<?xml version="1.0" encoding="utf-8" standalone="no"?>
<device schemaVersion="1.1">
  <name>STM32F765ZIT7</name>
  <version>1.0</version>
  <description>STM32F765BGT6,STM32F765BIT6,STM32F765IGK6,STM32F765IGT6,STM32F765IIK6,STM32F765IIK7,STM32F765IIT6,STM32F765IIT7,STM32F765NGH6,STM32F765NGH7,STM32F765NIH6,STM32F765NIH7,STM32F765VGH6,STM32F765VGH7,STM32F765VGT6,STM32F765VGT7,STM32F765VIH6,STM32F765VIT6,STM32F765ZGT6,STM32F765ZGT7,STM32F765ZIT6,STM32F765ZIT7</description>
  <addressUnitBits>8</addressUnitBits>
  <width>32</width>
  <size>0x20</size>
  <resetValue>0</resetValue>
  <resetMask>0xFFFFFFFF</resetMask>
  <peripherals>
    <peripheral>
      <name>TIM2</name>
      <baseAddress>0x40000000</baseAddress>
      <registers>
        <register>
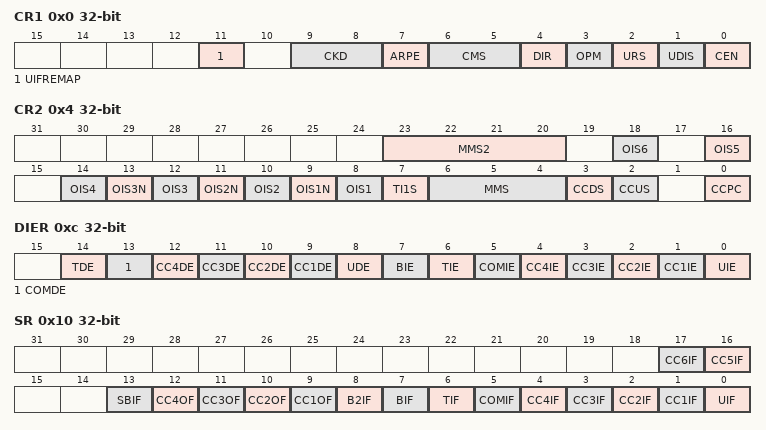
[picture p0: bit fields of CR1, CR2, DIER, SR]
          <name>CR1</name>
          <addressOffset>0x0</addressOffset>
          <size>0x20</size>
          <fields>
            <field>
              <name>CEN</name>
              <bitOffset>0</bitOffset>
              <bitWidth>1</bitWidth>
            </field>
            <field>
              <name>UDIS</name>
              <bitOffset>1</bitOffset>
              <bitWidth>1</bitWidth>
            </field>
            <field>
              <name>URS</name>
              <bitOffset>2</bitOffset>
              <bitWidth>1</bitWidth>
            </field>
            <field>
              <name>OPM</name>
              <bitOffset>3</bitOffset>
              <bitWidth>1</bitWidth>
            </field>
            <field>
              <name>DIR</name>
              <bitOffset>4</bitOffset>
              <bitWidth>1</bitWidth>
            </field>
            <field>
              <name>CMS</name>
              <bitOffset>5</bitOffset>
              <bitWidth>2</bitWidth>
            </field>
            <field>
              <name>ARPE</name>
              <bitOffset>7</bitOffset>
              <bitWidth>1</bitWidth>
            </field>
            <field>
              <name>CKD</name>
              <bitOffset>8</bitOffset>
              <bitWidth>2</bitWidth>
            </field>
            <field>
              <name>UIFREMAP</name>
              <bitOffset>11</bitOffset>
              <bitWidth>1</bitWidth>
            </field>
          </fields>
        </register>
        <register>
          <name>CR2</name>
          <addressOffset>0x4</addressOffset>
          <size>0x20</size>
          <fields>
            <field>
              <name>CCPC</name>
              <bitOffset>0</bitOffset>
              <bitWidth>1</bitWidth>
            </field>
            <field>
              <name>CCUS</name>
              <bitOffset>2</bitOffset>
              <bitWidth>1</bitWidth>
            </field>
            <field>
              <name>CCDS</name>
              <bitOffset>3</bitOffset>
              <bitWidth>1</bitWidth>
            </field>
            <field>
              <name>MMS</name>
              <bitOffset>4</bitOffset>
              <bitWidth>3</bitWidth>
            </field>
            <field>
              <name>TI1S</name>
              <bitOffset>7</bitOffset>
              <bitWidth>1</bitWidth>
            </field>
            <field>
              <name>OIS1</name>
              <bitOffset>8</bitOffset>
              <bitWidth>1</bitWidth>
            </field>
            <field>
              <name>OIS1N</name>
              <bitOffset>9</bitOffset>
              <bitWidth>1</bitWidth>
            </field>
            <field>
              <name>OIS2</name>
              <bitOffset>10</bitOffset>
              <bitWidth>1</bitWidth>
            </field>
            <field>
              <name>OIS2N</name>
              <bitOffset>11</bitOffset>
              <bitWidth>1</bitWidth>
            </field>
            <field>
              <name>OIS3</name>
              <bitOffset>12</bitOffset>
              <bitWidth>1</bitWidth>
            </field>
            <field>
              <name>OIS3N</name>
              <bitOffset>13</bitOffset>
              <bitWidth>1</bitWidth>
            </field>
            <field>
              <name>OIS4</name>
              <bitOffset>14</bitOffset>
              <bitWidth>1</bitWidth>
            </field>
            <field>
              <name>OIS5</name>
              <bitOffset>16</bitOffset>
              <bitWidth>1</bitWidth>
            </field>
            <field>
              <name>OIS6</name>
              <bitOffset>18</bitOffset>
              <bitWidth>1</bitWidth>
            </field>
            <field>
              <name>MMS2</name>
              <bitOffset>20</bitOffset>
              <bitWidth>4</bitWidth>
            </field>
          </fields>
        </register>
        <register>
          <name>SMCR</name>
          <addressOffset>0x8</addressOffset>
          <size>0x20</size>
          <fields>
            <field>
              <name>SMS</name>
              <bitOffset>0</bitOffset>
              <bitWidth>17</bitWidth>
            </field>
            <field>
              <name>TS</name>
              <bitOffset>4</bitOffset>
              <bitWidth>3</bitWidth>
            </field>
            <field>
              <name>MSM</name>
              <bitOffset>7</bitOffset>
              <bitWidth>1</bitWidth>
            </field>
            <field>
              <name>ETF</name>
              <bitOffset>8</bitOffset>
              <bitWidth>4</bitWidth>
            </field>
            <field>
              <name>ETPS</name>
              <bitOffset>12</bitOffset>
              <bitWidth>2</bitWidth>
            </field>
            <field>
              <name>ECE</name>
              <bitOffset>14</bitOffset>
              <bitWidth>1</bitWidth>
            </field>
            <field>
              <name>ETP</name>
              <bitOffset>15</bitOffset>
              <bitWidth>1</bitWidth>
            </field>
          </fields>
        </register>
        <register>
          <name>DIER</name>
          <addressOffset>0xc</addressOffset>
          <size>0x20</size>
          <fields>
            <field>
              <name>UIE</name>
              <bitOffset>0</bitOffset>
              <bitWidth>1</bitWidth>
            </field>
            <field>
              <name>CC1IE</name>
              <bitOffset>1</bitOffset>
              <bitWidth>1</bitWidth>
            </field>
            <field>
              <name>CC2IE</name>
              <bitOffset>2</bitOffset>
              <bitWidth>1</bitWidth>
            </field>
            <field>
              <name>CC3IE</name>
              <bitOffset>3</bitOffset>
              <bitWidth>1</bitWidth>
            </field>
            <field>
              <name>CC4IE</name>
              <bitOffset>4</bitOffset>
              <bitWidth>1</bitWidth>
            </field>
            <field>
              <name>COMIE</name>
              <bitOffset>5</bitOffset>
              <bitWidth>1</bitWidth>
            </field>
            <field>
              <name>TIE</name>
              <bitOffset>6</bitOffset>
              <bitWidth>1</bitWidth>
            </field>
            <field>
              <name>BIE</name>
              <bitOffset>7</bitOffset>
              <bitWidth>1</bitWidth>
            </field>
            <field>
              <name>UDE</name>
              <bitOffset>8</bitOffset>
              <bitWidth>1</bitWidth>
            </field>
            <field>
              <name>CC1DE</name>
              <bitOffset>9</bitOffset>
              <bitWidth>1</bitWidth>
            </field>
            <field>
              <name>CC2DE</name>
              <bitOffset>10</bitOffset>
              <bitWidth>1</bitWidth>
            </field>
            <field>
              <name>CC3DE</name>
              <bitOffset>11</bitOffset>
              <bitWidth>1</bitWidth>
            </field>
            <field>
              <name>CC4DE</name>
              <bitOffset>12</bitOffset>
              <bitWidth>1</bitWidth>
            </field>
            <field>
              <name>COMDE</name>
              <bitOffset>13</bitOffset>
              <bitWidth>1</bitWidth>
            </field>
            <field>
              <name>TDE</name>
              <bitOffset>14</bitOffset>
              <bitWidth>1</bitWidth>
            </field>
          </fields>
        </register>
        <register>
          <name>SR</name>
          <addressOffset>0x10</addressOffset>
          <size>0x20</size>
          <fields>
            <field>
              <name>UIF</name>
              <bitOffset>0</bitOffset>
              <bitWidth>1</bitWidth>
            </field>
            <field>
              <name>CC1IF</name>
              <bitOffset>1</bitOffset>
              <bitWidth>1</bitWidth>
            </field>
            <field>
              <name>CC2IF</name>
              <bitOffset>2</bitOffset>
              <bitWidth>1</bitWidth>
            </field>
            <field>
              <name>CC3IF</name>
              <bitOffset>3</bitOffset>
              <bitWidth>1</bitWidth>
            </field>
            <field>
              <name>CC4IF</name>
              <bitOffset>4</bitOffset>
              <bitWidth>1</bitWidth>
            </field>
            <field>
              <name>COMIF</name>
              <bitOffset>5</bitOffset>
              <bitWidth>1</bitWidth>
            </field>
            <field>
              <name>TIF</name>
              <bitOffset>6</bitOffset>
              <bitWidth>1</bitWidth>
            </field>
            <field>
              <name>BIF</name>
              <bitOffset>7</bitOffset>
              <bitWidth>1</bitWidth>
            </field>
            <field>
              <name>B2IF</name>
              <bitOffset>8</bitOffset>
              <bitWidth>1</bitWidth>
            </field>
            <field>
              <name>CC1OF</name>
              <bitOffset>9</bitOffset>
              <bitWidth>1</bitWidth>
            </field>
            <field>
              <name>CC2OF</name>
              <bitOffset>10</bitOffset>
              <bitWidth>1</bitWidth>
            </field>
            <field>
              <name>CC3OF</name>
              <bitOffset>11</bitOffset>
              <bitWidth>1</bitWidth>
            </field>
            <field>
              <name>CC4OF</name>
              <bitOffset>12</bitOffset>
              <bitWidth>1</bitWidth>
            </field>
            <field>
              <name>SBIF</name>
              <bitOffset>13</bitOffset>
              <bitWidth>1</bitWidth>
            </field>
            <field>
              <name>CC5IF</name>
              <bitOffset>16</bitOffset>
              <bitWidth>1</bitWidth>
            </field>
            <field>
              <name>CC6IF</name>
              <bitOffset>17</bitOffset>
              <bitWidth>1</bitWidth>
            </field>
          </fields>
        </register>
        <register>
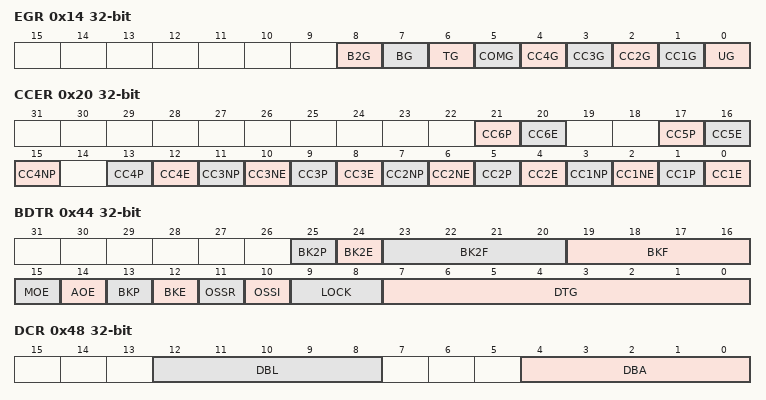
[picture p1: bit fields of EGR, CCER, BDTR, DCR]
          <name>EGR</name>
          <addressOffset>0x14</addressOffset>
          <size>0x20</size>
          <fields>
            <field>
              <name>UG</name>
              <bitOffset>0</bitOffset>
              <bitWidth>1</bitWidth>
            </field>
            <field>
              <name>CC1G</name>
              <bitOffset>1</bitOffset>
              <bitWidth>1</bitWidth>
            </field>
            <field>
              <name>CC2G</name>
              <bitOffset>2</bitOffset>
              <bitWidth>1</bitWidth>
            </field>
            <field>
              <name>CC3G</name>
              <bitOffset>3</bitOffset>
              <bitWidth>1</bitWidth>
            </field>
            <field>
              <name>CC4G</name>
              <bitOffset>4</bitOffset>
              <bitWidth>1</bitWidth>
            </field>
            <field>
              <name>COMG</name>
              <bitOffset>5</bitOffset>
              <bitWidth>1</bitWidth>
            </field>
            <field>
              <name>TG</name>
              <bitOffset>6</bitOffset>
              <bitWidth>1</bitWidth>
            </field>
            <field>
              <name>BG</name>
              <bitOffset>7</bitOffset>
              <bitWidth>1</bitWidth>
            </field>
            <field>
              <name>B2G</name>
              <bitOffset>8</bitOffset>
              <bitWidth>1</bitWidth>
            </field>
          </fields>
        </register>
        <register>
          <name>CCMR1</name>
          <addressOffset>0x18</addressOffset>
          <size>0x20</size>
          <fields>
            <field>
              <name>CC1S</name>
              <bitOffset>0</bitOffset>
              <bitWidth>2</bitWidth>
            </field>
            <field>
              <name>OC1FE</name>
              <bitOffset>2</bitOffset>
              <bitWidth>1</bitWidth>
            </field>
            <field>
              <name>OC1PE</name>
              <bitOffset>3</bitOffset>
              <bitWidth>1</bitWidth>
            </field>
            <field>
              <name>OC1M</name>
              <bitOffset>4</bitOffset>
              <bitWidth>13</bitWidth>
            </field>
            <field>
              <name>OC1CE</name>
              <bitOffset>7</bitOffset>
              <bitWidth>1</bitWidth>
            </field>
            <field>
              <name>CC2S</name>
              <bitOffset>8</bitOffset>
              <bitWidth>2</bitWidth>
            </field>
            <field>
              <name>OC2FE</name>
              <bitOffset>10</bitOffset>
              <bitWidth>1</bitWidth>
            </field>
            <field>
              <name>OC2PE</name>
              <bitOffset>11</bitOffset>
              <bitWidth>1</bitWidth>
            </field>
            <field>
              <name>OC2M</name>
              <bitOffset>12</bitOffset>
              <bitWidth>13</bitWidth>
            </field>
            <field>
              <name>OC2CE</name>
              <bitOffset>15</bitOffset>
              <bitWidth>1</bitWidth>
            </field>
          </fields>
        </register>
        <register>
          <name>CCMR2</name>
          <addressOffset>0x1c</addressOffset>
          <size>0x20</size>
          <fields>
            <field>
              <name>CC3S</name>
              <bitOffset>0</bitOffset>
              <bitWidth>2</bitWidth>
            </field>
            <field>
              <name>OC3FE</name>
              <bitOffset>2</bitOffset>
              <bitWidth>1</bitWidth>
            </field>
            <field>
              <name>OC3PE</name>
              <bitOffset>3</bitOffset>
              <bitWidth>1</bitWidth>
            </field>
            <field>
              <name>OC3M</name>
              <bitOffset>4</bitOffset>
              <bitWidth>13</bitWidth>
            </field>
            <field>
              <name>OC3CE</name>
              <bitOffset>7</bitOffset>
              <bitWidth>1</bitWidth>
            </field>
            <field>
              <name>CC4S</name>
              <bitOffset>8</bitOffset>
              <bitWidth>2</bitWidth>
            </field>
            <field>
              <name>OC4FE</name>
              <bitOffset>10</bitOffset>
              <bitWidth>1</bitWidth>
            </field>
            <field>
              <name>OC4PE</name>
              <bitOffset>11</bitOffset>
              <bitWidth>1</bitWidth>
            </field>
            <field>
              <name>OC4M</name>
              <bitOffset>12</bitOffset>
              <bitWidth>13</bitWidth>
            </field>
            <field>
              <name>OC4CE</name>
              <bitOffset>15</bitOffset>
              <bitWidth>1</bitWidth>
            </field>
          </fields>
        </register>
        <register>
          <name>CCER</name>
          <addressOffset>0x20</addressOffset>
          <size>0x20</size>
          <fields>
            <field>
              <name>CC1E</name>
              <bitOffset>0</bitOffset>
              <bitWidth>1</bitWidth>
            </field>
            <field>
              <name>CC1P</name>
              <bitOffset>1</bitOffset>
              <bitWidth>1</bitWidth>
            </field>
            <field>
              <name>CC1NE</name>
              <bitOffset>2</bitOffset>
              <bitWidth>1</bitWidth>
            </field>
            <field>
              <name>CC1NP</name>
              <bitOffset>3</bitOffset>
              <bitWidth>1</bitWidth>
            </field>
            <field>
              <name>CC2E</name>
              <bitOffset>4</bitOffset>
              <bitWidth>1</bitWidth>
            </field>
            <field>
              <name>CC2P</name>
              <bitOffset>5</bitOffset>
              <bitWidth>1</bitWidth>
            </field>
            <field>
              <name>CC2NE</name>
              <bitOffset>6</bitOffset>
              <bitWidth>1</bitWidth>
            </field>
            <field>
              <name>CC2NP</name>
              <bitOffset>7</bitOffset>
              <bitWidth>1</bitWidth>
            </field>
            <field>
              <name>CC3E</name>
              <bitOffset>8</bitOffset>
              <bitWidth>1</bitWidth>
            </field>
            <field>
              <name>CC3P</name>
              <bitOffset>9</bitOffset>
              <bitWidth>1</bitWidth>
            </field>
            <field>
              <name>CC3NE</name>
              <bitOffset>10</bitOffset>
              <bitWidth>1</bitWidth>
            </field>
            <field>
              <name>CC3NP</name>
              <bitOffset>11</bitOffset>
              <bitWidth>1</bitWidth>
            </field>
            <field>
              <name>CC4E</name>
              <bitOffset>12</bitOffset>
              <bitWidth>1</bitWidth>
            </field>
            <field>
              <name>CC4P</name>
              <bitOffset>13</bitOffset>
              <bitWidth>1</bitWidth>
            </field>
            <field>
              <name>CC4NP</name>
              <bitOffset>15</bitOffset>
              <bitWidth>1</bitWidth>
            </field>
            <field>
              <name>CC5E</name>
              <bitOffset>16</bitOffset>
              <bitWidth>1</bitWidth>
            </field>
            <field>
              <name>CC5P</name>
              <bitOffset>17</bitOffset>
              <bitWidth>1</bitWidth>
            </field>
            <field>
              <name>CC6E</name>
              <bitOffset>20</bitOffset>
              <bitWidth>1</bitWidth>
            </field>
            <field>
              <name>CC6P</name>
              <bitOffset>21</bitOffset>
              <bitWidth>1</bitWidth>
            </field>
          </fields>
        </register>
        <register>
          <name>CNT</name>
          <addressOffset>0x24</addressOffset>
          <size>0x20</size>
          <fields>
            <field>
              <name>CNT</name>
              <bitOffset>0</bitOffset>
              <bitWidth>32</bitWidth>
            </field>
            <field>
              <name>UIFCPY</name>
              <bitOffset>31</bitOffset>
              <bitWidth>1</bitWidth>
            </field>
          </fields>
        </register>
        <register>
          <name>PSC</name>
          <addressOffset>0x28</addressOffset>
          <size>0x20</size>
          <fields>
            <field>
              <name>PSC</name>
              <bitOffset>0</bitOffset>
              <bitWidth>16</bitWidth>
            </field>
          </fields>
        </register>
        <register>
          <name>ARR</name>
          <addressOffset>0x2c</addressOffset>
          <size>0x20</size>
          <fields>
            <field>
              <name>ARR</name>
              <bitOffset>0</bitOffset>
              <bitWidth>32</bitWidth>
            </field>
          </fields>
        </register>
        <register>
          <name>RCR</name>
          <addressOffset>0x30</addressOffset>
          <size>0x20</size>
          <fields>
            <field>
              <name>REP</name>
              <bitOffset>0</bitOffset>
              <bitWidth>16</bitWidth>
            </field>
          </fields>
        </register>
        <register>
          <name>CCR1</name>
          <addressOffset>0x34</addressOffset>
          <size>0x20</size>
          <fields>
            <field>
              <name>CCR1</name>
              <bitOffset>0</bitOffset>
              <bitWidth>16</bitWidth>
            </field>
          </fields>
        </register>
        <register>
          <name>CCR2</name>
          <addressOffset>0x38</addressOffset>
          <size>0x20</size>
          <fields>
            <field>
              <name>CCR2</name>
              <bitOffset>0</bitOffset>
              <bitWidth>16</bitWidth>
            </field>
          </fields>
        </register>
        <register>
          <name>CCR3</name>
          <addressOffset>0x3c</addressOffset>
          <size>0x20</size>
          <fields>
            <field>
              <name>CCR3</name>
              <bitOffset>0</bitOffset>
              <bitWidth>16</bitWidth>
            </field>
          </fields>
        </register>
        <register>
          <name>CCR4</name>
          <addressOffset>0x40</addressOffset>
          <size>0x20</size>
          <fields>
            <field>
              <name>CCR4</name>
              <bitOffset>0</bitOffset>
              <bitWidth>16</bitWidth>
            </field>
          </fields>
        </register>
        <register>
          <name>BDTR</name>
          <addressOffset>0x44</addressOffset>
          <size>0x20</size>
          <fields>
            <field>
              <name>DTG</name>
              <bitOffset>0</bitOffset>
              <bitWidth>8</bitWidth>
            </field>
            <field>
              <name>LOCK</name>
              <bitOffset>8</bitOffset>
              <bitWidth>2</bitWidth>
            </field>
            <field>
              <name>OSSI</name>
              <bitOffset>10</bitOffset>
              <bitWidth>1</bitWidth>
            </field>
            <field>
              <name>OSSR</name>
              <bitOffset>11</bitOffset>
              <bitWidth>1</bitWidth>
            </field>
            <field>
              <name>BKE</name>
              <bitOffset>12</bitOffset>
              <bitWidth>1</bitWidth>
            </field>
            <field>
              <name>BKP</name>
              <bitOffset>13</bitOffset>
              <bitWidth>1</bitWidth>
            </field>
            <field>
              <name>AOE</name>
              <bitOffset>14</bitOffset>
              <bitWidth>1</bitWidth>
            </field>
            <field>
              <name>MOE</name>
              <bitOffset>15</bitOffset>
              <bitWidth>1</bitWidth>
            </field>
            <field>
              <name>BKF</name>
              <bitOffset>16</bitOffset>
              <bitWidth>4</bitWidth>
            </field>
            <field>
              <name>BK2F</name>
              <bitOffset>20</bitOffset>
              <bitWidth>4</bitWidth>
            </field>
            <field>
              <name>BK2E</name>
              <bitOffset>24</bitOffset>
              <bitWidth>1</bitWidth>
            </field>
            <field>
              <name>BK2P</name>
              <bitOffset>25</bitOffset>
              <bitWidth>1</bitWidth>
            </field>
          </fields>
        </register>
        <register>
          <name>DCR</name>
          <addressOffset>0x48</addressOffset>
          <size>0x20</size>
          <fields>
            <field>
              <name>DBA</name>
              <bitOffset>0</bitOffset>
              <bitWidth>5</bitWidth>
            </field>
            <field>
              <name>DBL</name>
              <bitOffset>8</bitOffset>
              <bitWidth>5</bitWidth>
            </field>
          </fields>
        </register>
        <register>
          <name>DMAR</name>
          <addressOffset>0x4c</addressOffset>
          <size>0x20</size>
          <fields>
            <field>
              <name>DMAB</name>
              <bitOffset>0</bitOffset>
              <bitWidth>16</bitWidth>
            </field>
          </fields>
        </register>
        <register>
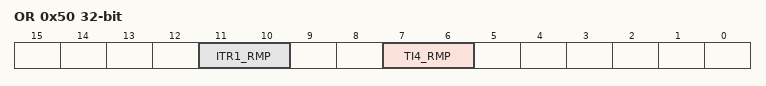
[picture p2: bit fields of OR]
          <name>OR</name>
          <addressOffset>0x50</addressOffset>
          <size>0x20</size>
          <fields>
            <field>
              <name>TI4_RMP</name>
              <bitOffset>6</bitOffset>
              <bitWidth>2</bitWidth>
            </field>
            <field>
              <name>ITR1_RMP</name>
              <bitOffset>10</bitOffset>
              <bitWidth>2</bitWidth>
            </field>
          </fields>
        </register>
        <register>
          <name>CCMR3</name>
          <addressOffset>0x54</addressOffset>
          <size>0x20</size>
          <fields>
            <field>
              <name>OC5FE</name>
              <bitOffset>2</bitOffset>
              <bitWidth>1</bitWidth>
            </field>
            <field>
              <name>OC5PE</name>
              <bitOffset>3</bitOffset>
              <bitWidth>1</bitWidth>
            </field>
            <field>
              <name>OC5M</name>
              <bitOffset>4</bitOffset>
              <bitWidth>13</bitWidth>
            </field>
            <field>
              <name>OC5CE</name>
              <bitOffset>7</bitOffset>
              <bitWidth>1</bitWidth>
            </field>
            <field>
              <name>OC6FE</name>
              <bitOffset>10</bitOffset>
              <bitWidth>1</bitWidth>
            </field>
            <field>
              <name>OC6PE</name>
              <bitOffset>11</bitOffset>
              <bitWidth>1</bitWidth>
            </field>
            <field>
              <name>OC6M</name>
              <bitOffset>12</bitOffset>
              <bitWidth>13</bitWidth>
            </field>
            <field>
              <name>OC6CE</name>
              <bitOffset>15</bitOffset>
              <bitWidth>1</bitWidth>
            </field>
          </fields>
        </register>
        <register>
          <name>CCR5</name>
          <addressOffset>0x58</addressOffset>
          <size>0x20</size>
          <fields>
            <field>
              <name>CCR5</name>
              <bitOffset>0</bitOffset>
              <bitWidth>32</bitWidth>
            </field>
            <field>
              <name>GC5C1</name>
              <bitOffset>29</bitOffset>
              <bitWidth>1</bitWidth>
            </field>
            <field>
              <name>GC5C2</name>
              <bitOffset>30</bitOffset>
              <bitWidth>1</bitWidth>
            </field>
            <field>
              <name>GC5C3</name>
              <bitOffset>31</bitOffset>
              <bitWidth>1</bitWidth>
            </field>
          </fields>
        </register>
        <register>
          <name>CCR6</name>
          <addressOffset>0x5c</addressOffset>
          <size>0x20</size>
        </register>
        <register>
          <name>AF1</name>
          <addressOffset>0x60</addressOffset>
          <size>0x20</size>
        </register>
        <register>
          <name>AF2</name>
          <addressOffset>0x64</addressOffset>
          <size>0x20</size>
        </register>
      </registers>
    </peripheral>
    <peripheral>
      <name>TIM3</name>
      <baseAddress>0x40000400</baseAddress>
      <registers>
        <register>
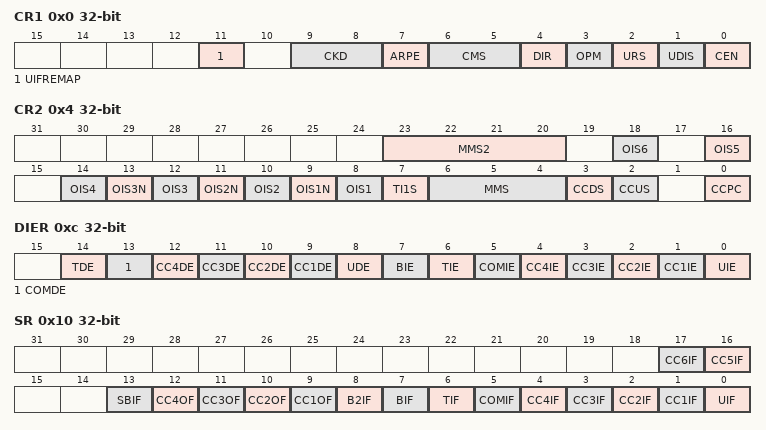
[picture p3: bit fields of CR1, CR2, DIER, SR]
          <name>CR1</name>
          <addressOffset>0x0</addressOffset>
          <size>0x20</size>
          <fields>
            <field>
              <name>CEN</name>
              <bitOffset>0</bitOffset>
              <bitWidth>1</bitWidth>
            </field>
            <field>
              <name>UDIS</name>
              <bitOffset>1</bitOffset>
              <bitWidth>1</bitWidth>
            </field>
            <field>
              <name>URS</name>
              <bitOffset>2</bitOffset>
              <bitWidth>1</bitWidth>
            </field>
            <field>
              <name>OPM</name>
              <bitOffset>3</bitOffset>
              <bitWidth>1</bitWidth>
            </field>
            <field>
              <name>DIR</name>
              <bitOffset>4</bitOffset>
              <bitWidth>1</bitWidth>
            </field>
            <field>
              <name>CMS</name>
              <bitOffset>5</bitOffset>
              <bitWidth>2</bitWidth>
            </field>
            <field>
              <name>ARPE</name>
              <bitOffset>7</bitOffset>
              <bitWidth>1</bitWidth>
            </field>
            <field>
              <name>CKD</name>
              <bitOffset>8</bitOffset>
              <bitWidth>2</bitWidth>
            </field>
            <field>
              <name>UIFREMAP</name>
              <bitOffset>11</bitOffset>
              <bitWidth>1</bitWidth>
            </field>
          </fields>
        </register>
        <register>
          <name>CR2</name>
          <addressOffset>0x4</addressOffset>
          <size>0x20</size>
          <fields>
            <field>
              <name>CCPC</name>
              <bitOffset>0</bitOffset>
              <bitWidth>1</bitWidth>
            </field>
            <field>
              <name>CCUS</name>
              <bitOffset>2</bitOffset>
              <bitWidth>1</bitWidth>
            </field>
            <field>
              <name>CCDS</name>
              <bitOffset>3</bitOffset>
              <bitWidth>1</bitWidth>
            </field>
            <field>
              <name>MMS</name>
              <bitOffset>4</bitOffset>
              <bitWidth>3</bitWidth>
            </field>
            <field>
              <name>TI1S</name>
              <bitOffset>7</bitOffset>
              <bitWidth>1</bitWidth>
            </field>
            <field>
              <name>OIS1</name>
              <bitOffset>8</bitOffset>
              <bitWidth>1</bitWidth>
            </field>
            <field>
              <name>OIS1N</name>
              <bitOffset>9</bitOffset>
              <bitWidth>1</bitWidth>
            </field>
            <field>
              <name>OIS2</name>
              <bitOffset>10</bitOffset>
              <bitWidth>1</bitWidth>
            </field>
            <field>
              <name>OIS2N</name>
              <bitOffset>11</bitOffset>
              <bitWidth>1</bitWidth>
            </field>
            <field>
              <name>OIS3</name>
              <bitOffset>12</bitOffset>
              <bitWidth>1</bitWidth>
            </field>
            <field>
              <name>OIS3N</name>
              <bitOffset>13</bitOffset>
              <bitWidth>1</bitWidth>
            </field>
            <field>
              <name>OIS4</name>
              <bitOffset>14</bitOffset>
              <bitWidth>1</bitWidth>
            </field>
            <field>
              <name>OIS5</name>
              <bitOffset>16</bitOffset>
              <bitWidth>1</bitWidth>
            </field>
            <field>
              <name>OIS6</name>
              <bitOffset>18</bitOffset>
              <bitWidth>1</bitWidth>
            </field>
            <field>
              <name>MMS2</name>
              <bitOffset>20</bitOffset>
              <bitWidth>4</bitWidth>
            </field>
          </fields>
        </register>
        <register>
          <name>SMCR</name>
          <addressOffset>0x8</addressOffset>
          <size>0x20</size>
          <fields>
            <field>
              <name>SMS</name>
              <bitOffset>0</bitOffset>
              <bitWidth>17</bitWidth>
            </field>
            <field>
              <name>TS</name>
              <bitOffset>4</bitOffset>
              <bitWidth>3</bitWidth>
            </field>
            <field>
              <name>MSM</name>
              <bitOffset>7</bitOffset>
              <bitWidth>1</bitWidth>
            </field>
            <field>
              <name>ETF</name>
              <bitOffset>8</bitOffset>
              <bitWidth>4</bitWidth>
            </field>
            <field>
              <name>ETPS</name>
              <bitOffset>12</bitOffset>
              <bitWidth>2</bitWidth>
            </field>
            <field>
              <name>ECE</name>
              <bitOffset>14</bitOffset>
              <bitWidth>1</bitWidth>
            </field>
            <field>
              <name>ETP</name>
              <bitOffset>15</bitOffset>
              <bitWidth>1</bitWidth>
            </field>
          </fields>
        </register>
        <register>
          <name>DIER</name>
          <addressOffset>0xc</addressOffset>
          <size>0x20</size>
          <fields>
            <field>
              <name>UIE</name>
              <bitOffset>0</bitOffset>
              <bitWidth>1</bitWidth>
            </field>
            <field>
              <name>CC1IE</name>
              <bitOffset>1</bitOffset>
              <bitWidth>1</bitWidth>
            </field>
            <field>
              <name>CC2IE</name>
              <bitOffset>2</bitOffset>
              <bitWidth>1</bitWidth>
            </field>
            <field>
              <name>CC3IE</name>
              <bitOffset>3</bitOffset>
              <bitWidth>1</bitWidth>
            </field>
            <field>
              <name>CC4IE</name>
              <bitOffset>4</bitOffset>
              <bitWidth>1</bitWidth>
            </field>
            <field>
              <name>COMIE</name>
              <bitOffset>5</bitOffset>
              <bitWidth>1</bitWidth>
            </field>
            <field>
              <name>TIE</name>
              <bitOffset>6</bitOffset>
              <bitWidth>1</bitWidth>
            </field>
            <field>
              <name>BIE</name>
              <bitOffset>7</bitOffset>
              <bitWidth>1</bitWidth>
            </field>
            <field>
              <name>UDE</name>
              <bitOffset>8</bitOffset>
              <bitWidth>1</bitWidth>
            </field>
            <field>
              <name>CC1DE</name>
              <bitOffset>9</bitOffset>
              <bitWidth>1</bitWidth>
            </field>
            <field>
              <name>CC2DE</name>
              <bitOffset>10</bitOffset>
              <bitWidth>1</bitWidth>
            </field>
            <field>
              <name>CC3DE</name>
              <bitOffset>11</bitOffset>
              <bitWidth>1</bitWidth>
            </field>
            <field>
              <name>CC4DE</name>
              <bitOffset>12</bitOffset>
              <bitWidth>1</bitWidth>
            </field>
            <field>
              <name>COMDE</name>
              <bitOffset>13</bitOffset>
              <bitWidth>1</bitWidth>
            </field>
            <field>
              <name>TDE</name>
              <bitOffset>14</bitOffset>
              <bitWidth>1</bitWidth>
            </field>
          </fields>
        </register>
        <register>
          <name>SR</name>
          <addressOffset>0x10</addressOffset>
          <size>0x20</size>
          <fields>
            <field>
              <name>UIF</name>
              <bitOffset>0</bitOffset>
              <bitWidth>1</bitWidth>
            </field>
            <field>
              <name>CC1IF</name>
              <bitOffset>1</bitOffset>
              <bitWidth>1</bitWidth>
            </field>
            <field>
              <name>CC2IF</name>
              <bitOffset>2</bitOffset>
              <bitWidth>1</bitWidth>
            </field>
            <field>
              <name>CC3IF</name>
              <bitOffset>3</bitOffset>
              <bitWidth>1</bitWidth>
            </field>
            <field>
              <name>CC4IF</name>
              <bitOffset>4</bitOffset>
              <bitWidth>1</bitWidth>
            </field>
            <field>
              <name>COMIF</name>
              <bitOffset>5</bitOffset>
              <bitWidth>1</bitWidth>
            </field>
            <field>
              <name>TIF</name>
              <bitOffset>6</bitOffset>
              <bitWidth>1</bitWidth>
            </field>
            <field>
              <name>BIF</name>
              <bitOffset>7</bitOffset>
              <bitWidth>1</bitWidth>
            </field>
            <field>
              <name>B2IF</name>
              <bitOffset>8</bitOffset>
              <bitWidth>1</bitWidth>
            </field>
            <field>
              <name>CC1OF</name>
              <bitOffset>9</bitOffset>
              <bitWidth>1</bitWidth>
            </field>
            <field>
              <name>CC2OF</name>
              <bitOffset>10</bitOffset>
              <bitWidth>1</bitWidth>
            </field>
            <field>
              <name>CC3OF</name>
              <bitOffset>11</bitOffset>
              <bitWidth>1</bitWidth>
            </field>
            <field>
              <name>CC4OF</name>
              <bitOffset>12</bitOffset>
              <bitWidth>1</bitWidth>
            </field>
            <field>
              <name>SBIF</name>
              <bitOffset>13</bitOffset>
              <bitWidth>1</bitWidth>
            </field>
            <field>
              <name>CC5IF</name>
              <bitOffset>16</bitOffset>
              <bitWidth>1</bitWidth>
            </field>
            <field>
              <name>CC6IF</name>
              <bitOffset>17</bitOffset>
              <bitWidth>1</bitWidth>
            </field>
          </fields>
        </register>
        <register>
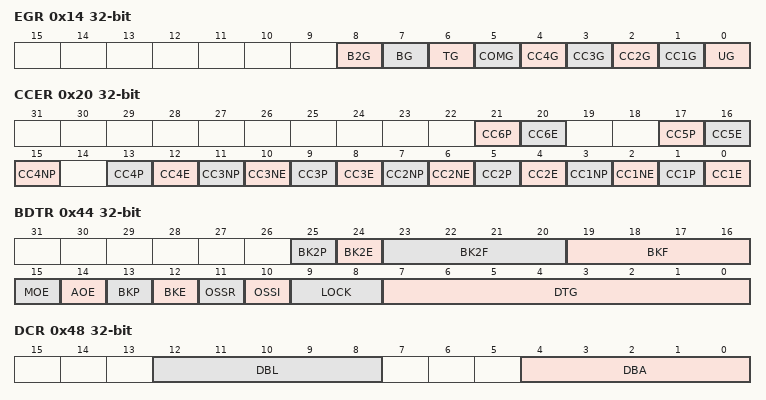
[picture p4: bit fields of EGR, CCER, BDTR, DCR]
          <name>EGR</name>
          <addressOffset>0x14</addressOffset>
          <size>0x20</size>
          <fields>
            <field>
              <name>UG</name>
              <bitOffset>0</bitOffset>
              <bitWidth>1</bitWidth>
            </field>
            <field>
              <name>CC1G</name>
              <bitOffset>1</bitOffset>
              <bitWidth>1</bitWidth>
            </field>
            <field>
              <name>CC2G</name>
              <bitOffset>2</bitOffset>
              <bitWidth>1</bitWidth>
            </field>
            <field>
              <name>CC3G</name>
              <bitOffset>3</bitOffset>
              <bitWidth>1</bitWidth>
            </field>
            <field>
              <name>CC4G</name>
              <bitOffset>4</bitOffset>
              <bitWidth>1</bitWidth>
            </field>
            <field>
              <name>COMG</name>
              <bitOffset>5</bitOffset>
              <bitWidth>1</bitWidth>
            </field>
            <field>
              <name>TG</name>
              <bitOffset>6</bitOffset>
              <bitWidth>1</bitWidth>
            </field>
            <field>
              <name>BG</name>
              <bitOffset>7</bitOffset>
              <bitWidth>1</bitWidth>
            </field>
            <field>
              <name>B2G</name>
              <bitOffset>8</bitOffset>
              <bitWidth>1</bitWidth>
            </field>
          </fields>
        </register>
        <register>
          <name>CCMR1</name>
          <addressOffset>0x18</addressOffset>
          <size>0x20</size>
          <fields>
            <field>
              <name>CC1S</name>
              <bitOffset>0</bitOffset>
              <bitWidth>2</bitWidth>
            </field>
            <field>
              <name>OC1FE</name>
              <bitOffset>2</bitOffset>
              <bitWidth>1</bitWidth>
            </field>
            <field>
              <name>OC1PE</name>
              <bitOffset>3</bitOffset>
              <bitWidth>1</bitWidth>
            </field>
            <field>
              <name>OC1M</name>
              <bitOffset>4</bitOffset>
              <bitWidth>13</bitWidth>
            </field>
            <field>
              <name>OC1CE</name>
              <bitOffset>7</bitOffset>
              <bitWidth>1</bitWidth>
            </field>
            <field>
              <name>CC2S</name>
              <bitOffset>8</bitOffset>
              <bitWidth>2</bitWidth>
            </field>
            <field>
              <name>OC2FE</name>
              <bitOffset>10</bitOffset>
              <bitWidth>1</bitWidth>
            </field>
            <field>
              <name>OC2PE</name>
              <bitOffset>11</bitOffset>
              <bitWidth>1</bitWidth>
            </field>
            <field>
              <name>OC2M</name>
              <bitOffset>12</bitOffset>
              <bitWidth>13</bitWidth>
            </field>
            <field>
              <name>OC2CE</name>
              <bitOffset>15</bitOffset>
              <bitWidth>1</bitWidth>
            </field>
          </fields>
        </register>
        <register>
          <name>CCMR2</name>
          <addressOffset>0x1c</addressOffset>
          <size>0x20</size>
          <fields>
            <field>
              <name>CC3S</name>
              <bitOffset>0</bitOffset>
              <bitWidth>2</bitWidth>
            </field>
            <field>
              <name>OC3FE</name>
              <bitOffset>2</bitOffset>
              <bitWidth>1</bitWidth>
            </field>
            <field>
              <name>OC3PE</name>
              <bitOffset>3</bitOffset>
              <bitWidth>1</bitWidth>
            </field>
            <field>
              <name>OC3M</name>
              <bitOffset>4</bitOffset>
              <bitWidth>13</bitWidth>
            </field>
            <field>
              <name>OC3CE</name>
              <bitOffset>7</bitOffset>
              <bitWidth>1</bitWidth>
            </field>
            <field>
              <name>CC4S</name>
              <bitOffset>8</bitOffset>
              <bitWidth>2</bitWidth>
            </field>
            <field>
              <name>OC4FE</name>
              <bitOffset>10</bitOffset>
              <bitWidth>1</bitWidth>
            </field>
            <field>
              <name>OC4PE</name>
              <bitOffset>11</bitOffset>
              <bitWidth>1</bitWidth>
            </field>
            <field>
              <name>OC4M</name>
              <bitOffset>12</bitOffset>
              <bitWidth>13</bitWidth>
            </field>
            <field>
              <name>OC4CE</name>
              <bitOffset>15</bitOffset>
              <bitWidth>1</bitWidth>
            </field>
          </fields>
        </register>
        <register>
          <name>CCER</name>
          <addressOffset>0x20</addressOffset>
          <size>0x20</size>
          <fields>
            <field>
              <name>CC1E</name>
              <bitOffset>0</bitOffset>
              <bitWidth>1</bitWidth>
            </field>
            <field>
              <name>CC1P</name>
              <bitOffset>1</bitOffset>
              <bitWidth>1</bitWidth>
            </field>
            <field>
              <name>CC1NE</name>
              <bitOffset>2</bitOffset>
              <bitWidth>1</bitWidth>
            </field>
            <field>
              <name>CC1NP</name>
              <bitOffset>3</bitOffset>
              <bitWidth>1</bitWidth>
            </field>
            <field>
              <name>CC2E</name>
              <bitOffset>4</bitOffset>
              <bitWidth>1</bitWidth>
            </field>
            <field>
              <name>CC2P</name>
              <bitOffset>5</bitOffset>
              <bitWidth>1</bitWidth>
            </field>
            <field>
              <name>CC2NE</name>
              <bitOffset>6</bitOffset>
              <bitWidth>1</bitWidth>
            </field>
            <field>
              <name>CC2NP</name>
              <bitOffset>7</bitOffset>
              <bitWidth>1</bitWidth>
            </field>
            <field>
              <name>CC3E</name>
              <bitOffset>8</bitOffset>
              <bitWidth>1</bitWidth>
            </field>
            <field>
              <name>CC3P</name>
              <bitOffset>9</bitOffset>
              <bitWidth>1</bitWidth>
            </field>
            <field>
              <name>CC3NE</name>
              <bitOffset>10</bitOffset>
              <bitWidth>1</bitWidth>
            </field>
            <field>
              <name>CC3NP</name>
              <bitOffset>11</bitOffset>
              <bitWidth>1</bitWidth>
            </field>
            <field>
              <name>CC4E</name>
              <bitOffset>12</bitOffset>
              <bitWidth>1</bitWidth>
            </field>
            <field>
              <name>CC4P</name>
              <bitOffset>13</bitOffset>
              <bitWidth>1</bitWidth>
            </field>
            <field>
              <name>CC4NP</name>
              <bitOffset>15</bitOffset>
              <bitWidth>1</bitWidth>
            </field>
            <field>
              <name>CC5E</name>
              <bitOffset>16</bitOffset>
              <bitWidth>1</bitWidth>
            </field>
            <field>
              <name>CC5P</name>
              <bitOffset>17</bitOffset>
              <bitWidth>1</bitWidth>
            </field>
            <field>
              <name>CC6E</name>
              <bitOffset>20</bitOffset>
              <bitWidth>1</bitWidth>
            </field>
            <field>
              <name>CC6P</name>
              <bitOffset>21</bitOffset>
              <bitWidth>1</bitWidth>
            </field>
          </fields>
        </register>
        <register>
          <name>CNT</name>
          <addressOffset>0x24</addressOffset>
          <size>0x20</size>
          <fields>
            <field>
              <name>CNT</name>
              <bitOffset>0</bitOffset>
              <bitWidth>32</bitWidth>
            </field>
            <field>
              <name>UIFCPY</name>
              <bitOffset>31</bitOffset>
              <bitWidth>1</bitWidth>
            </field>
          </fields>
        </register>
        <register>
          <name>PSC</name>
          <addressOffset>0x28</addressOffset>
          <size>0x20</size>
          <fields>
            <field>
              <name>PSC</name>
              <bitOffset>0</bitOffset>
              <bitWidth>16</bitWidth>
            </field>
          </fields>
        </register>
        <register>
          <name>ARR</name>
          <addressOffset>0x2c</addressOffset>
          <size>0x20</size>
          <fields>
            <field>
              <name>ARR</name>
              <bitOffset>0</bitOffset>
              <bitWidth>32</bitWidth>
            </field>
          </fields>
        </register>
        <register>
          <name>RCR</name>
          <addressOffset>0x30</addressOffset>
          <size>0x20</size>
          <fields>
            <field>
              <name>REP</name>
              <bitOffset>0</bitOffset>
              <bitWidth>16</bitWidth>
            </field>
          </fields>
        </register>
        <register>
          <name>CCR1</name>
          <addressOffset>0x34</addressOffset>
          <size>0x20</size>
          <fields>
            <field>
              <name>CCR1</name>
              <bitOffset>0</bitOffset>
              <bitWidth>16</bitWidth>
            </field>
          </fields>
        </register>
        <register>
          <name>CCR2</name>
          <addressOffset>0x38</addressOffset>
          <size>0x20</size>
          <fields>
            <field>
              <name>CCR2</name>
              <bitOffset>0</bitOffset>
              <bitWidth>16</bitWidth>
            </field>
          </fields>
        </register>
        <register>
          <name>CCR3</name>
          <addressOffset>0x3c</addressOffset>
          <size>0x20</size>
          <fields>
            <field>
              <name>CCR3</name>
              <bitOffset>0</bitOffset>
              <bitWidth>16</bitWidth>
            </field>
          </fields>
        </register>
        <register>
          <name>CCR4</name>
          <addressOffset>0x40</addressOffset>
          <size>0x20</size>
          <fields>
            <field>
              <name>CCR4</name>
              <bitOffset>0</bitOffset>
              <bitWidth>16</bitWidth>
            </field>
          </fields>
        </register>
        <register>
          <name>BDTR</name>
          <addressOffset>0x44</addressOffset>
          <size>0x20</size>
          <fields>
            <field>
              <name>DTG</name>
              <bitOffset>0</bitOffset>
              <bitWidth>8</bitWidth>
            </field>
            <field>
              <name>LOCK</name>
              <bitOffset>8</bitOffset>
              <bitWidth>2</bitWidth>
            </field>
            <field>
              <name>OSSI</name>
              <bitOffset>10</bitOffset>
              <bitWidth>1</bitWidth>
            </field>
            <field>
              <name>OSSR</name>
              <bitOffset>11</bitOffset>
              <bitWidth>1</bitWidth>
            </field>
            <field>
              <name>BKE</name>
              <bitOffset>12</bitOffset>
              <bitWidth>1</bitWidth>
            </field>
            <field>
              <name>BKP</name>
              <bitOffset>13</bitOffset>
              <bitWidth>1</bitWidth>
            </field>
            <field>
              <name>AOE</name>
              <bitOffset>14</bitOffset>
              <bitWidth>1</bitWidth>
            </field>
            <field>
              <name>MOE</name>
              <bitOffset>15</bitOffset>
              <bitWidth>1</bitWidth>
            </field>
            <field>
              <name>BKF</name>
              <bitOffset>16</bitOffset>
              <bitWidth>4</bitWidth>
            </field>
            <field>
              <name>BK2F</name>
              <bitOffset>20</bitOffset>
              <bitWidth>4</bitWidth>
            </field>
            <field>
              <name>BK2E</name>
              <bitOffset>24</bitOffset>
              <bitWidth>1</bitWidth>
            </field>
            <field>
              <name>BK2P</name>
              <bitOffset>25</bitOffset>
              <bitWidth>1</bitWidth>
            </field>
          </fields>
        </register>
        <register>
          <name>DCR</name>
          <addressOffset>0x48</addressOffset>
          <size>0x20</size>
          <fields>
            <field>
              <name>DBA</name>
              <bitOffset>0</bitOffset>
              <bitWidth>5</bitWidth>
            </field>
            <field>
              <name>DBL</name>
              <bitOffset>8</bitOffset>
              <bitWidth>5</bitWidth>
            </field>
          </fields>
        </register>
        <register>
          <name>DMAR</name>
          <addressOffset>0x4c</addressOffset>
          <size>0x20</size>
          <fields>
            <field>
              <name>DMAB</name>
              <bitOffset>0</bitOffset>
              <bitWidth>16</bitWidth>
            </field>
          </fields>
        </register>
        <register>
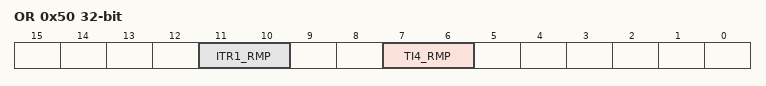
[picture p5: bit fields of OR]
          <name>OR</name>
          <addressOffset>0x50</addressOffset>
          <size>0x20</size>
          <fields>
            <field>
              <name>TI4_RMP</name>
              <bitOffset>6</bitOffset>
              <bitWidth>2</bitWidth>
            </field>
            <field>
              <name>ITR1_RMP</name>
              <bitOffset>10</bitOffset>
              <bitWidth>2</bitWidth>
            </field>
          </fields>
        </register>
        <register>
          <name>CCMR3</name>
          <addressOffset>0x54</addressOffset>
          <size>0x20</size>
          <fields>
            <field>
              <name>OC5FE</name>
              <bitOffset>2</bitOffset>
              <bitWidth>1</bitWidth>
            </field>
            <field>
              <name>OC5PE</name>
              <bitOffset>3</bitOffset>
              <bitWidth>1</bitWidth>
            </field>
            <field>
              <name>OC5M</name>
              <bitOffset>4</bitOffset>
              <bitWidth>13</bitWidth>
            </field>
            <field>
              <name>OC5CE</name>
              <bitOffset>7</bitOffset>
              <bitWidth>1</bitWidth>
            </field>
            <field>
              <name>OC6FE</name>
              <bitOffset>10</bitOffset>
              <bitWidth>1</bitWidth>
            </field>
            <field>
              <name>OC6PE</name>
              <bitOffset>11</bitOffset>
              <bitWidth>1</bitWidth>
            </field>
            <field>
              <name>OC6M</name>
              <bitOffset>12</bitOffset>
              <bitWidth>13</bitWidth>
            </field>
            <field>
              <name>OC6CE</name>
              <bitOffset>15</bitOffset>
              <bitWidth>1</bitWidth>
            </field>
          </fields>
        </register>
        <register>
          <name>CCR5</name>
          <addressOffset>0x58</addressOffset>
          <size>0x20</size>
          <fields>
            <field>
              <name>CCR5</name>
              <bitOffset>0</bitOffset>
              <bitWidth>32</bitWidth>
            </field>
            <field>
              <name>GC5C1</name>
              <bitOffset>29</bitOffset>
              <bitWidth>1</bitWidth>
            </field>
            <field>
              <name>GC5C2</name>
              <bitOffset>30</bitOffset>
              <bitWidth>1</bitWidth>
            </field>
            <field>
              <name>GC5C3</name>
              <bitOffset>31</bitOffset>
              <bitWidth>1</bitWidth>
            </field>
          </fields>
        </register>
        <register>
          <name>CCR6</name>
          <addressOffset>0x5c</addressOffset>
          <size>0x20</size>
        </register>
        <register>
          <name>AF1</name>
          <addressOffset>0x60</addressOffset>
          <size>0x20</size>
        </register>
        <register>
          <name>AF2</name>
          <addressOffset>0x64</addressOffset>
          <size>0x20</size>
        </register>
      </registers>
    </peripheral>
    <peripheral>
      <name>TIM4</name>
      <baseAddress>0x40000800</baseAddress>
      <registers>
        <register>
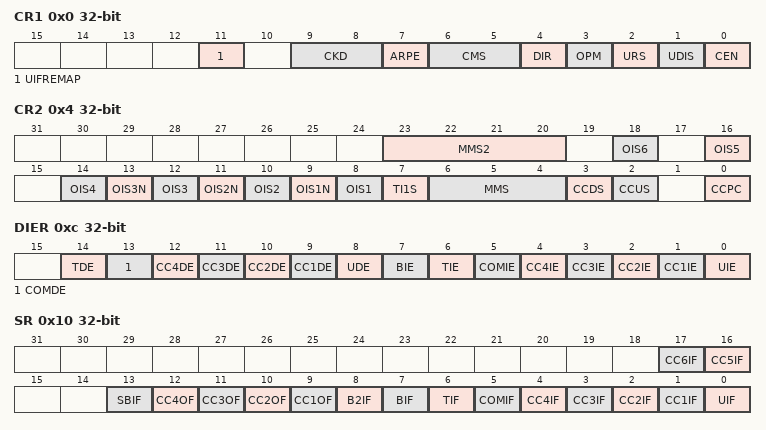
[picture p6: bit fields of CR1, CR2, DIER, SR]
          <name>CR1</name>
          <addressOffset>0x0</addressOffset>
          <size>0x20</size>
          <fields>
            <field>
              <name>CEN</name>
              <bitOffset>0</bitOffset>
              <bitWidth>1</bitWidth>
            </field>
            <field>
              <name>UDIS</name>
              <bitOffset>1</bitOffset>
              <bitWidth>1</bitWidth>
            </field>
            <field>
              <name>URS</name>
              <bitOffset>2</bitOffset>
              <bitWidth>1</bitWidth>
            </field>
            <field>
              <name>OPM</name>
              <bitOffset>3</bitOffset>
              <bitWidth>1</bitWidth>
            </field>
            <field>
              <name>DIR</name>
              <bitOffset>4</bitOffset>
              <bitWidth>1</bitWidth>
            </field>
            <field>
              <name>CMS</name>
              <bitOffset>5</bitOffset>
              <bitWidth>2</bitWidth>
            </field>
            <field>
              <name>ARPE</name>
              <bitOffset>7</bitOffset>
              <bitWidth>1</bitWidth>
            </field>
            <field>
              <name>CKD</name>
              <bitOffset>8</bitOffset>
              <bitWidth>2</bitWidth>
            </field>
            <field>
              <name>UIFREMAP</name>
              <bitOffset>11</bitOffset>
              <bitWidth>1</bitWidth>
            </field>
          </fields>
        </register>
        <register>
          <name>CR2</name>
          <addressOffset>0x4</addressOffset>
          <size>0x20</size>
          <fields>
            <field>
              <name>CCPC</name>
              <bitOffset>0</bitOffset>
              <bitWidth>1</bitWidth>
            </field>
            <field>
              <name>CCUS</name>
              <bitOffset>2</bitOffset>
              <bitWidth>1</bitWidth>
            </field>
            <field>
              <name>CCDS</name>
              <bitOffset>3</bitOffset>
              <bitWidth>1</bitWidth>
            </field>
            <field>
              <name>MMS</name>
              <bitOffset>4</bitOffset>
              <bitWidth>3</bitWidth>
            </field>
            <field>
              <name>TI1S</name>
              <bitOffset>7</bitOffset>
              <bitWidth>1</bitWidth>
            </field>
            <field>
              <name>OIS1</name>
              <bitOffset>8</bitOffset>
              <bitWidth>1</bitWidth>
            </field>
            <field>
              <name>OIS1N</name>
              <bitOffset>9</bitOffset>
              <bitWidth>1</bitWidth>
            </field>
            <field>
              <name>OIS2</name>
              <bitOffset>10</bitOffset>
              <bitWidth>1</bitWidth>
            </field>
            <field>
              <name>OIS2N</name>
              <bitOffset>11</bitOffset>
              <bitWidth>1</bitWidth>
            </field>
            <field>
              <name>OIS3</name>
              <bitOffset>12</bitOffset>
              <bitWidth>1</bitWidth>
            </field>
            <field>
              <name>OIS3N</name>
              <bitOffset>13</bitOffset>
              <bitWidth>1</bitWidth>
            </field>
            <field>
              <name>OIS4</name>
              <bitOffset>14</bitOffset>
              <bitWidth>1</bitWidth>
            </field>
            <field>
              <name>OIS5</name>
              <bitOffset>16</bitOffset>
              <bitWidth>1</bitWidth>
            </field>
            <field>
              <name>OIS6</name>
              <bitOffset>18</bitOffset>
              <bitWidth>1</bitWidth>
            </field>
            <field>
              <name>MMS2</name>
              <bitOffset>20</bitOffset>
              <bitWidth>4</bitWidth>
            </field>
          </fields>
        </register>
        <register>
          <name>SMCR</name>
          <addressOffset>0x8</addressOffset>
          <size>0x20</size>
          <fields>
            <field>
              <name>SMS</name>
              <bitOffset>0</bitOffset>
              <bitWidth>17</bitWidth>
            </field>
            <field>
              <name>TS</name>
              <bitOffset>4</bitOffset>
              <bitWidth>3</bitWidth>
            </field>
            <field>
              <name>MSM</name>
              <bitOffset>7</bitOffset>
              <bitWidth>1</bitWidth>
            </field>
            <field>
              <name>ETF</name>
              <bitOffset>8</bitOffset>
              <bitWidth>4</bitWidth>
            </field>
            <field>
              <name>ETPS</name>
              <bitOffset>12</bitOffset>
              <bitWidth>2</bitWidth>
            </field>
            <field>
              <name>ECE</name>
              <bitOffset>14</bitOffset>
              <bitWidth>1</bitWidth>
            </field>
            <field>
              <name>ETP</name>
              <bitOffset>15</bitOffset>
              <bitWidth>1</bitWidth>
            </field>
          </fields>
        </register>
        <register>
          <name>DIER</name>
          <addressOffset>0xc</addressOffset>
          <size>0x20</size>
          <fields>
            <field>
              <name>UIE</name>
              <bitOffset>0</bitOffset>
              <bitWidth>1</bitWidth>
            </field>
            <field>
              <name>CC1IE</name>
              <bitOffset>1</bitOffset>
              <bitWidth>1</bitWidth>
            </field>
            <field>
              <name>CC2IE</name>
              <bitOffset>2</bitOffset>
              <bitWidth>1</bitWidth>
            </field>
            <field>
              <name>CC3IE</name>
              <bitOffset>3</bitOffset>
              <bitWidth>1</bitWidth>
            </field>
            <field>
              <name>CC4IE</name>
              <bitOffset>4</bitOffset>
              <bitWidth>1</bitWidth>
            </field>
            <field>
              <name>COMIE</name>
              <bitOffset>5</bitOffset>
              <bitWidth>1</bitWidth>
            </field>
            <field>
              <name>TIE</name>
              <bitOffset>6</bitOffset>
              <bitWidth>1</bitWidth>
            </field>
            <field>
              <name>BIE</name>
              <bitOffset>7</bitOffset>
              <bitWidth>1</bitWidth>
            </field>
            <field>
              <name>UDE</name>
              <bitOffset>8</bitOffset>
              <bitWidth>1</bitWidth>
            </field>
            <field>
              <name>CC1DE</name>
              <bitOffset>9</bitOffset>
              <bitWidth>1</bitWidth>
            </field>
            <field>
              <name>CC2DE</name>
              <bitOffset>10</bitOffset>
              <bitWidth>1</bitWidth>
            </field>
            <field>
              <name>CC3DE</name>
              <bitOffset>11</bitOffset>
              <bitWidth>1</bitWidth>
            </field>
            <field>
              <name>CC4DE</name>
              <bitOffset>12</bitOffset>
              <bitWidth>1</bitWidth>
            </field>
            <field>
              <name>COMDE</name>
              <bitOffset>13</bitOffset>
              <bitWidth>1</bitWidth>
            </field>
            <field>
              <name>TDE</name>
              <bitOffset>14</bitOffset>
              <bitWidth>1</bitWidth>
            </field>
          </fields>
        </register>
        <register>
          <name>SR</name>
          <addressOffset>0x10</addressOffset>
          <size>0x20</size>
          <fields>
            <field>
              <name>UIF</name>
              <bitOffset>0</bitOffset>
              <bitWidth>1</bitWidth>
            </field>
            <field>
              <name>CC1IF</name>
              <bitOffset>1</bitOffset>
              <bitWidth>1</bitWidth>
            </field>
            <field>
              <name>CC2IF</name>
              <bitOffset>2</bitOffset>
              <bitWidth>1</bitWidth>
            </field>
            <field>
              <name>CC3IF</name>
              <bitOffset>3</bitOffset>
              <bitWidth>1</bitWidth>
            </field>
            <field>
              <name>CC4IF</name>
              <bitOffset>4</bitOffset>
              <bitWidth>1</bitWidth>
            </field>
            <field>
              <name>COMIF</name>
              <bitOffset>5</bitOffset>
              <bitWidth>1</bitWidth>
            </field>
            <field>
              <name>TIF</name>
              <bitOffset>6</bitOffset>
              <bitWidth>1</bitWidth>
            </field>
            <field>
              <name>BIF</name>
              <bitOffset>7</bitOffset>
              <bitWidth>1</bitWidth>
            </field>
            <field>
              <name>B2IF</name>
              <bitOffset>8</bitOffset>
              <bitWidth>1</bitWidth>
            </field>
            <field>
              <name>CC1OF</name>
              <bitOffset>9</bitOffset>
              <bitWidth>1</bitWidth>
            </field>
            <field>
              <name>CC2OF</name>
              <bitOffset>10</bitOffset>
              <bitWidth>1</bitWidth>
            </field>
            <field>
              <name>CC3OF</name>
              <bitOffset>11</bitOffset>
              <bitWidth>1</bitWidth>
            </field>
            <field>
              <name>CC4OF</name>
              <bitOffset>12</bitOffset>
              <bitWidth>1</bitWidth>
            </field>
            <field>
              <name>SBIF</name>
              <bitOffset>13</bitOffset>
              <bitWidth>1</bitWidth>
            </field>
            <field>
              <name>CC5IF</name>
              <bitOffset>16</bitOffset>
              <bitWidth>1</bitWidth>
            </field>
            <field>
              <name>CC6IF</name>
              <bitOffset>17</bitOffset>
              <bitWidth>1</bitWidth>
            </field>
          </fields>
        </register>
        <register>
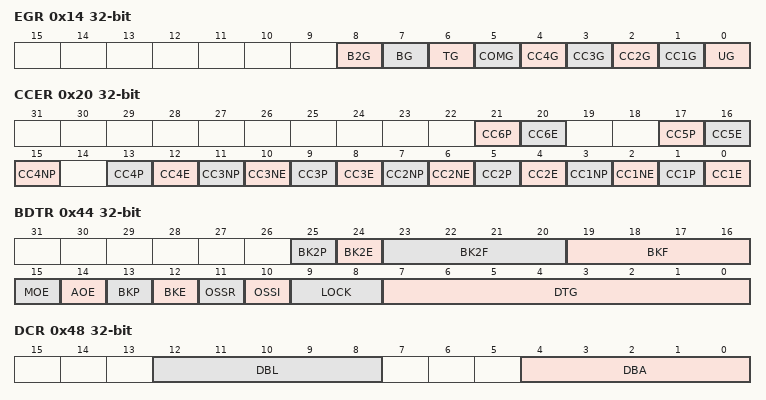
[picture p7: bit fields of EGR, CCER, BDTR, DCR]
          <name>EGR</name>
          <addressOffset>0x14</addressOffset>
          <size>0x20</size>
          <fields>
            <field>
              <name>UG</name>
              <bitOffset>0</bitOffset>
              <bitWidth>1</bitWidth>
            </field>
            <field>
              <name>CC1G</name>
              <bitOffset>1</bitOffset>
              <bitWidth>1</bitWidth>
            </field>
            <field>
              <name>CC2G</name>
              <bitOffset>2</bitOffset>
              <bitWidth>1</bitWidth>
            </field>
            <field>
              <name>CC3G</name>
              <bitOffset>3</bitOffset>
              <bitWidth>1</bitWidth>
            </field>
            <field>
              <name>CC4G</name>
              <bitOffset>4</bitOffset>
              <bitWidth>1</bitWidth>
            </field>
            <field>
              <name>COMG</name>
              <bitOffset>5</bitOffset>
              <bitWidth>1</bitWidth>
            </field>
            <field>
              <name>TG</name>
              <bitOffset>6</bitOffset>
              <bitWidth>1</bitWidth>
            </field>
            <field>
              <name>BG</name>
              <bitOffset>7</bitOffset>
              <bitWidth>1</bitWidth>
            </field>
            <field>
              <name>B2G</name>
              <bitOffset>8</bitOffset>
              <bitWidth>1</bitWidth>
            </field>
          </fields>
        </register>
        <register>
          <name>CCMR1</name>
          <addressOffset>0x18</addressOffset>
          <size>0x20</size>
          <fields>
            <field>
              <name>CC1S</name>
              <bitOffset>0</bitOffset>
              <bitWidth>2</bitWidth>
            </field>
            <field>
              <name>OC1FE</name>
              <bitOffset>2</bitOffset>
              <bitWidth>1</bitWidth>
            </field>
            <field>
              <name>OC1PE</name>
              <bitOffset>3</bitOffset>
              <bitWidth>1</bitWidth>
            </field>
            <field>
              <name>OC1M</name>
              <bitOffset>4</bitOffset>
              <bitWidth>13</bitWidth>
            </field>
            <field>
              <name>OC1CE</name>
              <bitOffset>7</bitOffset>
              <bitWidth>1</bitWidth>
            </field>
            <field>
              <name>CC2S</name>
              <bitOffset>8</bitOffset>
              <bitWidth>2</bitWidth>
            </field>
            <field>
              <name>OC2FE</name>
              <bitOffset>10</bitOffset>
              <bitWidth>1</bitWidth>
            </field>
            <field>
              <name>OC2PE</name>
              <bitOffset>11</bitOffset>
              <bitWidth>1</bitWidth>
            </field>
            <field>
              <name>OC2M</name>
              <bitOffset>12</bitOffset>
              <bitWidth>13</bitWidth>
            </field>
            <field>
              <name>OC2CE</name>
              <bitOffset>15</bitOffset>
              <bitWidth>1</bitWidth>
            </field>
          </fields>
        </register>
        <register>
          <name>CCMR2</name>
          <addressOffset>0x1c</addressOffset>
          <size>0x20</size>
          <fields>
            <field>
              <name>CC3S</name>
              <bitOffset>0</bitOffset>
              <bitWidth>2</bitWidth>
            </field>
            <field>
              <name>OC3FE</name>
              <bitOffset>2</bitOffset>
              <bitWidth>1</bitWidth>
            </field>
            <field>
              <name>OC3PE</name>
              <bitOffset>3</bitOffset>
              <bitWidth>1</bitWidth>
            </field>
            <field>
              <name>OC3M</name>
              <bitOffset>4</bitOffset>
              <bitWidth>13</bitWidth>
            </field>
            <field>
              <name>OC3CE</name>
              <bitOffset>7</bitOffset>
              <bitWidth>1</bitWidth>
            </field>
            <field>
              <name>CC4S</name>
              <bitOffset>8</bitOffset>
              <bitWidth>2</bitWidth>
            </field>
            <field>
              <name>OC4FE</name>
              <bitOffset>10</bitOffset>
              <bitWidth>1</bitWidth>
            </field>
            <field>
              <name>OC4PE</name>
              <bitOffset>11</bitOffset>
              <bitWidth>1</bitWidth>
            </field>
            <field>
              <name>OC4M</name>
              <bitOffset>12</bitOffset>
              <bitWidth>13</bitWidth>
            </field>
            <field>
              <name>OC4CE</name>
              <bitOffset>15</bitOffset>
              <bitWidth>1</bitWidth>
            </field>
          </fields>
        </register>
        <register>
          <name>CCER</name>
          <addressOffset>0x20</addressOffset>
          <size>0x20</size>
          <fields>
            <field>
              <name>CC1E</name>
              <bitOffset>0</bitOffset>
              <bitWidth>1</bitWidth>
            </field>
            <field>
              <name>CC1P</name>
              <bitOffset>1</bitOffset>
              <bitWidth>1</bitWidth>
            </field>
            <field>
              <name>CC1NE</name>
              <bitOffset>2</bitOffset>
              <bitWidth>1</bitWidth>
            </field>
            <field>
              <name>CC1NP</name>
              <bitOffset>3</bitOffset>
              <bitWidth>1</bitWidth>
            </field>
            <field>
              <name>CC2E</name>
              <bitOffset>4</bitOffset>
              <bitWidth>1</bitWidth>
            </field>
            <field>
              <name>CC2P</name>
              <bitOffset>5</bitOffset>
              <bitWidth>1</bitWidth>
            </field>
            <field>
              <name>CC2NE</name>
              <bitOffset>6</bitOffset>
              <bitWidth>1</bitWidth>
            </field>
            <field>
              <name>CC2NP</name>
              <bitOffset>7</bitOffset>
              <bitWidth>1</bitWidth>
            </field>
            <field>
              <name>CC3E</name>
              <bitOffset>8</bitOffset>
              <bitWidth>1</bitWidth>
            </field>
            <field>
              <name>CC3P</name>
              <bitOffset>9</bitOffset>
              <bitWidth>1</bitWidth>
            </field>
            <field>
              <name>CC3NE</name>
              <bitOffset>10</bitOffset>
              <bitWidth>1</bitWidth>
            </field>
            <field>
              <name>CC3NP</name>
              <bitOffset>11</bitOffset>
              <bitWidth>1</bitWidth>
            </field>
            <field>
              <name>CC4E</name>
              <bitOffset>12</bitOffset>
              <bitWidth>1</bitWidth>
            </field>
            <field>
              <name>CC4P</name>
              <bitOffset>13</bitOffset>
              <bitWidth>1</bitWidth>
            </field>
            <field>
              <name>CC4NP</name>
              <bitOffset>15</bitOffset>
              <bitWidth>1</bitWidth>
            </field>
            <field>
              <name>CC5E</name>
              <bitOffset>16</bitOffset>
              <bitWidth>1</bitWidth>
            </field>
            <field>
              <name>CC5P</name>
              <bitOffset>17</bitOffset>
              <bitWidth>1</bitWidth>
            </field>
            <field>
              <name>CC6E</name>
              <bitOffset>20</bitOffset>
              <bitWidth>1</bitWidth>
            </field>
            <field>
              <name>CC6P</name>
              <bitOffset>21</bitOffset>
              <bitWidth>1</bitWidth>
            </field>
          </fields>
        </register>
        <register>
          <name>CNT</name>
          <addressOffset>0x24</addressOffset>
          <size>0x20</size>
          <fields>
            <field>
              <name>CNT</name>
              <bitOffset>0</bitOffset>
              <bitWidth>32</bitWidth>
            </field>
            <field>
              <name>UIFCPY</name>
              <bitOffset>31</bitOffset>
              <bitWidth>1</bitWidth>
            </field>
          </fields>
        </register>
        <register>
          <name>PSC</name>
          <addressOffset>0x28</addressOffset>
          <size>0x20</size>
          <fields>
            <field>
              <name>PSC</name>
              <bitOffset>0</bitOffset>
              <bitWidth>16</bitWidth>
            </field>
          </fields>
        </register>
        <register>
          <name>ARR</name>
          <addressOffset>0x2c</addressOffset>
          <size>0x20</size>
          <fields>
            <field>
              <name>ARR</name>
              <bitOffset>0</bitOffset>
              <bitWidth>32</bitWidth>
            </field>
          </fields>
        </register>
        <register>
          <name>RCR</name>
          <addressOffset>0x30</addressOffset>
          <size>0x20</size>
          <fields>
            <field>
              <name>REP</name>
              <bitOffset>0</bitOffset>
              <bitWidth>16</bitWidth>
            </field>
          </fields>
        </register>
        <register>
          <name>CCR1</name>
          <addressOffset>0x34</addressOffset>
          <size>0x20</size>
          <fields>
            <field>
              <name>CCR1</name>
              <bitOffset>0</bitOffset>
              <bitWidth>16</bitWidth>
            </field>
          </fields>
        </register>
        <register>
          <name>CCR2</name>
          <addressOffset>0x38</addressOffset>
          <size>0x20</size>
          <fields>
            <field>
              <name>CCR2</name>
              <bitOffset>0</bitOffset>
              <bitWidth>16</bitWidth>
            </field>
          </fields>
        </register>
        <register>
          <name>CCR3</name>
          <addressOffset>0x3c</addressOffset>
          <size>0x20</size>
          <fields>
            <field>
              <name>CCR3</name>
              <bitOffset>0</bitOffset>
              <bitWidth>16</bitWidth>
            </field>
          </fields>
        </register>
        <register>
          <name>CCR4</name>
          <addressOffset>0x40</addressOffset>
          <size>0x20</size>
          <fields>
            <field>
              <name>CCR4</name>
              <bitOffset>0</bitOffset>
              <bitWidth>16</bitWidth>
            </field>
          </fields>
        </register>
        <register>
          <name>BDTR</name>
          <addressOffset>0x44</addressOffset>
          <size>0x20</size>
          <fields>
            <field>
              <name>DTG</name>
              <bitOffset>0</bitOffset>
              <bitWidth>8</bitWidth>
            </field>
            <field>
              <name>LOCK</name>
              <bitOffset>8</bitOffset>
              <bitWidth>2</bitWidth>
            </field>
            <field>
              <name>OSSI</name>
              <bitOffset>10</bitOffset>
              <bitWidth>1</bitWidth>
            </field>
            <field>
              <name>OSSR</name>
              <bitOffset>11</bitOffset>
              <bitWidth>1</bitWidth>
            </field>
            <field>
              <name>BKE</name>
              <bitOffset>12</bitOffset>
              <bitWidth>1</bitWidth>
            </field>
            <field>
              <name>BKP</name>
              <bitOffset>13</bitOffset>
              <bitWidth>1</bitWidth>
            </field>
            <field>
              <name>AOE</name>
              <bitOffset>14</bitOffset>
              <bitWidth>1</bitWidth>
            </field>
            <field>
              <name>MOE</name>
              <bitOffset>15</bitOffset>
              <bitWidth>1</bitWidth>
            </field>
            <field>
              <name>BKF</name>
              <bitOffset>16</bitOffset>
              <bitWidth>4</bitWidth>
            </field>
            <field>
              <name>BK2F</name>
              <bitOffset>20</bitOffset>
              <bitWidth>4</bitWidth>
            </field>
            <field>
              <name>BK2E</name>
              <bitOffset>24</bitOffset>
              <bitWidth>1</bitWidth>
            </field>
            <field>
              <name>BK2P</name>
              <bitOffset>25</bitOffset>
              <bitWidth>1</bitWidth>
            </field>
          </fields>
        </register>
        <register>
          <name>DCR</name>
          <addressOffset>0x48</addressOffset>
          <size>0x20</size>
          <fields>
            <field>
              <name>DBA</name>
              <bitOffset>0</bitOffset>
              <bitWidth>5</bitWidth>
            </field>
            <field>
              <name>DBL</name>
              <bitOffset>8</bitOffset>
              <bitWidth>5</bitWidth>
            </field>
          </fields>
        </register>
        <register>
          <name>DMAR</name>
          <addressOffset>0x4c</addressOffset>
          <size>0x20</size>
          <fields>
            <field>
              <name>DMAB</name>
              <bitOffset>0</bitOffset>
              <bitWidth>16</bitWidth>
            </field>
          </fields>
        </register>
        <register>
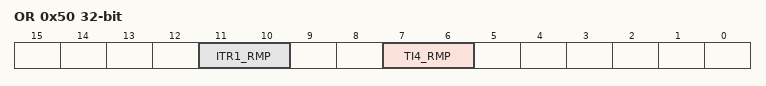
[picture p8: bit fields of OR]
          <name>OR</name>
          <addressOffset>0x50</addressOffset>
          <size>0x20</size>
          <fields>
            <field>
              <name>TI4_RMP</name>
              <bitOffset>6</bitOffset>
              <bitWidth>2</bitWidth>
            </field>
            <field>
              <name>ITR1_RMP</name>
              <bitOffset>10</bitOffset>
              <bitWidth>2</bitWidth>
            </field>
          </fields>
        </register>
        <register>
          <name>CCMR3</name>
          <addressOffset>0x54</addressOffset>
          <size>0x20</size>
          <fields>
            <field>
              <name>OC5FE</name>
              <bitOffset>2</bitOffset>
              <bitWidth>1</bitWidth>
            </field>
            <field>
              <name>OC5PE</name>
              <bitOffset>3</bitOffset>
              <bitWidth>1</bitWidth>
            </field>
            <field>
              <name>OC5M</name>
              <bitOffset>4</bitOffset>
              <bitWidth>13</bitWidth>
            </field>
            <field>
              <name>OC5CE</name>
              <bitOffset>7</bitOffset>
              <bitWidth>1</bitWidth>
            </field>
            <field>
              <name>OC6FE</name>
              <bitOffset>10</bitOffset>
              <bitWidth>1</bitWidth>
            </field>
            <field>
              <name>OC6PE</name>
              <bitOffset>11</bitOffset>
              <bitWidth>1</bitWidth>
            </field>
            <field>
              <name>OC6M</name>
              <bitOffset>12</bitOffset>
              <bitWidth>13</bitWidth>
            </field>
            <field>
              <name>OC6CE</name>
              <bitOffset>15</bitOffset>
              <bitWidth>1</bitWidth>
            </field>
          </fields>
        </register>
        <register>
          <name>CCR5</name>
          <addressOffset>0x58</addressOffset>
          <size>0x20</size>
          <fields>
            <field>
              <name>CCR5</name>
              <bitOffset>0</bitOffset>
              <bitWidth>32</bitWidth>
            </field>
            <field>
              <name>GC5C1</name>
              <bitOffset>29</bitOffset>
              <bitWidth>1</bitWidth>
            </field>
            <field>
              <name>GC5C2</name>
              <bitOffset>30</bitOffset>
              <bitWidth>1</bitWidth>
            </field>
            <field>
              <name>GC5C3</name>
              <bitOffset>31</bitOffset>
              <bitWidth>1</bitWidth>
            </field>
          </fields>
        </register>
        <register>
          <name>CCR6</name>
          <addressOffset>0x5c</addressOffset>
          <size>0x20</size>
        </register>
        <register>
          <name>AF1</name>
          <addressOffset>0x60</addressOffset>
          <size>0x20</size>
        </register>
        <register>
          <name>AF2</name>
          <addressOffset>0x64</addressOffset>
          <size>0x20</size>
        </register>
      </registers>
    </peripheral>
    <peripheral>
      <name>TIM5</name>
      <baseAddress>0x40000c00</baseAddress>
      <registers>
        <register>
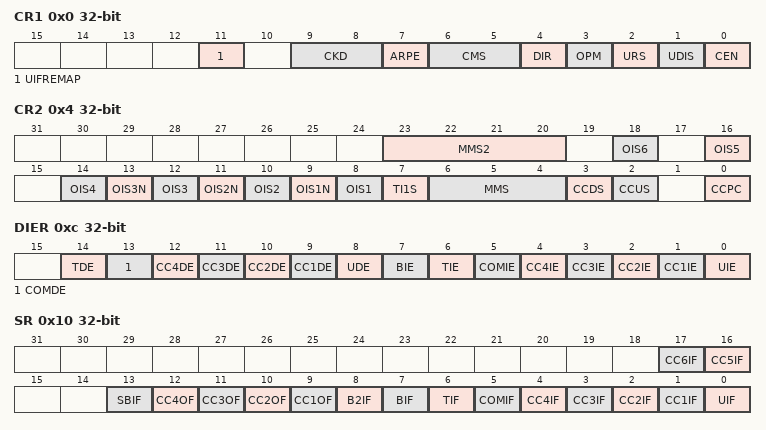
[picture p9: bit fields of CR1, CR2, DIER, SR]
          <name>CR1</name>
          <addressOffset>0x0</addressOffset>
          <size>0x20</size>
          <fields>
            <field>
              <name>CEN</name>
              <bitOffset>0</bitOffset>
              <bitWidth>1</bitWidth>
            </field>
            <field>
              <name>UDIS</name>
              <bitOffset>1</bitOffset>
              <bitWidth>1</bitWidth>
            </field>
            <field>
              <name>URS</name>
              <bitOffset>2</bitOffset>
              <bitWidth>1</bitWidth>
            </field>
            <field>
              <name>OPM</name>
              <bitOffset>3</bitOffset>
              <bitWidth>1</bitWidth>
            </field>
            <field>
              <name>DIR</name>
              <bitOffset>4</bitOffset>
              <bitWidth>1</bitWidth>
            </field>
            <field>
              <name>CMS</name>
              <bitOffset>5</bitOffset>
              <bitWidth>2</bitWidth>
            </field>
            <field>
              <name>ARPE</name>
              <bitOffset>7</bitOffset>
              <bitWidth>1</bitWidth>
            </field>
            <field>
              <name>CKD</name>
              <bitOffset>8</bitOffset>
              <bitWidth>2</bitWidth>
            </field>
            <field>
              <name>UIFREMAP</name>
              <bitOffset>11</bitOffset>
              <bitWidth>1</bitWidth>
            </field>
          </fields>
        </register>
        <register>
          <name>CR2</name>
          <addressOffset>0x4</addressOffset>
          <size>0x20</size>
          <fields>
            <field>
              <name>CCPC</name>
              <bitOffset>0</bitOffset>
              <bitWidth>1</bitWidth>
            </field>
            <field>
              <name>CCUS</name>
              <bitOffset>2</bitOffset>
              <bitWidth>1</bitWidth>
            </field>
            <field>
              <name>CCDS</name>
              <bitOffset>3</bitOffset>
              <bitWidth>1</bitWidth>
            </field>
            <field>
              <name>MMS</name>
              <bitOffset>4</bitOffset>
              <bitWidth>3</bitWidth>
            </field>
            <field>
              <name>TI1S</name>
              <bitOffset>7</bitOffset>
              <bitWidth>1</bitWidth>
            </field>
            <field>
              <name>OIS1</name>
              <bitOffset>8</bitOffset>
              <bitWidth>1</bitWidth>
            </field>
            <field>
              <name>OIS1N</name>
              <bitOffset>9</bitOffset>
              <bitWidth>1</bitWidth>
            </field>
            <field>
              <name>OIS2</name>
              <bitOffset>10</bitOffset>
              <bitWidth>1</bitWidth>
            </field>
            <field>
              <name>OIS2N</name>
              <bitOffset>11</bitOffset>
              <bitWidth>1</bitWidth>
            </field>
            <field>
              <name>OIS3</name>
              <bitOffset>12</bitOffset>
              <bitWidth>1</bitWidth>
            </field>
            <field>
              <name>OIS3N</name>
              <bitOffset>13</bitOffset>
              <bitWidth>1</bitWidth>
            </field>
            <field>
              <name>OIS4</name>
              <bitOffset>14</bitOffset>
              <bitWidth>1</bitWidth>
            </field>
            <field>
              <name>OIS5</name>
              <bitOffset>16</bitOffset>
              <bitWidth>1</bitWidth>
            </field>
            <field>
              <name>OIS6</name>
              <bitOffset>18</bitOffset>
              <bitWidth>1</bitWidth>
            </field>
            <field>
              <name>MMS2</name>
              <bitOffset>20</bitOffset>
              <bitWidth>4</bitWidth>
            </field>
          </fields>
        </register>
        <register>
          <name>SMCR</name>
          <addressOffset>0x8</addressOffset>
          <size>0x20</size>
          <fields>
            <field>
              <name>SMS</name>
              <bitOffset>0</bitOffset>
              <bitWidth>17</bitWidth>
            </field>
            <field>
              <name>TS</name>
              <bitOffset>4</bitOffset>
              <bitWidth>3</bitWidth>
            </field>
            <field>
              <name>MSM</name>
              <bitOffset>7</bitOffset>
              <bitWidth>1</bitWidth>
            </field>
            <field>
              <name>ETF</name>
              <bitOffset>8</bitOffset>
              <bitWidth>4</bitWidth>
            </field>
            <field>
              <name>ETPS</name>
              <bitOffset>12</bitOffset>
              <bitWidth>2</bitWidth>
            </field>
            <field>
              <name>ECE</name>
              <bitOffset>14</bitOffset>
              <bitWidth>1</bitWidth>
            </field>
            <field>
              <name>ETP</name>
              <bitOffset>15</bitOffset>
              <bitWidth>1</bitWidth>
            </field>
          </fields>
        </register>
        <register>
          <name>DIER</name>
          <addressOffset>0xc</addressOffset>
          <size>0x20</size>
          <fields>
            <field>
              <name>UIE</name>
              <bitOffset>0</bitOffset>
              <bitWidth>1</bitWidth>
            </field>
            <field>
              <name>CC1IE</name>
              <bitOffset>1</bitOffset>
              <bitWidth>1</bitWidth>
            </field>
            <field>
              <name>CC2IE</name>
              <bitOffset>2</bitOffset>
              <bitWidth>1</bitWidth>
            </field>
            <field>
              <name>CC3IE</name>
              <bitOffset>3</bitOffset>
              <bitWidth>1</bitWidth>
            </field>
            <field>
              <name>CC4IE</name>
              <bitOffset>4</bitOffset>
              <bitWidth>1</bitWidth>
            </field>
            <field>
              <name>COMIE</name>
              <bitOffset>5</bitOffset>
              <bitWidth>1</bitWidth>
            </field>
            <field>
              <name>TIE</name>
              <bitOffset>6</bitOffset>
              <bitWidth>1</bitWidth>
            </field>
            <field>
              <name>BIE</name>
              <bitOffset>7</bitOffset>
              <bitWidth>1</bitWidth>
            </field>
            <field>
              <name>UDE</name>
              <bitOffset>8</bitOffset>
              <bitWidth>1</bitWidth>
            </field>
            <field>
              <name>CC1DE</name>
              <bitOffset>9</bitOffset>
              <bitWidth>1</bitWidth>
            </field>
            <field>
              <name>CC2DE</name>
              <bitOffset>10</bitOffset>
              <bitWidth>1</bitWidth>
            </field>
            <field>
              <name>CC3DE</name>
              <bitOffset>11</bitOffset>
              <bitWidth>1</bitWidth>
            </field>
            <field>
              <name>CC4DE</name>
              <bitOffset>12</bitOffset>
              <bitWidth>1</bitWidth>
            </field>
            <field>
              <name>COMDE</name>
              <bitOffset>13</bitOffset>
              <bitWidth>1</bitWidth>
            </field>
            <field>
              <name>TDE</name>
              <bitOffset>14</bitOffset>
              <bitWidth>1</bitWidth>
            </field>
          </fields>
        </register>
        <register>
          <name>SR</name>
          <addressOffset>0x10</addressOffset>
          <size>0x20</size>
          <fields>
            <field>
              <name>UIF</name>
              <bitOffset>0</bitOffset>
              <bitWidth>1</bitWidth>
            </field>
            <field>
              <name>CC1IF</name>
              <bitOffset>1</bitOffset>
              <bitWidth>1</bitWidth>
            </field>
            <field>
              <name>CC2IF</name>
              <bitOffset>2</bitOffset>
              <bitWidth>1</bitWidth>
            </field>
            <field>
              <name>CC3IF</name>
              <bitOffset>3</bitOffset>
              <bitWidth>1</bitWidth>
            </field>
            <field>
              <name>CC4IF</name>
              <bitOffset>4</bitOffset>
              <bitWidth>1</bitWidth>
            </field>
            <field>
              <name>COMIF</name>
              <bitOffset>5</bitOffset>
              <bitWidth>1</bitWidth>
            </field>
            <field>
              <name>TIF</name>
              <bitOffset>6</bitOffset>
              <bitWidth>1</bitWidth>
            </field>
            <field>
              <name>BIF</name>
              <bitOffset>7</bitOffset>
              <bitWidth>1</bitWidth>
            </field>
            <field>
              <name>B2IF</name>
              <bitOffset>8</bitOffset>
              <bitWidth>1</bitWidth>
            </field>
            <field>
              <name>CC1OF</name>
              <bitOffset>9</bitOffset>
              <bitWidth>1</bitWidth>
            </field>
            <field>
              <name>CC2OF</name>
              <bitOffset>10</bitOffset>
              <bitWidth>1</bitWidth>
            </field>
            <field>
              <name>CC3OF</name>
              <bitOffset>11</bitOffset>
              <bitWidth>1</bitWidth>
            </field>
            <field>
              <name>CC4OF</name>
              <bitOffset>12</bitOffset>
              <bitWidth>1</bitWidth>
            </field>
            <field>
              <name>SBIF</name>
              <bitOffset>13</bitOffset>
              <bitWidth>1</bitWidth>
            </field>
            <field>
              <name>CC5IF</name>
              <bitOffset>16</bitOffset>
              <bitWidth>1</bitWidth>
            </field>
            <field>
              <name>CC6IF</name>
              <bitOffset>17</bitOffset>
              <bitWidth>1</bitWidth>
            </field>
          </fields>
        </register>
        <register>
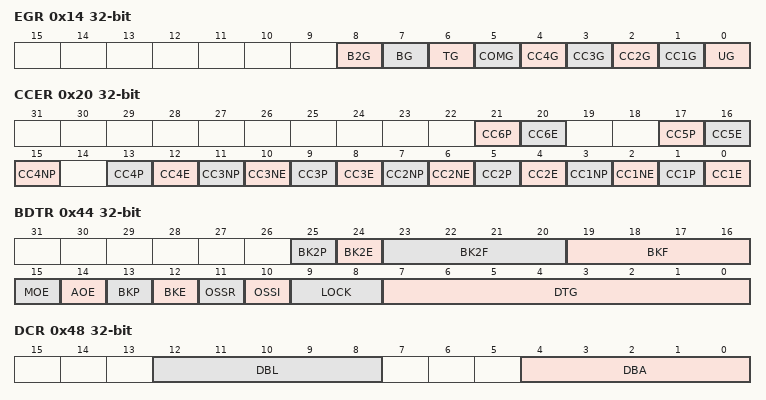
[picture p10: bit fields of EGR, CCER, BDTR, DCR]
          <name>EGR</name>
          <addressOffset>0x14</addressOffset>
          <size>0x20</size>
          <fields>
            <field>
              <name>UG</name>
              <bitOffset>0</bitOffset>
              <bitWidth>1</bitWidth>
            </field>
            <field>
              <name>CC1G</name>
              <bitOffset>1</bitOffset>
              <bitWidth>1</bitWidth>
            </field>
            <field>
              <name>CC2G</name>
              <bitOffset>2</bitOffset>
              <bitWidth>1</bitWidth>
            </field>
            <field>
              <name>CC3G</name>
              <bitOffset>3</bitOffset>
              <bitWidth>1</bitWidth>
            </field>
            <field>
              <name>CC4G</name>
              <bitOffset>4</bitOffset>
              <bitWidth>1</bitWidth>
            </field>
            <field>
              <name>COMG</name>
              <bitOffset>5</bitOffset>
              <bitWidth>1</bitWidth>
            </field>
            <field>
              <name>TG</name>
              <bitOffset>6</bitOffset>
              <bitWidth>1</bitWidth>
            </field>
            <field>
              <name>BG</name>
              <bitOffset>7</bitOffset>
              <bitWidth>1</bitWidth>
            </field>
            <field>
              <name>B2G</name>
              <bitOffset>8</bitOffset>
              <bitWidth>1</bitWidth>
            </field>
          </fields>
        </register>
        <register>
          <name>CCMR1</name>
          <addressOffset>0x18</addressOffset>
          <size>0x20</size>
          <fields>
            <field>
              <name>CC1S</name>
              <bitOffset>0</bitOffset>
              <bitWidth>2</bitWidth>
            </field>
            <field>
              <name>OC1FE</name>
              <bitOffset>2</bitOffset>
              <bitWidth>1</bitWidth>
            </field>
            <field>
              <name>OC1PE</name>
              <bitOffset>3</bitOffset>
              <bitWidth>1</bitWidth>
            </field>
            <field>
              <name>OC1M</name>
              <bitOffset>4</bitOffset>
              <bitWidth>13</bitWidth>
            </field>
            <field>
              <name>OC1CE</name>
              <bitOffset>7</bitOffset>
              <bitWidth>1</bitWidth>
            </field>
            <field>
              <name>CC2S</name>
              <bitOffset>8</bitOffset>
              <bitWidth>2</bitWidth>
            </field>
            <field>
              <name>OC2FE</name>
              <bitOffset>10</bitOffset>
              <bitWidth>1</bitWidth>
            </field>
            <field>
              <name>OC2PE</name>
              <bitOffset>11</bitOffset>
              <bitWidth>1</bitWidth>
            </field>
            <field>
              <name>OC2M</name>
              <bitOffset>12</bitOffset>
              <bitWidth>13</bitWidth>
            </field>
            <field>
              <name>OC2CE</name>
              <bitOffset>15</bitOffset>
              <bitWidth>1</bitWidth>
            </field>
          </fields>
        </register>
        <register>
          <name>CCMR2</name>
          <addressOffset>0x1c</addressOffset>
          <size>0x20</size>
          <fields>
            <field>
              <name>CC3S</name>
              <bitOffset>0</bitOffset>
              <bitWidth>2</bitWidth>
            </field>
            <field>
              <name>OC3FE</name>
              <bitOffset>2</bitOffset>
              <bitWidth>1</bitWidth>
            </field>
            <field>
              <name>OC3PE</name>
              <bitOffset>3</bitOffset>
              <bitWidth>1</bitWidth>
            </field>
            <field>
              <name>OC3M</name>
              <bitOffset>4</bitOffset>
              <bitWidth>13</bitWidth>
            </field>
            <field>
              <name>OC3CE</name>
              <bitOffset>7</bitOffset>
              <bitWidth>1</bitWidth>
            </field>
            <field>
              <name>CC4S</name>
              <bitOffset>8</bitOffset>
              <bitWidth>2</bitWidth>
            </field>
            <field>
              <name>OC4FE</name>
              <bitOffset>10</bitOffset>
              <bitWidth>1</bitWidth>
            </field>
            <field>
              <name>OC4PE</name>
              <bitOffset>11</bitOffset>
              <bitWidth>1</bitWidth>
            </field>
            <field>
              <name>OC4M</name>
              <bitOffset>12</bitOffset>
              <bitWidth>13</bitWidth>
            </field>
            <field>
              <name>OC4CE</name>
              <bitOffset>15</bitOffset>
              <bitWidth>1</bitWidth>
            </field>
          </fields>
        </register>
        <register>
          <name>CCER</name>
          <addressOffset>0x20</addressOffset>
          <size>0x20</size>
          <fields>
            <field>
              <name>CC1E</name>
              <bitOffset>0</bitOffset>
              <bitWidth>1</bitWidth>
            </field>
            <field>
              <name>CC1P</name>
              <bitOffset>1</bitOffset>
              <bitWidth>1</bitWidth>
            </field>
            <field>
              <name>CC1NE</name>
              <bitOffset>2</bitOffset>
              <bitWidth>1</bitWidth>
            </field>
            <field>
              <name>CC1NP</name>
              <bitOffset>3</bitOffset>
              <bitWidth>1</bitWidth>
            </field>
            <field>
              <name>CC2E</name>
              <bitOffset>4</bitOffset>
              <bitWidth>1</bitWidth>
            </field>
            <field>
              <name>CC2P</name>
              <bitOffset>5</bitOffset>
              <bitWidth>1</bitWidth>
            </field>
            <field>
              <name>CC2NE</name>
              <bitOffset>6</bitOffset>
              <bitWidth>1</bitWidth>
            </field>
            <field>
              <name>CC2NP</name>
              <bitOffset>7</bitOffset>
              <bitWidth>1</bitWidth>
            </field>
            <field>
              <name>CC3E</name>
              <bitOffset>8</bitOffset>
              <bitWidth>1</bitWidth>
            </field>
            <field>
              <name>CC3P</name>
              <bitOffset>9</bitOffset>
              <bitWidth>1</bitWidth>
            </field>
            <field>
              <name>CC3NE</name>
              <bitOffset>10</bitOffset>
              <bitWidth>1</bitWidth>
            </field>
            <field>
              <name>CC3NP</name>
              <bitOffset>11</bitOffset>
              <bitWidth>1</bitWidth>
            </field>
            <field>
              <name>CC4E</name>
              <bitOffset>12</bitOffset>
              <bitWidth>1</bitWidth>
            </field>
            <field>
              <name>CC4P</name>
              <bitOffset>13</bitOffset>
              <bitWidth>1</bitWidth>
            </field>
            <field>
              <name>CC4NP</name>
              <bitOffset>15</bitOffset>
              <bitWidth>1</bitWidth>
            </field>
            <field>
              <name>CC5E</name>
              <bitOffset>16</bitOffset>
              <bitWidth>1</bitWidth>
            </field>
            <field>
              <name>CC5P</name>
              <bitOffset>17</bitOffset>
              <bitWidth>1</bitWidth>
            </field>
            <field>
              <name>CC6E</name>
              <bitOffset>20</bitOffset>
              <bitWidth>1</bitWidth>
            </field>
            <field>
              <name>CC6P</name>
              <bitOffset>21</bitOffset>
              <bitWidth>1</bitWidth>
            </field>
          </fields>
        </register>
        <register>
          <name>CNT</name>
          <addressOffset>0x24</addressOffset>
          <size>0x20</size>
          <fields>
            <field>
              <name>CNT</name>
              <bitOffset>0</bitOffset>
              <bitWidth>32</bitWidth>
            </field>
            <field>
              <name>UIFCPY</name>
              <bitOffset>31</bitOffset>
              <bitWidth>1</bitWidth>
            </field>
          </fields>
        </register>
        <register>
          <name>PSC</name>
          <addressOffset>0x28</addressOffset>
          <size>0x20</size>
          <fields>
            <field>
              <name>PSC</name>
              <bitOffset>0</bitOffset>
              <bitWidth>16</bitWidth>
            </field>
          </fields>
        </register>
        <register>
          <name>ARR</name>
          <addressOffset>0x2c</addressOffset>
          <size>0x20</size>
          <fields>
            <field>
              <name>ARR</name>
              <bitOffset>0</bitOffset>
              <bitWidth>32</bitWidth>
            </field>
          </fields>
        </register>
        <register>
          <name>RCR</name>
          <addressOffset>0x30</addressOffset>
          <size>0x20</size>
          <fields>
            <field>
              <name>REP</name>
              <bitOffset>0</bitOffset>
              <bitWidth>16</bitWidth>
            </field>
          </fields>
        </register>
        <register>
          <name>CCR1</name>
          <addressOffset>0x34</addressOffset>
          <size>0x20</size>
          <fields>
            <field>
              <name>CCR1</name>
              <bitOffset>0</bitOffset>
              <bitWidth>16</bitWidth>
            </field>
          </fields>
        </register>
        <register>
          <name>CCR2</name>
          <addressOffset>0x38</addressOffset>
          <size>0x20</size>
          <fields>
            <field>
              <name>CCR2</name>
              <bitOffset>0</bitOffset>
              <bitWidth>16</bitWidth>
            </field>
          </fields>
        </register>
        <register>
          <name>CCR3</name>
          <addressOffset>0x3c</addressOffset>
          <size>0x20</size>
          <fields>
            <field>
              <name>CCR3</name>
              <bitOffset>0</bitOffset>
              <bitWidth>16</bitWidth>
            </field>
          </fields>
        </register>
        <register>
          <name>CCR4</name>
          <addressOffset>0x40</addressOffset>
          <size>0x20</size>
          <fields>
            <field>
              <name>CCR4</name>
              <bitOffset>0</bitOffset>
              <bitWidth>16</bitWidth>
            </field>
          </fields>
        </register>
        <register>
          <name>BDTR</name>
          <addressOffset>0x44</addressOffset>
          <size>0x20</size>
          <fields>
            <field>
              <name>DTG</name>
              <bitOffset>0</bitOffset>
              <bitWidth>8</bitWidth>
            </field>
            <field>
              <name>LOCK</name>
              <bitOffset>8</bitOffset>
              <bitWidth>2</bitWidth>
            </field>
            <field>
              <name>OSSI</name>
              <bitOffset>10</bitOffset>
              <bitWidth>1</bitWidth>
            </field>
            <field>
              <name>OSSR</name>
              <bitOffset>11</bitOffset>
              <bitWidth>1</bitWidth>
            </field>
            <field>
              <name>BKE</name>
              <bitOffset>12</bitOffset>
              <bitWidth>1</bitWidth>
            </field>
            <field>
              <name>BKP</name>
              <bitOffset>13</bitOffset>
              <bitWidth>1</bitWidth>
            </field>
            <field>
              <name>AOE</name>
              <bitOffset>14</bitOffset>
              <bitWidth>1</bitWidth>
            </field>
            <field>
              <name>MOE</name>
              <bitOffset>15</bitOffset>
              <bitWidth>1</bitWidth>
            </field>
            <field>
              <name>BKF</name>
              <bitOffset>16</bitOffset>
              <bitWidth>4</bitWidth>
            </field>
            <field>
              <name>BK2F</name>
              <bitOffset>20</bitOffset>
              <bitWidth>4</bitWidth>
            </field>
            <field>
              <name>BK2E</name>
              <bitOffset>24</bitOffset>
              <bitWidth>1</bitWidth>
            </field>
            <field>
              <name>BK2P</name>
              <bitOffset>25</bitOffset>
              <bitWidth>1</bitWidth>
            </field>
          </fields>
        </register>
        <register>
          <name>DCR</name>
          <addressOffset>0x48</addressOffset>
          <size>0x20</size>
          <fields>
            <field>
              <name>DBA</name>
              <bitOffset>0</bitOffset>
              <bitWidth>5</bitWidth>
            </field>
            <field>
              <name>DBL</name>
              <bitOffset>8</bitOffset>
              <bitWidth>5</bitWidth>
            </field>
          </fields>
        </register>
        <register>
          <name>DMAR</name>
          <addressOffset>0x4c</addressOffset>
          <size>0x20</size>
          <fields>
            <field>
              <name>DMAB</name>
              <bitOffset>0</bitOffset>
              <bitWidth>16</bitWidth>
            </field>
          </fields>
        </register>
        <register>
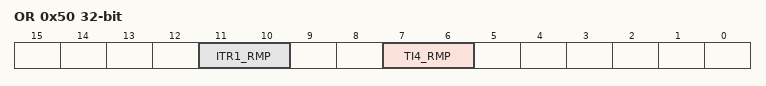
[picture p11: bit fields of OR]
          <name>OR</name>
          <addressOffset>0x50</addressOffset>
          <size>0x20</size>
          <fields>
            <field>
              <name>TI4_RMP</name>
              <bitOffset>6</bitOffset>
              <bitWidth>2</bitWidth>
            </field>
            <field>
              <name>ITR1_RMP</name>
              <bitOffset>10</bitOffset>
              <bitWidth>2</bitWidth>
            </field>
          </fields>
        </register>
        <register>
          <name>CCMR3</name>
          <addressOffset>0x54</addressOffset>
          <size>0x20</size>
          <fields>
            <field>
              <name>OC5FE</name>
              <bitOffset>2</bitOffset>
              <bitWidth>1</bitWidth>
            </field>
            <field>
              <name>OC5PE</name>
              <bitOffset>3</bitOffset>
              <bitWidth>1</bitWidth>
            </field>
            <field>
              <name>OC5M</name>
              <bitOffset>4</bitOffset>
              <bitWidth>13</bitWidth>
            </field>
            <field>
              <name>OC5CE</name>
              <bitOffset>7</bitOffset>
              <bitWidth>1</bitWidth>
            </field>
            <field>
              <name>OC6FE</name>
              <bitOffset>10</bitOffset>
              <bitWidth>1</bitWidth>
            </field>
            <field>
              <name>OC6PE</name>
              <bitOffset>11</bitOffset>
              <bitWidth>1</bitWidth>
            </field>
            <field>
              <name>OC6M</name>
              <bitOffset>12</bitOffset>
              <bitWidth>13</bitWidth>
            </field>
            <field>
              <name>OC6CE</name>
              <bitOffset>15</bitOffset>
              <bitWidth>1</bitWidth>
            </field>
          </fields>
        </register>
        <register>
          <name>CCR5</name>
          <addressOffset>0x58</addressOffset>
          <size>0x20</size>
          <fields>
            <field>
              <name>CCR5</name>
              <bitOffset>0</bitOffset>
              <bitWidth>32</bitWidth>
            </field>
            <field>
              <name>GC5C1</name>
              <bitOffset>29</bitOffset>
              <bitWidth>1</bitWidth>
            </field>
            <field>
              <name>GC5C2</name>
              <bitOffset>30</bitOffset>
              <bitWidth>1</bitWidth>
            </field>
            <field>
              <name>GC5C3</name>
              <bitOffset>31</bitOffset>
              <bitWidth>1</bitWidth>
            </field>
          </fields>
        </register>
        <register>
          <name>CCR6</name>
          <addressOffset>0x5c</addressOffset>
          <size>0x20</size>
        </register>
        <register>
          <name>AF1</name>
          <addressOffset>0x60</addressOffset>
          <size>0x20</size>
        </register>
        <register>
          <name>AF2</name>
          <addressOffset>0x64</addressOffset>
          <size>0x20</size>
        </register>
      </registers>
    </peripheral>
    <peripheral>
      <name>TIM6</name>
      <baseAddress>0x40001000</baseAddress>
      <registers>
        <register>
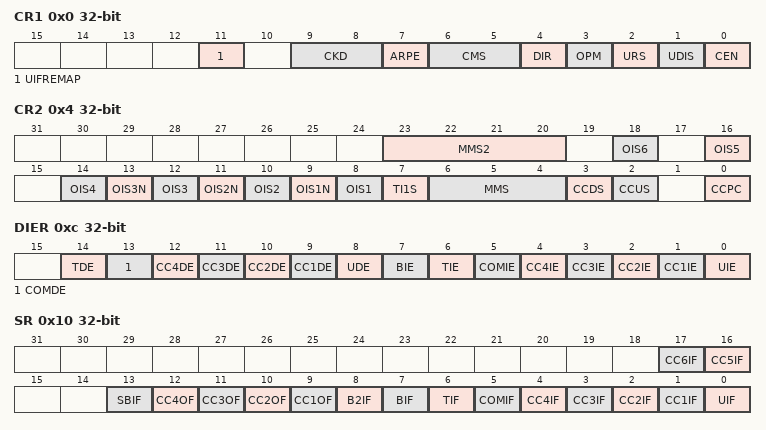
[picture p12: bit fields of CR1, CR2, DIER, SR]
          <name>CR1</name>
          <addressOffset>0x0</addressOffset>
          <size>0x20</size>
          <fields>
            <field>
              <name>CEN</name>
              <bitOffset>0</bitOffset>
              <bitWidth>1</bitWidth>
            </field>
            <field>
              <name>UDIS</name>
              <bitOffset>1</bitOffset>
              <bitWidth>1</bitWidth>
            </field>
            <field>
              <name>URS</name>
              <bitOffset>2</bitOffset>
              <bitWidth>1</bitWidth>
            </field>
            <field>
              <name>OPM</name>
              <bitOffset>3</bitOffset>
              <bitWidth>1</bitWidth>
            </field>
            <field>
              <name>DIR</name>
              <bitOffset>4</bitOffset>
              <bitWidth>1</bitWidth>
            </field>
            <field>
              <name>CMS</name>
              <bitOffset>5</bitOffset>
              <bitWidth>2</bitWidth>
            </field>
            <field>
              <name>ARPE</name>
              <bitOffset>7</bitOffset>
              <bitWidth>1</bitWidth>
            </field>
            <field>
              <name>CKD</name>
              <bitOffset>8</bitOffset>
              <bitWidth>2</bitWidth>
            </field>
            <field>
              <name>UIFREMAP</name>
              <bitOffset>11</bitOffset>
              <bitWidth>1</bitWidth>
            </field>
          </fields>
        </register>
        <register>
          <name>CR2</name>
          <addressOffset>0x4</addressOffset>
          <size>0x20</size>
          <fields>
            <field>
              <name>CCPC</name>
              <bitOffset>0</bitOffset>
              <bitWidth>1</bitWidth>
            </field>
            <field>
              <name>CCUS</name>
              <bitOffset>2</bitOffset>
              <bitWidth>1</bitWidth>
            </field>
            <field>
              <name>CCDS</name>
              <bitOffset>3</bitOffset>
              <bitWidth>1</bitWidth>
            </field>
            <field>
              <name>MMS</name>
              <bitOffset>4</bitOffset>
              <bitWidth>3</bitWidth>
            </field>
            <field>
              <name>TI1S</name>
              <bitOffset>7</bitOffset>
              <bitWidth>1</bitWidth>
            </field>
            <field>
              <name>OIS1</name>
              <bitOffset>8</bitOffset>
              <bitWidth>1</bitWidth>
            </field>
            <field>
              <name>OIS1N</name>
              <bitOffset>9</bitOffset>
              <bitWidth>1</bitWidth>
            </field>
            <field>
              <name>OIS2</name>
              <bitOffset>10</bitOffset>
              <bitWidth>1</bitWidth>
            </field>
            <field>
              <name>OIS2N</name>
              <bitOffset>11</bitOffset>
              <bitWidth>1</bitWidth>
            </field>
            <field>
              <name>OIS3</name>
              <bitOffset>12</bitOffset>
              <bitWidth>1</bitWidth>
            </field>
            <field>
              <name>OIS3N</name>
              <bitOffset>13</bitOffset>
              <bitWidth>1</bitWidth>
            </field>
            <field>
              <name>OIS4</name>
              <bitOffset>14</bitOffset>
              <bitWidth>1</bitWidth>
            </field>
            <field>
              <name>OIS5</name>
              <bitOffset>16</bitOffset>
              <bitWidth>1</bitWidth>
            </field>
            <field>
              <name>OIS6</name>
              <bitOffset>18</bitOffset>
              <bitWidth>1</bitWidth>
            </field>
            <field>
              <name>MMS2</name>
              <bitOffset>20</bitOffset>
              <bitWidth>4</bitWidth>
            </field>
          </fields>
        </register>
        <register>
          <name>SMCR</name>
          <addressOffset>0x8</addressOffset>
          <size>0x20</size>
          <fields>
            <field>
              <name>SMS</name>
              <bitOffset>0</bitOffset>
              <bitWidth>17</bitWidth>
            </field>
            <field>
              <name>TS</name>
              <bitOffset>4</bitOffset>
              <bitWidth>3</bitWidth>
            </field>
            <field>
              <name>MSM</name>
              <bitOffset>7</bitOffset>
              <bitWidth>1</bitWidth>
            </field>
            <field>
              <name>ETF</name>
              <bitOffset>8</bitOffset>
              <bitWidth>4</bitWidth>
            </field>
            <field>
              <name>ETPS</name>
              <bitOffset>12</bitOffset>
              <bitWidth>2</bitWidth>
            </field>
            <field>
              <name>ECE</name>
              <bitOffset>14</bitOffset>
              <bitWidth>1</bitWidth>
            </field>
            <field>
              <name>ETP</name>
              <bitOffset>15</bitOffset>
              <bitWidth>1</bitWidth>
            </field>
          </fields>
        </register>
        <register>
          <name>DIER</name>
          <addressOffset>0xc</addressOffset>
          <size>0x20</size>
          <fields>
            <field>
              <name>UIE</name>
              <bitOffset>0</bitOffset>
              <bitWidth>1</bitWidth>
            </field>
            <field>
              <name>CC1IE</name>
              <bitOffset>1</bitOffset>
              <bitWidth>1</bitWidth>
            </field>
            <field>
              <name>CC2IE</name>
              <bitOffset>2</bitOffset>
              <bitWidth>1</bitWidth>
            </field>
            <field>
              <name>CC3IE</name>
              <bitOffset>3</bitOffset>
              <bitWidth>1</bitWidth>
            </field>
            <field>
              <name>CC4IE</name>
              <bitOffset>4</bitOffset>
              <bitWidth>1</bitWidth>
            </field>
            <field>
              <name>COMIE</name>
              <bitOffset>5</bitOffset>
              <bitWidth>1</bitWidth>
            </field>
            <field>
              <name>TIE</name>
              <bitOffset>6</bitOffset>
              <bitWidth>1</bitWidth>
            </field>
            <field>
              <name>BIE</name>
              <bitOffset>7</bitOffset>
              <bitWidth>1</bitWidth>
            </field>
            <field>
              <name>UDE</name>
              <bitOffset>8</bitOffset>
              <bitWidth>1</bitWidth>
            </field>
            <field>
              <name>CC1DE</name>
              <bitOffset>9</bitOffset>
              <bitWidth>1</bitWidth>
            </field>
            <field>
              <name>CC2DE</name>
              <bitOffset>10</bitOffset>
              <bitWidth>1</bitWidth>
            </field>
            <field>
              <name>CC3DE</name>
              <bitOffset>11</bitOffset>
              <bitWidth>1</bitWidth>
            </field>
            <field>
              <name>CC4DE</name>
              <bitOffset>12</bitOffset>
              <bitWidth>1</bitWidth>
            </field>
            <field>
              <name>COMDE</name>
              <bitOffset>13</bitOffset>
              <bitWidth>1</bitWidth>
            </field>
            <field>
              <name>TDE</name>
              <bitOffset>14</bitOffset>
              <bitWidth>1</bitWidth>
            </field>
          </fields>
        </register>
        <register>
          <name>SR</name>
          <addressOffset>0x10</addressOffset>
          <size>0x20</size>
          <fields>
            <field>
              <name>UIF</name>
              <bitOffset>0</bitOffset>
              <bitWidth>1</bitWidth>
            </field>
            <field>
              <name>CC1IF</name>
              <bitOffset>1</bitOffset>
              <bitWidth>1</bitWidth>
            </field>
            <field>
              <name>CC2IF</name>
              <bitOffset>2</bitOffset>
              <bitWidth>1</bitWidth>
            </field>
            <field>
              <name>CC3IF</name>
              <bitOffset>3</bitOffset>
              <bitWidth>1</bitWidth>
            </field>
            <field>
              <name>CC4IF</name>
              <bitOffset>4</bitOffset>
              <bitWidth>1</bitWidth>
            </field>
            <field>
              <name>COMIF</name>
              <bitOffset>5</bitOffset>
              <bitWidth>1</bitWidth>
            </field>
            <field>
              <name>TIF</name>
              <bitOffset>6</bitOffset>
              <bitWidth>1</bitWidth>
            </field>
            <field>
              <name>BIF</name>
              <bitOffset>7</bitOffset>
              <bitWidth>1</bitWidth>
            </field>
            <field>
              <name>B2IF</name>
              <bitOffset>8</bitOffset>
              <bitWidth>1</bitWidth>
            </field>
            <field>
              <name>CC1OF</name>
              <bitOffset>9</bitOffset>
              <bitWidth>1</bitWidth>
            </field>
            <field>
              <name>CC2OF</name>
              <bitOffset>10</bitOffset>
              <bitWidth>1</bitWidth>
            </field>
            <field>
              <name>CC3OF</name>
              <bitOffset>11</bitOffset>
              <bitWidth>1</bitWidth>
            </field>
            <field>
              <name>CC4OF</name>
              <bitOffset>12</bitOffset>
              <bitWidth>1</bitWidth>
            </field>
            <field>
              <name>SBIF</name>
              <bitOffset>13</bitOffset>
              <bitWidth>1</bitWidth>
            </field>
            <field>
              <name>CC5IF</name>
              <bitOffset>16</bitOffset>
              <bitWidth>1</bitWidth>
            </field>
            <field>
              <name>CC6IF</name>
              <bitOffset>17</bitOffset>
              <bitWidth>1</bitWidth>
            </field>
          </fields>
        </register>
        <register>
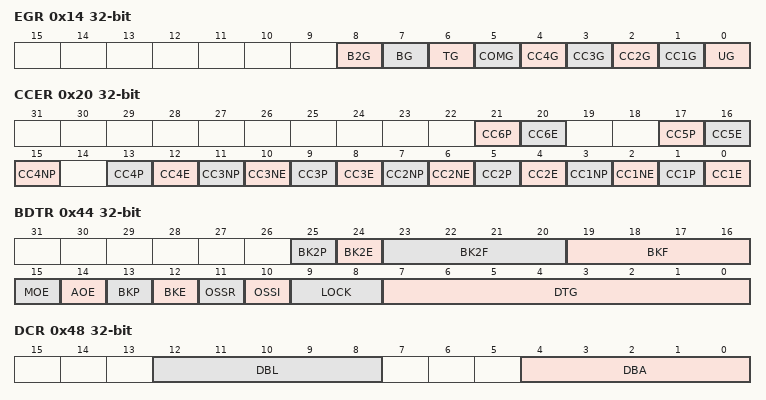
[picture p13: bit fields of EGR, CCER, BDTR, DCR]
          <name>EGR</name>
          <addressOffset>0x14</addressOffset>
          <size>0x20</size>
          <fields>
            <field>
              <name>UG</name>
              <bitOffset>0</bitOffset>
              <bitWidth>1</bitWidth>
            </field>
            <field>
              <name>CC1G</name>
              <bitOffset>1</bitOffset>
              <bitWidth>1</bitWidth>
            </field>
            <field>
              <name>CC2G</name>
              <bitOffset>2</bitOffset>
              <bitWidth>1</bitWidth>
            </field>
            <field>
              <name>CC3G</name>
              <bitOffset>3</bitOffset>
              <bitWidth>1</bitWidth>
            </field>
            <field>
              <name>CC4G</name>
              <bitOffset>4</bitOffset>
              <bitWidth>1</bitWidth>
            </field>
            <field>
              <name>COMG</name>
              <bitOffset>5</bitOffset>
              <bitWidth>1</bitWidth>
            </field>
            <field>
              <name>TG</name>
              <bitOffset>6</bitOffset>
              <bitWidth>1</bitWidth>
            </field>
            <field>
              <name>BG</name>
              <bitOffset>7</bitOffset>
              <bitWidth>1</bitWidth>
            </field>
            <field>
              <name>B2G</name>
              <bitOffset>8</bitOffset>
              <bitWidth>1</bitWidth>
            </field>
          </fields>
        </register>
        <register>
          <name>CCMR1</name>
          <addressOffset>0x18</addressOffset>
          <size>0x20</size>
          <fields>
            <field>
              <name>CC1S</name>
              <bitOffset>0</bitOffset>
              <bitWidth>2</bitWidth>
            </field>
            <field>
              <name>OC1FE</name>
              <bitOffset>2</bitOffset>
              <bitWidth>1</bitWidth>
            </field>
            <field>
              <name>OC1PE</name>
              <bitOffset>3</bitOffset>
              <bitWidth>1</bitWidth>
            </field>
            <field>
              <name>OC1M</name>
              <bitOffset>4</bitOffset>
              <bitWidth>13</bitWidth>
            </field>
            <field>
              <name>OC1CE</name>
              <bitOffset>7</bitOffset>
              <bitWidth>1</bitWidth>
            </field>
            <field>
              <name>CC2S</name>
              <bitOffset>8</bitOffset>
              <bitWidth>2</bitWidth>
            </field>
            <field>
              <name>OC2FE</name>
              <bitOffset>10</bitOffset>
              <bitWidth>1</bitWidth>
            </field>
            <field>
              <name>OC2PE</name>
              <bitOffset>11</bitOffset>
              <bitWidth>1</bitWidth>
            </field>
            <field>
              <name>OC2M</name>
              <bitOffset>12</bitOffset>
              <bitWidth>13</bitWidth>
            </field>
            <field>
              <name>OC2CE</name>
              <bitOffset>15</bitOffset>
              <bitWidth>1</bitWidth>
            </field>
          </fields>
        </register>
        <register>
          <name>CCMR2</name>
          <addressOffset>0x1c</addressOffset>
          <size>0x20</size>
          <fields>
            <field>
              <name>CC3S</name>
              <bitOffset>0</bitOffset>
              <bitWidth>2</bitWidth>
            </field>
            <field>
              <name>OC3FE</name>
              <bitOffset>2</bitOffset>
              <bitWidth>1</bitWidth>
            </field>
            <field>
              <name>OC3PE</name>
              <bitOffset>3</bitOffset>
              <bitWidth>1</bitWidth>
            </field>
            <field>
              <name>OC3M</name>
              <bitOffset>4</bitOffset>
              <bitWidth>13</bitWidth>
            </field>
            <field>
              <name>OC3CE</name>
              <bitOffset>7</bitOffset>
              <bitWidth>1</bitWidth>
            </field>
            <field>
              <name>CC4S</name>
              <bitOffset>8</bitOffset>
              <bitWidth>2</bitWidth>
            </field>
            <field>
              <name>OC4FE</name>
              <bitOffset>10</bitOffset>
              <bitWidth>1</bitWidth>
            </field>
            <field>
              <name>OC4PE</name>
              <bitOffset>11</bitOffset>
              <bitWidth>1</bitWidth>
            </field>
            <field>
              <name>OC4M</name>
              <bitOffset>12</bitOffset>
              <bitWidth>13</bitWidth>
            </field>
            <field>
              <name>OC4CE</name>
              <bitOffset>15</bitOffset>
              <bitWidth>1</bitWidth>
            </field>
          </fields>
        </register>
        <register>
          <name>CCER</name>
          <addressOffset>0x20</addressOffset>
          <size>0x20</size>
          <fields>
            <field>
              <name>CC1E</name>
              <bitOffset>0</bitOffset>
              <bitWidth>1</bitWidth>
            </field>
            <field>
              <name>CC1P</name>
              <bitOffset>1</bitOffset>
              <bitWidth>1</bitWidth>
            </field>
            <field>
              <name>CC1NE</name>
              <bitOffset>2</bitOffset>
              <bitWidth>1</bitWidth>
            </field>
            <field>
              <name>CC1NP</name>
              <bitOffset>3</bitOffset>
              <bitWidth>1</bitWidth>
            </field>
            <field>
              <name>CC2E</name>
              <bitOffset>4</bitOffset>
              <bitWidth>1</bitWidth>
            </field>
            <field>
              <name>CC2P</name>
              <bitOffset>5</bitOffset>
              <bitWidth>1</bitWidth>
            </field>
            <field>
              <name>CC2NE</name>
              <bitOffset>6</bitOffset>
              <bitWidth>1</bitWidth>
            </field>
            <field>
              <name>CC2NP</name>
              <bitOffset>7</bitOffset>
              <bitWidth>1</bitWidth>
            </field>
            <field>
              <name>CC3E</name>
              <bitOffset>8</bitOffset>
              <bitWidth>1</bitWidth>
            </field>
            <field>
              <name>CC3P</name>
              <bitOffset>9</bitOffset>
              <bitWidth>1</bitWidth>
            </field>
            <field>
              <name>CC3NE</name>
              <bitOffset>10</bitOffset>
              <bitWidth>1</bitWidth>
            </field>
            <field>
              <name>CC3NP</name>
              <bitOffset>11</bitOffset>
              <bitWidth>1</bitWidth>
            </field>
            <field>
              <name>CC4E</name>
              <bitOffset>12</bitOffset>
              <bitWidth>1</bitWidth>
            </field>
            <field>
              <name>CC4P</name>
              <bitOffset>13</bitOffset>
              <bitWidth>1</bitWidth>
            </field>
            <field>
              <name>CC4NP</name>
              <bitOffset>15</bitOffset>
              <bitWidth>1</bitWidth>
            </field>
            <field>
              <name>CC5E</name>
              <bitOffset>16</bitOffset>
              <bitWidth>1</bitWidth>
            </field>
            <field>
              <name>CC5P</name>
              <bitOffset>17</bitOffset>
              <bitWidth>1</bitWidth>
            </field>
            <field>
              <name>CC6E</name>
              <bitOffset>20</bitOffset>
              <bitWidth>1</bitWidth>
            </field>
            <field>
              <name>CC6P</name>
              <bitOffset>21</bitOffset>
              <bitWidth>1</bitWidth>
            </field>
          </fields>
        </register>
        <register>
          <name>CNT</name>
          <addressOffset>0x24</addressOffset>
          <size>0x20</size>
          <fields>
            <field>
              <name>CNT</name>
              <bitOffset>0</bitOffset>
              <bitWidth>32</bitWidth>
            </field>
            <field>
              <name>UIFCPY</name>
              <bitOffset>31</bitOffset>
              <bitWidth>1</bitWidth>
            </field>
          </fields>
        </register>
        <register>
          <name>PSC</name>
          <addressOffset>0x28</addressOffset>
          <size>0x20</size>
          <fields>
            <field>
              <name>PSC</name>
              <bitOffset>0</bitOffset>
              <bitWidth>16</bitWidth>
            </field>
          </fields>
        </register>
        <register>
          <name>ARR</name>
          <addressOffset>0x2c</addressOffset>
          <size>0x20</size>
          <fields>
            <field>
              <name>ARR</name>
              <bitOffset>0</bitOffset>
              <bitWidth>32</bitWidth>
            </field>
          </fields>
        </register>
        <register>
          <name>RCR</name>
          <addressOffset>0x30</addressOffset>
          <size>0x20</size>
          <fields>
            <field>
              <name>REP</name>
              <bitOffset>0</bitOffset>
              <bitWidth>16</bitWidth>
            </field>
          </fields>
        </register>
        <register>
          <name>CCR1</name>
          <addressOffset>0x34</addressOffset>
          <size>0x20</size>
          <fields>
            <field>
              <name>CCR1</name>
              <bitOffset>0</bitOffset>
              <bitWidth>16</bitWidth>
            </field>
          </fields>
        </register>
        <register>
          <name>CCR2</name>
          <addressOffset>0x38</addressOffset>
          <size>0x20</size>
          <fields>
            <field>
              <name>CCR2</name>
              <bitOffset>0</bitOffset>
              <bitWidth>16</bitWidth>
            </field>
          </fields>
        </register>
        <register>
          <name>CCR3</name>
          <addressOffset>0x3c</addressOffset>
          <size>0x20</size>
          <fields>
            <field>
              <name>CCR3</name>
              <bitOffset>0</bitOffset>
              <bitWidth>16</bitWidth>
            </field>
          </fields>
        </register>
        <register>
          <name>CCR4</name>
          <addressOffset>0x40</addressOffset>
          <size>0x20</size>
          <fields>
            <field>
              <name>CCR4</name>
              <bitOffset>0</bitOffset>
              <bitWidth>16</bitWidth>
            </field>
          </fields>
        </register>
        <register>
          <name>BDTR</name>
          <addressOffset>0x44</addressOffset>
          <size>0x20</size>
          <fields>
            <field>
              <name>DTG</name>
              <bitOffset>0</bitOffset>
              <bitWidth>8</bitWidth>
            </field>
            <field>
              <name>LOCK</name>
              <bitOffset>8</bitOffset>
              <bitWidth>2</bitWidth>
            </field>
            <field>
              <name>OSSI</name>
              <bitOffset>10</bitOffset>
              <bitWidth>1</bitWidth>
            </field>
            <field>
              <name>OSSR</name>
              <bitOffset>11</bitOffset>
              <bitWidth>1</bitWidth>
            </field>
            <field>
              <name>BKE</name>
              <bitOffset>12</bitOffset>
              <bitWidth>1</bitWidth>
            </field>
            <field>
              <name>BKP</name>
              <bitOffset>13</bitOffset>
              <bitWidth>1</bitWidth>
            </field>
            <field>
              <name>AOE</name>
              <bitOffset>14</bitOffset>
              <bitWidth>1</bitWidth>
            </field>
            <field>
              <name>MOE</name>
              <bitOffset>15</bitOffset>
              <bitWidth>1</bitWidth>
            </field>
            <field>
              <name>BKF</name>
              <bitOffset>16</bitOffset>
              <bitWidth>4</bitWidth>
            </field>
            <field>
              <name>BK2F</name>
              <bitOffset>20</bitOffset>
              <bitWidth>4</bitWidth>
            </field>
            <field>
              <name>BK2E</name>
              <bitOffset>24</bitOffset>
              <bitWidth>1</bitWidth>
            </field>
            <field>
              <name>BK2P</name>
              <bitOffset>25</bitOffset>
              <bitWidth>1</bitWidth>
            </field>
          </fields>
        </register>
        <register>
          <name>DCR</name>
          <addressOffset>0x48</addressOffset>
          <size>0x20</size>
          <fields>
            <field>
              <name>DBA</name>
              <bitOffset>0</bitOffset>
              <bitWidth>5</bitWidth>
            </field>
            <field>
              <name>DBL</name>
              <bitOffset>8</bitOffset>
              <bitWidth>5</bitWidth>
            </field>
          </fields>
        </register>
        <register>
          <name>DMAR</name>
          <addressOffset>0x4c</addressOffset>
          <size>0x20</size>
          <fields>
            <field>
              <name>DMAB</name>
              <bitOffset>0</bitOffset>
              <bitWidth>16</bitWidth>
            </field>
          </fields>
        </register>
        <register>
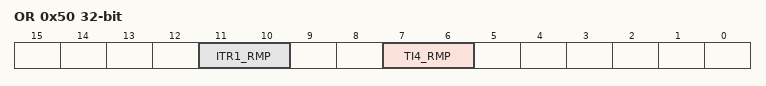
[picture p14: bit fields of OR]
          <name>OR</name>
          <addressOffset>0x50</addressOffset>
          <size>0x20</size>
          <fields>
            <field>
              <name>TI4_RMP</name>
              <bitOffset>6</bitOffset>
              <bitWidth>2</bitWidth>
            </field>
            <field>
              <name>ITR1_RMP</name>
              <bitOffset>10</bitOffset>
              <bitWidth>2</bitWidth>
            </field>
          </fields>
        </register>
        <register>
          <name>CCMR3</name>
          <addressOffset>0x54</addressOffset>
          <size>0x20</size>
          <fields>
            <field>
              <name>OC5FE</name>
              <bitOffset>2</bitOffset>
              <bitWidth>1</bitWidth>
            </field>
            <field>
              <name>OC5PE</name>
              <bitOffset>3</bitOffset>
              <bitWidth>1</bitWidth>
            </field>
            <field>
              <name>OC5M</name>
              <bitOffset>4</bitOffset>
              <bitWidth>13</bitWidth>
            </field>
            <field>
              <name>OC5CE</name>
              <bitOffset>7</bitOffset>
              <bitWidth>1</bitWidth>
            </field>
            <field>
              <name>OC6FE</name>
              <bitOffset>10</bitOffset>
              <bitWidth>1</bitWidth>
            </field>
            <field>
              <name>OC6PE</name>
              <bitOffset>11</bitOffset>
              <bitWidth>1</bitWidth>
            </field>
            <field>
              <name>OC6M</name>
              <bitOffset>12</bitOffset>
              <bitWidth>13</bitWidth>
            </field>
            <field>
              <name>OC6CE</name>
              <bitOffset>15</bitOffset>
              <bitWidth>1</bitWidth>
            </field>
          </fields>
        </register>
        <register>
          <name>CCR5</name>
          <addressOffset>0x58</addressOffset>
          <size>0x20</size>
          <fields>
            <field>
              <name>CCR5</name>
              <bitOffset>0</bitOffset>
              <bitWidth>32</bitWidth>
            </field>
            <field>
              <name>GC5C1</name>
              <bitOffset>29</bitOffset>
              <bitWidth>1</bitWidth>
            </field>
            <field>
              <name>GC5C2</name>
              <bitOffset>30</bitOffset>
              <bitWidth>1</bitWidth>
            </field>
            <field>
              <name>GC5C3</name>
              <bitOffset>31</bitOffset>
              <bitWidth>1</bitWidth>
            </field>
          </fields>
        </register>
        <register>
          <name>CCR6</name>
          <addressOffset>0x5c</addressOffset>
          <size>0x20</size>
        </register>
        <register>
          <name>AF1</name>
          <addressOffset>0x60</addressOffset>
          <size>0x20</size>
        </register>
        <register>
          <name>AF2</name>
          <addressOffset>0x64</addressOffset>
          <size>0x20</size>
        </register>
      </registers>
    </peripheral>
    <peripheral>
      <name>TIM7</name>
      <baseAddress>0x40001400</baseAddress>
      <registers>
        <register>
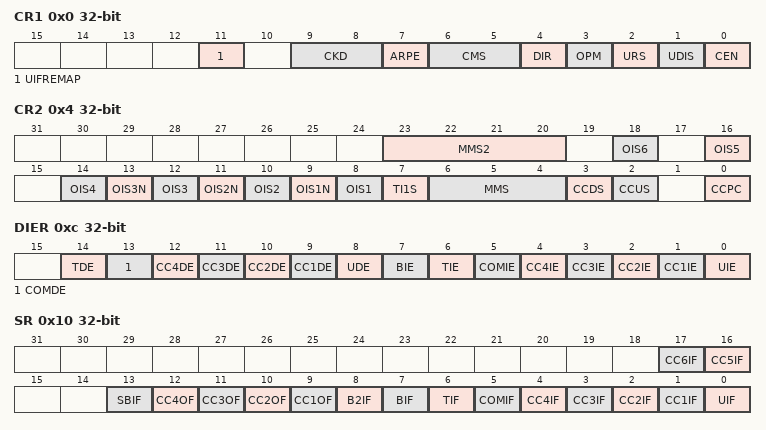
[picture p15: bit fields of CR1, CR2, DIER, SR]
          <name>CR1</name>
          <addressOffset>0x0</addressOffset>
          <size>0x20</size>
          <fields>
            <field>
              <name>CEN</name>
              <bitOffset>0</bitOffset>
              <bitWidth>1</bitWidth>
            </field>
            <field>
              <name>UDIS</name>
              <bitOffset>1</bitOffset>
              <bitWidth>1</bitWidth>
            </field>
            <field>
              <name>URS</name>
              <bitOffset>2</bitOffset>
              <bitWidth>1</bitWidth>
            </field>
            <field>
              <name>OPM</name>
              <bitOffset>3</bitOffset>
              <bitWidth>1</bitWidth>
            </field>
            <field>
              <name>DIR</name>
              <bitOffset>4</bitOffset>
              <bitWidth>1</bitWidth>
            </field>
            <field>
              <name>CMS</name>
              <bitOffset>5</bitOffset>
              <bitWidth>2</bitWidth>
            </field>
            <field>
              <name>ARPE</name>
              <bitOffset>7</bitOffset>
              <bitWidth>1</bitWidth>
            </field>
            <field>
              <name>CKD</name>
              <bitOffset>8</bitOffset>
              <bitWidth>2</bitWidth>
            </field>
            <field>
              <name>UIFREMAP</name>
              <bitOffset>11</bitOffset>
              <bitWidth>1</bitWidth>
            </field>
          </fields>
        </register>
        <register>
          <name>CR2</name>
          <addressOffset>0x4</addressOffset>
          <size>0x20</size>
          <fields>
            <field>
              <name>CCPC</name>
              <bitOffset>0</bitOffset>
              <bitWidth>1</bitWidth>
            </field>
            <field>
              <name>CCUS</name>
              <bitOffset>2</bitOffset>
              <bitWidth>1</bitWidth>
            </field>
            <field>
              <name>CCDS</name>
              <bitOffset>3</bitOffset>
              <bitWidth>1</bitWidth>
            </field>
            <field>
              <name>MMS</name>
              <bitOffset>4</bitOffset>
              <bitWidth>3</bitWidth>
            </field>
            <field>
              <name>TI1S</name>
              <bitOffset>7</bitOffset>
              <bitWidth>1</bitWidth>
            </field>
            <field>
              <name>OIS1</name>
              <bitOffset>8</bitOffset>
              <bitWidth>1</bitWidth>
            </field>
            <field>
              <name>OIS1N</name>
              <bitOffset>9</bitOffset>
              <bitWidth>1</bitWidth>
            </field>
            <field>
              <name>OIS2</name>
              <bitOffset>10</bitOffset>
              <bitWidth>1</bitWidth>
            </field>
            <field>
              <name>OIS2N</name>
              <bitOffset>11</bitOffset>
              <bitWidth>1</bitWidth>
            </field>
            <field>
              <name>OIS3</name>
              <bitOffset>12</bitOffset>
              <bitWidth>1</bitWidth>
            </field>
            <field>
              <name>OIS3N</name>
              <bitOffset>13</bitOffset>
              <bitWidth>1</bitWidth>
            </field>
            <field>
              <name>OIS4</name>
              <bitOffset>14</bitOffset>
              <bitWidth>1</bitWidth>
            </field>
            <field>
              <name>OIS5</name>
              <bitOffset>16</bitOffset>
              <bitWidth>1</bitWidth>
            </field>
            <field>
              <name>OIS6</name>
              <bitOffset>18</bitOffset>
              <bitWidth>1</bitWidth>
            </field>
            <field>
              <name>MMS2</name>
              <bitOffset>20</bitOffset>
              <bitWidth>4</bitWidth>
            </field>
          </fields>
        </register>
        <register>
          <name>SMCR</name>
          <addressOffset>0x8</addressOffset>
          <size>0x20</size>
          <fields>
            <field>
              <name>SMS</name>
              <bitOffset>0</bitOffset>
              <bitWidth>17</bitWidth>
            </field>
            <field>
              <name>TS</name>
              <bitOffset>4</bitOffset>
              <bitWidth>3</bitWidth>
            </field>
            <field>
              <name>MSM</name>
              <bitOffset>7</bitOffset>
              <bitWidth>1</bitWidth>
            </field>
            <field>
              <name>ETF</name>
              <bitOffset>8</bitOffset>
              <bitWidth>4</bitWidth>
            </field>
            <field>
              <name>ETPS</name>
              <bitOffset>12</bitOffset>
              <bitWidth>2</bitWidth>
            </field>
            <field>
              <name>ECE</name>
              <bitOffset>14</bitOffset>
              <bitWidth>1</bitWidth>
            </field>
            <field>
              <name>ETP</name>
              <bitOffset>15</bitOffset>
              <bitWidth>1</bitWidth>
            </field>
          </fields>
        </register>
        <register>
          <name>DIER</name>
          <addressOffset>0xc</addressOffset>
          <size>0x20</size>
          <fields>
            <field>
              <name>UIE</name>
              <bitOffset>0</bitOffset>
              <bitWidth>1</bitWidth>
            </field>
            <field>
              <name>CC1IE</name>
              <bitOffset>1</bitOffset>
              <bitWidth>1</bitWidth>
            </field>
            <field>
              <name>CC2IE</name>
              <bitOffset>2</bitOffset>
              <bitWidth>1</bitWidth>
            </field>
            <field>
              <name>CC3IE</name>
              <bitOffset>3</bitOffset>
              <bitWidth>1</bitWidth>
            </field>
            <field>
              <name>CC4IE</name>
              <bitOffset>4</bitOffset>
              <bitWidth>1</bitWidth>
            </field>
            <field>
              <name>COMIE</name>
              <bitOffset>5</bitOffset>
              <bitWidth>1</bitWidth>
            </field>
            <field>
              <name>TIE</name>
              <bitOffset>6</bitOffset>
              <bitWidth>1</bitWidth>
            </field>
            <field>
              <name>BIE</name>
              <bitOffset>7</bitOffset>
              <bitWidth>1</bitWidth>
            </field>
            <field>
              <name>UDE</name>
              <bitOffset>8</bitOffset>
              <bitWidth>1</bitWidth>
            </field>
            <field>
              <name>CC1DE</name>
              <bitOffset>9</bitOffset>
              <bitWidth>1</bitWidth>
            </field>
            <field>
              <name>CC2DE</name>
              <bitOffset>10</bitOffset>
              <bitWidth>1</bitWidth>
            </field>
            <field>
              <name>CC3DE</name>
              <bitOffset>11</bitOffset>
              <bitWidth>1</bitWidth>
            </field>
            <field>
              <name>CC4DE</name>
              <bitOffset>12</bitOffset>
              <bitWidth>1</bitWidth>
            </field>
            <field>
              <name>COMDE</name>
              <bitOffset>13</bitOffset>
              <bitWidth>1</bitWidth>
            </field>
            <field>
              <name>TDE</name>
              <bitOffset>14</bitOffset>
              <bitWidth>1</bitWidth>
            </field>
          </fields>
        </register>
        <register>
          <name>SR</name>
          <addressOffset>0x10</addressOffset>
          <size>0x20</size>
          <fields>
            <field>
              <name>UIF</name>
              <bitOffset>0</bitOffset>
              <bitWidth>1</bitWidth>
            </field>
            <field>
              <name>CC1IF</name>
              <bitOffset>1</bitOffset>
              <bitWidth>1</bitWidth>
            </field>
            <field>
              <name>CC2IF</name>
              <bitOffset>2</bitOffset>
              <bitWidth>1</bitWidth>
            </field>
            <field>
              <name>CC3IF</name>
              <bitOffset>3</bitOffset>
              <bitWidth>1</bitWidth>
            </field>
            <field>
              <name>CC4IF</name>
              <bitOffset>4</bitOffset>
              <bitWidth>1</bitWidth>
            </field>
            <field>
              <name>COMIF</name>
              <bitOffset>5</bitOffset>
              <bitWidth>1</bitWidth>
            </field>
            <field>
              <name>TIF</name>
              <bitOffset>6</bitOffset>
              <bitWidth>1</bitWidth>
            </field>
            <field>
              <name>BIF</name>
              <bitOffset>7</bitOffset>
              <bitWidth>1</bitWidth>
            </field>
            <field>
              <name>B2IF</name>
              <bitOffset>8</bitOffset>
              <bitWidth>1</bitWidth>
            </field>
            <field>
              <name>CC1OF</name>
              <bitOffset>9</bitOffset>
              <bitWidth>1</bitWidth>
            </field>
            <field>
              <name>CC2OF</name>
              <bitOffset>10</bitOffset>
              <bitWidth>1</bitWidth>
            </field>
            <field>
              <name>CC3OF</name>
              <bitOffset>11</bitOffset>
              <bitWidth>1</bitWidth>
            </field>
            <field>
              <name>CC4OF</name>
              <bitOffset>12</bitOffset>
              <bitWidth>1</bitWidth>
            </field>
            <field>
              <name>SBIF</name>
              <bitOffset>13</bitOffset>
              <bitWidth>1</bitWidth>
            </field>
            <field>
              <name>CC5IF</name>
              <bitOffset>16</bitOffset>
              <bitWidth>1</bitWidth>
            </field>
            <field>
              <name>CC6IF</name>
              <bitOffset>17</bitOffset>
              <bitWidth>1</bitWidth>
            </field>
          </fields>
        </register>
        <register>
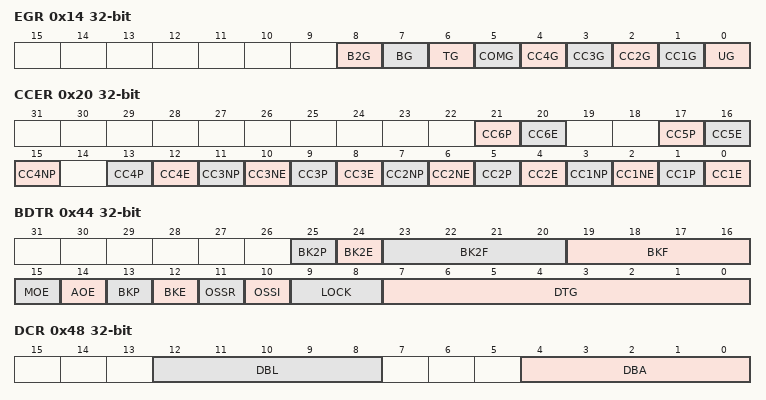
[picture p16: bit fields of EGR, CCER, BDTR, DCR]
          <name>EGR</name>
          <addressOffset>0x14</addressOffset>
          <size>0x20</size>
          <fields>
            <field>
              <name>UG</name>
              <bitOffset>0</bitOffset>
              <bitWidth>1</bitWidth>
            </field>
            <field>
              <name>CC1G</name>
              <bitOffset>1</bitOffset>
              <bitWidth>1</bitWidth>
            </field>
            <field>
              <name>CC2G</name>
              <bitOffset>2</bitOffset>
              <bitWidth>1</bitWidth>
            </field>
            <field>
              <name>CC3G</name>
              <bitOffset>3</bitOffset>
              <bitWidth>1</bitWidth>
            </field>
            <field>
              <name>CC4G</name>
              <bitOffset>4</bitOffset>
              <bitWidth>1</bitWidth>
            </field>
            <field>
              <name>COMG</name>
              <bitOffset>5</bitOffset>
              <bitWidth>1</bitWidth>
            </field>
            <field>
              <name>TG</name>
              <bitOffset>6</bitOffset>
              <bitWidth>1</bitWidth>
            </field>
            <field>
              <name>BG</name>
              <bitOffset>7</bitOffset>
              <bitWidth>1</bitWidth>
            </field>
            <field>
              <name>B2G</name>
              <bitOffset>8</bitOffset>
              <bitWidth>1</bitWidth>
            </field>
          </fields>
        </register>
        <register>
          <name>CCMR1</name>
          <addressOffset>0x18</addressOffset>
          <size>0x20</size>
          <fields>
            <field>
              <name>CC1S</name>
              <bitOffset>0</bitOffset>
              <bitWidth>2</bitWidth>
            </field>
            <field>
              <name>OC1FE</name>
              <bitOffset>2</bitOffset>
              <bitWidth>1</bitWidth>
            </field>
            <field>
              <name>OC1PE</name>
              <bitOffset>3</bitOffset>
              <bitWidth>1</bitWidth>
            </field>
            <field>
              <name>OC1M</name>
              <bitOffset>4</bitOffset>
              <bitWidth>13</bitWidth>
            </field>
            <field>
              <name>OC1CE</name>
              <bitOffset>7</bitOffset>
              <bitWidth>1</bitWidth>
            </field>
            <field>
              <name>CC2S</name>
              <bitOffset>8</bitOffset>
              <bitWidth>2</bitWidth>
            </field>
            <field>
              <name>OC2FE</name>
              <bitOffset>10</bitOffset>
              <bitWidth>1</bitWidth>
            </field>
            <field>
              <name>OC2PE</name>
              <bitOffset>11</bitOffset>
              <bitWidth>1</bitWidth>
            </field>
            <field>
              <name>OC2M</name>
              <bitOffset>12</bitOffset>
              <bitWidth>13</bitWidth>
            </field>
            <field>
              <name>OC2CE</name>
              <bitOffset>15</bitOffset>
              <bitWidth>1</bitWidth>
            </field>
          </fields>
        </register>
        <register>
          <name>CCMR2</name>
          <addressOffset>0x1c</addressOffset>
          <size>0x20</size>
          <fields>
            <field>
              <name>CC3S</name>
              <bitOffset>0</bitOffset>
              <bitWidth>2</bitWidth>
            </field>
            <field>
              <name>OC3FE</name>
              <bitOffset>2</bitOffset>
              <bitWidth>1</bitWidth>
            </field>
            <field>
              <name>OC3PE</name>
              <bitOffset>3</bitOffset>
              <bitWidth>1</bitWidth>
            </field>
            <field>
              <name>OC3M</name>
              <bitOffset>4</bitOffset>
              <bitWidth>13</bitWidth>
            </field>
            <field>
              <name>OC3CE</name>
              <bitOffset>7</bitOffset>
              <bitWidth>1</bitWidth>
            </field>
            <field>
              <name>CC4S</name>
              <bitOffset>8</bitOffset>
              <bitWidth>2</bitWidth>
            </field>
            <field>
              <name>OC4FE</name>
              <bitOffset>10</bitOffset>
              <bitWidth>1</bitWidth>
            </field>
            <field>
              <name>OC4PE</name>
              <bitOffset>11</bitOffset>
              <bitWidth>1</bitWidth>
            </field>
            <field>
              <name>OC4M</name>
              <bitOffset>12</bitOffset>
              <bitWidth>13</bitWidth>
            </field>
            <field>
              <name>OC4CE</name>
              <bitOffset>15</bitOffset>
              <bitWidth>1</bitWidth>
            </field>
          </fields>
        </register>
        <register>
          <name>CCER</name>
          <addressOffset>0x20</addressOffset>
          <size>0x20</size>
          <fields>
            <field>
              <name>CC1E</name>
              <bitOffset>0</bitOffset>
              <bitWidth>1</bitWidth>
            </field>
            <field>
              <name>CC1P</name>
              <bitOffset>1</bitOffset>
              <bitWidth>1</bitWidth>
            </field>
            <field>
              <name>CC1NE</name>
              <bitOffset>2</bitOffset>
              <bitWidth>1</bitWidth>
            </field>
            <field>
              <name>CC1NP</name>
              <bitOffset>3</bitOffset>
              <bitWidth>1</bitWidth>
            </field>
            <field>
              <name>CC2E</name>
              <bitOffset>4</bitOffset>
              <bitWidth>1</bitWidth>
            </field>
            <field>
              <name>CC2P</name>
              <bitOffset>5</bitOffset>
              <bitWidth>1</bitWidth>
            </field>
            <field>
              <name>CC2NE</name>
              <bitOffset>6</bitOffset>
              <bitWidth>1</bitWidth>
            </field>
            <field>
              <name>CC2NP</name>
              <bitOffset>7</bitOffset>
              <bitWidth>1</bitWidth>
            </field>
            <field>
              <name>CC3E</name>
              <bitOffset>8</bitOffset>
              <bitWidth>1</bitWidth>
            </field>
            <field>
              <name>CC3P</name>
              <bitOffset>9</bitOffset>
              <bitWidth>1</bitWidth>
            </field>
            <field>
              <name>CC3NE</name>
              <bitOffset>10</bitOffset>
              <bitWidth>1</bitWidth>
            </field>
            <field>
              <name>CC3NP</name>
              <bitOffset>11</bitOffset>
              <bitWidth>1</bitWidth>
            </field>
            <field>
              <name>CC4E</name>
              <bitOffset>12</bitOffset>
              <bitWidth>1</bitWidth>
            </field>
            <field>
              <name>CC4P</name>
              <bitOffset>13</bitOffset>
              <bitWidth>1</bitWidth>
            </field>
            <field>
              <name>CC4NP</name>
              <bitOffset>15</bitOffset>
              <bitWidth>1</bitWidth>
            </field>
            <field>
              <name>CC5E</name>
              <bitOffset>16</bitOffset>
              <bitWidth>1</bitWidth>
            </field>
            <field>
              <name>CC5P</name>
              <bitOffset>17</bitOffset>
              <bitWidth>1</bitWidth>
            </field>
            <field>
              <name>CC6E</name>
              <bitOffset>20</bitOffset>
              <bitWidth>1</bitWidth>
            </field>
            <field>
              <name>CC6P</name>
              <bitOffset>21</bitOffset>
              <bitWidth>1</bitWidth>
            </field>
          </fields>
        </register>
        <register>
          <name>CNT</name>
          <addressOffset>0x24</addressOffset>
          <size>0x20</size>
          <fields>
            <field>
              <name>CNT</name>
              <bitOffset>0</bitOffset>
              <bitWidth>32</bitWidth>
            </field>
            <field>
              <name>UIFCPY</name>
              <bitOffset>31</bitOffset>
              <bitWidth>1</bitWidth>
            </field>
          </fields>
        </register>
        <register>
          <name>PSC</name>
          <addressOffset>0x28</addressOffset>
          <size>0x20</size>
          <fields>
            <field>
              <name>PSC</name>
              <bitOffset>0</bitOffset>
              <bitWidth>16</bitWidth>
            </field>
          </fields>
        </register>
        <register>
          <name>ARR</name>
          <addressOffset>0x2c</addressOffset>
          <size>0x20</size>
          <fields>
            <field>
              <name>ARR</name>
              <bitOffset>0</bitOffset>
              <bitWidth>32</bitWidth>
            </field>
          </fields>
        </register>
        <register>
          <name>RCR</name>
          <addressOffset>0x30</addressOffset>
          <size>0x20</size>
          <fields>
            <field>
              <name>REP</name>
              <bitOffset>0</bitOffset>
              <bitWidth>16</bitWidth>
            </field>
          </fields>
        </register>
        <register>
          <name>CCR1</name>
          <addressOffset>0x34</addressOffset>
          <size>0x20</size>
          <fields>
            <field>
              <name>CCR1</name>
              <bitOffset>0</bitOffset>
              <bitWidth>16</bitWidth>
            </field>
          </fields>
        </register>
        <register>
          <name>CCR2</name>
          <addressOffset>0x38</addressOffset>
          <size>0x20</size>
          <fields>
            <field>
              <name>CCR2</name>
              <bitOffset>0</bitOffset>
              <bitWidth>16</bitWidth>
            </field>
          </fields>
        </register>
        <register>
          <name>CCR3</name>
          <addressOffset>0x3c</addressOffset>
          <size>0x20</size>
          <fields>
            <field>
              <name>CCR3</name>
              <bitOffset>0</bitOffset>
              <bitWidth>16</bitWidth>
            </field>
          </fields>
        </register>
        <register>
          <name>CCR4</name>
          <addressOffset>0x40</addressOffset>
          <size>0x20</size>
          <fields>
            <field>
              <name>CCR4</name>
              <bitOffset>0</bitOffset>
              <bitWidth>16</bitWidth>
            </field>
          </fields>
        </register>
        <register>
          <name>BDTR</name>
          <addressOffset>0x44</addressOffset>
          <size>0x20</size>
          <fields>
            <field>
              <name>DTG</name>
              <bitOffset>0</bitOffset>
              <bitWidth>8</bitWidth>
            </field>
            <field>
              <name>LOCK</name>
              <bitOffset>8</bitOffset>
              <bitWidth>2</bitWidth>
            </field>
            <field>
              <name>OSSI</name>
              <bitOffset>10</bitOffset>
              <bitWidth>1</bitWidth>
            </field>
            <field>
              <name>OSSR</name>
              <bitOffset>11</bitOffset>
              <bitWidth>1</bitWidth>
            </field>
            <field>
              <name>BKE</name>
              <bitOffset>12</bitOffset>
              <bitWidth>1</bitWidth>
            </field>
            <field>
              <name>BKP</name>
              <bitOffset>13</bitOffset>
              <bitWidth>1</bitWidth>
            </field>
            <field>
              <name>AOE</name>
              <bitOffset>14</bitOffset>
              <bitWidth>1</bitWidth>
            </field>
            <field>
              <name>MOE</name>
              <bitOffset>15</bitOffset>
              <bitWidth>1</bitWidth>
            </field>
            <field>
              <name>BKF</name>
              <bitOffset>16</bitOffset>
              <bitWidth>4</bitWidth>
            </field>
            <field>
              <name>BK2F</name>
              <bitOffset>20</bitOffset>
              <bitWidth>4</bitWidth>
            </field>
            <field>
              <name>BK2E</name>
              <bitOffset>24</bitOffset>
              <bitWidth>1</bitWidth>
            </field>
            <field>
              <name>BK2P</name>
              <bitOffset>25</bitOffset>
              <bitWidth>1</bitWidth>
            </field>
          </fields>
        </register>
        <register>
          <name>DCR</name>
          <addressOffset>0x48</addressOffset>
          <size>0x20</size>
          <fields>
            <field>
              <name>DBA</name>
              <bitOffset>0</bitOffset>
              <bitWidth>5</bitWidth>
            </field>
            <field>
              <name>DBL</name>
              <bitOffset>8</bitOffset>
              <bitWidth>5</bitWidth>
            </field>
          </fields>
        </register>
        <register>
          <name>DMAR</name>
          <addressOffset>0x4c</addressOffset>
          <size>0x20</size>
          <fields>
            <field>
              <name>DMAB</name>
              <bitOffset>0</bitOffset>
              <bitWidth>16</bitWidth>
            </field>
          </fields>
        </register>
        <register>
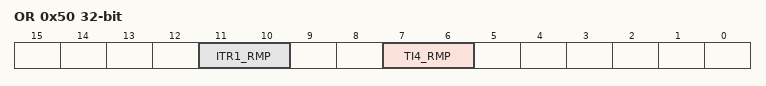
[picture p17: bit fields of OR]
          <name>OR</name>
          <addressOffset>0x50</addressOffset>
          <size>0x20</size>
          <fields>
            <field>
              <name>TI4_RMP</name>
              <bitOffset>6</bitOffset>
              <bitWidth>2</bitWidth>
            </field>
            <field>
              <name>ITR1_RMP</name>
              <bitOffset>10</bitOffset>
              <bitWidth>2</bitWidth>
            </field>
          </fields>
        </register>
        <register>
          <name>CCMR3</name>
          <addressOffset>0x54</addressOffset>
          <size>0x20</size>
          <fields>
            <field>
              <name>OC5FE</name>
              <bitOffset>2</bitOffset>
              <bitWidth>1</bitWidth>
            </field>
            <field>
              <name>OC5PE</name>
              <bitOffset>3</bitOffset>
              <bitWidth>1</bitWidth>
            </field>
            <field>
              <name>OC5M</name>
              <bitOffset>4</bitOffset>
              <bitWidth>13</bitWidth>
            </field>
            <field>
              <name>OC5CE</name>
              <bitOffset>7</bitOffset>
              <bitWidth>1</bitWidth>
            </field>
            <field>
              <name>OC6FE</name>
              <bitOffset>10</bitOffset>
              <bitWidth>1</bitWidth>
            </field>
            <field>
              <name>OC6PE</name>
              <bitOffset>11</bitOffset>
              <bitWidth>1</bitWidth>
            </field>
            <field>
              <name>OC6M</name>
              <bitOffset>12</bitOffset>
              <bitWidth>13</bitWidth>
            </field>
            <field>
              <name>OC6CE</name>
              <bitOffset>15</bitOffset>
              <bitWidth>1</bitWidth>
            </field>
          </fields>
        </register>
        <register>
          <name>CCR5</name>
          <addressOffset>0x58</addressOffset>
          <size>0x20</size>
          <fields>
            <field>
              <name>CCR5</name>
              <bitOffset>0</bitOffset>
              <bitWidth>32</bitWidth>
            </field>
            <field>
              <name>GC5C1</name>
              <bitOffset>29</bitOffset>
              <bitWidth>1</bitWidth>
            </field>
            <field>
              <name>GC5C2</name>
              <bitOffset>30</bitOffset>
              <bitWidth>1</bitWidth>
            </field>
            <field>
              <name>GC5C3</name>
              <bitOffset>31</bitOffset>
              <bitWidth>1</bitWidth>
            </field>
          </fields>
        </register>
        <register>
          <name>CCR6</name>
          <addressOffset>0x5c</addressOffset>
          <size>0x20</size>
        </register>
        <register>
          <name>AF1</name>
          <addressOffset>0x60</addressOffset>
          <size>0x20</size>
        </register>
        <register>
          <name>AF2</name>
          <addressOffset>0x64</addressOffset>
          <size>0x20</size>
        </register>
      </registers>
    </peripheral>
    <peripheral>
      <name>TIM12</name>
      <baseAddress>0x40001800</baseAddress>
      <registers>
        <register>
          <name>CR1</name>
          <addressOffset>0x0</addressOffset>
          <size>0x20</size>
          <fields>
            <field>
              <name>CEN</name>
              <bitOffset>0</bitOffset>
              <bitWidth>1</bitWidth>
            </field>
            <field>
              <name>UDIS</name>
              <bitOffset>1</bitOffset>
              <bitWidth>1</bitWidth>
            </field>
            <field>
              <name>URS</name>
              <bitOffset>2</bitOffset>
              <bitWidth>1</bitWidth>
            </field>
            <field>
              <name>OPM</name>
              <bitOffset>3</bitOffset>
              <bitWidth>1</bitWidth>
            </field>
            <field>
              <name>DIR</name>
              <bitOffset>4</bitOffset>
              <bitWidth>1</bitWidth>
            </field>
            <field>
              <name>CMS</name>
              <bitOffset>5</bitOffset>
              <bitWidth>2</bitWidth>
            </field>
            <field>
              <name>ARPE</name>
              <bitOffset>7</bitOffset>
              <bitWidth>1</bitWidth>
            </field>
            <field>
              <name>CKD</name>
              <bitOffset>8</bitOffset>
              <bitWidth>2</bitWidth>
            </field>
            <field>
              <name>UIFREMAP</name>
              <bitOffset>11</bitOffset>
              <bitWidth>1</bitWidth>
            </field>
          </fields>
        </register>
        <register>
          <name>CR2</name>
          <addressOffset>0x4</addressOffset>
          <size>0x20</size>
          <fields>
            <field>
              <name>CCPC</name>
              <bitOffset>0</bitOffset>
              <bitWidth>1</bitWidth>
            </field>
            <field>
              <name>CCUS</name>
              <bitOffset>2</bitOffset>
              <bitWidth>1</bitWidth>
            </field>
            <field>
              <name>CCDS</name>
              <bitOffset>3</bitOffset>
              <bitWidth>1</bitWidth>
            </field>
            <field>
              <name>MMS</name>
              <bitOffset>4</bitOffset>
              <bitWidth>3</bitWidth>
            </field>
            <field>
              <name>TI1S</name>
              <bitOffset>7</bitOffset>
              <bitWidth>1</bitWidth>
            </field>
            <field>
              <name>OIS1</name>
              <bitOffset>8</bitOffset>
              <bitWidth>1</bitWidth>
            </field>
            <field>
              <name>OIS1N</name>
              <bitOffset>9</bitOffset>
              <bitWidth>1</bitWidth>
            </field>
            <field>
              <name>OIS2</name>
              <bitOffset>10</bitOffset>
              <bitWidth>1</bitWidth>
            </field>
            <field>
              <name>OIS2N</name>
              <bitOffset>11</bitOffset>
              <bitWidth>1</bitWidth>
            </field>
            <field>
              <name>OIS3</name>
              <bitOffset>12</bitOffset>
              <bitWidth>1</bitWidth>
            </field>
            <field>
              <name>OIS3N</name>
              <bitOffset>13</bitOffset>
              <bitWidth>1</bitWidth>
            </field>
            <field>
              <name>OIS4</name>
              <bitOffset>14</bitOffset>
              <bitWidth>1</bitWidth>
            </field>
            <field>
              <name>OIS5</name>
              <bitOffset>16</bitOffset>
              <bitWidth>1</bitWidth>
            </field>
            <field>
              <name>OIS6</name>
              <bitOffset>18</bitOffset>
              <bitWidth>1</bitWidth>
            </field>
            <field>
              <name>MMS2</name>
              <bitOffset>20</bitOffset>
              <bitWidth>4</bitWidth>
            </field>
          </fields>
        </register>
        <register>
          <name>SMCR</name>
          <addressOffset>0x8</addressOffset>
          <size>0x20</size>
          <fields>
            <field>
              <name>SMS</name>
              <bitOffset>0</bitOffset>
              <bitWidth>17</bitWidth>
            </field>
            <field>
              <name>TS</name>
              <bitOffset>4</bitOffset>
              <bitWidth>3</bitWidth>
            </field>
            <field>
              <name>MSM</name>
              <bitOffset>7</bitOffset>
              <bitWidth>1</bitWidth>
            </field>
            <field>
              <name>ETF</name>
              <bitOffset>8</bitOffset>
              <bitWidth>4</bitWidth>
            </field>
            <field>
              <name>ETPS</name>
              <bitOffset>12</bitOffset>
              <bitWidth>2</bitWidth>
            </field>
            <field>
              <name>ECE</name>
              <bitOffset>14</bitOffset>
              <bitWidth>1</bitWidth>
            </field>
            <field>
              <name>ETP</name>
              <bitOffset>15</bitOffset>
              <bitWidth>1</bitWidth>
            </field>
          </fields>
        </register>
        <register>
          <name>DIER</name>
          <addressOffset>0xc</addressOffset>
          <size>0x20</size>
          <fields>
            <field>
              <name>UIE</name>
              <bitOffset>0</bitOffset>
              <bitWidth>1</bitWidth>
            </field>
            <field>
              <name>CC1IE</name>
              <bitOffset>1</bitOffset>
              <bitWidth>1</bitWidth>
            </field>
            <field>
              <name>CC2IE</name>
              <bitOffset>2</bitOffset>
              <bitWidth>1</bitWidth>
            </field>
            <field>
              <name>CC3IE</name>
              <bitOffset>3</bitOffset>
              <bitWidth>1</bitWidth>
            </field>
            <field>
              <name>CC4IE</name>
              <bitOffset>4</bitOffset>
              <bitWidth>1</bitWidth>
            </field>
            <field>
              <name>COMIE</name>
              <bitOffset>5</bitOffset>
              <bitWidth>1</bitWidth>
            </field>
            <field>
              <name>TIE</name>
              <bitOffset>6</bitOffset>
              <bitWidth>1</bitWidth>
            </field>
            <field>
              <name>BIE</name>
              <bitOffset>7</bitOffset>
              <bitWidth>1</bitWidth>
            </field>
            <field>
              <name>UDE</name>
              <bitOffset>8</bitOffset>
              <bitWidth>1</bitWidth>
            </field>
            <field>
              <name>CC1DE</name>
              <bitOffset>9</bitOffset>
              <bitWidth>1</bitWidth>
            </field>
            <field>
              <name>CC2DE</name>
              <bitOffset>10</bitOffset>
              <bitWidth>1</bitWidth>
            </field>
            <field>
              <name>CC3DE</name>
              <bitOffset>11</bitOffset>
              <bitWidth>1</bitWidth>
            </field>
            <field>
              <name>CC4DE</name>
              <bitOffset>12</bitOffset>
              <bitWidth>1</bitWidth>
            </field>
            <field>
              <name>COMDE</name>
              <bitOffset>13</bitOffset>
              <bitWidth>1</bitWidth>
            </field>
            <field>
              <name>TDE</name>
              <bitOffset>14</bitOffset>
              <bitWidth>1</bitWidth>
            </field>
          </fields>
        </register>
        <register>
          <name>SR</name>
          <addressOffset>0x10</addressOffset>
          <size>0x20</size>
          <fields>
            <field>
              <name>UIF</name>
              <bitOffset>0</bitOffset>
              <bitWidth>1</bitWidth>
            </field>
            <field>
              <name>CC1IF</name>
              <bitOffset>1</bitOffset>
              <bitWidth>1</bitWidth>
            </field>
            <field>
              <name>CC2IF</name>
              <bitOffset>2</bitOffset>
              <bitWidth>1</bitWidth>
            </field>
            <field>
              <name>CC3IF</name>
              <bitOffset>3</bitOffset>
              <bitWidth>1</bitWidth>
            </field>
            <field>
              <name>CC4IF</name>
              <bitOffset>4</bitOffset>
              <bitWidth>1</bitWidth>
            </field>
            <field>
              <name>COMIF</name>
              <bitOffset>5</bitOffset>
              <bitWidth>1</bitWidth>
            </field>
            <field>
              <name>TIF</name>
              <bitOffset>6</bitOffset>
              <bitWidth>1</bitWidth>
            </field>
            <field>
              <name>BIF</name>
              <bitOffset>7</bitOffset>
              <bitWidth>1</bitWidth>
            </field>
            <field>
              <name>B2IF</name>
              <bitOffset>8</bitOffset>
              <bitWidth>1</bitWidth>
            </field>
            <field>
              <name>CC1OF</name>
              <bitOffset>9</bitOffset>
              <bitWidth>1</bitWidth>
            </field>
            <field>
              <name>CC2OF</name>
              <bitOffset>10</bitOffset>
              <bitWidth>1</bitWidth>
            </field>
            <field>
              <name>CC3OF</name>
              <bitOffset>11</bitOffset>
              <bitWidth>1</bitWidth>
            </field>
            <field>
              <name>CC4OF</name>
              <bitOffset>12</bitOffset>
              <bitWidth>1</bitWidth>
            </field>
            <field>
              <name>SBIF</name>
              <bitOffset>13</bitOffset>
              <bitWidth>1</bitWidth>
            </field>
            <field>
              <name>CC5IF</name>
              <bitOffset>16</bitOffset>
              <bitWidth>1</bitWidth>
            </field>
            <field>
              <name>CC6IF</name>
              <bitOffset>17</bitOffset>
              <bitWidth>1</bitWidth>
            </field>
          </fields>
        </register>
        <register>
          <name>EGR</name>
          <addressOffset>0x14</addressOffset>
          <size>0x20</size>
          <fields>
            <field>
              <name>UG</name>
              <bitOffset>0</bitOffset>
              <bitWidth>1</bitWidth>
            </field>
            <field>
              <name>CC1G</name>
              <bitOffset>1</bitOffset>
              <bitWidth>1</bitWidth>
            </field>
            <field>
              <name>CC2G</name>
              <bitOffset>2</bitOffset>
              <bitWidth>1</bitWidth>
            </field>
            <field>
              <name>CC3G</name>
              <bitOffset>3</bitOffset>
              <bitWidth>1</bitWidth>
            </field>
            <field>
              <name>CC4G</name>
              <bitOffset>4</bitOffset>
              <bitWidth>1</bitWidth>
            </field>
            <field>
              <name>COMG</name>
              <bitOffset>5</bitOffset>
              <bitWidth>1</bitWidth>
            </field>
            <field>
              <name>TG</name>
              <bitOffset>6</bitOffset>
              <bitWidth>1</bitWidth>
            </field>
            <field>
              <name>BG</name>
              <bitOffset>7</bitOffset>
              <bitWidth>1</bitWidth>
            </field>
            <field>
              <name>B2G</name>
              <bitOffset>8</bitOffset>
              <bitWidth>1</bitWidth>
            </field>
          </fields>
        </register>
        <register>
          <name>CCMR1</name>
          <addressOffset>0x18</addressOffset>
          <size>0x20</size>
          <fields>
            <field>
              <name>CC1S</name>
              <bitOffset>0</bitOffset>
              <bitWidth>2</bitWidth>
            </field>
            <field>
              <name>OC1FE</name>
              <bitOffset>2</bitOffset>
              <bitWidth>1</bitWidth>
            </field>
            <field>
              <name>OC1PE</name>
              <bitOffset>3</bitOffset>
              <bitWidth>1</bitWidth>
            </field>
            <field>
              <name>OC1M</name>
              <bitOffset>4</bitOffset>
              <bitWidth>13</bitWidth>
            </field>
            <field>
              <name>OC1CE</name>
              <bitOffset>7</bitOffset>
              <bitWidth>1</bitWidth>
            </field>
            <field>
              <name>CC2S</name>
              <bitOffset>8</bitOffset>
              <bitWidth>2</bitWidth>
            </field>
            <field>
              <name>OC2FE</name>
              <bitOffset>10</bitOffset>
              <bitWidth>1</bitWidth>
            </field>
            <field>
              <name>OC2PE</name>
              <bitOffset>11</bitOffset>
              <bitWidth>1</bitWidth>
            </field>
            <field>
              <name>OC2M</name>
              <bitOffset>12</bitOffset>
              <bitWidth>13</bitWidth>
            </field>
            <field>
              <name>OC2CE</name>
              <bitOffset>15</bitOffset>
              <bitWidth>1</bitWidth>
            </field>
          </fields>
        </register>
        <register>
          <name>CCMR2</name>
          <addressOffset>0x1c</addressOffset>
          <size>0x20</size>
          <fields>
            <field>
              <name>CC3S</name>
              <bitOffset>0</bitOffset>
              <bitWidth>2</bitWidth>
            </field>
            <field>
              <name>OC3FE</name>
              <bitOffset>2</bitOffset>
              <bitWidth>1</bitWidth>
            </field>
            <field>
              <name>OC3PE</name>
              <bitOffset>3</bitOffset>
              <bitWidth>1</bitWidth>
            </field>
            <field>
              <name>OC3M</name>
              <bitOffset>4</bitOffset>
              <bitWidth>13</bitWidth>
            </field>
            <field>
              <name>OC3CE</name>
              <bitOffset>7</bitOffset>
              <bitWidth>1</bitWidth>
            </field>
            <field>
              <name>CC4S</name>
              <bitOffset>8</bitOffset>
              <bitWidth>2</bitWidth>
            </field>
            <field>
              <name>OC4FE</name>
              <bitOffset>10</bitOffset>
              <bitWidth>1</bitWidth>
            </field>
            <field>
              <name>OC4PE</name>
              <bitOffset>11</bitOffset>
              <bitWidth>1</bitWidth>
            </field>
            <field>
              <name>OC4M</name>
              <bitOffset>12</bitOffset>
              <bitWidth>13</bitWidth>
            </field>
            <field>
              <name>OC4CE</name>
              <bitOffset>15</bitOffset>
              <bitWidth>1</bitWidth>
            </field>
          </fields>
        </register>
        <register>
          <name>CCER</name>
          <addressOffset>0x20</addressOffset>
          <size>0x20</size>
          <fields>
            <field>
              <name>CC1E</name>
              <bitOffset>0</bitOffset>
              <bitWidth>1</bitWidth>
            </field>
            <field>
              <name>CC1P</name>
              <bitOffset>1</bitOffset>
              <bitWidth>1</bitWidth>
            </field>
            <field>
              <name>CC1NE</name>
              <bitOffset>2</bitOffset>
              <bitWidth>1</bitWidth>
            </field>
            <field>
              <name>CC1NP</name>
              <bitOffset>3</bitOffset>
              <bitWidth>1</bitWidth>
            </field>
            <field>
              <name>CC2E</name>
              <bitOffset>4</bitOffset>
              <bitWidth>1</bitWidth>
            </field>
            <field>
              <name>CC2P</name>
              <bitOffset>5</bitOffset>
              <bitWidth>1</bitWidth>
            </field>
            <field>
              <name>CC2NE</name>
              <bitOffset>6</bitOffset>
              <bitWidth>1</bitWidth>
            </field>
            <field>
              <name>CC2NP</name>
              <bitOffset>7</bitOffset>
              <bitWidth>1</bitWidth>
            </field>
            <field>
              <name>CC3E</name>
              <bitOffset>8</bitOffset>
              <bitWidth>1</bitWidth>
            </field>
            <field>
              <name>CC3P</name>
              <bitOffset>9</bitOffset>
              <bitWidth>1</bitWidth>
            </field>
            <field>
              <name>CC3NE</name>
              <bitOffset>10</bitOffset>
              <bitWidth>1</bitWidth>
            </field>
            <field>
              <name>CC3NP</name>
              <bitOffset>11</bitOffset>
              <bitWidth>1</bitWidth>
            </field>
            <field>
              <name>CC4E</name>
              <bitOffset>12</bitOffset>
              <bitWidth>1</bitWidth>
            </field>
            <field>
              <name>CC4P</name>
              <bitOffset>13</bitOffset>
              <bitWidth>1</bitWidth>
            </field>
            <field>
              <name>CC4NP</name>
              <bitOffset>15</bitOffset>
              <bitWidth>1</bitWidth>
            </field>
            <field>
              <name>CC5E</name>
              <bitOffset>16</bitOffset>
              <bitWidth>1</bitWidth>
            </field>
            <field>
              <name>CC5P</name>
              <bitOffset>17</bitOffset>
              <bitWidth>1</bitWidth>
            </field>
            <field>
              <name>CC6E</name>
              <bitOffset>20</bitOffset>
              <bitWidth>1</bitWidth>
            </field>
            <field>
              <name>CC6P</name>
              <bitOffset>21</bitOffset>
              <bitWidth>1</bitWidth>
            </field>
          </fields>
        </register>
        <register>
          <name>CNT</name>
          <addressOffset>0x24</addressOffset>
          <size>0x20</size>
          <fields>
            <field>
              <name>CNT</name>
              <bitOffset>0</bitOffset>
              <bitWidth>32</bitWidth>
            </field>
            <field>
              <name>UIFCPY</name>
              <bitOffset>31</bitOffset>
              <bitWidth>1</bitWidth>
            </field>
          </fields>
        </register>
        <register>
          <name>PSC</name>
          <addressOffset>0x28</addressOffset>
          <size>0x20</size>
          <fields>
            <field>
              <name>PSC</name>
              <bitOffset>0</bitOffset>
              <bitWidth>16</bitWidth>
            </field>
          </fields>
        </register>
        <register>
          <name>ARR</name>
          <addressOffset>0x2c</addressOffset>
          <size>0x20</size>
          <fields>
            <field>
              <name>ARR</name>
              <bitOffset>0</bitOffset>
              <bitWidth>32</bitWidth>
            </field>
          </fields>
        </register>
        <register>
          <name>RCR</name>
          <addressOffset>0x30</addressOffset>
          <size>0x20</size>
          <fields>
            <field>
              <name>REP</name>
              <bitOffset>0</bitOffset>
              <bitWidth>16</bitWidth>
            </field>
          </fields>
        </register>
        <register>
          <name>CCR1</name>
          <addressOffset>0x34</addressOffset>
          <size>0x20</size>
          <fields>
            <field>
              <name>CCR1</name>
              <bitOffset>0</bitOffset>
              <bitWidth>16</bitWidth>
            </field>
          </fields>
        </register>
        <register>
          <name>CCR2</name>
          <addressOffset>0x38</addressOffset>
          <size>0x20</size>
          <fields>
            <field>
              <name>CCR2</name>
              <bitOffset>0</bitOffset>
              <bitWidth>16</bitWidth>
            </field>
          </fields>
        </register>
        <register>
          <name>CCR3</name>
          <addressOffset>0x3c</addressOffset>
          <size>0x20</size>
          <fields>
            <field>
              <name>CCR3</name>
              <bitOffset>0</bitOffset>
              <bitWidth>16</bitWidth>
            </field>
          </fields>
        </register>
        <register>
          <name>CCR4</name>
          <addressOffset>0x40</addressOffset>
          <size>0x20</size>
          <fields>
            <field>
              <name>CCR4</name>
              <bitOffset>0</bitOffset>
              <bitWidth>16</bitWidth>
            </field>
          </fields>
        </register>
        <register>
          <name>BDTR</name>
          <addressOffset>0x44</addressOffset>
          <size>0x20</size>
          <fields>
            <field>
              <name>DTG</name>
              <bitOffset>0</bitOffset>
              <bitWidth>8</bitWidth>
            </field>
            <field>
              <name>LOCK</name>
              <bitOffset>8</bitOffset>
              <bitWidth>2</bitWidth>
            </field>
            <field>
              <name>OSSI</name>
              <bitOffset>10</bitOffset>
              <bitWidth>1</bitWidth>
            </field>
            <field>
              <name>OSSR</name>
              <bitOffset>11</bitOffset>
              <bitWidth>1</bitWidth>
            </field>
            <field>
              <name>BKE</name>
              <bitOffset>12</bitOffset>
              <bitWidth>1</bitWidth>
            </field>
            <field>
              <name>BKP</name>
              <bitOffset>13</bitOffset>
              <bitWidth>1</bitWidth>
            </field>
            <field>
              <name>AOE</name>
              <bitOffset>14</bitOffset>
              <bitWidth>1</bitWidth>
            </field>
            <field>
              <name>MOE</name>
              <bitOffset>15</bitOffset>
              <bitWidth>1</bitWidth>
            </field>
            <field>
              <name>BKF</name>
              <bitOffset>16</bitOffset>
              <bitWidth>4</bitWidth>
            </field>
            <field>
              <name>BK2F</name>
              <bitOffset>20</bitOffset>
              <bitWidth>4</bitWidth>
            </field>
            <field>
              <name>BK2E</name>
              <bitOffset>24</bitOffset>
              <bitWidth>1</bitWidth>
            </field>
            <field>
              <name>BK2P</name>
              <bitOffset>25</bitOffset>
              <bitWidth>1</bitWidth>
            </field>
          </fields>
        </register>
        <register>
          <name>DCR</name>
          <addressOffset>0x48</addressOffset>
          <size>0x20</size>
          <fields>
            <field>
              <name>DBA</name>
              <bitOffset>0</bitOffset>
              <bitWidth>5</bitWidth>
            </field>
            <field>
              <name>DBL</name>
              <bitOffset>8</bitOffset>
              <bitWidth>5</bitWidth>
            </field>
          </fields>
        </register>
        <register>
          <name>DMAR</name>
          <addressOffset>0x4c</addressOffset>
          <size>0x20</size>
          <fields>
            <field>
              <name>DMAB</name>
              <bitOffset>0</bitOffset>
              <bitWidth>16</bitWidth>
            </field>
          </fields>
        </register>
        <register>
          <name>OR</name>
          <addressOffset>0x50</addressOffset>
          <size>0x20</size>
          <fields>
            <field>
              <name>TI4_RMP</name>
              <bitOffset>6</bitOffset>
              <bitWidth>2</bitWidth>
            </field>
            <field>
              <name>ITR1_RMP</name>
              <bitOffset>10</bitOffset>
              <bitWidth>2</bitWidth>
            </field>
          </fields>
        </register>
        <register>
          <name>CCMR3</name>
          <addressOffset>0x54</addressOffset>
          <size>0x20</size>
          <fields>
            <field>
              <name>OC5FE</name>
              <bitOffset>2</bitOffset>
              <bitWidth>1</bitWidth>
            </field>
            <field>
              <name>OC5PE</name>
              <bitOffset>3</bitOffset>
              <bitWidth>1</bitWidth>
            </field>
            <field>
              <name>OC5M</name>
              <bitOffset>4</bitOffset>
              <bitWidth>13</bitWidth>
            </field>
            <field>
              <name>OC5CE</name>
              <bitOffset>7</bitOffset>
              <bitWidth>1</bitWidth>
            </field>
            <field>
              <name>OC6FE</name>
              <bitOffset>10</bitOffset>
              <bitWidth>1</bitWidth>
            </field>
            <field>
              <name>OC6PE</name>
              <bitOffset>11</bitOffset>
              <bitWidth>1</bitWidth>
            </field>
            <field>
              <name>OC6M</name>
              <bitOffset>12</bitOffset>
              <bitWidth>13</bitWidth>
            </field>
            <field>
              <name>OC6CE</name>
              <bitOffset>15</bitOffset>
              <bitWidth>1</bitWidth>
            </field>
          </fields>
        </register>
        <register>
          <name>CCR5</name>
          <addressOffset>0x58</addressOffset>
          <size>0x20</size>
          <fields>
            <field>
              <name>CCR5</name>
              <bitOffset>0</bitOffset>
              <bitWidth>32</bitWidth>
            </field>
            <field>
              <name>GC5C1</name>
              <bitOffset>29</bitOffset>
              <bitWidth>1</bitWidth>
            </field>
            <field>
              <name>GC5C2</name>
              <bitOffset>30</bitOffset>
              <bitWidth>1</bitWidth>
            </field>
            <field>
              <name>GC5C3</name>
              <bitOffset>31</bitOffset>
              <bitWidth>1</bitWidth>
            </field>
          </fields>
        </register>
        <register>
          <name>CCR6</name>
          <addressOffset>0x5c</addressOffset>
          <size>0x20</size>
        </register>
        <register>
          <name>AF1</name>
          <addressOffset>0x60</addressOffset>
          <size>0x20</size>
        </register>
        <register>
          <name>AF2</name>
          <addressOffset>0x64</addressOffset>
          <size>0x20</size>
        </register>
      </registers>
    </peripheral>
    <peripheral>
      <name>TIM13</name>
      <baseAddress>0x40001c00</baseAddress>
      <registers>
        <register>
          <name>CR1</name>
          <addressOffset>0x0</addressOffset>
          <size>0x20</size>
          <fields>
            <field>
              <name>CEN</name>
              <bitOffset>0</bitOffset>
              <bitWidth>1</bitWidth>
            </field>
            <field>
              <name>UDIS</name>
              <bitOffset>1</bitOffset>
              <bitWidth>1</bitWidth>
            </field>
            <field>
              <name>URS</name>
              <bitOffset>2</bitOffset>
              <bitWidth>1</bitWidth>
            </field>
            <field>
              <name>OPM</name>
              <bitOffset>3</bitOffset>
              <bitWidth>1</bitWidth>
            </field>
            <field>
              <name>DIR</name>
              <bitOffset>4</bitOffset>
              <bitWidth>1</bitWidth>
            </field>
            <field>
              <name>CMS</name>
              <bitOffset>5</bitOffset>
              <bitWidth>2</bitWidth>
            </field>
            <field>
              <name>ARPE</name>
              <bitOffset>7</bitOffset>
              <bitWidth>1</bitWidth>
            </field>
            <field>
              <name>CKD</name>
              <bitOffset>8</bitOffset>
              <bitWidth>2</bitWidth>
            </field>
            <field>
              <name>UIFREMAP</name>
              <bitOffset>11</bitOffset>
              <bitWidth>1</bitWidth>
            </field>
          </fields>
        </register>
        <register>
          <name>CR2</name>
          <addressOffset>0x4</addressOffset>
          <size>0x20</size>
          <fields>
            <field>
              <name>CCPC</name>
              <bitOffset>0</bitOffset>
              <bitWidth>1</bitWidth>
            </field>
            <field>
              <name>CCUS</name>
              <bitOffset>2</bitOffset>
              <bitWidth>1</bitWidth>
            </field>
            <field>
              <name>CCDS</name>
              <bitOffset>3</bitOffset>
              <bitWidth>1</bitWidth>
            </field>
            <field>
              <name>MMS</name>
              <bitOffset>4</bitOffset>
              <bitWidth>3</bitWidth>
            </field>
            <field>
              <name>TI1S</name>
              <bitOffset>7</bitOffset>
              <bitWidth>1</bitWidth>
            </field>
            <field>
              <name>OIS1</name>
              <bitOffset>8</bitOffset>
              <bitWidth>1</bitWidth>
            </field>
            <field>
              <name>OIS1N</name>
              <bitOffset>9</bitOffset>
              <bitWidth>1</bitWidth>
            </field>
            <field>
              <name>OIS2</name>
              <bitOffset>10</bitOffset>
              <bitWidth>1</bitWidth>
            </field>
            <field>
              <name>OIS2N</name>
              <bitOffset>11</bitOffset>
              <bitWidth>1</bitWidth>
            </field>
            <field>
              <name>OIS3</name>
              <bitOffset>12</bitOffset>
              <bitWidth>1</bitWidth>
            </field>
            <field>
              <name>OIS3N</name>
              <bitOffset>13</bitOffset>
              <bitWidth>1</bitWidth>
            </field>
            <field>
              <name>OIS4</name>
              <bitOffset>14</bitOffset>
              <bitWidth>1</bitWidth>
            </field>
            <field>
              <name>OIS5</name>
              <bitOffset>16</bitOffset>
              <bitWidth>1</bitWidth>
            </field>
            <field>
              <name>OIS6</name>
              <bitOffset>18</bitOffset>
              <bitWidth>1</bitWidth>
            </field>
            <field>
              <name>MMS2</name>
              <bitOffset>20</bitOffset>
              <bitWidth>4</bitWidth>
            </field>
          </fields>
        </register>
        <register>
          <name>SMCR</name>
          <addressOffset>0x8</addressOffset>
          <size>0x20</size>
          <fields>
            <field>
              <name>SMS</name>
              <bitOffset>0</bitOffset>
              <bitWidth>17</bitWidth>
            </field>
            <field>
              <name>TS</name>
              <bitOffset>4</bitOffset>
              <bitWidth>3</bitWidth>
            </field>
            <field>
              <name>MSM</name>
              <bitOffset>7</bitOffset>
              <bitWidth>1</bitWidth>
            </field>
            <field>
              <name>ETF</name>
              <bitOffset>8</bitOffset>
              <bitWidth>4</bitWidth>
            </field>
            <field>
              <name>ETPS</name>
              <bitOffset>12</bitOffset>
              <bitWidth>2</bitWidth>
            </field>
            <field>
              <name>ECE</name>
              <bitOffset>14</bitOffset>
              <bitWidth>1</bitWidth>
            </field>
            <field>
              <name>ETP</name>
              <bitOffset>15</bitOffset>
              <bitWidth>1</bitWidth>
            </field>
          </fields>
        </register>
        <register>
          <name>DIER</name>
          <addressOffset>0xc</addressOffset>
          <size>0x20</size>
          <fields>
            <field>
              <name>UIE</name>
              <bitOffset>0</bitOffset>
              <bitWidth>1</bitWidth>
            </field>
            <field>
              <name>CC1IE</name>
              <bitOffset>1</bitOffset>
              <bitWidth>1</bitWidth>
            </field>
            <field>
              <name>CC2IE</name>
              <bitOffset>2</bitOffset>
              <bitWidth>1</bitWidth>
            </field>
            <field>
              <name>CC3IE</name>
              <bitOffset>3</bitOffset>
              <bitWidth>1</bitWidth>
            </field>
            <field>
              <name>CC4IE</name>
              <bitOffset>4</bitOffset>
              <bitWidth>1</bitWidth>
            </field>
            <field>
              <name>COMIE</name>
              <bitOffset>5</bitOffset>
              <bitWidth>1</bitWidth>
            </field>
            <field>
              <name>TIE</name>
              <bitOffset>6</bitOffset>
              <bitWidth>1</bitWidth>
            </field>
            <field>
              <name>BIE</name>
              <bitOffset>7</bitOffset>
              <bitWidth>1</bitWidth>
            </field>
            <field>
              <name>UDE</name>
              <bitOffset>8</bitOffset>
              <bitWidth>1</bitWidth>
            </field>
            <field>
              <name>CC1DE</name>
              <bitOffset>9</bitOffset>
              <bitWidth>1</bitWidth>
            </field>
            <field>
              <name>CC2DE</name>
              <bitOffset>10</bitOffset>
              <bitWidth>1</bitWidth>
            </field>
            <field>
              <name>CC3DE</name>
              <bitOffset>11</bitOffset>
              <bitWidth>1</bitWidth>
            </field>
            <field>
              <name>CC4DE</name>
              <bitOffset>12</bitOffset>
              <bitWidth>1</bitWidth>
            </field>
            <field>
              <name>COMDE</name>
              <bitOffset>13</bitOffset>
              <bitWidth>1</bitWidth>
            </field>
            <field>
              <name>TDE</name>
              <bitOffset>14</bitOffset>
              <bitWidth>1</bitWidth>
            </field>
          </fields>
        </register>
        <register>
          <name>SR</name>
          <addressOffset>0x10</addressOffset>
          <size>0x20</size>
          <fields>
            <field>
              <name>UIF</name>
              <bitOffset>0</bitOffset>
              <bitWidth>1</bitWidth>
            </field>
            <field>
              <name>CC1IF</name>
              <bitOffset>1</bitOffset>
              <bitWidth>1</bitWidth>
            </field>
            <field>
              <name>CC2IF</name>
              <bitOffset>2</bitOffset>
              <bitWidth>1</bitWidth>
            </field>
            <field>
              <name>CC3IF</name>
              <bitOffset>3</bitOffset>
              <bitWidth>1</bitWidth>
            </field>
            <field>
              <name>CC4IF</name>
              <bitOffset>4</bitOffset>
              <bitWidth>1</bitWidth>
            </field>
            <field>
              <name>COMIF</name>
              <bitOffset>5</bitOffset>
              <bitWidth>1</bitWidth>
            </field>
            <field>
              <name>TIF</name>
              <bitOffset>6</bitOffset>
              <bitWidth>1</bitWidth>
            </field>
            <field>
              <name>BIF</name>
              <bitOffset>7</bitOffset>
              <bitWidth>1</bitWidth>
            </field>
            <field>
              <name>B2IF</name>
              <bitOffset>8</bitOffset>
              <bitWidth>1</bitWidth>
            </field>
            <field>
              <name>CC1OF</name>
              <bitOffset>9</bitOffset>
              <bitWidth>1</bitWidth>
            </field>
            <field>
              <name>CC2OF</name>
              <bitOffset>10</bitOffset>
              <bitWidth>1</bitWidth>
            </field>
            <field>
              <name>CC3OF</name>
              <bitOffset>11</bitOffset>
              <bitWidth>1</bitWidth>
            </field>
            <field>
              <name>CC4OF</name>
              <bitOffset>12</bitOffset>
              <bitWidth>1</bitWidth>
            </field>
            <field>
              <name>SBIF</name>
              <bitOffset>13</bitOffset>
              <bitWidth>1</bitWidth>
            </field>
            <field>
              <name>CC5IF</name>
              <bitOffset>16</bitOffset>
              <bitWidth>1</bitWidth>
            </field>
            <field>
              <name>CC6IF</name>
              <bitOffset>17</bitOffset>
              <bitWidth>1</bitWidth>
            </field>
          </fields>
        </register>
        <register>
          <name>EGR</name>
          <addressOffset>0x14</addressOffset>
          <size>0x20</size>
          <fields>
            <field>
              <name>UG</name>
              <bitOffset>0</bitOffset>
              <bitWidth>1</bitWidth>
            </field>
            <field>
              <name>CC1G</name>
              <bitOffset>1</bitOffset>
              <bitWidth>1</bitWidth>
            </field>
            <field>
              <name>CC2G</name>
              <bitOffset>2</bitOffset>
              <bitWidth>1</bitWidth>
            </field>
            <field>
              <name>CC3G</name>
              <bitOffset>3</bitOffset>
              <bitWidth>1</bitWidth>
            </field>
            <field>
              <name>CC4G</name>
              <bitOffset>4</bitOffset>
              <bitWidth>1</bitWidth>
            </field>
            <field>
              <name>COMG</name>
              <bitOffset>5</bitOffset>
              <bitWidth>1</bitWidth>
            </field>
            <field>
              <name>TG</name>
              <bitOffset>6</bitOffset>
              <bitWidth>1</bitWidth>
            </field>
            <field>
              <name>BG</name>
              <bitOffset>7</bitOffset>
              <bitWidth>1</bitWidth>
            </field>
            <field>
              <name>B2G</name>
              <bitOffset>8</bitOffset>
              <bitWidth>1</bitWidth>
            </field>
          </fields>
        </register>
        <register>
          <name>CCMR1</name>
          <addressOffset>0x18</addressOffset>
          <size>0x20</size>
          <fields>
            <field>
              <name>CC1S</name>
              <bitOffset>0</bitOffset>
              <bitWidth>2</bitWidth>
            </field>
            <field>
              <name>OC1FE</name>
              <bitOffset>2</bitOffset>
              <bitWidth>1</bitWidth>
            </field>
            <field>
              <name>OC1PE</name>
              <bitOffset>3</bitOffset>
              <bitWidth>1</bitWidth>
            </field>
            <field>
              <name>OC1M</name>
              <bitOffset>4</bitOffset>
              <bitWidth>13</bitWidth>
            </field>
            <field>
              <name>OC1CE</name>
              <bitOffset>7</bitOffset>
              <bitWidth>1</bitWidth>
            </field>
            <field>
              <name>CC2S</name>
              <bitOffset>8</bitOffset>
              <bitWidth>2</bitWidth>
            </field>
            <field>
              <name>OC2FE</name>
              <bitOffset>10</bitOffset>
              <bitWidth>1</bitWidth>
            </field>
            <field>
              <name>OC2PE</name>
              <bitOffset>11</bitOffset>
              <bitWidth>1</bitWidth>
            </field>
            <field>
              <name>OC2M</name>
              <bitOffset>12</bitOffset>
              <bitWidth>13</bitWidth>
            </field>
            <field>
              <name>OC2CE</name>
              <bitOffset>15</bitOffset>
              <bitWidth>1</bitWidth>
            </field>
          </fields>
        </register>
        <register>
          <name>CCMR2</name>
          <addressOffset>0x1c</addressOffset>
          <size>0x20</size>
          <fields>
            <field>
              <name>CC3S</name>
              <bitOffset>0</bitOffset>
              <bitWidth>2</bitWidth>
            </field>
            <field>
              <name>OC3FE</name>
              <bitOffset>2</bitOffset>
              <bitWidth>1</bitWidth>
            </field>
            <field>
              <name>OC3PE</name>
              <bitOffset>3</bitOffset>
              <bitWidth>1</bitWidth>
            </field>
            <field>
              <name>OC3M</name>
              <bitOffset>4</bitOffset>
              <bitWidth>13</bitWidth>
            </field>
            <field>
              <name>OC3CE</name>
              <bitOffset>7</bitOffset>
              <bitWidth>1</bitWidth>
            </field>
            <field>
              <name>CC4S</name>
              <bitOffset>8</bitOffset>
              <bitWidth>2</bitWidth>
            </field>
            <field>
              <name>OC4FE</name>
              <bitOffset>10</bitOffset>
              <bitWidth>1</bitWidth>
            </field>
            <field>
              <name>OC4PE</name>
              <bitOffset>11</bitOffset>
              <bitWidth>1</bitWidth>
            </field>
            <field>
              <name>OC4M</name>
              <bitOffset>12</bitOffset>
              <bitWidth>13</bitWidth>
            </field>
            <field>
              <name>OC4CE</name>
              <bitOffset>15</bitOffset>
              <bitWidth>1</bitWidth>
            </field>
          </fields>
        </register>
        <register>
          <name>CCER</name>
          <addressOffset>0x20</addressOffset>
          <size>0x20</size>
          <fields>
            <field>
              <name>CC1E</name>
              <bitOffset>0</bitOffset>
              <bitWidth>1</bitWidth>
            </field>
            <field>
              <name>CC1P</name>
              <bitOffset>1</bitOffset>
              <bitWidth>1</bitWidth>
            </field>
            <field>
              <name>CC1NE</name>
              <bitOffset>2</bitOffset>
              <bitWidth>1</bitWidth>
            </field>
            <field>
              <name>CC1NP</name>
              <bitOffset>3</bitOffset>
              <bitWidth>1</bitWidth>
            </field>
            <field>
              <name>CC2E</name>
              <bitOffset>4</bitOffset>
              <bitWidth>1</bitWidth>
            </field>
            <field>
              <name>CC2P</name>
              <bitOffset>5</bitOffset>
              <bitWidth>1</bitWidth>
            </field>
            <field>
              <name>CC2NE</name>
              <bitOffset>6</bitOffset>
              <bitWidth>1</bitWidth>
            </field>
            <field>
              <name>CC2NP</name>
              <bitOffset>7</bitOffset>
              <bitWidth>1</bitWidth>
            </field>
            <field>
              <name>CC3E</name>
              <bitOffset>8</bitOffset>
              <bitWidth>1</bitWidth>
            </field>
            <field>
              <name>CC3P</name>
              <bitOffset>9</bitOffset>
              <bitWidth>1</bitWidth>
            </field>
            <field>
              <name>CC3NE</name>
              <bitOffset>10</bitOffset>
              <bitWidth>1</bitWidth>
            </field>
            <field>
              <name>CC3NP</name>
              <bitOffset>11</bitOffset>
              <bitWidth>1</bitWidth>
            </field>
            <field>
              <name>CC4E</name>
              <bitOffset>12</bitOffset>
              <bitWidth>1</bitWidth>
            </field>
            <field>
              <name>CC4P</name>
              <bitOffset>13</bitOffset>
              <bitWidth>1</bitWidth>
            </field>
            <field>
              <name>CC4NP</name>
              <bitOffset>15</bitOffset>
              <bitWidth>1</bitWidth>
            </field>
            <field>
              <name>CC5E</name>
              <bitOffset>16</bitOffset>
              <bitWidth>1</bitWidth>
            </field>
            <field>
              <name>CC5P</name>
              <bitOffset>17</bitOffset>
              <bitWidth>1</bitWidth>
            </field>
            <field>
              <name>CC6E</name>
              <bitOffset>20</bitOffset>
              <bitWidth>1</bitWidth>
            </field>
            <field>
              <name>CC6P</name>
              <bitOffset>21</bitOffset>
              <bitWidth>1</bitWidth>
            </field>
          </fields>
        </register>
        <register>
          <name>CNT</name>
          <addressOffset>0x24</addressOffset>
          <size>0x20</size>
          <fields>
            <field>
              <name>CNT</name>
              <bitOffset>0</bitOffset>
              <bitWidth>32</bitWidth>
            </field>
            <field>
              <name>UIFCPY</name>
              <bitOffset>31</bitOffset>
              <bitWidth>1</bitWidth>
            </field>
          </fields>
        </register>
        <register>
          <name>PSC</name>
          <addressOffset>0x28</addressOffset>
          <size>0x20</size>
          <fields>
            <field>
              <name>PSC</name>
              <bitOffset>0</bitOffset>
              <bitWidth>16</bitWidth>
            </field>
          </fields>
        </register>
        <register>
          <name>ARR</name>
          <addressOffset>0x2c</addressOffset>
          <size>0x20</size>
          <fields>
            <field>
              <name>ARR</name>
              <bitOffset>0</bitOffset>
              <bitWidth>32</bitWidth>
            </field>
          </fields>
        </register>
        <register>
          <name>RCR</name>
          <addressOffset>0x30</addressOffset>
          <size>0x20</size>
          <fields>
            <field>
              <name>REP</name>
              <bitOffset>0</bitOffset>
              <bitWidth>16</bitWidth>
            </field>
          </fields>
        </register>
        <register>
          <name>CCR1</name>
          <addressOffset>0x34</addressOffset>
          <size>0x20</size>
          <fields>
            <field>
              <name>CCR1</name>
              <bitOffset>0</bitOffset>
              <bitWidth>16</bitWidth>
            </field>
          </fields>
        </register>
        <register>
          <name>CCR2</name>
          <addressOffset>0x38</addressOffset>
          <size>0x20</size>
          <fields>
            <field>
              <name>CCR2</name>
              <bitOffset>0</bitOffset>
              <bitWidth>16</bitWidth>
            </field>
          </fields>
        </register>
        <register>
          <name>CCR3</name>
          <addressOffset>0x3c</addressOffset>
          <size>0x20</size>
          <fields>
            <field>
              <name>CCR3</name>
              <bitOffset>0</bitOffset>
              <bitWidth>16</bitWidth>
            </field>
          </fields>
        </register>
        <register>
          <name>CCR4</name>
          <addressOffset>0x40</addressOffset>
          <size>0x20</size>
          <fields>
            <field>
              <name>CCR4</name>
              <bitOffset>0</bitOffset>
              <bitWidth>16</bitWidth>
            </field>
          </fields>
        </register>
        <register>
          <name>BDTR</name>
          <addressOffset>0x44</addressOffset>
          <size>0x20</size>
          <fields>
            <field>
              <name>DTG</name>
              <bitOffset>0</bitOffset>
              <bitWidth>8</bitWidth>
            </field>
            <field>
              <name>LOCK</name>
              <bitOffset>8</bitOffset>
              <bitWidth>2</bitWidth>
            </field>
            <field>
              <name>OSSI</name>
              <bitOffset>10</bitOffset>
              <bitWidth>1</bitWidth>
            </field>
            <field>
              <name>OSSR</name>
              <bitOffset>11</bitOffset>
              <bitWidth>1</bitWidth>
            </field>
            <field>
              <name>BKE</name>
              <bitOffset>12</bitOffset>
              <bitWidth>1</bitWidth>
            </field>
            <field>
              <name>BKP</name>
              <bitOffset>13</bitOffset>
              <bitWidth>1</bitWidth>
            </field>
            <field>
              <name>AOE</name>
              <bitOffset>14</bitOffset>
              <bitWidth>1</bitWidth>
            </field>
            <field>
              <name>MOE</name>
              <bitOffset>15</bitOffset>
              <bitWidth>1</bitWidth>
            </field>
            <field>
              <name>BKF</name>
              <bitOffset>16</bitOffset>
              <bitWidth>4</bitWidth>
            </field>
            <field>
              <name>BK2F</name>
              <bitOffset>20</bitOffset>
              <bitWidth>4</bitWidth>
            </field>
            <field>
              <name>BK2E</name>
              <bitOffset>24</bitOffset>
              <bitWidth>1</bitWidth>
            </field>
            <field>
              <name>BK2P</name>
              <bitOffset>25</bitOffset>
              <bitWidth>1</bitWidth>
            </field>
          </fields>
        </register>
        <register>
          <name>DCR</name>
          <addressOffset>0x48</addressOffset>
          <size>0x20</size>
          <fields>
            <field>
              <name>DBA</name>
              <bitOffset>0</bitOffset>
              <bitWidth>5</bitWidth>
            </field>
            <field>
              <name>DBL</name>
              <bitOffset>8</bitOffset>
              <bitWidth>5</bitWidth>
            </field>
          </fields>
        </register>
        <register>
          <name>DMAR</name>
          <addressOffset>0x4c</addressOffset>
          <size>0x20</size>
          <fields>
            <field>
              <name>DMAB</name>
              <bitOffset>0</bitOffset>
              <bitWidth>16</bitWidth>
            </field>
          </fields>
        </register>
        <register>
          <name>OR</name>
          <addressOffset>0x50</addressOffset>
          <size>0x20</size>
          <fields>
            <field>
              <name>TI4_RMP</name>
              <bitOffset>6</bitOffset>
              <bitWidth>2</bitWidth>
            </field>
            <field>
              <name>ITR1_RMP</name>
              <bitOffset>10</bitOffset>
              <bitWidth>2</bitWidth>
            </field>
          </fields>
        </register>
        <register>
          <name>CCMR3</name>
          <addressOffset>0x54</addressOffset>
          <size>0x20</size>
          <fields>
            <field>
              <name>OC5FE</name>
              <bitOffset>2</bitOffset>
              <bitWidth>1</bitWidth>
            </field>
            <field>
              <name>OC5PE</name>
              <bitOffset>3</bitOffset>
              <bitWidth>1</bitWidth>
            </field>
            <field>
              <name>OC5M</name>
              <bitOffset>4</bitOffset>
              <bitWidth>13</bitWidth>
            </field>
            <field>
              <name>OC5CE</name>
              <bitOffset>7</bitOffset>
              <bitWidth>1</bitWidth>
            </field>
            <field>
              <name>OC6FE</name>
              <bitOffset>10</bitOffset>
              <bitWidth>1</bitWidth>
            </field>
            <field>
              <name>OC6PE</name>
              <bitOffset>11</bitOffset>
              <bitWidth>1</bitWidth>
            </field>
            <field>
              <name>OC6M</name>
              <bitOffset>12</bitOffset>
              <bitWidth>13</bitWidth>
            </field>
            <field>
              <name>OC6CE</name>
              <bitOffset>15</bitOffset>
              <bitWidth>1</bitWidth>
            </field>
          </fields>
        </register>
        <register>
          <name>CCR5</name>
          <addressOffset>0x58</addressOffset>
          <size>0x20</size>
          <fields>
            <field>
              <name>CCR5</name>
              <bitOffset>0</bitOffset>
              <bitWidth>32</bitWidth>
            </field>
            <field>
              <name>GC5C1</name>
              <bitOffset>29</bitOffset>
              <bitWidth>1</bitWidth>
            </field>
            <field>
              <name>GC5C2</name>
              <bitOffset>30</bitOffset>
              <bitWidth>1</bitWidth>
            </field>
            <field>
              <name>GC5C3</name>
              <bitOffset>31</bitOffset>
              <bitWidth>1</bitWidth>
            </field>
          </fields>
        </register>
        <register>
          <name>CCR6</name>
          <addressOffset>0x5c</addressOffset>
          <size>0x20</size>
        </register>
        <register>
          <name>AF1</name>
          <addressOffset>0x60</addressOffset>
          <size>0x20</size>
        </register>
        <register>
          <name>AF2</name>
          <addressOffset>0x64</addressOffset>
          <size>0x20</size>
        </register>
      </registers>
    </peripheral>
    <peripheral>
      <name>TIM14</name>
      <baseAddress>0x40002000</baseAddress>
      <registers>
        <register>
          <name>CR1</name>
          <addressOffset>0x0</addressOffset>
          <size>0x20</size>
          <fields>
            <field>
              <name>CEN</name>
              <bitOffset>0</bitOffset>
              <bitWidth>1</bitWidth>
            </field>
            <field>
              <name>UDIS</name>
              <bitOffset>1</bitOffset>
              <bitWidth>1</bitWidth>
            </field>
            <field>
              <name>URS</name>
              <bitOffset>2</bitOffset>
              <bitWidth>1</bitWidth>
            </field>
            <field>
              <name>OPM</name>
              <bitOffset>3</bitOffset>
              <bitWidth>1</bitWidth>
            </field>
            <field>
              <name>DIR</name>
              <bitOffset>4</bitOffset>
              <bitWidth>1</bitWidth>
            </field>
            <field>
              <name>CMS</name>
              <bitOffset>5</bitOffset>
              <bitWidth>2</bitWidth>
            </field>
            <field>
              <name>ARPE</name>
              <bitOffset>7</bitOffset>
              <bitWidth>1</bitWidth>
            </field>
            <field>
              <name>CKD</name>
              <bitOffset>8</bitOffset>
              <bitWidth>2</bitWidth>
            </field>
            <field>
              <name>UIFREMAP</name>
              <bitOffset>11</bitOffset>
              <bitWidth>1</bitWidth>
            </field>
          </fields>
        </register>
        <register>
          <name>CR2</name>
          <addressOffset>0x4</addressOffset>
          <size>0x20</size>
          <fields>
            <field>
              <name>CCPC</name>
              <bitOffset>0</bitOffset>
              <bitWidth>1</bitWidth>
            </field>
            <field>
              <name>CCUS</name>
              <bitOffset>2</bitOffset>
              <bitWidth>1</bitWidth>
            </field>
            <field>
              <name>CCDS</name>
              <bitOffset>3</bitOffset>
              <bitWidth>1</bitWidth>
            </field>
            <field>
              <name>MMS</name>
              <bitOffset>4</bitOffset>
              <bitWidth>3</bitWidth>
            </field>
            <field>
              <name>TI1S</name>
              <bitOffset>7</bitOffset>
              <bitWidth>1</bitWidth>
            </field>
            <field>
              <name>OIS1</name>
              <bitOffset>8</bitOffset>
              <bitWidth>1</bitWidth>
            </field>
            <field>
              <name>OIS1N</name>
              <bitOffset>9</bitOffset>
              <bitWidth>1</bitWidth>
            </field>
            <field>
              <name>OIS2</name>
              <bitOffset>10</bitOffset>
              <bitWidth>1</bitWidth>
            </field>
            <field>
              <name>OIS2N</name>
              <bitOffset>11</bitOffset>
              <bitWidth>1</bitWidth>
            </field>
            <field>
              <name>OIS3</name>
              <bitOffset>12</bitOffset>
              <bitWidth>1</bitWidth>
            </field>
            <field>
              <name>OIS3N</name>
              <bitOffset>13</bitOffset>
              <bitWidth>1</bitWidth>
            </field>
            <field>
              <name>OIS4</name>
              <bitOffset>14</bitOffset>
              <bitWidth>1</bitWidth>
            </field>
            <field>
              <name>OIS5</name>
              <bitOffset>16</bitOffset>
              <bitWidth>1</bitWidth>
            </field>
            <field>
              <name>OIS6</name>
              <bitOffset>18</bitOffset>
              <bitWidth>1</bitWidth>
            </field>
            <field>
              <name>MMS2</name>
              <bitOffset>20</bitOffset>
              <bitWidth>4</bitWidth>
            </field>
          </fields>
        </register>
        <register>
          <name>SMCR</name>
          <addressOffset>0x8</addressOffset>
          <size>0x20</size>
          <fields>
            <field>
              <name>SMS</name>
              <bitOffset>0</bitOffset>
              <bitWidth>17</bitWidth>
            </field>
            <field>
              <name>TS</name>
              <bitOffset>4</bitOffset>
              <bitWidth>3</bitWidth>
            </field>
            <field>
              <name>MSM</name>
              <bitOffset>7</bitOffset>
              <bitWidth>1</bitWidth>
            </field>
            <field>
              <name>ETF</name>
              <bitOffset>8</bitOffset>
              <bitWidth>4</bitWidth>
            </field>
            <field>
              <name>ETPS</name>
              <bitOffset>12</bitOffset>
              <bitWidth>2</bitWidth>
            </field>
            <field>
              <name>ECE</name>
              <bitOffset>14</bitOffset>
              <bitWidth>1</bitWidth>
            </field>
            <field>
              <name>ETP</name>
              <bitOffset>15</bitOffset>
              <bitWidth>1</bitWidth>
            </field>
          </fields>
        </register>
        <register>
          <name>DIER</name>
          <addressOffset>0xc</addressOffset>
          <size>0x20</size>
          <fields>
            <field>
              <name>UIE</name>
              <bitOffset>0</bitOffset>
              <bitWidth>1</bitWidth>
            </field>
            <field>
              <name>CC1IE</name>
              <bitOffset>1</bitOffset>
              <bitWidth>1</bitWidth>
            </field>
            <field>
              <name>CC2IE</name>
              <bitOffset>2</bitOffset>
              <bitWidth>1</bitWidth>
            </field>
            <field>
              <name>CC3IE</name>
              <bitOffset>3</bitOffset>
              <bitWidth>1</bitWidth>
            </field>
            <field>
              <name>CC4IE</name>
              <bitOffset>4</bitOffset>
              <bitWidth>1</bitWidth>
            </field>
            <field>
              <name>COMIE</name>
              <bitOffset>5</bitOffset>
              <bitWidth>1</bitWidth>
            </field>
            <field>
              <name>TIE</name>
              <bitOffset>6</bitOffset>
              <bitWidth>1</bitWidth>
            </field>
            <field>
              <name>BIE</name>
              <bitOffset>7</bitOffset>
              <bitWidth>1</bitWidth>
            </field>
            <field>
              <name>UDE</name>
              <bitOffset>8</bitOffset>
              <bitWidth>1</bitWidth>
            </field>
            <field>
              <name>CC1DE</name>
              <bitOffset>9</bitOffset>
              <bitWidth>1</bitWidth>
            </field>
            <field>
              <name>CC2DE</name>
              <bitOffset>10</bitOffset>
              <bitWidth>1</bitWidth>
            </field>
            <field>
              <name>CC3DE</name>
              <bitOffset>11</bitOffset>
              <bitWidth>1</bitWidth>
            </field>
            <field>
              <name>CC4DE</name>
              <bitOffset>12</bitOffset>
              <bitWidth>1</bitWidth>
            </field>
            <field>
              <name>COMDE</name>
              <bitOffset>13</bitOffset>
              <bitWidth>1</bitWidth>
            </field>
            <field>
              <name>TDE</name>
              <bitOffset>14</bitOffset>
              <bitWidth>1</bitWidth>
            </field>
          </fields>
        </register>
        <register>
          <name>SR</name>
          <addressOffset>0x10</addressOffset>
          <size>0x20</size>
          <fields>
            <field>
              <name>UIF</name>
              <bitOffset>0</bitOffset>
              <bitWidth>1</bitWidth>
            </field>
            <field>
              <name>CC1IF</name>
              <bitOffset>1</bitOffset>
              <bitWidth>1</bitWidth>
            </field>
            <field>
              <name>CC2IF</name>
              <bitOffset>2</bitOffset>
              <bitWidth>1</bitWidth>
            </field>
            <field>
              <name>CC3IF</name>
              <bitOffset>3</bitOffset>
              <bitWidth>1</bitWidth>
            </field>
            <field>
              <name>CC4IF</name>
              <bitOffset>4</bitOffset>
              <bitWidth>1</bitWidth>
            </field>
            <field>
              <name>COMIF</name>
              <bitOffset>5</bitOffset>
              <bitWidth>1</bitWidth>
            </field>
            <field>
              <name>TIF</name>
              <bitOffset>6</bitOffset>
              <bitWidth>1</bitWidth>
            </field>
            <field>
              <name>BIF</name>
              <bitOffset>7</bitOffset>
              <bitWidth>1</bitWidth>
            </field>
            <field>
              <name>B2IF</name>
              <bitOffset>8</bitOffset>
              <bitWidth>1</bitWidth>
            </field>
            <field>
              <name>CC1OF</name>
              <bitOffset>9</bitOffset>
              <bitWidth>1</bitWidth>
            </field>
            <field>
              <name>CC2OF</name>
              <bitOffset>10</bitOffset>
              <bitWidth>1</bitWidth>
            </field>
            <field>
              <name>CC3OF</name>
              <bitOffset>11</bitOffset>
              <bitWidth>1</bitWidth>
            </field>
            <field>
              <name>CC4OF</name>
              <bitOffset>12</bitOffset>
              <bitWidth>1</bitWidth>
            </field>
            <field>
              <name>SBIF</name>
              <bitOffset>13</bitOffset>
              <bitWidth>1</bitWidth>
            </field>
            <field>
              <name>CC5IF</name>
              <bitOffset>16</bitOffset>
              <bitWidth>1</bitWidth>
            </field>
            <field>
              <name>CC6IF</name>
              <bitOffset>17</bitOffset>
              <bitWidth>1</bitWidth>
            </field>
          </fields>
        </register>
        <register>
          <name>EGR</name>
          <addressOffset>0x14</addressOffset>
          <size>0x20</size>
          <fields>
            <field>
              <name>UG</name>
              <bitOffset>0</bitOffset>
              <bitWidth>1</bitWidth>
            </field>
            <field>
              <name>CC1G</name>
              <bitOffset>1</bitOffset>
              <bitWidth>1</bitWidth>
            </field>
            <field>
              <name>CC2G</name>
              <bitOffset>2</bitOffset>
              <bitWidth>1</bitWidth>
            </field>
            <field>
              <name>CC3G</name>
              <bitOffset>3</bitOffset>
              <bitWidth>1</bitWidth>
            </field>
            <field>
              <name>CC4G</name>
              <bitOffset>4</bitOffset>
              <bitWidth>1</bitWidth>
            </field>
            <field>
              <name>COMG</name>
              <bitOffset>5</bitOffset>
              <bitWidth>1</bitWidth>
            </field>
            <field>
              <name>TG</name>
              <bitOffset>6</bitOffset>
              <bitWidth>1</bitWidth>
            </field>
            <field>
              <name>BG</name>
              <bitOffset>7</bitOffset>
              <bitWidth>1</bitWidth>
            </field>
            <field>
              <name>B2G</name>
              <bitOffset>8</bitOffset>
              <bitWidth>1</bitWidth>
            </field>
          </fields>
        </register>
        <register>
          <name>CCMR1</name>
          <addressOffset>0x18</addressOffset>
          <size>0x20</size>
          <fields>
            <field>
              <name>CC1S</name>
              <bitOffset>0</bitOffset>
              <bitWidth>2</bitWidth>
            </field>
            <field>
              <name>OC1FE</name>
              <bitOffset>2</bitOffset>
              <bitWidth>1</bitWidth>
            </field>
            <field>
              <name>OC1PE</name>
              <bitOffset>3</bitOffset>
              <bitWidth>1</bitWidth>
            </field>
            <field>
              <name>OC1M</name>
              <bitOffset>4</bitOffset>
              <bitWidth>13</bitWidth>
            </field>
            <field>
              <name>OC1CE</name>
              <bitOffset>7</bitOffset>
              <bitWidth>1</bitWidth>
            </field>
            <field>
              <name>CC2S</name>
              <bitOffset>8</bitOffset>
              <bitWidth>2</bitWidth>
            </field>
            <field>
              <name>OC2FE</name>
              <bitOffset>10</bitOffset>
              <bitWidth>1</bitWidth>
            </field>
            <field>
              <name>OC2PE</name>
              <bitOffset>11</bitOffset>
              <bitWidth>1</bitWidth>
            </field>
            <field>
              <name>OC2M</name>
              <bitOffset>12</bitOffset>
              <bitWidth>13</bitWidth>
            </field>
            <field>
              <name>OC2CE</name>
              <bitOffset>15</bitOffset>
              <bitWidth>1</bitWidth>
            </field>
          </fields>
        </register>
        <register>
          <name>CCMR2</name>
          <addressOffset>0x1c</addressOffset>
          <size>0x20</size>
          <fields>
            <field>
              <name>CC3S</name>
              <bitOffset>0</bitOffset>
              <bitWidth>2</bitWidth>
            </field>
            <field>
              <name>OC3FE</name>
              <bitOffset>2</bitOffset>
              <bitWidth>1</bitWidth>
            </field>
            <field>
              <name>OC3PE</name>
              <bitOffset>3</bitOffset>
              <bitWidth>1</bitWidth>
            </field>
            <field>
              <name>OC3M</name>
              <bitOffset>4</bitOffset>
              <bitWidth>13</bitWidth>
            </field>
            <field>
              <name>OC3CE</name>
              <bitOffset>7</bitOffset>
              <bitWidth>1</bitWidth>
            </field>
            <field>
              <name>CC4S</name>
              <bitOffset>8</bitOffset>
              <bitWidth>2</bitWidth>
            </field>
            <field>
              <name>OC4FE</name>
              <bitOffset>10</bitOffset>
              <bitWidth>1</bitWidth>
            </field>
            <field>
              <name>OC4PE</name>
              <bitOffset>11</bitOffset>
              <bitWidth>1</bitWidth>
            </field>
            <field>
              <name>OC4M</name>
              <bitOffset>12</bitOffset>
              <bitWidth>13</bitWidth>
            </field>
            <field>
              <name>OC4CE</name>
              <bitOffset>15</bitOffset>
              <bitWidth>1</bitWidth>
            </field>
          </fields>
        </register>
        <register>
          <name>CCER</name>
          <addressOffset>0x20</addressOffset>
          <size>0x20</size>
          <fields>
            <field>
              <name>CC1E</name>
              <bitOffset>0</bitOffset>
              <bitWidth>1</bitWidth>
            </field>
            <field>
              <name>CC1P</name>
              <bitOffset>1</bitOffset>
              <bitWidth>1</bitWidth>
            </field>
            <field>
              <name>CC1NE</name>
              <bitOffset>2</bitOffset>
              <bitWidth>1</bitWidth>
            </field>
            <field>
              <name>CC1NP</name>
              <bitOffset>3</bitOffset>
              <bitWidth>1</bitWidth>
            </field>
            <field>
              <name>CC2E</name>
              <bitOffset>4</bitOffset>
              <bitWidth>1</bitWidth>
            </field>
            <field>
              <name>CC2P</name>
              <bitOffset>5</bitOffset>
              <bitWidth>1</bitWidth>
            </field>
            <field>
              <name>CC2NE</name>
              <bitOffset>6</bitOffset>
              <bitWidth>1</bitWidth>
            </field>
            <field>
              <name>CC2NP</name>
              <bitOffset>7</bitOffset>
              <bitWidth>1</bitWidth>
            </field>
            <field>
              <name>CC3E</name>
              <bitOffset>8</bitOffset>
              <bitWidth>1</bitWidth>
            </field>
            <field>
              <name>CC3P</name>
              <bitOffset>9</bitOffset>
              <bitWidth>1</bitWidth>
            </field>
            <field>
              <name>CC3NE</name>
              <bitOffset>10</bitOffset>
              <bitWidth>1</bitWidth>
            </field>
            <field>
              <name>CC3NP</name>
              <bitOffset>11</bitOffset>
              <bitWidth>1</bitWidth>
            </field>
            <field>
              <name>CC4E</name>
              <bitOffset>12</bitOffset>
              <bitWidth>1</bitWidth>
            </field>
            <field>
              <name>CC4P</name>
              <bitOffset>13</bitOffset>
              <bitWidth>1</bitWidth>
            </field>
            <field>
              <name>CC4NP</name>
              <bitOffset>15</bitOffset>
              <bitWidth>1</bitWidth>
            </field>
            <field>
              <name>CC5E</name>
              <bitOffset>16</bitOffset>
              <bitWidth>1</bitWidth>
            </field>
            <field>
              <name>CC5P</name>
              <bitOffset>17</bitOffset>
              <bitWidth>1</bitWidth>
            </field>
            <field>
              <name>CC6E</name>
              <bitOffset>20</bitOffset>
              <bitWidth>1</bitWidth>
            </field>
            <field>
              <name>CC6P</name>
              <bitOffset>21</bitOffset>
              <bitWidth>1</bitWidth>
            </field>
          </fields>
        </register>
        <register>
          <name>CNT</name>
          <addressOffset>0x24</addressOffset>
          <size>0x20</size>
          <fields>
            <field>
              <name>CNT</name>
              <bitOffset>0</bitOffset>
              <bitWidth>32</bitWidth>
            </field>
            <field>
              <name>UIFCPY</name>
              <bitOffset>31</bitOffset>
              <bitWidth>1</bitWidth>
            </field>
          </fields>
        </register>
        <register>
          <name>PSC</name>
          <addressOffset>0x28</addressOffset>
          <size>0x20</size>
          <fields>
            <field>
              <name>PSC</name>
              <bitOffset>0</bitOffset>
              <bitWidth>16</bitWidth>
            </field>
          </fields>
        </register>
        <register>
          <name>ARR</name>
          <addressOffset>0x2c</addressOffset>
          <size>0x20</size>
          <fields>
            <field>
              <name>ARR</name>
              <bitOffset>0</bitOffset>
              <bitWidth>32</bitWidth>
            </field>
          </fields>
        </register>
        <register>
          <name>RCR</name>
          <addressOffset>0x30</addressOffset>
          <size>0x20</size>
          <fields>
            <field>
              <name>REP</name>
              <bitOffset>0</bitOffset>
              <bitWidth>16</bitWidth>
            </field>
          </fields>
        </register>
        <register>
          <name>CCR1</name>
          <addressOffset>0x34</addressOffset>
          <size>0x20</size>
          <fields>
            <field>
              <name>CCR1</name>
              <bitOffset>0</bitOffset>
              <bitWidth>16</bitWidth>
            </field>
          </fields>
        </register>
        <register>
          <name>CCR2</name>
          <addressOffset>0x38</addressOffset>
          <size>0x20</size>
          <fields>
            <field>
              <name>CCR2</name>
              <bitOffset>0</bitOffset>
              <bitWidth>16</bitWidth>
            </field>
          </fields>
        </register>
        <register>
          <name>CCR3</name>
          <addressOffset>0x3c</addressOffset>
          <size>0x20</size>
          <fields>
            <field>
              <name>CCR3</name>
              <bitOffset>0</bitOffset>
              <bitWidth>16</bitWidth>
            </field>
          </fields>
        </register>
        <register>
          <name>CCR4</name>
          <addressOffset>0x40</addressOffset>
          <size>0x20</size>
          <fields>
            <field>
              <name>CCR4</name>
              <bitOffset>0</bitOffset>
              <bitWidth>16</bitWidth>
            </field>
          </fields>
        </register>
        <register>
          <name>BDTR</name>
          <addressOffset>0x44</addressOffset>
          <size>0x20</size>
          <fields>
            <field>
              <name>DTG</name>
              <bitOffset>0</bitOffset>
              <bitWidth>8</bitWidth>
            </field>
            <field>
              <name>LOCK</name>
              <bitOffset>8</bitOffset>
              <bitWidth>2</bitWidth>
            </field>
            <field>
              <name>OSSI</name>
              <bitOffset>10</bitOffset>
              <bitWidth>1</bitWidth>
            </field>
            <field>
              <name>OSSR</name>
              <bitOffset>11</bitOffset>
              <bitWidth>1</bitWidth>
            </field>
            <field>
              <name>BKE</name>
              <bitOffset>12</bitOffset>
              <bitWidth>1</bitWidth>
            </field>
            <field>
              <name>BKP</name>
              <bitOffset>13</bitOffset>
              <bitWidth>1</bitWidth>
            </field>
            <field>
              <name>AOE</name>
              <bitOffset>14</bitOffset>
              <bitWidth>1</bitWidth>
            </field>
            <field>
              <name>MOE</name>
              <bitOffset>15</bitOffset>
              <bitWidth>1</bitWidth>
            </field>
            <field>
              <name>BKF</name>
              <bitOffset>16</bitOffset>
              <bitWidth>4</bitWidth>
            </field>
            <field>
              <name>BK2F</name>
              <bitOffset>20</bitOffset>
              <bitWidth>4</bitWidth>
            </field>
            <field>
              <name>BK2E</name>
              <bitOffset>24</bitOffset>
              <bitWidth>1</bitWidth>
            </field>
            <field>
              <name>BK2P</name>
              <bitOffset>25</bitOffset>
              <bitWidth>1</bitWidth>
            </field>
          </fields>
        </register>
        <register>
          <name>DCR</name>
          <addressOffset>0x48</addressOffset>
          <size>0x20</size>
          <fields>
            <field>
              <name>DBA</name>
              <bitOffset>0</bitOffset>
              <bitWidth>5</bitWidth>
            </field>
            <field>
              <name>DBL</name>
              <bitOffset>8</bitOffset>
              <bitWidth>5</bitWidth>
            </field>
          </fields>
        </register>
        <register>
          <name>DMAR</name>
          <addressOffset>0x4c</addressOffset>
          <size>0x20</size>
          <fields>
            <field>
              <name>DMAB</name>
              <bitOffset>0</bitOffset>
              <bitWidth>16</bitWidth>
            </field>
          </fields>
        </register>
        <register>
          <name>OR</name>
          <addressOffset>0x50</addressOffset>
          <size>0x20</size>
          <fields>
            <field>
              <name>TI4_RMP</name>
              <bitOffset>6</bitOffset>
              <bitWidth>2</bitWidth>
            </field>
            <field>
              <name>ITR1_RMP</name>
              <bitOffset>10</bitOffset>
              <bitWidth>2</bitWidth>
            </field>
          </fields>
        </register>
        <register>
          <name>CCMR3</name>
          <addressOffset>0x54</addressOffset>
          <size>0x20</size>
          <fields>
            <field>
              <name>OC5FE</name>
              <bitOffset>2</bitOffset>
              <bitWidth>1</bitWidth>
            </field>
            <field>
              <name>OC5PE</name>
              <bitOffset>3</bitOffset>
              <bitWidth>1</bitWidth>
            </field>
            <field>
              <name>OC5M</name>
              <bitOffset>4</bitOffset>
              <bitWidth>13</bitWidth>
            </field>
            <field>
              <name>OC5CE</name>
              <bitOffset>7</bitOffset>
              <bitWidth>1</bitWidth>
            </field>
            <field>
              <name>OC6FE</name>
              <bitOffset>10</bitOffset>
              <bitWidth>1</bitWidth>
            </field>
            <field>
              <name>OC6PE</name>
              <bitOffset>11</bitOffset>
              <bitWidth>1</bitWidth>
            </field>
            <field>
              <name>OC6M</name>
              <bitOffset>12</bitOffset>
              <bitWidth>13</bitWidth>
            </field>
            <field>
              <name>OC6CE</name>
              <bitOffset>15</bitOffset>
              <bitWidth>1</bitWidth>
            </field>
          </fields>
        </register>
        <register>
          <name>CCR5</name>
          <addressOffset>0x58</addressOffset>
          <size>0x20</size>
          <fields>
            <field>
              <name>CCR5</name>
              <bitOffset>0</bitOffset>
              <bitWidth>32</bitWidth>
            </field>
            <field>
              <name>GC5C1</name>
              <bitOffset>29</bitOffset>
              <bitWidth>1</bitWidth>
            </field>
            <field>
              <name>GC5C2</name>
              <bitOffset>30</bitOffset>
              <bitWidth>1</bitWidth>
            </field>
            <field>
              <name>GC5C3</name>
              <bitOffset>31</bitOffset>
              <bitWidth>1</bitWidth>
            </field>
          </fields>
        </register>
        <register>
          <name>CCR6</name>
          <addressOffset>0x5c</addressOffset>
          <size>0x20</size>
        </register>
        <register>
          <name>AF1</name>
          <addressOffset>0x60</addressOffset>
          <size>0x20</size>
        </register>
        <register>
          <name>AF2</name>
          <addressOffset>0x64</addressOffset>
          <size>0x20</size>
        </register>
      </registers>
    </peripheral>
    <peripheral>
      <name>LPTIM1</name>
      <baseAddress>0x40002400</baseAddress>
      <registers>
        <register>
          <name>ISR</name>
          <addressOffset>0x0</addressOffset>
          <size>0x20</size>
          <fields>
            <field>
              <name>CMPM</name>
              <bitOffset>0</bitOffset>
              <bitWidth>1</bitWidth>
            </field>
            <field>
              <name>ARRM</name>
              <bitOffset>1</bitOffset>
              <bitWidth>1</bitWidth>
            </field>
            <field>
              <name>EXTTRIG</name>
              <bitOffset>2</bitOffset>
              <bitWidth>1</bitWidth>
            </field>
            <field>
              <name>CMPOK</name>
              <bitOffset>3</bitOffset>
              <bitWidth>1</bitWidth>
            </field>
            <field>
              <name>ARROK</name>
              <bitOffset>4</bitOffset>
              <bitWidth>1</bitWidth>
            </field>
            <field>
              <name>UP</name>
              <bitOffset>5</bitOffset>
              <bitWidth>1</bitWidth>
            </field>
            <field>
              <name>DOWN</name>
              <bitOffset>6</bitOffset>
              <bitWidth>1</bitWidth>
            </field>
          </fields>
        </register>
        <register>
          <name>ICR</name>
          <addressOffset>0x4</addressOffset>
          <size>0x20</size>
          <fields>
            <field>
              <name>CMPMCF</name>
              <bitOffset>0</bitOffset>
              <bitWidth>1</bitWidth>
            </field>
            <field>
              <name>ARRMCF</name>
              <bitOffset>1</bitOffset>
              <bitWidth>1</bitWidth>
            </field>
            <field>
              <name>EXTTRIGCF</name>
              <bitOffset>2</bitOffset>
              <bitWidth>1</bitWidth>
            </field>
            <field>
              <name>CMPOKCF</name>
              <bitOffset>3</bitOffset>
              <bitWidth>1</bitWidth>
            </field>
            <field>
              <name>ARROKCF</name>
              <bitOffset>4</bitOffset>
              <bitWidth>1</bitWidth>
            </field>
            <field>
              <name>UPCF</name>
              <bitOffset>5</bitOffset>
              <bitWidth>1</bitWidth>
            </field>
            <field>
              <name>DOWNCF</name>
              <bitOffset>6</bitOffset>
              <bitWidth>1</bitWidth>
            </field>
          </fields>
        </register>
        <register>
          <name>IER</name>
          <addressOffset>0x8</addressOffset>
          <size>0x20</size>
          <fields>
            <field>
              <name>CMPMIE</name>
              <bitOffset>0</bitOffset>
              <bitWidth>1</bitWidth>
            </field>
            <field>
              <name>ARRMIE</name>
              <bitOffset>1</bitOffset>
              <bitWidth>1</bitWidth>
            </field>
            <field>
              <name>EXTTRIGIE</name>
              <bitOffset>2</bitOffset>
              <bitWidth>1</bitWidth>
            </field>
            <field>
              <name>CMPOKIE</name>
              <bitOffset>3</bitOffset>
              <bitWidth>1</bitWidth>
            </field>
            <field>
              <name>ARROKIE</name>
              <bitOffset>4</bitOffset>
              <bitWidth>1</bitWidth>
            </field>
            <field>
              <name>UPIE</name>
              <bitOffset>5</bitOffset>
              <bitWidth>1</bitWidth>
            </field>
            <field>
              <name>DOWNIE</name>
              <bitOffset>6</bitOffset>
              <bitWidth>1</bitWidth>
            </field>
          </fields>
        </register>
        <register>
          <name>CFGR</name>
          <addressOffset>0xc</addressOffset>
          <size>0x20</size>
          <fields>
            <field>
              <name>CKSEL</name>
              <bitOffset>0</bitOffset>
              <bitWidth>1</bitWidth>
            </field>
            <field>
              <name>CKPOL</name>
              <bitOffset>1</bitOffset>
              <bitWidth>2</bitWidth>
            </field>
            <field>
              <name>CKFLT</name>
              <bitOffset>3</bitOffset>
              <bitWidth>2</bitWidth>
            </field>
            <field>
              <name>TRGFLT</name>
              <bitOffset>6</bitOffset>
              <bitWidth>2</bitWidth>
            </field>
            <field>
              <name>PRESC</name>
              <bitOffset>9</bitOffset>
              <bitWidth>3</bitWidth>
            </field>
            <field>
              <name>TRIGSEL</name>
              <bitOffset>13</bitOffset>
              <bitWidth>3</bitWidth>
            </field>
            <field>
              <name>TRIGEN</name>
              <bitOffset>17</bitOffset>
              <bitWidth>2</bitWidth>
            </field>
            <field>
              <name>TIMOUT</name>
              <bitOffset>19</bitOffset>
              <bitWidth>1</bitWidth>
            </field>
            <field>
              <name>WAVE</name>
              <bitOffset>20</bitOffset>
              <bitWidth>1</bitWidth>
            </field>
            <field>
              <name>WAVPOL</name>
              <bitOffset>21</bitOffset>
              <bitWidth>1</bitWidth>
            </field>
            <field>
              <name>PRELOAD</name>
              <bitOffset>22</bitOffset>
              <bitWidth>1</bitWidth>
            </field>
            <field>
              <name>COUNTMODE</name>
              <bitOffset>23</bitOffset>
              <bitWidth>1</bitWidth>
            </field>
            <field>
              <name>ENC</name>
              <bitOffset>24</bitOffset>
              <bitWidth>1</bitWidth>
            </field>
          </fields>
        </register>
        <register>
          <name>CR</name>
          <addressOffset>0x10</addressOffset>
          <size>0x20</size>
          <fields>
            <field>
              <name>ENABLE</name>
              <bitOffset>0</bitOffset>
              <bitWidth>1</bitWidth>
            </field>
            <field>
              <name>SNGSTRT</name>
              <bitOffset>1</bitOffset>
              <bitWidth>1</bitWidth>
            </field>
            <field>
              <name>CNTSTRT</name>
              <bitOffset>2</bitOffset>
              <bitWidth>1</bitWidth>
            </field>
          </fields>
        </register>
        <register>
          <name>CMP</name>
          <addressOffset>0x14</addressOffset>
          <size>0x20</size>
          <fields>
            <field>
              <name>CMP</name>
              <bitOffset>0</bitOffset>
              <bitWidth>16</bitWidth>
            </field>
          </fields>
        </register>
        <register>
          <name>ARR</name>
          <addressOffset>0x18</addressOffset>
          <size>0x20</size>
          <fields>
            <field>
              <name>ARR</name>
              <bitOffset>0</bitOffset>
              <bitWidth>16</bitWidth>
            </field>
          </fields>
        </register>
        <register>
          <name>CNT</name>
          <addressOffset>0x1c</addressOffset>
          <size>0x20</size>
          <fields>
            <field>
              <name>CNT</name>
              <bitOffset>0</bitOffset>
              <bitWidth>16</bitWidth>
            </field>
          </fields>
        </register>
      </registers>
    </peripheral>
    <peripheral>
      <name>RTC</name>
      <baseAddress>0x40002800</baseAddress>
      <registers>
        <register>
          <name>TR</name>
          <addressOffset>0x0</addressOffset>
          <size>0x20</size>
          <fields>
            <field>
              <name>SU</name>
              <bitOffset>0</bitOffset>
              <bitWidth>4</bitWidth>
            </field>
            <field>
              <name>ST</name>
              <bitOffset>4</bitOffset>
              <bitWidth>3</bitWidth>
            </field>
            <field>
              <name>MNU</name>
              <bitOffset>8</bitOffset>
              <bitWidth>4</bitWidth>
            </field>
            <field>
              <name>MNT</name>
              <bitOffset>12</bitOffset>
              <bitWidth>3</bitWidth>
            </field>
            <field>
              <name>HU</name>
              <bitOffset>16</bitOffset>
              <bitWidth>4</bitWidth>
            </field>
            <field>
              <name>HT</name>
              <bitOffset>20</bitOffset>
              <bitWidth>2</bitWidth>
            </field>
            <field>
              <name>PM</name>
              <bitOffset>22</bitOffset>
              <bitWidth>1</bitWidth>
            </field>
          </fields>
        </register>
        <register>
          <name>DR</name>
          <addressOffset>0x4</addressOffset>
          <size>0x20</size>
          <fields>
            <field>
              <name>DU</name>
              <bitOffset>0</bitOffset>
              <bitWidth>4</bitWidth>
            </field>
            <field>
              <name>DT</name>
              <bitOffset>4</bitOffset>
              <bitWidth>2</bitWidth>
            </field>
            <field>
              <name>MU</name>
              <bitOffset>8</bitOffset>
              <bitWidth>4</bitWidth>
            </field>
            <field>
              <name>MT</name>
              <bitOffset>12</bitOffset>
              <bitWidth>1</bitWidth>
            </field>
            <field>
              <name>WDU</name>
              <bitOffset>13</bitOffset>
              <bitWidth>3</bitWidth>
            </field>
            <field>
              <name>YU</name>
              <bitOffset>16</bitOffset>
              <bitWidth>4</bitWidth>
            </field>
            <field>
              <name>YT</name>
              <bitOffset>20</bitOffset>
              <bitWidth>4</bitWidth>
            </field>
          </fields>
        </register>
        <register>
          <name>CR</name>
          <addressOffset>0x8</addressOffset>
          <size>0x20</size>
          <fields>
            <field>
              <name>WUCKSEL</name>
              <bitOffset>0</bitOffset>
              <bitWidth>3</bitWidth>
            </field>
            <field>
              <name>TSEDGE</name>
              <bitOffset>3</bitOffset>
              <bitWidth>1</bitWidth>
            </field>
            <field>
              <name>REFCKON</name>
              <bitOffset>4</bitOffset>
              <bitWidth>1</bitWidth>
            </field>
            <field>
              <name>BYPSHAD</name>
              <bitOffset>5</bitOffset>
              <bitWidth>1</bitWidth>
            </field>
            <field>
              <name>FMT</name>
              <bitOffset>6</bitOffset>
              <bitWidth>1</bitWidth>
            </field>
            <field>
              <name>ALRAE</name>
              <bitOffset>8</bitOffset>
              <bitWidth>1</bitWidth>
            </field>
            <field>
              <name>ALRBE</name>
              <bitOffset>9</bitOffset>
              <bitWidth>1</bitWidth>
            </field>
            <field>
              <name>WUTE</name>
              <bitOffset>10</bitOffset>
              <bitWidth>1</bitWidth>
            </field>
            <field>
              <name>TSE</name>
              <bitOffset>11</bitOffset>
              <bitWidth>1</bitWidth>
            </field>
            <field>
              <name>ALRAIE</name>
              <bitOffset>12</bitOffset>
              <bitWidth>1</bitWidth>
            </field>
            <field>
              <name>ALRBIE</name>
              <bitOffset>13</bitOffset>
              <bitWidth>1</bitWidth>
            </field>
            <field>
              <name>WUTIE</name>
              <bitOffset>14</bitOffset>
              <bitWidth>1</bitWidth>
            </field>
            <field>
              <name>TSIE</name>
              <bitOffset>15</bitOffset>
              <bitWidth>1</bitWidth>
            </field>
            <field>
              <name>ADD1H</name>
              <bitOffset>16</bitOffset>
              <bitWidth>1</bitWidth>
            </field>
            <field>
              <name>SUB1H</name>
              <bitOffset>17</bitOffset>
              <bitWidth>1</bitWidth>
            </field>
            <field>
              <name>BKP</name>
              <bitOffset>18</bitOffset>
              <bitWidth>1</bitWidth>
            </field>
            <field>
              <name>COSEL</name>
              <bitOffset>19</bitOffset>
              <bitWidth>1</bitWidth>
            </field>
            <field>
              <name>POL</name>
              <bitOffset>20</bitOffset>
              <bitWidth>1</bitWidth>
            </field>
            <field>
              <name>OSEL</name>
              <bitOffset>21</bitOffset>
              <bitWidth>2</bitWidth>
            </field>
            <field>
              <name>COE</name>
              <bitOffset>23</bitOffset>
              <bitWidth>1</bitWidth>
            </field>
            <field>
              <name>ITSE</name>
              <bitOffset>24</bitOffset>
              <bitWidth>1</bitWidth>
            </field>
          </fields>
        </register>
        <register>
          <name>ISR</name>
          <addressOffset>0xc</addressOffset>
          <size>0x20</size>
          <fields>
            <field>
              <name>ALRAWF</name>
              <bitOffset>0</bitOffset>
              <bitWidth>1</bitWidth>
            </field>
            <field>
              <name>ALRBWF</name>
              <bitOffset>1</bitOffset>
              <bitWidth>1</bitWidth>
            </field>
            <field>
              <name>WUTWF</name>
              <bitOffset>2</bitOffset>
              <bitWidth>1</bitWidth>
            </field>
            <field>
              <name>SHPF</name>
              <bitOffset>3</bitOffset>
              <bitWidth>1</bitWidth>
            </field>
            <field>
              <name>INITS</name>
              <bitOffset>4</bitOffset>
              <bitWidth>1</bitWidth>
            </field>
            <field>
              <name>RSF</name>
              <bitOffset>5</bitOffset>
              <bitWidth>1</bitWidth>
            </field>
            <field>
              <name>INITF</name>
              <bitOffset>6</bitOffset>
              <bitWidth>1</bitWidth>
            </field>
            <field>
              <name>INIT</name>
              <bitOffset>7</bitOffset>
              <bitWidth>1</bitWidth>
            </field>
            <field>
              <name>ALRAF</name>
              <bitOffset>8</bitOffset>
              <bitWidth>1</bitWidth>
            </field>
            <field>
              <name>ALRBF</name>
              <bitOffset>9</bitOffset>
              <bitWidth>1</bitWidth>
            </field>
            <field>
              <name>WUTF</name>
              <bitOffset>10</bitOffset>
              <bitWidth>1</bitWidth>
            </field>
            <field>
              <name>TSF</name>
              <bitOffset>11</bitOffset>
              <bitWidth>1</bitWidth>
            </field>
            <field>
              <name>TSOVF</name>
              <bitOffset>12</bitOffset>
              <bitWidth>1</bitWidth>
            </field>
            <field>
              <name>TAMP1F</name>
              <bitOffset>13</bitOffset>
              <bitWidth>1</bitWidth>
            </field>
            <field>
              <name>TAMP2F</name>
              <bitOffset>14</bitOffset>
              <bitWidth>1</bitWidth>
            </field>
            <field>
              <name>TAMP3F</name>
              <bitOffset>15</bitOffset>
              <bitWidth>1</bitWidth>
            </field>
            <field>
              <name>RECALPF</name>
              <bitOffset>16</bitOffset>
              <bitWidth>1</bitWidth>
            </field>
            <field>
              <name>ITSF</name>
              <bitOffset>17</bitOffset>
              <bitWidth>1</bitWidth>
            </field>
          </fields>
        </register>
        <register>
          <name>PRER</name>
          <addressOffset>0x10</addressOffset>
          <size>0x20</size>
          <fields>
            <field>
              <name>PREDIV_S</name>
              <bitOffset>0</bitOffset>
              <bitWidth>15</bitWidth>
            </field>
            <field>
              <name>PREDIV_A</name>
              <bitOffset>16</bitOffset>
              <bitWidth>7</bitWidth>
            </field>
          </fields>
        </register>
        <register>
          <name>WUTR</name>
          <addressOffset>0x14</addressOffset>
          <size>0x20</size>
          <fields>
            <field>
              <name>WUT</name>
              <bitOffset>0</bitOffset>
              <bitWidth>16</bitWidth>
            </field>
          </fields>
        </register>
        <register>
          <name>ALRMAR</name>
          <addressOffset>0x1c</addressOffset>
          <size>0x20</size>
          <fields>
            <field>
              <name>SU</name>
              <bitOffset>0</bitOffset>
              <bitWidth>4</bitWidth>
            </field>
            <field>
              <name>ST</name>
              <bitOffset>4</bitOffset>
              <bitWidth>3</bitWidth>
            </field>
            <field>
              <name>MSK1</name>
              <bitOffset>7</bitOffset>
              <bitWidth>1</bitWidth>
            </field>
            <field>
              <name>MNU</name>
              <bitOffset>8</bitOffset>
              <bitWidth>4</bitWidth>
            </field>
            <field>
              <name>MNT</name>
              <bitOffset>12</bitOffset>
              <bitWidth>3</bitWidth>
            </field>
            <field>
              <name>MSK2</name>
              <bitOffset>15</bitOffset>
              <bitWidth>1</bitWidth>
            </field>
            <field>
              <name>HU</name>
              <bitOffset>16</bitOffset>
              <bitWidth>4</bitWidth>
            </field>
            <field>
              <name>HT</name>
              <bitOffset>20</bitOffset>
              <bitWidth>2</bitWidth>
            </field>
            <field>
              <name>PM</name>
              <bitOffset>22</bitOffset>
              <bitWidth>1</bitWidth>
            </field>
            <field>
              <name>MSK3</name>
              <bitOffset>23</bitOffset>
              <bitWidth>1</bitWidth>
            </field>
            <field>
              <name>DU</name>
              <bitOffset>24</bitOffset>
              <bitWidth>4</bitWidth>
            </field>
            <field>
              <name>DT</name>
              <bitOffset>28</bitOffset>
              <bitWidth>2</bitWidth>
            </field>
            <field>
              <name>WDSEL</name>
              <bitOffset>30</bitOffset>
              <bitWidth>1</bitWidth>
            </field>
            <field>
              <name>MSK4</name>
              <bitOffset>31</bitOffset>
              <bitWidth>1</bitWidth>
            </field>
          </fields>
        </register>
        <register>
          <name>ALRMBR</name>
          <addressOffset>0x20</addressOffset>
          <size>0x20</size>
          <fields>
            <field>
              <name>SU</name>
              <bitOffset>0</bitOffset>
              <bitWidth>4</bitWidth>
            </field>
            <field>
              <name>ST</name>
              <bitOffset>4</bitOffset>
              <bitWidth>3</bitWidth>
            </field>
            <field>
              <name>MSK1</name>
              <bitOffset>7</bitOffset>
              <bitWidth>1</bitWidth>
            </field>
            <field>
              <name>MNU</name>
              <bitOffset>8</bitOffset>
              <bitWidth>4</bitWidth>
            </field>
            <field>
              <name>MNT</name>
              <bitOffset>12</bitOffset>
              <bitWidth>3</bitWidth>
            </field>
            <field>
              <name>MSK2</name>
              <bitOffset>15</bitOffset>
              <bitWidth>1</bitWidth>
            </field>
            <field>
              <name>HU</name>
              <bitOffset>16</bitOffset>
              <bitWidth>4</bitWidth>
            </field>
            <field>
              <name>HT</name>
              <bitOffset>20</bitOffset>
              <bitWidth>2</bitWidth>
            </field>
            <field>
              <name>PM</name>
              <bitOffset>22</bitOffset>
              <bitWidth>1</bitWidth>
            </field>
            <field>
              <name>MSK3</name>
              <bitOffset>23</bitOffset>
              <bitWidth>1</bitWidth>
            </field>
            <field>
              <name>DU</name>
              <bitOffset>24</bitOffset>
              <bitWidth>4</bitWidth>
            </field>
            <field>
              <name>DT</name>
              <bitOffset>28</bitOffset>
              <bitWidth>2</bitWidth>
            </field>
            <field>
              <name>WDSEL</name>
              <bitOffset>30</bitOffset>
              <bitWidth>1</bitWidth>
            </field>
            <field>
              <name>MSK4</name>
              <bitOffset>31</bitOffset>
              <bitWidth>1</bitWidth>
            </field>
          </fields>
        </register>
        <register>
          <name>WPR</name>
          <addressOffset>0x24</addressOffset>
          <size>0x20</size>
          <fields>
            <field>
              <name>KEY</name>
              <bitOffset>0</bitOffset>
              <bitWidth>8</bitWidth>
            </field>
          </fields>
        </register>
        <register>
          <name>SSR</name>
          <addressOffset>0x28</addressOffset>
          <size>0x20</size>
          <fields>
            <field>
              <name>SS</name>
              <bitOffset>0</bitOffset>
              <bitWidth>16</bitWidth>
            </field>
          </fields>
        </register>
        <register>
          <name>SHIFTR</name>
          <addressOffset>0x2c</addressOffset>
          <size>0x20</size>
          <fields>
            <field>
              <name>SUBFS</name>
              <bitOffset>0</bitOffset>
              <bitWidth>15</bitWidth>
            </field>
            <field>
              <name>ADD1S</name>
              <bitOffset>31</bitOffset>
              <bitWidth>1</bitWidth>
            </field>
          </fields>
        </register>
        <register>
          <name>TSTR</name>
          <addressOffset>0x30</addressOffset>
          <size>0x20</size>
          <fields>
            <field>
              <name>SU</name>
              <bitOffset>0</bitOffset>
              <bitWidth>4</bitWidth>
            </field>
            <field>
              <name>ST</name>
              <bitOffset>4</bitOffset>
              <bitWidth>3</bitWidth>
            </field>
            <field>
              <name>MNU</name>
              <bitOffset>8</bitOffset>
              <bitWidth>4</bitWidth>
            </field>
            <field>
              <name>MNT</name>
              <bitOffset>12</bitOffset>
              <bitWidth>3</bitWidth>
            </field>
            <field>
              <name>HU</name>
              <bitOffset>16</bitOffset>
              <bitWidth>4</bitWidth>
            </field>
            <field>
              <name>HT</name>
              <bitOffset>20</bitOffset>
              <bitWidth>2</bitWidth>
            </field>
            <field>
              <name>PM</name>
              <bitOffset>22</bitOffset>
              <bitWidth>1</bitWidth>
            </field>
          </fields>
        </register>
        <register>
          <name>TSDR</name>
          <addressOffset>0x34</addressOffset>
          <size>0x20</size>
          <fields>
            <field>
              <name>DU</name>
              <bitOffset>0</bitOffset>
              <bitWidth>4</bitWidth>
            </field>
            <field>
              <name>DT</name>
              <bitOffset>4</bitOffset>
              <bitWidth>2</bitWidth>
            </field>
            <field>
              <name>MU</name>
              <bitOffset>8</bitOffset>
              <bitWidth>4</bitWidth>
            </field>
            <field>
              <name>MT</name>
              <bitOffset>12</bitOffset>
              <bitWidth>1</bitWidth>
            </field>
            <field>
              <name>WDU</name>
              <bitOffset>13</bitOffset>
              <bitWidth>3</bitWidth>
            </field>
          </fields>
        </register>
        <register>
          <name>TSSSR</name>
          <addressOffset>0x38</addressOffset>
          <size>0x20</size>
          <fields>
            <field>
              <name>SS</name>
              <bitOffset>0</bitOffset>
              <bitWidth>16</bitWidth>
            </field>
          </fields>
        </register>
        <register>
          <name>CALR</name>
          <addressOffset>0x3c</addressOffset>
          <size>0x20</size>
          <fields>
            <field>
              <name>CALM</name>
              <bitOffset>0</bitOffset>
              <bitWidth>9</bitWidth>
            </field>
            <field>
              <name>CALW16</name>
              <bitOffset>13</bitOffset>
              <bitWidth>1</bitWidth>
            </field>
            <field>
              <name>CALW8</name>
              <bitOffset>14</bitOffset>
              <bitWidth>1</bitWidth>
            </field>
            <field>
              <name>CALP</name>
              <bitOffset>15</bitOffset>
              <bitWidth>1</bitWidth>
            </field>
          </fields>
        </register>
        <register>
          <name>TAMPCR</name>
          <addressOffset>0x40</addressOffset>
          <size>0x20</size>
          <fields>
            <field>
              <name>TAMP1E</name>
              <bitOffset>0</bitOffset>
              <bitWidth>1</bitWidth>
            </field>
            <field>
              <name>TAMP1TRG</name>
              <bitOffset>1</bitOffset>
              <bitWidth>1</bitWidth>
            </field>
            <field>
              <name>TAMPIE</name>
              <bitOffset>2</bitOffset>
              <bitWidth>1</bitWidth>
            </field>
            <field>
              <name>TAMP2E</name>
              <bitOffset>3</bitOffset>
              <bitWidth>1</bitWidth>
            </field>
            <field>
              <name>TAMP2TRG</name>
              <bitOffset>4</bitOffset>
              <bitWidth>1</bitWidth>
            </field>
            <field>
              <name>TAMP3E</name>
              <bitOffset>5</bitOffset>
              <bitWidth>1</bitWidth>
            </field>
            <field>
              <name>TAMP3TRG</name>
              <bitOffset>6</bitOffset>
              <bitWidth>1</bitWidth>
            </field>
            <field>
              <name>TAMPTS</name>
              <bitOffset>7</bitOffset>
              <bitWidth>1</bitWidth>
            </field>
            <field>
              <name>TAMPFREQ</name>
              <bitOffset>8</bitOffset>
              <bitWidth>3</bitWidth>
            </field>
            <field>
              <name>TAMPFLT</name>
              <bitOffset>11</bitOffset>
              <bitWidth>2</bitWidth>
            </field>
            <field>
              <name>TAMPPRCH</name>
              <bitOffset>13</bitOffset>
              <bitWidth>2</bitWidth>
            </field>
            <field>
              <name>TAMPPUDIS</name>
              <bitOffset>15</bitOffset>
              <bitWidth>1</bitWidth>
            </field>
            <field>
              <name>TAMP1IE</name>
              <bitOffset>16</bitOffset>
              <bitWidth>1</bitWidth>
            </field>
            <field>
              <name>TAMP1NOERASE</name>
              <bitOffset>17</bitOffset>
              <bitWidth>1</bitWidth>
            </field>
            <field>
              <name>TAMP1MF</name>
              <bitOffset>18</bitOffset>
              <bitWidth>1</bitWidth>
            </field>
            <field>
              <name>TAMP2IE</name>
              <bitOffset>19</bitOffset>
              <bitWidth>1</bitWidth>
            </field>
            <field>
              <name>TAMP2NOERASE</name>
              <bitOffset>20</bitOffset>
              <bitWidth>1</bitWidth>
            </field>
            <field>
              <name>TAMP2MF</name>
              <bitOffset>21</bitOffset>
              <bitWidth>1</bitWidth>
            </field>
            <field>
              <name>TAMP3IE</name>
              <bitOffset>22</bitOffset>
              <bitWidth>1</bitWidth>
            </field>
            <field>
              <name>TAMP3NOERASE</name>
              <bitOffset>23</bitOffset>
              <bitWidth>1</bitWidth>
            </field>
            <field>
              <name>TAMP3MF</name>
              <bitOffset>24</bitOffset>
              <bitWidth>1</bitWidth>
            </field>
          </fields>
        </register>
        <register>
          <name>ALRMASSR</name>
          <addressOffset>0x44</addressOffset>
          <size>0x20</size>
          <fields>
            <field>
              <name>SS</name>
              <bitOffset>0</bitOffset>
              <bitWidth>15</bitWidth>
            </field>
            <field>
              <name>MASKSS</name>
              <bitOffset>24</bitOffset>
              <bitWidth>4</bitWidth>
            </field>
          </fields>
        </register>
        <register>
          <name>ALRMBSSR</name>
          <addressOffset>0x48</addressOffset>
          <size>0x20</size>
          <fields>
            <field>
              <name>SS</name>
              <bitOffset>0</bitOffset>
              <bitWidth>15</bitWidth>
            </field>
            <field>
              <name>MASKSS</name>
              <bitOffset>24</bitOffset>
              <bitWidth>4</bitWidth>
            </field>
          </fields>
        </register>
        <register>
          <name>OR</name>
          <addressOffset>0x4c</addressOffset>
          <size>0x20</size>
          <fields>
            <field>
              <name>TSINSEL</name>
              <bitOffset>1</bitOffset>
              <bitWidth>2</bitWidth>
            </field>
            <field>
              <name>ALARMOUTTYPE</name>
              <bitOffset>3</bitOffset>
              <bitWidth>1</bitWidth>
            </field>
          </fields>
        </register>
        <register>
          <name>BKP0R</name>
          <addressOffset>0x50</addressOffset>
          <size>0x20</size>
        </register>
        <register>
          <name>BKP1R</name>
          <addressOffset>0x54</addressOffset>
          <size>0x20</size>
        </register>
        <register>
          <name>BKP2R</name>
          <addressOffset>0x58</addressOffset>
          <size>0x20</size>
        </register>
        <register>
          <name>BKP3R</name>
          <addressOffset>0x5c</addressOffset>
          <size>0x20</size>
        </register>
        <register>
          <name>BKP4R</name>
          <addressOffset>0x60</addressOffset>
          <size>0x20</size>
        </register>
        <register>
          <name>BKP5R</name>
          <addressOffset>0x64</addressOffset>
          <size>0x20</size>
        </register>
        <register>
          <name>BKP6R</name>
          <addressOffset>0x68</addressOffset>
          <size>0x20</size>
        </register>
        <register>
          <name>BKP7R</name>
          <addressOffset>0x6c</addressOffset>
          <size>0x20</size>
        </register>
        <register>
          <name>BKP8R</name>
          <addressOffset>0x70</addressOffset>
          <size>0x20</size>
        </register>
        <register>
          <name>BKP9R</name>
          <addressOffset>0x74</addressOffset>
          <size>0x20</size>
        </register>
        <register>
          <name>BKP10R</name>
          <addressOffset>0x78</addressOffset>
          <size>0x20</size>
        </register>
        <register>
          <name>BKP11R</name>
          <addressOffset>0x7c</addressOffset>
          <size>0x20</size>
        </register>
        <register>
          <name>BKP12R</name>
          <addressOffset>0x80</addressOffset>
          <size>0x20</size>
        </register>
        <register>
          <name>BKP13R</name>
          <addressOffset>0x84</addressOffset>
          <size>0x20</size>
        </register>
        <register>
          <name>BKP14R</name>
          <addressOffset>0x88</addressOffset>
          <size>0x20</size>
        </register>
        <register>
          <name>BKP15R</name>
          <addressOffset>0x8c</addressOffset>
          <size>0x20</size>
        </register>
        <register>
          <name>BKP16R</name>
          <addressOffset>0x90</addressOffset>
          <size>0x20</size>
        </register>
        <register>
          <name>BKP17R</name>
          <addressOffset>0x94</addressOffset>
          <size>0x20</size>
        </register>
        <register>
          <name>BKP18R</name>
          <addressOffset>0x98</addressOffset>
          <size>0x20</size>
        </register>
        <register>
          <name>BKP19R</name>
          <addressOffset>0x9c</addressOffset>
          <size>0x20</size>
        </register>
        <register>
          <name>BKP20R</name>
          <addressOffset>0xa0</addressOffset>
          <size>0x20</size>
        </register>
        <register>
          <name>BKP21R</name>
          <addressOffset>0xa4</addressOffset>
          <size>0x20</size>
        </register>
        <register>
          <name>BKP22R</name>
          <addressOffset>0xa8</addressOffset>
          <size>0x20</size>
        </register>
        <register>
          <name>BKP23R</name>
          <addressOffset>0xac</addressOffset>
          <size>0x20</size>
        </register>
        <register>
          <name>BKP24R</name>
          <addressOffset>0xb0</addressOffset>
          <size>0x20</size>
        </register>
        <register>
          <name>BKP25R</name>
          <addressOffset>0xb4</addressOffset>
          <size>0x20</size>
        </register>
        <register>
          <name>BKP26R</name>
          <addressOffset>0xb8</addressOffset>
          <size>0x20</size>
        </register>
        <register>
          <name>BKP27R</name>
          <addressOffset>0xbc</addressOffset>
          <size>0x20</size>
        </register>
        <register>
          <name>BKP28R</name>
          <addressOffset>0xc0</addressOffset>
          <size>0x20</size>
        </register>
        <register>
          <name>BKP29R</name>
          <addressOffset>0xc4</addressOffset>
          <size>0x20</size>
        </register>
        <register>
          <name>BKP30R</name>
          <addressOffset>0xc8</addressOffset>
          <size>0x20</size>
        </register>
        <register>
          <name>BKP31R</name>
          <addressOffset>0xcc</addressOffset>
          <size>0x20</size>
        </register>
      </registers>
    </peripheral>
    <peripheral>
      <name>WWDG</name>
      <baseAddress>0x40002c00</baseAddress>
      <registers>
        <register>
          <name>CR</name>
          <addressOffset>0x0</addressOffset>
          <size>0x20</size>
          <fields>
            <field>
              <name>T</name>
              <bitOffset>0</bitOffset>
              <bitWidth>7</bitWidth>
            </field>
            <field>
              <name>WDGA</name>
              <bitOffset>7</bitOffset>
              <bitWidth>1</bitWidth>
            </field>
          </fields>
        </register>
        <register>
          <name>CFR</name>
          <addressOffset>0x4</addressOffset>
          <size>0x20</size>
          <fields>
            <field>
              <name>W</name>
              <bitOffset>0</bitOffset>
              <bitWidth>7</bitWidth>
            </field>
            <field>
              <name>WDGTB</name>
              <bitOffset>7</bitOffset>
              <bitWidth>2</bitWidth>
            </field>
            <field>
              <name>EWI</name>
              <bitOffset>9</bitOffset>
              <bitWidth>1</bitWidth>
            </field>
          </fields>
        </register>
        <register>
          <name>SR</name>
          <addressOffset>0x8</addressOffset>
          <size>0x20</size>
          <fields>
            <field>
              <name>EWIF</name>
              <bitOffset>0</bitOffset>
              <bitWidth>1</bitWidth>
            </field>
          </fields>
        </register>
      </registers>
    </peripheral>
    <peripheral>
      <name>IWDG</name>
      <baseAddress>0x40003000</baseAddress>
      <registers>
        <register>
          <name>KR</name>
          <addressOffset>0x0</addressOffset>
          <size>0x20</size>
          <fields>
            <field>
              <name>KEY</name>
              <bitOffset>0</bitOffset>
              <bitWidth>16</bitWidth>
            </field>
          </fields>
        </register>
        <register>
          <name>PR</name>
          <addressOffset>0x4</addressOffset>
          <size>0x20</size>
          <fields>
            <field>
              <name>PR</name>
              <bitOffset>0</bitOffset>
              <bitWidth>3</bitWidth>
            </field>
          </fields>
        </register>
        <register>
          <name>RLR</name>
          <addressOffset>0x8</addressOffset>
          <size>0x20</size>
          <fields>
            <field>
              <name>RL</name>
              <bitOffset>0</bitOffset>
              <bitWidth>12</bitWidth>
            </field>
          </fields>
        </register>
        <register>
          <name>SR</name>
          <addressOffset>0xc</addressOffset>
          <size>0x20</size>
          <fields>
            <field>
              <name>PVU</name>
              <bitOffset>0</bitOffset>
              <bitWidth>1</bitWidth>
            </field>
            <field>
              <name>RVU</name>
              <bitOffset>1</bitOffset>
              <bitWidth>1</bitWidth>
            </field>
            <field>
              <name>WVU</name>
              <bitOffset>2</bitOffset>
              <bitWidth>1</bitWidth>
            </field>
          </fields>
        </register>
        <register>
          <name>WINR</name>
          <addressOffset>0x10</addressOffset>
          <size>0x20</size>
          <fields>
            <field>
              <name>WIN</name>
              <bitOffset>0</bitOffset>
              <bitWidth>12</bitWidth>
            </field>
          </fields>
        </register>
      </registers>
    </peripheral>
    <peripheral>
      <name>CAN3</name>
      <baseAddress>0x40003400</baseAddress>
      <registers>
        <register>
          <name>MCR</name>
          <addressOffset>0x0</addressOffset>
          <size>0x20</size>
          <fields>
            <field>
              <name>INRQ</name>
              <bitOffset>0</bitOffset>
              <bitWidth>1</bitWidth>
            </field>
            <field>
              <name>SLEEP</name>
              <bitOffset>1</bitOffset>
              <bitWidth>1</bitWidth>
            </field>
            <field>
              <name>TXFP</name>
              <bitOffset>2</bitOffset>
              <bitWidth>1</bitWidth>
            </field>
            <field>
              <name>RFLM</name>
              <bitOffset>3</bitOffset>
              <bitWidth>1</bitWidth>
            </field>
            <field>
              <name>NART</name>
              <bitOffset>4</bitOffset>
              <bitWidth>1</bitWidth>
            </field>
            <field>
              <name>AWUM</name>
              <bitOffset>5</bitOffset>
              <bitWidth>1</bitWidth>
            </field>
            <field>
              <name>ABOM</name>
              <bitOffset>6</bitOffset>
              <bitWidth>1</bitWidth>
            </field>
            <field>
              <name>TTCM</name>
              <bitOffset>7</bitOffset>
              <bitWidth>1</bitWidth>
            </field>
            <field>
              <name>RESET</name>
              <bitOffset>15</bitOffset>
              <bitWidth>1</bitWidth>
            </field>
          </fields>
        </register>
        <register>
          <name>MSR</name>
          <addressOffset>0x4</addressOffset>
          <size>0x20</size>
          <fields>
            <field>
              <name>INAK</name>
              <bitOffset>0</bitOffset>
              <bitWidth>1</bitWidth>
            </field>
            <field>
              <name>SLAK</name>
              <bitOffset>1</bitOffset>
              <bitWidth>1</bitWidth>
            </field>
            <field>
              <name>ERRI</name>
              <bitOffset>2</bitOffset>
              <bitWidth>1</bitWidth>
            </field>
            <field>
              <name>WKUI</name>
              <bitOffset>3</bitOffset>
              <bitWidth>1</bitWidth>
            </field>
            <field>
              <name>SLAKI</name>
              <bitOffset>4</bitOffset>
              <bitWidth>1</bitWidth>
            </field>
            <field>
              <name>TXM</name>
              <bitOffset>8</bitOffset>
              <bitWidth>1</bitWidth>
            </field>
            <field>
              <name>RXM</name>
              <bitOffset>9</bitOffset>
              <bitWidth>1</bitWidth>
            </field>
            <field>
              <name>SAMP</name>
              <bitOffset>10</bitOffset>
              <bitWidth>1</bitWidth>
            </field>
            <field>
              <name>RX</name>
              <bitOffset>11</bitOffset>
              <bitWidth>1</bitWidth>
            </field>
          </fields>
        </register>
        <register>
          <name>TSR</name>
          <addressOffset>0x8</addressOffset>
          <size>0x20</size>
          <fields>
            <field>
              <name>RQCP0</name>
              <bitOffset>0</bitOffset>
              <bitWidth>1</bitWidth>
            </field>
            <field>
              <name>TXOK0</name>
              <bitOffset>1</bitOffset>
              <bitWidth>1</bitWidth>
            </field>
            <field>
              <name>ALST0</name>
              <bitOffset>2</bitOffset>
              <bitWidth>1</bitWidth>
            </field>
            <field>
              <name>TERR0</name>
              <bitOffset>3</bitOffset>
              <bitWidth>1</bitWidth>
            </field>
            <field>
              <name>ABRQ0</name>
              <bitOffset>7</bitOffset>
              <bitWidth>1</bitWidth>
            </field>
            <field>
              <name>RQCP1</name>
              <bitOffset>8</bitOffset>
              <bitWidth>1</bitWidth>
            </field>
            <field>
              <name>TXOK1</name>
              <bitOffset>9</bitOffset>
              <bitWidth>1</bitWidth>
            </field>
            <field>
              <name>ALST1</name>
              <bitOffset>10</bitOffset>
              <bitWidth>1</bitWidth>
            </field>
            <field>
              <name>TERR1</name>
              <bitOffset>11</bitOffset>
              <bitWidth>1</bitWidth>
            </field>
            <field>
              <name>ABRQ1</name>
              <bitOffset>15</bitOffset>
              <bitWidth>1</bitWidth>
            </field>
            <field>
              <name>RQCP2</name>
              <bitOffset>16</bitOffset>
              <bitWidth>1</bitWidth>
            </field>
            <field>
              <name>TXOK2</name>
              <bitOffset>17</bitOffset>
              <bitWidth>1</bitWidth>
            </field>
            <field>
              <name>ALST2</name>
              <bitOffset>18</bitOffset>
              <bitWidth>1</bitWidth>
            </field>
            <field>
              <name>TERR2</name>
              <bitOffset>19</bitOffset>
              <bitWidth>1</bitWidth>
            </field>
            <field>
              <name>ABRQ2</name>
              <bitOffset>23</bitOffset>
              <bitWidth>1</bitWidth>
            </field>
            <field>
              <name>CODE</name>
              <bitOffset>24</bitOffset>
              <bitWidth>2</bitWidth>
            </field>
            <field>
              <name>TME0</name>
              <bitOffset>26</bitOffset>
              <bitWidth>1</bitWidth>
            </field>
            <field>
              <name>TME1</name>
              <bitOffset>27</bitOffset>
              <bitWidth>1</bitWidth>
            </field>
            <field>
              <name>TME2</name>
              <bitOffset>28</bitOffset>
              <bitWidth>1</bitWidth>
            </field>
            <field>
              <name>LOW0</name>
              <bitOffset>29</bitOffset>
              <bitWidth>1</bitWidth>
            </field>
            <field>
              <name>LOW1</name>
              <bitOffset>30</bitOffset>
              <bitWidth>1</bitWidth>
            </field>
            <field>
              <name>LOW2</name>
              <bitOffset>31</bitOffset>
              <bitWidth>1</bitWidth>
            </field>
          </fields>
        </register>
        <register>
          <name>RF0R</name>
          <addressOffset>0xc</addressOffset>
          <size>0x20</size>
          <fields>
            <field>
              <name>FMP0</name>
              <bitOffset>0</bitOffset>
              <bitWidth>2</bitWidth>
            </field>
            <field>
              <name>FULL0</name>
              <bitOffset>3</bitOffset>
              <bitWidth>1</bitWidth>
            </field>
            <field>
              <name>FOVR0</name>
              <bitOffset>4</bitOffset>
              <bitWidth>1</bitWidth>
            </field>
            <field>
              <name>RFOM0</name>
              <bitOffset>5</bitOffset>
              <bitWidth>1</bitWidth>
            </field>
          </fields>
        </register>
        <register>
          <name>RF1R</name>
          <addressOffset>0x10</addressOffset>
          <size>0x20</size>
          <fields>
            <field>
              <name>FMP1</name>
              <bitOffset>0</bitOffset>
              <bitWidth>2</bitWidth>
            </field>
            <field>
              <name>FULL1</name>
              <bitOffset>3</bitOffset>
              <bitWidth>1</bitWidth>
            </field>
            <field>
              <name>FOVR1</name>
              <bitOffset>4</bitOffset>
              <bitWidth>1</bitWidth>
            </field>
            <field>
              <name>RFOM1</name>
              <bitOffset>5</bitOffset>
              <bitWidth>1</bitWidth>
            </field>
          </fields>
        </register>
        <register>
          <name>IER</name>
          <addressOffset>0x14</addressOffset>
          <size>0x20</size>
          <fields>
            <field>
              <name>TMEIE</name>
              <bitOffset>0</bitOffset>
              <bitWidth>1</bitWidth>
            </field>
            <field>
              <name>FMPIE0</name>
              <bitOffset>1</bitOffset>
              <bitWidth>1</bitWidth>
            </field>
            <field>
              <name>FFIE0</name>
              <bitOffset>2</bitOffset>
              <bitWidth>1</bitWidth>
            </field>
            <field>
              <name>FOVIE0</name>
              <bitOffset>3</bitOffset>
              <bitWidth>1</bitWidth>
            </field>
            <field>
              <name>FMPIE1</name>
              <bitOffset>4</bitOffset>
              <bitWidth>1</bitWidth>
            </field>
            <field>
              <name>FFIE1</name>
              <bitOffset>5</bitOffset>
              <bitWidth>1</bitWidth>
            </field>
            <field>
              <name>FOVIE1</name>
              <bitOffset>6</bitOffset>
              <bitWidth>1</bitWidth>
            </field>
            <field>
              <name>EWGIE</name>
              <bitOffset>8</bitOffset>
              <bitWidth>1</bitWidth>
            </field>
            <field>
              <name>EPVIE</name>
              <bitOffset>9</bitOffset>
              <bitWidth>1</bitWidth>
            </field>
            <field>
              <name>BOFIE</name>
              <bitOffset>10</bitOffset>
              <bitWidth>1</bitWidth>
            </field>
            <field>
              <name>LECIE</name>
              <bitOffset>11</bitOffset>
              <bitWidth>1</bitWidth>
            </field>
            <field>
              <name>ERRIE</name>
              <bitOffset>15</bitOffset>
              <bitWidth>1</bitWidth>
            </field>
            <field>
              <name>WKUIE</name>
              <bitOffset>16</bitOffset>
              <bitWidth>1</bitWidth>
            </field>
            <field>
              <name>SLKIE</name>
              <bitOffset>17</bitOffset>
              <bitWidth>1</bitWidth>
            </field>
          </fields>
        </register>
        <register>
          <name>ESR</name>
          <addressOffset>0x18</addressOffset>
          <size>0x20</size>
          <fields>
            <field>
              <name>EWGF</name>
              <bitOffset>0</bitOffset>
              <bitWidth>1</bitWidth>
            </field>
            <field>
              <name>EPVF</name>
              <bitOffset>1</bitOffset>
              <bitWidth>1</bitWidth>
            </field>
            <field>
              <name>BOFF</name>
              <bitOffset>2</bitOffset>
              <bitWidth>1</bitWidth>
            </field>
            <field>
              <name>LEC</name>
              <bitOffset>4</bitOffset>
              <bitWidth>3</bitWidth>
            </field>
            <field>
              <name>TEC</name>
              <bitOffset>16</bitOffset>
              <bitWidth>8</bitWidth>
            </field>
            <field>
              <name>REC</name>
              <bitOffset>24</bitOffset>
              <bitWidth>8</bitWidth>
            </field>
          </fields>
        </register>
        <register>
          <name>BTR</name>
          <addressOffset>0x1c</addressOffset>
          <size>0x20</size>
          <fields>
            <field>
              <name>BRP</name>
              <bitOffset>0</bitOffset>
              <bitWidth>10</bitWidth>
            </field>
            <field>
              <name>TS1</name>
              <bitOffset>16</bitOffset>
              <bitWidth>4</bitWidth>
            </field>
            <field>
              <name>TS2</name>
              <bitOffset>20</bitOffset>
              <bitWidth>3</bitWidth>
            </field>
            <field>
              <name>SJW</name>
              <bitOffset>24</bitOffset>
              <bitWidth>2</bitWidth>
            </field>
            <field>
              <name>LBKM</name>
              <bitOffset>30</bitOffset>
              <bitWidth>1</bitWidth>
            </field>
            <field>
              <name>SILM</name>
              <bitOffset>31</bitOffset>
              <bitWidth>1</bitWidth>
            </field>
          </fields>
        </register>
        <register>
          <name>sTxMailBox.0.TIR</name>
          <addressOffset>0x180</addressOffset>
          <size>0x20</size>
          <fields>
            <field>
              <name>TXRQ</name>
              <bitOffset>0</bitOffset>
              <bitWidth>1</bitWidth>
            </field>
            <field>
              <name>RTR</name>
              <bitOffset>1</bitOffset>
              <bitWidth>1</bitWidth>
            </field>
            <field>
              <name>IDE</name>
              <bitOffset>2</bitOffset>
              <bitWidth>1</bitWidth>
            </field>
            <field>
              <name>EXID</name>
              <bitOffset>3</bitOffset>
              <bitWidth>18</bitWidth>
            </field>
            <field>
              <name>STID</name>
              <bitOffset>21</bitOffset>
              <bitWidth>11</bitWidth>
            </field>
          </fields>
        </register>
        <register>
          <name>sTxMailBox.0.TDTR</name>
          <addressOffset>0x184</addressOffset>
          <size>0x20</size>
          <fields>
            <field>
              <name>DLC</name>
              <bitOffset>0</bitOffset>
              <bitWidth>4</bitWidth>
            </field>
            <field>
              <name>TGT</name>
              <bitOffset>8</bitOffset>
              <bitWidth>1</bitWidth>
            </field>
            <field>
              <name>TIME</name>
              <bitOffset>16</bitOffset>
              <bitWidth>16</bitWidth>
            </field>
          </fields>
        </register>
        <register>
          <name>sTxMailBox.0.TDLR</name>
          <addressOffset>0x188</addressOffset>
          <size>0x20</size>
          <fields>
            <field>
              <name>DATA0</name>
              <bitOffset>0</bitOffset>
              <bitWidth>8</bitWidth>
            </field>
            <field>
              <name>DATA1</name>
              <bitOffset>8</bitOffset>
              <bitWidth>8</bitWidth>
            </field>
            <field>
              <name>DATA2</name>
              <bitOffset>16</bitOffset>
              <bitWidth>8</bitWidth>
            </field>
            <field>
              <name>DATA3</name>
              <bitOffset>24</bitOffset>
              <bitWidth>8</bitWidth>
            </field>
          </fields>
        </register>
        <register>
          <name>sTxMailBox.0.TDHR</name>
          <addressOffset>0x18c</addressOffset>
          <size>0x20</size>
          <fields>
            <field>
              <name>DATA4</name>
              <bitOffset>0</bitOffset>
              <bitWidth>8</bitWidth>
            </field>
            <field>
              <name>DATA5</name>
              <bitOffset>8</bitOffset>
              <bitWidth>8</bitWidth>
            </field>
            <field>
              <name>DATA6</name>
              <bitOffset>16</bitOffset>
              <bitWidth>8</bitWidth>
            </field>
            <field>
              <name>DATA7</name>
              <bitOffset>24</bitOffset>
              <bitWidth>8</bitWidth>
            </field>
          </fields>
        </register>
        <register>
          <name>sTxMailBox.1.TIR</name>
          <addressOffset>0x190</addressOffset>
          <size>0x20</size>
          <fields>
            <field>
              <name>TXRQ</name>
              <bitOffset>0</bitOffset>
              <bitWidth>1</bitWidth>
            </field>
            <field>
              <name>RTR</name>
              <bitOffset>1</bitOffset>
              <bitWidth>1</bitWidth>
            </field>
            <field>
              <name>IDE</name>
              <bitOffset>2</bitOffset>
              <bitWidth>1</bitWidth>
            </field>
            <field>
              <name>EXID</name>
              <bitOffset>3</bitOffset>
              <bitWidth>18</bitWidth>
            </field>
            <field>
              <name>STID</name>
              <bitOffset>21</bitOffset>
              <bitWidth>11</bitWidth>
            </field>
          </fields>
        </register>
        <register>
          <name>sTxMailBox.1.TDTR</name>
          <addressOffset>0x194</addressOffset>
          <size>0x20</size>
          <fields>
            <field>
              <name>DLC</name>
              <bitOffset>0</bitOffset>
              <bitWidth>4</bitWidth>
            </field>
            <field>
              <name>TGT</name>
              <bitOffset>8</bitOffset>
              <bitWidth>1</bitWidth>
            </field>
            <field>
              <name>TIME</name>
              <bitOffset>16</bitOffset>
              <bitWidth>16</bitWidth>
            </field>
          </fields>
        </register>
        <register>
          <name>sTxMailBox.1.TDLR</name>
          <addressOffset>0x198</addressOffset>
          <size>0x20</size>
          <fields>
            <field>
              <name>DATA0</name>
              <bitOffset>0</bitOffset>
              <bitWidth>8</bitWidth>
            </field>
            <field>
              <name>DATA1</name>
              <bitOffset>8</bitOffset>
              <bitWidth>8</bitWidth>
            </field>
            <field>
              <name>DATA2</name>
              <bitOffset>16</bitOffset>
              <bitWidth>8</bitWidth>
            </field>
            <field>
              <name>DATA3</name>
              <bitOffset>24</bitOffset>
              <bitWidth>8</bitWidth>
            </field>
          </fields>
        </register>
        <register>
          <name>sTxMailBox.1.TDHR</name>
          <addressOffset>0x19c</addressOffset>
          <size>0x20</size>
          <fields>
            <field>
              <name>DATA4</name>
              <bitOffset>0</bitOffset>
              <bitWidth>8</bitWidth>
            </field>
            <field>
              <name>DATA5</name>
              <bitOffset>8</bitOffset>
              <bitWidth>8</bitWidth>
            </field>
            <field>
              <name>DATA6</name>
              <bitOffset>16</bitOffset>
              <bitWidth>8</bitWidth>
            </field>
            <field>
              <name>DATA7</name>
              <bitOffset>24</bitOffset>
              <bitWidth>8</bitWidth>
            </field>
          </fields>
        </register>
        <register>
          <name>sTxMailBox.2.TIR</name>
          <addressOffset>0x1a0</addressOffset>
          <size>0x20</size>
          <fields>
            <field>
              <name>TXRQ</name>
              <bitOffset>0</bitOffset>
              <bitWidth>1</bitWidth>
            </field>
            <field>
              <name>RTR</name>
              <bitOffset>1</bitOffset>
              <bitWidth>1</bitWidth>
            </field>
            <field>
              <name>IDE</name>
              <bitOffset>2</bitOffset>
              <bitWidth>1</bitWidth>
            </field>
            <field>
              <name>EXID</name>
              <bitOffset>3</bitOffset>
              <bitWidth>18</bitWidth>
            </field>
            <field>
              <name>STID</name>
              <bitOffset>21</bitOffset>
              <bitWidth>11</bitWidth>
            </field>
          </fields>
        </register>
        <register>
          <name>sTxMailBox.2.TDTR</name>
          <addressOffset>0x1a4</addressOffset>
          <size>0x20</size>
          <fields>
            <field>
              <name>DLC</name>
              <bitOffset>0</bitOffset>
              <bitWidth>4</bitWidth>
            </field>
            <field>
              <name>TGT</name>
              <bitOffset>8</bitOffset>
              <bitWidth>1</bitWidth>
            </field>
            <field>
              <name>TIME</name>
              <bitOffset>16</bitOffset>
              <bitWidth>16</bitWidth>
            </field>
          </fields>
        </register>
        <register>
          <name>sTxMailBox.2.TDLR</name>
          <addressOffset>0x1a8</addressOffset>
          <size>0x20</size>
          <fields>
            <field>
              <name>DATA0</name>
              <bitOffset>0</bitOffset>
              <bitWidth>8</bitWidth>
            </field>
            <field>
              <name>DATA1</name>
              <bitOffset>8</bitOffset>
              <bitWidth>8</bitWidth>
            </field>
            <field>
              <name>DATA2</name>
              <bitOffset>16</bitOffset>
              <bitWidth>8</bitWidth>
            </field>
            <field>
              <name>DATA3</name>
              <bitOffset>24</bitOffset>
              <bitWidth>8</bitWidth>
            </field>
          </fields>
        </register>
        <register>
          <name>sTxMailBox.2.TDHR</name>
          <addressOffset>0x1ac</addressOffset>
          <size>0x20</size>
          <fields>
            <field>
              <name>DATA4</name>
              <bitOffset>0</bitOffset>
              <bitWidth>8</bitWidth>
            </field>
            <field>
              <name>DATA5</name>
              <bitOffset>8</bitOffset>
              <bitWidth>8</bitWidth>
            </field>
            <field>
              <name>DATA6</name>
              <bitOffset>16</bitOffset>
              <bitWidth>8</bitWidth>
            </field>
            <field>
              <name>DATA7</name>
              <bitOffset>24</bitOffset>
              <bitWidth>8</bitWidth>
            </field>
          </fields>
        </register>
        <register>
          <name>sFIFOMailBox.0.RIR</name>
          <addressOffset>0x1b0</addressOffset>
          <size>0x20</size>
          <fields>
            <field>
              <name>RTR</name>
              <bitOffset>1</bitOffset>
              <bitWidth>1</bitWidth>
            </field>
            <field>
              <name>IDE</name>
              <bitOffset>2</bitOffset>
              <bitWidth>1</bitWidth>
            </field>
            <field>
              <name>EXID</name>
              <bitOffset>3</bitOffset>
              <bitWidth>18</bitWidth>
            </field>
            <field>
              <name>STID</name>
              <bitOffset>21</bitOffset>
              <bitWidth>11</bitWidth>
            </field>
          </fields>
        </register>
        <register>
          <name>sFIFOMailBox.0.RDTR</name>
          <addressOffset>0x1b4</addressOffset>
          <size>0x20</size>
          <fields>
            <field>
              <name>DLC</name>
              <bitOffset>0</bitOffset>
              <bitWidth>4</bitWidth>
            </field>
            <field>
              <name>FMI</name>
              <bitOffset>8</bitOffset>
              <bitWidth>8</bitWidth>
            </field>
            <field>
              <name>TIME</name>
              <bitOffset>16</bitOffset>
              <bitWidth>16</bitWidth>
            </field>
          </fields>
        </register>
        <register>
          <name>sFIFOMailBox.0.RDLR</name>
          <addressOffset>0x1b8</addressOffset>
          <size>0x20</size>
          <fields>
            <field>
              <name>DATA0</name>
              <bitOffset>0</bitOffset>
              <bitWidth>8</bitWidth>
            </field>
            <field>
              <name>DATA1</name>
              <bitOffset>8</bitOffset>
              <bitWidth>8</bitWidth>
            </field>
            <field>
              <name>DATA2</name>
              <bitOffset>16</bitOffset>
              <bitWidth>8</bitWidth>
            </field>
            <field>
              <name>DATA3</name>
              <bitOffset>24</bitOffset>
              <bitWidth>8</bitWidth>
            </field>
          </fields>
        </register>
        <register>
          <name>sFIFOMailBox.0.RDHR</name>
          <addressOffset>0x1bc</addressOffset>
          <size>0x20</size>
          <fields>
            <field>
              <name>DATA4</name>
              <bitOffset>0</bitOffset>
              <bitWidth>8</bitWidth>
            </field>
            <field>
              <name>DATA5</name>
              <bitOffset>8</bitOffset>
              <bitWidth>8</bitWidth>
            </field>
            <field>
              <name>DATA6</name>
              <bitOffset>16</bitOffset>
              <bitWidth>8</bitWidth>
            </field>
            <field>
              <name>DATA7</name>
              <bitOffset>24</bitOffset>
              <bitWidth>8</bitWidth>
            </field>
          </fields>
        </register>
        <register>
          <name>sFIFOMailBox.1.RIR</name>
          <addressOffset>0x1c0</addressOffset>
          <size>0x20</size>
          <fields>
            <field>
              <name>RTR</name>
              <bitOffset>1</bitOffset>
              <bitWidth>1</bitWidth>
            </field>
            <field>
              <name>IDE</name>
              <bitOffset>2</bitOffset>
              <bitWidth>1</bitWidth>
            </field>
            <field>
              <name>EXID</name>
              <bitOffset>3</bitOffset>
              <bitWidth>18</bitWidth>
            </field>
            <field>
              <name>STID</name>
              <bitOffset>21</bitOffset>
              <bitWidth>11</bitWidth>
            </field>
          </fields>
        </register>
        <register>
          <name>sFIFOMailBox.1.RDTR</name>
          <addressOffset>0x1c4</addressOffset>
          <size>0x20</size>
          <fields>
            <field>
              <name>DLC</name>
              <bitOffset>0</bitOffset>
              <bitWidth>4</bitWidth>
            </field>
            <field>
              <name>FMI</name>
              <bitOffset>8</bitOffset>
              <bitWidth>8</bitWidth>
            </field>
            <field>
              <name>TIME</name>
              <bitOffset>16</bitOffset>
              <bitWidth>16</bitWidth>
            </field>
          </fields>
        </register>
        <register>
          <name>sFIFOMailBox.1.RDLR</name>
          <addressOffset>0x1c8</addressOffset>
          <size>0x20</size>
          <fields>
            <field>
              <name>DATA0</name>
              <bitOffset>0</bitOffset>
              <bitWidth>8</bitWidth>
            </field>
            <field>
              <name>DATA1</name>
              <bitOffset>8</bitOffset>
              <bitWidth>8</bitWidth>
            </field>
            <field>
              <name>DATA2</name>
              <bitOffset>16</bitOffset>
              <bitWidth>8</bitWidth>
            </field>
            <field>
              <name>DATA3</name>
              <bitOffset>24</bitOffset>
              <bitWidth>8</bitWidth>
            </field>
          </fields>
        </register>
        <register>
          <name>sFIFOMailBox.1.RDHR</name>
          <addressOffset>0x1cc</addressOffset>
          <size>0x20</size>
          <fields>
            <field>
              <name>DATA4</name>
              <bitOffset>0</bitOffset>
              <bitWidth>8</bitWidth>
            </field>
            <field>
              <name>DATA5</name>
              <bitOffset>8</bitOffset>
              <bitWidth>8</bitWidth>
            </field>
            <field>
              <name>DATA6</name>
              <bitOffset>16</bitOffset>
              <bitWidth>8</bitWidth>
            </field>
            <field>
              <name>DATA7</name>
              <bitOffset>24</bitOffset>
              <bitWidth>8</bitWidth>
            </field>
          </fields>
        </register>
        <register>
          <name>FMR</name>
          <addressOffset>0x200</addressOffset>
          <size>0x20</size>
          <fields>
            <field>
              <name>CAN2SB</name>
              <bitOffset>8</bitOffset>
              <bitWidth>6</bitWidth>
            </field>
          </fields>
        </register>
        <register>
          <name>FM1R</name>
          <addressOffset>0x204</addressOffset>
          <size>0x20</size>
          <fields>
            <field>
              <name>FBM0</name>
              <bitOffset>0</bitOffset>
              <bitWidth>1</bitWidth>
            </field>
            <field>
              <name>FBM1</name>
              <bitOffset>1</bitOffset>
              <bitWidth>1</bitWidth>
            </field>
            <field>
              <name>FBM2</name>
              <bitOffset>2</bitOffset>
              <bitWidth>1</bitWidth>
            </field>
            <field>
              <name>FBM3</name>
              <bitOffset>3</bitOffset>
              <bitWidth>1</bitWidth>
            </field>
            <field>
              <name>FBM4</name>
              <bitOffset>4</bitOffset>
              <bitWidth>1</bitWidth>
            </field>
            <field>
              <name>FBM5</name>
              <bitOffset>5</bitOffset>
              <bitWidth>1</bitWidth>
            </field>
            <field>
              <name>FBM6</name>
              <bitOffset>6</bitOffset>
              <bitWidth>1</bitWidth>
            </field>
            <field>
              <name>FBM7</name>
              <bitOffset>7</bitOffset>
              <bitWidth>1</bitWidth>
            </field>
            <field>
              <name>FBM8</name>
              <bitOffset>8</bitOffset>
              <bitWidth>1</bitWidth>
            </field>
            <field>
              <name>FBM9</name>
              <bitOffset>9</bitOffset>
              <bitWidth>1</bitWidth>
            </field>
            <field>
              <name>FBM10</name>
              <bitOffset>10</bitOffset>
              <bitWidth>1</bitWidth>
            </field>
            <field>
              <name>FBM11</name>
              <bitOffset>11</bitOffset>
              <bitWidth>1</bitWidth>
            </field>
            <field>
              <name>FBM12</name>
              <bitOffset>12</bitOffset>
              <bitWidth>1</bitWidth>
            </field>
            <field>
              <name>FBM13</name>
              <bitOffset>13</bitOffset>
              <bitWidth>1</bitWidth>
            </field>
          </fields>
        </register>
        <register>
          <name>FS1R</name>
          <addressOffset>0x20c</addressOffset>
          <size>0x20</size>
          <fields>
            <field>
              <name>FSC0</name>
              <bitOffset>0</bitOffset>
              <bitWidth>1</bitWidth>
            </field>
            <field>
              <name>FSC1</name>
              <bitOffset>1</bitOffset>
              <bitWidth>1</bitWidth>
            </field>
            <field>
              <name>FSC2</name>
              <bitOffset>2</bitOffset>
              <bitWidth>1</bitWidth>
            </field>
            <field>
              <name>FSC3</name>
              <bitOffset>3</bitOffset>
              <bitWidth>1</bitWidth>
            </field>
            <field>
              <name>FSC4</name>
              <bitOffset>4</bitOffset>
              <bitWidth>1</bitWidth>
            </field>
            <field>
              <name>FSC5</name>
              <bitOffset>5</bitOffset>
              <bitWidth>1</bitWidth>
            </field>
            <field>
              <name>FSC6</name>
              <bitOffset>6</bitOffset>
              <bitWidth>1</bitWidth>
            </field>
            <field>
              <name>FSC7</name>
              <bitOffset>7</bitOffset>
              <bitWidth>1</bitWidth>
            </field>
            <field>
              <name>FSC8</name>
              <bitOffset>8</bitOffset>
              <bitWidth>1</bitWidth>
            </field>
            <field>
              <name>FSC9</name>
              <bitOffset>9</bitOffset>
              <bitWidth>1</bitWidth>
            </field>
            <field>
              <name>FSC10</name>
              <bitOffset>10</bitOffset>
              <bitWidth>1</bitWidth>
            </field>
            <field>
              <name>FSC11</name>
              <bitOffset>11</bitOffset>
              <bitWidth>1</bitWidth>
            </field>
            <field>
              <name>FSC12</name>
              <bitOffset>12</bitOffset>
              <bitWidth>1</bitWidth>
            </field>
            <field>
              <name>FSC13</name>
              <bitOffset>13</bitOffset>
              <bitWidth>1</bitWidth>
            </field>
          </fields>
        </register>
        <register>
          <name>FFA1R</name>
          <addressOffset>0x214</addressOffset>
          <size>0x20</size>
          <fields>
            <field>
              <name>FFA0</name>
              <bitOffset>0</bitOffset>
              <bitWidth>1</bitWidth>
            </field>
            <field>
              <name>FFA1</name>
              <bitOffset>1</bitOffset>
              <bitWidth>1</bitWidth>
            </field>
            <field>
              <name>FFA2</name>
              <bitOffset>2</bitOffset>
              <bitWidth>1</bitWidth>
            </field>
            <field>
              <name>FFA3</name>
              <bitOffset>3</bitOffset>
              <bitWidth>1</bitWidth>
            </field>
            <field>
              <name>FFA4</name>
              <bitOffset>4</bitOffset>
              <bitWidth>1</bitWidth>
            </field>
            <field>
              <name>FFA5</name>
              <bitOffset>5</bitOffset>
              <bitWidth>1</bitWidth>
            </field>
            <field>
              <name>FFA6</name>
              <bitOffset>6</bitOffset>
              <bitWidth>1</bitWidth>
            </field>
            <field>
              <name>FFA7</name>
              <bitOffset>7</bitOffset>
              <bitWidth>1</bitWidth>
            </field>
            <field>
              <name>FFA8</name>
              <bitOffset>8</bitOffset>
              <bitWidth>1</bitWidth>
            </field>
            <field>
              <name>FFA9</name>
              <bitOffset>9</bitOffset>
              <bitWidth>1</bitWidth>
            </field>
            <field>
              <name>FFA10</name>
              <bitOffset>10</bitOffset>
              <bitWidth>1</bitWidth>
            </field>
            <field>
              <name>FFA11</name>
              <bitOffset>11</bitOffset>
              <bitWidth>1</bitWidth>
            </field>
            <field>
              <name>FFA12</name>
              <bitOffset>12</bitOffset>
              <bitWidth>1</bitWidth>
            </field>
            <field>
              <name>FFA13</name>
              <bitOffset>13</bitOffset>
              <bitWidth>1</bitWidth>
            </field>
          </fields>
        </register>
        <register>
          <name>FA1R</name>
          <addressOffset>0x21c</addressOffset>
          <size>0x20</size>
          <fields>
            <field>
              <name>FACT0</name>
              <bitOffset>0</bitOffset>
              <bitWidth>1</bitWidth>
            </field>
            <field>
              <name>FACT1</name>
              <bitOffset>1</bitOffset>
              <bitWidth>1</bitWidth>
            </field>
            <field>
              <name>FACT2</name>
              <bitOffset>2</bitOffset>
              <bitWidth>1</bitWidth>
            </field>
            <field>
              <name>FACT3</name>
              <bitOffset>3</bitOffset>
              <bitWidth>1</bitWidth>
            </field>
            <field>
              <name>FACT4</name>
              <bitOffset>4</bitOffset>
              <bitWidth>1</bitWidth>
            </field>
            <field>
              <name>FACT5</name>
              <bitOffset>5</bitOffset>
              <bitWidth>1</bitWidth>
            </field>
            <field>
              <name>FACT6</name>
              <bitOffset>6</bitOffset>
              <bitWidth>1</bitWidth>
            </field>
            <field>
              <name>FACT7</name>
              <bitOffset>7</bitOffset>
              <bitWidth>1</bitWidth>
            </field>
            <field>
              <name>FACT8</name>
              <bitOffset>8</bitOffset>
              <bitWidth>1</bitWidth>
            </field>
            <field>
              <name>FACT9</name>
              <bitOffset>9</bitOffset>
              <bitWidth>1</bitWidth>
            </field>
            <field>
              <name>FACT10</name>
              <bitOffset>10</bitOffset>
              <bitWidth>1</bitWidth>
            </field>
            <field>
              <name>FACT11</name>
              <bitOffset>11</bitOffset>
              <bitWidth>1</bitWidth>
            </field>
            <field>
              <name>FACT12</name>
              <bitOffset>12</bitOffset>
              <bitWidth>1</bitWidth>
            </field>
            <field>
              <name>FACT13</name>
              <bitOffset>13</bitOffset>
              <bitWidth>1</bitWidth>
            </field>
          </fields>
        </register>
        <register>
          <name>sFilterRegister.0.FR1</name>
          <addressOffset>0x240</addressOffset>
          <size>0x20</size>
          <fields>
            <field>
              <name>FB0</name>
              <bitOffset>0</bitOffset>
              <bitWidth>1</bitWidth>
            </field>
            <field>
              <name>FB1</name>
              <bitOffset>1</bitOffset>
              <bitWidth>1</bitWidth>
            </field>
            <field>
              <name>FB2</name>
              <bitOffset>2</bitOffset>
              <bitWidth>1</bitWidth>
            </field>
            <field>
              <name>FB3</name>
              <bitOffset>3</bitOffset>
              <bitWidth>1</bitWidth>
            </field>
            <field>
              <name>FB4</name>
              <bitOffset>4</bitOffset>
              <bitWidth>1</bitWidth>
            </field>
            <field>
              <name>FB5</name>
              <bitOffset>5</bitOffset>
              <bitWidth>1</bitWidth>
            </field>
            <field>
              <name>FB6</name>
              <bitOffset>6</bitOffset>
              <bitWidth>1</bitWidth>
            </field>
            <field>
              <name>FB7</name>
              <bitOffset>7</bitOffset>
              <bitWidth>1</bitWidth>
            </field>
            <field>
              <name>FB8</name>
              <bitOffset>8</bitOffset>
              <bitWidth>1</bitWidth>
            </field>
            <field>
              <name>FB9</name>
              <bitOffset>9</bitOffset>
              <bitWidth>1</bitWidth>
            </field>
            <field>
              <name>FB10</name>
              <bitOffset>10</bitOffset>
              <bitWidth>1</bitWidth>
            </field>
            <field>
              <name>FB11</name>
              <bitOffset>11</bitOffset>
              <bitWidth>1</bitWidth>
            </field>
            <field>
              <name>FB12</name>
              <bitOffset>12</bitOffset>
              <bitWidth>1</bitWidth>
            </field>
            <field>
              <name>FB13</name>
              <bitOffset>13</bitOffset>
              <bitWidth>1</bitWidth>
            </field>
            <field>
              <name>FB14</name>
              <bitOffset>14</bitOffset>
              <bitWidth>1</bitWidth>
            </field>
            <field>
              <name>FB15</name>
              <bitOffset>15</bitOffset>
              <bitWidth>1</bitWidth>
            </field>
            <field>
              <name>FB16</name>
              <bitOffset>16</bitOffset>
              <bitWidth>1</bitWidth>
            </field>
            <field>
              <name>FB17</name>
              <bitOffset>17</bitOffset>
              <bitWidth>1</bitWidth>
            </field>
            <field>
              <name>FB18</name>
              <bitOffset>18</bitOffset>
              <bitWidth>1</bitWidth>
            </field>
            <field>
              <name>FB19</name>
              <bitOffset>19</bitOffset>
              <bitWidth>1</bitWidth>
            </field>
            <field>
              <name>FB20</name>
              <bitOffset>20</bitOffset>
              <bitWidth>1</bitWidth>
            </field>
            <field>
              <name>FB21</name>
              <bitOffset>21</bitOffset>
              <bitWidth>1</bitWidth>
            </field>
            <field>
              <name>FB22</name>
              <bitOffset>22</bitOffset>
              <bitWidth>1</bitWidth>
            </field>
            <field>
              <name>FB23</name>
              <bitOffset>23</bitOffset>
              <bitWidth>1</bitWidth>
            </field>
            <field>
              <name>FB24</name>
              <bitOffset>24</bitOffset>
              <bitWidth>1</bitWidth>
            </field>
            <field>
              <name>FB25</name>
              <bitOffset>25</bitOffset>
              <bitWidth>1</bitWidth>
            </field>
            <field>
              <name>FB26</name>
              <bitOffset>26</bitOffset>
              <bitWidth>1</bitWidth>
            </field>
            <field>
              <name>FB27</name>
              <bitOffset>27</bitOffset>
              <bitWidth>1</bitWidth>
            </field>
            <field>
              <name>FB28</name>
              <bitOffset>28</bitOffset>
              <bitWidth>1</bitWidth>
            </field>
            <field>
              <name>FB29</name>
              <bitOffset>29</bitOffset>
              <bitWidth>1</bitWidth>
            </field>
            <field>
              <name>FB30</name>
              <bitOffset>30</bitOffset>
              <bitWidth>1</bitWidth>
            </field>
            <field>
              <name>FB31</name>
              <bitOffset>31</bitOffset>
              <bitWidth>1</bitWidth>
            </field>
          </fields>
        </register>
        <register>
          <name>sFilterRegister.0.FR2</name>
          <addressOffset>0x244</addressOffset>
          <size>0x20</size>
          <fields>
            <field>
              <name>FB0</name>
              <bitOffset>0</bitOffset>
              <bitWidth>1</bitWidth>
            </field>
            <field>
              <name>FB1</name>
              <bitOffset>1</bitOffset>
              <bitWidth>1</bitWidth>
            </field>
            <field>
              <name>FB2</name>
              <bitOffset>2</bitOffset>
              <bitWidth>1</bitWidth>
            </field>
            <field>
              <name>FB3</name>
              <bitOffset>3</bitOffset>
              <bitWidth>1</bitWidth>
            </field>
            <field>
              <name>FB4</name>
              <bitOffset>4</bitOffset>
              <bitWidth>1</bitWidth>
            </field>
            <field>
              <name>FB5</name>
              <bitOffset>5</bitOffset>
              <bitWidth>1</bitWidth>
            </field>
            <field>
              <name>FB6</name>
              <bitOffset>6</bitOffset>
              <bitWidth>1</bitWidth>
            </field>
            <field>
              <name>FB7</name>
              <bitOffset>7</bitOffset>
              <bitWidth>1</bitWidth>
            </field>
            <field>
              <name>FB8</name>
              <bitOffset>8</bitOffset>
              <bitWidth>1</bitWidth>
            </field>
            <field>
              <name>FB9</name>
              <bitOffset>9</bitOffset>
              <bitWidth>1</bitWidth>
            </field>
            <field>
              <name>FB10</name>
              <bitOffset>10</bitOffset>
              <bitWidth>1</bitWidth>
            </field>
            <field>
              <name>FB11</name>
              <bitOffset>11</bitOffset>
              <bitWidth>1</bitWidth>
            </field>
            <field>
              <name>FB12</name>
              <bitOffset>12</bitOffset>
              <bitWidth>1</bitWidth>
            </field>
            <field>
              <name>FB13</name>
              <bitOffset>13</bitOffset>
              <bitWidth>1</bitWidth>
            </field>
            <field>
              <name>FB14</name>
              <bitOffset>14</bitOffset>
              <bitWidth>1</bitWidth>
            </field>
            <field>
              <name>FB15</name>
              <bitOffset>15</bitOffset>
              <bitWidth>1</bitWidth>
            </field>
            <field>
              <name>FB16</name>
              <bitOffset>16</bitOffset>
              <bitWidth>1</bitWidth>
            </field>
            <field>
              <name>FB17</name>
              <bitOffset>17</bitOffset>
              <bitWidth>1</bitWidth>
            </field>
            <field>
              <name>FB18</name>
              <bitOffset>18</bitOffset>
              <bitWidth>1</bitWidth>
            </field>
            <field>
              <name>FB19</name>
              <bitOffset>19</bitOffset>
              <bitWidth>1</bitWidth>
            </field>
            <field>
              <name>FB20</name>
              <bitOffset>20</bitOffset>
              <bitWidth>1</bitWidth>
            </field>
            <field>
              <name>FB21</name>
              <bitOffset>21</bitOffset>
              <bitWidth>1</bitWidth>
            </field>
            <field>
              <name>FB22</name>
              <bitOffset>22</bitOffset>
              <bitWidth>1</bitWidth>
            </field>
            <field>
              <name>FB23</name>
              <bitOffset>23</bitOffset>
              <bitWidth>1</bitWidth>
            </field>
            <field>
              <name>FB24</name>
              <bitOffset>24</bitOffset>
              <bitWidth>1</bitWidth>
            </field>
            <field>
              <name>FB25</name>
              <bitOffset>25</bitOffset>
              <bitWidth>1</bitWidth>
            </field>
            <field>
              <name>FB26</name>
              <bitOffset>26</bitOffset>
              <bitWidth>1</bitWidth>
            </field>
            <field>
              <name>FB27</name>
              <bitOffset>27</bitOffset>
              <bitWidth>1</bitWidth>
            </field>
            <field>
              <name>FB28</name>
              <bitOffset>28</bitOffset>
              <bitWidth>1</bitWidth>
            </field>
            <field>
              <name>FB29</name>
              <bitOffset>29</bitOffset>
              <bitWidth>1</bitWidth>
            </field>
            <field>
              <name>FB30</name>
              <bitOffset>30</bitOffset>
              <bitWidth>1</bitWidth>
            </field>
            <field>
              <name>FB31</name>
              <bitOffset>31</bitOffset>
              <bitWidth>1</bitWidth>
            </field>
          </fields>
        </register>
        <register>
          <name>sFilterRegister.1.FR1</name>
          <addressOffset>0x248</addressOffset>
          <size>0x20</size>
          <fields>
            <field>
              <name>FB0</name>
              <bitOffset>0</bitOffset>
              <bitWidth>1</bitWidth>
            </field>
            <field>
              <name>FB1</name>
              <bitOffset>1</bitOffset>
              <bitWidth>1</bitWidth>
            </field>
            <field>
              <name>FB2</name>
              <bitOffset>2</bitOffset>
              <bitWidth>1</bitWidth>
            </field>
            <field>
              <name>FB3</name>
              <bitOffset>3</bitOffset>
              <bitWidth>1</bitWidth>
            </field>
            <field>
              <name>FB4</name>
              <bitOffset>4</bitOffset>
              <bitWidth>1</bitWidth>
            </field>
            <field>
              <name>FB5</name>
              <bitOffset>5</bitOffset>
              <bitWidth>1</bitWidth>
            </field>
            <field>
              <name>FB6</name>
              <bitOffset>6</bitOffset>
              <bitWidth>1</bitWidth>
            </field>
            <field>
              <name>FB7</name>
              <bitOffset>7</bitOffset>
              <bitWidth>1</bitWidth>
            </field>
            <field>
              <name>FB8</name>
              <bitOffset>8</bitOffset>
              <bitWidth>1</bitWidth>
            </field>
            <field>
              <name>FB9</name>
              <bitOffset>9</bitOffset>
              <bitWidth>1</bitWidth>
            </field>
            <field>
              <name>FB10</name>
              <bitOffset>10</bitOffset>
              <bitWidth>1</bitWidth>
            </field>
            <field>
              <name>FB11</name>
              <bitOffset>11</bitOffset>
              <bitWidth>1</bitWidth>
            </field>
            <field>
              <name>FB12</name>
              <bitOffset>12</bitOffset>
              <bitWidth>1</bitWidth>
            </field>
            <field>
              <name>FB13</name>
              <bitOffset>13</bitOffset>
              <bitWidth>1</bitWidth>
            </field>
            <field>
              <name>FB14</name>
              <bitOffset>14</bitOffset>
              <bitWidth>1</bitWidth>
            </field>
            <field>
              <name>FB15</name>
              <bitOffset>15</bitOffset>
              <bitWidth>1</bitWidth>
            </field>
            <field>
              <name>FB16</name>
              <bitOffset>16</bitOffset>
              <bitWidth>1</bitWidth>
            </field>
            <field>
              <name>FB17</name>
              <bitOffset>17</bitOffset>
              <bitWidth>1</bitWidth>
            </field>
            <field>
              <name>FB18</name>
              <bitOffset>18</bitOffset>
              <bitWidth>1</bitWidth>
            </field>
            <field>
              <name>FB19</name>
              <bitOffset>19</bitOffset>
              <bitWidth>1</bitWidth>
            </field>
            <field>
              <name>FB20</name>
              <bitOffset>20</bitOffset>
              <bitWidth>1</bitWidth>
            </field>
            <field>
              <name>FB21</name>
              <bitOffset>21</bitOffset>
              <bitWidth>1</bitWidth>
            </field>
            <field>
              <name>FB22</name>
              <bitOffset>22</bitOffset>
              <bitWidth>1</bitWidth>
            </field>
            <field>
              <name>FB23</name>
              <bitOffset>23</bitOffset>
              <bitWidth>1</bitWidth>
            </field>
            <field>
              <name>FB24</name>
              <bitOffset>24</bitOffset>
              <bitWidth>1</bitWidth>
            </field>
            <field>
              <name>FB25</name>
              <bitOffset>25</bitOffset>
              <bitWidth>1</bitWidth>
            </field>
            <field>
              <name>FB26</name>
              <bitOffset>26</bitOffset>
              <bitWidth>1</bitWidth>
            </field>
            <field>
              <name>FB27</name>
              <bitOffset>27</bitOffset>
              <bitWidth>1</bitWidth>
            </field>
            <field>
              <name>FB28</name>
              <bitOffset>28</bitOffset>
              <bitWidth>1</bitWidth>
            </field>
            <field>
              <name>FB29</name>
              <bitOffset>29</bitOffset>
              <bitWidth>1</bitWidth>
            </field>
            <field>
              <name>FB30</name>
              <bitOffset>30</bitOffset>
              <bitWidth>1</bitWidth>
            </field>
            <field>
              <name>FB31</name>
              <bitOffset>31</bitOffset>
              <bitWidth>1</bitWidth>
            </field>
          </fields>
        </register>
        <register>
          <name>sFilterRegister.1.FR2</name>
          <addressOffset>0x24c</addressOffset>
          <size>0x20</size>
          <fields>
            <field>
              <name>FB0</name>
              <bitOffset>0</bitOffset>
              <bitWidth>1</bitWidth>
            </field>
            <field>
              <name>FB1</name>
              <bitOffset>1</bitOffset>
              <bitWidth>1</bitWidth>
            </field>
            <field>
              <name>FB2</name>
              <bitOffset>2</bitOffset>
              <bitWidth>1</bitWidth>
            </field>
            <field>
              <name>FB3</name>
              <bitOffset>3</bitOffset>
              <bitWidth>1</bitWidth>
            </field>
            <field>
              <name>FB4</name>
              <bitOffset>4</bitOffset>
              <bitWidth>1</bitWidth>
            </field>
            <field>
              <name>FB5</name>
              <bitOffset>5</bitOffset>
              <bitWidth>1</bitWidth>
            </field>
            <field>
              <name>FB6</name>
              <bitOffset>6</bitOffset>
              <bitWidth>1</bitWidth>
            </field>
            <field>
              <name>FB7</name>
              <bitOffset>7</bitOffset>
              <bitWidth>1</bitWidth>
            </field>
            <field>
              <name>FB8</name>
              <bitOffset>8</bitOffset>
              <bitWidth>1</bitWidth>
            </field>
            <field>
              <name>FB9</name>
              <bitOffset>9</bitOffset>
              <bitWidth>1</bitWidth>
            </field>
            <field>
              <name>FB10</name>
              <bitOffset>10</bitOffset>
              <bitWidth>1</bitWidth>
            </field>
            <field>
              <name>FB11</name>
              <bitOffset>11</bitOffset>
              <bitWidth>1</bitWidth>
            </field>
            <field>
              <name>FB12</name>
              <bitOffset>12</bitOffset>
              <bitWidth>1</bitWidth>
            </field>
            <field>
              <name>FB13</name>
              <bitOffset>13</bitOffset>
              <bitWidth>1</bitWidth>
            </field>
            <field>
              <name>FB14</name>
              <bitOffset>14</bitOffset>
              <bitWidth>1</bitWidth>
            </field>
            <field>
              <name>FB15</name>
              <bitOffset>15</bitOffset>
              <bitWidth>1</bitWidth>
            </field>
            <field>
              <name>FB16</name>
              <bitOffset>16</bitOffset>
              <bitWidth>1</bitWidth>
            </field>
            <field>
              <name>FB17</name>
              <bitOffset>17</bitOffset>
              <bitWidth>1</bitWidth>
            </field>
            <field>
              <name>FB18</name>
              <bitOffset>18</bitOffset>
              <bitWidth>1</bitWidth>
            </field>
            <field>
              <name>FB19</name>
              <bitOffset>19</bitOffset>
              <bitWidth>1</bitWidth>
            </field>
            <field>
              <name>FB20</name>
              <bitOffset>20</bitOffset>
              <bitWidth>1</bitWidth>
            </field>
            <field>
              <name>FB21</name>
              <bitOffset>21</bitOffset>
              <bitWidth>1</bitWidth>
            </field>
            <field>
              <name>FB22</name>
              <bitOffset>22</bitOffset>
              <bitWidth>1</bitWidth>
            </field>
            <field>
              <name>FB23</name>
              <bitOffset>23</bitOffset>
              <bitWidth>1</bitWidth>
            </field>
            <field>
              <name>FB24</name>
              <bitOffset>24</bitOffset>
              <bitWidth>1</bitWidth>
            </field>
            <field>
              <name>FB25</name>
              <bitOffset>25</bitOffset>
              <bitWidth>1</bitWidth>
            </field>
            <field>
              <name>FB26</name>
              <bitOffset>26</bitOffset>
              <bitWidth>1</bitWidth>
            </field>
            <field>
              <name>FB27</name>
              <bitOffset>27</bitOffset>
              <bitWidth>1</bitWidth>
            </field>
            <field>
              <name>FB28</name>
              <bitOffset>28</bitOffset>
              <bitWidth>1</bitWidth>
            </field>
            <field>
              <name>FB29</name>
              <bitOffset>29</bitOffset>
              <bitWidth>1</bitWidth>
            </field>
            <field>
              <name>FB30</name>
              <bitOffset>30</bitOffset>
              <bitWidth>1</bitWidth>
            </field>
            <field>
              <name>FB31</name>
              <bitOffset>31</bitOffset>
              <bitWidth>1</bitWidth>
            </field>
          </fields>
        </register>
        <register>
          <name>sFilterRegister.2.FR1</name>
          <addressOffset>0x250</addressOffset>
          <size>0x20</size>
          <fields>
            <field>
              <name>FB0</name>
              <bitOffset>0</bitOffset>
              <bitWidth>1</bitWidth>
            </field>
            <field>
              <name>FB1</name>
              <bitOffset>1</bitOffset>
              <bitWidth>1</bitWidth>
            </field>
            <field>
              <name>FB2</name>
              <bitOffset>2</bitOffset>
              <bitWidth>1</bitWidth>
            </field>
            <field>
              <name>FB3</name>
              <bitOffset>3</bitOffset>
              <bitWidth>1</bitWidth>
            </field>
            <field>
              <name>FB4</name>
              <bitOffset>4</bitOffset>
              <bitWidth>1</bitWidth>
            </field>
            <field>
              <name>FB5</name>
              <bitOffset>5</bitOffset>
              <bitWidth>1</bitWidth>
            </field>
            <field>
              <name>FB6</name>
              <bitOffset>6</bitOffset>
              <bitWidth>1</bitWidth>
            </field>
            <field>
              <name>FB7</name>
              <bitOffset>7</bitOffset>
              <bitWidth>1</bitWidth>
            </field>
            <field>
              <name>FB8</name>
              <bitOffset>8</bitOffset>
              <bitWidth>1</bitWidth>
            </field>
            <field>
              <name>FB9</name>
              <bitOffset>9</bitOffset>
              <bitWidth>1</bitWidth>
            </field>
            <field>
              <name>FB10</name>
              <bitOffset>10</bitOffset>
              <bitWidth>1</bitWidth>
            </field>
            <field>
              <name>FB11</name>
              <bitOffset>11</bitOffset>
              <bitWidth>1</bitWidth>
            </field>
            <field>
              <name>FB12</name>
              <bitOffset>12</bitOffset>
              <bitWidth>1</bitWidth>
            </field>
            <field>
              <name>FB13</name>
              <bitOffset>13</bitOffset>
              <bitWidth>1</bitWidth>
            </field>
            <field>
              <name>FB14</name>
              <bitOffset>14</bitOffset>
              <bitWidth>1</bitWidth>
            </field>
            <field>
              <name>FB15</name>
              <bitOffset>15</bitOffset>
              <bitWidth>1</bitWidth>
            </field>
            <field>
              <name>FB16</name>
              <bitOffset>16</bitOffset>
              <bitWidth>1</bitWidth>
            </field>
            <field>
              <name>FB17</name>
              <bitOffset>17</bitOffset>
              <bitWidth>1</bitWidth>
            </field>
            <field>
              <name>FB18</name>
              <bitOffset>18</bitOffset>
              <bitWidth>1</bitWidth>
            </field>
            <field>
              <name>FB19</name>
              <bitOffset>19</bitOffset>
              <bitWidth>1</bitWidth>
            </field>
            <field>
              <name>FB20</name>
              <bitOffset>20</bitOffset>
              <bitWidth>1</bitWidth>
            </field>
            <field>
              <name>FB21</name>
              <bitOffset>21</bitOffset>
              <bitWidth>1</bitWidth>
            </field>
            <field>
              <name>FB22</name>
              <bitOffset>22</bitOffset>
              <bitWidth>1</bitWidth>
            </field>
            <field>
              <name>FB23</name>
              <bitOffset>23</bitOffset>
              <bitWidth>1</bitWidth>
            </field>
            <field>
              <name>FB24</name>
              <bitOffset>24</bitOffset>
              <bitWidth>1</bitWidth>
            </field>
            <field>
              <name>FB25</name>
              <bitOffset>25</bitOffset>
              <bitWidth>1</bitWidth>
            </field>
            <field>
              <name>FB26</name>
              <bitOffset>26</bitOffset>
              <bitWidth>1</bitWidth>
            </field>
            <field>
              <name>FB27</name>
              <bitOffset>27</bitOffset>
              <bitWidth>1</bitWidth>
            </field>
            <field>
              <name>FB28</name>
              <bitOffset>28</bitOffset>
              <bitWidth>1</bitWidth>
            </field>
            <field>
              <name>FB29</name>
              <bitOffset>29</bitOffset>
              <bitWidth>1</bitWidth>
            </field>
            <field>
              <name>FB30</name>
              <bitOffset>30</bitOffset>
              <bitWidth>1</bitWidth>
            </field>
            <field>
              <name>FB31</name>
              <bitOffset>31</bitOffset>
              <bitWidth>1</bitWidth>
            </field>
          </fields>
        </register>
        <register>
          <name>sFilterRegister.2.FR2</name>
          <addressOffset>0x254</addressOffset>
          <size>0x20</size>
          <fields>
            <field>
              <name>FB0</name>
              <bitOffset>0</bitOffset>
              <bitWidth>1</bitWidth>
            </field>
            <field>
              <name>FB1</name>
              <bitOffset>1</bitOffset>
              <bitWidth>1</bitWidth>
            </field>
            <field>
              <name>FB2</name>
              <bitOffset>2</bitOffset>
              <bitWidth>1</bitWidth>
            </field>
            <field>
              <name>FB3</name>
              <bitOffset>3</bitOffset>
              <bitWidth>1</bitWidth>
            </field>
            <field>
              <name>FB4</name>
              <bitOffset>4</bitOffset>
              <bitWidth>1</bitWidth>
            </field>
            <field>
              <name>FB5</name>
              <bitOffset>5</bitOffset>
              <bitWidth>1</bitWidth>
            </field>
            <field>
              <name>FB6</name>
              <bitOffset>6</bitOffset>
              <bitWidth>1</bitWidth>
            </field>
            <field>
              <name>FB7</name>
              <bitOffset>7</bitOffset>
              <bitWidth>1</bitWidth>
            </field>
            <field>
              <name>FB8</name>
              <bitOffset>8</bitOffset>
              <bitWidth>1</bitWidth>
            </field>
            <field>
              <name>FB9</name>
              <bitOffset>9</bitOffset>
              <bitWidth>1</bitWidth>
            </field>
            <field>
              <name>FB10</name>
              <bitOffset>10</bitOffset>
              <bitWidth>1</bitWidth>
            </field>
            <field>
              <name>FB11</name>
              <bitOffset>11</bitOffset>
              <bitWidth>1</bitWidth>
            </field>
            <field>
              <name>FB12</name>
              <bitOffset>12</bitOffset>
              <bitWidth>1</bitWidth>
            </field>
            <field>
              <name>FB13</name>
              <bitOffset>13</bitOffset>
              <bitWidth>1</bitWidth>
            </field>
            <field>
              <name>FB14</name>
              <bitOffset>14</bitOffset>
              <bitWidth>1</bitWidth>
            </field>
            <field>
              <name>FB15</name>
              <bitOffset>15</bitOffset>
              <bitWidth>1</bitWidth>
            </field>
            <field>
              <name>FB16</name>
              <bitOffset>16</bitOffset>
              <bitWidth>1</bitWidth>
            </field>
            <field>
              <name>FB17</name>
              <bitOffset>17</bitOffset>
              <bitWidth>1</bitWidth>
            </field>
            <field>
              <name>FB18</name>
              <bitOffset>18</bitOffset>
              <bitWidth>1</bitWidth>
            </field>
            <field>
              <name>FB19</name>
              <bitOffset>19</bitOffset>
              <bitWidth>1</bitWidth>
            </field>
            <field>
              <name>FB20</name>
              <bitOffset>20</bitOffset>
              <bitWidth>1</bitWidth>
            </field>
            <field>
              <name>FB21</name>
              <bitOffset>21</bitOffset>
              <bitWidth>1</bitWidth>
            </field>
            <field>
              <name>FB22</name>
              <bitOffset>22</bitOffset>
              <bitWidth>1</bitWidth>
            </field>
            <field>
              <name>FB23</name>
              <bitOffset>23</bitOffset>
              <bitWidth>1</bitWidth>
            </field>
            <field>
              <name>FB24</name>
              <bitOffset>24</bitOffset>
              <bitWidth>1</bitWidth>
            </field>
            <field>
              <name>FB25</name>
              <bitOffset>25</bitOffset>
              <bitWidth>1</bitWidth>
            </field>
            <field>
              <name>FB26</name>
              <bitOffset>26</bitOffset>
              <bitWidth>1</bitWidth>
            </field>
            <field>
              <name>FB27</name>
              <bitOffset>27</bitOffset>
              <bitWidth>1</bitWidth>
            </field>
            <field>
              <name>FB28</name>
              <bitOffset>28</bitOffset>
              <bitWidth>1</bitWidth>
            </field>
            <field>
              <name>FB29</name>
              <bitOffset>29</bitOffset>
              <bitWidth>1</bitWidth>
            </field>
            <field>
              <name>FB30</name>
              <bitOffset>30</bitOffset>
              <bitWidth>1</bitWidth>
            </field>
            <field>
              <name>FB31</name>
              <bitOffset>31</bitOffset>
              <bitWidth>1</bitWidth>
            </field>
          </fields>
        </register>
        <register>
          <name>sFilterRegister.3.FR1</name>
          <addressOffset>0x258</addressOffset>
          <size>0x20</size>
          <fields>
            <field>
              <name>FB0</name>
              <bitOffset>0</bitOffset>
              <bitWidth>1</bitWidth>
            </field>
            <field>
              <name>FB1</name>
              <bitOffset>1</bitOffset>
              <bitWidth>1</bitWidth>
            </field>
            <field>
              <name>FB2</name>
              <bitOffset>2</bitOffset>
              <bitWidth>1</bitWidth>
            </field>
            <field>
              <name>FB3</name>
              <bitOffset>3</bitOffset>
              <bitWidth>1</bitWidth>
            </field>
            <field>
              <name>FB4</name>
              <bitOffset>4</bitOffset>
              <bitWidth>1</bitWidth>
            </field>
            <field>
              <name>FB5</name>
              <bitOffset>5</bitOffset>
              <bitWidth>1</bitWidth>
            </field>
            <field>
              <name>FB6</name>
              <bitOffset>6</bitOffset>
              <bitWidth>1</bitWidth>
            </field>
            <field>
              <name>FB7</name>
              <bitOffset>7</bitOffset>
              <bitWidth>1</bitWidth>
            </field>
            <field>
              <name>FB8</name>
              <bitOffset>8</bitOffset>
              <bitWidth>1</bitWidth>
            </field>
            <field>
              <name>FB9</name>
              <bitOffset>9</bitOffset>
              <bitWidth>1</bitWidth>
            </field>
            <field>
              <name>FB10</name>
              <bitOffset>10</bitOffset>
              <bitWidth>1</bitWidth>
            </field>
            <field>
              <name>FB11</name>
              <bitOffset>11</bitOffset>
              <bitWidth>1</bitWidth>
            </field>
            <field>
              <name>FB12</name>
              <bitOffset>12</bitOffset>
              <bitWidth>1</bitWidth>
            </field>
            <field>
              <name>FB13</name>
              <bitOffset>13</bitOffset>
              <bitWidth>1</bitWidth>
            </field>
            <field>
              <name>FB14</name>
              <bitOffset>14</bitOffset>
              <bitWidth>1</bitWidth>
            </field>
            <field>
              <name>FB15</name>
              <bitOffset>15</bitOffset>
              <bitWidth>1</bitWidth>
            </field>
            <field>
              <name>FB16</name>
              <bitOffset>16</bitOffset>
              <bitWidth>1</bitWidth>
            </field>
            <field>
              <name>FB17</name>
              <bitOffset>17</bitOffset>
              <bitWidth>1</bitWidth>
            </field>
            <field>
              <name>FB18</name>
              <bitOffset>18</bitOffset>
              <bitWidth>1</bitWidth>
            </field>
            <field>
              <name>FB19</name>
              <bitOffset>19</bitOffset>
              <bitWidth>1</bitWidth>
            </field>
            <field>
              <name>FB20</name>
              <bitOffset>20</bitOffset>
              <bitWidth>1</bitWidth>
            </field>
            <field>
              <name>FB21</name>
              <bitOffset>21</bitOffset>
              <bitWidth>1</bitWidth>
            </field>
            <field>
              <name>FB22</name>
              <bitOffset>22</bitOffset>
              <bitWidth>1</bitWidth>
            </field>
            <field>
              <name>FB23</name>
              <bitOffset>23</bitOffset>
              <bitWidth>1</bitWidth>
            </field>
            <field>
              <name>FB24</name>
              <bitOffset>24</bitOffset>
              <bitWidth>1</bitWidth>
            </field>
            <field>
              <name>FB25</name>
              <bitOffset>25</bitOffset>
              <bitWidth>1</bitWidth>
            </field>
            <field>
              <name>FB26</name>
              <bitOffset>26</bitOffset>
              <bitWidth>1</bitWidth>
            </field>
            <field>
              <name>FB27</name>
              <bitOffset>27</bitOffset>
              <bitWidth>1</bitWidth>
            </field>
            <field>
              <name>FB28</name>
              <bitOffset>28</bitOffset>
              <bitWidth>1</bitWidth>
            </field>
            <field>
              <name>FB29</name>
              <bitOffset>29</bitOffset>
              <bitWidth>1</bitWidth>
            </field>
            <field>
              <name>FB30</name>
              <bitOffset>30</bitOffset>
              <bitWidth>1</bitWidth>
            </field>
            <field>
              <name>FB31</name>
              <bitOffset>31</bitOffset>
              <bitWidth>1</bitWidth>
            </field>
          </fields>
        </register>
        <register>
          <name>sFilterRegister.3.FR2</name>
          <addressOffset>0x25c</addressOffset>
          <size>0x20</size>
          <fields>
            <field>
              <name>FB0</name>
              <bitOffset>0</bitOffset>
              <bitWidth>1</bitWidth>
            </field>
            <field>
              <name>FB1</name>
              <bitOffset>1</bitOffset>
              <bitWidth>1</bitWidth>
            </field>
            <field>
              <name>FB2</name>
              <bitOffset>2</bitOffset>
              <bitWidth>1</bitWidth>
            </field>
            <field>
              <name>FB3</name>
              <bitOffset>3</bitOffset>
              <bitWidth>1</bitWidth>
            </field>
            <field>
              <name>FB4</name>
              <bitOffset>4</bitOffset>
              <bitWidth>1</bitWidth>
            </field>
            <field>
              <name>FB5</name>
              <bitOffset>5</bitOffset>
              <bitWidth>1</bitWidth>
            </field>
            <field>
              <name>FB6</name>
              <bitOffset>6</bitOffset>
              <bitWidth>1</bitWidth>
            </field>
            <field>
              <name>FB7</name>
              <bitOffset>7</bitOffset>
              <bitWidth>1</bitWidth>
            </field>
            <field>
              <name>FB8</name>
              <bitOffset>8</bitOffset>
              <bitWidth>1</bitWidth>
            </field>
            <field>
              <name>FB9</name>
              <bitOffset>9</bitOffset>
              <bitWidth>1</bitWidth>
            </field>
            <field>
              <name>FB10</name>
              <bitOffset>10</bitOffset>
              <bitWidth>1</bitWidth>
            </field>
            <field>
              <name>FB11</name>
              <bitOffset>11</bitOffset>
              <bitWidth>1</bitWidth>
            </field>
            <field>
              <name>FB12</name>
              <bitOffset>12</bitOffset>
              <bitWidth>1</bitWidth>
            </field>
            <field>
              <name>FB13</name>
              <bitOffset>13</bitOffset>
              <bitWidth>1</bitWidth>
            </field>
            <field>
              <name>FB14</name>
              <bitOffset>14</bitOffset>
              <bitWidth>1</bitWidth>
            </field>
            <field>
              <name>FB15</name>
              <bitOffset>15</bitOffset>
              <bitWidth>1</bitWidth>
            </field>
            <field>
              <name>FB16</name>
              <bitOffset>16</bitOffset>
              <bitWidth>1</bitWidth>
            </field>
            <field>
              <name>FB17</name>
              <bitOffset>17</bitOffset>
              <bitWidth>1</bitWidth>
            </field>
            <field>
              <name>FB18</name>
              <bitOffset>18</bitOffset>
              <bitWidth>1</bitWidth>
            </field>
            <field>
              <name>FB19</name>
              <bitOffset>19</bitOffset>
              <bitWidth>1</bitWidth>
            </field>
            <field>
              <name>FB20</name>
              <bitOffset>20</bitOffset>
              <bitWidth>1</bitWidth>
            </field>
            <field>
              <name>FB21</name>
              <bitOffset>21</bitOffset>
              <bitWidth>1</bitWidth>
            </field>
            <field>
              <name>FB22</name>
              <bitOffset>22</bitOffset>
              <bitWidth>1</bitWidth>
            </field>
            <field>
              <name>FB23</name>
              <bitOffset>23</bitOffset>
              <bitWidth>1</bitWidth>
            </field>
            <field>
              <name>FB24</name>
              <bitOffset>24</bitOffset>
              <bitWidth>1</bitWidth>
            </field>
            <field>
              <name>FB25</name>
              <bitOffset>25</bitOffset>
              <bitWidth>1</bitWidth>
            </field>
            <field>
              <name>FB26</name>
              <bitOffset>26</bitOffset>
              <bitWidth>1</bitWidth>
            </field>
            <field>
              <name>FB27</name>
              <bitOffset>27</bitOffset>
              <bitWidth>1</bitWidth>
            </field>
            <field>
              <name>FB28</name>
              <bitOffset>28</bitOffset>
              <bitWidth>1</bitWidth>
            </field>
            <field>
              <name>FB29</name>
              <bitOffset>29</bitOffset>
              <bitWidth>1</bitWidth>
            </field>
            <field>
              <name>FB30</name>
              <bitOffset>30</bitOffset>
              <bitWidth>1</bitWidth>
            </field>
            <field>
              <name>FB31</name>
              <bitOffset>31</bitOffset>
              <bitWidth>1</bitWidth>
            </field>
          </fields>
        </register>
        <register>
          <name>sFilterRegister.4.FR1</name>
          <addressOffset>0x260</addressOffset>
          <size>0x20</size>
          <fields>
            <field>
              <name>FB0</name>
              <bitOffset>0</bitOffset>
              <bitWidth>1</bitWidth>
            </field>
            <field>
              <name>FB1</name>
              <bitOffset>1</bitOffset>
              <bitWidth>1</bitWidth>
            </field>
            <field>
              <name>FB2</name>
              <bitOffset>2</bitOffset>
              <bitWidth>1</bitWidth>
            </field>
            <field>
              <name>FB3</name>
              <bitOffset>3</bitOffset>
              <bitWidth>1</bitWidth>
            </field>
            <field>
              <name>FB4</name>
              <bitOffset>4</bitOffset>
              <bitWidth>1</bitWidth>
            </field>
            <field>
              <name>FB5</name>
              <bitOffset>5</bitOffset>
              <bitWidth>1</bitWidth>
            </field>
            <field>
              <name>FB6</name>
              <bitOffset>6</bitOffset>
              <bitWidth>1</bitWidth>
            </field>
            <field>
              <name>FB7</name>
              <bitOffset>7</bitOffset>
              <bitWidth>1</bitWidth>
            </field>
            <field>
              <name>FB8</name>
              <bitOffset>8</bitOffset>
              <bitWidth>1</bitWidth>
            </field>
            <field>
              <name>FB9</name>
              <bitOffset>9</bitOffset>
              <bitWidth>1</bitWidth>
            </field>
            <field>
              <name>FB10</name>
              <bitOffset>10</bitOffset>
              <bitWidth>1</bitWidth>
            </field>
            <field>
              <name>FB11</name>
              <bitOffset>11</bitOffset>
              <bitWidth>1</bitWidth>
            </field>
            <field>
              <name>FB12</name>
              <bitOffset>12</bitOffset>
              <bitWidth>1</bitWidth>
            </field>
            <field>
              <name>FB13</name>
              <bitOffset>13</bitOffset>
              <bitWidth>1</bitWidth>
            </field>
            <field>
              <name>FB14</name>
              <bitOffset>14</bitOffset>
              <bitWidth>1</bitWidth>
            </field>
            <field>
              <name>FB15</name>
              <bitOffset>15</bitOffset>
              <bitWidth>1</bitWidth>
            </field>
            <field>
              <name>FB16</name>
              <bitOffset>16</bitOffset>
              <bitWidth>1</bitWidth>
            </field>
            <field>
              <name>FB17</name>
              <bitOffset>17</bitOffset>
              <bitWidth>1</bitWidth>
            </field>
            <field>
              <name>FB18</name>
              <bitOffset>18</bitOffset>
              <bitWidth>1</bitWidth>
            </field>
            <field>
              <name>FB19</name>
              <bitOffset>19</bitOffset>
              <bitWidth>1</bitWidth>
            </field>
            <field>
              <name>FB20</name>
              <bitOffset>20</bitOffset>
              <bitWidth>1</bitWidth>
            </field>
            <field>
              <name>FB21</name>
              <bitOffset>21</bitOffset>
              <bitWidth>1</bitWidth>
            </field>
            <field>
              <name>FB22</name>
              <bitOffset>22</bitOffset>
              <bitWidth>1</bitWidth>
            </field>
            <field>
              <name>FB23</name>
              <bitOffset>23</bitOffset>
              <bitWidth>1</bitWidth>
            </field>
            <field>
              <name>FB24</name>
              <bitOffset>24</bitOffset>
              <bitWidth>1</bitWidth>
            </field>
            <field>
              <name>FB25</name>
              <bitOffset>25</bitOffset>
              <bitWidth>1</bitWidth>
            </field>
            <field>
              <name>FB26</name>
              <bitOffset>26</bitOffset>
              <bitWidth>1</bitWidth>
            </field>
            <field>
              <name>FB27</name>
              <bitOffset>27</bitOffset>
              <bitWidth>1</bitWidth>
            </field>
            <field>
              <name>FB28</name>
              <bitOffset>28</bitOffset>
              <bitWidth>1</bitWidth>
            </field>
            <field>
              <name>FB29</name>
              <bitOffset>29</bitOffset>
              <bitWidth>1</bitWidth>
            </field>
            <field>
              <name>FB30</name>
              <bitOffset>30</bitOffset>
              <bitWidth>1</bitWidth>
            </field>
            <field>
              <name>FB31</name>
              <bitOffset>31</bitOffset>
              <bitWidth>1</bitWidth>
            </field>
          </fields>
        </register>
        <register>
          <name>sFilterRegister.4.FR2</name>
          <addressOffset>0x264</addressOffset>
          <size>0x20</size>
          <fields>
            <field>
              <name>FB0</name>
              <bitOffset>0</bitOffset>
              <bitWidth>1</bitWidth>
            </field>
            <field>
              <name>FB1</name>
              <bitOffset>1</bitOffset>
              <bitWidth>1</bitWidth>
            </field>
            <field>
              <name>FB2</name>
              <bitOffset>2</bitOffset>
              <bitWidth>1</bitWidth>
            </field>
            <field>
              <name>FB3</name>
              <bitOffset>3</bitOffset>
              <bitWidth>1</bitWidth>
            </field>
            <field>
              <name>FB4</name>
              <bitOffset>4</bitOffset>
              <bitWidth>1</bitWidth>
            </field>
            <field>
              <name>FB5</name>
              <bitOffset>5</bitOffset>
              <bitWidth>1</bitWidth>
            </field>
            <field>
              <name>FB6</name>
              <bitOffset>6</bitOffset>
              <bitWidth>1</bitWidth>
            </field>
            <field>
              <name>FB7</name>
              <bitOffset>7</bitOffset>
              <bitWidth>1</bitWidth>
            </field>
            <field>
              <name>FB8</name>
              <bitOffset>8</bitOffset>
              <bitWidth>1</bitWidth>
            </field>
            <field>
              <name>FB9</name>
              <bitOffset>9</bitOffset>
              <bitWidth>1</bitWidth>
            </field>
            <field>
              <name>FB10</name>
              <bitOffset>10</bitOffset>
              <bitWidth>1</bitWidth>
            </field>
            <field>
              <name>FB11</name>
              <bitOffset>11</bitOffset>
              <bitWidth>1</bitWidth>
            </field>
            <field>
              <name>FB12</name>
              <bitOffset>12</bitOffset>
              <bitWidth>1</bitWidth>
            </field>
            <field>
              <name>FB13</name>
              <bitOffset>13</bitOffset>
              <bitWidth>1</bitWidth>
            </field>
            <field>
              <name>FB14</name>
              <bitOffset>14</bitOffset>
              <bitWidth>1</bitWidth>
            </field>
            <field>
              <name>FB15</name>
              <bitOffset>15</bitOffset>
              <bitWidth>1</bitWidth>
            </field>
            <field>
              <name>FB16</name>
              <bitOffset>16</bitOffset>
              <bitWidth>1</bitWidth>
            </field>
            <field>
              <name>FB17</name>
              <bitOffset>17</bitOffset>
              <bitWidth>1</bitWidth>
            </field>
            <field>
              <name>FB18</name>
              <bitOffset>18</bitOffset>
              <bitWidth>1</bitWidth>
            </field>
            <field>
              <name>FB19</name>
              <bitOffset>19</bitOffset>
              <bitWidth>1</bitWidth>
            </field>
            <field>
              <name>FB20</name>
              <bitOffset>20</bitOffset>
              <bitWidth>1</bitWidth>
            </field>
            <field>
              <name>FB21</name>
              <bitOffset>21</bitOffset>
              <bitWidth>1</bitWidth>
            </field>
            <field>
              <name>FB22</name>
              <bitOffset>22</bitOffset>
              <bitWidth>1</bitWidth>
            </field>
            <field>
              <name>FB23</name>
              <bitOffset>23</bitOffset>
              <bitWidth>1</bitWidth>
            </field>
            <field>
              <name>FB24</name>
              <bitOffset>24</bitOffset>
              <bitWidth>1</bitWidth>
            </field>
            <field>
              <name>FB25</name>
              <bitOffset>25</bitOffset>
              <bitWidth>1</bitWidth>
            </field>
            <field>
              <name>FB26</name>
              <bitOffset>26</bitOffset>
              <bitWidth>1</bitWidth>
            </field>
            <field>
              <name>FB27</name>
              <bitOffset>27</bitOffset>
              <bitWidth>1</bitWidth>
            </field>
            <field>
              <name>FB28</name>
              <bitOffset>28</bitOffset>
              <bitWidth>1</bitWidth>
            </field>
            <field>
              <name>FB29</name>
              <bitOffset>29</bitOffset>
              <bitWidth>1</bitWidth>
            </field>
            <field>
              <name>FB30</name>
              <bitOffset>30</bitOffset>
              <bitWidth>1</bitWidth>
            </field>
            <field>
              <name>FB31</name>
              <bitOffset>31</bitOffset>
              <bitWidth>1</bitWidth>
            </field>
          </fields>
        </register>
        <register>
          <name>sFilterRegister.5.FR1</name>
          <addressOffset>0x268</addressOffset>
          <size>0x20</size>
          <fields>
            <field>
              <name>FB0</name>
              <bitOffset>0</bitOffset>
              <bitWidth>1</bitWidth>
            </field>
            <field>
              <name>FB1</name>
              <bitOffset>1</bitOffset>
              <bitWidth>1</bitWidth>
            </field>
            <field>
              <name>FB2</name>
              <bitOffset>2</bitOffset>
              <bitWidth>1</bitWidth>
            </field>
            <field>
              <name>FB3</name>
              <bitOffset>3</bitOffset>
              <bitWidth>1</bitWidth>
            </field>
            <field>
              <name>FB4</name>
              <bitOffset>4</bitOffset>
              <bitWidth>1</bitWidth>
            </field>
            <field>
              <name>FB5</name>
              <bitOffset>5</bitOffset>
              <bitWidth>1</bitWidth>
            </field>
            <field>
              <name>FB6</name>
              <bitOffset>6</bitOffset>
              <bitWidth>1</bitWidth>
            </field>
            <field>
              <name>FB7</name>
              <bitOffset>7</bitOffset>
              <bitWidth>1</bitWidth>
            </field>
            <field>
              <name>FB8</name>
              <bitOffset>8</bitOffset>
              <bitWidth>1</bitWidth>
            </field>
            <field>
              <name>FB9</name>
              <bitOffset>9</bitOffset>
              <bitWidth>1</bitWidth>
            </field>
            <field>
              <name>FB10</name>
              <bitOffset>10</bitOffset>
              <bitWidth>1</bitWidth>
            </field>
            <field>
              <name>FB11</name>
              <bitOffset>11</bitOffset>
              <bitWidth>1</bitWidth>
            </field>
            <field>
              <name>FB12</name>
              <bitOffset>12</bitOffset>
              <bitWidth>1</bitWidth>
            </field>
            <field>
              <name>FB13</name>
              <bitOffset>13</bitOffset>
              <bitWidth>1</bitWidth>
            </field>
            <field>
              <name>FB14</name>
              <bitOffset>14</bitOffset>
              <bitWidth>1</bitWidth>
            </field>
            <field>
              <name>FB15</name>
              <bitOffset>15</bitOffset>
              <bitWidth>1</bitWidth>
            </field>
            <field>
              <name>FB16</name>
              <bitOffset>16</bitOffset>
              <bitWidth>1</bitWidth>
            </field>
            <field>
              <name>FB17</name>
              <bitOffset>17</bitOffset>
              <bitWidth>1</bitWidth>
            </field>
            <field>
              <name>FB18</name>
              <bitOffset>18</bitOffset>
              <bitWidth>1</bitWidth>
            </field>
            <field>
              <name>FB19</name>
              <bitOffset>19</bitOffset>
              <bitWidth>1</bitWidth>
            </field>
            <field>
              <name>FB20</name>
              <bitOffset>20</bitOffset>
              <bitWidth>1</bitWidth>
            </field>
            <field>
              <name>FB21</name>
              <bitOffset>21</bitOffset>
              <bitWidth>1</bitWidth>
            </field>
            <field>
              <name>FB22</name>
              <bitOffset>22</bitOffset>
              <bitWidth>1</bitWidth>
            </field>
            <field>
              <name>FB23</name>
              <bitOffset>23</bitOffset>
              <bitWidth>1</bitWidth>
            </field>
            <field>
              <name>FB24</name>
              <bitOffset>24</bitOffset>
              <bitWidth>1</bitWidth>
            </field>
            <field>
              <name>FB25</name>
              <bitOffset>25</bitOffset>
              <bitWidth>1</bitWidth>
            </field>
            <field>
              <name>FB26</name>
              <bitOffset>26</bitOffset>
              <bitWidth>1</bitWidth>
            </field>
            <field>
              <name>FB27</name>
              <bitOffset>27</bitOffset>
              <bitWidth>1</bitWidth>
            </field>
            <field>
              <name>FB28</name>
              <bitOffset>28</bitOffset>
              <bitWidth>1</bitWidth>
            </field>
            <field>
              <name>FB29</name>
              <bitOffset>29</bitOffset>
              <bitWidth>1</bitWidth>
            </field>
            <field>
              <name>FB30</name>
              <bitOffset>30</bitOffset>
              <bitWidth>1</bitWidth>
            </field>
            <field>
              <name>FB31</name>
              <bitOffset>31</bitOffset>
              <bitWidth>1</bitWidth>
            </field>
          </fields>
        </register>
        <register>
          <name>sFilterRegister.5.FR2</name>
          <addressOffset>0x26c</addressOffset>
          <size>0x20</size>
          <fields>
            <field>
              <name>FB0</name>
              <bitOffset>0</bitOffset>
              <bitWidth>1</bitWidth>
            </field>
            <field>
              <name>FB1</name>
              <bitOffset>1</bitOffset>
              <bitWidth>1</bitWidth>
            </field>
            <field>
              <name>FB2</name>
              <bitOffset>2</bitOffset>
              <bitWidth>1</bitWidth>
            </field>
            <field>
              <name>FB3</name>
              <bitOffset>3</bitOffset>
              <bitWidth>1</bitWidth>
            </field>
            <field>
              <name>FB4</name>
              <bitOffset>4</bitOffset>
              <bitWidth>1</bitWidth>
            </field>
            <field>
              <name>FB5</name>
              <bitOffset>5</bitOffset>
              <bitWidth>1</bitWidth>
            </field>
            <field>
              <name>FB6</name>
              <bitOffset>6</bitOffset>
              <bitWidth>1</bitWidth>
            </field>
            <field>
              <name>FB7</name>
              <bitOffset>7</bitOffset>
              <bitWidth>1</bitWidth>
            </field>
            <field>
              <name>FB8</name>
              <bitOffset>8</bitOffset>
              <bitWidth>1</bitWidth>
            </field>
            <field>
              <name>FB9</name>
              <bitOffset>9</bitOffset>
              <bitWidth>1</bitWidth>
            </field>
            <field>
              <name>FB10</name>
              <bitOffset>10</bitOffset>
              <bitWidth>1</bitWidth>
            </field>
            <field>
              <name>FB11</name>
              <bitOffset>11</bitOffset>
              <bitWidth>1</bitWidth>
            </field>
            <field>
              <name>FB12</name>
              <bitOffset>12</bitOffset>
              <bitWidth>1</bitWidth>
            </field>
            <field>
              <name>FB13</name>
              <bitOffset>13</bitOffset>
              <bitWidth>1</bitWidth>
            </field>
            <field>
              <name>FB14</name>
              <bitOffset>14</bitOffset>
              <bitWidth>1</bitWidth>
            </field>
            <field>
              <name>FB15</name>
              <bitOffset>15</bitOffset>
              <bitWidth>1</bitWidth>
            </field>
            <field>
              <name>FB16</name>
              <bitOffset>16</bitOffset>
              <bitWidth>1</bitWidth>
            </field>
            <field>
              <name>FB17</name>
              <bitOffset>17</bitOffset>
              <bitWidth>1</bitWidth>
            </field>
            <field>
              <name>FB18</name>
              <bitOffset>18</bitOffset>
              <bitWidth>1</bitWidth>
            </field>
            <field>
              <name>FB19</name>
              <bitOffset>19</bitOffset>
              <bitWidth>1</bitWidth>
            </field>
            <field>
              <name>FB20</name>
              <bitOffset>20</bitOffset>
              <bitWidth>1</bitWidth>
            </field>
            <field>
              <name>FB21</name>
              <bitOffset>21</bitOffset>
              <bitWidth>1</bitWidth>
            </field>
            <field>
              <name>FB22</name>
              <bitOffset>22</bitOffset>
              <bitWidth>1</bitWidth>
            </field>
            <field>
              <name>FB23</name>
              <bitOffset>23</bitOffset>
              <bitWidth>1</bitWidth>
            </field>
            <field>
              <name>FB24</name>
              <bitOffset>24</bitOffset>
              <bitWidth>1</bitWidth>
            </field>
            <field>
              <name>FB25</name>
              <bitOffset>25</bitOffset>
              <bitWidth>1</bitWidth>
            </field>
            <field>
              <name>FB26</name>
              <bitOffset>26</bitOffset>
              <bitWidth>1</bitWidth>
            </field>
            <field>
              <name>FB27</name>
              <bitOffset>27</bitOffset>
              <bitWidth>1</bitWidth>
            </field>
            <field>
              <name>FB28</name>
              <bitOffset>28</bitOffset>
              <bitWidth>1</bitWidth>
            </field>
            <field>
              <name>FB29</name>
              <bitOffset>29</bitOffset>
              <bitWidth>1</bitWidth>
            </field>
            <field>
              <name>FB30</name>
              <bitOffset>30</bitOffset>
              <bitWidth>1</bitWidth>
            </field>
            <field>
              <name>FB31</name>
              <bitOffset>31</bitOffset>
              <bitWidth>1</bitWidth>
            </field>
          </fields>
        </register>
        <register>
          <name>sFilterRegister.6.FR1</name>
          <addressOffset>0x270</addressOffset>
          <size>0x20</size>
          <fields>
            <field>
              <name>FB0</name>
              <bitOffset>0</bitOffset>
              <bitWidth>1</bitWidth>
            </field>
            <field>
              <name>FB1</name>
              <bitOffset>1</bitOffset>
              <bitWidth>1</bitWidth>
            </field>
            <field>
              <name>FB2</name>
              <bitOffset>2</bitOffset>
              <bitWidth>1</bitWidth>
            </field>
            <field>
              <name>FB3</name>
              <bitOffset>3</bitOffset>
              <bitWidth>1</bitWidth>
            </field>
            <field>
              <name>FB4</name>
              <bitOffset>4</bitOffset>
              <bitWidth>1</bitWidth>
            </field>
            <field>
              <name>FB5</name>
              <bitOffset>5</bitOffset>
              <bitWidth>1</bitWidth>
            </field>
            <field>
              <name>FB6</name>
              <bitOffset>6</bitOffset>
              <bitWidth>1</bitWidth>
            </field>
            <field>
              <name>FB7</name>
              <bitOffset>7</bitOffset>
              <bitWidth>1</bitWidth>
            </field>
            <field>
              <name>FB8</name>
              <bitOffset>8</bitOffset>
              <bitWidth>1</bitWidth>
            </field>
            <field>
              <name>FB9</name>
              <bitOffset>9</bitOffset>
              <bitWidth>1</bitWidth>
            </field>
            <field>
              <name>FB10</name>
              <bitOffset>10</bitOffset>
              <bitWidth>1</bitWidth>
            </field>
            <field>
              <name>FB11</name>
              <bitOffset>11</bitOffset>
              <bitWidth>1</bitWidth>
            </field>
            <field>
              <name>FB12</name>
              <bitOffset>12</bitOffset>
              <bitWidth>1</bitWidth>
            </field>
            <field>
              <name>FB13</name>
              <bitOffset>13</bitOffset>
              <bitWidth>1</bitWidth>
            </field>
            <field>
              <name>FB14</name>
              <bitOffset>14</bitOffset>
              <bitWidth>1</bitWidth>
            </field>
            <field>
              <name>FB15</name>
              <bitOffset>15</bitOffset>
              <bitWidth>1</bitWidth>
            </field>
            <field>
              <name>FB16</name>
              <bitOffset>16</bitOffset>
              <bitWidth>1</bitWidth>
            </field>
            <field>
              <name>FB17</name>
              <bitOffset>17</bitOffset>
              <bitWidth>1</bitWidth>
            </field>
            <field>
              <name>FB18</name>
              <bitOffset>18</bitOffset>
              <bitWidth>1</bitWidth>
            </field>
            <field>
              <name>FB19</name>
              <bitOffset>19</bitOffset>
              <bitWidth>1</bitWidth>
            </field>
            <field>
              <name>FB20</name>
              <bitOffset>20</bitOffset>
              <bitWidth>1</bitWidth>
            </field>
            <field>
              <name>FB21</name>
              <bitOffset>21</bitOffset>
              <bitWidth>1</bitWidth>
            </field>
            <field>
              <name>FB22</name>
              <bitOffset>22</bitOffset>
              <bitWidth>1</bitWidth>
            </field>
            <field>
              <name>FB23</name>
              <bitOffset>23</bitOffset>
              <bitWidth>1</bitWidth>
            </field>
            <field>
              <name>FB24</name>
              <bitOffset>24</bitOffset>
              <bitWidth>1</bitWidth>
            </field>
            <field>
              <name>FB25</name>
              <bitOffset>25</bitOffset>
              <bitWidth>1</bitWidth>
            </field>
            <field>
              <name>FB26</name>
              <bitOffset>26</bitOffset>
              <bitWidth>1</bitWidth>
            </field>
            <field>
              <name>FB27</name>
              <bitOffset>27</bitOffset>
              <bitWidth>1</bitWidth>
            </field>
            <field>
              <name>FB28</name>
              <bitOffset>28</bitOffset>
              <bitWidth>1</bitWidth>
            </field>
            <field>
              <name>FB29</name>
              <bitOffset>29</bitOffset>
              <bitWidth>1</bitWidth>
            </field>
            <field>
              <name>FB30</name>
              <bitOffset>30</bitOffset>
              <bitWidth>1</bitWidth>
            </field>
            <field>
              <name>FB31</name>
              <bitOffset>31</bitOffset>
              <bitWidth>1</bitWidth>
            </field>
          </fields>
        </register>
        <register>
          <name>sFilterRegister.6.FR2</name>
          <addressOffset>0x274</addressOffset>
          <size>0x20</size>
          <fields>
            <field>
              <name>FB0</name>
              <bitOffset>0</bitOffset>
              <bitWidth>1</bitWidth>
            </field>
            <field>
              <name>FB1</name>
              <bitOffset>1</bitOffset>
              <bitWidth>1</bitWidth>
            </field>
            <field>
              <name>FB2</name>
              <bitOffset>2</bitOffset>
              <bitWidth>1</bitWidth>
            </field>
            <field>
              <name>FB3</name>
              <bitOffset>3</bitOffset>
              <bitWidth>1</bitWidth>
            </field>
            <field>
              <name>FB4</name>
              <bitOffset>4</bitOffset>
              <bitWidth>1</bitWidth>
            </field>
            <field>
              <name>FB5</name>
              <bitOffset>5</bitOffset>
              <bitWidth>1</bitWidth>
            </field>
            <field>
              <name>FB6</name>
              <bitOffset>6</bitOffset>
              <bitWidth>1</bitWidth>
            </field>
            <field>
              <name>FB7</name>
              <bitOffset>7</bitOffset>
              <bitWidth>1</bitWidth>
            </field>
            <field>
              <name>FB8</name>
              <bitOffset>8</bitOffset>
              <bitWidth>1</bitWidth>
            </field>
            <field>
              <name>FB9</name>
              <bitOffset>9</bitOffset>
              <bitWidth>1</bitWidth>
            </field>
            <field>
              <name>FB10</name>
              <bitOffset>10</bitOffset>
              <bitWidth>1</bitWidth>
            </field>
            <field>
              <name>FB11</name>
              <bitOffset>11</bitOffset>
              <bitWidth>1</bitWidth>
            </field>
            <field>
              <name>FB12</name>
              <bitOffset>12</bitOffset>
              <bitWidth>1</bitWidth>
            </field>
            <field>
              <name>FB13</name>
              <bitOffset>13</bitOffset>
              <bitWidth>1</bitWidth>
            </field>
            <field>
              <name>FB14</name>
              <bitOffset>14</bitOffset>
              <bitWidth>1</bitWidth>
            </field>
            <field>
              <name>FB15</name>
              <bitOffset>15</bitOffset>
              <bitWidth>1</bitWidth>
            </field>
            <field>
              <name>FB16</name>
              <bitOffset>16</bitOffset>
              <bitWidth>1</bitWidth>
            </field>
            <field>
              <name>FB17</name>
              <bitOffset>17</bitOffset>
              <bitWidth>1</bitWidth>
            </field>
            <field>
              <name>FB18</name>
              <bitOffset>18</bitOffset>
              <bitWidth>1</bitWidth>
            </field>
            <field>
              <name>FB19</name>
              <bitOffset>19</bitOffset>
              <bitWidth>1</bitWidth>
            </field>
            <field>
              <name>FB20</name>
              <bitOffset>20</bitOffset>
              <bitWidth>1</bitWidth>
            </field>
            <field>
              <name>FB21</name>
              <bitOffset>21</bitOffset>
              <bitWidth>1</bitWidth>
            </field>
            <field>
              <name>FB22</name>
              <bitOffset>22</bitOffset>
              <bitWidth>1</bitWidth>
            </field>
            <field>
              <name>FB23</name>
              <bitOffset>23</bitOffset>
              <bitWidth>1</bitWidth>
            </field>
            <field>
              <name>FB24</name>
              <bitOffset>24</bitOffset>
              <bitWidth>1</bitWidth>
            </field>
            <field>
              <name>FB25</name>
              <bitOffset>25</bitOffset>
              <bitWidth>1</bitWidth>
            </field>
            <field>
              <name>FB26</name>
              <bitOffset>26</bitOffset>
              <bitWidth>1</bitWidth>
            </field>
            <field>
              <name>FB27</name>
              <bitOffset>27</bitOffset>
              <bitWidth>1</bitWidth>
            </field>
            <field>
              <name>FB28</name>
              <bitOffset>28</bitOffset>
              <bitWidth>1</bitWidth>
            </field>
            <field>
              <name>FB29</name>
              <bitOffset>29</bitOffset>
              <bitWidth>1</bitWidth>
            </field>
            <field>
              <name>FB30</name>
              <bitOffset>30</bitOffset>
              <bitWidth>1</bitWidth>
            </field>
            <field>
              <name>FB31</name>
              <bitOffset>31</bitOffset>
              <bitWidth>1</bitWidth>
            </field>
          </fields>
        </register>
        <register>
          <name>sFilterRegister.7.FR1</name>
          <addressOffset>0x278</addressOffset>
          <size>0x20</size>
          <fields>
            <field>
              <name>FB0</name>
              <bitOffset>0</bitOffset>
              <bitWidth>1</bitWidth>
            </field>
            <field>
              <name>FB1</name>
              <bitOffset>1</bitOffset>
              <bitWidth>1</bitWidth>
            </field>
            <field>
              <name>FB2</name>
              <bitOffset>2</bitOffset>
              <bitWidth>1</bitWidth>
            </field>
            <field>
              <name>FB3</name>
              <bitOffset>3</bitOffset>
              <bitWidth>1</bitWidth>
            </field>
            <field>
              <name>FB4</name>
              <bitOffset>4</bitOffset>
              <bitWidth>1</bitWidth>
            </field>
            <field>
              <name>FB5</name>
              <bitOffset>5</bitOffset>
              <bitWidth>1</bitWidth>
            </field>
            <field>
              <name>FB6</name>
              <bitOffset>6</bitOffset>
              <bitWidth>1</bitWidth>
            </field>
            <field>
              <name>FB7</name>
              <bitOffset>7</bitOffset>
              <bitWidth>1</bitWidth>
            </field>
            <field>
              <name>FB8</name>
              <bitOffset>8</bitOffset>
              <bitWidth>1</bitWidth>
            </field>
            <field>
              <name>FB9</name>
              <bitOffset>9</bitOffset>
              <bitWidth>1</bitWidth>
            </field>
            <field>
              <name>FB10</name>
              <bitOffset>10</bitOffset>
              <bitWidth>1</bitWidth>
            </field>
            <field>
              <name>FB11</name>
              <bitOffset>11</bitOffset>
              <bitWidth>1</bitWidth>
            </field>
            <field>
              <name>FB12</name>
              <bitOffset>12</bitOffset>
              <bitWidth>1</bitWidth>
            </field>
            <field>
              <name>FB13</name>
              <bitOffset>13</bitOffset>
              <bitWidth>1</bitWidth>
            </field>
            <field>
              <name>FB14</name>
              <bitOffset>14</bitOffset>
              <bitWidth>1</bitWidth>
            </field>
            <field>
              <name>FB15</name>
              <bitOffset>15</bitOffset>
              <bitWidth>1</bitWidth>
            </field>
            <field>
              <name>FB16</name>
              <bitOffset>16</bitOffset>
              <bitWidth>1</bitWidth>
            </field>
            <field>
              <name>FB17</name>
              <bitOffset>17</bitOffset>
              <bitWidth>1</bitWidth>
            </field>
            <field>
              <name>FB18</name>
              <bitOffset>18</bitOffset>
              <bitWidth>1</bitWidth>
            </field>
            <field>
              <name>FB19</name>
              <bitOffset>19</bitOffset>
              <bitWidth>1</bitWidth>
            </field>
            <field>
              <name>FB20</name>
              <bitOffset>20</bitOffset>
              <bitWidth>1</bitWidth>
            </field>
            <field>
              <name>FB21</name>
              <bitOffset>21</bitOffset>
              <bitWidth>1</bitWidth>
            </field>
            <field>
              <name>FB22</name>
              <bitOffset>22</bitOffset>
              <bitWidth>1</bitWidth>
            </field>
            <field>
              <name>FB23</name>
              <bitOffset>23</bitOffset>
              <bitWidth>1</bitWidth>
            </field>
            <field>
              <name>FB24</name>
              <bitOffset>24</bitOffset>
              <bitWidth>1</bitWidth>
            </field>
            <field>
              <name>FB25</name>
              <bitOffset>25</bitOffset>
              <bitWidth>1</bitWidth>
            </field>
            <field>
              <name>FB26</name>
              <bitOffset>26</bitOffset>
              <bitWidth>1</bitWidth>
            </field>
            <field>
              <name>FB27</name>
              <bitOffset>27</bitOffset>
              <bitWidth>1</bitWidth>
            </field>
            <field>
              <name>FB28</name>
              <bitOffset>28</bitOffset>
              <bitWidth>1</bitWidth>
            </field>
            <field>
              <name>FB29</name>
              <bitOffset>29</bitOffset>
              <bitWidth>1</bitWidth>
            </field>
            <field>
              <name>FB30</name>
              <bitOffset>30</bitOffset>
              <bitWidth>1</bitWidth>
            </field>
            <field>
              <name>FB31</name>
              <bitOffset>31</bitOffset>
              <bitWidth>1</bitWidth>
            </field>
          </fields>
        </register>
        <register>
          <name>sFilterRegister.7.FR2</name>
          <addressOffset>0x27c</addressOffset>
          <size>0x20</size>
          <fields>
            <field>
              <name>FB0</name>
              <bitOffset>0</bitOffset>
              <bitWidth>1</bitWidth>
            </field>
            <field>
              <name>FB1</name>
              <bitOffset>1</bitOffset>
              <bitWidth>1</bitWidth>
            </field>
            <field>
              <name>FB2</name>
              <bitOffset>2</bitOffset>
              <bitWidth>1</bitWidth>
            </field>
            <field>
              <name>FB3</name>
              <bitOffset>3</bitOffset>
              <bitWidth>1</bitWidth>
            </field>
            <field>
              <name>FB4</name>
              <bitOffset>4</bitOffset>
              <bitWidth>1</bitWidth>
            </field>
            <field>
              <name>FB5</name>
              <bitOffset>5</bitOffset>
              <bitWidth>1</bitWidth>
            </field>
            <field>
              <name>FB6</name>
              <bitOffset>6</bitOffset>
              <bitWidth>1</bitWidth>
            </field>
            <field>
              <name>FB7</name>
              <bitOffset>7</bitOffset>
              <bitWidth>1</bitWidth>
            </field>
            <field>
              <name>FB8</name>
              <bitOffset>8</bitOffset>
              <bitWidth>1</bitWidth>
            </field>
            <field>
              <name>FB9</name>
              <bitOffset>9</bitOffset>
              <bitWidth>1</bitWidth>
            </field>
            <field>
              <name>FB10</name>
              <bitOffset>10</bitOffset>
              <bitWidth>1</bitWidth>
            </field>
            <field>
              <name>FB11</name>
              <bitOffset>11</bitOffset>
              <bitWidth>1</bitWidth>
            </field>
            <field>
              <name>FB12</name>
              <bitOffset>12</bitOffset>
              <bitWidth>1</bitWidth>
            </field>
            <field>
              <name>FB13</name>
              <bitOffset>13</bitOffset>
              <bitWidth>1</bitWidth>
            </field>
            <field>
              <name>FB14</name>
              <bitOffset>14</bitOffset>
              <bitWidth>1</bitWidth>
            </field>
            <field>
              <name>FB15</name>
              <bitOffset>15</bitOffset>
              <bitWidth>1</bitWidth>
            </field>
            <field>
              <name>FB16</name>
              <bitOffset>16</bitOffset>
              <bitWidth>1</bitWidth>
            </field>
            <field>
              <name>FB17</name>
              <bitOffset>17</bitOffset>
              <bitWidth>1</bitWidth>
            </field>
            <field>
              <name>FB18</name>
              <bitOffset>18</bitOffset>
              <bitWidth>1</bitWidth>
            </field>
            <field>
              <name>FB19</name>
              <bitOffset>19</bitOffset>
              <bitWidth>1</bitWidth>
            </field>
            <field>
              <name>FB20</name>
              <bitOffset>20</bitOffset>
              <bitWidth>1</bitWidth>
            </field>
            <field>
              <name>FB21</name>
              <bitOffset>21</bitOffset>
              <bitWidth>1</bitWidth>
            </field>
            <field>
              <name>FB22</name>
              <bitOffset>22</bitOffset>
              <bitWidth>1</bitWidth>
            </field>
            <field>
              <name>FB23</name>
              <bitOffset>23</bitOffset>
              <bitWidth>1</bitWidth>
            </field>
            <field>
              <name>FB24</name>
              <bitOffset>24</bitOffset>
              <bitWidth>1</bitWidth>
            </field>
            <field>
              <name>FB25</name>
              <bitOffset>25</bitOffset>
              <bitWidth>1</bitWidth>
            </field>
            <field>
              <name>FB26</name>
              <bitOffset>26</bitOffset>
              <bitWidth>1</bitWidth>
            </field>
            <field>
              <name>FB27</name>
              <bitOffset>27</bitOffset>
              <bitWidth>1</bitWidth>
            </field>
            <field>
              <name>FB28</name>
              <bitOffset>28</bitOffset>
              <bitWidth>1</bitWidth>
            </field>
            <field>
              <name>FB29</name>
              <bitOffset>29</bitOffset>
              <bitWidth>1</bitWidth>
            </field>
            <field>
              <name>FB30</name>
              <bitOffset>30</bitOffset>
              <bitWidth>1</bitWidth>
            </field>
            <field>
              <name>FB31</name>
              <bitOffset>31</bitOffset>
              <bitWidth>1</bitWidth>
            </field>
          </fields>
        </register>
        <register>
          <name>sFilterRegister.8.FR1</name>
          <addressOffset>0x280</addressOffset>
          <size>0x20</size>
          <fields>
            <field>
              <name>FB0</name>
              <bitOffset>0</bitOffset>
              <bitWidth>1</bitWidth>
            </field>
            <field>
              <name>FB1</name>
              <bitOffset>1</bitOffset>
              <bitWidth>1</bitWidth>
            </field>
            <field>
              <name>FB2</name>
              <bitOffset>2</bitOffset>
              <bitWidth>1</bitWidth>
            </field>
            <field>
              <name>FB3</name>
              <bitOffset>3</bitOffset>
              <bitWidth>1</bitWidth>
            </field>
            <field>
              <name>FB4</name>
              <bitOffset>4</bitOffset>
              <bitWidth>1</bitWidth>
            </field>
            <field>
              <name>FB5</name>
              <bitOffset>5</bitOffset>
              <bitWidth>1</bitWidth>
            </field>
            <field>
              <name>FB6</name>
              <bitOffset>6</bitOffset>
              <bitWidth>1</bitWidth>
            </field>
            <field>
              <name>FB7</name>
              <bitOffset>7</bitOffset>
              <bitWidth>1</bitWidth>
            </field>
            <field>
              <name>FB8</name>
              <bitOffset>8</bitOffset>
              <bitWidth>1</bitWidth>
            </field>
            <field>
              <name>FB9</name>
              <bitOffset>9</bitOffset>
              <bitWidth>1</bitWidth>
            </field>
            <field>
              <name>FB10</name>
              <bitOffset>10</bitOffset>
              <bitWidth>1</bitWidth>
            </field>
            <field>
              <name>FB11</name>
              <bitOffset>11</bitOffset>
              <bitWidth>1</bitWidth>
            </field>
            <field>
              <name>FB12</name>
              <bitOffset>12</bitOffset>
              <bitWidth>1</bitWidth>
            </field>
            <field>
              <name>FB13</name>
              <bitOffset>13</bitOffset>
              <bitWidth>1</bitWidth>
            </field>
            <field>
              <name>FB14</name>
              <bitOffset>14</bitOffset>
              <bitWidth>1</bitWidth>
            </field>
            <field>
              <name>FB15</name>
              <bitOffset>15</bitOffset>
              <bitWidth>1</bitWidth>
            </field>
            <field>
              <name>FB16</name>
              <bitOffset>16</bitOffset>
              <bitWidth>1</bitWidth>
            </field>
            <field>
              <name>FB17</name>
              <bitOffset>17</bitOffset>
              <bitWidth>1</bitWidth>
            </field>
            <field>
              <name>FB18</name>
              <bitOffset>18</bitOffset>
              <bitWidth>1</bitWidth>
            </field>
            <field>
              <name>FB19</name>
              <bitOffset>19</bitOffset>
              <bitWidth>1</bitWidth>
            </field>
            <field>
              <name>FB20</name>
              <bitOffset>20</bitOffset>
              <bitWidth>1</bitWidth>
            </field>
            <field>
              <name>FB21</name>
              <bitOffset>21</bitOffset>
              <bitWidth>1</bitWidth>
            </field>
            <field>
              <name>FB22</name>
              <bitOffset>22</bitOffset>
              <bitWidth>1</bitWidth>
            </field>
            <field>
              <name>FB23</name>
              <bitOffset>23</bitOffset>
              <bitWidth>1</bitWidth>
            </field>
            <field>
              <name>FB24</name>
              <bitOffset>24</bitOffset>
              <bitWidth>1</bitWidth>
            </field>
            <field>
              <name>FB25</name>
              <bitOffset>25</bitOffset>
              <bitWidth>1</bitWidth>
            </field>
            <field>
              <name>FB26</name>
              <bitOffset>26</bitOffset>
              <bitWidth>1</bitWidth>
            </field>
            <field>
              <name>FB27</name>
              <bitOffset>27</bitOffset>
              <bitWidth>1</bitWidth>
            </field>
            <field>
              <name>FB28</name>
              <bitOffset>28</bitOffset>
              <bitWidth>1</bitWidth>
            </field>
            <field>
              <name>FB29</name>
              <bitOffset>29</bitOffset>
              <bitWidth>1</bitWidth>
            </field>
            <field>
              <name>FB30</name>
              <bitOffset>30</bitOffset>
              <bitWidth>1</bitWidth>
            </field>
            <field>
              <name>FB31</name>
              <bitOffset>31</bitOffset>
              <bitWidth>1</bitWidth>
            </field>
          </fields>
        </register>
        <register>
          <name>sFilterRegister.8.FR2</name>
          <addressOffset>0x284</addressOffset>
          <size>0x20</size>
          <fields>
            <field>
              <name>FB0</name>
              <bitOffset>0</bitOffset>
              <bitWidth>1</bitWidth>
            </field>
            <field>
              <name>FB1</name>
              <bitOffset>1</bitOffset>
              <bitWidth>1</bitWidth>
            </field>
            <field>
              <name>FB2</name>
              <bitOffset>2</bitOffset>
              <bitWidth>1</bitWidth>
            </field>
            <field>
              <name>FB3</name>
              <bitOffset>3</bitOffset>
              <bitWidth>1</bitWidth>
            </field>
            <field>
              <name>FB4</name>
              <bitOffset>4</bitOffset>
              <bitWidth>1</bitWidth>
            </field>
            <field>
              <name>FB5</name>
              <bitOffset>5</bitOffset>
              <bitWidth>1</bitWidth>
            </field>
            <field>
              <name>FB6</name>
              <bitOffset>6</bitOffset>
              <bitWidth>1</bitWidth>
            </field>
            <field>
              <name>FB7</name>
              <bitOffset>7</bitOffset>
              <bitWidth>1</bitWidth>
            </field>
            <field>
              <name>FB8</name>
              <bitOffset>8</bitOffset>
              <bitWidth>1</bitWidth>
            </field>
            <field>
              <name>FB9</name>
              <bitOffset>9</bitOffset>
              <bitWidth>1</bitWidth>
            </field>
            <field>
              <name>FB10</name>
              <bitOffset>10</bitOffset>
              <bitWidth>1</bitWidth>
            </field>
            <field>
              <name>FB11</name>
              <bitOffset>11</bitOffset>
              <bitWidth>1</bitWidth>
            </field>
            <field>
              <name>FB12</name>
              <bitOffset>12</bitOffset>
              <bitWidth>1</bitWidth>
            </field>
            <field>
              <name>FB13</name>
              <bitOffset>13</bitOffset>
              <bitWidth>1</bitWidth>
            </field>
            <field>
              <name>FB14</name>
              <bitOffset>14</bitOffset>
              <bitWidth>1</bitWidth>
            </field>
            <field>
              <name>FB15</name>
              <bitOffset>15</bitOffset>
              <bitWidth>1</bitWidth>
            </field>
            <field>
              <name>FB16</name>
              <bitOffset>16</bitOffset>
              <bitWidth>1</bitWidth>
            </field>
            <field>
              <name>FB17</name>
              <bitOffset>17</bitOffset>
              <bitWidth>1</bitWidth>
            </field>
            <field>
              <name>FB18</name>
              <bitOffset>18</bitOffset>
              <bitWidth>1</bitWidth>
            </field>
            <field>
              <name>FB19</name>
              <bitOffset>19</bitOffset>
              <bitWidth>1</bitWidth>
            </field>
            <field>
              <name>FB20</name>
              <bitOffset>20</bitOffset>
              <bitWidth>1</bitWidth>
            </field>
            <field>
              <name>FB21</name>
              <bitOffset>21</bitOffset>
              <bitWidth>1</bitWidth>
            </field>
            <field>
              <name>FB22</name>
              <bitOffset>22</bitOffset>
              <bitWidth>1</bitWidth>
            </field>
            <field>
              <name>FB23</name>
              <bitOffset>23</bitOffset>
              <bitWidth>1</bitWidth>
            </field>
            <field>
              <name>FB24</name>
              <bitOffset>24</bitOffset>
              <bitWidth>1</bitWidth>
            </field>
            <field>
              <name>FB25</name>
              <bitOffset>25</bitOffset>
              <bitWidth>1</bitWidth>
            </field>
            <field>
              <name>FB26</name>
              <bitOffset>26</bitOffset>
              <bitWidth>1</bitWidth>
            </field>
            <field>
              <name>FB27</name>
              <bitOffset>27</bitOffset>
              <bitWidth>1</bitWidth>
            </field>
            <field>
              <name>FB28</name>
              <bitOffset>28</bitOffset>
              <bitWidth>1</bitWidth>
            </field>
            <field>
              <name>FB29</name>
              <bitOffset>29</bitOffset>
              <bitWidth>1</bitWidth>
            </field>
            <field>
              <name>FB30</name>
              <bitOffset>30</bitOffset>
              <bitWidth>1</bitWidth>
            </field>
            <field>
              <name>FB31</name>
              <bitOffset>31</bitOffset>
              <bitWidth>1</bitWidth>
            </field>
          </fields>
        </register>
        <register>
          <name>sFilterRegister.9.FR1</name>
          <addressOffset>0x288</addressOffset>
          <size>0x20</size>
          <fields>
            <field>
              <name>FB0</name>
              <bitOffset>0</bitOffset>
              <bitWidth>1</bitWidth>
            </field>
            <field>
              <name>FB1</name>
              <bitOffset>1</bitOffset>
              <bitWidth>1</bitWidth>
            </field>
            <field>
              <name>FB2</name>
              <bitOffset>2</bitOffset>
              <bitWidth>1</bitWidth>
            </field>
            <field>
              <name>FB3</name>
              <bitOffset>3</bitOffset>
              <bitWidth>1</bitWidth>
            </field>
            <field>
              <name>FB4</name>
              <bitOffset>4</bitOffset>
              <bitWidth>1</bitWidth>
            </field>
            <field>
              <name>FB5</name>
              <bitOffset>5</bitOffset>
              <bitWidth>1</bitWidth>
            </field>
            <field>
              <name>FB6</name>
              <bitOffset>6</bitOffset>
              <bitWidth>1</bitWidth>
            </field>
            <field>
              <name>FB7</name>
              <bitOffset>7</bitOffset>
              <bitWidth>1</bitWidth>
            </field>
            <field>
              <name>FB8</name>
              <bitOffset>8</bitOffset>
              <bitWidth>1</bitWidth>
            </field>
            <field>
              <name>FB9</name>
              <bitOffset>9</bitOffset>
              <bitWidth>1</bitWidth>
            </field>
            <field>
              <name>FB10</name>
              <bitOffset>10</bitOffset>
              <bitWidth>1</bitWidth>
            </field>
            <field>
              <name>FB11</name>
              <bitOffset>11</bitOffset>
              <bitWidth>1</bitWidth>
            </field>
            <field>
              <name>FB12</name>
              <bitOffset>12</bitOffset>
              <bitWidth>1</bitWidth>
            </field>
            <field>
              <name>FB13</name>
              <bitOffset>13</bitOffset>
              <bitWidth>1</bitWidth>
            </field>
            <field>
              <name>FB14</name>
              <bitOffset>14</bitOffset>
              <bitWidth>1</bitWidth>
            </field>
            <field>
              <name>FB15</name>
              <bitOffset>15</bitOffset>
              <bitWidth>1</bitWidth>
            </field>
            <field>
              <name>FB16</name>
              <bitOffset>16</bitOffset>
              <bitWidth>1</bitWidth>
            </field>
            <field>
              <name>FB17</name>
              <bitOffset>17</bitOffset>
              <bitWidth>1</bitWidth>
            </field>
            <field>
              <name>FB18</name>
              <bitOffset>18</bitOffset>
              <bitWidth>1</bitWidth>
            </field>
            <field>
              <name>FB19</name>
              <bitOffset>19</bitOffset>
              <bitWidth>1</bitWidth>
            </field>
            <field>
              <name>FB20</name>
              <bitOffset>20</bitOffset>
              <bitWidth>1</bitWidth>
            </field>
            <field>
              <name>FB21</name>
              <bitOffset>21</bitOffset>
              <bitWidth>1</bitWidth>
            </field>
            <field>
              <name>FB22</name>
              <bitOffset>22</bitOffset>
              <bitWidth>1</bitWidth>
            </field>
            <field>
              <name>FB23</name>
              <bitOffset>23</bitOffset>
              <bitWidth>1</bitWidth>
            </field>
            <field>
              <name>FB24</name>
              <bitOffset>24</bitOffset>
              <bitWidth>1</bitWidth>
            </field>
            <field>
              <name>FB25</name>
              <bitOffset>25</bitOffset>
              <bitWidth>1</bitWidth>
            </field>
            <field>
              <name>FB26</name>
              <bitOffset>26</bitOffset>
              <bitWidth>1</bitWidth>
            </field>
            <field>
              <name>FB27</name>
              <bitOffset>27</bitOffset>
              <bitWidth>1</bitWidth>
            </field>
            <field>
              <name>FB28</name>
              <bitOffset>28</bitOffset>
              <bitWidth>1</bitWidth>
            </field>
            <field>
              <name>FB29</name>
              <bitOffset>29</bitOffset>
              <bitWidth>1</bitWidth>
            </field>
            <field>
              <name>FB30</name>
              <bitOffset>30</bitOffset>
              <bitWidth>1</bitWidth>
            </field>
            <field>
              <name>FB31</name>
              <bitOffset>31</bitOffset>
              <bitWidth>1</bitWidth>
            </field>
          </fields>
        </register>
        <register>
          <name>sFilterRegister.9.FR2</name>
          <addressOffset>0x28c</addressOffset>
          <size>0x20</size>
          <fields>
            <field>
              <name>FB0</name>
              <bitOffset>0</bitOffset>
              <bitWidth>1</bitWidth>
            </field>
            <field>
              <name>FB1</name>
              <bitOffset>1</bitOffset>
              <bitWidth>1</bitWidth>
            </field>
            <field>
              <name>FB2</name>
              <bitOffset>2</bitOffset>
              <bitWidth>1</bitWidth>
            </field>
            <field>
              <name>FB3</name>
              <bitOffset>3</bitOffset>
              <bitWidth>1</bitWidth>
            </field>
            <field>
              <name>FB4</name>
              <bitOffset>4</bitOffset>
              <bitWidth>1</bitWidth>
            </field>
            <field>
              <name>FB5</name>
              <bitOffset>5</bitOffset>
              <bitWidth>1</bitWidth>
            </field>
            <field>
              <name>FB6</name>
              <bitOffset>6</bitOffset>
              <bitWidth>1</bitWidth>
            </field>
            <field>
              <name>FB7</name>
              <bitOffset>7</bitOffset>
              <bitWidth>1</bitWidth>
            </field>
            <field>
              <name>FB8</name>
              <bitOffset>8</bitOffset>
              <bitWidth>1</bitWidth>
            </field>
            <field>
              <name>FB9</name>
              <bitOffset>9</bitOffset>
              <bitWidth>1</bitWidth>
            </field>
            <field>
              <name>FB10</name>
              <bitOffset>10</bitOffset>
              <bitWidth>1</bitWidth>
            </field>
            <field>
              <name>FB11</name>
              <bitOffset>11</bitOffset>
              <bitWidth>1</bitWidth>
            </field>
            <field>
              <name>FB12</name>
              <bitOffset>12</bitOffset>
              <bitWidth>1</bitWidth>
            </field>
            <field>
              <name>FB13</name>
              <bitOffset>13</bitOffset>
              <bitWidth>1</bitWidth>
            </field>
            <field>
              <name>FB14</name>
              <bitOffset>14</bitOffset>
              <bitWidth>1</bitWidth>
            </field>
            <field>
              <name>FB15</name>
              <bitOffset>15</bitOffset>
              <bitWidth>1</bitWidth>
            </field>
            <field>
              <name>FB16</name>
              <bitOffset>16</bitOffset>
              <bitWidth>1</bitWidth>
            </field>
            <field>
              <name>FB17</name>
              <bitOffset>17</bitOffset>
              <bitWidth>1</bitWidth>
            </field>
            <field>
              <name>FB18</name>
              <bitOffset>18</bitOffset>
              <bitWidth>1</bitWidth>
            </field>
            <field>
              <name>FB19</name>
              <bitOffset>19</bitOffset>
              <bitWidth>1</bitWidth>
            </field>
            <field>
              <name>FB20</name>
              <bitOffset>20</bitOffset>
              <bitWidth>1</bitWidth>
            </field>
            <field>
              <name>FB21</name>
              <bitOffset>21</bitOffset>
              <bitWidth>1</bitWidth>
            </field>
            <field>
              <name>FB22</name>
              <bitOffset>22</bitOffset>
              <bitWidth>1</bitWidth>
            </field>
            <field>
              <name>FB23</name>
              <bitOffset>23</bitOffset>
              <bitWidth>1</bitWidth>
            </field>
            <field>
              <name>FB24</name>
              <bitOffset>24</bitOffset>
              <bitWidth>1</bitWidth>
            </field>
            <field>
              <name>FB25</name>
              <bitOffset>25</bitOffset>
              <bitWidth>1</bitWidth>
            </field>
            <field>
              <name>FB26</name>
              <bitOffset>26</bitOffset>
              <bitWidth>1</bitWidth>
            </field>
            <field>
              <name>FB27</name>
              <bitOffset>27</bitOffset>
              <bitWidth>1</bitWidth>
            </field>
            <field>
              <name>FB28</name>
              <bitOffset>28</bitOffset>
              <bitWidth>1</bitWidth>
            </field>
            <field>
              <name>FB29</name>
              <bitOffset>29</bitOffset>
              <bitWidth>1</bitWidth>
            </field>
            <field>
              <name>FB30</name>
              <bitOffset>30</bitOffset>
              <bitWidth>1</bitWidth>
            </field>
            <field>
              <name>FB31</name>
              <bitOffset>31</bitOffset>
              <bitWidth>1</bitWidth>
            </field>
          </fields>
        </register>
        <register>
          <name>sFilterRegister.10.FR1</name>
          <addressOffset>0x290</addressOffset>
          <size>0x20</size>
          <fields>
            <field>
              <name>FB0</name>
              <bitOffset>0</bitOffset>
              <bitWidth>1</bitWidth>
            </field>
            <field>
              <name>FB1</name>
              <bitOffset>1</bitOffset>
              <bitWidth>1</bitWidth>
            </field>
            <field>
              <name>FB2</name>
              <bitOffset>2</bitOffset>
              <bitWidth>1</bitWidth>
            </field>
            <field>
              <name>FB3</name>
              <bitOffset>3</bitOffset>
              <bitWidth>1</bitWidth>
            </field>
            <field>
              <name>FB4</name>
              <bitOffset>4</bitOffset>
              <bitWidth>1</bitWidth>
            </field>
            <field>
              <name>FB5</name>
              <bitOffset>5</bitOffset>
              <bitWidth>1</bitWidth>
            </field>
            <field>
              <name>FB6</name>
              <bitOffset>6</bitOffset>
              <bitWidth>1</bitWidth>
            </field>
            <field>
              <name>FB7</name>
              <bitOffset>7</bitOffset>
              <bitWidth>1</bitWidth>
            </field>
            <field>
              <name>FB8</name>
              <bitOffset>8</bitOffset>
              <bitWidth>1</bitWidth>
            </field>
            <field>
              <name>FB9</name>
              <bitOffset>9</bitOffset>
              <bitWidth>1</bitWidth>
            </field>
            <field>
              <name>FB10</name>
              <bitOffset>10</bitOffset>
              <bitWidth>1</bitWidth>
            </field>
            <field>
              <name>FB11</name>
              <bitOffset>11</bitOffset>
              <bitWidth>1</bitWidth>
            </field>
            <field>
              <name>FB12</name>
              <bitOffset>12</bitOffset>
              <bitWidth>1</bitWidth>
            </field>
            <field>
              <name>FB13</name>
              <bitOffset>13</bitOffset>
              <bitWidth>1</bitWidth>
            </field>
            <field>
              <name>FB14</name>
              <bitOffset>14</bitOffset>
              <bitWidth>1</bitWidth>
            </field>
            <field>
              <name>FB15</name>
              <bitOffset>15</bitOffset>
              <bitWidth>1</bitWidth>
            </field>
            <field>
              <name>FB16</name>
              <bitOffset>16</bitOffset>
              <bitWidth>1</bitWidth>
            </field>
            <field>
              <name>FB17</name>
              <bitOffset>17</bitOffset>
              <bitWidth>1</bitWidth>
            </field>
            <field>
              <name>FB18</name>
              <bitOffset>18</bitOffset>
              <bitWidth>1</bitWidth>
            </field>
            <field>
              <name>FB19</name>
              <bitOffset>19</bitOffset>
              <bitWidth>1</bitWidth>
            </field>
            <field>
              <name>FB20</name>
              <bitOffset>20</bitOffset>
              <bitWidth>1</bitWidth>
            </field>
            <field>
              <name>FB21</name>
              <bitOffset>21</bitOffset>
              <bitWidth>1</bitWidth>
            </field>
            <field>
              <name>FB22</name>
              <bitOffset>22</bitOffset>
              <bitWidth>1</bitWidth>
            </field>
            <field>
              <name>FB23</name>
              <bitOffset>23</bitOffset>
              <bitWidth>1</bitWidth>
            </field>
            <field>
              <name>FB24</name>
              <bitOffset>24</bitOffset>
              <bitWidth>1</bitWidth>
            </field>
            <field>
              <name>FB25</name>
              <bitOffset>25</bitOffset>
              <bitWidth>1</bitWidth>
            </field>
            <field>
              <name>FB26</name>
              <bitOffset>26</bitOffset>
              <bitWidth>1</bitWidth>
            </field>
            <field>
              <name>FB27</name>
              <bitOffset>27</bitOffset>
              <bitWidth>1</bitWidth>
            </field>
            <field>
              <name>FB28</name>
              <bitOffset>28</bitOffset>
              <bitWidth>1</bitWidth>
            </field>
            <field>
              <name>FB29</name>
              <bitOffset>29</bitOffset>
              <bitWidth>1</bitWidth>
            </field>
            <field>
              <name>FB30</name>
              <bitOffset>30</bitOffset>
              <bitWidth>1</bitWidth>
            </field>
            <field>
              <name>FB31</name>
              <bitOffset>31</bitOffset>
              <bitWidth>1</bitWidth>
            </field>
          </fields>
        </register>
        <register>
          <name>sFilterRegister.10.FR2</name>
          <addressOffset>0x294</addressOffset>
          <size>0x20</size>
          <fields>
            <field>
              <name>FB0</name>
              <bitOffset>0</bitOffset>
              <bitWidth>1</bitWidth>
            </field>
            <field>
              <name>FB1</name>
              <bitOffset>1</bitOffset>
              <bitWidth>1</bitWidth>
            </field>
            <field>
              <name>FB2</name>
              <bitOffset>2</bitOffset>
              <bitWidth>1</bitWidth>
            </field>
            <field>
              <name>FB3</name>
              <bitOffset>3</bitOffset>
              <bitWidth>1</bitWidth>
            </field>
            <field>
              <name>FB4</name>
              <bitOffset>4</bitOffset>
              <bitWidth>1</bitWidth>
            </field>
            <field>
              <name>FB5</name>
              <bitOffset>5</bitOffset>
              <bitWidth>1</bitWidth>
            </field>
            <field>
              <name>FB6</name>
              <bitOffset>6</bitOffset>
              <bitWidth>1</bitWidth>
            </field>
            <field>
              <name>FB7</name>
              <bitOffset>7</bitOffset>
              <bitWidth>1</bitWidth>
            </field>
            <field>
              <name>FB8</name>
              <bitOffset>8</bitOffset>
              <bitWidth>1</bitWidth>
            </field>
            <field>
              <name>FB9</name>
              <bitOffset>9</bitOffset>
              <bitWidth>1</bitWidth>
            </field>
            <field>
              <name>FB10</name>
              <bitOffset>10</bitOffset>
              <bitWidth>1</bitWidth>
            </field>
            <field>
              <name>FB11</name>
              <bitOffset>11</bitOffset>
              <bitWidth>1</bitWidth>
            </field>
            <field>
              <name>FB12</name>
              <bitOffset>12</bitOffset>
              <bitWidth>1</bitWidth>
            </field>
            <field>
              <name>FB13</name>
              <bitOffset>13</bitOffset>
              <bitWidth>1</bitWidth>
            </field>
            <field>
              <name>FB14</name>
              <bitOffset>14</bitOffset>
              <bitWidth>1</bitWidth>
            </field>
            <field>
              <name>FB15</name>
              <bitOffset>15</bitOffset>
              <bitWidth>1</bitWidth>
            </field>
            <field>
              <name>FB16</name>
              <bitOffset>16</bitOffset>
              <bitWidth>1</bitWidth>
            </field>
            <field>
              <name>FB17</name>
              <bitOffset>17</bitOffset>
              <bitWidth>1</bitWidth>
            </field>
            <field>
              <name>FB18</name>
              <bitOffset>18</bitOffset>
              <bitWidth>1</bitWidth>
            </field>
            <field>
              <name>FB19</name>
              <bitOffset>19</bitOffset>
              <bitWidth>1</bitWidth>
            </field>
            <field>
              <name>FB20</name>
              <bitOffset>20</bitOffset>
              <bitWidth>1</bitWidth>
            </field>
            <field>
              <name>FB21</name>
              <bitOffset>21</bitOffset>
              <bitWidth>1</bitWidth>
            </field>
            <field>
              <name>FB22</name>
              <bitOffset>22</bitOffset>
              <bitWidth>1</bitWidth>
            </field>
            <field>
              <name>FB23</name>
              <bitOffset>23</bitOffset>
              <bitWidth>1</bitWidth>
            </field>
            <field>
              <name>FB24</name>
              <bitOffset>24</bitOffset>
              <bitWidth>1</bitWidth>
            </field>
            <field>
              <name>FB25</name>
              <bitOffset>25</bitOffset>
              <bitWidth>1</bitWidth>
            </field>
            <field>
              <name>FB26</name>
              <bitOffset>26</bitOffset>
              <bitWidth>1</bitWidth>
            </field>
            <field>
              <name>FB27</name>
              <bitOffset>27</bitOffset>
              <bitWidth>1</bitWidth>
            </field>
            <field>
              <name>FB28</name>
              <bitOffset>28</bitOffset>
              <bitWidth>1</bitWidth>
            </field>
            <field>
              <name>FB29</name>
              <bitOffset>29</bitOffset>
              <bitWidth>1</bitWidth>
            </field>
            <field>
              <name>FB30</name>
              <bitOffset>30</bitOffset>
              <bitWidth>1</bitWidth>
            </field>
            <field>
              <name>FB31</name>
              <bitOffset>31</bitOffset>
              <bitWidth>1</bitWidth>
            </field>
          </fields>
        </register>
        <register>
          <name>sFilterRegister.11.FR1</name>
          <addressOffset>0x298</addressOffset>
          <size>0x20</size>
          <fields>
            <field>
              <name>FB0</name>
              <bitOffset>0</bitOffset>
              <bitWidth>1</bitWidth>
            </field>
            <field>
              <name>FB1</name>
              <bitOffset>1</bitOffset>
              <bitWidth>1</bitWidth>
            </field>
            <field>
              <name>FB2</name>
              <bitOffset>2</bitOffset>
              <bitWidth>1</bitWidth>
            </field>
            <field>
              <name>FB3</name>
              <bitOffset>3</bitOffset>
              <bitWidth>1</bitWidth>
            </field>
            <field>
              <name>FB4</name>
              <bitOffset>4</bitOffset>
              <bitWidth>1</bitWidth>
            </field>
            <field>
              <name>FB5</name>
              <bitOffset>5</bitOffset>
              <bitWidth>1</bitWidth>
            </field>
            <field>
              <name>FB6</name>
              <bitOffset>6</bitOffset>
              <bitWidth>1</bitWidth>
            </field>
            <field>
              <name>FB7</name>
              <bitOffset>7</bitOffset>
              <bitWidth>1</bitWidth>
            </field>
            <field>
              <name>FB8</name>
              <bitOffset>8</bitOffset>
              <bitWidth>1</bitWidth>
            </field>
            <field>
              <name>FB9</name>
              <bitOffset>9</bitOffset>
              <bitWidth>1</bitWidth>
            </field>
            <field>
              <name>FB10</name>
              <bitOffset>10</bitOffset>
              <bitWidth>1</bitWidth>
            </field>
            <field>
              <name>FB11</name>
              <bitOffset>11</bitOffset>
              <bitWidth>1</bitWidth>
            </field>
            <field>
              <name>FB12</name>
              <bitOffset>12</bitOffset>
              <bitWidth>1</bitWidth>
            </field>
            <field>
              <name>FB13</name>
              <bitOffset>13</bitOffset>
              <bitWidth>1</bitWidth>
            </field>
            <field>
              <name>FB14</name>
              <bitOffset>14</bitOffset>
              <bitWidth>1</bitWidth>
            </field>
            <field>
              <name>FB15</name>
              <bitOffset>15</bitOffset>
              <bitWidth>1</bitWidth>
            </field>
            <field>
              <name>FB16</name>
              <bitOffset>16</bitOffset>
              <bitWidth>1</bitWidth>
            </field>
            <field>
              <name>FB17</name>
              <bitOffset>17</bitOffset>
              <bitWidth>1</bitWidth>
            </field>
            <field>
              <name>FB18</name>
              <bitOffset>18</bitOffset>
              <bitWidth>1</bitWidth>
            </field>
            <field>
              <name>FB19</name>
              <bitOffset>19</bitOffset>
              <bitWidth>1</bitWidth>
            </field>
            <field>
              <name>FB20</name>
              <bitOffset>20</bitOffset>
              <bitWidth>1</bitWidth>
            </field>
            <field>
              <name>FB21</name>
              <bitOffset>21</bitOffset>
              <bitWidth>1</bitWidth>
            </field>
            <field>
              <name>FB22</name>
              <bitOffset>22</bitOffset>
              <bitWidth>1</bitWidth>
            </field>
            <field>
              <name>FB23</name>
              <bitOffset>23</bitOffset>
              <bitWidth>1</bitWidth>
            </field>
            <field>
              <name>FB24</name>
              <bitOffset>24</bitOffset>
              <bitWidth>1</bitWidth>
            </field>
            <field>
              <name>FB25</name>
              <bitOffset>25</bitOffset>
              <bitWidth>1</bitWidth>
            </field>
            <field>
              <name>FB26</name>
              <bitOffset>26</bitOffset>
              <bitWidth>1</bitWidth>
            </field>
            <field>
              <name>FB27</name>
              <bitOffset>27</bitOffset>
              <bitWidth>1</bitWidth>
            </field>
            <field>
              <name>FB28</name>
              <bitOffset>28</bitOffset>
              <bitWidth>1</bitWidth>
            </field>
            <field>
              <name>FB29</name>
              <bitOffset>29</bitOffset>
              <bitWidth>1</bitWidth>
            </field>
            <field>
              <name>FB30</name>
              <bitOffset>30</bitOffset>
              <bitWidth>1</bitWidth>
            </field>
            <field>
              <name>FB31</name>
              <bitOffset>31</bitOffset>
              <bitWidth>1</bitWidth>
            </field>
          </fields>
        </register>
        <register>
          <name>sFilterRegister.11.FR2</name>
          <addressOffset>0x29c</addressOffset>
          <size>0x20</size>
          <fields>
            <field>
              <name>FB0</name>
              <bitOffset>0</bitOffset>
              <bitWidth>1</bitWidth>
            </field>
            <field>
              <name>FB1</name>
              <bitOffset>1</bitOffset>
              <bitWidth>1</bitWidth>
            </field>
            <field>
              <name>FB2</name>
              <bitOffset>2</bitOffset>
              <bitWidth>1</bitWidth>
            </field>
            <field>
              <name>FB3</name>
              <bitOffset>3</bitOffset>
              <bitWidth>1</bitWidth>
            </field>
            <field>
              <name>FB4</name>
              <bitOffset>4</bitOffset>
              <bitWidth>1</bitWidth>
            </field>
            <field>
              <name>FB5</name>
              <bitOffset>5</bitOffset>
              <bitWidth>1</bitWidth>
            </field>
            <field>
              <name>FB6</name>
              <bitOffset>6</bitOffset>
              <bitWidth>1</bitWidth>
            </field>
            <field>
              <name>FB7</name>
              <bitOffset>7</bitOffset>
              <bitWidth>1</bitWidth>
            </field>
            <field>
              <name>FB8</name>
              <bitOffset>8</bitOffset>
              <bitWidth>1</bitWidth>
            </field>
            <field>
              <name>FB9</name>
              <bitOffset>9</bitOffset>
              <bitWidth>1</bitWidth>
            </field>
            <field>
              <name>FB10</name>
              <bitOffset>10</bitOffset>
              <bitWidth>1</bitWidth>
            </field>
            <field>
              <name>FB11</name>
              <bitOffset>11</bitOffset>
              <bitWidth>1</bitWidth>
            </field>
            <field>
              <name>FB12</name>
              <bitOffset>12</bitOffset>
              <bitWidth>1</bitWidth>
            </field>
            <field>
              <name>FB13</name>
              <bitOffset>13</bitOffset>
              <bitWidth>1</bitWidth>
            </field>
            <field>
              <name>FB14</name>
              <bitOffset>14</bitOffset>
              <bitWidth>1</bitWidth>
            </field>
            <field>
              <name>FB15</name>
              <bitOffset>15</bitOffset>
              <bitWidth>1</bitWidth>
            </field>
            <field>
              <name>FB16</name>
              <bitOffset>16</bitOffset>
              <bitWidth>1</bitWidth>
            </field>
            <field>
              <name>FB17</name>
              <bitOffset>17</bitOffset>
              <bitWidth>1</bitWidth>
            </field>
            <field>
              <name>FB18</name>
              <bitOffset>18</bitOffset>
              <bitWidth>1</bitWidth>
            </field>
            <field>
              <name>FB19</name>
              <bitOffset>19</bitOffset>
              <bitWidth>1</bitWidth>
            </field>
            <field>
              <name>FB20</name>
              <bitOffset>20</bitOffset>
              <bitWidth>1</bitWidth>
            </field>
            <field>
              <name>FB21</name>
              <bitOffset>21</bitOffset>
              <bitWidth>1</bitWidth>
            </field>
            <field>
              <name>FB22</name>
              <bitOffset>22</bitOffset>
              <bitWidth>1</bitWidth>
            </field>
            <field>
              <name>FB23</name>
              <bitOffset>23</bitOffset>
              <bitWidth>1</bitWidth>
            </field>
            <field>
              <name>FB24</name>
              <bitOffset>24</bitOffset>
              <bitWidth>1</bitWidth>
            </field>
            <field>
              <name>FB25</name>
              <bitOffset>25</bitOffset>
              <bitWidth>1</bitWidth>
            </field>
            <field>
              <name>FB26</name>
              <bitOffset>26</bitOffset>
              <bitWidth>1</bitWidth>
            </field>
            <field>
              <name>FB27</name>
              <bitOffset>27</bitOffset>
              <bitWidth>1</bitWidth>
            </field>
            <field>
              <name>FB28</name>
              <bitOffset>28</bitOffset>
              <bitWidth>1</bitWidth>
            </field>
            <field>
              <name>FB29</name>
              <bitOffset>29</bitOffset>
              <bitWidth>1</bitWidth>
            </field>
            <field>
              <name>FB30</name>
              <bitOffset>30</bitOffset>
              <bitWidth>1</bitWidth>
            </field>
            <field>
              <name>FB31</name>
              <bitOffset>31</bitOffset>
              <bitWidth>1</bitWidth>
            </field>
          </fields>
        </register>
        <register>
          <name>sFilterRegister.12.FR1</name>
          <addressOffset>0x2a0</addressOffset>
          <size>0x20</size>
          <fields>
            <field>
              <name>FB0</name>
              <bitOffset>0</bitOffset>
              <bitWidth>1</bitWidth>
            </field>
            <field>
              <name>FB1</name>
              <bitOffset>1</bitOffset>
              <bitWidth>1</bitWidth>
            </field>
            <field>
              <name>FB2</name>
              <bitOffset>2</bitOffset>
              <bitWidth>1</bitWidth>
            </field>
            <field>
              <name>FB3</name>
              <bitOffset>3</bitOffset>
              <bitWidth>1</bitWidth>
            </field>
            <field>
              <name>FB4</name>
              <bitOffset>4</bitOffset>
              <bitWidth>1</bitWidth>
            </field>
            <field>
              <name>FB5</name>
              <bitOffset>5</bitOffset>
              <bitWidth>1</bitWidth>
            </field>
            <field>
              <name>FB6</name>
              <bitOffset>6</bitOffset>
              <bitWidth>1</bitWidth>
            </field>
            <field>
              <name>FB7</name>
              <bitOffset>7</bitOffset>
              <bitWidth>1</bitWidth>
            </field>
            <field>
              <name>FB8</name>
              <bitOffset>8</bitOffset>
              <bitWidth>1</bitWidth>
            </field>
            <field>
              <name>FB9</name>
              <bitOffset>9</bitOffset>
              <bitWidth>1</bitWidth>
            </field>
            <field>
              <name>FB10</name>
              <bitOffset>10</bitOffset>
              <bitWidth>1</bitWidth>
            </field>
            <field>
              <name>FB11</name>
              <bitOffset>11</bitOffset>
              <bitWidth>1</bitWidth>
            </field>
            <field>
              <name>FB12</name>
              <bitOffset>12</bitOffset>
              <bitWidth>1</bitWidth>
            </field>
            <field>
              <name>FB13</name>
              <bitOffset>13</bitOffset>
              <bitWidth>1</bitWidth>
            </field>
            <field>
              <name>FB14</name>
              <bitOffset>14</bitOffset>
              <bitWidth>1</bitWidth>
            </field>
            <field>
              <name>FB15</name>
              <bitOffset>15</bitOffset>
              <bitWidth>1</bitWidth>
            </field>
            <field>
              <name>FB16</name>
              <bitOffset>16</bitOffset>
              <bitWidth>1</bitWidth>
            </field>
            <field>
              <name>FB17</name>
              <bitOffset>17</bitOffset>
              <bitWidth>1</bitWidth>
            </field>
            <field>
              <name>FB18</name>
              <bitOffset>18</bitOffset>
              <bitWidth>1</bitWidth>
            </field>
            <field>
              <name>FB19</name>
              <bitOffset>19</bitOffset>
              <bitWidth>1</bitWidth>
            </field>
            <field>
              <name>FB20</name>
              <bitOffset>20</bitOffset>
              <bitWidth>1</bitWidth>
            </field>
            <field>
              <name>FB21</name>
              <bitOffset>21</bitOffset>
              <bitWidth>1</bitWidth>
            </field>
            <field>
              <name>FB22</name>
              <bitOffset>22</bitOffset>
              <bitWidth>1</bitWidth>
            </field>
            <field>
              <name>FB23</name>
              <bitOffset>23</bitOffset>
              <bitWidth>1</bitWidth>
            </field>
            <field>
              <name>FB24</name>
              <bitOffset>24</bitOffset>
              <bitWidth>1</bitWidth>
            </field>
            <field>
              <name>FB25</name>
              <bitOffset>25</bitOffset>
              <bitWidth>1</bitWidth>
            </field>
            <field>
              <name>FB26</name>
              <bitOffset>26</bitOffset>
              <bitWidth>1</bitWidth>
            </field>
            <field>
              <name>FB27</name>
              <bitOffset>27</bitOffset>
              <bitWidth>1</bitWidth>
            </field>
            <field>
              <name>FB28</name>
              <bitOffset>28</bitOffset>
              <bitWidth>1</bitWidth>
            </field>
            <field>
              <name>FB29</name>
              <bitOffset>29</bitOffset>
              <bitWidth>1</bitWidth>
            </field>
            <field>
              <name>FB30</name>
              <bitOffset>30</bitOffset>
              <bitWidth>1</bitWidth>
            </field>
            <field>
              <name>FB31</name>
              <bitOffset>31</bitOffset>
              <bitWidth>1</bitWidth>
            </field>
          </fields>
        </register>
        <register>
          <name>sFilterRegister.12.FR2</name>
          <addressOffset>0x2a4</addressOffset>
          <size>0x20</size>
          <fields>
            <field>
              <name>FB0</name>
              <bitOffset>0</bitOffset>
              <bitWidth>1</bitWidth>
            </field>
            <field>
              <name>FB1</name>
              <bitOffset>1</bitOffset>
              <bitWidth>1</bitWidth>
            </field>
            <field>
              <name>FB2</name>
              <bitOffset>2</bitOffset>
              <bitWidth>1</bitWidth>
            </field>
            <field>
              <name>FB3</name>
              <bitOffset>3</bitOffset>
              <bitWidth>1</bitWidth>
            </field>
            <field>
              <name>FB4</name>
              <bitOffset>4</bitOffset>
              <bitWidth>1</bitWidth>
            </field>
            <field>
              <name>FB5</name>
              <bitOffset>5</bitOffset>
              <bitWidth>1</bitWidth>
            </field>
            <field>
              <name>FB6</name>
              <bitOffset>6</bitOffset>
              <bitWidth>1</bitWidth>
            </field>
            <field>
              <name>FB7</name>
              <bitOffset>7</bitOffset>
              <bitWidth>1</bitWidth>
            </field>
            <field>
              <name>FB8</name>
              <bitOffset>8</bitOffset>
              <bitWidth>1</bitWidth>
            </field>
            <field>
              <name>FB9</name>
              <bitOffset>9</bitOffset>
              <bitWidth>1</bitWidth>
            </field>
            <field>
              <name>FB10</name>
              <bitOffset>10</bitOffset>
              <bitWidth>1</bitWidth>
            </field>
            <field>
              <name>FB11</name>
              <bitOffset>11</bitOffset>
              <bitWidth>1</bitWidth>
            </field>
            <field>
              <name>FB12</name>
              <bitOffset>12</bitOffset>
              <bitWidth>1</bitWidth>
            </field>
            <field>
              <name>FB13</name>
              <bitOffset>13</bitOffset>
              <bitWidth>1</bitWidth>
            </field>
            <field>
              <name>FB14</name>
              <bitOffset>14</bitOffset>
              <bitWidth>1</bitWidth>
            </field>
            <field>
              <name>FB15</name>
              <bitOffset>15</bitOffset>
              <bitWidth>1</bitWidth>
            </field>
            <field>
              <name>FB16</name>
              <bitOffset>16</bitOffset>
              <bitWidth>1</bitWidth>
            </field>
            <field>
              <name>FB17</name>
              <bitOffset>17</bitOffset>
              <bitWidth>1</bitWidth>
            </field>
            <field>
              <name>FB18</name>
              <bitOffset>18</bitOffset>
              <bitWidth>1</bitWidth>
            </field>
            <field>
              <name>FB19</name>
              <bitOffset>19</bitOffset>
              <bitWidth>1</bitWidth>
            </field>
            <field>
              <name>FB20</name>
              <bitOffset>20</bitOffset>
              <bitWidth>1</bitWidth>
            </field>
            <field>
              <name>FB21</name>
              <bitOffset>21</bitOffset>
              <bitWidth>1</bitWidth>
            </field>
            <field>
              <name>FB22</name>
              <bitOffset>22</bitOffset>
              <bitWidth>1</bitWidth>
            </field>
            <field>
              <name>FB23</name>
              <bitOffset>23</bitOffset>
              <bitWidth>1</bitWidth>
            </field>
            <field>
              <name>FB24</name>
              <bitOffset>24</bitOffset>
              <bitWidth>1</bitWidth>
            </field>
            <field>
              <name>FB25</name>
              <bitOffset>25</bitOffset>
              <bitWidth>1</bitWidth>
            </field>
            <field>
              <name>FB26</name>
              <bitOffset>26</bitOffset>
              <bitWidth>1</bitWidth>
            </field>
            <field>
              <name>FB27</name>
              <bitOffset>27</bitOffset>
              <bitWidth>1</bitWidth>
            </field>
            <field>
              <name>FB28</name>
              <bitOffset>28</bitOffset>
              <bitWidth>1</bitWidth>
            </field>
            <field>
              <name>FB29</name>
              <bitOffset>29</bitOffset>
              <bitWidth>1</bitWidth>
            </field>
            <field>
              <name>FB30</name>
              <bitOffset>30</bitOffset>
              <bitWidth>1</bitWidth>
            </field>
            <field>
              <name>FB31</name>
              <bitOffset>31</bitOffset>
              <bitWidth>1</bitWidth>
            </field>
          </fields>
        </register>
        <register>
          <name>sFilterRegister.13.FR1</name>
          <addressOffset>0x2a8</addressOffset>
          <size>0x20</size>
          <fields>
            <field>
              <name>FB0</name>
              <bitOffset>0</bitOffset>
              <bitWidth>1</bitWidth>
            </field>
            <field>
              <name>FB1</name>
              <bitOffset>1</bitOffset>
              <bitWidth>1</bitWidth>
            </field>
            <field>
              <name>FB2</name>
              <bitOffset>2</bitOffset>
              <bitWidth>1</bitWidth>
            </field>
            <field>
              <name>FB3</name>
              <bitOffset>3</bitOffset>
              <bitWidth>1</bitWidth>
            </field>
            <field>
              <name>FB4</name>
              <bitOffset>4</bitOffset>
              <bitWidth>1</bitWidth>
            </field>
            <field>
              <name>FB5</name>
              <bitOffset>5</bitOffset>
              <bitWidth>1</bitWidth>
            </field>
            <field>
              <name>FB6</name>
              <bitOffset>6</bitOffset>
              <bitWidth>1</bitWidth>
            </field>
            <field>
              <name>FB7</name>
              <bitOffset>7</bitOffset>
              <bitWidth>1</bitWidth>
            </field>
            <field>
              <name>FB8</name>
              <bitOffset>8</bitOffset>
              <bitWidth>1</bitWidth>
            </field>
            <field>
              <name>FB9</name>
              <bitOffset>9</bitOffset>
              <bitWidth>1</bitWidth>
            </field>
            <field>
              <name>FB10</name>
              <bitOffset>10</bitOffset>
              <bitWidth>1</bitWidth>
            </field>
            <field>
              <name>FB11</name>
              <bitOffset>11</bitOffset>
              <bitWidth>1</bitWidth>
            </field>
            <field>
              <name>FB12</name>
              <bitOffset>12</bitOffset>
              <bitWidth>1</bitWidth>
            </field>
            <field>
              <name>FB13</name>
              <bitOffset>13</bitOffset>
              <bitWidth>1</bitWidth>
            </field>
            <field>
              <name>FB14</name>
              <bitOffset>14</bitOffset>
              <bitWidth>1</bitWidth>
            </field>
            <field>
              <name>FB15</name>
              <bitOffset>15</bitOffset>
              <bitWidth>1</bitWidth>
            </field>
            <field>
              <name>FB16</name>
              <bitOffset>16</bitOffset>
              <bitWidth>1</bitWidth>
            </field>
            <field>
              <name>FB17</name>
              <bitOffset>17</bitOffset>
              <bitWidth>1</bitWidth>
            </field>
            <field>
              <name>FB18</name>
              <bitOffset>18</bitOffset>
              <bitWidth>1</bitWidth>
            </field>
            <field>
              <name>FB19</name>
              <bitOffset>19</bitOffset>
              <bitWidth>1</bitWidth>
            </field>
            <field>
              <name>FB20</name>
              <bitOffset>20</bitOffset>
              <bitWidth>1</bitWidth>
            </field>
            <field>
              <name>FB21</name>
              <bitOffset>21</bitOffset>
              <bitWidth>1</bitWidth>
            </field>
            <field>
              <name>FB22</name>
              <bitOffset>22</bitOffset>
              <bitWidth>1</bitWidth>
            </field>
            <field>
              <name>FB23</name>
              <bitOffset>23</bitOffset>
              <bitWidth>1</bitWidth>
            </field>
            <field>
              <name>FB24</name>
              <bitOffset>24</bitOffset>
              <bitWidth>1</bitWidth>
            </field>
            <field>
              <name>FB25</name>
              <bitOffset>25</bitOffset>
              <bitWidth>1</bitWidth>
            </field>
            <field>
              <name>FB26</name>
              <bitOffset>26</bitOffset>
              <bitWidth>1</bitWidth>
            </field>
            <field>
              <name>FB27</name>
              <bitOffset>27</bitOffset>
              <bitWidth>1</bitWidth>
            </field>
            <field>
              <name>FB28</name>
              <bitOffset>28</bitOffset>
              <bitWidth>1</bitWidth>
            </field>
            <field>
              <name>FB29</name>
              <bitOffset>29</bitOffset>
              <bitWidth>1</bitWidth>
            </field>
            <field>
              <name>FB30</name>
              <bitOffset>30</bitOffset>
              <bitWidth>1</bitWidth>
            </field>
            <field>
              <name>FB31</name>
              <bitOffset>31</bitOffset>
              <bitWidth>1</bitWidth>
            </field>
          </fields>
        </register>
        <register>
          <name>sFilterRegister.13.FR2</name>
          <addressOffset>0x2ac</addressOffset>
          <size>0x20</size>
          <fields>
            <field>
              <name>FB0</name>
              <bitOffset>0</bitOffset>
              <bitWidth>1</bitWidth>
            </field>
            <field>
              <name>FB1</name>
              <bitOffset>1</bitOffset>
              <bitWidth>1</bitWidth>
            </field>
            <field>
              <name>FB2</name>
              <bitOffset>2</bitOffset>
              <bitWidth>1</bitWidth>
            </field>
            <field>
              <name>FB3</name>
              <bitOffset>3</bitOffset>
              <bitWidth>1</bitWidth>
            </field>
            <field>
              <name>FB4</name>
              <bitOffset>4</bitOffset>
              <bitWidth>1</bitWidth>
            </field>
            <field>
              <name>FB5</name>
              <bitOffset>5</bitOffset>
              <bitWidth>1</bitWidth>
            </field>
            <field>
              <name>FB6</name>
              <bitOffset>6</bitOffset>
              <bitWidth>1</bitWidth>
            </field>
            <field>
              <name>FB7</name>
              <bitOffset>7</bitOffset>
              <bitWidth>1</bitWidth>
            </field>
            <field>
              <name>FB8</name>
              <bitOffset>8</bitOffset>
              <bitWidth>1</bitWidth>
            </field>
            <field>
              <name>FB9</name>
              <bitOffset>9</bitOffset>
              <bitWidth>1</bitWidth>
            </field>
            <field>
              <name>FB10</name>
              <bitOffset>10</bitOffset>
              <bitWidth>1</bitWidth>
            </field>
            <field>
              <name>FB11</name>
              <bitOffset>11</bitOffset>
              <bitWidth>1</bitWidth>
            </field>
            <field>
              <name>FB12</name>
              <bitOffset>12</bitOffset>
              <bitWidth>1</bitWidth>
            </field>
            <field>
              <name>FB13</name>
              <bitOffset>13</bitOffset>
              <bitWidth>1</bitWidth>
            </field>
            <field>
              <name>FB14</name>
              <bitOffset>14</bitOffset>
              <bitWidth>1</bitWidth>
            </field>
            <field>
              <name>FB15</name>
              <bitOffset>15</bitOffset>
              <bitWidth>1</bitWidth>
            </field>
            <field>
              <name>FB16</name>
              <bitOffset>16</bitOffset>
              <bitWidth>1</bitWidth>
            </field>
            <field>
              <name>FB17</name>
              <bitOffset>17</bitOffset>
              <bitWidth>1</bitWidth>
            </field>
            <field>
              <name>FB18</name>
              <bitOffset>18</bitOffset>
              <bitWidth>1</bitWidth>
            </field>
            <field>
              <name>FB19</name>
              <bitOffset>19</bitOffset>
              <bitWidth>1</bitWidth>
            </field>
            <field>
              <name>FB20</name>
              <bitOffset>20</bitOffset>
              <bitWidth>1</bitWidth>
            </field>
            <field>
              <name>FB21</name>
              <bitOffset>21</bitOffset>
              <bitWidth>1</bitWidth>
            </field>
            <field>
              <name>FB22</name>
              <bitOffset>22</bitOffset>
              <bitWidth>1</bitWidth>
            </field>
            <field>
              <name>FB23</name>
              <bitOffset>23</bitOffset>
              <bitWidth>1</bitWidth>
            </field>
            <field>
              <name>FB24</name>
              <bitOffset>24</bitOffset>
              <bitWidth>1</bitWidth>
            </field>
            <field>
              <name>FB25</name>
              <bitOffset>25</bitOffset>
              <bitWidth>1</bitWidth>
            </field>
            <field>
              <name>FB26</name>
              <bitOffset>26</bitOffset>
              <bitWidth>1</bitWidth>
            </field>
            <field>
              <name>FB27</name>
              <bitOffset>27</bitOffset>
              <bitWidth>1</bitWidth>
            </field>
            <field>
              <name>FB28</name>
              <bitOffset>28</bitOffset>
              <bitWidth>1</bitWidth>
            </field>
            <field>
              <name>FB29</name>
              <bitOffset>29</bitOffset>
              <bitWidth>1</bitWidth>
            </field>
            <field>
              <name>FB30</name>
              <bitOffset>30</bitOffset>
              <bitWidth>1</bitWidth>
            </field>
            <field>
              <name>FB31</name>
              <bitOffset>31</bitOffset>
              <bitWidth>1</bitWidth>
            </field>
          </fields>
        </register>
        <register>
          <name>sFilterRegister.14.FR1</name>
          <addressOffset>0x2b0</addressOffset>
          <size>0x20</size>
        </register>
        <register>
          <name>sFilterRegister.14.FR2</name>
          <addressOffset>0x2b4</addressOffset>
          <size>0x20</size>
        </register>
        <register>
          <name>sFilterRegister.15.FR1</name>
          <addressOffset>0x2b8</addressOffset>
          <size>0x20</size>
        </register>
        <register>
          <name>sFilterRegister.15.FR2</name>
          <addressOffset>0x2bc</addressOffset>
          <size>0x20</size>
        </register>
        <register>
          <name>sFilterRegister.16.FR1</name>
          <addressOffset>0x2c0</addressOffset>
          <size>0x20</size>
        </register>
        <register>
          <name>sFilterRegister.16.FR2</name>
          <addressOffset>0x2c4</addressOffset>
          <size>0x20</size>
        </register>
        <register>
          <name>sFilterRegister.17.FR1</name>
          <addressOffset>0x2c8</addressOffset>
          <size>0x20</size>
        </register>
        <register>
          <name>sFilterRegister.17.FR2</name>
          <addressOffset>0x2cc</addressOffset>
          <size>0x20</size>
        </register>
        <register>
          <name>sFilterRegister.18.FR1</name>
          <addressOffset>0x2d0</addressOffset>
          <size>0x20</size>
        </register>
        <register>
          <name>sFilterRegister.18.FR2</name>
          <addressOffset>0x2d4</addressOffset>
          <size>0x20</size>
        </register>
        <register>
          <name>sFilterRegister.19.FR1</name>
          <addressOffset>0x2d8</addressOffset>
          <size>0x20</size>
        </register>
        <register>
          <name>sFilterRegister.19.FR2</name>
          <addressOffset>0x2dc</addressOffset>
          <size>0x20</size>
        </register>
        <register>
          <name>sFilterRegister.20.FR1</name>
          <addressOffset>0x2e0</addressOffset>
          <size>0x20</size>
        </register>
        <register>
          <name>sFilterRegister.20.FR2</name>
          <addressOffset>0x2e4</addressOffset>
          <size>0x20</size>
        </register>
        <register>
          <name>sFilterRegister.21.FR1</name>
          <addressOffset>0x2e8</addressOffset>
          <size>0x20</size>
        </register>
        <register>
          <name>sFilterRegister.21.FR2</name>
          <addressOffset>0x2ec</addressOffset>
          <size>0x20</size>
        </register>
        <register>
          <name>sFilterRegister.22.FR1</name>
          <addressOffset>0x2f0</addressOffset>
          <size>0x20</size>
        </register>
        <register>
          <name>sFilterRegister.22.FR2</name>
          <addressOffset>0x2f4</addressOffset>
          <size>0x20</size>
        </register>
        <register>
          <name>sFilterRegister.23.FR1</name>
          <addressOffset>0x2f8</addressOffset>
          <size>0x20</size>
        </register>
        <register>
          <name>sFilterRegister.23.FR2</name>
          <addressOffset>0x2fc</addressOffset>
          <size>0x20</size>
        </register>
        <register>
          <name>sFilterRegister.24.FR1</name>
          <addressOffset>0x300</addressOffset>
          <size>0x20</size>
        </register>
        <register>
          <name>sFilterRegister.24.FR2</name>
          <addressOffset>0x304</addressOffset>
          <size>0x20</size>
        </register>
        <register>
          <name>sFilterRegister.25.FR1</name>
          <addressOffset>0x308</addressOffset>
          <size>0x20</size>
        </register>
        <register>
          <name>sFilterRegister.25.FR2</name>
          <addressOffset>0x30c</addressOffset>
          <size>0x20</size>
        </register>
        <register>
          <name>sFilterRegister.26.FR1</name>
          <addressOffset>0x310</addressOffset>
          <size>0x20</size>
        </register>
        <register>
          <name>sFilterRegister.26.FR2</name>
          <addressOffset>0x314</addressOffset>
          <size>0x20</size>
        </register>
        <register>
          <name>sFilterRegister.27.FR1</name>
          <addressOffset>0x318</addressOffset>
          <size>0x20</size>
        </register>
        <register>
          <name>sFilterRegister.27.FR2</name>
          <addressOffset>0x31c</addressOffset>
          <size>0x20</size>
        </register>
      </registers>
    </peripheral>
    <peripheral>
      <name>SPI2</name>
      <baseAddress>0x40003800</baseAddress>
      <registers>
        <register>
          <name>CR1</name>
          <addressOffset>0x0</addressOffset>
          <size>0x20</size>
          <fields>
            <field>
              <name>CPHA</name>
              <bitOffset>0</bitOffset>
              <bitWidth>1</bitWidth>
            </field>
            <field>
              <name>CPOL</name>
              <bitOffset>1</bitOffset>
              <bitWidth>1</bitWidth>
            </field>
            <field>
              <name>MSTR</name>
              <bitOffset>2</bitOffset>
              <bitWidth>1</bitWidth>
            </field>
            <field>
              <name>BR</name>
              <bitOffset>3</bitOffset>
              <bitWidth>3</bitWidth>
            </field>
            <field>
              <name>SPE</name>
              <bitOffset>6</bitOffset>
              <bitWidth>1</bitWidth>
            </field>
            <field>
              <name>LSBFIRST</name>
              <bitOffset>7</bitOffset>
              <bitWidth>1</bitWidth>
            </field>
            <field>
              <name>SSI</name>
              <bitOffset>8</bitOffset>
              <bitWidth>1</bitWidth>
            </field>
            <field>
              <name>SSM</name>
              <bitOffset>9</bitOffset>
              <bitWidth>1</bitWidth>
            </field>
            <field>
              <name>RXONLY</name>
              <bitOffset>10</bitOffset>
              <bitWidth>1</bitWidth>
            </field>
            <field>
              <name>CRCL</name>
              <bitOffset>11</bitOffset>
              <bitWidth>1</bitWidth>
            </field>
            <field>
              <name>CRCNEXT</name>
              <bitOffset>12</bitOffset>
              <bitWidth>1</bitWidth>
            </field>
            <field>
              <name>CRCEN</name>
              <bitOffset>13</bitOffset>
              <bitWidth>1</bitWidth>
            </field>
            <field>
              <name>BIDIOE</name>
              <bitOffset>14</bitOffset>
              <bitWidth>1</bitWidth>
            </field>
            <field>
              <name>BIDIMODE</name>
              <bitOffset>15</bitOffset>
              <bitWidth>1</bitWidth>
            </field>
          </fields>
        </register>
        <register>
          <name>CR2</name>
          <addressOffset>0x4</addressOffset>
          <size>0x20</size>
          <fields>
            <field>
              <name>RXDMAEN</name>
              <bitOffset>0</bitOffset>
              <bitWidth>1</bitWidth>
            </field>
            <field>
              <name>TXDMAEN</name>
              <bitOffset>1</bitOffset>
              <bitWidth>1</bitWidth>
            </field>
            <field>
              <name>SSOE</name>
              <bitOffset>2</bitOffset>
              <bitWidth>1</bitWidth>
            </field>
            <field>
              <name>NSSP</name>
              <bitOffset>3</bitOffset>
              <bitWidth>1</bitWidth>
            </field>
            <field>
              <name>FRF</name>
              <bitOffset>4</bitOffset>
              <bitWidth>1</bitWidth>
            </field>
            <field>
              <name>ERRIE</name>
              <bitOffset>5</bitOffset>
              <bitWidth>1</bitWidth>
            </field>
            <field>
              <name>RXNEIE</name>
              <bitOffset>6</bitOffset>
              <bitWidth>1</bitWidth>
            </field>
            <field>
              <name>TXEIE</name>
              <bitOffset>7</bitOffset>
              <bitWidth>1</bitWidth>
            </field>
            <field>
              <name>DS</name>
              <bitOffset>8</bitOffset>
              <bitWidth>4</bitWidth>
            </field>
            <field>
              <name>FRXTH</name>
              <bitOffset>12</bitOffset>
              <bitWidth>1</bitWidth>
            </field>
            <field>
              <name>LDMARX</name>
              <bitOffset>13</bitOffset>
              <bitWidth>1</bitWidth>
            </field>
            <field>
              <name>LDMATX</name>
              <bitOffset>14</bitOffset>
              <bitWidth>1</bitWidth>
            </field>
          </fields>
        </register>
        <register>
          <name>SR</name>
          <addressOffset>0x8</addressOffset>
          <size>0x20</size>
          <fields>
            <field>
              <name>RXNE</name>
              <bitOffset>0</bitOffset>
              <bitWidth>1</bitWidth>
            </field>
            <field>
              <name>TXE</name>
              <bitOffset>1</bitOffset>
              <bitWidth>1</bitWidth>
            </field>
            <field>
              <name>CHSIDE</name>
              <bitOffset>2</bitOffset>
              <bitWidth>1</bitWidth>
            </field>
            <field>
              <name>UDR</name>
              <bitOffset>3</bitOffset>
              <bitWidth>1</bitWidth>
            </field>
            <field>
              <name>CRCERR</name>
              <bitOffset>4</bitOffset>
              <bitWidth>1</bitWidth>
            </field>
            <field>
              <name>MODF</name>
              <bitOffset>5</bitOffset>
              <bitWidth>1</bitWidth>
            </field>
            <field>
              <name>OVR</name>
              <bitOffset>6</bitOffset>
              <bitWidth>1</bitWidth>
            </field>
            <field>
              <name>BSY</name>
              <bitOffset>7</bitOffset>
              <bitWidth>1</bitWidth>
            </field>
            <field>
              <name>FRE</name>
              <bitOffset>8</bitOffset>
              <bitWidth>1</bitWidth>
            </field>
            <field>
              <name>FRLVL</name>
              <bitOffset>9</bitOffset>
              <bitWidth>2</bitWidth>
            </field>
            <field>
              <name>FTLVL</name>
              <bitOffset>11</bitOffset>
              <bitWidth>2</bitWidth>
            </field>
          </fields>
        </register>
        <register>
          <name>DR</name>
          <addressOffset>0xc</addressOffset>
          <size>0x20</size>
          <fields>
            <field>
              <name>DR</name>
              <bitOffset>0</bitOffset>
              <bitWidth>16</bitWidth>
            </field>
          </fields>
        </register>
        <register>
          <name>CRCPR</name>
          <addressOffset>0x10</addressOffset>
          <size>0x20</size>
          <fields>
            <field>
              <name>CRCPOLY</name>
              <bitOffset>0</bitOffset>
              <bitWidth>16</bitWidth>
            </field>
          </fields>
        </register>
        <register>
          <name>RXCRCR</name>
          <addressOffset>0x14</addressOffset>
          <size>0x20</size>
          <fields>
            <field>
              <name>RXCRC</name>
              <bitOffset>0</bitOffset>
              <bitWidth>16</bitWidth>
            </field>
          </fields>
        </register>
        <register>
          <name>TXCRCR</name>
          <addressOffset>0x18</addressOffset>
          <size>0x20</size>
          <fields>
            <field>
              <name>TXCRC</name>
              <bitOffset>0</bitOffset>
              <bitWidth>16</bitWidth>
            </field>
          </fields>
        </register>
        <register>
          <name>I2SCFGR</name>
          <addressOffset>0x1c</addressOffset>
          <size>0x20</size>
          <fields>
            <field>
              <name>CHLEN</name>
              <bitOffset>0</bitOffset>
              <bitWidth>1</bitWidth>
            </field>
            <field>
              <name>DATLEN</name>
              <bitOffset>1</bitOffset>
              <bitWidth>2</bitWidth>
            </field>
            <field>
              <name>CKPOL</name>
              <bitOffset>3</bitOffset>
              <bitWidth>1</bitWidth>
            </field>
            <field>
              <name>I2SSTD</name>
              <bitOffset>4</bitOffset>
              <bitWidth>2</bitWidth>
            </field>
            <field>
              <name>PCMSYNC</name>
              <bitOffset>7</bitOffset>
              <bitWidth>1</bitWidth>
            </field>
            <field>
              <name>I2SCFG</name>
              <bitOffset>8</bitOffset>
              <bitWidth>2</bitWidth>
            </field>
            <field>
              <name>I2SE</name>
              <bitOffset>10</bitOffset>
              <bitWidth>1</bitWidth>
            </field>
            <field>
              <name>I2SMOD</name>
              <bitOffset>11</bitOffset>
              <bitWidth>1</bitWidth>
            </field>
            <field>
              <name>ASTRTEN</name>
              <bitOffset>12</bitOffset>
              <bitWidth>1</bitWidth>
            </field>
          </fields>
        </register>
        <register>
          <name>I2SPR</name>
          <addressOffset>0x20</addressOffset>
          <size>0x20</size>
          <fields>
            <field>
              <name>I2SDIV</name>
              <bitOffset>0</bitOffset>
              <bitWidth>8</bitWidth>
            </field>
            <field>
              <name>ODD</name>
              <bitOffset>8</bitOffset>
              <bitWidth>1</bitWidth>
            </field>
            <field>
              <name>MCKOE</name>
              <bitOffset>9</bitOffset>
              <bitWidth>1</bitWidth>
            </field>
          </fields>
        </register>
      </registers>
    </peripheral>
    <peripheral>
      <name>SPI3</name>
      <baseAddress>0x40003c00</baseAddress>
      <registers>
        <register>
          <name>CR1</name>
          <addressOffset>0x0</addressOffset>
          <size>0x20</size>
          <fields>
            <field>
              <name>CPHA</name>
              <bitOffset>0</bitOffset>
              <bitWidth>1</bitWidth>
            </field>
            <field>
              <name>CPOL</name>
              <bitOffset>1</bitOffset>
              <bitWidth>1</bitWidth>
            </field>
            <field>
              <name>MSTR</name>
              <bitOffset>2</bitOffset>
              <bitWidth>1</bitWidth>
            </field>
            <field>
              <name>BR</name>
              <bitOffset>3</bitOffset>
              <bitWidth>3</bitWidth>
            </field>
            <field>
              <name>SPE</name>
              <bitOffset>6</bitOffset>
              <bitWidth>1</bitWidth>
            </field>
            <field>
              <name>LSBFIRST</name>
              <bitOffset>7</bitOffset>
              <bitWidth>1</bitWidth>
            </field>
            <field>
              <name>SSI</name>
              <bitOffset>8</bitOffset>
              <bitWidth>1</bitWidth>
            </field>
            <field>
              <name>SSM</name>
              <bitOffset>9</bitOffset>
              <bitWidth>1</bitWidth>
            </field>
            <field>
              <name>RXONLY</name>
              <bitOffset>10</bitOffset>
              <bitWidth>1</bitWidth>
            </field>
            <field>
              <name>CRCL</name>
              <bitOffset>11</bitOffset>
              <bitWidth>1</bitWidth>
            </field>
            <field>
              <name>CRCNEXT</name>
              <bitOffset>12</bitOffset>
              <bitWidth>1</bitWidth>
            </field>
            <field>
              <name>CRCEN</name>
              <bitOffset>13</bitOffset>
              <bitWidth>1</bitWidth>
            </field>
            <field>
              <name>BIDIOE</name>
              <bitOffset>14</bitOffset>
              <bitWidth>1</bitWidth>
            </field>
            <field>
              <name>BIDIMODE</name>
              <bitOffset>15</bitOffset>
              <bitWidth>1</bitWidth>
            </field>
          </fields>
        </register>
        <register>
          <name>CR2</name>
          <addressOffset>0x4</addressOffset>
          <size>0x20</size>
          <fields>
            <field>
              <name>RXDMAEN</name>
              <bitOffset>0</bitOffset>
              <bitWidth>1</bitWidth>
            </field>
            <field>
              <name>TXDMAEN</name>
              <bitOffset>1</bitOffset>
              <bitWidth>1</bitWidth>
            </field>
            <field>
              <name>SSOE</name>
              <bitOffset>2</bitOffset>
              <bitWidth>1</bitWidth>
            </field>
            <field>
              <name>NSSP</name>
              <bitOffset>3</bitOffset>
              <bitWidth>1</bitWidth>
            </field>
            <field>
              <name>FRF</name>
              <bitOffset>4</bitOffset>
              <bitWidth>1</bitWidth>
            </field>
            <field>
              <name>ERRIE</name>
              <bitOffset>5</bitOffset>
              <bitWidth>1</bitWidth>
            </field>
            <field>
              <name>RXNEIE</name>
              <bitOffset>6</bitOffset>
              <bitWidth>1</bitWidth>
            </field>
            <field>
              <name>TXEIE</name>
              <bitOffset>7</bitOffset>
              <bitWidth>1</bitWidth>
            </field>
            <field>
              <name>DS</name>
              <bitOffset>8</bitOffset>
              <bitWidth>4</bitWidth>
            </field>
            <field>
              <name>FRXTH</name>
              <bitOffset>12</bitOffset>
              <bitWidth>1</bitWidth>
            </field>
            <field>
              <name>LDMARX</name>
              <bitOffset>13</bitOffset>
              <bitWidth>1</bitWidth>
            </field>
            <field>
              <name>LDMATX</name>
              <bitOffset>14</bitOffset>
              <bitWidth>1</bitWidth>
            </field>
          </fields>
        </register>
        <register>
          <name>SR</name>
          <addressOffset>0x8</addressOffset>
          <size>0x20</size>
          <fields>
            <field>
              <name>RXNE</name>
              <bitOffset>0</bitOffset>
              <bitWidth>1</bitWidth>
            </field>
            <field>
              <name>TXE</name>
              <bitOffset>1</bitOffset>
              <bitWidth>1</bitWidth>
            </field>
            <field>
              <name>CHSIDE</name>
              <bitOffset>2</bitOffset>
              <bitWidth>1</bitWidth>
            </field>
            <field>
              <name>UDR</name>
              <bitOffset>3</bitOffset>
              <bitWidth>1</bitWidth>
            </field>
            <field>
              <name>CRCERR</name>
              <bitOffset>4</bitOffset>
              <bitWidth>1</bitWidth>
            </field>
            <field>
              <name>MODF</name>
              <bitOffset>5</bitOffset>
              <bitWidth>1</bitWidth>
            </field>
            <field>
              <name>OVR</name>
              <bitOffset>6</bitOffset>
              <bitWidth>1</bitWidth>
            </field>
            <field>
              <name>BSY</name>
              <bitOffset>7</bitOffset>
              <bitWidth>1</bitWidth>
            </field>
            <field>
              <name>FRE</name>
              <bitOffset>8</bitOffset>
              <bitWidth>1</bitWidth>
            </field>
            <field>
              <name>FRLVL</name>
              <bitOffset>9</bitOffset>
              <bitWidth>2</bitWidth>
            </field>
            <field>
              <name>FTLVL</name>
              <bitOffset>11</bitOffset>
              <bitWidth>2</bitWidth>
            </field>
          </fields>
        </register>
        <register>
          <name>DR</name>
          <addressOffset>0xc</addressOffset>
          <size>0x20</size>
          <fields>
            <field>
              <name>DR</name>
              <bitOffset>0</bitOffset>
              <bitWidth>16</bitWidth>
            </field>
          </fields>
        </register>
        <register>
          <name>CRCPR</name>
          <addressOffset>0x10</addressOffset>
          <size>0x20</size>
          <fields>
            <field>
              <name>CRCPOLY</name>
              <bitOffset>0</bitOffset>
              <bitWidth>16</bitWidth>
            </field>
          </fields>
        </register>
        <register>
          <name>RXCRCR</name>
          <addressOffset>0x14</addressOffset>
          <size>0x20</size>
          <fields>
            <field>
              <name>RXCRC</name>
              <bitOffset>0</bitOffset>
              <bitWidth>16</bitWidth>
            </field>
          </fields>
        </register>
        <register>
          <name>TXCRCR</name>
          <addressOffset>0x18</addressOffset>
          <size>0x20</size>
          <fields>
            <field>
              <name>TXCRC</name>
              <bitOffset>0</bitOffset>
              <bitWidth>16</bitWidth>
            </field>
          </fields>
        </register>
        <register>
          <name>I2SCFGR</name>
          <addressOffset>0x1c</addressOffset>
          <size>0x20</size>
          <fields>
            <field>
              <name>CHLEN</name>
              <bitOffset>0</bitOffset>
              <bitWidth>1</bitWidth>
            </field>
            <field>
              <name>DATLEN</name>
              <bitOffset>1</bitOffset>
              <bitWidth>2</bitWidth>
            </field>
            <field>
              <name>CKPOL</name>
              <bitOffset>3</bitOffset>
              <bitWidth>1</bitWidth>
            </field>
            <field>
              <name>I2SSTD</name>
              <bitOffset>4</bitOffset>
              <bitWidth>2</bitWidth>
            </field>
            <field>
              <name>PCMSYNC</name>
              <bitOffset>7</bitOffset>
              <bitWidth>1</bitWidth>
            </field>
            <field>
              <name>I2SCFG</name>
              <bitOffset>8</bitOffset>
              <bitWidth>2</bitWidth>
            </field>
            <field>
              <name>I2SE</name>
              <bitOffset>10</bitOffset>
              <bitWidth>1</bitWidth>
            </field>
            <field>
              <name>I2SMOD</name>
              <bitOffset>11</bitOffset>
              <bitWidth>1</bitWidth>
            </field>
            <field>
              <name>ASTRTEN</name>
              <bitOffset>12</bitOffset>
              <bitWidth>1</bitWidth>
            </field>
          </fields>
        </register>
        <register>
          <name>I2SPR</name>
          <addressOffset>0x20</addressOffset>
          <size>0x20</size>
          <fields>
            <field>
              <name>I2SDIV</name>
              <bitOffset>0</bitOffset>
              <bitWidth>8</bitWidth>
            </field>
            <field>
              <name>ODD</name>
              <bitOffset>8</bitOffset>
              <bitWidth>1</bitWidth>
            </field>
            <field>
              <name>MCKOE</name>
              <bitOffset>9</bitOffset>
              <bitWidth>1</bitWidth>
            </field>
          </fields>
        </register>
      </registers>
    </peripheral>
    <peripheral>
      <name>SPDIFRX</name>
      <baseAddress>0x40004000</baseAddress>
      <registers>
        <register>
          <name>CR</name>
          <addressOffset>0x0</addressOffset>
          <size>0x20</size>
          <fields>
            <field>
              <name>SPDIFEN</name>
              <bitOffset>0</bitOffset>
              <bitWidth>2</bitWidth>
            </field>
            <field>
              <name>RXDMAEN</name>
              <bitOffset>2</bitOffset>
              <bitWidth>1</bitWidth>
            </field>
            <field>
              <name>RXSTEO</name>
              <bitOffset>3</bitOffset>
              <bitWidth>1</bitWidth>
            </field>
            <field>
              <name>DRFMT</name>
              <bitOffset>4</bitOffset>
              <bitWidth>2</bitWidth>
            </field>
            <field>
              <name>PMSK</name>
              <bitOffset>6</bitOffset>
              <bitWidth>1</bitWidth>
            </field>
            <field>
              <name>VMSK</name>
              <bitOffset>7</bitOffset>
              <bitWidth>1</bitWidth>
            </field>
            <field>
              <name>CUMSK</name>
              <bitOffset>8</bitOffset>
              <bitWidth>1</bitWidth>
            </field>
            <field>
              <name>PTMSK</name>
              <bitOffset>9</bitOffset>
              <bitWidth>1</bitWidth>
            </field>
            <field>
              <name>CBDMAEN</name>
              <bitOffset>10</bitOffset>
              <bitWidth>1</bitWidth>
            </field>
            <field>
              <name>CHSEL</name>
              <bitOffset>11</bitOffset>
              <bitWidth>1</bitWidth>
            </field>
            <field>
              <name>NBTR</name>
              <bitOffset>12</bitOffset>
              <bitWidth>2</bitWidth>
            </field>
            <field>
              <name>WFA</name>
              <bitOffset>14</bitOffset>
              <bitWidth>1</bitWidth>
            </field>
            <field>
              <name>INSEL</name>
              <bitOffset>16</bitOffset>
              <bitWidth>3</bitWidth>
            </field>
          </fields>
        </register>
        <register>
          <name>IMR</name>
          <addressOffset>0x4</addressOffset>
          <size>0x20</size>
          <fields>
            <field>
              <name>RXNEIE</name>
              <bitOffset>0</bitOffset>
              <bitWidth>1</bitWidth>
            </field>
            <field>
              <name>CSRNEIE</name>
              <bitOffset>1</bitOffset>
              <bitWidth>1</bitWidth>
            </field>
            <field>
              <name>PERRIE</name>
              <bitOffset>2</bitOffset>
              <bitWidth>1</bitWidth>
            </field>
            <field>
              <name>OVRIE</name>
              <bitOffset>3</bitOffset>
              <bitWidth>1</bitWidth>
            </field>
            <field>
              <name>SBLKIE</name>
              <bitOffset>4</bitOffset>
              <bitWidth>1</bitWidth>
            </field>
            <field>
              <name>SYNCDIE</name>
              <bitOffset>5</bitOffset>
              <bitWidth>1</bitWidth>
            </field>
            <field>
              <name>IFEIE</name>
              <bitOffset>6</bitOffset>
              <bitWidth>1</bitWidth>
            </field>
          </fields>
        </register>
        <register>
          <name>SR</name>
          <addressOffset>0x8</addressOffset>
          <size>0x20</size>
          <fields>
            <field>
              <name>RXNE</name>
              <bitOffset>0</bitOffset>
              <bitWidth>1</bitWidth>
            </field>
            <field>
              <name>CSRNE</name>
              <bitOffset>1</bitOffset>
              <bitWidth>1</bitWidth>
            </field>
            <field>
              <name>PERR</name>
              <bitOffset>2</bitOffset>
              <bitWidth>1</bitWidth>
            </field>
            <field>
              <name>OVR</name>
              <bitOffset>3</bitOffset>
              <bitWidth>1</bitWidth>
            </field>
            <field>
              <name>SBD</name>
              <bitOffset>4</bitOffset>
              <bitWidth>1</bitWidth>
            </field>
            <field>
              <name>SYNCD</name>
              <bitOffset>5</bitOffset>
              <bitWidth>1</bitWidth>
            </field>
            <field>
              <name>FERR</name>
              <bitOffset>6</bitOffset>
              <bitWidth>1</bitWidth>
            </field>
            <field>
              <name>SERR</name>
              <bitOffset>7</bitOffset>
              <bitWidth>1</bitWidth>
            </field>
            <field>
              <name>TERR</name>
              <bitOffset>8</bitOffset>
              <bitWidth>1</bitWidth>
            </field>
            <field>
              <name>WIDTH5</name>
              <bitOffset>16</bitOffset>
              <bitWidth>15</bitWidth>
            </field>
          </fields>
        </register>
        <register>
          <name>IFCR</name>
          <addressOffset>0xc</addressOffset>
          <size>0x20</size>
          <fields>
            <field>
              <name>PERRCF</name>
              <bitOffset>2</bitOffset>
              <bitWidth>1</bitWidth>
            </field>
            <field>
              <name>OVRCF</name>
              <bitOffset>3</bitOffset>
              <bitWidth>1</bitWidth>
            </field>
            <field>
              <name>SBDCF</name>
              <bitOffset>4</bitOffset>
              <bitWidth>1</bitWidth>
            </field>
            <field>
              <name>SYNCDCF</name>
              <bitOffset>5</bitOffset>
              <bitWidth>1</bitWidth>
            </field>
          </fields>
        </register>
        <register>
          <name>DR</name>
          <addressOffset>0x10</addressOffset>
          <size>0x20</size>
        </register>
        <register>
          <name>CSR</name>
          <addressOffset>0x14</addressOffset>
          <size>0x20</size>
          <fields>
            <field>
              <name>USR</name>
              <bitOffset>0</bitOffset>
              <bitWidth>16</bitWidth>
            </field>
            <field>
              <name>CS</name>
              <bitOffset>16</bitOffset>
              <bitWidth>8</bitWidth>
            </field>
            <field>
              <name>SOB</name>
              <bitOffset>24</bitOffset>
              <bitWidth>1</bitWidth>
            </field>
          </fields>
        </register>
        <register>
          <name>DIR</name>
          <addressOffset>0x18</addressOffset>
          <size>0x20</size>
          <fields>
            <field>
              <name>THI</name>
              <bitOffset>0</bitOffset>
              <bitWidth>13</bitWidth>
            </field>
            <field>
              <name>TLO</name>
              <bitOffset>16</bitOffset>
              <bitWidth>13</bitWidth>
            </field>
          </fields>
        </register>
      </registers>
    </peripheral>
    <peripheral>
      <name>USART2</name>
      <baseAddress>0x40004400</baseAddress>
      <registers>
        <register>
          <name>CR1</name>
          <addressOffset>0x0</addressOffset>
          <size>0x20</size>
          <fields>
            <field>
              <name>UE</name>
              <bitOffset>0</bitOffset>
              <bitWidth>1</bitWidth>
            </field>
            <field>
              <name>UESM</name>
              <bitOffset>1</bitOffset>
              <bitWidth>1</bitWidth>
            </field>
            <field>
              <name>RE</name>
              <bitOffset>2</bitOffset>
              <bitWidth>1</bitWidth>
            </field>
            <field>
              <name>TE</name>
              <bitOffset>3</bitOffset>
              <bitWidth>1</bitWidth>
            </field>
            <field>
              <name>IDLEIE</name>
              <bitOffset>4</bitOffset>
              <bitWidth>1</bitWidth>
            </field>
            <field>
              <name>RXNEIE</name>
              <bitOffset>5</bitOffset>
              <bitWidth>1</bitWidth>
            </field>
            <field>
              <name>TCIE</name>
              <bitOffset>6</bitOffset>
              <bitWidth>1</bitWidth>
            </field>
            <field>
              <name>TXEIE</name>
              <bitOffset>7</bitOffset>
              <bitWidth>1</bitWidth>
            </field>
            <field>
              <name>PEIE</name>
              <bitOffset>8</bitOffset>
              <bitWidth>1</bitWidth>
            </field>
            <field>
              <name>PS</name>
              <bitOffset>9</bitOffset>
              <bitWidth>1</bitWidth>
            </field>
            <field>
              <name>PCE</name>
              <bitOffset>10</bitOffset>
              <bitWidth>1</bitWidth>
            </field>
            <field>
              <name>WAKE</name>
              <bitOffset>11</bitOffset>
              <bitWidth>1</bitWidth>
            </field>
            <field>
              <name>M</name>
              <bitOffset>12</bitOffset>
              <bitWidth>17</bitWidth>
            </field>
            <field>
              <name>MME</name>
              <bitOffset>13</bitOffset>
              <bitWidth>1</bitWidth>
            </field>
            <field>
              <name>CMIE</name>
              <bitOffset>14</bitOffset>
              <bitWidth>1</bitWidth>
            </field>
            <field>
              <name>OVER8</name>
              <bitOffset>15</bitOffset>
              <bitWidth>1</bitWidth>
            </field>
            <field>
              <name>DEDT</name>
              <bitOffset>16</bitOffset>
              <bitWidth>5</bitWidth>
            </field>
            <field>
              <name>DEAT</name>
              <bitOffset>21</bitOffset>
              <bitWidth>5</bitWidth>
            </field>
            <field>
              <name>RTOIE</name>
              <bitOffset>26</bitOffset>
              <bitWidth>1</bitWidth>
            </field>
            <field>
              <name>EOBIE</name>
              <bitOffset>27</bitOffset>
              <bitWidth>1</bitWidth>
            </field>
          </fields>
        </register>
        <register>
          <name>CR2</name>
          <addressOffset>0x4</addressOffset>
          <size>0x20</size>
          <fields>
            <field>
              <name>ADDM7</name>
              <bitOffset>4</bitOffset>
              <bitWidth>1</bitWidth>
            </field>
            <field>
              <name>LBDL</name>
              <bitOffset>5</bitOffset>
              <bitWidth>1</bitWidth>
            </field>
            <field>
              <name>LBDIE</name>
              <bitOffset>6</bitOffset>
              <bitWidth>1</bitWidth>
            </field>
            <field>
              <name>LBCL</name>
              <bitOffset>8</bitOffset>
              <bitWidth>1</bitWidth>
            </field>
            <field>
              <name>CPHA</name>
              <bitOffset>9</bitOffset>
              <bitWidth>1</bitWidth>
            </field>
            <field>
              <name>CPOL</name>
              <bitOffset>10</bitOffset>
              <bitWidth>1</bitWidth>
            </field>
            <field>
              <name>CLKEN</name>
              <bitOffset>11</bitOffset>
              <bitWidth>1</bitWidth>
            </field>
            <field>
              <name>STOP</name>
              <bitOffset>12</bitOffset>
              <bitWidth>2</bitWidth>
            </field>
            <field>
              <name>LINEN</name>
              <bitOffset>14</bitOffset>
              <bitWidth>1</bitWidth>
            </field>
            <field>
              <name>SWAP</name>
              <bitOffset>15</bitOffset>
              <bitWidth>1</bitWidth>
            </field>
            <field>
              <name>RXINV</name>
              <bitOffset>16</bitOffset>
              <bitWidth>1</bitWidth>
            </field>
            <field>
              <name>TXINV</name>
              <bitOffset>17</bitOffset>
              <bitWidth>1</bitWidth>
            </field>
            <field>
              <name>DATAINV</name>
              <bitOffset>18</bitOffset>
              <bitWidth>1</bitWidth>
            </field>
            <field>
              <name>MSBFIRST</name>
              <bitOffset>19</bitOffset>
              <bitWidth>1</bitWidth>
            </field>
            <field>
              <name>ABREN</name>
              <bitOffset>20</bitOffset>
              <bitWidth>1</bitWidth>
            </field>
            <field>
              <name>ABRMODE</name>
              <bitOffset>21</bitOffset>
              <bitWidth>2</bitWidth>
            </field>
            <field>
              <name>RTOEN</name>
              <bitOffset>23</bitOffset>
              <bitWidth>1</bitWidth>
            </field>
            <field>
              <name>ADD</name>
              <bitOffset>24</bitOffset>
              <bitWidth>8</bitWidth>
            </field>
          </fields>
        </register>
        <register>
          <name>CR3</name>
          <addressOffset>0x8</addressOffset>
          <size>0x20</size>
          <fields>
            <field>
              <name>EIE</name>
              <bitOffset>0</bitOffset>
              <bitWidth>1</bitWidth>
            </field>
            <field>
              <name>IREN</name>
              <bitOffset>1</bitOffset>
              <bitWidth>1</bitWidth>
            </field>
            <field>
              <name>IRLP</name>
              <bitOffset>2</bitOffset>
              <bitWidth>1</bitWidth>
            </field>
            <field>
              <name>HDSEL</name>
              <bitOffset>3</bitOffset>
              <bitWidth>1</bitWidth>
            </field>
            <field>
              <name>NACK</name>
              <bitOffset>4</bitOffset>
              <bitWidth>1</bitWidth>
            </field>
            <field>
              <name>SCEN</name>
              <bitOffset>5</bitOffset>
              <bitWidth>1</bitWidth>
            </field>
            <field>
              <name>DMAR</name>
              <bitOffset>6</bitOffset>
              <bitWidth>1</bitWidth>
            </field>
            <field>
              <name>DMAT</name>
              <bitOffset>7</bitOffset>
              <bitWidth>1</bitWidth>
            </field>
            <field>
              <name>RTSE</name>
              <bitOffset>8</bitOffset>
              <bitWidth>1</bitWidth>
            </field>
            <field>
              <name>CTSE</name>
              <bitOffset>9</bitOffset>
              <bitWidth>1</bitWidth>
            </field>
            <field>
              <name>CTSIE</name>
              <bitOffset>10</bitOffset>
              <bitWidth>1</bitWidth>
            </field>
            <field>
              <name>ONEBIT</name>
              <bitOffset>11</bitOffset>
              <bitWidth>1</bitWidth>
            </field>
            <field>
              <name>OVRDIS</name>
              <bitOffset>12</bitOffset>
              <bitWidth>1</bitWidth>
            </field>
            <field>
              <name>DDRE</name>
              <bitOffset>13</bitOffset>
              <bitWidth>1</bitWidth>
            </field>
            <field>
              <name>DEM</name>
              <bitOffset>14</bitOffset>
              <bitWidth>1</bitWidth>
            </field>
            <field>
              <name>DEP</name>
              <bitOffset>15</bitOffset>
              <bitWidth>1</bitWidth>
            </field>
            <field>
              <name>SCARCNT</name>
              <bitOffset>17</bitOffset>
              <bitWidth>3</bitWidth>
            </field>
            <field>
              <name>WUS</name>
              <bitOffset>20</bitOffset>
              <bitWidth>2</bitWidth>
            </field>
            <field>
              <name>WUFIE</name>
              <bitOffset>22</bitOffset>
              <bitWidth>1</bitWidth>
            </field>
            <field>
              <name>UCESM</name>
              <bitOffset>23</bitOffset>
              <bitWidth>1</bitWidth>
            </field>
          </fields>
        </register>
        <register>
          <name>BRR</name>
          <addressOffset>0xc</addressOffset>
          <size>0x20</size>
          <fields>
            <field>
              <name>DIV_FRACTION</name>
              <bitOffset>0</bitOffset>
              <bitWidth>4</bitWidth>
            </field>
            <field>
              <name>DIV_MANTISSA</name>
              <bitOffset>4</bitOffset>
              <bitWidth>12</bitWidth>
            </field>
          </fields>
        </register>
        <register>
          <name>GTPR</name>
          <addressOffset>0x10</addressOffset>
          <size>0x20</size>
          <fields>
            <field>
              <name>PSC</name>
              <bitOffset>0</bitOffset>
              <bitWidth>8</bitWidth>
            </field>
            <field>
              <name>GT</name>
              <bitOffset>8</bitOffset>
              <bitWidth>8</bitWidth>
            </field>
          </fields>
        </register>
        <register>
          <name>RTOR</name>
          <addressOffset>0x14</addressOffset>
          <size>0x20</size>
          <fields>
            <field>
              <name>RTO</name>
              <bitOffset>0</bitOffset>
              <bitWidth>24</bitWidth>
            </field>
            <field>
              <name>BLEN</name>
              <bitOffset>24</bitOffset>
              <bitWidth>8</bitWidth>
            </field>
          </fields>
        </register>
        <register>
          <name>RQR</name>
          <addressOffset>0x18</addressOffset>
          <size>0x20</size>
          <fields>
            <field>
              <name>ABRRQ</name>
              <bitOffset>0</bitOffset>
              <bitWidth>1</bitWidth>
            </field>
            <field>
              <name>SBKRQ</name>
              <bitOffset>1</bitOffset>
              <bitWidth>1</bitWidth>
            </field>
            <field>
              <name>MMRQ</name>
              <bitOffset>2</bitOffset>
              <bitWidth>1</bitWidth>
            </field>
            <field>
              <name>RXFRQ</name>
              <bitOffset>3</bitOffset>
              <bitWidth>1</bitWidth>
            </field>
            <field>
              <name>TXFRQ</name>
              <bitOffset>4</bitOffset>
              <bitWidth>1</bitWidth>
            </field>
          </fields>
        </register>
        <register>
          <name>ISR</name>
          <addressOffset>0x1c</addressOffset>
          <size>0x20</size>
          <fields>
            <field>
              <name>PE</name>
              <bitOffset>0</bitOffset>
              <bitWidth>1</bitWidth>
            </field>
            <field>
              <name>FE</name>
              <bitOffset>1</bitOffset>
              <bitWidth>1</bitWidth>
            </field>
            <field>
              <name>NE</name>
              <bitOffset>2</bitOffset>
              <bitWidth>1</bitWidth>
            </field>
            <field>
              <name>ORE</name>
              <bitOffset>3</bitOffset>
              <bitWidth>1</bitWidth>
            </field>
            <field>
              <name>IDLE</name>
              <bitOffset>4</bitOffset>
              <bitWidth>1</bitWidth>
            </field>
            <field>
              <name>RXNE</name>
              <bitOffset>5</bitOffset>
              <bitWidth>1</bitWidth>
            </field>
            <field>
              <name>TC</name>
              <bitOffset>6</bitOffset>
              <bitWidth>1</bitWidth>
            </field>
            <field>
              <name>TXE</name>
              <bitOffset>7</bitOffset>
              <bitWidth>1</bitWidth>
            </field>
            <field>
              <name>LBDF</name>
              <bitOffset>8</bitOffset>
              <bitWidth>1</bitWidth>
            </field>
            <field>
              <name>CTSIF</name>
              <bitOffset>9</bitOffset>
              <bitWidth>1</bitWidth>
            </field>
            <field>
              <name>CTS</name>
              <bitOffset>10</bitOffset>
              <bitWidth>1</bitWidth>
            </field>
            <field>
              <name>RTOF</name>
              <bitOffset>11</bitOffset>
              <bitWidth>1</bitWidth>
            </field>
            <field>
              <name>EOBF</name>
              <bitOffset>12</bitOffset>
              <bitWidth>1</bitWidth>
            </field>
            <field>
              <name>ABRE</name>
              <bitOffset>14</bitOffset>
              <bitWidth>1</bitWidth>
            </field>
            <field>
              <name>ABRF</name>
              <bitOffset>15</bitOffset>
              <bitWidth>1</bitWidth>
            </field>
            <field>
              <name>BUSY</name>
              <bitOffset>16</bitOffset>
              <bitWidth>1</bitWidth>
            </field>
            <field>
              <name>CMF</name>
              <bitOffset>17</bitOffset>
              <bitWidth>1</bitWidth>
            </field>
            <field>
              <name>SBKF</name>
              <bitOffset>18</bitOffset>
              <bitWidth>1</bitWidth>
            </field>
            <field>
              <name>RWU</name>
              <bitOffset>19</bitOffset>
              <bitWidth>1</bitWidth>
            </field>
            <field>
              <name>WUF</name>
              <bitOffset>20</bitOffset>
              <bitWidth>1</bitWidth>
            </field>
            <field>
              <name>TEACK</name>
              <bitOffset>21</bitOffset>
              <bitWidth>1</bitWidth>
            </field>
            <field>
              <name>REACK</name>
              <bitOffset>22</bitOffset>
              <bitWidth>1</bitWidth>
            </field>
          </fields>
        </register>
        <register>
          <name>ICR</name>
          <addressOffset>0x20</addressOffset>
          <size>0x20</size>
          <fields>
            <field>
              <name>PECF</name>
              <bitOffset>0</bitOffset>
              <bitWidth>1</bitWidth>
            </field>
            <field>
              <name>FECF</name>
              <bitOffset>1</bitOffset>
              <bitWidth>1</bitWidth>
            </field>
            <field>
              <name>NCF</name>
              <bitOffset>2</bitOffset>
              <bitWidth>1</bitWidth>
            </field>
            <field>
              <name>ORECF</name>
              <bitOffset>3</bitOffset>
              <bitWidth>1</bitWidth>
            </field>
            <field>
              <name>IDLECF</name>
              <bitOffset>4</bitOffset>
              <bitWidth>1</bitWidth>
            </field>
            <field>
              <name>TCCF</name>
              <bitOffset>6</bitOffset>
              <bitWidth>1</bitWidth>
            </field>
            <field>
              <name>LBDCF</name>
              <bitOffset>8</bitOffset>
              <bitWidth>1</bitWidth>
            </field>
            <field>
              <name>CTSCF</name>
              <bitOffset>9</bitOffset>
              <bitWidth>1</bitWidth>
            </field>
            <field>
              <name>RTOCF</name>
              <bitOffset>11</bitOffset>
              <bitWidth>1</bitWidth>
            </field>
            <field>
              <name>EOBCF</name>
              <bitOffset>12</bitOffset>
              <bitWidth>1</bitWidth>
            </field>
            <field>
              <name>CMCF</name>
              <bitOffset>17</bitOffset>
              <bitWidth>1</bitWidth>
            </field>
            <field>
              <name>WUCF</name>
              <bitOffset>20</bitOffset>
              <bitWidth>1</bitWidth>
            </field>
          </fields>
        </register>
        <register>
          <name>RDR</name>
          <addressOffset>0x24</addressOffset>
          <size>0x20</size>
          <fields>
            <field>
              <name>RDR</name>
              <bitOffset>0</bitOffset>
              <bitWidth>9</bitWidth>
            </field>
          </fields>
        </register>
        <register>
          <name>TDR</name>
          <addressOffset>0x28</addressOffset>
          <size>0x20</size>
          <fields>
            <field>
              <name>TDR</name>
              <bitOffset>0</bitOffset>
              <bitWidth>9</bitWidth>
            </field>
          </fields>
        </register>
      </registers>
    </peripheral>
    <peripheral>
      <name>USART3</name>
      <baseAddress>0x40004800</baseAddress>
      <registers>
        <register>
          <name>CR1</name>
          <addressOffset>0x0</addressOffset>
          <size>0x20</size>
          <fields>
            <field>
              <name>UE</name>
              <bitOffset>0</bitOffset>
              <bitWidth>1</bitWidth>
            </field>
            <field>
              <name>UESM</name>
              <bitOffset>1</bitOffset>
              <bitWidth>1</bitWidth>
            </field>
            <field>
              <name>RE</name>
              <bitOffset>2</bitOffset>
              <bitWidth>1</bitWidth>
            </field>
            <field>
              <name>TE</name>
              <bitOffset>3</bitOffset>
              <bitWidth>1</bitWidth>
            </field>
            <field>
              <name>IDLEIE</name>
              <bitOffset>4</bitOffset>
              <bitWidth>1</bitWidth>
            </field>
            <field>
              <name>RXNEIE</name>
              <bitOffset>5</bitOffset>
              <bitWidth>1</bitWidth>
            </field>
            <field>
              <name>TCIE</name>
              <bitOffset>6</bitOffset>
              <bitWidth>1</bitWidth>
            </field>
            <field>
              <name>TXEIE</name>
              <bitOffset>7</bitOffset>
              <bitWidth>1</bitWidth>
            </field>
            <field>
              <name>PEIE</name>
              <bitOffset>8</bitOffset>
              <bitWidth>1</bitWidth>
            </field>
            <field>
              <name>PS</name>
              <bitOffset>9</bitOffset>
              <bitWidth>1</bitWidth>
            </field>
            <field>
              <name>PCE</name>
              <bitOffset>10</bitOffset>
              <bitWidth>1</bitWidth>
            </field>
            <field>
              <name>WAKE</name>
              <bitOffset>11</bitOffset>
              <bitWidth>1</bitWidth>
            </field>
            <field>
              <name>M</name>
              <bitOffset>12</bitOffset>
              <bitWidth>17</bitWidth>
            </field>
            <field>
              <name>MME</name>
              <bitOffset>13</bitOffset>
              <bitWidth>1</bitWidth>
            </field>
            <field>
              <name>CMIE</name>
              <bitOffset>14</bitOffset>
              <bitWidth>1</bitWidth>
            </field>
            <field>
              <name>OVER8</name>
              <bitOffset>15</bitOffset>
              <bitWidth>1</bitWidth>
            </field>
            <field>
              <name>DEDT</name>
              <bitOffset>16</bitOffset>
              <bitWidth>5</bitWidth>
            </field>
            <field>
              <name>DEAT</name>
              <bitOffset>21</bitOffset>
              <bitWidth>5</bitWidth>
            </field>
            <field>
              <name>RTOIE</name>
              <bitOffset>26</bitOffset>
              <bitWidth>1</bitWidth>
            </field>
            <field>
              <name>EOBIE</name>
              <bitOffset>27</bitOffset>
              <bitWidth>1</bitWidth>
            </field>
          </fields>
        </register>
        <register>
          <name>CR2</name>
          <addressOffset>0x4</addressOffset>
          <size>0x20</size>
          <fields>
            <field>
              <name>ADDM7</name>
              <bitOffset>4</bitOffset>
              <bitWidth>1</bitWidth>
            </field>
            <field>
              <name>LBDL</name>
              <bitOffset>5</bitOffset>
              <bitWidth>1</bitWidth>
            </field>
            <field>
              <name>LBDIE</name>
              <bitOffset>6</bitOffset>
              <bitWidth>1</bitWidth>
            </field>
            <field>
              <name>LBCL</name>
              <bitOffset>8</bitOffset>
              <bitWidth>1</bitWidth>
            </field>
            <field>
              <name>CPHA</name>
              <bitOffset>9</bitOffset>
              <bitWidth>1</bitWidth>
            </field>
            <field>
              <name>CPOL</name>
              <bitOffset>10</bitOffset>
              <bitWidth>1</bitWidth>
            </field>
            <field>
              <name>CLKEN</name>
              <bitOffset>11</bitOffset>
              <bitWidth>1</bitWidth>
            </field>
            <field>
              <name>STOP</name>
              <bitOffset>12</bitOffset>
              <bitWidth>2</bitWidth>
            </field>
            <field>
              <name>LINEN</name>
              <bitOffset>14</bitOffset>
              <bitWidth>1</bitWidth>
            </field>
            <field>
              <name>SWAP</name>
              <bitOffset>15</bitOffset>
              <bitWidth>1</bitWidth>
            </field>
            <field>
              <name>RXINV</name>
              <bitOffset>16</bitOffset>
              <bitWidth>1</bitWidth>
            </field>
            <field>
              <name>TXINV</name>
              <bitOffset>17</bitOffset>
              <bitWidth>1</bitWidth>
            </field>
            <field>
              <name>DATAINV</name>
              <bitOffset>18</bitOffset>
              <bitWidth>1</bitWidth>
            </field>
            <field>
              <name>MSBFIRST</name>
              <bitOffset>19</bitOffset>
              <bitWidth>1</bitWidth>
            </field>
            <field>
              <name>ABREN</name>
              <bitOffset>20</bitOffset>
              <bitWidth>1</bitWidth>
            </field>
            <field>
              <name>ABRMODE</name>
              <bitOffset>21</bitOffset>
              <bitWidth>2</bitWidth>
            </field>
            <field>
              <name>RTOEN</name>
              <bitOffset>23</bitOffset>
              <bitWidth>1</bitWidth>
            </field>
            <field>
              <name>ADD</name>
              <bitOffset>24</bitOffset>
              <bitWidth>8</bitWidth>
            </field>
          </fields>
        </register>
        <register>
          <name>CR3</name>
          <addressOffset>0x8</addressOffset>
          <size>0x20</size>
          <fields>
            <field>
              <name>EIE</name>
              <bitOffset>0</bitOffset>
              <bitWidth>1</bitWidth>
            </field>
            <field>
              <name>IREN</name>
              <bitOffset>1</bitOffset>
              <bitWidth>1</bitWidth>
            </field>
            <field>
              <name>IRLP</name>
              <bitOffset>2</bitOffset>
              <bitWidth>1</bitWidth>
            </field>
            <field>
              <name>HDSEL</name>
              <bitOffset>3</bitOffset>
              <bitWidth>1</bitWidth>
            </field>
            <field>
              <name>NACK</name>
              <bitOffset>4</bitOffset>
              <bitWidth>1</bitWidth>
            </field>
            <field>
              <name>SCEN</name>
              <bitOffset>5</bitOffset>
              <bitWidth>1</bitWidth>
            </field>
            <field>
              <name>DMAR</name>
              <bitOffset>6</bitOffset>
              <bitWidth>1</bitWidth>
            </field>
            <field>
              <name>DMAT</name>
              <bitOffset>7</bitOffset>
              <bitWidth>1</bitWidth>
            </field>
            <field>
              <name>RTSE</name>
              <bitOffset>8</bitOffset>
              <bitWidth>1</bitWidth>
            </field>
            <field>
              <name>CTSE</name>
              <bitOffset>9</bitOffset>
              <bitWidth>1</bitWidth>
            </field>
            <field>
              <name>CTSIE</name>
              <bitOffset>10</bitOffset>
              <bitWidth>1</bitWidth>
            </field>
            <field>
              <name>ONEBIT</name>
              <bitOffset>11</bitOffset>
              <bitWidth>1</bitWidth>
            </field>
            <field>
              <name>OVRDIS</name>
              <bitOffset>12</bitOffset>
              <bitWidth>1</bitWidth>
            </field>
            <field>
              <name>DDRE</name>
              <bitOffset>13</bitOffset>
              <bitWidth>1</bitWidth>
            </field>
            <field>
              <name>DEM</name>
              <bitOffset>14</bitOffset>
              <bitWidth>1</bitWidth>
            </field>
            <field>
              <name>DEP</name>
              <bitOffset>15</bitOffset>
              <bitWidth>1</bitWidth>
            </field>
            <field>
              <name>SCARCNT</name>
              <bitOffset>17</bitOffset>
              <bitWidth>3</bitWidth>
            </field>
            <field>
              <name>WUS</name>
              <bitOffset>20</bitOffset>
              <bitWidth>2</bitWidth>
            </field>
            <field>
              <name>WUFIE</name>
              <bitOffset>22</bitOffset>
              <bitWidth>1</bitWidth>
            </field>
            <field>
              <name>UCESM</name>
              <bitOffset>23</bitOffset>
              <bitWidth>1</bitWidth>
            </field>
          </fields>
        </register>
        <register>
          <name>BRR</name>
          <addressOffset>0xc</addressOffset>
          <size>0x20</size>
          <fields>
            <field>
              <name>DIV_FRACTION</name>
              <bitOffset>0</bitOffset>
              <bitWidth>4</bitWidth>
            </field>
            <field>
              <name>DIV_MANTISSA</name>
              <bitOffset>4</bitOffset>
              <bitWidth>12</bitWidth>
            </field>
          </fields>
        </register>
        <register>
          <name>GTPR</name>
          <addressOffset>0x10</addressOffset>
          <size>0x20</size>
          <fields>
            <field>
              <name>PSC</name>
              <bitOffset>0</bitOffset>
              <bitWidth>8</bitWidth>
            </field>
            <field>
              <name>GT</name>
              <bitOffset>8</bitOffset>
              <bitWidth>8</bitWidth>
            </field>
          </fields>
        </register>
        <register>
          <name>RTOR</name>
          <addressOffset>0x14</addressOffset>
          <size>0x20</size>
          <fields>
            <field>
              <name>RTO</name>
              <bitOffset>0</bitOffset>
              <bitWidth>24</bitWidth>
            </field>
            <field>
              <name>BLEN</name>
              <bitOffset>24</bitOffset>
              <bitWidth>8</bitWidth>
            </field>
          </fields>
        </register>
        <register>
          <name>RQR</name>
          <addressOffset>0x18</addressOffset>
          <size>0x20</size>
          <fields>
            <field>
              <name>ABRRQ</name>
              <bitOffset>0</bitOffset>
              <bitWidth>1</bitWidth>
            </field>
            <field>
              <name>SBKRQ</name>
              <bitOffset>1</bitOffset>
              <bitWidth>1</bitWidth>
            </field>
            <field>
              <name>MMRQ</name>
              <bitOffset>2</bitOffset>
              <bitWidth>1</bitWidth>
            </field>
            <field>
              <name>RXFRQ</name>
              <bitOffset>3</bitOffset>
              <bitWidth>1</bitWidth>
            </field>
            <field>
              <name>TXFRQ</name>
              <bitOffset>4</bitOffset>
              <bitWidth>1</bitWidth>
            </field>
          </fields>
        </register>
        <register>
          <name>ISR</name>
          <addressOffset>0x1c</addressOffset>
          <size>0x20</size>
          <fields>
            <field>
              <name>PE</name>
              <bitOffset>0</bitOffset>
              <bitWidth>1</bitWidth>
            </field>
            <field>
              <name>FE</name>
              <bitOffset>1</bitOffset>
              <bitWidth>1</bitWidth>
            </field>
            <field>
              <name>NE</name>
              <bitOffset>2</bitOffset>
              <bitWidth>1</bitWidth>
            </field>
            <field>
              <name>ORE</name>
              <bitOffset>3</bitOffset>
              <bitWidth>1</bitWidth>
            </field>
            <field>
              <name>IDLE</name>
              <bitOffset>4</bitOffset>
              <bitWidth>1</bitWidth>
            </field>
            <field>
              <name>RXNE</name>
              <bitOffset>5</bitOffset>
              <bitWidth>1</bitWidth>
            </field>
            <field>
              <name>TC</name>
              <bitOffset>6</bitOffset>
              <bitWidth>1</bitWidth>
            </field>
            <field>
              <name>TXE</name>
              <bitOffset>7</bitOffset>
              <bitWidth>1</bitWidth>
            </field>
            <field>
              <name>LBDF</name>
              <bitOffset>8</bitOffset>
              <bitWidth>1</bitWidth>
            </field>
            <field>
              <name>CTSIF</name>
              <bitOffset>9</bitOffset>
              <bitWidth>1</bitWidth>
            </field>
            <field>
              <name>CTS</name>
              <bitOffset>10</bitOffset>
              <bitWidth>1</bitWidth>
            </field>
            <field>
              <name>RTOF</name>
              <bitOffset>11</bitOffset>
              <bitWidth>1</bitWidth>
            </field>
            <field>
              <name>EOBF</name>
              <bitOffset>12</bitOffset>
              <bitWidth>1</bitWidth>
            </field>
            <field>
              <name>ABRE</name>
              <bitOffset>14</bitOffset>
              <bitWidth>1</bitWidth>
            </field>
            <field>
              <name>ABRF</name>
              <bitOffset>15</bitOffset>
              <bitWidth>1</bitWidth>
            </field>
            <field>
              <name>BUSY</name>
              <bitOffset>16</bitOffset>
              <bitWidth>1</bitWidth>
            </field>
            <field>
              <name>CMF</name>
              <bitOffset>17</bitOffset>
              <bitWidth>1</bitWidth>
            </field>
            <field>
              <name>SBKF</name>
              <bitOffset>18</bitOffset>
              <bitWidth>1</bitWidth>
            </field>
            <field>
              <name>RWU</name>
              <bitOffset>19</bitOffset>
              <bitWidth>1</bitWidth>
            </field>
            <field>
              <name>WUF</name>
              <bitOffset>20</bitOffset>
              <bitWidth>1</bitWidth>
            </field>
            <field>
              <name>TEACK</name>
              <bitOffset>21</bitOffset>
              <bitWidth>1</bitWidth>
            </field>
            <field>
              <name>REACK</name>
              <bitOffset>22</bitOffset>
              <bitWidth>1</bitWidth>
            </field>
          </fields>
        </register>
        <register>
          <name>ICR</name>
          <addressOffset>0x20</addressOffset>
          <size>0x20</size>
          <fields>
            <field>
              <name>PECF</name>
              <bitOffset>0</bitOffset>
              <bitWidth>1</bitWidth>
            </field>
            <field>
              <name>FECF</name>
              <bitOffset>1</bitOffset>
              <bitWidth>1</bitWidth>
            </field>
            <field>
              <name>NCF</name>
              <bitOffset>2</bitOffset>
              <bitWidth>1</bitWidth>
            </field>
            <field>
              <name>ORECF</name>
              <bitOffset>3</bitOffset>
              <bitWidth>1</bitWidth>
            </field>
            <field>
              <name>IDLECF</name>
              <bitOffset>4</bitOffset>
              <bitWidth>1</bitWidth>
            </field>
            <field>
              <name>TCCF</name>
              <bitOffset>6</bitOffset>
              <bitWidth>1</bitWidth>
            </field>
            <field>
              <name>LBDCF</name>
              <bitOffset>8</bitOffset>
              <bitWidth>1</bitWidth>
            </field>
            <field>
              <name>CTSCF</name>
              <bitOffset>9</bitOffset>
              <bitWidth>1</bitWidth>
            </field>
            <field>
              <name>RTOCF</name>
              <bitOffset>11</bitOffset>
              <bitWidth>1</bitWidth>
            </field>
            <field>
              <name>EOBCF</name>
              <bitOffset>12</bitOffset>
              <bitWidth>1</bitWidth>
            </field>
            <field>
              <name>CMCF</name>
              <bitOffset>17</bitOffset>
              <bitWidth>1</bitWidth>
            </field>
            <field>
              <name>WUCF</name>
              <bitOffset>20</bitOffset>
              <bitWidth>1</bitWidth>
            </field>
          </fields>
        </register>
        <register>
          <name>RDR</name>
          <addressOffset>0x24</addressOffset>
          <size>0x20</size>
          <fields>
            <field>
              <name>RDR</name>
              <bitOffset>0</bitOffset>
              <bitWidth>9</bitWidth>
            </field>
          </fields>
        </register>
        <register>
          <name>TDR</name>
          <addressOffset>0x28</addressOffset>
          <size>0x20</size>
          <fields>
            <field>
              <name>TDR</name>
              <bitOffset>0</bitOffset>
              <bitWidth>9</bitWidth>
            </field>
          </fields>
        </register>
      </registers>
    </peripheral>
    <peripheral>
      <name>UART4</name>
      <baseAddress>0x40004c00</baseAddress>
      <registers>
        <register>
          <name>CR1</name>
          <addressOffset>0x0</addressOffset>
          <size>0x20</size>
          <fields>
            <field>
              <name>UE</name>
              <bitOffset>0</bitOffset>
              <bitWidth>1</bitWidth>
            </field>
            <field>
              <name>UESM</name>
              <bitOffset>1</bitOffset>
              <bitWidth>1</bitWidth>
            </field>
            <field>
              <name>RE</name>
              <bitOffset>2</bitOffset>
              <bitWidth>1</bitWidth>
            </field>
            <field>
              <name>TE</name>
              <bitOffset>3</bitOffset>
              <bitWidth>1</bitWidth>
            </field>
            <field>
              <name>IDLEIE</name>
              <bitOffset>4</bitOffset>
              <bitWidth>1</bitWidth>
            </field>
            <field>
              <name>RXNEIE</name>
              <bitOffset>5</bitOffset>
              <bitWidth>1</bitWidth>
            </field>
            <field>
              <name>TCIE</name>
              <bitOffset>6</bitOffset>
              <bitWidth>1</bitWidth>
            </field>
            <field>
              <name>TXEIE</name>
              <bitOffset>7</bitOffset>
              <bitWidth>1</bitWidth>
            </field>
            <field>
              <name>PEIE</name>
              <bitOffset>8</bitOffset>
              <bitWidth>1</bitWidth>
            </field>
            <field>
              <name>PS</name>
              <bitOffset>9</bitOffset>
              <bitWidth>1</bitWidth>
            </field>
            <field>
              <name>PCE</name>
              <bitOffset>10</bitOffset>
              <bitWidth>1</bitWidth>
            </field>
            <field>
              <name>WAKE</name>
              <bitOffset>11</bitOffset>
              <bitWidth>1</bitWidth>
            </field>
            <field>
              <name>M</name>
              <bitOffset>12</bitOffset>
              <bitWidth>17</bitWidth>
            </field>
            <field>
              <name>MME</name>
              <bitOffset>13</bitOffset>
              <bitWidth>1</bitWidth>
            </field>
            <field>
              <name>CMIE</name>
              <bitOffset>14</bitOffset>
              <bitWidth>1</bitWidth>
            </field>
            <field>
              <name>OVER8</name>
              <bitOffset>15</bitOffset>
              <bitWidth>1</bitWidth>
            </field>
            <field>
              <name>DEDT</name>
              <bitOffset>16</bitOffset>
              <bitWidth>5</bitWidth>
            </field>
            <field>
              <name>DEAT</name>
              <bitOffset>21</bitOffset>
              <bitWidth>5</bitWidth>
            </field>
            <field>
              <name>RTOIE</name>
              <bitOffset>26</bitOffset>
              <bitWidth>1</bitWidth>
            </field>
            <field>
              <name>EOBIE</name>
              <bitOffset>27</bitOffset>
              <bitWidth>1</bitWidth>
            </field>
          </fields>
        </register>
        <register>
          <name>CR2</name>
          <addressOffset>0x4</addressOffset>
          <size>0x20</size>
          <fields>
            <field>
              <name>ADDM7</name>
              <bitOffset>4</bitOffset>
              <bitWidth>1</bitWidth>
            </field>
            <field>
              <name>LBDL</name>
              <bitOffset>5</bitOffset>
              <bitWidth>1</bitWidth>
            </field>
            <field>
              <name>LBDIE</name>
              <bitOffset>6</bitOffset>
              <bitWidth>1</bitWidth>
            </field>
            <field>
              <name>LBCL</name>
              <bitOffset>8</bitOffset>
              <bitWidth>1</bitWidth>
            </field>
            <field>
              <name>CPHA</name>
              <bitOffset>9</bitOffset>
              <bitWidth>1</bitWidth>
            </field>
            <field>
              <name>CPOL</name>
              <bitOffset>10</bitOffset>
              <bitWidth>1</bitWidth>
            </field>
            <field>
              <name>CLKEN</name>
              <bitOffset>11</bitOffset>
              <bitWidth>1</bitWidth>
            </field>
            <field>
              <name>STOP</name>
              <bitOffset>12</bitOffset>
              <bitWidth>2</bitWidth>
            </field>
            <field>
              <name>LINEN</name>
              <bitOffset>14</bitOffset>
              <bitWidth>1</bitWidth>
            </field>
            <field>
              <name>SWAP</name>
              <bitOffset>15</bitOffset>
              <bitWidth>1</bitWidth>
            </field>
            <field>
              <name>RXINV</name>
              <bitOffset>16</bitOffset>
              <bitWidth>1</bitWidth>
            </field>
            <field>
              <name>TXINV</name>
              <bitOffset>17</bitOffset>
              <bitWidth>1</bitWidth>
            </field>
            <field>
              <name>DATAINV</name>
              <bitOffset>18</bitOffset>
              <bitWidth>1</bitWidth>
            </field>
            <field>
              <name>MSBFIRST</name>
              <bitOffset>19</bitOffset>
              <bitWidth>1</bitWidth>
            </field>
            <field>
              <name>ABREN</name>
              <bitOffset>20</bitOffset>
              <bitWidth>1</bitWidth>
            </field>
            <field>
              <name>ABRMODE</name>
              <bitOffset>21</bitOffset>
              <bitWidth>2</bitWidth>
            </field>
            <field>
              <name>RTOEN</name>
              <bitOffset>23</bitOffset>
              <bitWidth>1</bitWidth>
            </field>
            <field>
              <name>ADD</name>
              <bitOffset>24</bitOffset>
              <bitWidth>8</bitWidth>
            </field>
          </fields>
        </register>
        <register>
          <name>CR3</name>
          <addressOffset>0x8</addressOffset>
          <size>0x20</size>
          <fields>
            <field>
              <name>EIE</name>
              <bitOffset>0</bitOffset>
              <bitWidth>1</bitWidth>
            </field>
            <field>
              <name>IREN</name>
              <bitOffset>1</bitOffset>
              <bitWidth>1</bitWidth>
            </field>
            <field>
              <name>IRLP</name>
              <bitOffset>2</bitOffset>
              <bitWidth>1</bitWidth>
            </field>
            <field>
              <name>HDSEL</name>
              <bitOffset>3</bitOffset>
              <bitWidth>1</bitWidth>
            </field>
            <field>
              <name>NACK</name>
              <bitOffset>4</bitOffset>
              <bitWidth>1</bitWidth>
            </field>
            <field>
              <name>SCEN</name>
              <bitOffset>5</bitOffset>
              <bitWidth>1</bitWidth>
            </field>
            <field>
              <name>DMAR</name>
              <bitOffset>6</bitOffset>
              <bitWidth>1</bitWidth>
            </field>
            <field>
              <name>DMAT</name>
              <bitOffset>7</bitOffset>
              <bitWidth>1</bitWidth>
            </field>
            <field>
              <name>RTSE</name>
              <bitOffset>8</bitOffset>
              <bitWidth>1</bitWidth>
            </field>
            <field>
              <name>CTSE</name>
              <bitOffset>9</bitOffset>
              <bitWidth>1</bitWidth>
            </field>
            <field>
              <name>CTSIE</name>
              <bitOffset>10</bitOffset>
              <bitWidth>1</bitWidth>
            </field>
            <field>
              <name>ONEBIT</name>
              <bitOffset>11</bitOffset>
              <bitWidth>1</bitWidth>
            </field>
            <field>
              <name>OVRDIS</name>
              <bitOffset>12</bitOffset>
              <bitWidth>1</bitWidth>
            </field>
            <field>
              <name>DDRE</name>
              <bitOffset>13</bitOffset>
              <bitWidth>1</bitWidth>
            </field>
            <field>
              <name>DEM</name>
              <bitOffset>14</bitOffset>
              <bitWidth>1</bitWidth>
            </field>
            <field>
              <name>DEP</name>
              <bitOffset>15</bitOffset>
              <bitWidth>1</bitWidth>
            </field>
            <field>
              <name>SCARCNT</name>
              <bitOffset>17</bitOffset>
              <bitWidth>3</bitWidth>
            </field>
            <field>
              <name>WUS</name>
              <bitOffset>20</bitOffset>
              <bitWidth>2</bitWidth>
            </field>
            <field>
              <name>WUFIE</name>
              <bitOffset>22</bitOffset>
              <bitWidth>1</bitWidth>
            </field>
            <field>
              <name>UCESM</name>
              <bitOffset>23</bitOffset>
              <bitWidth>1</bitWidth>
            </field>
          </fields>
        </register>
        <register>
          <name>BRR</name>
          <addressOffset>0xc</addressOffset>
          <size>0x20</size>
          <fields>
            <field>
              <name>DIV_FRACTION</name>
              <bitOffset>0</bitOffset>
              <bitWidth>4</bitWidth>
            </field>
            <field>
              <name>DIV_MANTISSA</name>
              <bitOffset>4</bitOffset>
              <bitWidth>12</bitWidth>
            </field>
          </fields>
        </register>
        <register>
          <name>GTPR</name>
          <addressOffset>0x10</addressOffset>
          <size>0x20</size>
          <fields>
            <field>
              <name>PSC</name>
              <bitOffset>0</bitOffset>
              <bitWidth>8</bitWidth>
            </field>
            <field>
              <name>GT</name>
              <bitOffset>8</bitOffset>
              <bitWidth>8</bitWidth>
            </field>
          </fields>
        </register>
        <register>
          <name>RTOR</name>
          <addressOffset>0x14</addressOffset>
          <size>0x20</size>
          <fields>
            <field>
              <name>RTO</name>
              <bitOffset>0</bitOffset>
              <bitWidth>24</bitWidth>
            </field>
            <field>
              <name>BLEN</name>
              <bitOffset>24</bitOffset>
              <bitWidth>8</bitWidth>
            </field>
          </fields>
        </register>
        <register>
          <name>RQR</name>
          <addressOffset>0x18</addressOffset>
          <size>0x20</size>
          <fields>
            <field>
              <name>ABRRQ</name>
              <bitOffset>0</bitOffset>
              <bitWidth>1</bitWidth>
            </field>
            <field>
              <name>SBKRQ</name>
              <bitOffset>1</bitOffset>
              <bitWidth>1</bitWidth>
            </field>
            <field>
              <name>MMRQ</name>
              <bitOffset>2</bitOffset>
              <bitWidth>1</bitWidth>
            </field>
            <field>
              <name>RXFRQ</name>
              <bitOffset>3</bitOffset>
              <bitWidth>1</bitWidth>
            </field>
            <field>
              <name>TXFRQ</name>
              <bitOffset>4</bitOffset>
              <bitWidth>1</bitWidth>
            </field>
          </fields>
        </register>
        <register>
          <name>ISR</name>
          <addressOffset>0x1c</addressOffset>
          <size>0x20</size>
          <fields>
            <field>
              <name>PE</name>
              <bitOffset>0</bitOffset>
              <bitWidth>1</bitWidth>
            </field>
            <field>
              <name>FE</name>
              <bitOffset>1</bitOffset>
              <bitWidth>1</bitWidth>
            </field>
            <field>
              <name>NE</name>
              <bitOffset>2</bitOffset>
              <bitWidth>1</bitWidth>
            </field>
            <field>
              <name>ORE</name>
              <bitOffset>3</bitOffset>
              <bitWidth>1</bitWidth>
            </field>
            <field>
              <name>IDLE</name>
              <bitOffset>4</bitOffset>
              <bitWidth>1</bitWidth>
            </field>
            <field>
              <name>RXNE</name>
              <bitOffset>5</bitOffset>
              <bitWidth>1</bitWidth>
            </field>
            <field>
              <name>TC</name>
              <bitOffset>6</bitOffset>
              <bitWidth>1</bitWidth>
            </field>
            <field>
              <name>TXE</name>
              <bitOffset>7</bitOffset>
              <bitWidth>1</bitWidth>
            </field>
            <field>
              <name>LBDF</name>
              <bitOffset>8</bitOffset>
              <bitWidth>1</bitWidth>
            </field>
            <field>
              <name>CTSIF</name>
              <bitOffset>9</bitOffset>
              <bitWidth>1</bitWidth>
            </field>
            <field>
              <name>CTS</name>
              <bitOffset>10</bitOffset>
              <bitWidth>1</bitWidth>
            </field>
            <field>
              <name>RTOF</name>
              <bitOffset>11</bitOffset>
              <bitWidth>1</bitWidth>
            </field>
            <field>
              <name>EOBF</name>
              <bitOffset>12</bitOffset>
              <bitWidth>1</bitWidth>
            </field>
            <field>
              <name>ABRE</name>
              <bitOffset>14</bitOffset>
              <bitWidth>1</bitWidth>
            </field>
            <field>
              <name>ABRF</name>
              <bitOffset>15</bitOffset>
              <bitWidth>1</bitWidth>
            </field>
            <field>
              <name>BUSY</name>
              <bitOffset>16</bitOffset>
              <bitWidth>1</bitWidth>
            </field>
            <field>
              <name>CMF</name>
              <bitOffset>17</bitOffset>
              <bitWidth>1</bitWidth>
            </field>
            <field>
              <name>SBKF</name>
              <bitOffset>18</bitOffset>
              <bitWidth>1</bitWidth>
            </field>
            <field>
              <name>RWU</name>
              <bitOffset>19</bitOffset>
              <bitWidth>1</bitWidth>
            </field>
            <field>
              <name>WUF</name>
              <bitOffset>20</bitOffset>
              <bitWidth>1</bitWidth>
            </field>
            <field>
              <name>TEACK</name>
              <bitOffset>21</bitOffset>
              <bitWidth>1</bitWidth>
            </field>
            <field>
              <name>REACK</name>
              <bitOffset>22</bitOffset>
              <bitWidth>1</bitWidth>
            </field>
          </fields>
        </register>
        <register>
          <name>ICR</name>
          <addressOffset>0x20</addressOffset>
          <size>0x20</size>
          <fields>
            <field>
              <name>PECF</name>
              <bitOffset>0</bitOffset>
              <bitWidth>1</bitWidth>
            </field>
            <field>
              <name>FECF</name>
              <bitOffset>1</bitOffset>
              <bitWidth>1</bitWidth>
            </field>
            <field>
              <name>NCF</name>
              <bitOffset>2</bitOffset>
              <bitWidth>1</bitWidth>
            </field>
            <field>
              <name>ORECF</name>
              <bitOffset>3</bitOffset>
              <bitWidth>1</bitWidth>
            </field>
            <field>
              <name>IDLECF</name>
              <bitOffset>4</bitOffset>
              <bitWidth>1</bitWidth>
            </field>
            <field>
              <name>TCCF</name>
              <bitOffset>6</bitOffset>
              <bitWidth>1</bitWidth>
            </field>
            <field>
              <name>LBDCF</name>
              <bitOffset>8</bitOffset>
              <bitWidth>1</bitWidth>
            </field>
            <field>
              <name>CTSCF</name>
              <bitOffset>9</bitOffset>
              <bitWidth>1</bitWidth>
            </field>
            <field>
              <name>RTOCF</name>
              <bitOffset>11</bitOffset>
              <bitWidth>1</bitWidth>
            </field>
            <field>
              <name>EOBCF</name>
              <bitOffset>12</bitOffset>
              <bitWidth>1</bitWidth>
            </field>
            <field>
              <name>CMCF</name>
              <bitOffset>17</bitOffset>
              <bitWidth>1</bitWidth>
            </field>
            <field>
              <name>WUCF</name>
              <bitOffset>20</bitOffset>
              <bitWidth>1</bitWidth>
            </field>
          </fields>
        </register>
        <register>
          <name>RDR</name>
          <addressOffset>0x24</addressOffset>
          <size>0x20</size>
          <fields>
            <field>
              <name>RDR</name>
              <bitOffset>0</bitOffset>
              <bitWidth>9</bitWidth>
            </field>
          </fields>
        </register>
        <register>
          <name>TDR</name>
          <addressOffset>0x28</addressOffset>
          <size>0x20</size>
          <fields>
            <field>
              <name>TDR</name>
              <bitOffset>0</bitOffset>
              <bitWidth>9</bitWidth>
            </field>
          </fields>
        </register>
      </registers>
    </peripheral>
    <peripheral>
      <name>UART5</name>
      <baseAddress>0x40005000</baseAddress>
      <registers>
        <register>
          <name>CR1</name>
          <addressOffset>0x0</addressOffset>
          <size>0x20</size>
          <fields>
            <field>
              <name>UE</name>
              <bitOffset>0</bitOffset>
              <bitWidth>1</bitWidth>
            </field>
            <field>
              <name>UESM</name>
              <bitOffset>1</bitOffset>
              <bitWidth>1</bitWidth>
            </field>
            <field>
              <name>RE</name>
              <bitOffset>2</bitOffset>
              <bitWidth>1</bitWidth>
            </field>
            <field>
              <name>TE</name>
              <bitOffset>3</bitOffset>
              <bitWidth>1</bitWidth>
            </field>
            <field>
              <name>IDLEIE</name>
              <bitOffset>4</bitOffset>
              <bitWidth>1</bitWidth>
            </field>
            <field>
              <name>RXNEIE</name>
              <bitOffset>5</bitOffset>
              <bitWidth>1</bitWidth>
            </field>
            <field>
              <name>TCIE</name>
              <bitOffset>6</bitOffset>
              <bitWidth>1</bitWidth>
            </field>
            <field>
              <name>TXEIE</name>
              <bitOffset>7</bitOffset>
              <bitWidth>1</bitWidth>
            </field>
            <field>
              <name>PEIE</name>
              <bitOffset>8</bitOffset>
              <bitWidth>1</bitWidth>
            </field>
            <field>
              <name>PS</name>
              <bitOffset>9</bitOffset>
              <bitWidth>1</bitWidth>
            </field>
            <field>
              <name>PCE</name>
              <bitOffset>10</bitOffset>
              <bitWidth>1</bitWidth>
            </field>
            <field>
              <name>WAKE</name>
              <bitOffset>11</bitOffset>
              <bitWidth>1</bitWidth>
            </field>
            <field>
              <name>M</name>
              <bitOffset>12</bitOffset>
              <bitWidth>17</bitWidth>
            </field>
            <field>
              <name>MME</name>
              <bitOffset>13</bitOffset>
              <bitWidth>1</bitWidth>
            </field>
            <field>
              <name>CMIE</name>
              <bitOffset>14</bitOffset>
              <bitWidth>1</bitWidth>
            </field>
            <field>
              <name>OVER8</name>
              <bitOffset>15</bitOffset>
              <bitWidth>1</bitWidth>
            </field>
            <field>
              <name>DEDT</name>
              <bitOffset>16</bitOffset>
              <bitWidth>5</bitWidth>
            </field>
            <field>
              <name>DEAT</name>
              <bitOffset>21</bitOffset>
              <bitWidth>5</bitWidth>
            </field>
            <field>
              <name>RTOIE</name>
              <bitOffset>26</bitOffset>
              <bitWidth>1</bitWidth>
            </field>
            <field>
              <name>EOBIE</name>
              <bitOffset>27</bitOffset>
              <bitWidth>1</bitWidth>
            </field>
          </fields>
        </register>
        <register>
          <name>CR2</name>
          <addressOffset>0x4</addressOffset>
          <size>0x20</size>
          <fields>
            <field>
              <name>ADDM7</name>
              <bitOffset>4</bitOffset>
              <bitWidth>1</bitWidth>
            </field>
            <field>
              <name>LBDL</name>
              <bitOffset>5</bitOffset>
              <bitWidth>1</bitWidth>
            </field>
            <field>
              <name>LBDIE</name>
              <bitOffset>6</bitOffset>
              <bitWidth>1</bitWidth>
            </field>
            <field>
              <name>LBCL</name>
              <bitOffset>8</bitOffset>
              <bitWidth>1</bitWidth>
            </field>
            <field>
              <name>CPHA</name>
              <bitOffset>9</bitOffset>
              <bitWidth>1</bitWidth>
            </field>
            <field>
              <name>CPOL</name>
              <bitOffset>10</bitOffset>
              <bitWidth>1</bitWidth>
            </field>
            <field>
              <name>CLKEN</name>
              <bitOffset>11</bitOffset>
              <bitWidth>1</bitWidth>
            </field>
            <field>
              <name>STOP</name>
              <bitOffset>12</bitOffset>
              <bitWidth>2</bitWidth>
            </field>
            <field>
              <name>LINEN</name>
              <bitOffset>14</bitOffset>
              <bitWidth>1</bitWidth>
            </field>
            <field>
              <name>SWAP</name>
              <bitOffset>15</bitOffset>
              <bitWidth>1</bitWidth>
            </field>
            <field>
              <name>RXINV</name>
              <bitOffset>16</bitOffset>
              <bitWidth>1</bitWidth>
            </field>
            <field>
              <name>TXINV</name>
              <bitOffset>17</bitOffset>
              <bitWidth>1</bitWidth>
            </field>
            <field>
              <name>DATAINV</name>
              <bitOffset>18</bitOffset>
              <bitWidth>1</bitWidth>
            </field>
            <field>
              <name>MSBFIRST</name>
              <bitOffset>19</bitOffset>
              <bitWidth>1</bitWidth>
            </field>
            <field>
              <name>ABREN</name>
              <bitOffset>20</bitOffset>
              <bitWidth>1</bitWidth>
            </field>
            <field>
              <name>ABRMODE</name>
              <bitOffset>21</bitOffset>
              <bitWidth>2</bitWidth>
            </field>
            <field>
              <name>RTOEN</name>
              <bitOffset>23</bitOffset>
              <bitWidth>1</bitWidth>
            </field>
            <field>
              <name>ADD</name>
              <bitOffset>24</bitOffset>
              <bitWidth>8</bitWidth>
            </field>
          </fields>
        </register>
        <register>
          <name>CR3</name>
          <addressOffset>0x8</addressOffset>
          <size>0x20</size>
          <fields>
            <field>
              <name>EIE</name>
              <bitOffset>0</bitOffset>
              <bitWidth>1</bitWidth>
            </field>
            <field>
              <name>IREN</name>
              <bitOffset>1</bitOffset>
              <bitWidth>1</bitWidth>
            </field>
            <field>
              <name>IRLP</name>
              <bitOffset>2</bitOffset>
              <bitWidth>1</bitWidth>
            </field>
            <field>
              <name>HDSEL</name>
              <bitOffset>3</bitOffset>
              <bitWidth>1</bitWidth>
            </field>
            <field>
              <name>NACK</name>
              <bitOffset>4</bitOffset>
              <bitWidth>1</bitWidth>
            </field>
            <field>
              <name>SCEN</name>
              <bitOffset>5</bitOffset>
              <bitWidth>1</bitWidth>
            </field>
            <field>
              <name>DMAR</name>
              <bitOffset>6</bitOffset>
              <bitWidth>1</bitWidth>
            </field>
            <field>
              <name>DMAT</name>
              <bitOffset>7</bitOffset>
              <bitWidth>1</bitWidth>
            </field>
            <field>
              <name>RTSE</name>
              <bitOffset>8</bitOffset>
              <bitWidth>1</bitWidth>
            </field>
            <field>
              <name>CTSE</name>
              <bitOffset>9</bitOffset>
              <bitWidth>1</bitWidth>
            </field>
            <field>
              <name>CTSIE</name>
              <bitOffset>10</bitOffset>
              <bitWidth>1</bitWidth>
            </field>
            <field>
              <name>ONEBIT</name>
              <bitOffset>11</bitOffset>
              <bitWidth>1</bitWidth>
            </field>
            <field>
              <name>OVRDIS</name>
              <bitOffset>12</bitOffset>
              <bitWidth>1</bitWidth>
            </field>
            <field>
              <name>DDRE</name>
              <bitOffset>13</bitOffset>
              <bitWidth>1</bitWidth>
            </field>
            <field>
              <name>DEM</name>
              <bitOffset>14</bitOffset>
              <bitWidth>1</bitWidth>
            </field>
            <field>
              <name>DEP</name>
              <bitOffset>15</bitOffset>
              <bitWidth>1</bitWidth>
            </field>
            <field>
              <name>SCARCNT</name>
              <bitOffset>17</bitOffset>
              <bitWidth>3</bitWidth>
            </field>
            <field>
              <name>WUS</name>
              <bitOffset>20</bitOffset>
              <bitWidth>2</bitWidth>
            </field>
            <field>
              <name>WUFIE</name>
              <bitOffset>22</bitOffset>
              <bitWidth>1</bitWidth>
            </field>
            <field>
              <name>UCESM</name>
              <bitOffset>23</bitOffset>
              <bitWidth>1</bitWidth>
            </field>
          </fields>
        </register>
        <register>
          <name>BRR</name>
          <addressOffset>0xc</addressOffset>
          <size>0x20</size>
          <fields>
            <field>
              <name>DIV_FRACTION</name>
              <bitOffset>0</bitOffset>
              <bitWidth>4</bitWidth>
            </field>
            <field>
              <name>DIV_MANTISSA</name>
              <bitOffset>4</bitOffset>
              <bitWidth>12</bitWidth>
            </field>
          </fields>
        </register>
        <register>
          <name>GTPR</name>
          <addressOffset>0x10</addressOffset>
          <size>0x20</size>
          <fields>
            <field>
              <name>PSC</name>
              <bitOffset>0</bitOffset>
              <bitWidth>8</bitWidth>
            </field>
            <field>
              <name>GT</name>
              <bitOffset>8</bitOffset>
              <bitWidth>8</bitWidth>
            </field>
          </fields>
        </register>
        <register>
          <name>RTOR</name>
          <addressOffset>0x14</addressOffset>
          <size>0x20</size>
          <fields>
            <field>
              <name>RTO</name>
              <bitOffset>0</bitOffset>
              <bitWidth>24</bitWidth>
            </field>
            <field>
              <name>BLEN</name>
              <bitOffset>24</bitOffset>
              <bitWidth>8</bitWidth>
            </field>
          </fields>
        </register>
        <register>
          <name>RQR</name>
          <addressOffset>0x18</addressOffset>
          <size>0x20</size>
          <fields>
            <field>
              <name>ABRRQ</name>
              <bitOffset>0</bitOffset>
              <bitWidth>1</bitWidth>
            </field>
            <field>
              <name>SBKRQ</name>
              <bitOffset>1</bitOffset>
              <bitWidth>1</bitWidth>
            </field>
            <field>
              <name>MMRQ</name>
              <bitOffset>2</bitOffset>
              <bitWidth>1</bitWidth>
            </field>
            <field>
              <name>RXFRQ</name>
              <bitOffset>3</bitOffset>
              <bitWidth>1</bitWidth>
            </field>
            <field>
              <name>TXFRQ</name>
              <bitOffset>4</bitOffset>
              <bitWidth>1</bitWidth>
            </field>
          </fields>
        </register>
        <register>
          <name>ISR</name>
          <addressOffset>0x1c</addressOffset>
          <size>0x20</size>
          <fields>
            <field>
              <name>PE</name>
              <bitOffset>0</bitOffset>
              <bitWidth>1</bitWidth>
            </field>
            <field>
              <name>FE</name>
              <bitOffset>1</bitOffset>
              <bitWidth>1</bitWidth>
            </field>
            <field>
              <name>NE</name>
              <bitOffset>2</bitOffset>
              <bitWidth>1</bitWidth>
            </field>
            <field>
              <name>ORE</name>
              <bitOffset>3</bitOffset>
              <bitWidth>1</bitWidth>
            </field>
            <field>
              <name>IDLE</name>
              <bitOffset>4</bitOffset>
              <bitWidth>1</bitWidth>
            </field>
            <field>
              <name>RXNE</name>
              <bitOffset>5</bitOffset>
              <bitWidth>1</bitWidth>
            </field>
            <field>
              <name>TC</name>
              <bitOffset>6</bitOffset>
              <bitWidth>1</bitWidth>
            </field>
            <field>
              <name>TXE</name>
              <bitOffset>7</bitOffset>
              <bitWidth>1</bitWidth>
            </field>
            <field>
              <name>LBDF</name>
              <bitOffset>8</bitOffset>
              <bitWidth>1</bitWidth>
            </field>
            <field>
              <name>CTSIF</name>
              <bitOffset>9</bitOffset>
              <bitWidth>1</bitWidth>
            </field>
            <field>
              <name>CTS</name>
              <bitOffset>10</bitOffset>
              <bitWidth>1</bitWidth>
            </field>
            <field>
              <name>RTOF</name>
              <bitOffset>11</bitOffset>
              <bitWidth>1</bitWidth>
            </field>
            <field>
              <name>EOBF</name>
              <bitOffset>12</bitOffset>
              <bitWidth>1</bitWidth>
            </field>
            <field>
              <name>ABRE</name>
              <bitOffset>14</bitOffset>
              <bitWidth>1</bitWidth>
            </field>
            <field>
              <name>ABRF</name>
              <bitOffset>15</bitOffset>
              <bitWidth>1</bitWidth>
            </field>
            <field>
              <name>BUSY</name>
              <bitOffset>16</bitOffset>
              <bitWidth>1</bitWidth>
            </field>
            <field>
              <name>CMF</name>
              <bitOffset>17</bitOffset>
              <bitWidth>1</bitWidth>
            </field>
            <field>
              <name>SBKF</name>
              <bitOffset>18</bitOffset>
              <bitWidth>1</bitWidth>
            </field>
            <field>
              <name>RWU</name>
              <bitOffset>19</bitOffset>
              <bitWidth>1</bitWidth>
            </field>
            <field>
              <name>WUF</name>
              <bitOffset>20</bitOffset>
              <bitWidth>1</bitWidth>
            </field>
            <field>
              <name>TEACK</name>
              <bitOffset>21</bitOffset>
              <bitWidth>1</bitWidth>
            </field>
            <field>
              <name>REACK</name>
              <bitOffset>22</bitOffset>
              <bitWidth>1</bitWidth>
            </field>
          </fields>
        </register>
        <register>
          <name>ICR</name>
          <addressOffset>0x20</addressOffset>
          <size>0x20</size>
          <fields>
            <field>
              <name>PECF</name>
              <bitOffset>0</bitOffset>
              <bitWidth>1</bitWidth>
            </field>
            <field>
              <name>FECF</name>
              <bitOffset>1</bitOffset>
              <bitWidth>1</bitWidth>
            </field>
            <field>
              <name>NCF</name>
              <bitOffset>2</bitOffset>
              <bitWidth>1</bitWidth>
            </field>
            <field>
              <name>ORECF</name>
              <bitOffset>3</bitOffset>
              <bitWidth>1</bitWidth>
            </field>
            <field>
              <name>IDLECF</name>
              <bitOffset>4</bitOffset>
              <bitWidth>1</bitWidth>
            </field>
            <field>
              <name>TCCF</name>
              <bitOffset>6</bitOffset>
              <bitWidth>1</bitWidth>
            </field>
            <field>
              <name>LBDCF</name>
              <bitOffset>8</bitOffset>
              <bitWidth>1</bitWidth>
            </field>
            <field>
              <name>CTSCF</name>
              <bitOffset>9</bitOffset>
              <bitWidth>1</bitWidth>
            </field>
            <field>
              <name>RTOCF</name>
              <bitOffset>11</bitOffset>
              <bitWidth>1</bitWidth>
            </field>
            <field>
              <name>EOBCF</name>
              <bitOffset>12</bitOffset>
              <bitWidth>1</bitWidth>
            </field>
            <field>
              <name>CMCF</name>
              <bitOffset>17</bitOffset>
              <bitWidth>1</bitWidth>
            </field>
            <field>
              <name>WUCF</name>
              <bitOffset>20</bitOffset>
              <bitWidth>1</bitWidth>
            </field>
          </fields>
        </register>
        <register>
          <name>RDR</name>
          <addressOffset>0x24</addressOffset>
          <size>0x20</size>
          <fields>
            <field>
              <name>RDR</name>
              <bitOffset>0</bitOffset>
              <bitWidth>9</bitWidth>
            </field>
          </fields>
        </register>
        <register>
          <name>TDR</name>
          <addressOffset>0x28</addressOffset>
          <size>0x20</size>
          <fields>
            <field>
              <name>TDR</name>
              <bitOffset>0</bitOffset>
              <bitWidth>9</bitWidth>
            </field>
          </fields>
        </register>
      </registers>
    </peripheral>
    <peripheral>
      <name>I2C1</name>
      <baseAddress>0x40005400</baseAddress>
      <registers>
        <register>
          <name>CR1</name>
          <addressOffset>0x0</addressOffset>
          <size>0x20</size>
          <fields>
            <field>
              <name>PE</name>
              <bitOffset>0</bitOffset>
              <bitWidth>1</bitWidth>
            </field>
            <field>
              <name>TXIE</name>
              <bitOffset>1</bitOffset>
              <bitWidth>1</bitWidth>
            </field>
            <field>
              <name>RXIE</name>
              <bitOffset>2</bitOffset>
              <bitWidth>1</bitWidth>
            </field>
            <field>
              <name>ADDRIE</name>
              <bitOffset>3</bitOffset>
              <bitWidth>1</bitWidth>
            </field>
            <field>
              <name>NACKIE</name>
              <bitOffset>4</bitOffset>
              <bitWidth>1</bitWidth>
            </field>
            <field>
              <name>STOPIE</name>
              <bitOffset>5</bitOffset>
              <bitWidth>1</bitWidth>
            </field>
            <field>
              <name>TCIE</name>
              <bitOffset>6</bitOffset>
              <bitWidth>1</bitWidth>
            </field>
            <field>
              <name>ERRIE</name>
              <bitOffset>7</bitOffset>
              <bitWidth>1</bitWidth>
            </field>
            <field>
              <name>DNF</name>
              <bitOffset>8</bitOffset>
              <bitWidth>4</bitWidth>
            </field>
            <field>
              <name>ANFOFF</name>
              <bitOffset>12</bitOffset>
              <bitWidth>1</bitWidth>
            </field>
            <field>
              <name>TXDMAEN</name>
              <bitOffset>14</bitOffset>
              <bitWidth>1</bitWidth>
            </field>
            <field>
              <name>RXDMAEN</name>
              <bitOffset>15</bitOffset>
              <bitWidth>1</bitWidth>
            </field>
            <field>
              <name>SBC</name>
              <bitOffset>16</bitOffset>
              <bitWidth>1</bitWidth>
            </field>
            <field>
              <name>NOSTRETCH</name>
              <bitOffset>17</bitOffset>
              <bitWidth>1</bitWidth>
            </field>
            <field>
              <name>GCEN</name>
              <bitOffset>19</bitOffset>
              <bitWidth>1</bitWidth>
            </field>
            <field>
              <name>SMBHEN</name>
              <bitOffset>20</bitOffset>
              <bitWidth>1</bitWidth>
            </field>
            <field>
              <name>SMBDEN</name>
              <bitOffset>21</bitOffset>
              <bitWidth>1</bitWidth>
            </field>
            <field>
              <name>ALERTEN</name>
              <bitOffset>22</bitOffset>
              <bitWidth>1</bitWidth>
            </field>
            <field>
              <name>PECEN</name>
              <bitOffset>23</bitOffset>
              <bitWidth>1</bitWidth>
            </field>
          </fields>
        </register>
        <register>
          <name>CR2</name>
          <addressOffset>0x4</addressOffset>
          <size>0x20</size>
          <fields>
            <field>
              <name>SADD</name>
              <bitOffset>0</bitOffset>
              <bitWidth>10</bitWidth>
            </field>
            <field>
              <name>RD_WRN</name>
              <bitOffset>10</bitOffset>
              <bitWidth>1</bitWidth>
            </field>
            <field>
              <name>ADD10</name>
              <bitOffset>11</bitOffset>
              <bitWidth>1</bitWidth>
            </field>
            <field>
              <name>HEAD10R</name>
              <bitOffset>12</bitOffset>
              <bitWidth>1</bitWidth>
            </field>
            <field>
              <name>START</name>
              <bitOffset>13</bitOffset>
              <bitWidth>1</bitWidth>
            </field>
            <field>
              <name>STOP</name>
              <bitOffset>14</bitOffset>
              <bitWidth>1</bitWidth>
            </field>
            <field>
              <name>NACK</name>
              <bitOffset>15</bitOffset>
              <bitWidth>1</bitWidth>
            </field>
            <field>
              <name>NBYTES</name>
              <bitOffset>16</bitOffset>
              <bitWidth>8</bitWidth>
            </field>
            <field>
              <name>RELOAD</name>
              <bitOffset>24</bitOffset>
              <bitWidth>1</bitWidth>
            </field>
            <field>
              <name>AUTOEND</name>
              <bitOffset>25</bitOffset>
              <bitWidth>1</bitWidth>
            </field>
            <field>
              <name>PECBYTE</name>
              <bitOffset>26</bitOffset>
              <bitWidth>1</bitWidth>
            </field>
          </fields>
        </register>
        <register>
          <name>OAR1</name>
          <addressOffset>0x8</addressOffset>
          <size>0x20</size>
          <fields>
            <field>
              <name>OA1</name>
              <bitOffset>0</bitOffset>
              <bitWidth>10</bitWidth>
            </field>
            <field>
              <name>OA1MODE</name>
              <bitOffset>10</bitOffset>
              <bitWidth>1</bitWidth>
            </field>
            <field>
              <name>OA1EN</name>
              <bitOffset>15</bitOffset>
              <bitWidth>1</bitWidth>
            </field>
          </fields>
        </register>
        <register>
          <name>OAR2</name>
          <addressOffset>0xc</addressOffset>
          <size>0x20</size>
          <fields>
            <field>
              <name>OA2</name>
              <bitOffset>1</bitOffset>
              <bitWidth>7</bitWidth>
            </field>
            <field>
              <name>OA2MSK</name>
              <bitOffset>8</bitOffset>
              <bitWidth>3</bitWidth>
            </field>
            <field>
              <name>OA2MASK06</name>
              <bitOffset>9</bitOffset>
              <bitWidth>2</bitWidth>
            </field>
            <field>
              <name>OA2MASK04</name>
              <bitOffset>10</bitOffset>
              <bitWidth>1</bitWidth>
            </field>
            <field>
              <name>OA2EN</name>
              <bitOffset>15</bitOffset>
              <bitWidth>1</bitWidth>
            </field>
          </fields>
        </register>
        <register>
          <name>TIMINGR</name>
          <addressOffset>0x10</addressOffset>
          <size>0x20</size>
          <fields>
            <field>
              <name>SCLL</name>
              <bitOffset>0</bitOffset>
              <bitWidth>8</bitWidth>
            </field>
            <field>
              <name>SCLH</name>
              <bitOffset>8</bitOffset>
              <bitWidth>8</bitWidth>
            </field>
            <field>
              <name>SDADEL</name>
              <bitOffset>16</bitOffset>
              <bitWidth>4</bitWidth>
            </field>
            <field>
              <name>SCLDEL</name>
              <bitOffset>20</bitOffset>
              <bitWidth>4</bitWidth>
            </field>
            <field>
              <name>PRESC</name>
              <bitOffset>28</bitOffset>
              <bitWidth>4</bitWidth>
            </field>
          </fields>
        </register>
        <register>
          <name>TIMEOUTR</name>
          <addressOffset>0x14</addressOffset>
          <size>0x20</size>
          <fields>
            <field>
              <name>TIMEOUTA</name>
              <bitOffset>0</bitOffset>
              <bitWidth>12</bitWidth>
            </field>
            <field>
              <name>TIDLE</name>
              <bitOffset>12</bitOffset>
              <bitWidth>1</bitWidth>
            </field>
            <field>
              <name>TIMOUTEN</name>
              <bitOffset>15</bitOffset>
              <bitWidth>1</bitWidth>
            </field>
            <field>
              <name>TIMEOUTB</name>
              <bitOffset>16</bitOffset>
              <bitWidth>12</bitWidth>
            </field>
            <field>
              <name>TEXTEN</name>
              <bitOffset>31</bitOffset>
              <bitWidth>1</bitWidth>
            </field>
          </fields>
        </register>
        <register>
          <name>ISR</name>
          <addressOffset>0x18</addressOffset>
          <size>0x20</size>
          <fields>
            <field>
              <name>TXE</name>
              <bitOffset>0</bitOffset>
              <bitWidth>1</bitWidth>
            </field>
            <field>
              <name>TXIS</name>
              <bitOffset>1</bitOffset>
              <bitWidth>1</bitWidth>
            </field>
            <field>
              <name>RXNE</name>
              <bitOffset>2</bitOffset>
              <bitWidth>1</bitWidth>
            </field>
            <field>
              <name>ADDR</name>
              <bitOffset>3</bitOffset>
              <bitWidth>1</bitWidth>
            </field>
            <field>
              <name>NACKF</name>
              <bitOffset>4</bitOffset>
              <bitWidth>1</bitWidth>
            </field>
            <field>
              <name>STOPF</name>
              <bitOffset>5</bitOffset>
              <bitWidth>1</bitWidth>
            </field>
            <field>
              <name>TC</name>
              <bitOffset>6</bitOffset>
              <bitWidth>1</bitWidth>
            </field>
            <field>
              <name>TCR</name>
              <bitOffset>7</bitOffset>
              <bitWidth>1</bitWidth>
            </field>
            <field>
              <name>BERR</name>
              <bitOffset>8</bitOffset>
              <bitWidth>1</bitWidth>
            </field>
            <field>
              <name>ARLO</name>
              <bitOffset>9</bitOffset>
              <bitWidth>1</bitWidth>
            </field>
            <field>
              <name>OVR</name>
              <bitOffset>10</bitOffset>
              <bitWidth>1</bitWidth>
            </field>
            <field>
              <name>PECERR</name>
              <bitOffset>11</bitOffset>
              <bitWidth>1</bitWidth>
            </field>
            <field>
              <name>TIMEOUT</name>
              <bitOffset>12</bitOffset>
              <bitWidth>1</bitWidth>
            </field>
            <field>
              <name>ALERT</name>
              <bitOffset>13</bitOffset>
              <bitWidth>1</bitWidth>
            </field>
            <field>
              <name>BUSY</name>
              <bitOffset>15</bitOffset>
              <bitWidth>1</bitWidth>
            </field>
            <field>
              <name>DIR</name>
              <bitOffset>16</bitOffset>
              <bitWidth>1</bitWidth>
            </field>
            <field>
              <name>ADDCODE</name>
              <bitOffset>17</bitOffset>
              <bitWidth>7</bitWidth>
            </field>
          </fields>
        </register>
        <register>
          <name>ICR</name>
          <addressOffset>0x1c</addressOffset>
          <size>0x20</size>
          <fields>
            <field>
              <name>ADDRCF</name>
              <bitOffset>3</bitOffset>
              <bitWidth>1</bitWidth>
            </field>
            <field>
              <name>NACKCF</name>
              <bitOffset>4</bitOffset>
              <bitWidth>1</bitWidth>
            </field>
            <field>
              <name>STOPCF</name>
              <bitOffset>5</bitOffset>
              <bitWidth>1</bitWidth>
            </field>
            <field>
              <name>BERRCF</name>
              <bitOffset>8</bitOffset>
              <bitWidth>1</bitWidth>
            </field>
            <field>
              <name>ARLOCF</name>
              <bitOffset>9</bitOffset>
              <bitWidth>1</bitWidth>
            </field>
            <field>
              <name>OVRCF</name>
              <bitOffset>10</bitOffset>
              <bitWidth>1</bitWidth>
            </field>
            <field>
              <name>PECCF</name>
              <bitOffset>11</bitOffset>
              <bitWidth>1</bitWidth>
            </field>
            <field>
              <name>TIMOUTCF</name>
              <bitOffset>12</bitOffset>
              <bitWidth>1</bitWidth>
            </field>
            <field>
              <name>ALERTCF</name>
              <bitOffset>13</bitOffset>
              <bitWidth>1</bitWidth>
            </field>
          </fields>
        </register>
        <register>
          <name>PECR</name>
          <addressOffset>0x20</addressOffset>
          <size>0x20</size>
          <fields>
            <field>
              <name>PEC</name>
              <bitOffset>0</bitOffset>
              <bitWidth>8</bitWidth>
            </field>
          </fields>
        </register>
        <register>
          <name>RXDR</name>
          <addressOffset>0x24</addressOffset>
          <size>0x20</size>
          <fields>
            <field>
              <name>RXDATA</name>
              <bitOffset>0</bitOffset>
              <bitWidth>8</bitWidth>
            </field>
          </fields>
        </register>
        <register>
          <name>TXDR</name>
          <addressOffset>0x28</addressOffset>
          <size>0x20</size>
          <fields>
            <field>
              <name>TXDATA</name>
              <bitOffset>0</bitOffset>
              <bitWidth>8</bitWidth>
            </field>
          </fields>
        </register>
      </registers>
    </peripheral>
    <peripheral>
      <name>I2C2</name>
      <baseAddress>0x40005800</baseAddress>
      <registers>
        <register>
          <name>CR1</name>
          <addressOffset>0x0</addressOffset>
          <size>0x20</size>
          <fields>
            <field>
              <name>PE</name>
              <bitOffset>0</bitOffset>
              <bitWidth>1</bitWidth>
            </field>
            <field>
              <name>TXIE</name>
              <bitOffset>1</bitOffset>
              <bitWidth>1</bitWidth>
            </field>
            <field>
              <name>RXIE</name>
              <bitOffset>2</bitOffset>
              <bitWidth>1</bitWidth>
            </field>
            <field>
              <name>ADDRIE</name>
              <bitOffset>3</bitOffset>
              <bitWidth>1</bitWidth>
            </field>
            <field>
              <name>NACKIE</name>
              <bitOffset>4</bitOffset>
              <bitWidth>1</bitWidth>
            </field>
            <field>
              <name>STOPIE</name>
              <bitOffset>5</bitOffset>
              <bitWidth>1</bitWidth>
            </field>
            <field>
              <name>TCIE</name>
              <bitOffset>6</bitOffset>
              <bitWidth>1</bitWidth>
            </field>
            <field>
              <name>ERRIE</name>
              <bitOffset>7</bitOffset>
              <bitWidth>1</bitWidth>
            </field>
            <field>
              <name>DNF</name>
              <bitOffset>8</bitOffset>
              <bitWidth>4</bitWidth>
            </field>
            <field>
              <name>ANFOFF</name>
              <bitOffset>12</bitOffset>
              <bitWidth>1</bitWidth>
            </field>
            <field>
              <name>TXDMAEN</name>
              <bitOffset>14</bitOffset>
              <bitWidth>1</bitWidth>
            </field>
            <field>
              <name>RXDMAEN</name>
              <bitOffset>15</bitOffset>
              <bitWidth>1</bitWidth>
            </field>
            <field>
              <name>SBC</name>
              <bitOffset>16</bitOffset>
              <bitWidth>1</bitWidth>
            </field>
            <field>
              <name>NOSTRETCH</name>
              <bitOffset>17</bitOffset>
              <bitWidth>1</bitWidth>
            </field>
            <field>
              <name>GCEN</name>
              <bitOffset>19</bitOffset>
              <bitWidth>1</bitWidth>
            </field>
            <field>
              <name>SMBHEN</name>
              <bitOffset>20</bitOffset>
              <bitWidth>1</bitWidth>
            </field>
            <field>
              <name>SMBDEN</name>
              <bitOffset>21</bitOffset>
              <bitWidth>1</bitWidth>
            </field>
            <field>
              <name>ALERTEN</name>
              <bitOffset>22</bitOffset>
              <bitWidth>1</bitWidth>
            </field>
            <field>
              <name>PECEN</name>
              <bitOffset>23</bitOffset>
              <bitWidth>1</bitWidth>
            </field>
          </fields>
        </register>
        <register>
          <name>CR2</name>
          <addressOffset>0x4</addressOffset>
          <size>0x20</size>
          <fields>
            <field>
              <name>SADD</name>
              <bitOffset>0</bitOffset>
              <bitWidth>10</bitWidth>
            </field>
            <field>
              <name>RD_WRN</name>
              <bitOffset>10</bitOffset>
              <bitWidth>1</bitWidth>
            </field>
            <field>
              <name>ADD10</name>
              <bitOffset>11</bitOffset>
              <bitWidth>1</bitWidth>
            </field>
            <field>
              <name>HEAD10R</name>
              <bitOffset>12</bitOffset>
              <bitWidth>1</bitWidth>
            </field>
            <field>
              <name>START</name>
              <bitOffset>13</bitOffset>
              <bitWidth>1</bitWidth>
            </field>
            <field>
              <name>STOP</name>
              <bitOffset>14</bitOffset>
              <bitWidth>1</bitWidth>
            </field>
            <field>
              <name>NACK</name>
              <bitOffset>15</bitOffset>
              <bitWidth>1</bitWidth>
            </field>
            <field>
              <name>NBYTES</name>
              <bitOffset>16</bitOffset>
              <bitWidth>8</bitWidth>
            </field>
            <field>
              <name>RELOAD</name>
              <bitOffset>24</bitOffset>
              <bitWidth>1</bitWidth>
            </field>
            <field>
              <name>AUTOEND</name>
              <bitOffset>25</bitOffset>
              <bitWidth>1</bitWidth>
            </field>
            <field>
              <name>PECBYTE</name>
              <bitOffset>26</bitOffset>
              <bitWidth>1</bitWidth>
            </field>
          </fields>
        </register>
        <register>
          <name>OAR1</name>
          <addressOffset>0x8</addressOffset>
          <size>0x20</size>
          <fields>
            <field>
              <name>OA1</name>
              <bitOffset>0</bitOffset>
              <bitWidth>10</bitWidth>
            </field>
            <field>
              <name>OA1MODE</name>
              <bitOffset>10</bitOffset>
              <bitWidth>1</bitWidth>
            </field>
            <field>
              <name>OA1EN</name>
              <bitOffset>15</bitOffset>
              <bitWidth>1</bitWidth>
            </field>
          </fields>
        </register>
        <register>
          <name>OAR2</name>
          <addressOffset>0xc</addressOffset>
          <size>0x20</size>
          <fields>
            <field>
              <name>OA2</name>
              <bitOffset>1</bitOffset>
              <bitWidth>7</bitWidth>
            </field>
            <field>
              <name>OA2MSK</name>
              <bitOffset>8</bitOffset>
              <bitWidth>3</bitWidth>
            </field>
            <field>
              <name>OA2MASK06</name>
              <bitOffset>9</bitOffset>
              <bitWidth>2</bitWidth>
            </field>
            <field>
              <name>OA2MASK04</name>
              <bitOffset>10</bitOffset>
              <bitWidth>1</bitWidth>
            </field>
            <field>
              <name>OA2EN</name>
              <bitOffset>15</bitOffset>
              <bitWidth>1</bitWidth>
            </field>
          </fields>
        </register>
        <register>
          <name>TIMINGR</name>
          <addressOffset>0x10</addressOffset>
          <size>0x20</size>
          <fields>
            <field>
              <name>SCLL</name>
              <bitOffset>0</bitOffset>
              <bitWidth>8</bitWidth>
            </field>
            <field>
              <name>SCLH</name>
              <bitOffset>8</bitOffset>
              <bitWidth>8</bitWidth>
            </field>
            <field>
              <name>SDADEL</name>
              <bitOffset>16</bitOffset>
              <bitWidth>4</bitWidth>
            </field>
            <field>
              <name>SCLDEL</name>
              <bitOffset>20</bitOffset>
              <bitWidth>4</bitWidth>
            </field>
            <field>
              <name>PRESC</name>
              <bitOffset>28</bitOffset>
              <bitWidth>4</bitWidth>
            </field>
          </fields>
        </register>
        <register>
          <name>TIMEOUTR</name>
          <addressOffset>0x14</addressOffset>
          <size>0x20</size>
          <fields>
            <field>
              <name>TIMEOUTA</name>
              <bitOffset>0</bitOffset>
              <bitWidth>12</bitWidth>
            </field>
            <field>
              <name>TIDLE</name>
              <bitOffset>12</bitOffset>
              <bitWidth>1</bitWidth>
            </field>
            <field>
              <name>TIMOUTEN</name>
              <bitOffset>15</bitOffset>
              <bitWidth>1</bitWidth>
            </field>
            <field>
              <name>TIMEOUTB</name>
              <bitOffset>16</bitOffset>
              <bitWidth>12</bitWidth>
            </field>
            <field>
              <name>TEXTEN</name>
              <bitOffset>31</bitOffset>
              <bitWidth>1</bitWidth>
            </field>
          </fields>
        </register>
        <register>
          <name>ISR</name>
          <addressOffset>0x18</addressOffset>
          <size>0x20</size>
          <fields>
            <field>
              <name>TXE</name>
              <bitOffset>0</bitOffset>
              <bitWidth>1</bitWidth>
            </field>
            <field>
              <name>TXIS</name>
              <bitOffset>1</bitOffset>
              <bitWidth>1</bitWidth>
            </field>
            <field>
              <name>RXNE</name>
              <bitOffset>2</bitOffset>
              <bitWidth>1</bitWidth>
            </field>
            <field>
              <name>ADDR</name>
              <bitOffset>3</bitOffset>
              <bitWidth>1</bitWidth>
            </field>
            <field>
              <name>NACKF</name>
              <bitOffset>4</bitOffset>
              <bitWidth>1</bitWidth>
            </field>
            <field>
              <name>STOPF</name>
              <bitOffset>5</bitOffset>
              <bitWidth>1</bitWidth>
            </field>
            <field>
              <name>TC</name>
              <bitOffset>6</bitOffset>
              <bitWidth>1</bitWidth>
            </field>
            <field>
              <name>TCR</name>
              <bitOffset>7</bitOffset>
              <bitWidth>1</bitWidth>
            </field>
            <field>
              <name>BERR</name>
              <bitOffset>8</bitOffset>
              <bitWidth>1</bitWidth>
            </field>
            <field>
              <name>ARLO</name>
              <bitOffset>9</bitOffset>
              <bitWidth>1</bitWidth>
            </field>
            <field>
              <name>OVR</name>
              <bitOffset>10</bitOffset>
              <bitWidth>1</bitWidth>
            </field>
            <field>
              <name>PECERR</name>
              <bitOffset>11</bitOffset>
              <bitWidth>1</bitWidth>
            </field>
            <field>
              <name>TIMEOUT</name>
              <bitOffset>12</bitOffset>
              <bitWidth>1</bitWidth>
            </field>
            <field>
              <name>ALERT</name>
              <bitOffset>13</bitOffset>
              <bitWidth>1</bitWidth>
            </field>
            <field>
              <name>BUSY</name>
              <bitOffset>15</bitOffset>
              <bitWidth>1</bitWidth>
            </field>
            <field>
              <name>DIR</name>
              <bitOffset>16</bitOffset>
              <bitWidth>1</bitWidth>
            </field>
            <field>
              <name>ADDCODE</name>
              <bitOffset>17</bitOffset>
              <bitWidth>7</bitWidth>
            </field>
          </fields>
        </register>
        <register>
          <name>ICR</name>
          <addressOffset>0x1c</addressOffset>
          <size>0x20</size>
          <fields>
            <field>
              <name>ADDRCF</name>
              <bitOffset>3</bitOffset>
              <bitWidth>1</bitWidth>
            </field>
            <field>
              <name>NACKCF</name>
              <bitOffset>4</bitOffset>
              <bitWidth>1</bitWidth>
            </field>
            <field>
              <name>STOPCF</name>
              <bitOffset>5</bitOffset>
              <bitWidth>1</bitWidth>
            </field>
            <field>
              <name>BERRCF</name>
              <bitOffset>8</bitOffset>
              <bitWidth>1</bitWidth>
            </field>
            <field>
              <name>ARLOCF</name>
              <bitOffset>9</bitOffset>
              <bitWidth>1</bitWidth>
            </field>
            <field>
              <name>OVRCF</name>
              <bitOffset>10</bitOffset>
              <bitWidth>1</bitWidth>
            </field>
            <field>
              <name>PECCF</name>
              <bitOffset>11</bitOffset>
              <bitWidth>1</bitWidth>
            </field>
            <field>
              <name>TIMOUTCF</name>
              <bitOffset>12</bitOffset>
              <bitWidth>1</bitWidth>
            </field>
            <field>
              <name>ALERTCF</name>
              <bitOffset>13</bitOffset>
              <bitWidth>1</bitWidth>
            </field>
          </fields>
        </register>
        <register>
          <name>PECR</name>
          <addressOffset>0x20</addressOffset>
          <size>0x20</size>
          <fields>
            <field>
              <name>PEC</name>
              <bitOffset>0</bitOffset>
              <bitWidth>8</bitWidth>
            </field>
          </fields>
        </register>
        <register>
          <name>RXDR</name>
          <addressOffset>0x24</addressOffset>
          <size>0x20</size>
          <fields>
            <field>
              <name>RXDATA</name>
              <bitOffset>0</bitOffset>
              <bitWidth>8</bitWidth>
            </field>
          </fields>
        </register>
        <register>
          <name>TXDR</name>
          <addressOffset>0x28</addressOffset>
          <size>0x20</size>
          <fields>
            <field>
              <name>TXDATA</name>
              <bitOffset>0</bitOffset>
              <bitWidth>8</bitWidth>
            </field>
          </fields>
        </register>
      </registers>
    </peripheral>
    <peripheral>
      <name>I2C3</name>
      <baseAddress>0x40005c00</baseAddress>
      <registers>
        <register>
          <name>CR1</name>
          <addressOffset>0x0</addressOffset>
          <size>0x20</size>
          <fields>
            <field>
              <name>PE</name>
              <bitOffset>0</bitOffset>
              <bitWidth>1</bitWidth>
            </field>
            <field>
              <name>TXIE</name>
              <bitOffset>1</bitOffset>
              <bitWidth>1</bitWidth>
            </field>
            <field>
              <name>RXIE</name>
              <bitOffset>2</bitOffset>
              <bitWidth>1</bitWidth>
            </field>
            <field>
              <name>ADDRIE</name>
              <bitOffset>3</bitOffset>
              <bitWidth>1</bitWidth>
            </field>
            <field>
              <name>NACKIE</name>
              <bitOffset>4</bitOffset>
              <bitWidth>1</bitWidth>
            </field>
            <field>
              <name>STOPIE</name>
              <bitOffset>5</bitOffset>
              <bitWidth>1</bitWidth>
            </field>
            <field>
              <name>TCIE</name>
              <bitOffset>6</bitOffset>
              <bitWidth>1</bitWidth>
            </field>
            <field>
              <name>ERRIE</name>
              <bitOffset>7</bitOffset>
              <bitWidth>1</bitWidth>
            </field>
            <field>
              <name>DNF</name>
              <bitOffset>8</bitOffset>
              <bitWidth>4</bitWidth>
            </field>
            <field>
              <name>ANFOFF</name>
              <bitOffset>12</bitOffset>
              <bitWidth>1</bitWidth>
            </field>
            <field>
              <name>TXDMAEN</name>
              <bitOffset>14</bitOffset>
              <bitWidth>1</bitWidth>
            </field>
            <field>
              <name>RXDMAEN</name>
              <bitOffset>15</bitOffset>
              <bitWidth>1</bitWidth>
            </field>
            <field>
              <name>SBC</name>
              <bitOffset>16</bitOffset>
              <bitWidth>1</bitWidth>
            </field>
            <field>
              <name>NOSTRETCH</name>
              <bitOffset>17</bitOffset>
              <bitWidth>1</bitWidth>
            </field>
            <field>
              <name>GCEN</name>
              <bitOffset>19</bitOffset>
              <bitWidth>1</bitWidth>
            </field>
            <field>
              <name>SMBHEN</name>
              <bitOffset>20</bitOffset>
              <bitWidth>1</bitWidth>
            </field>
            <field>
              <name>SMBDEN</name>
              <bitOffset>21</bitOffset>
              <bitWidth>1</bitWidth>
            </field>
            <field>
              <name>ALERTEN</name>
              <bitOffset>22</bitOffset>
              <bitWidth>1</bitWidth>
            </field>
            <field>
              <name>PECEN</name>
              <bitOffset>23</bitOffset>
              <bitWidth>1</bitWidth>
            </field>
          </fields>
        </register>
        <register>
          <name>CR2</name>
          <addressOffset>0x4</addressOffset>
          <size>0x20</size>
          <fields>
            <field>
              <name>SADD</name>
              <bitOffset>0</bitOffset>
              <bitWidth>10</bitWidth>
            </field>
            <field>
              <name>RD_WRN</name>
              <bitOffset>10</bitOffset>
              <bitWidth>1</bitWidth>
            </field>
            <field>
              <name>ADD10</name>
              <bitOffset>11</bitOffset>
              <bitWidth>1</bitWidth>
            </field>
            <field>
              <name>HEAD10R</name>
              <bitOffset>12</bitOffset>
              <bitWidth>1</bitWidth>
            </field>
            <field>
              <name>START</name>
              <bitOffset>13</bitOffset>
              <bitWidth>1</bitWidth>
            </field>
            <field>
              <name>STOP</name>
              <bitOffset>14</bitOffset>
              <bitWidth>1</bitWidth>
            </field>
            <field>
              <name>NACK</name>
              <bitOffset>15</bitOffset>
              <bitWidth>1</bitWidth>
            </field>
            <field>
              <name>NBYTES</name>
              <bitOffset>16</bitOffset>
              <bitWidth>8</bitWidth>
            </field>
            <field>
              <name>RELOAD</name>
              <bitOffset>24</bitOffset>
              <bitWidth>1</bitWidth>
            </field>
            <field>
              <name>AUTOEND</name>
              <bitOffset>25</bitOffset>
              <bitWidth>1</bitWidth>
            </field>
            <field>
              <name>PECBYTE</name>
              <bitOffset>26</bitOffset>
              <bitWidth>1</bitWidth>
            </field>
          </fields>
        </register>
        <register>
          <name>OAR1</name>
          <addressOffset>0x8</addressOffset>
          <size>0x20</size>
          <fields>
            <field>
              <name>OA1</name>
              <bitOffset>0</bitOffset>
              <bitWidth>10</bitWidth>
            </field>
            <field>
              <name>OA1MODE</name>
              <bitOffset>10</bitOffset>
              <bitWidth>1</bitWidth>
            </field>
            <field>
              <name>OA1EN</name>
              <bitOffset>15</bitOffset>
              <bitWidth>1</bitWidth>
            </field>
          </fields>
        </register>
        <register>
          <name>OAR2</name>
          <addressOffset>0xc</addressOffset>
          <size>0x20</size>
          <fields>
            <field>
              <name>OA2</name>
              <bitOffset>1</bitOffset>
              <bitWidth>7</bitWidth>
            </field>
            <field>
              <name>OA2MSK</name>
              <bitOffset>8</bitOffset>
              <bitWidth>3</bitWidth>
            </field>
            <field>
              <name>OA2MASK06</name>
              <bitOffset>9</bitOffset>
              <bitWidth>2</bitWidth>
            </field>
            <field>
              <name>OA2MASK04</name>
              <bitOffset>10</bitOffset>
              <bitWidth>1</bitWidth>
            </field>
            <field>
              <name>OA2EN</name>
              <bitOffset>15</bitOffset>
              <bitWidth>1</bitWidth>
            </field>
          </fields>
        </register>
        <register>
          <name>TIMINGR</name>
          <addressOffset>0x10</addressOffset>
          <size>0x20</size>
          <fields>
            <field>
              <name>SCLL</name>
              <bitOffset>0</bitOffset>
              <bitWidth>8</bitWidth>
            </field>
            <field>
              <name>SCLH</name>
              <bitOffset>8</bitOffset>
              <bitWidth>8</bitWidth>
            </field>
            <field>
              <name>SDADEL</name>
              <bitOffset>16</bitOffset>
              <bitWidth>4</bitWidth>
            </field>
            <field>
              <name>SCLDEL</name>
              <bitOffset>20</bitOffset>
              <bitWidth>4</bitWidth>
            </field>
            <field>
              <name>PRESC</name>
              <bitOffset>28</bitOffset>
              <bitWidth>4</bitWidth>
            </field>
          </fields>
        </register>
        <register>
          <name>TIMEOUTR</name>
          <addressOffset>0x14</addressOffset>
          <size>0x20</size>
          <fields>
            <field>
              <name>TIMEOUTA</name>
              <bitOffset>0</bitOffset>
              <bitWidth>12</bitWidth>
            </field>
            <field>
              <name>TIDLE</name>
              <bitOffset>12</bitOffset>
              <bitWidth>1</bitWidth>
            </field>
            <field>
              <name>TIMOUTEN</name>
              <bitOffset>15</bitOffset>
              <bitWidth>1</bitWidth>
            </field>
            <field>
              <name>TIMEOUTB</name>
              <bitOffset>16</bitOffset>
              <bitWidth>12</bitWidth>
            </field>
            <field>
              <name>TEXTEN</name>
              <bitOffset>31</bitOffset>
              <bitWidth>1</bitWidth>
            </field>
          </fields>
        </register>
        <register>
          <name>ISR</name>
          <addressOffset>0x18</addressOffset>
          <size>0x20</size>
          <fields>
            <field>
              <name>TXE</name>
              <bitOffset>0</bitOffset>
              <bitWidth>1</bitWidth>
            </field>
            <field>
              <name>TXIS</name>
              <bitOffset>1</bitOffset>
              <bitWidth>1</bitWidth>
            </field>
            <field>
              <name>RXNE</name>
              <bitOffset>2</bitOffset>
              <bitWidth>1</bitWidth>
            </field>
            <field>
              <name>ADDR</name>
              <bitOffset>3</bitOffset>
              <bitWidth>1</bitWidth>
            </field>
            <field>
              <name>NACKF</name>
              <bitOffset>4</bitOffset>
              <bitWidth>1</bitWidth>
            </field>
            <field>
              <name>STOPF</name>
              <bitOffset>5</bitOffset>
              <bitWidth>1</bitWidth>
            </field>
            <field>
              <name>TC</name>
              <bitOffset>6</bitOffset>
              <bitWidth>1</bitWidth>
            </field>
            <field>
              <name>TCR</name>
              <bitOffset>7</bitOffset>
              <bitWidth>1</bitWidth>
            </field>
            <field>
              <name>BERR</name>
              <bitOffset>8</bitOffset>
              <bitWidth>1</bitWidth>
            </field>
            <field>
              <name>ARLO</name>
              <bitOffset>9</bitOffset>
              <bitWidth>1</bitWidth>
            </field>
            <field>
              <name>OVR</name>
              <bitOffset>10</bitOffset>
              <bitWidth>1</bitWidth>
            </field>
            <field>
              <name>PECERR</name>
              <bitOffset>11</bitOffset>
              <bitWidth>1</bitWidth>
            </field>
            <field>
              <name>TIMEOUT</name>
              <bitOffset>12</bitOffset>
              <bitWidth>1</bitWidth>
            </field>
            <field>
              <name>ALERT</name>
              <bitOffset>13</bitOffset>
              <bitWidth>1</bitWidth>
            </field>
            <field>
              <name>BUSY</name>
              <bitOffset>15</bitOffset>
              <bitWidth>1</bitWidth>
            </field>
            <field>
              <name>DIR</name>
              <bitOffset>16</bitOffset>
              <bitWidth>1</bitWidth>
            </field>
            <field>
              <name>ADDCODE</name>
              <bitOffset>17</bitOffset>
              <bitWidth>7</bitWidth>
            </field>
          </fields>
        </register>
        <register>
          <name>ICR</name>
          <addressOffset>0x1c</addressOffset>
          <size>0x20</size>
          <fields>
            <field>
              <name>ADDRCF</name>
              <bitOffset>3</bitOffset>
              <bitWidth>1</bitWidth>
            </field>
            <field>
              <name>NACKCF</name>
              <bitOffset>4</bitOffset>
              <bitWidth>1</bitWidth>
            </field>
            <field>
              <name>STOPCF</name>
              <bitOffset>5</bitOffset>
              <bitWidth>1</bitWidth>
            </field>
            <field>
              <name>BERRCF</name>
              <bitOffset>8</bitOffset>
              <bitWidth>1</bitWidth>
            </field>
            <field>
              <name>ARLOCF</name>
              <bitOffset>9</bitOffset>
              <bitWidth>1</bitWidth>
            </field>
            <field>
              <name>OVRCF</name>
              <bitOffset>10</bitOffset>
              <bitWidth>1</bitWidth>
            </field>
            <field>
              <name>PECCF</name>
              <bitOffset>11</bitOffset>
              <bitWidth>1</bitWidth>
            </field>
            <field>
              <name>TIMOUTCF</name>
              <bitOffset>12</bitOffset>
              <bitWidth>1</bitWidth>
            </field>
            <field>
              <name>ALERTCF</name>
              <bitOffset>13</bitOffset>
              <bitWidth>1</bitWidth>
            </field>
          </fields>
        </register>
        <register>
          <name>PECR</name>
          <addressOffset>0x20</addressOffset>
          <size>0x20</size>
          <fields>
            <field>
              <name>PEC</name>
              <bitOffset>0</bitOffset>
              <bitWidth>8</bitWidth>
            </field>
          </fields>
        </register>
        <register>
          <name>RXDR</name>
          <addressOffset>0x24</addressOffset>
          <size>0x20</size>
          <fields>
            <field>
              <name>RXDATA</name>
              <bitOffset>0</bitOffset>
              <bitWidth>8</bitWidth>
            </field>
          </fields>
        </register>
        <register>
          <name>TXDR</name>
          <addressOffset>0x28</addressOffset>
          <size>0x20</size>
          <fields>
            <field>
              <name>TXDATA</name>
              <bitOffset>0</bitOffset>
              <bitWidth>8</bitWidth>
            </field>
          </fields>
        </register>
      </registers>
    </peripheral>
    <peripheral>
      <name>I2C4</name>
      <baseAddress>0x40006000</baseAddress>
      <registers>
        <register>
          <name>CR1</name>
          <addressOffset>0x0</addressOffset>
          <size>0x20</size>
          <fields>
            <field>
              <name>PE</name>
              <bitOffset>0</bitOffset>
              <bitWidth>1</bitWidth>
            </field>
            <field>
              <name>TXIE</name>
              <bitOffset>1</bitOffset>
              <bitWidth>1</bitWidth>
            </field>
            <field>
              <name>RXIE</name>
              <bitOffset>2</bitOffset>
              <bitWidth>1</bitWidth>
            </field>
            <field>
              <name>ADDRIE</name>
              <bitOffset>3</bitOffset>
              <bitWidth>1</bitWidth>
            </field>
            <field>
              <name>NACKIE</name>
              <bitOffset>4</bitOffset>
              <bitWidth>1</bitWidth>
            </field>
            <field>
              <name>STOPIE</name>
              <bitOffset>5</bitOffset>
              <bitWidth>1</bitWidth>
            </field>
            <field>
              <name>TCIE</name>
              <bitOffset>6</bitOffset>
              <bitWidth>1</bitWidth>
            </field>
            <field>
              <name>ERRIE</name>
              <bitOffset>7</bitOffset>
              <bitWidth>1</bitWidth>
            </field>
            <field>
              <name>DNF</name>
              <bitOffset>8</bitOffset>
              <bitWidth>4</bitWidth>
            </field>
            <field>
              <name>ANFOFF</name>
              <bitOffset>12</bitOffset>
              <bitWidth>1</bitWidth>
            </field>
            <field>
              <name>TXDMAEN</name>
              <bitOffset>14</bitOffset>
              <bitWidth>1</bitWidth>
            </field>
            <field>
              <name>RXDMAEN</name>
              <bitOffset>15</bitOffset>
              <bitWidth>1</bitWidth>
            </field>
            <field>
              <name>SBC</name>
              <bitOffset>16</bitOffset>
              <bitWidth>1</bitWidth>
            </field>
            <field>
              <name>NOSTRETCH</name>
              <bitOffset>17</bitOffset>
              <bitWidth>1</bitWidth>
            </field>
            <field>
              <name>GCEN</name>
              <bitOffset>19</bitOffset>
              <bitWidth>1</bitWidth>
            </field>
            <field>
              <name>SMBHEN</name>
              <bitOffset>20</bitOffset>
              <bitWidth>1</bitWidth>
            </field>
            <field>
              <name>SMBDEN</name>
              <bitOffset>21</bitOffset>
              <bitWidth>1</bitWidth>
            </field>
            <field>
              <name>ALERTEN</name>
              <bitOffset>22</bitOffset>
              <bitWidth>1</bitWidth>
            </field>
            <field>
              <name>PECEN</name>
              <bitOffset>23</bitOffset>
              <bitWidth>1</bitWidth>
            </field>
          </fields>
        </register>
        <register>
          <name>CR2</name>
          <addressOffset>0x4</addressOffset>
          <size>0x20</size>
          <fields>
            <field>
              <name>SADD</name>
              <bitOffset>0</bitOffset>
              <bitWidth>10</bitWidth>
            </field>
            <field>
              <name>RD_WRN</name>
              <bitOffset>10</bitOffset>
              <bitWidth>1</bitWidth>
            </field>
            <field>
              <name>ADD10</name>
              <bitOffset>11</bitOffset>
              <bitWidth>1</bitWidth>
            </field>
            <field>
              <name>HEAD10R</name>
              <bitOffset>12</bitOffset>
              <bitWidth>1</bitWidth>
            </field>
            <field>
              <name>START</name>
              <bitOffset>13</bitOffset>
              <bitWidth>1</bitWidth>
            </field>
            <field>
              <name>STOP</name>
              <bitOffset>14</bitOffset>
              <bitWidth>1</bitWidth>
            </field>
            <field>
              <name>NACK</name>
              <bitOffset>15</bitOffset>
              <bitWidth>1</bitWidth>
            </field>
            <field>
              <name>NBYTES</name>
              <bitOffset>16</bitOffset>
              <bitWidth>8</bitWidth>
            </field>
            <field>
              <name>RELOAD</name>
              <bitOffset>24</bitOffset>
              <bitWidth>1</bitWidth>
            </field>
            <field>
              <name>AUTOEND</name>
              <bitOffset>25</bitOffset>
              <bitWidth>1</bitWidth>
            </field>
            <field>
              <name>PECBYTE</name>
              <bitOffset>26</bitOffset>
              <bitWidth>1</bitWidth>
            </field>
          </fields>
        </register>
        <register>
          <name>OAR1</name>
          <addressOffset>0x8</addressOffset>
          <size>0x20</size>
          <fields>
            <field>
              <name>OA1</name>
              <bitOffset>0</bitOffset>
              <bitWidth>10</bitWidth>
            </field>
            <field>
              <name>OA1MODE</name>
              <bitOffset>10</bitOffset>
              <bitWidth>1</bitWidth>
            </field>
            <field>
              <name>OA1EN</name>
              <bitOffset>15</bitOffset>
              <bitWidth>1</bitWidth>
            </field>
          </fields>
        </register>
        <register>
          <name>OAR2</name>
          <addressOffset>0xc</addressOffset>
          <size>0x20</size>
          <fields>
            <field>
              <name>OA2</name>
              <bitOffset>1</bitOffset>
              <bitWidth>7</bitWidth>
            </field>
            <field>
              <name>OA2MSK</name>
              <bitOffset>8</bitOffset>
              <bitWidth>3</bitWidth>
            </field>
            <field>
              <name>OA2MASK06</name>
              <bitOffset>9</bitOffset>
              <bitWidth>2</bitWidth>
            </field>
            <field>
              <name>OA2MASK04</name>
              <bitOffset>10</bitOffset>
              <bitWidth>1</bitWidth>
            </field>
            <field>
              <name>OA2EN</name>
              <bitOffset>15</bitOffset>
              <bitWidth>1</bitWidth>
            </field>
          </fields>
        </register>
        <register>
          <name>TIMINGR</name>
          <addressOffset>0x10</addressOffset>
          <size>0x20</size>
          <fields>
            <field>
              <name>SCLL</name>
              <bitOffset>0</bitOffset>
              <bitWidth>8</bitWidth>
            </field>
            <field>
              <name>SCLH</name>
              <bitOffset>8</bitOffset>
              <bitWidth>8</bitWidth>
            </field>
            <field>
              <name>SDADEL</name>
              <bitOffset>16</bitOffset>
              <bitWidth>4</bitWidth>
            </field>
            <field>
              <name>SCLDEL</name>
              <bitOffset>20</bitOffset>
              <bitWidth>4</bitWidth>
            </field>
            <field>
              <name>PRESC</name>
              <bitOffset>28</bitOffset>
              <bitWidth>4</bitWidth>
            </field>
          </fields>
        </register>
        <register>
          <name>TIMEOUTR</name>
          <addressOffset>0x14</addressOffset>
          <size>0x20</size>
          <fields>
            <field>
              <name>TIMEOUTA</name>
              <bitOffset>0</bitOffset>
              <bitWidth>12</bitWidth>
            </field>
            <field>
              <name>TIDLE</name>
              <bitOffset>12</bitOffset>
              <bitWidth>1</bitWidth>
            </field>
            <field>
              <name>TIMOUTEN</name>
              <bitOffset>15</bitOffset>
              <bitWidth>1</bitWidth>
            </field>
            <field>
              <name>TIMEOUTB</name>
              <bitOffset>16</bitOffset>
              <bitWidth>12</bitWidth>
            </field>
            <field>
              <name>TEXTEN</name>
              <bitOffset>31</bitOffset>
              <bitWidth>1</bitWidth>
            </field>
          </fields>
        </register>
        <register>
          <name>ISR</name>
          <addressOffset>0x18</addressOffset>
          <size>0x20</size>
          <fields>
            <field>
              <name>TXE</name>
              <bitOffset>0</bitOffset>
              <bitWidth>1</bitWidth>
            </field>
            <field>
              <name>TXIS</name>
              <bitOffset>1</bitOffset>
              <bitWidth>1</bitWidth>
            </field>
            <field>
              <name>RXNE</name>
              <bitOffset>2</bitOffset>
              <bitWidth>1</bitWidth>
            </field>
            <field>
              <name>ADDR</name>
              <bitOffset>3</bitOffset>
              <bitWidth>1</bitWidth>
            </field>
            <field>
              <name>NACKF</name>
              <bitOffset>4</bitOffset>
              <bitWidth>1</bitWidth>
            </field>
            <field>
              <name>STOPF</name>
              <bitOffset>5</bitOffset>
              <bitWidth>1</bitWidth>
            </field>
            <field>
              <name>TC</name>
              <bitOffset>6</bitOffset>
              <bitWidth>1</bitWidth>
            </field>
            <field>
              <name>TCR</name>
              <bitOffset>7</bitOffset>
              <bitWidth>1</bitWidth>
            </field>
            <field>
              <name>BERR</name>
              <bitOffset>8</bitOffset>
              <bitWidth>1</bitWidth>
            </field>
            <field>
              <name>ARLO</name>
              <bitOffset>9</bitOffset>
              <bitWidth>1</bitWidth>
            </field>
            <field>
              <name>OVR</name>
              <bitOffset>10</bitOffset>
              <bitWidth>1</bitWidth>
            </field>
            <field>
              <name>PECERR</name>
              <bitOffset>11</bitOffset>
              <bitWidth>1</bitWidth>
            </field>
            <field>
              <name>TIMEOUT</name>
              <bitOffset>12</bitOffset>
              <bitWidth>1</bitWidth>
            </field>
            <field>
              <name>ALERT</name>
              <bitOffset>13</bitOffset>
              <bitWidth>1</bitWidth>
            </field>
            <field>
              <name>BUSY</name>
              <bitOffset>15</bitOffset>
              <bitWidth>1</bitWidth>
            </field>
            <field>
              <name>DIR</name>
              <bitOffset>16</bitOffset>
              <bitWidth>1</bitWidth>
            </field>
            <field>
              <name>ADDCODE</name>
              <bitOffset>17</bitOffset>
              <bitWidth>7</bitWidth>
            </field>
          </fields>
        </register>
        <register>
          <name>ICR</name>
          <addressOffset>0x1c</addressOffset>
          <size>0x20</size>
          <fields>
            <field>
              <name>ADDRCF</name>
              <bitOffset>3</bitOffset>
              <bitWidth>1</bitWidth>
            </field>
            <field>
              <name>NACKCF</name>
              <bitOffset>4</bitOffset>
              <bitWidth>1</bitWidth>
            </field>
            <field>
              <name>STOPCF</name>
              <bitOffset>5</bitOffset>
              <bitWidth>1</bitWidth>
            </field>
            <field>
              <name>BERRCF</name>
              <bitOffset>8</bitOffset>
              <bitWidth>1</bitWidth>
            </field>
            <field>
              <name>ARLOCF</name>
              <bitOffset>9</bitOffset>
              <bitWidth>1</bitWidth>
            </field>
            <field>
              <name>OVRCF</name>
              <bitOffset>10</bitOffset>
              <bitWidth>1</bitWidth>
            </field>
            <field>
              <name>PECCF</name>
              <bitOffset>11</bitOffset>
              <bitWidth>1</bitWidth>
            </field>
            <field>
              <name>TIMOUTCF</name>
              <bitOffset>12</bitOffset>
              <bitWidth>1</bitWidth>
            </field>
            <field>
              <name>ALERTCF</name>
              <bitOffset>13</bitOffset>
              <bitWidth>1</bitWidth>
            </field>
          </fields>
        </register>
        <register>
          <name>PECR</name>
          <addressOffset>0x20</addressOffset>
          <size>0x20</size>
          <fields>
            <field>
              <name>PEC</name>
              <bitOffset>0</bitOffset>
              <bitWidth>8</bitWidth>
            </field>
          </fields>
        </register>
        <register>
          <name>RXDR</name>
          <addressOffset>0x24</addressOffset>
          <size>0x20</size>
          <fields>
            <field>
              <name>RXDATA</name>
              <bitOffset>0</bitOffset>
              <bitWidth>8</bitWidth>
            </field>
          </fields>
        </register>
        <register>
          <name>TXDR</name>
          <addressOffset>0x28</addressOffset>
          <size>0x20</size>
          <fields>
            <field>
              <name>TXDATA</name>
              <bitOffset>0</bitOffset>
              <bitWidth>8</bitWidth>
            </field>
          </fields>
        </register>
      </registers>
    </peripheral>
    <peripheral>
      <name>CAN1</name>
      <baseAddress>0x40006400</baseAddress>
      <registers>
        <register>
          <name>MCR</name>
          <addressOffset>0x0</addressOffset>
          <size>0x20</size>
          <fields>
            <field>
              <name>INRQ</name>
              <bitOffset>0</bitOffset>
              <bitWidth>1</bitWidth>
            </field>
            <field>
              <name>SLEEP</name>
              <bitOffset>1</bitOffset>
              <bitWidth>1</bitWidth>
            </field>
            <field>
              <name>TXFP</name>
              <bitOffset>2</bitOffset>
              <bitWidth>1</bitWidth>
            </field>
            <field>
              <name>RFLM</name>
              <bitOffset>3</bitOffset>
              <bitWidth>1</bitWidth>
            </field>
            <field>
              <name>NART</name>
              <bitOffset>4</bitOffset>
              <bitWidth>1</bitWidth>
            </field>
            <field>
              <name>AWUM</name>
              <bitOffset>5</bitOffset>
              <bitWidth>1</bitWidth>
            </field>
            <field>
              <name>ABOM</name>
              <bitOffset>6</bitOffset>
              <bitWidth>1</bitWidth>
            </field>
            <field>
              <name>TTCM</name>
              <bitOffset>7</bitOffset>
              <bitWidth>1</bitWidth>
            </field>
            <field>
              <name>RESET</name>
              <bitOffset>15</bitOffset>
              <bitWidth>1</bitWidth>
            </field>
          </fields>
        </register>
        <register>
          <name>MSR</name>
          <addressOffset>0x4</addressOffset>
          <size>0x20</size>
          <fields>
            <field>
              <name>INAK</name>
              <bitOffset>0</bitOffset>
              <bitWidth>1</bitWidth>
            </field>
            <field>
              <name>SLAK</name>
              <bitOffset>1</bitOffset>
              <bitWidth>1</bitWidth>
            </field>
            <field>
              <name>ERRI</name>
              <bitOffset>2</bitOffset>
              <bitWidth>1</bitWidth>
            </field>
            <field>
              <name>WKUI</name>
              <bitOffset>3</bitOffset>
              <bitWidth>1</bitWidth>
            </field>
            <field>
              <name>SLAKI</name>
              <bitOffset>4</bitOffset>
              <bitWidth>1</bitWidth>
            </field>
            <field>
              <name>TXM</name>
              <bitOffset>8</bitOffset>
              <bitWidth>1</bitWidth>
            </field>
            <field>
              <name>RXM</name>
              <bitOffset>9</bitOffset>
              <bitWidth>1</bitWidth>
            </field>
            <field>
              <name>SAMP</name>
              <bitOffset>10</bitOffset>
              <bitWidth>1</bitWidth>
            </field>
            <field>
              <name>RX</name>
              <bitOffset>11</bitOffset>
              <bitWidth>1</bitWidth>
            </field>
          </fields>
        </register>
        <register>
          <name>TSR</name>
          <addressOffset>0x8</addressOffset>
          <size>0x20</size>
          <fields>
            <field>
              <name>RQCP0</name>
              <bitOffset>0</bitOffset>
              <bitWidth>1</bitWidth>
            </field>
            <field>
              <name>TXOK0</name>
              <bitOffset>1</bitOffset>
              <bitWidth>1</bitWidth>
            </field>
            <field>
              <name>ALST0</name>
              <bitOffset>2</bitOffset>
              <bitWidth>1</bitWidth>
            </field>
            <field>
              <name>TERR0</name>
              <bitOffset>3</bitOffset>
              <bitWidth>1</bitWidth>
            </field>
            <field>
              <name>ABRQ0</name>
              <bitOffset>7</bitOffset>
              <bitWidth>1</bitWidth>
            </field>
            <field>
              <name>RQCP1</name>
              <bitOffset>8</bitOffset>
              <bitWidth>1</bitWidth>
            </field>
            <field>
              <name>TXOK1</name>
              <bitOffset>9</bitOffset>
              <bitWidth>1</bitWidth>
            </field>
            <field>
              <name>ALST1</name>
              <bitOffset>10</bitOffset>
              <bitWidth>1</bitWidth>
            </field>
            <field>
              <name>TERR1</name>
              <bitOffset>11</bitOffset>
              <bitWidth>1</bitWidth>
            </field>
            <field>
              <name>ABRQ1</name>
              <bitOffset>15</bitOffset>
              <bitWidth>1</bitWidth>
            </field>
            <field>
              <name>RQCP2</name>
              <bitOffset>16</bitOffset>
              <bitWidth>1</bitWidth>
            </field>
            <field>
              <name>TXOK2</name>
              <bitOffset>17</bitOffset>
              <bitWidth>1</bitWidth>
            </field>
            <field>
              <name>ALST2</name>
              <bitOffset>18</bitOffset>
              <bitWidth>1</bitWidth>
            </field>
            <field>
              <name>TERR2</name>
              <bitOffset>19</bitOffset>
              <bitWidth>1</bitWidth>
            </field>
            <field>
              <name>ABRQ2</name>
              <bitOffset>23</bitOffset>
              <bitWidth>1</bitWidth>
            </field>
            <field>
              <name>CODE</name>
              <bitOffset>24</bitOffset>
              <bitWidth>2</bitWidth>
            </field>
            <field>
              <name>TME0</name>
              <bitOffset>26</bitOffset>
              <bitWidth>1</bitWidth>
            </field>
            <field>
              <name>TME1</name>
              <bitOffset>27</bitOffset>
              <bitWidth>1</bitWidth>
            </field>
            <field>
              <name>TME2</name>
              <bitOffset>28</bitOffset>
              <bitWidth>1</bitWidth>
            </field>
            <field>
              <name>LOW0</name>
              <bitOffset>29</bitOffset>
              <bitWidth>1</bitWidth>
            </field>
            <field>
              <name>LOW1</name>
              <bitOffset>30</bitOffset>
              <bitWidth>1</bitWidth>
            </field>
            <field>
              <name>LOW2</name>
              <bitOffset>31</bitOffset>
              <bitWidth>1</bitWidth>
            </field>
          </fields>
        </register>
        <register>
          <name>RF0R</name>
          <addressOffset>0xc</addressOffset>
          <size>0x20</size>
          <fields>
            <field>
              <name>FMP0</name>
              <bitOffset>0</bitOffset>
              <bitWidth>2</bitWidth>
            </field>
            <field>
              <name>FULL0</name>
              <bitOffset>3</bitOffset>
              <bitWidth>1</bitWidth>
            </field>
            <field>
              <name>FOVR0</name>
              <bitOffset>4</bitOffset>
              <bitWidth>1</bitWidth>
            </field>
            <field>
              <name>RFOM0</name>
              <bitOffset>5</bitOffset>
              <bitWidth>1</bitWidth>
            </field>
          </fields>
        </register>
        <register>
          <name>RF1R</name>
          <addressOffset>0x10</addressOffset>
          <size>0x20</size>
          <fields>
            <field>
              <name>FMP1</name>
              <bitOffset>0</bitOffset>
              <bitWidth>2</bitWidth>
            </field>
            <field>
              <name>FULL1</name>
              <bitOffset>3</bitOffset>
              <bitWidth>1</bitWidth>
            </field>
            <field>
              <name>FOVR1</name>
              <bitOffset>4</bitOffset>
              <bitWidth>1</bitWidth>
            </field>
            <field>
              <name>RFOM1</name>
              <bitOffset>5</bitOffset>
              <bitWidth>1</bitWidth>
            </field>
          </fields>
        </register>
        <register>
          <name>IER</name>
          <addressOffset>0x14</addressOffset>
          <size>0x20</size>
          <fields>
            <field>
              <name>TMEIE</name>
              <bitOffset>0</bitOffset>
              <bitWidth>1</bitWidth>
            </field>
            <field>
              <name>FMPIE0</name>
              <bitOffset>1</bitOffset>
              <bitWidth>1</bitWidth>
            </field>
            <field>
              <name>FFIE0</name>
              <bitOffset>2</bitOffset>
              <bitWidth>1</bitWidth>
            </field>
            <field>
              <name>FOVIE0</name>
              <bitOffset>3</bitOffset>
              <bitWidth>1</bitWidth>
            </field>
            <field>
              <name>FMPIE1</name>
              <bitOffset>4</bitOffset>
              <bitWidth>1</bitWidth>
            </field>
            <field>
              <name>FFIE1</name>
              <bitOffset>5</bitOffset>
              <bitWidth>1</bitWidth>
            </field>
            <field>
              <name>FOVIE1</name>
              <bitOffset>6</bitOffset>
              <bitWidth>1</bitWidth>
            </field>
            <field>
              <name>EWGIE</name>
              <bitOffset>8</bitOffset>
              <bitWidth>1</bitWidth>
            </field>
            <field>
              <name>EPVIE</name>
              <bitOffset>9</bitOffset>
              <bitWidth>1</bitWidth>
            </field>
            <field>
              <name>BOFIE</name>
              <bitOffset>10</bitOffset>
              <bitWidth>1</bitWidth>
            </field>
            <field>
              <name>LECIE</name>
              <bitOffset>11</bitOffset>
              <bitWidth>1</bitWidth>
            </field>
            <field>
              <name>ERRIE</name>
              <bitOffset>15</bitOffset>
              <bitWidth>1</bitWidth>
            </field>
            <field>
              <name>WKUIE</name>
              <bitOffset>16</bitOffset>
              <bitWidth>1</bitWidth>
            </field>
            <field>
              <name>SLKIE</name>
              <bitOffset>17</bitOffset>
              <bitWidth>1</bitWidth>
            </field>
          </fields>
        </register>
        <register>
          <name>ESR</name>
          <addressOffset>0x18</addressOffset>
          <size>0x20</size>
          <fields>
            <field>
              <name>EWGF</name>
              <bitOffset>0</bitOffset>
              <bitWidth>1</bitWidth>
            </field>
            <field>
              <name>EPVF</name>
              <bitOffset>1</bitOffset>
              <bitWidth>1</bitWidth>
            </field>
            <field>
              <name>BOFF</name>
              <bitOffset>2</bitOffset>
              <bitWidth>1</bitWidth>
            </field>
            <field>
              <name>LEC</name>
              <bitOffset>4</bitOffset>
              <bitWidth>3</bitWidth>
            </field>
            <field>
              <name>TEC</name>
              <bitOffset>16</bitOffset>
              <bitWidth>8</bitWidth>
            </field>
            <field>
              <name>REC</name>
              <bitOffset>24</bitOffset>
              <bitWidth>8</bitWidth>
            </field>
          </fields>
        </register>
        <register>
          <name>BTR</name>
          <addressOffset>0x1c</addressOffset>
          <size>0x20</size>
          <fields>
            <field>
              <name>BRP</name>
              <bitOffset>0</bitOffset>
              <bitWidth>10</bitWidth>
            </field>
            <field>
              <name>TS1</name>
              <bitOffset>16</bitOffset>
              <bitWidth>4</bitWidth>
            </field>
            <field>
              <name>TS2</name>
              <bitOffset>20</bitOffset>
              <bitWidth>3</bitWidth>
            </field>
            <field>
              <name>SJW</name>
              <bitOffset>24</bitOffset>
              <bitWidth>2</bitWidth>
            </field>
            <field>
              <name>LBKM</name>
              <bitOffset>30</bitOffset>
              <bitWidth>1</bitWidth>
            </field>
            <field>
              <name>SILM</name>
              <bitOffset>31</bitOffset>
              <bitWidth>1</bitWidth>
            </field>
          </fields>
        </register>
        <register>
          <name>sTxMailBox.0.TIR</name>
          <addressOffset>0x180</addressOffset>
          <size>0x20</size>
          <fields>
            <field>
              <name>TXRQ</name>
              <bitOffset>0</bitOffset>
              <bitWidth>1</bitWidth>
            </field>
            <field>
              <name>RTR</name>
              <bitOffset>1</bitOffset>
              <bitWidth>1</bitWidth>
            </field>
            <field>
              <name>IDE</name>
              <bitOffset>2</bitOffset>
              <bitWidth>1</bitWidth>
            </field>
            <field>
              <name>EXID</name>
              <bitOffset>3</bitOffset>
              <bitWidth>18</bitWidth>
            </field>
            <field>
              <name>STID</name>
              <bitOffset>21</bitOffset>
              <bitWidth>11</bitWidth>
            </field>
          </fields>
        </register>
        <register>
          <name>sTxMailBox.0.TDTR</name>
          <addressOffset>0x184</addressOffset>
          <size>0x20</size>
          <fields>
            <field>
              <name>DLC</name>
              <bitOffset>0</bitOffset>
              <bitWidth>4</bitWidth>
            </field>
            <field>
              <name>TGT</name>
              <bitOffset>8</bitOffset>
              <bitWidth>1</bitWidth>
            </field>
            <field>
              <name>TIME</name>
              <bitOffset>16</bitOffset>
              <bitWidth>16</bitWidth>
            </field>
          </fields>
        </register>
        <register>
          <name>sTxMailBox.0.TDLR</name>
          <addressOffset>0x188</addressOffset>
          <size>0x20</size>
          <fields>
            <field>
              <name>DATA0</name>
              <bitOffset>0</bitOffset>
              <bitWidth>8</bitWidth>
            </field>
            <field>
              <name>DATA1</name>
              <bitOffset>8</bitOffset>
              <bitWidth>8</bitWidth>
            </field>
            <field>
              <name>DATA2</name>
              <bitOffset>16</bitOffset>
              <bitWidth>8</bitWidth>
            </field>
            <field>
              <name>DATA3</name>
              <bitOffset>24</bitOffset>
              <bitWidth>8</bitWidth>
            </field>
          </fields>
        </register>
        <register>
          <name>sTxMailBox.0.TDHR</name>
          <addressOffset>0x18c</addressOffset>
          <size>0x20</size>
          <fields>
            <field>
              <name>DATA4</name>
              <bitOffset>0</bitOffset>
              <bitWidth>8</bitWidth>
            </field>
            <field>
              <name>DATA5</name>
              <bitOffset>8</bitOffset>
              <bitWidth>8</bitWidth>
            </field>
            <field>
              <name>DATA6</name>
              <bitOffset>16</bitOffset>
              <bitWidth>8</bitWidth>
            </field>
            <field>
              <name>DATA7</name>
              <bitOffset>24</bitOffset>
              <bitWidth>8</bitWidth>
            </field>
          </fields>
        </register>
        <register>
          <name>sTxMailBox.1.TIR</name>
          <addressOffset>0x190</addressOffset>
          <size>0x20</size>
          <fields>
            <field>
              <name>TXRQ</name>
              <bitOffset>0</bitOffset>
              <bitWidth>1</bitWidth>
            </field>
            <field>
              <name>RTR</name>
              <bitOffset>1</bitOffset>
              <bitWidth>1</bitWidth>
            </field>
            <field>
              <name>IDE</name>
              <bitOffset>2</bitOffset>
              <bitWidth>1</bitWidth>
            </field>
            <field>
              <name>EXID</name>
              <bitOffset>3</bitOffset>
              <bitWidth>18</bitWidth>
            </field>
            <field>
              <name>STID</name>
              <bitOffset>21</bitOffset>
              <bitWidth>11</bitWidth>
            </field>
          </fields>
        </register>
        <register>
          <name>sTxMailBox.1.TDTR</name>
          <addressOffset>0x194</addressOffset>
          <size>0x20</size>
          <fields>
            <field>
              <name>DLC</name>
              <bitOffset>0</bitOffset>
              <bitWidth>4</bitWidth>
            </field>
            <field>
              <name>TGT</name>
              <bitOffset>8</bitOffset>
              <bitWidth>1</bitWidth>
            </field>
            <field>
              <name>TIME</name>
              <bitOffset>16</bitOffset>
              <bitWidth>16</bitWidth>
            </field>
          </fields>
        </register>
        <register>
          <name>sTxMailBox.1.TDLR</name>
          <addressOffset>0x198</addressOffset>
          <size>0x20</size>
          <fields>
            <field>
              <name>DATA0</name>
              <bitOffset>0</bitOffset>
              <bitWidth>8</bitWidth>
            </field>
            <field>
              <name>DATA1</name>
              <bitOffset>8</bitOffset>
              <bitWidth>8</bitWidth>
            </field>
            <field>
              <name>DATA2</name>
              <bitOffset>16</bitOffset>
              <bitWidth>8</bitWidth>
            </field>
            <field>
              <name>DATA3</name>
              <bitOffset>24</bitOffset>
              <bitWidth>8</bitWidth>
            </field>
          </fields>
        </register>
        <register>
          <name>sTxMailBox.1.TDHR</name>
          <addressOffset>0x19c</addressOffset>
          <size>0x20</size>
          <fields>
            <field>
              <name>DATA4</name>
              <bitOffset>0</bitOffset>
              <bitWidth>8</bitWidth>
            </field>
            <field>
              <name>DATA5</name>
              <bitOffset>8</bitOffset>
              <bitWidth>8</bitWidth>
            </field>
            <field>
              <name>DATA6</name>
              <bitOffset>16</bitOffset>
              <bitWidth>8</bitWidth>
            </field>
            <field>
              <name>DATA7</name>
              <bitOffset>24</bitOffset>
              <bitWidth>8</bitWidth>
            </field>
          </fields>
        </register>
        <register>
          <name>sTxMailBox.2.TIR</name>
          <addressOffset>0x1a0</addressOffset>
          <size>0x20</size>
          <fields>
            <field>
              <name>TXRQ</name>
              <bitOffset>0</bitOffset>
              <bitWidth>1</bitWidth>
            </field>
            <field>
              <name>RTR</name>
              <bitOffset>1</bitOffset>
              <bitWidth>1</bitWidth>
            </field>
            <field>
              <name>IDE</name>
              <bitOffset>2</bitOffset>
              <bitWidth>1</bitWidth>
            </field>
            <field>
              <name>EXID</name>
              <bitOffset>3</bitOffset>
              <bitWidth>18</bitWidth>
            </field>
            <field>
              <name>STID</name>
              <bitOffset>21</bitOffset>
              <bitWidth>11</bitWidth>
            </field>
          </fields>
        </register>
        <register>
          <name>sTxMailBox.2.TDTR</name>
          <addressOffset>0x1a4</addressOffset>
          <size>0x20</size>
          <fields>
            <field>
              <name>DLC</name>
              <bitOffset>0</bitOffset>
              <bitWidth>4</bitWidth>
            </field>
            <field>
              <name>TGT</name>
              <bitOffset>8</bitOffset>
              <bitWidth>1</bitWidth>
            </field>
            <field>
              <name>TIME</name>
              <bitOffset>16</bitOffset>
              <bitWidth>16</bitWidth>
            </field>
          </fields>
        </register>
        <register>
          <name>sTxMailBox.2.TDLR</name>
          <addressOffset>0x1a8</addressOffset>
          <size>0x20</size>
          <fields>
            <field>
              <name>DATA0</name>
              <bitOffset>0</bitOffset>
              <bitWidth>8</bitWidth>
            </field>
            <field>
              <name>DATA1</name>
              <bitOffset>8</bitOffset>
              <bitWidth>8</bitWidth>
            </field>
            <field>
              <name>DATA2</name>
              <bitOffset>16</bitOffset>
              <bitWidth>8</bitWidth>
            </field>
            <field>
              <name>DATA3</name>
              <bitOffset>24</bitOffset>
              <bitWidth>8</bitWidth>
            </field>
          </fields>
        </register>
        <register>
          <name>sTxMailBox.2.TDHR</name>
          <addressOffset>0x1ac</addressOffset>
          <size>0x20</size>
          <fields>
            <field>
              <name>DATA4</name>
              <bitOffset>0</bitOffset>
              <bitWidth>8</bitWidth>
            </field>
            <field>
              <name>DATA5</name>
              <bitOffset>8</bitOffset>
              <bitWidth>8</bitWidth>
            </field>
            <field>
              <name>DATA6</name>
              <bitOffset>16</bitOffset>
              <bitWidth>8</bitWidth>
            </field>
            <field>
              <name>DATA7</name>
              <bitOffset>24</bitOffset>
              <bitWidth>8</bitWidth>
            </field>
          </fields>
        </register>
        <register>
          <name>sFIFOMailBox.0.RIR</name>
          <addressOffset>0x1b0</addressOffset>
          <size>0x20</size>
          <fields>
            <field>
              <name>RTR</name>
              <bitOffset>1</bitOffset>
              <bitWidth>1</bitWidth>
            </field>
            <field>
              <name>IDE</name>
              <bitOffset>2</bitOffset>
              <bitWidth>1</bitWidth>
            </field>
            <field>
              <name>EXID</name>
              <bitOffset>3</bitOffset>
              <bitWidth>18</bitWidth>
            </field>
            <field>
              <name>STID</name>
              <bitOffset>21</bitOffset>
              <bitWidth>11</bitWidth>
            </field>
          </fields>
        </register>
        <register>
          <name>sFIFOMailBox.0.RDTR</name>
          <addressOffset>0x1b4</addressOffset>
          <size>0x20</size>
          <fields>
            <field>
              <name>DLC</name>
              <bitOffset>0</bitOffset>
              <bitWidth>4</bitWidth>
            </field>
            <field>
              <name>FMI</name>
              <bitOffset>8</bitOffset>
              <bitWidth>8</bitWidth>
            </field>
            <field>
              <name>TIME</name>
              <bitOffset>16</bitOffset>
              <bitWidth>16</bitWidth>
            </field>
          </fields>
        </register>
        <register>
          <name>sFIFOMailBox.0.RDLR</name>
          <addressOffset>0x1b8</addressOffset>
          <size>0x20</size>
          <fields>
            <field>
              <name>DATA0</name>
              <bitOffset>0</bitOffset>
              <bitWidth>8</bitWidth>
            </field>
            <field>
              <name>DATA1</name>
              <bitOffset>8</bitOffset>
              <bitWidth>8</bitWidth>
            </field>
            <field>
              <name>DATA2</name>
              <bitOffset>16</bitOffset>
              <bitWidth>8</bitWidth>
            </field>
            <field>
              <name>DATA3</name>
              <bitOffset>24</bitOffset>
              <bitWidth>8</bitWidth>
            </field>
          </fields>
        </register>
        <register>
          <name>sFIFOMailBox.0.RDHR</name>
          <addressOffset>0x1bc</addressOffset>
          <size>0x20</size>
          <fields>
            <field>
              <name>DATA4</name>
              <bitOffset>0</bitOffset>
              <bitWidth>8</bitWidth>
            </field>
            <field>
              <name>DATA5</name>
              <bitOffset>8</bitOffset>
              <bitWidth>8</bitWidth>
            </field>
            <field>
              <name>DATA6</name>
              <bitOffset>16</bitOffset>
              <bitWidth>8</bitWidth>
            </field>
            <field>
              <name>DATA7</name>
              <bitOffset>24</bitOffset>
              <bitWidth>8</bitWidth>
            </field>
          </fields>
        </register>
        <register>
          <name>sFIFOMailBox.1.RIR</name>
          <addressOffset>0x1c0</addressOffset>
          <size>0x20</size>
          <fields>
            <field>
              <name>RTR</name>
              <bitOffset>1</bitOffset>
              <bitWidth>1</bitWidth>
            </field>
            <field>
              <name>IDE</name>
              <bitOffset>2</bitOffset>
              <bitWidth>1</bitWidth>
            </field>
            <field>
              <name>EXID</name>
              <bitOffset>3</bitOffset>
              <bitWidth>18</bitWidth>
            </field>
            <field>
              <name>STID</name>
              <bitOffset>21</bitOffset>
              <bitWidth>11</bitWidth>
            </field>
          </fields>
        </register>
        <register>
          <name>sFIFOMailBox.1.RDTR</name>
          <addressOffset>0x1c4</addressOffset>
          <size>0x20</size>
          <fields>
            <field>
              <name>DLC</name>
              <bitOffset>0</bitOffset>
              <bitWidth>4</bitWidth>
            </field>
            <field>
              <name>FMI</name>
              <bitOffset>8</bitOffset>
              <bitWidth>8</bitWidth>
            </field>
            <field>
              <name>TIME</name>
              <bitOffset>16</bitOffset>
              <bitWidth>16</bitWidth>
            </field>
          </fields>
        </register>
        <register>
          <name>sFIFOMailBox.1.RDLR</name>
          <addressOffset>0x1c8</addressOffset>
          <size>0x20</size>
          <fields>
            <field>
              <name>DATA0</name>
              <bitOffset>0</bitOffset>
              <bitWidth>8</bitWidth>
            </field>
            <field>
              <name>DATA1</name>
              <bitOffset>8</bitOffset>
              <bitWidth>8</bitWidth>
            </field>
            <field>
              <name>DATA2</name>
              <bitOffset>16</bitOffset>
              <bitWidth>8</bitWidth>
            </field>
            <field>
              <name>DATA3</name>
              <bitOffset>24</bitOffset>
              <bitWidth>8</bitWidth>
            </field>
          </fields>
        </register>
        <register>
          <name>sFIFOMailBox.1.RDHR</name>
          <addressOffset>0x1cc</addressOffset>
          <size>0x20</size>
          <fields>
            <field>
              <name>DATA4</name>
              <bitOffset>0</bitOffset>
              <bitWidth>8</bitWidth>
            </field>
            <field>
              <name>DATA5</name>
              <bitOffset>8</bitOffset>
              <bitWidth>8</bitWidth>
            </field>
            <field>
              <name>DATA6</name>
              <bitOffset>16</bitOffset>
              <bitWidth>8</bitWidth>
            </field>
            <field>
              <name>DATA7</name>
              <bitOffset>24</bitOffset>
              <bitWidth>8</bitWidth>
            </field>
          </fields>
        </register>
        <register>
          <name>FMR</name>
          <addressOffset>0x200</addressOffset>
          <size>0x20</size>
          <fields>
            <field>
              <name>CAN2SB</name>
              <bitOffset>8</bitOffset>
              <bitWidth>6</bitWidth>
            </field>
          </fields>
        </register>
        <register>
          <name>FM1R</name>
          <addressOffset>0x204</addressOffset>
          <size>0x20</size>
          <fields>
            <field>
              <name>FBM0</name>
              <bitOffset>0</bitOffset>
              <bitWidth>1</bitWidth>
            </field>
            <field>
              <name>FBM1</name>
              <bitOffset>1</bitOffset>
              <bitWidth>1</bitWidth>
            </field>
            <field>
              <name>FBM2</name>
              <bitOffset>2</bitOffset>
              <bitWidth>1</bitWidth>
            </field>
            <field>
              <name>FBM3</name>
              <bitOffset>3</bitOffset>
              <bitWidth>1</bitWidth>
            </field>
            <field>
              <name>FBM4</name>
              <bitOffset>4</bitOffset>
              <bitWidth>1</bitWidth>
            </field>
            <field>
              <name>FBM5</name>
              <bitOffset>5</bitOffset>
              <bitWidth>1</bitWidth>
            </field>
            <field>
              <name>FBM6</name>
              <bitOffset>6</bitOffset>
              <bitWidth>1</bitWidth>
            </field>
            <field>
              <name>FBM7</name>
              <bitOffset>7</bitOffset>
              <bitWidth>1</bitWidth>
            </field>
            <field>
              <name>FBM8</name>
              <bitOffset>8</bitOffset>
              <bitWidth>1</bitWidth>
            </field>
            <field>
              <name>FBM9</name>
              <bitOffset>9</bitOffset>
              <bitWidth>1</bitWidth>
            </field>
            <field>
              <name>FBM10</name>
              <bitOffset>10</bitOffset>
              <bitWidth>1</bitWidth>
            </field>
            <field>
              <name>FBM11</name>
              <bitOffset>11</bitOffset>
              <bitWidth>1</bitWidth>
            </field>
            <field>
              <name>FBM12</name>
              <bitOffset>12</bitOffset>
              <bitWidth>1</bitWidth>
            </field>
            <field>
              <name>FBM13</name>
              <bitOffset>13</bitOffset>
              <bitWidth>1</bitWidth>
            </field>
          </fields>
        </register>
        <register>
          <name>FS1R</name>
          <addressOffset>0x20c</addressOffset>
          <size>0x20</size>
          <fields>
            <field>
              <name>FSC0</name>
              <bitOffset>0</bitOffset>
              <bitWidth>1</bitWidth>
            </field>
            <field>
              <name>FSC1</name>
              <bitOffset>1</bitOffset>
              <bitWidth>1</bitWidth>
            </field>
            <field>
              <name>FSC2</name>
              <bitOffset>2</bitOffset>
              <bitWidth>1</bitWidth>
            </field>
            <field>
              <name>FSC3</name>
              <bitOffset>3</bitOffset>
              <bitWidth>1</bitWidth>
            </field>
            <field>
              <name>FSC4</name>
              <bitOffset>4</bitOffset>
              <bitWidth>1</bitWidth>
            </field>
            <field>
              <name>FSC5</name>
              <bitOffset>5</bitOffset>
              <bitWidth>1</bitWidth>
            </field>
            <field>
              <name>FSC6</name>
              <bitOffset>6</bitOffset>
              <bitWidth>1</bitWidth>
            </field>
            <field>
              <name>FSC7</name>
              <bitOffset>7</bitOffset>
              <bitWidth>1</bitWidth>
            </field>
            <field>
              <name>FSC8</name>
              <bitOffset>8</bitOffset>
              <bitWidth>1</bitWidth>
            </field>
            <field>
              <name>FSC9</name>
              <bitOffset>9</bitOffset>
              <bitWidth>1</bitWidth>
            </field>
            <field>
              <name>FSC10</name>
              <bitOffset>10</bitOffset>
              <bitWidth>1</bitWidth>
            </field>
            <field>
              <name>FSC11</name>
              <bitOffset>11</bitOffset>
              <bitWidth>1</bitWidth>
            </field>
            <field>
              <name>FSC12</name>
              <bitOffset>12</bitOffset>
              <bitWidth>1</bitWidth>
            </field>
            <field>
              <name>FSC13</name>
              <bitOffset>13</bitOffset>
              <bitWidth>1</bitWidth>
            </field>
          </fields>
        </register>
        <register>
          <name>FFA1R</name>
          <addressOffset>0x214</addressOffset>
          <size>0x20</size>
          <fields>
            <field>
              <name>FFA0</name>
              <bitOffset>0</bitOffset>
              <bitWidth>1</bitWidth>
            </field>
            <field>
              <name>FFA1</name>
              <bitOffset>1</bitOffset>
              <bitWidth>1</bitWidth>
            </field>
            <field>
              <name>FFA2</name>
              <bitOffset>2</bitOffset>
              <bitWidth>1</bitWidth>
            </field>
            <field>
              <name>FFA3</name>
              <bitOffset>3</bitOffset>
              <bitWidth>1</bitWidth>
            </field>
            <field>
              <name>FFA4</name>
              <bitOffset>4</bitOffset>
              <bitWidth>1</bitWidth>
            </field>
            <field>
              <name>FFA5</name>
              <bitOffset>5</bitOffset>
              <bitWidth>1</bitWidth>
            </field>
            <field>
              <name>FFA6</name>
              <bitOffset>6</bitOffset>
              <bitWidth>1</bitWidth>
            </field>
            <field>
              <name>FFA7</name>
              <bitOffset>7</bitOffset>
              <bitWidth>1</bitWidth>
            </field>
            <field>
              <name>FFA8</name>
              <bitOffset>8</bitOffset>
              <bitWidth>1</bitWidth>
            </field>
            <field>
              <name>FFA9</name>
              <bitOffset>9</bitOffset>
              <bitWidth>1</bitWidth>
            </field>
            <field>
              <name>FFA10</name>
              <bitOffset>10</bitOffset>
              <bitWidth>1</bitWidth>
            </field>
            <field>
              <name>FFA11</name>
              <bitOffset>11</bitOffset>
              <bitWidth>1</bitWidth>
            </field>
            <field>
              <name>FFA12</name>
              <bitOffset>12</bitOffset>
              <bitWidth>1</bitWidth>
            </field>
            <field>
              <name>FFA13</name>
              <bitOffset>13</bitOffset>
              <bitWidth>1</bitWidth>
            </field>
          </fields>
        </register>
        <register>
          <name>FA1R</name>
          <addressOffset>0x21c</addressOffset>
          <size>0x20</size>
          <fields>
            <field>
              <name>FACT0</name>
              <bitOffset>0</bitOffset>
              <bitWidth>1</bitWidth>
            </field>
            <field>
              <name>FACT1</name>
              <bitOffset>1</bitOffset>
              <bitWidth>1</bitWidth>
            </field>
            <field>
              <name>FACT2</name>
              <bitOffset>2</bitOffset>
              <bitWidth>1</bitWidth>
            </field>
            <field>
              <name>FACT3</name>
              <bitOffset>3</bitOffset>
              <bitWidth>1</bitWidth>
            </field>
            <field>
              <name>FACT4</name>
              <bitOffset>4</bitOffset>
              <bitWidth>1</bitWidth>
            </field>
            <field>
              <name>FACT5</name>
              <bitOffset>5</bitOffset>
              <bitWidth>1</bitWidth>
            </field>
            <field>
              <name>FACT6</name>
              <bitOffset>6</bitOffset>
              <bitWidth>1</bitWidth>
            </field>
            <field>
              <name>FACT7</name>
              <bitOffset>7</bitOffset>
              <bitWidth>1</bitWidth>
            </field>
            <field>
              <name>FACT8</name>
              <bitOffset>8</bitOffset>
              <bitWidth>1</bitWidth>
            </field>
            <field>
              <name>FACT9</name>
              <bitOffset>9</bitOffset>
              <bitWidth>1</bitWidth>
            </field>
            <field>
              <name>FACT10</name>
              <bitOffset>10</bitOffset>
              <bitWidth>1</bitWidth>
            </field>
            <field>
              <name>FACT11</name>
              <bitOffset>11</bitOffset>
              <bitWidth>1</bitWidth>
            </field>
            <field>
              <name>FACT12</name>
              <bitOffset>12</bitOffset>
              <bitWidth>1</bitWidth>
            </field>
            <field>
              <name>FACT13</name>
              <bitOffset>13</bitOffset>
              <bitWidth>1</bitWidth>
            </field>
          </fields>
        </register>
        <register>
          <name>sFilterRegister.0.FR1</name>
          <addressOffset>0x240</addressOffset>
          <size>0x20</size>
          <fields>
            <field>
              <name>FB0</name>
              <bitOffset>0</bitOffset>
              <bitWidth>1</bitWidth>
            </field>
            <field>
              <name>FB1</name>
              <bitOffset>1</bitOffset>
              <bitWidth>1</bitWidth>
            </field>
            <field>
              <name>FB2</name>
              <bitOffset>2</bitOffset>
              <bitWidth>1</bitWidth>
            </field>
            <field>
              <name>FB3</name>
              <bitOffset>3</bitOffset>
              <bitWidth>1</bitWidth>
            </field>
            <field>
              <name>FB4</name>
              <bitOffset>4</bitOffset>
              <bitWidth>1</bitWidth>
            </field>
            <field>
              <name>FB5</name>
              <bitOffset>5</bitOffset>
              <bitWidth>1</bitWidth>
            </field>
            <field>
              <name>FB6</name>
              <bitOffset>6</bitOffset>
              <bitWidth>1</bitWidth>
            </field>
            <field>
              <name>FB7</name>
              <bitOffset>7</bitOffset>
              <bitWidth>1</bitWidth>
            </field>
            <field>
              <name>FB8</name>
              <bitOffset>8</bitOffset>
              <bitWidth>1</bitWidth>
            </field>
            <field>
              <name>FB9</name>
              <bitOffset>9</bitOffset>
              <bitWidth>1</bitWidth>
            </field>
            <field>
              <name>FB10</name>
              <bitOffset>10</bitOffset>
              <bitWidth>1</bitWidth>
            </field>
            <field>
              <name>FB11</name>
              <bitOffset>11</bitOffset>
              <bitWidth>1</bitWidth>
            </field>
            <field>
              <name>FB12</name>
              <bitOffset>12</bitOffset>
              <bitWidth>1</bitWidth>
            </field>
            <field>
              <name>FB13</name>
              <bitOffset>13</bitOffset>
              <bitWidth>1</bitWidth>
            </field>
            <field>
              <name>FB14</name>
              <bitOffset>14</bitOffset>
              <bitWidth>1</bitWidth>
            </field>
            <field>
              <name>FB15</name>
              <bitOffset>15</bitOffset>
              <bitWidth>1</bitWidth>
            </field>
            <field>
              <name>FB16</name>
              <bitOffset>16</bitOffset>
              <bitWidth>1</bitWidth>
            </field>
            <field>
              <name>FB17</name>
              <bitOffset>17</bitOffset>
              <bitWidth>1</bitWidth>
            </field>
            <field>
              <name>FB18</name>
              <bitOffset>18</bitOffset>
              <bitWidth>1</bitWidth>
            </field>
            <field>
              <name>FB19</name>
              <bitOffset>19</bitOffset>
              <bitWidth>1</bitWidth>
            </field>
            <field>
              <name>FB20</name>
              <bitOffset>20</bitOffset>
              <bitWidth>1</bitWidth>
            </field>
            <field>
              <name>FB21</name>
              <bitOffset>21</bitOffset>
              <bitWidth>1</bitWidth>
            </field>
            <field>
              <name>FB22</name>
              <bitOffset>22</bitOffset>
              <bitWidth>1</bitWidth>
            </field>
            <field>
              <name>FB23</name>
              <bitOffset>23</bitOffset>
              <bitWidth>1</bitWidth>
            </field>
            <field>
              <name>FB24</name>
              <bitOffset>24</bitOffset>
              <bitWidth>1</bitWidth>
            </field>
            <field>
              <name>FB25</name>
              <bitOffset>25</bitOffset>
              <bitWidth>1</bitWidth>
            </field>
            <field>
              <name>FB26</name>
              <bitOffset>26</bitOffset>
              <bitWidth>1</bitWidth>
            </field>
            <field>
              <name>FB27</name>
              <bitOffset>27</bitOffset>
              <bitWidth>1</bitWidth>
            </field>
            <field>
              <name>FB28</name>
              <bitOffset>28</bitOffset>
              <bitWidth>1</bitWidth>
            </field>
            <field>
              <name>FB29</name>
              <bitOffset>29</bitOffset>
              <bitWidth>1</bitWidth>
            </field>
            <field>
              <name>FB30</name>
              <bitOffset>30</bitOffset>
              <bitWidth>1</bitWidth>
            </field>
            <field>
              <name>FB31</name>
              <bitOffset>31</bitOffset>
              <bitWidth>1</bitWidth>
            </field>
          </fields>
        </register>
        <register>
          <name>sFilterRegister.0.FR2</name>
          <addressOffset>0x244</addressOffset>
          <size>0x20</size>
          <fields>
            <field>
              <name>FB0</name>
              <bitOffset>0</bitOffset>
              <bitWidth>1</bitWidth>
            </field>
            <field>
              <name>FB1</name>
              <bitOffset>1</bitOffset>
              <bitWidth>1</bitWidth>
            </field>
            <field>
              <name>FB2</name>
              <bitOffset>2</bitOffset>
              <bitWidth>1</bitWidth>
            </field>
            <field>
              <name>FB3</name>
              <bitOffset>3</bitOffset>
              <bitWidth>1</bitWidth>
            </field>
            <field>
              <name>FB4</name>
              <bitOffset>4</bitOffset>
              <bitWidth>1</bitWidth>
            </field>
            <field>
              <name>FB5</name>
              <bitOffset>5</bitOffset>
              <bitWidth>1</bitWidth>
            </field>
            <field>
              <name>FB6</name>
              <bitOffset>6</bitOffset>
              <bitWidth>1</bitWidth>
            </field>
            <field>
              <name>FB7</name>
              <bitOffset>7</bitOffset>
              <bitWidth>1</bitWidth>
            </field>
            <field>
              <name>FB8</name>
              <bitOffset>8</bitOffset>
              <bitWidth>1</bitWidth>
            </field>
            <field>
              <name>FB9</name>
              <bitOffset>9</bitOffset>
              <bitWidth>1</bitWidth>
            </field>
            <field>
              <name>FB10</name>
              <bitOffset>10</bitOffset>
              <bitWidth>1</bitWidth>
            </field>
            <field>
              <name>FB11</name>
              <bitOffset>11</bitOffset>
              <bitWidth>1</bitWidth>
            </field>
            <field>
              <name>FB12</name>
              <bitOffset>12</bitOffset>
              <bitWidth>1</bitWidth>
            </field>
            <field>
              <name>FB13</name>
              <bitOffset>13</bitOffset>
              <bitWidth>1</bitWidth>
            </field>
            <field>
              <name>FB14</name>
              <bitOffset>14</bitOffset>
              <bitWidth>1</bitWidth>
            </field>
            <field>
              <name>FB15</name>
              <bitOffset>15</bitOffset>
              <bitWidth>1</bitWidth>
            </field>
            <field>
              <name>FB16</name>
              <bitOffset>16</bitOffset>
              <bitWidth>1</bitWidth>
            </field>
            <field>
              <name>FB17</name>
              <bitOffset>17</bitOffset>
              <bitWidth>1</bitWidth>
            </field>
            <field>
              <name>FB18</name>
              <bitOffset>18</bitOffset>
              <bitWidth>1</bitWidth>
            </field>
            <field>
              <name>FB19</name>
              <bitOffset>19</bitOffset>
              <bitWidth>1</bitWidth>
            </field>
            <field>
              <name>FB20</name>
              <bitOffset>20</bitOffset>
              <bitWidth>1</bitWidth>
            </field>
            <field>
              <name>FB21</name>
              <bitOffset>21</bitOffset>
              <bitWidth>1</bitWidth>
            </field>
            <field>
              <name>FB22</name>
              <bitOffset>22</bitOffset>
              <bitWidth>1</bitWidth>
            </field>
            <field>
              <name>FB23</name>
              <bitOffset>23</bitOffset>
              <bitWidth>1</bitWidth>
            </field>
            <field>
              <name>FB24</name>
              <bitOffset>24</bitOffset>
              <bitWidth>1</bitWidth>
            </field>
            <field>
              <name>FB25</name>
              <bitOffset>25</bitOffset>
              <bitWidth>1</bitWidth>
            </field>
            <field>
              <name>FB26</name>
              <bitOffset>26</bitOffset>
              <bitWidth>1</bitWidth>
            </field>
            <field>
              <name>FB27</name>
              <bitOffset>27</bitOffset>
              <bitWidth>1</bitWidth>
            </field>
            <field>
              <name>FB28</name>
              <bitOffset>28</bitOffset>
              <bitWidth>1</bitWidth>
            </field>
            <field>
              <name>FB29</name>
              <bitOffset>29</bitOffset>
              <bitWidth>1</bitWidth>
            </field>
            <field>
              <name>FB30</name>
              <bitOffset>30</bitOffset>
              <bitWidth>1</bitWidth>
            </field>
            <field>
              <name>FB31</name>
              <bitOffset>31</bitOffset>
              <bitWidth>1</bitWidth>
            </field>
          </fields>
        </register>
        <register>
          <name>sFilterRegister.1.FR1</name>
          <addressOffset>0x248</addressOffset>
          <size>0x20</size>
          <fields>
            <field>
              <name>FB0</name>
              <bitOffset>0</bitOffset>
              <bitWidth>1</bitWidth>
            </field>
            <field>
              <name>FB1</name>
              <bitOffset>1</bitOffset>
              <bitWidth>1</bitWidth>
            </field>
            <field>
              <name>FB2</name>
              <bitOffset>2</bitOffset>
              <bitWidth>1</bitWidth>
            </field>
            <field>
              <name>FB3</name>
              <bitOffset>3</bitOffset>
              <bitWidth>1</bitWidth>
            </field>
            <field>
              <name>FB4</name>
              <bitOffset>4</bitOffset>
              <bitWidth>1</bitWidth>
            </field>
            <field>
              <name>FB5</name>
              <bitOffset>5</bitOffset>
              <bitWidth>1</bitWidth>
            </field>
            <field>
              <name>FB6</name>
              <bitOffset>6</bitOffset>
              <bitWidth>1</bitWidth>
            </field>
            <field>
              <name>FB7</name>
              <bitOffset>7</bitOffset>
              <bitWidth>1</bitWidth>
            </field>
            <field>
              <name>FB8</name>
              <bitOffset>8</bitOffset>
              <bitWidth>1</bitWidth>
            </field>
            <field>
              <name>FB9</name>
              <bitOffset>9</bitOffset>
              <bitWidth>1</bitWidth>
            </field>
            <field>
              <name>FB10</name>
              <bitOffset>10</bitOffset>
              <bitWidth>1</bitWidth>
            </field>
            <field>
              <name>FB11</name>
              <bitOffset>11</bitOffset>
              <bitWidth>1</bitWidth>
            </field>
            <field>
              <name>FB12</name>
              <bitOffset>12</bitOffset>
              <bitWidth>1</bitWidth>
            </field>
            <field>
              <name>FB13</name>
              <bitOffset>13</bitOffset>
              <bitWidth>1</bitWidth>
            </field>
            <field>
              <name>FB14</name>
              <bitOffset>14</bitOffset>
              <bitWidth>1</bitWidth>
            </field>
            <field>
              <name>FB15</name>
              <bitOffset>15</bitOffset>
              <bitWidth>1</bitWidth>
            </field>
            <field>
              <name>FB16</name>
              <bitOffset>16</bitOffset>
              <bitWidth>1</bitWidth>
            </field>
            <field>
              <name>FB17</name>
              <bitOffset>17</bitOffset>
              <bitWidth>1</bitWidth>
            </field>
            <field>
              <name>FB18</name>
              <bitOffset>18</bitOffset>
              <bitWidth>1</bitWidth>
            </field>
            <field>
              <name>FB19</name>
              <bitOffset>19</bitOffset>
              <bitWidth>1</bitWidth>
            </field>
            <field>
              <name>FB20</name>
              <bitOffset>20</bitOffset>
              <bitWidth>1</bitWidth>
            </field>
            <field>
              <name>FB21</name>
              <bitOffset>21</bitOffset>
              <bitWidth>1</bitWidth>
            </field>
            <field>
              <name>FB22</name>
              <bitOffset>22</bitOffset>
              <bitWidth>1</bitWidth>
            </field>
            <field>
              <name>FB23</name>
              <bitOffset>23</bitOffset>
              <bitWidth>1</bitWidth>
            </field>
            <field>
              <name>FB24</name>
              <bitOffset>24</bitOffset>
              <bitWidth>1</bitWidth>
            </field>
            <field>
              <name>FB25</name>
              <bitOffset>25</bitOffset>
              <bitWidth>1</bitWidth>
            </field>
            <field>
              <name>FB26</name>
              <bitOffset>26</bitOffset>
              <bitWidth>1</bitWidth>
            </field>
            <field>
              <name>FB27</name>
              <bitOffset>27</bitOffset>
              <bitWidth>1</bitWidth>
            </field>
            <field>
              <name>FB28</name>
              <bitOffset>28</bitOffset>
              <bitWidth>1</bitWidth>
            </field>
            <field>
              <name>FB29</name>
              <bitOffset>29</bitOffset>
              <bitWidth>1</bitWidth>
            </field>
            <field>
              <name>FB30</name>
              <bitOffset>30</bitOffset>
              <bitWidth>1</bitWidth>
            </field>
            <field>
              <name>FB31</name>
              <bitOffset>31</bitOffset>
              <bitWidth>1</bitWidth>
            </field>
          </fields>
        </register>
        <register>
          <name>sFilterRegister.1.FR2</name>
          <addressOffset>0x24c</addressOffset>
          <size>0x20</size>
          <fields>
            <field>
              <name>FB0</name>
              <bitOffset>0</bitOffset>
              <bitWidth>1</bitWidth>
            </field>
            <field>
              <name>FB1</name>
              <bitOffset>1</bitOffset>
              <bitWidth>1</bitWidth>
            </field>
            <field>
              <name>FB2</name>
              <bitOffset>2</bitOffset>
              <bitWidth>1</bitWidth>
            </field>
            <field>
              <name>FB3</name>
              <bitOffset>3</bitOffset>
              <bitWidth>1</bitWidth>
            </field>
            <field>
              <name>FB4</name>
              <bitOffset>4</bitOffset>
              <bitWidth>1</bitWidth>
            </field>
            <field>
              <name>FB5</name>
              <bitOffset>5</bitOffset>
              <bitWidth>1</bitWidth>
            </field>
            <field>
              <name>FB6</name>
              <bitOffset>6</bitOffset>
              <bitWidth>1</bitWidth>
            </field>
            <field>
              <name>FB7</name>
              <bitOffset>7</bitOffset>
              <bitWidth>1</bitWidth>
            </field>
            <field>
              <name>FB8</name>
              <bitOffset>8</bitOffset>
              <bitWidth>1</bitWidth>
            </field>
            <field>
              <name>FB9</name>
              <bitOffset>9</bitOffset>
              <bitWidth>1</bitWidth>
            </field>
            <field>
              <name>FB10</name>
              <bitOffset>10</bitOffset>
              <bitWidth>1</bitWidth>
            </field>
            <field>
              <name>FB11</name>
              <bitOffset>11</bitOffset>
              <bitWidth>1</bitWidth>
            </field>
            <field>
              <name>FB12</name>
              <bitOffset>12</bitOffset>
              <bitWidth>1</bitWidth>
            </field>
            <field>
              <name>FB13</name>
              <bitOffset>13</bitOffset>
              <bitWidth>1</bitWidth>
            </field>
            <field>
              <name>FB14</name>
              <bitOffset>14</bitOffset>
              <bitWidth>1</bitWidth>
            </field>
            <field>
              <name>FB15</name>
              <bitOffset>15</bitOffset>
              <bitWidth>1</bitWidth>
            </field>
            <field>
              <name>FB16</name>
              <bitOffset>16</bitOffset>
              <bitWidth>1</bitWidth>
            </field>
            <field>
              <name>FB17</name>
              <bitOffset>17</bitOffset>
              <bitWidth>1</bitWidth>
            </field>
            <field>
              <name>FB18</name>
              <bitOffset>18</bitOffset>
              <bitWidth>1</bitWidth>
            </field>
            <field>
              <name>FB19</name>
              <bitOffset>19</bitOffset>
              <bitWidth>1</bitWidth>
            </field>
            <field>
              <name>FB20</name>
              <bitOffset>20</bitOffset>
              <bitWidth>1</bitWidth>
            </field>
            <field>
              <name>FB21</name>
              <bitOffset>21</bitOffset>
              <bitWidth>1</bitWidth>
            </field>
            <field>
              <name>FB22</name>
              <bitOffset>22</bitOffset>
              <bitWidth>1</bitWidth>
            </field>
            <field>
              <name>FB23</name>
              <bitOffset>23</bitOffset>
              <bitWidth>1</bitWidth>
            </field>
            <field>
              <name>FB24</name>
              <bitOffset>24</bitOffset>
              <bitWidth>1</bitWidth>
            </field>
            <field>
              <name>FB25</name>
              <bitOffset>25</bitOffset>
              <bitWidth>1</bitWidth>
            </field>
            <field>
              <name>FB26</name>
              <bitOffset>26</bitOffset>
              <bitWidth>1</bitWidth>
            </field>
            <field>
              <name>FB27</name>
              <bitOffset>27</bitOffset>
              <bitWidth>1</bitWidth>
            </field>
            <field>
              <name>FB28</name>
              <bitOffset>28</bitOffset>
              <bitWidth>1</bitWidth>
            </field>
            <field>
              <name>FB29</name>
              <bitOffset>29</bitOffset>
              <bitWidth>1</bitWidth>
            </field>
            <field>
              <name>FB30</name>
              <bitOffset>30</bitOffset>
              <bitWidth>1</bitWidth>
            </field>
            <field>
              <name>FB31</name>
              <bitOffset>31</bitOffset>
              <bitWidth>1</bitWidth>
            </field>
          </fields>
        </register>
        <register>
          <name>sFilterRegister.2.FR1</name>
          <addressOffset>0x250</addressOffset>
          <size>0x20</size>
          <fields>
            <field>
              <name>FB0</name>
              <bitOffset>0</bitOffset>
              <bitWidth>1</bitWidth>
            </field>
            <field>
              <name>FB1</name>
              <bitOffset>1</bitOffset>
              <bitWidth>1</bitWidth>
            </field>
            <field>
              <name>FB2</name>
              <bitOffset>2</bitOffset>
              <bitWidth>1</bitWidth>
            </field>
            <field>
              <name>FB3</name>
              <bitOffset>3</bitOffset>
              <bitWidth>1</bitWidth>
            </field>
            <field>
              <name>FB4</name>
              <bitOffset>4</bitOffset>
              <bitWidth>1</bitWidth>
            </field>
            <field>
              <name>FB5</name>
              <bitOffset>5</bitOffset>
              <bitWidth>1</bitWidth>
            </field>
            <field>
              <name>FB6</name>
              <bitOffset>6</bitOffset>
              <bitWidth>1</bitWidth>
            </field>
            <field>
              <name>FB7</name>
              <bitOffset>7</bitOffset>
              <bitWidth>1</bitWidth>
            </field>
            <field>
              <name>FB8</name>
              <bitOffset>8</bitOffset>
              <bitWidth>1</bitWidth>
            </field>
            <field>
              <name>FB9</name>
              <bitOffset>9</bitOffset>
              <bitWidth>1</bitWidth>
            </field>
            <field>
              <name>FB10</name>
              <bitOffset>10</bitOffset>
              <bitWidth>1</bitWidth>
            </field>
            <field>
              <name>FB11</name>
              <bitOffset>11</bitOffset>
              <bitWidth>1</bitWidth>
            </field>
            <field>
              <name>FB12</name>
              <bitOffset>12</bitOffset>
              <bitWidth>1</bitWidth>
            </field>
            <field>
              <name>FB13</name>
              <bitOffset>13</bitOffset>
              <bitWidth>1</bitWidth>
            </field>
            <field>
              <name>FB14</name>
              <bitOffset>14</bitOffset>
              <bitWidth>1</bitWidth>
            </field>
            <field>
              <name>FB15</name>
              <bitOffset>15</bitOffset>
              <bitWidth>1</bitWidth>
            </field>
            <field>
              <name>FB16</name>
              <bitOffset>16</bitOffset>
              <bitWidth>1</bitWidth>
            </field>
            <field>
              <name>FB17</name>
              <bitOffset>17</bitOffset>
              <bitWidth>1</bitWidth>
            </field>
            <field>
              <name>FB18</name>
              <bitOffset>18</bitOffset>
              <bitWidth>1</bitWidth>
            </field>
            <field>
              <name>FB19</name>
              <bitOffset>19</bitOffset>
              <bitWidth>1</bitWidth>
            </field>
            <field>
              <name>FB20</name>
              <bitOffset>20</bitOffset>
              <bitWidth>1</bitWidth>
            </field>
            <field>
              <name>FB21</name>
              <bitOffset>21</bitOffset>
              <bitWidth>1</bitWidth>
            </field>
            <field>
              <name>FB22</name>
              <bitOffset>22</bitOffset>
              <bitWidth>1</bitWidth>
            </field>
            <field>
              <name>FB23</name>
              <bitOffset>23</bitOffset>
              <bitWidth>1</bitWidth>
            </field>
            <field>
              <name>FB24</name>
              <bitOffset>24</bitOffset>
              <bitWidth>1</bitWidth>
            </field>
            <field>
              <name>FB25</name>
              <bitOffset>25</bitOffset>
              <bitWidth>1</bitWidth>
            </field>
            <field>
              <name>FB26</name>
              <bitOffset>26</bitOffset>
              <bitWidth>1</bitWidth>
            </field>
            <field>
              <name>FB27</name>
              <bitOffset>27</bitOffset>
              <bitWidth>1</bitWidth>
            </field>
            <field>
              <name>FB28</name>
              <bitOffset>28</bitOffset>
              <bitWidth>1</bitWidth>
            </field>
            <field>
              <name>FB29</name>
              <bitOffset>29</bitOffset>
              <bitWidth>1</bitWidth>
            </field>
            <field>
              <name>FB30</name>
              <bitOffset>30</bitOffset>
              <bitWidth>1</bitWidth>
            </field>
            <field>
              <name>FB31</name>
              <bitOffset>31</bitOffset>
              <bitWidth>1</bitWidth>
            </field>
          </fields>
        </register>
        <register>
          <name>sFilterRegister.2.FR2</name>
          <addressOffset>0x254</addressOffset>
          <size>0x20</size>
          <fields>
            <field>
              <name>FB0</name>
              <bitOffset>0</bitOffset>
              <bitWidth>1</bitWidth>
            </field>
            <field>
              <name>FB1</name>
              <bitOffset>1</bitOffset>
              <bitWidth>1</bitWidth>
            </field>
            <field>
              <name>FB2</name>
              <bitOffset>2</bitOffset>
              <bitWidth>1</bitWidth>
            </field>
            <field>
              <name>FB3</name>
              <bitOffset>3</bitOffset>
              <bitWidth>1</bitWidth>
            </field>
            <field>
              <name>FB4</name>
              <bitOffset>4</bitOffset>
              <bitWidth>1</bitWidth>
            </field>
            <field>
              <name>FB5</name>
              <bitOffset>5</bitOffset>
              <bitWidth>1</bitWidth>
            </field>
            <field>
              <name>FB6</name>
              <bitOffset>6</bitOffset>
              <bitWidth>1</bitWidth>
            </field>
            <field>
              <name>FB7</name>
              <bitOffset>7</bitOffset>
              <bitWidth>1</bitWidth>
            </field>
            <field>
              <name>FB8</name>
              <bitOffset>8</bitOffset>
              <bitWidth>1</bitWidth>
            </field>
            <field>
              <name>FB9</name>
              <bitOffset>9</bitOffset>
              <bitWidth>1</bitWidth>
            </field>
            <field>
              <name>FB10</name>
              <bitOffset>10</bitOffset>
              <bitWidth>1</bitWidth>
            </field>
            <field>
              <name>FB11</name>
              <bitOffset>11</bitOffset>
              <bitWidth>1</bitWidth>
            </field>
            <field>
              <name>FB12</name>
              <bitOffset>12</bitOffset>
              <bitWidth>1</bitWidth>
            </field>
            <field>
              <name>FB13</name>
              <bitOffset>13</bitOffset>
              <bitWidth>1</bitWidth>
            </field>
            <field>
              <name>FB14</name>
              <bitOffset>14</bitOffset>
              <bitWidth>1</bitWidth>
            </field>
            <field>
              <name>FB15</name>
              <bitOffset>15</bitOffset>
              <bitWidth>1</bitWidth>
            </field>
            <field>
              <name>FB16</name>
              <bitOffset>16</bitOffset>
              <bitWidth>1</bitWidth>
            </field>
            <field>
              <name>FB17</name>
              <bitOffset>17</bitOffset>
              <bitWidth>1</bitWidth>
            </field>
            <field>
              <name>FB18</name>
              <bitOffset>18</bitOffset>
              <bitWidth>1</bitWidth>
            </field>
            <field>
              <name>FB19</name>
              <bitOffset>19</bitOffset>
              <bitWidth>1</bitWidth>
            </field>
            <field>
              <name>FB20</name>
              <bitOffset>20</bitOffset>
              <bitWidth>1</bitWidth>
            </field>
            <field>
              <name>FB21</name>
              <bitOffset>21</bitOffset>
              <bitWidth>1</bitWidth>
            </field>
            <field>
              <name>FB22</name>
              <bitOffset>22</bitOffset>
              <bitWidth>1</bitWidth>
            </field>
            <field>
              <name>FB23</name>
              <bitOffset>23</bitOffset>
              <bitWidth>1</bitWidth>
            </field>
            <field>
              <name>FB24</name>
              <bitOffset>24</bitOffset>
              <bitWidth>1</bitWidth>
            </field>
            <field>
              <name>FB25</name>
              <bitOffset>25</bitOffset>
              <bitWidth>1</bitWidth>
            </field>
            <field>
              <name>FB26</name>
              <bitOffset>26</bitOffset>
              <bitWidth>1</bitWidth>
            </field>
            <field>
              <name>FB27</name>
              <bitOffset>27</bitOffset>
              <bitWidth>1</bitWidth>
            </field>
            <field>
              <name>FB28</name>
              <bitOffset>28</bitOffset>
              <bitWidth>1</bitWidth>
            </field>
            <field>
              <name>FB29</name>
              <bitOffset>29</bitOffset>
              <bitWidth>1</bitWidth>
            </field>
            <field>
              <name>FB30</name>
              <bitOffset>30</bitOffset>
              <bitWidth>1</bitWidth>
            </field>
            <field>
              <name>FB31</name>
              <bitOffset>31</bitOffset>
              <bitWidth>1</bitWidth>
            </field>
          </fields>
        </register>
        <register>
          <name>sFilterRegister.3.FR1</name>
          <addressOffset>0x258</addressOffset>
          <size>0x20</size>
          <fields>
            <field>
              <name>FB0</name>
              <bitOffset>0</bitOffset>
              <bitWidth>1</bitWidth>
            </field>
            <field>
              <name>FB1</name>
              <bitOffset>1</bitOffset>
              <bitWidth>1</bitWidth>
            </field>
            <field>
              <name>FB2</name>
              <bitOffset>2</bitOffset>
              <bitWidth>1</bitWidth>
            </field>
            <field>
              <name>FB3</name>
              <bitOffset>3</bitOffset>
              <bitWidth>1</bitWidth>
            </field>
            <field>
              <name>FB4</name>
              <bitOffset>4</bitOffset>
              <bitWidth>1</bitWidth>
            </field>
            <field>
              <name>FB5</name>
              <bitOffset>5</bitOffset>
              <bitWidth>1</bitWidth>
            </field>
            <field>
              <name>FB6</name>
              <bitOffset>6</bitOffset>
              <bitWidth>1</bitWidth>
            </field>
            <field>
              <name>FB7</name>
              <bitOffset>7</bitOffset>
              <bitWidth>1</bitWidth>
            </field>
            <field>
              <name>FB8</name>
              <bitOffset>8</bitOffset>
              <bitWidth>1</bitWidth>
            </field>
            <field>
              <name>FB9</name>
              <bitOffset>9</bitOffset>
              <bitWidth>1</bitWidth>
            </field>
            <field>
              <name>FB10</name>
              <bitOffset>10</bitOffset>
              <bitWidth>1</bitWidth>
            </field>
            <field>
              <name>FB11</name>
              <bitOffset>11</bitOffset>
              <bitWidth>1</bitWidth>
            </field>
            <field>
              <name>FB12</name>
              <bitOffset>12</bitOffset>
              <bitWidth>1</bitWidth>
            </field>
            <field>
              <name>FB13</name>
              <bitOffset>13</bitOffset>
              <bitWidth>1</bitWidth>
            </field>
            <field>
              <name>FB14</name>
              <bitOffset>14</bitOffset>
              <bitWidth>1</bitWidth>
            </field>
            <field>
              <name>FB15</name>
              <bitOffset>15</bitOffset>
              <bitWidth>1</bitWidth>
            </field>
            <field>
              <name>FB16</name>
              <bitOffset>16</bitOffset>
              <bitWidth>1</bitWidth>
            </field>
            <field>
              <name>FB17</name>
              <bitOffset>17</bitOffset>
              <bitWidth>1</bitWidth>
            </field>
            <field>
              <name>FB18</name>
              <bitOffset>18</bitOffset>
              <bitWidth>1</bitWidth>
            </field>
            <field>
              <name>FB19</name>
              <bitOffset>19</bitOffset>
              <bitWidth>1</bitWidth>
            </field>
            <field>
              <name>FB20</name>
              <bitOffset>20</bitOffset>
              <bitWidth>1</bitWidth>
            </field>
            <field>
              <name>FB21</name>
              <bitOffset>21</bitOffset>
              <bitWidth>1</bitWidth>
            </field>
            <field>
              <name>FB22</name>
              <bitOffset>22</bitOffset>
              <bitWidth>1</bitWidth>
            </field>
            <field>
              <name>FB23</name>
              <bitOffset>23</bitOffset>
              <bitWidth>1</bitWidth>
            </field>
            <field>
              <name>FB24</name>
              <bitOffset>24</bitOffset>
              <bitWidth>1</bitWidth>
            </field>
            <field>
              <name>FB25</name>
              <bitOffset>25</bitOffset>
              <bitWidth>1</bitWidth>
            </field>
            <field>
              <name>FB26</name>
              <bitOffset>26</bitOffset>
              <bitWidth>1</bitWidth>
            </field>
            <field>
              <name>FB27</name>
              <bitOffset>27</bitOffset>
              <bitWidth>1</bitWidth>
            </field>
            <field>
              <name>FB28</name>
              <bitOffset>28</bitOffset>
              <bitWidth>1</bitWidth>
            </field>
            <field>
              <name>FB29</name>
              <bitOffset>29</bitOffset>
              <bitWidth>1</bitWidth>
            </field>
            <field>
              <name>FB30</name>
              <bitOffset>30</bitOffset>
              <bitWidth>1</bitWidth>
            </field>
            <field>
              <name>FB31</name>
              <bitOffset>31</bitOffset>
              <bitWidth>1</bitWidth>
            </field>
          </fields>
        </register>
        <register>
          <name>sFilterRegister.3.FR2</name>
          <addressOffset>0x25c</addressOffset>
          <size>0x20</size>
          <fields>
            <field>
              <name>FB0</name>
              <bitOffset>0</bitOffset>
              <bitWidth>1</bitWidth>
            </field>
            <field>
              <name>FB1</name>
              <bitOffset>1</bitOffset>
              <bitWidth>1</bitWidth>
            </field>
            <field>
              <name>FB2</name>
              <bitOffset>2</bitOffset>
              <bitWidth>1</bitWidth>
            </field>
            <field>
              <name>FB3</name>
              <bitOffset>3</bitOffset>
              <bitWidth>1</bitWidth>
            </field>
            <field>
              <name>FB4</name>
              <bitOffset>4</bitOffset>
              <bitWidth>1</bitWidth>
            </field>
            <field>
              <name>FB5</name>
              <bitOffset>5</bitOffset>
              <bitWidth>1</bitWidth>
            </field>
            <field>
              <name>FB6</name>
              <bitOffset>6</bitOffset>
              <bitWidth>1</bitWidth>
            </field>
            <field>
              <name>FB7</name>
              <bitOffset>7</bitOffset>
              <bitWidth>1</bitWidth>
            </field>
            <field>
              <name>FB8</name>
              <bitOffset>8</bitOffset>
              <bitWidth>1</bitWidth>
            </field>
            <field>
              <name>FB9</name>
              <bitOffset>9</bitOffset>
              <bitWidth>1</bitWidth>
            </field>
            <field>
              <name>FB10</name>
              <bitOffset>10</bitOffset>
              <bitWidth>1</bitWidth>
            </field>
            <field>
              <name>FB11</name>
              <bitOffset>11</bitOffset>
              <bitWidth>1</bitWidth>
            </field>
            <field>
              <name>FB12</name>
              <bitOffset>12</bitOffset>
              <bitWidth>1</bitWidth>
            </field>
            <field>
              <name>FB13</name>
              <bitOffset>13</bitOffset>
              <bitWidth>1</bitWidth>
            </field>
            <field>
              <name>FB14</name>
              <bitOffset>14</bitOffset>
              <bitWidth>1</bitWidth>
            </field>
            <field>
              <name>FB15</name>
              <bitOffset>15</bitOffset>
              <bitWidth>1</bitWidth>
            </field>
            <field>
              <name>FB16</name>
              <bitOffset>16</bitOffset>
              <bitWidth>1</bitWidth>
            </field>
            <field>
              <name>FB17</name>
              <bitOffset>17</bitOffset>
              <bitWidth>1</bitWidth>
            </field>
            <field>
              <name>FB18</name>
              <bitOffset>18</bitOffset>
              <bitWidth>1</bitWidth>
            </field>
            <field>
              <name>FB19</name>
              <bitOffset>19</bitOffset>
              <bitWidth>1</bitWidth>
            </field>
            <field>
              <name>FB20</name>
              <bitOffset>20</bitOffset>
              <bitWidth>1</bitWidth>
            </field>
            <field>
              <name>FB21</name>
              <bitOffset>21</bitOffset>
              <bitWidth>1</bitWidth>
            </field>
            <field>
              <name>FB22</name>
              <bitOffset>22</bitOffset>
              <bitWidth>1</bitWidth>
            </field>
            <field>
              <name>FB23</name>
              <bitOffset>23</bitOffset>
              <bitWidth>1</bitWidth>
            </field>
            <field>
              <name>FB24</name>
              <bitOffset>24</bitOffset>
              <bitWidth>1</bitWidth>
            </field>
            <field>
              <name>FB25</name>
              <bitOffset>25</bitOffset>
              <bitWidth>1</bitWidth>
            </field>
            <field>
              <name>FB26</name>
              <bitOffset>26</bitOffset>
              <bitWidth>1</bitWidth>
            </field>
            <field>
              <name>FB27</name>
              <bitOffset>27</bitOffset>
              <bitWidth>1</bitWidth>
            </field>
            <field>
              <name>FB28</name>
              <bitOffset>28</bitOffset>
              <bitWidth>1</bitWidth>
            </field>
            <field>
              <name>FB29</name>
              <bitOffset>29</bitOffset>
              <bitWidth>1</bitWidth>
            </field>
            <field>
              <name>FB30</name>
              <bitOffset>30</bitOffset>
              <bitWidth>1</bitWidth>
            </field>
            <field>
              <name>FB31</name>
              <bitOffset>31</bitOffset>
              <bitWidth>1</bitWidth>
            </field>
          </fields>
        </register>
        <register>
          <name>sFilterRegister.4.FR1</name>
          <addressOffset>0x260</addressOffset>
          <size>0x20</size>
          <fields>
            <field>
              <name>FB0</name>
              <bitOffset>0</bitOffset>
              <bitWidth>1</bitWidth>
            </field>
            <field>
              <name>FB1</name>
              <bitOffset>1</bitOffset>
              <bitWidth>1</bitWidth>
            </field>
            <field>
              <name>FB2</name>
              <bitOffset>2</bitOffset>
              <bitWidth>1</bitWidth>
            </field>
            <field>
              <name>FB3</name>
              <bitOffset>3</bitOffset>
              <bitWidth>1</bitWidth>
            </field>
            <field>
              <name>FB4</name>
              <bitOffset>4</bitOffset>
              <bitWidth>1</bitWidth>
            </field>
            <field>
              <name>FB5</name>
              <bitOffset>5</bitOffset>
              <bitWidth>1</bitWidth>
            </field>
            <field>
              <name>FB6</name>
              <bitOffset>6</bitOffset>
              <bitWidth>1</bitWidth>
            </field>
            <field>
              <name>FB7</name>
              <bitOffset>7</bitOffset>
              <bitWidth>1</bitWidth>
            </field>
            <field>
              <name>FB8</name>
              <bitOffset>8</bitOffset>
              <bitWidth>1</bitWidth>
            </field>
            <field>
              <name>FB9</name>
              <bitOffset>9</bitOffset>
              <bitWidth>1</bitWidth>
            </field>
            <field>
              <name>FB10</name>
              <bitOffset>10</bitOffset>
              <bitWidth>1</bitWidth>
            </field>
            <field>
              <name>FB11</name>
              <bitOffset>11</bitOffset>
              <bitWidth>1</bitWidth>
            </field>
            <field>
              <name>FB12</name>
              <bitOffset>12</bitOffset>
              <bitWidth>1</bitWidth>
            </field>
            <field>
              <name>FB13</name>
              <bitOffset>13</bitOffset>
              <bitWidth>1</bitWidth>
            </field>
            <field>
              <name>FB14</name>
              <bitOffset>14</bitOffset>
              <bitWidth>1</bitWidth>
            </field>
            <field>
              <name>FB15</name>
              <bitOffset>15</bitOffset>
              <bitWidth>1</bitWidth>
            </field>
            <field>
              <name>FB16</name>
              <bitOffset>16</bitOffset>
              <bitWidth>1</bitWidth>
            </field>
            <field>
              <name>FB17</name>
              <bitOffset>17</bitOffset>
              <bitWidth>1</bitWidth>
            </field>
            <field>
              <name>FB18</name>
              <bitOffset>18</bitOffset>
              <bitWidth>1</bitWidth>
            </field>
            <field>
              <name>FB19</name>
              <bitOffset>19</bitOffset>
              <bitWidth>1</bitWidth>
            </field>
            <field>
              <name>FB20</name>
              <bitOffset>20</bitOffset>
              <bitWidth>1</bitWidth>
            </field>
            <field>
              <name>FB21</name>
              <bitOffset>21</bitOffset>
              <bitWidth>1</bitWidth>
            </field>
            <field>
              <name>FB22</name>
              <bitOffset>22</bitOffset>
              <bitWidth>1</bitWidth>
            </field>
            <field>
              <name>FB23</name>
              <bitOffset>23</bitOffset>
              <bitWidth>1</bitWidth>
            </field>
            <field>
              <name>FB24</name>
              <bitOffset>24</bitOffset>
              <bitWidth>1</bitWidth>
            </field>
            <field>
              <name>FB25</name>
              <bitOffset>25</bitOffset>
              <bitWidth>1</bitWidth>
            </field>
            <field>
              <name>FB26</name>
              <bitOffset>26</bitOffset>
              <bitWidth>1</bitWidth>
            </field>
            <field>
              <name>FB27</name>
              <bitOffset>27</bitOffset>
              <bitWidth>1</bitWidth>
            </field>
            <field>
              <name>FB28</name>
              <bitOffset>28</bitOffset>
              <bitWidth>1</bitWidth>
            </field>
            <field>
              <name>FB29</name>
              <bitOffset>29</bitOffset>
              <bitWidth>1</bitWidth>
            </field>
            <field>
              <name>FB30</name>
              <bitOffset>30</bitOffset>
              <bitWidth>1</bitWidth>
            </field>
            <field>
              <name>FB31</name>
              <bitOffset>31</bitOffset>
              <bitWidth>1</bitWidth>
            </field>
          </fields>
        </register>
        <register>
          <name>sFilterRegister.4.FR2</name>
          <addressOffset>0x264</addressOffset>
          <size>0x20</size>
          <fields>
            <field>
              <name>FB0</name>
              <bitOffset>0</bitOffset>
              <bitWidth>1</bitWidth>
            </field>
            <field>
              <name>FB1</name>
              <bitOffset>1</bitOffset>
              <bitWidth>1</bitWidth>
            </field>
            <field>
              <name>FB2</name>
              <bitOffset>2</bitOffset>
              <bitWidth>1</bitWidth>
            </field>
            <field>
              <name>FB3</name>
              <bitOffset>3</bitOffset>
              <bitWidth>1</bitWidth>
            </field>
            <field>
              <name>FB4</name>
              <bitOffset>4</bitOffset>
              <bitWidth>1</bitWidth>
            </field>
            <field>
              <name>FB5</name>
              <bitOffset>5</bitOffset>
              <bitWidth>1</bitWidth>
            </field>
            <field>
              <name>FB6</name>
              <bitOffset>6</bitOffset>
              <bitWidth>1</bitWidth>
            </field>
            <field>
              <name>FB7</name>
              <bitOffset>7</bitOffset>
              <bitWidth>1</bitWidth>
            </field>
            <field>
              <name>FB8</name>
              <bitOffset>8</bitOffset>
              <bitWidth>1</bitWidth>
            </field>
            <field>
              <name>FB9</name>
              <bitOffset>9</bitOffset>
              <bitWidth>1</bitWidth>
            </field>
            <field>
              <name>FB10</name>
              <bitOffset>10</bitOffset>
              <bitWidth>1</bitWidth>
            </field>
            <field>
              <name>FB11</name>
              <bitOffset>11</bitOffset>
              <bitWidth>1</bitWidth>
            </field>
            <field>
              <name>FB12</name>
              <bitOffset>12</bitOffset>
              <bitWidth>1</bitWidth>
            </field>
            <field>
              <name>FB13</name>
              <bitOffset>13</bitOffset>
              <bitWidth>1</bitWidth>
            </field>
            <field>
              <name>FB14</name>
              <bitOffset>14</bitOffset>
              <bitWidth>1</bitWidth>
            </field>
            <field>
              <name>FB15</name>
              <bitOffset>15</bitOffset>
              <bitWidth>1</bitWidth>
            </field>
            <field>
              <name>FB16</name>
              <bitOffset>16</bitOffset>
              <bitWidth>1</bitWidth>
            </field>
            <field>
              <name>FB17</name>
              <bitOffset>17</bitOffset>
              <bitWidth>1</bitWidth>
            </field>
            <field>
              <name>FB18</name>
              <bitOffset>18</bitOffset>
              <bitWidth>1</bitWidth>
            </field>
            <field>
              <name>FB19</name>
              <bitOffset>19</bitOffset>
              <bitWidth>1</bitWidth>
            </field>
            <field>
              <name>FB20</name>
              <bitOffset>20</bitOffset>
              <bitWidth>1</bitWidth>
            </field>
            <field>
              <name>FB21</name>
              <bitOffset>21</bitOffset>
              <bitWidth>1</bitWidth>
            </field>
            <field>
              <name>FB22</name>
              <bitOffset>22</bitOffset>
              <bitWidth>1</bitWidth>
            </field>
            <field>
              <name>FB23</name>
              <bitOffset>23</bitOffset>
              <bitWidth>1</bitWidth>
            </field>
            <field>
              <name>FB24</name>
              <bitOffset>24</bitOffset>
              <bitWidth>1</bitWidth>
            </field>
            <field>
              <name>FB25</name>
              <bitOffset>25</bitOffset>
              <bitWidth>1</bitWidth>
            </field>
            <field>
              <name>FB26</name>
              <bitOffset>26</bitOffset>
              <bitWidth>1</bitWidth>
            </field>
            <field>
              <name>FB27</name>
              <bitOffset>27</bitOffset>
              <bitWidth>1</bitWidth>
            </field>
            <field>
              <name>FB28</name>
              <bitOffset>28</bitOffset>
              <bitWidth>1</bitWidth>
            </field>
            <field>
              <name>FB29</name>
              <bitOffset>29</bitOffset>
              <bitWidth>1</bitWidth>
            </field>
            <field>
              <name>FB30</name>
              <bitOffset>30</bitOffset>
              <bitWidth>1</bitWidth>
            </field>
            <field>
              <name>FB31</name>
              <bitOffset>31</bitOffset>
              <bitWidth>1</bitWidth>
            </field>
          </fields>
        </register>
        <register>
          <name>sFilterRegister.5.FR1</name>
          <addressOffset>0x268</addressOffset>
          <size>0x20</size>
          <fields>
            <field>
              <name>FB0</name>
              <bitOffset>0</bitOffset>
              <bitWidth>1</bitWidth>
            </field>
            <field>
              <name>FB1</name>
              <bitOffset>1</bitOffset>
              <bitWidth>1</bitWidth>
            </field>
            <field>
              <name>FB2</name>
              <bitOffset>2</bitOffset>
              <bitWidth>1</bitWidth>
            </field>
            <field>
              <name>FB3</name>
              <bitOffset>3</bitOffset>
              <bitWidth>1</bitWidth>
            </field>
            <field>
              <name>FB4</name>
              <bitOffset>4</bitOffset>
              <bitWidth>1</bitWidth>
            </field>
            <field>
              <name>FB5</name>
              <bitOffset>5</bitOffset>
              <bitWidth>1</bitWidth>
            </field>
            <field>
              <name>FB6</name>
              <bitOffset>6</bitOffset>
              <bitWidth>1</bitWidth>
            </field>
            <field>
              <name>FB7</name>
              <bitOffset>7</bitOffset>
              <bitWidth>1</bitWidth>
            </field>
            <field>
              <name>FB8</name>
              <bitOffset>8</bitOffset>
              <bitWidth>1</bitWidth>
            </field>
            <field>
              <name>FB9</name>
              <bitOffset>9</bitOffset>
              <bitWidth>1</bitWidth>
            </field>
            <field>
              <name>FB10</name>
              <bitOffset>10</bitOffset>
              <bitWidth>1</bitWidth>
            </field>
            <field>
              <name>FB11</name>
              <bitOffset>11</bitOffset>
              <bitWidth>1</bitWidth>
            </field>
            <field>
              <name>FB12</name>
              <bitOffset>12</bitOffset>
              <bitWidth>1</bitWidth>
            </field>
            <field>
              <name>FB13</name>
              <bitOffset>13</bitOffset>
              <bitWidth>1</bitWidth>
            </field>
            <field>
              <name>FB14</name>
              <bitOffset>14</bitOffset>
              <bitWidth>1</bitWidth>
            </field>
            <field>
              <name>FB15</name>
              <bitOffset>15</bitOffset>
              <bitWidth>1</bitWidth>
            </field>
            <field>
              <name>FB16</name>
              <bitOffset>16</bitOffset>
              <bitWidth>1</bitWidth>
            </field>
            <field>
              <name>FB17</name>
              <bitOffset>17</bitOffset>
              <bitWidth>1</bitWidth>
            </field>
            <field>
              <name>FB18</name>
              <bitOffset>18</bitOffset>
              <bitWidth>1</bitWidth>
            </field>
            <field>
              <name>FB19</name>
              <bitOffset>19</bitOffset>
              <bitWidth>1</bitWidth>
            </field>
            <field>
              <name>FB20</name>
              <bitOffset>20</bitOffset>
              <bitWidth>1</bitWidth>
            </field>
            <field>
              <name>FB21</name>
              <bitOffset>21</bitOffset>
              <bitWidth>1</bitWidth>
            </field>
            <field>
              <name>FB22</name>
              <bitOffset>22</bitOffset>
              <bitWidth>1</bitWidth>
            </field>
            <field>
              <name>FB23</name>
              <bitOffset>23</bitOffset>
              <bitWidth>1</bitWidth>
            </field>
            <field>
              <name>FB24</name>
              <bitOffset>24</bitOffset>
              <bitWidth>1</bitWidth>
            </field>
            <field>
              <name>FB25</name>
              <bitOffset>25</bitOffset>
              <bitWidth>1</bitWidth>
            </field>
            <field>
              <name>FB26</name>
              <bitOffset>26</bitOffset>
              <bitWidth>1</bitWidth>
            </field>
            <field>
              <name>FB27</name>
              <bitOffset>27</bitOffset>
              <bitWidth>1</bitWidth>
            </field>
            <field>
              <name>FB28</name>
              <bitOffset>28</bitOffset>
              <bitWidth>1</bitWidth>
            </field>
            <field>
              <name>FB29</name>
              <bitOffset>29</bitOffset>
              <bitWidth>1</bitWidth>
            </field>
            <field>
              <name>FB30</name>
              <bitOffset>30</bitOffset>
              <bitWidth>1</bitWidth>
            </field>
            <field>
              <name>FB31</name>
              <bitOffset>31</bitOffset>
              <bitWidth>1</bitWidth>
            </field>
          </fields>
        </register>
        <register>
          <name>sFilterRegister.5.FR2</name>
          <addressOffset>0x26c</addressOffset>
          <size>0x20</size>
          <fields>
            <field>
              <name>FB0</name>
              <bitOffset>0</bitOffset>
              <bitWidth>1</bitWidth>
            </field>
            <field>
              <name>FB1</name>
              <bitOffset>1</bitOffset>
              <bitWidth>1</bitWidth>
            </field>
            <field>
              <name>FB2</name>
              <bitOffset>2</bitOffset>
              <bitWidth>1</bitWidth>
            </field>
            <field>
              <name>FB3</name>
              <bitOffset>3</bitOffset>
              <bitWidth>1</bitWidth>
            </field>
            <field>
              <name>FB4</name>
              <bitOffset>4</bitOffset>
              <bitWidth>1</bitWidth>
            </field>
            <field>
              <name>FB5</name>
              <bitOffset>5</bitOffset>
              <bitWidth>1</bitWidth>
            </field>
            <field>
              <name>FB6</name>
              <bitOffset>6</bitOffset>
              <bitWidth>1</bitWidth>
            </field>
            <field>
              <name>FB7</name>
              <bitOffset>7</bitOffset>
              <bitWidth>1</bitWidth>
            </field>
            <field>
              <name>FB8</name>
              <bitOffset>8</bitOffset>
              <bitWidth>1</bitWidth>
            </field>
            <field>
              <name>FB9</name>
              <bitOffset>9</bitOffset>
              <bitWidth>1</bitWidth>
            </field>
            <field>
              <name>FB10</name>
              <bitOffset>10</bitOffset>
              <bitWidth>1</bitWidth>
            </field>
            <field>
              <name>FB11</name>
              <bitOffset>11</bitOffset>
              <bitWidth>1</bitWidth>
            </field>
            <field>
              <name>FB12</name>
              <bitOffset>12</bitOffset>
              <bitWidth>1</bitWidth>
            </field>
            <field>
              <name>FB13</name>
              <bitOffset>13</bitOffset>
              <bitWidth>1</bitWidth>
            </field>
            <field>
              <name>FB14</name>
              <bitOffset>14</bitOffset>
              <bitWidth>1</bitWidth>
            </field>
            <field>
              <name>FB15</name>
              <bitOffset>15</bitOffset>
              <bitWidth>1</bitWidth>
            </field>
            <field>
              <name>FB16</name>
              <bitOffset>16</bitOffset>
              <bitWidth>1</bitWidth>
            </field>
            <field>
              <name>FB17</name>
              <bitOffset>17</bitOffset>
              <bitWidth>1</bitWidth>
            </field>
            <field>
              <name>FB18</name>
              <bitOffset>18</bitOffset>
              <bitWidth>1</bitWidth>
            </field>
            <field>
              <name>FB19</name>
              <bitOffset>19</bitOffset>
              <bitWidth>1</bitWidth>
            </field>
            <field>
              <name>FB20</name>
              <bitOffset>20</bitOffset>
              <bitWidth>1</bitWidth>
            </field>
            <field>
              <name>FB21</name>
              <bitOffset>21</bitOffset>
              <bitWidth>1</bitWidth>
            </field>
            <field>
              <name>FB22</name>
              <bitOffset>22</bitOffset>
              <bitWidth>1</bitWidth>
            </field>
            <field>
              <name>FB23</name>
              <bitOffset>23</bitOffset>
              <bitWidth>1</bitWidth>
            </field>
            <field>
              <name>FB24</name>
              <bitOffset>24</bitOffset>
              <bitWidth>1</bitWidth>
            </field>
            <field>
              <name>FB25</name>
              <bitOffset>25</bitOffset>
              <bitWidth>1</bitWidth>
            </field>
            <field>
              <name>FB26</name>
              <bitOffset>26</bitOffset>
              <bitWidth>1</bitWidth>
            </field>
            <field>
              <name>FB27</name>
              <bitOffset>27</bitOffset>
              <bitWidth>1</bitWidth>
            </field>
            <field>
              <name>FB28</name>
              <bitOffset>28</bitOffset>
              <bitWidth>1</bitWidth>
            </field>
            <field>
              <name>FB29</name>
              <bitOffset>29</bitOffset>
              <bitWidth>1</bitWidth>
            </field>
            <field>
              <name>FB30</name>
              <bitOffset>30</bitOffset>
              <bitWidth>1</bitWidth>
            </field>
            <field>
              <name>FB31</name>
              <bitOffset>31</bitOffset>
              <bitWidth>1</bitWidth>
            </field>
          </fields>
        </register>
        <register>
          <name>sFilterRegister.6.FR1</name>
          <addressOffset>0x270</addressOffset>
          <size>0x20</size>
          <fields>
            <field>
              <name>FB0</name>
              <bitOffset>0</bitOffset>
              <bitWidth>1</bitWidth>
            </field>
            <field>
              <name>FB1</name>
              <bitOffset>1</bitOffset>
              <bitWidth>1</bitWidth>
            </field>
            <field>
              <name>FB2</name>
              <bitOffset>2</bitOffset>
              <bitWidth>1</bitWidth>
            </field>
            <field>
              <name>FB3</name>
              <bitOffset>3</bitOffset>
              <bitWidth>1</bitWidth>
            </field>
            <field>
              <name>FB4</name>
              <bitOffset>4</bitOffset>
              <bitWidth>1</bitWidth>
            </field>
            <field>
              <name>FB5</name>
              <bitOffset>5</bitOffset>
              <bitWidth>1</bitWidth>
            </field>
            <field>
              <name>FB6</name>
              <bitOffset>6</bitOffset>
              <bitWidth>1</bitWidth>
            </field>
            <field>
              <name>FB7</name>
              <bitOffset>7</bitOffset>
              <bitWidth>1</bitWidth>
            </field>
            <field>
              <name>FB8</name>
              <bitOffset>8</bitOffset>
              <bitWidth>1</bitWidth>
            </field>
            <field>
              <name>FB9</name>
              <bitOffset>9</bitOffset>
              <bitWidth>1</bitWidth>
            </field>
            <field>
              <name>FB10</name>
              <bitOffset>10</bitOffset>
              <bitWidth>1</bitWidth>
            </field>
            <field>
              <name>FB11</name>
              <bitOffset>11</bitOffset>
              <bitWidth>1</bitWidth>
            </field>
            <field>
              <name>FB12</name>
              <bitOffset>12</bitOffset>
              <bitWidth>1</bitWidth>
            </field>
            <field>
              <name>FB13</name>
              <bitOffset>13</bitOffset>
              <bitWidth>1</bitWidth>
            </field>
            <field>
              <name>FB14</name>
              <bitOffset>14</bitOffset>
              <bitWidth>1</bitWidth>
            </field>
            <field>
              <name>FB15</name>
              <bitOffset>15</bitOffset>
              <bitWidth>1</bitWidth>
            </field>
            <field>
              <name>FB16</name>
              <bitOffset>16</bitOffset>
              <bitWidth>1</bitWidth>
            </field>
            <field>
              <name>FB17</name>
              <bitOffset>17</bitOffset>
              <bitWidth>1</bitWidth>
            </field>
            <field>
              <name>FB18</name>
              <bitOffset>18</bitOffset>
              <bitWidth>1</bitWidth>
            </field>
            <field>
              <name>FB19</name>
              <bitOffset>19</bitOffset>
              <bitWidth>1</bitWidth>
            </field>
            <field>
              <name>FB20</name>
              <bitOffset>20</bitOffset>
              <bitWidth>1</bitWidth>
            </field>
            <field>
              <name>FB21</name>
              <bitOffset>21</bitOffset>
              <bitWidth>1</bitWidth>
            </field>
            <field>
              <name>FB22</name>
              <bitOffset>22</bitOffset>
              <bitWidth>1</bitWidth>
            </field>
            <field>
              <name>FB23</name>
              <bitOffset>23</bitOffset>
              <bitWidth>1</bitWidth>
            </field>
            <field>
              <name>FB24</name>
              <bitOffset>24</bitOffset>
              <bitWidth>1</bitWidth>
            </field>
            <field>
              <name>FB25</name>
              <bitOffset>25</bitOffset>
              <bitWidth>1</bitWidth>
            </field>
            <field>
              <name>FB26</name>
              <bitOffset>26</bitOffset>
              <bitWidth>1</bitWidth>
            </field>
            <field>
              <name>FB27</name>
              <bitOffset>27</bitOffset>
              <bitWidth>1</bitWidth>
            </field>
            <field>
              <name>FB28</name>
              <bitOffset>28</bitOffset>
              <bitWidth>1</bitWidth>
            </field>
            <field>
              <name>FB29</name>
              <bitOffset>29</bitOffset>
              <bitWidth>1</bitWidth>
            </field>
            <field>
              <name>FB30</name>
              <bitOffset>30</bitOffset>
              <bitWidth>1</bitWidth>
            </field>
            <field>
              <name>FB31</name>
              <bitOffset>31</bitOffset>
              <bitWidth>1</bitWidth>
            </field>
          </fields>
        </register>
        <register>
          <name>sFilterRegister.6.FR2</name>
          <addressOffset>0x274</addressOffset>
          <size>0x20</size>
          <fields>
            <field>
              <name>FB0</name>
              <bitOffset>0</bitOffset>
              <bitWidth>1</bitWidth>
            </field>
            <field>
              <name>FB1</name>
              <bitOffset>1</bitOffset>
              <bitWidth>1</bitWidth>
            </field>
            <field>
              <name>FB2</name>
              <bitOffset>2</bitOffset>
              <bitWidth>1</bitWidth>
            </field>
            <field>
              <name>FB3</name>
              <bitOffset>3</bitOffset>
              <bitWidth>1</bitWidth>
            </field>
            <field>
              <name>FB4</name>
              <bitOffset>4</bitOffset>
              <bitWidth>1</bitWidth>
            </field>
            <field>
              <name>FB5</name>
              <bitOffset>5</bitOffset>
              <bitWidth>1</bitWidth>
            </field>
            <field>
              <name>FB6</name>
              <bitOffset>6</bitOffset>
              <bitWidth>1</bitWidth>
            </field>
            <field>
              <name>FB7</name>
              <bitOffset>7</bitOffset>
              <bitWidth>1</bitWidth>
            </field>
            <field>
              <name>FB8</name>
              <bitOffset>8</bitOffset>
              <bitWidth>1</bitWidth>
            </field>
            <field>
              <name>FB9</name>
              <bitOffset>9</bitOffset>
              <bitWidth>1</bitWidth>
            </field>
            <field>
              <name>FB10</name>
              <bitOffset>10</bitOffset>
              <bitWidth>1</bitWidth>
            </field>
            <field>
              <name>FB11</name>
              <bitOffset>11</bitOffset>
              <bitWidth>1</bitWidth>
            </field>
            <field>
              <name>FB12</name>
              <bitOffset>12</bitOffset>
              <bitWidth>1</bitWidth>
            </field>
            <field>
              <name>FB13</name>
              <bitOffset>13</bitOffset>
              <bitWidth>1</bitWidth>
            </field>
            <field>
              <name>FB14</name>
              <bitOffset>14</bitOffset>
              <bitWidth>1</bitWidth>
            </field>
            <field>
              <name>FB15</name>
              <bitOffset>15</bitOffset>
              <bitWidth>1</bitWidth>
            </field>
            <field>
              <name>FB16</name>
              <bitOffset>16</bitOffset>
              <bitWidth>1</bitWidth>
            </field>
            <field>
              <name>FB17</name>
              <bitOffset>17</bitOffset>
              <bitWidth>1</bitWidth>
            </field>
            <field>
              <name>FB18</name>
              <bitOffset>18</bitOffset>
              <bitWidth>1</bitWidth>
            </field>
            <field>
              <name>FB19</name>
              <bitOffset>19</bitOffset>
              <bitWidth>1</bitWidth>
            </field>
            <field>
              <name>FB20</name>
              <bitOffset>20</bitOffset>
              <bitWidth>1</bitWidth>
            </field>
            <field>
              <name>FB21</name>
              <bitOffset>21</bitOffset>
              <bitWidth>1</bitWidth>
            </field>
            <field>
              <name>FB22</name>
              <bitOffset>22</bitOffset>
              <bitWidth>1</bitWidth>
            </field>
            <field>
              <name>FB23</name>
              <bitOffset>23</bitOffset>
              <bitWidth>1</bitWidth>
            </field>
            <field>
              <name>FB24</name>
              <bitOffset>24</bitOffset>
              <bitWidth>1</bitWidth>
            </field>
            <field>
              <name>FB25</name>
              <bitOffset>25</bitOffset>
              <bitWidth>1</bitWidth>
            </field>
            <field>
              <name>FB26</name>
              <bitOffset>26</bitOffset>
              <bitWidth>1</bitWidth>
            </field>
            <field>
              <name>FB27</name>
              <bitOffset>27</bitOffset>
              <bitWidth>1</bitWidth>
            </field>
            <field>
              <name>FB28</name>
              <bitOffset>28</bitOffset>
              <bitWidth>1</bitWidth>
            </field>
            <field>
              <name>FB29</name>
              <bitOffset>29</bitOffset>
              <bitWidth>1</bitWidth>
            </field>
            <field>
              <name>FB30</name>
              <bitOffset>30</bitOffset>
              <bitWidth>1</bitWidth>
            </field>
            <field>
              <name>FB31</name>
              <bitOffset>31</bitOffset>
              <bitWidth>1</bitWidth>
            </field>
          </fields>
        </register>
        <register>
          <name>sFilterRegister.7.FR1</name>
          <addressOffset>0x278</addressOffset>
          <size>0x20</size>
          <fields>
            <field>
              <name>FB0</name>
              <bitOffset>0</bitOffset>
              <bitWidth>1</bitWidth>
            </field>
            <field>
              <name>FB1</name>
              <bitOffset>1</bitOffset>
              <bitWidth>1</bitWidth>
            </field>
            <field>
              <name>FB2</name>
              <bitOffset>2</bitOffset>
              <bitWidth>1</bitWidth>
            </field>
            <field>
              <name>FB3</name>
              <bitOffset>3</bitOffset>
              <bitWidth>1</bitWidth>
            </field>
            <field>
              <name>FB4</name>
              <bitOffset>4</bitOffset>
              <bitWidth>1</bitWidth>
            </field>
            <field>
              <name>FB5</name>
              <bitOffset>5</bitOffset>
              <bitWidth>1</bitWidth>
            </field>
            <field>
              <name>FB6</name>
              <bitOffset>6</bitOffset>
              <bitWidth>1</bitWidth>
            </field>
            <field>
              <name>FB7</name>
              <bitOffset>7</bitOffset>
              <bitWidth>1</bitWidth>
            </field>
            <field>
              <name>FB8</name>
              <bitOffset>8</bitOffset>
              <bitWidth>1</bitWidth>
            </field>
            <field>
              <name>FB9</name>
              <bitOffset>9</bitOffset>
              <bitWidth>1</bitWidth>
            </field>
            <field>
              <name>FB10</name>
              <bitOffset>10</bitOffset>
              <bitWidth>1</bitWidth>
            </field>
            <field>
              <name>FB11</name>
              <bitOffset>11</bitOffset>
              <bitWidth>1</bitWidth>
            </field>
            <field>
              <name>FB12</name>
              <bitOffset>12</bitOffset>
              <bitWidth>1</bitWidth>
            </field>
            <field>
              <name>FB13</name>
              <bitOffset>13</bitOffset>
              <bitWidth>1</bitWidth>
            </field>
            <field>
              <name>FB14</name>
              <bitOffset>14</bitOffset>
              <bitWidth>1</bitWidth>
            </field>
            <field>
              <name>FB15</name>
              <bitOffset>15</bitOffset>
              <bitWidth>1</bitWidth>
            </field>
            <field>
              <name>FB16</name>
              <bitOffset>16</bitOffset>
              <bitWidth>1</bitWidth>
            </field>
            <field>
              <name>FB17</name>
              <bitOffset>17</bitOffset>
              <bitWidth>1</bitWidth>
            </field>
            <field>
              <name>FB18</name>
              <bitOffset>18</bitOffset>
              <bitWidth>1</bitWidth>
            </field>
            <field>
              <name>FB19</name>
              <bitOffset>19</bitOffset>
              <bitWidth>1</bitWidth>
            </field>
            <field>
              <name>FB20</name>
              <bitOffset>20</bitOffset>
              <bitWidth>1</bitWidth>
            </field>
            <field>
              <name>FB21</name>
              <bitOffset>21</bitOffset>
              <bitWidth>1</bitWidth>
            </field>
            <field>
              <name>FB22</name>
              <bitOffset>22</bitOffset>
              <bitWidth>1</bitWidth>
            </field>
            <field>
              <name>FB23</name>
              <bitOffset>23</bitOffset>
              <bitWidth>1</bitWidth>
            </field>
            <field>
              <name>FB24</name>
              <bitOffset>24</bitOffset>
              <bitWidth>1</bitWidth>
            </field>
            <field>
              <name>FB25</name>
              <bitOffset>25</bitOffset>
              <bitWidth>1</bitWidth>
            </field>
            <field>
              <name>FB26</name>
              <bitOffset>26</bitOffset>
              <bitWidth>1</bitWidth>
            </field>
            <field>
              <name>FB27</name>
              <bitOffset>27</bitOffset>
              <bitWidth>1</bitWidth>
            </field>
            <field>
              <name>FB28</name>
              <bitOffset>28</bitOffset>
              <bitWidth>1</bitWidth>
            </field>
            <field>
              <name>FB29</name>
              <bitOffset>29</bitOffset>
              <bitWidth>1</bitWidth>
            </field>
            <field>
              <name>FB30</name>
              <bitOffset>30</bitOffset>
              <bitWidth>1</bitWidth>
            </field>
            <field>
              <name>FB31</name>
              <bitOffset>31</bitOffset>
              <bitWidth>1</bitWidth>
            </field>
          </fields>
        </register>
        <register>
          <name>sFilterRegister.7.FR2</name>
          <addressOffset>0x27c</addressOffset>
          <size>0x20</size>
          <fields>
            <field>
              <name>FB0</name>
              <bitOffset>0</bitOffset>
              <bitWidth>1</bitWidth>
            </field>
            <field>
              <name>FB1</name>
              <bitOffset>1</bitOffset>
              <bitWidth>1</bitWidth>
            </field>
            <field>
              <name>FB2</name>
              <bitOffset>2</bitOffset>
              <bitWidth>1</bitWidth>
            </field>
            <field>
              <name>FB3</name>
              <bitOffset>3</bitOffset>
              <bitWidth>1</bitWidth>
            </field>
            <field>
              <name>FB4</name>
              <bitOffset>4</bitOffset>
              <bitWidth>1</bitWidth>
            </field>
            <field>
              <name>FB5</name>
              <bitOffset>5</bitOffset>
              <bitWidth>1</bitWidth>
            </field>
            <field>
              <name>FB6</name>
              <bitOffset>6</bitOffset>
              <bitWidth>1</bitWidth>
            </field>
            <field>
              <name>FB7</name>
              <bitOffset>7</bitOffset>
              <bitWidth>1</bitWidth>
            </field>
            <field>
              <name>FB8</name>
              <bitOffset>8</bitOffset>
              <bitWidth>1</bitWidth>
            </field>
            <field>
              <name>FB9</name>
              <bitOffset>9</bitOffset>
              <bitWidth>1</bitWidth>
            </field>
            <field>
              <name>FB10</name>
              <bitOffset>10</bitOffset>
              <bitWidth>1</bitWidth>
            </field>
            <field>
              <name>FB11</name>
              <bitOffset>11</bitOffset>
              <bitWidth>1</bitWidth>
            </field>
            <field>
              <name>FB12</name>
              <bitOffset>12</bitOffset>
              <bitWidth>1</bitWidth>
            </field>
            <field>
              <name>FB13</name>
              <bitOffset>13</bitOffset>
              <bitWidth>1</bitWidth>
            </field>
            <field>
              <name>FB14</name>
              <bitOffset>14</bitOffset>
              <bitWidth>1</bitWidth>
            </field>
            <field>
              <name>FB15</name>
              <bitOffset>15</bitOffset>
              <bitWidth>1</bitWidth>
            </field>
            <field>
              <name>FB16</name>
              <bitOffset>16</bitOffset>
              <bitWidth>1</bitWidth>
            </field>
            <field>
              <name>FB17</name>
              <bitOffset>17</bitOffset>
              <bitWidth>1</bitWidth>
            </field>
            <field>
              <name>FB18</name>
              <bitOffset>18</bitOffset>
              <bitWidth>1</bitWidth>
            </field>
            <field>
              <name>FB19</name>
              <bitOffset>19</bitOffset>
              <bitWidth>1</bitWidth>
            </field>
            <field>
              <name>FB20</name>
              <bitOffset>20</bitOffset>
              <bitWidth>1</bitWidth>
            </field>
            <field>
              <name>FB21</name>
              <bitOffset>21</bitOffset>
              <bitWidth>1</bitWidth>
            </field>
            <field>
              <name>FB22</name>
              <bitOffset>22</bitOffset>
              <bitWidth>1</bitWidth>
            </field>
            <field>
              <name>FB23</name>
              <bitOffset>23</bitOffset>
              <bitWidth>1</bitWidth>
            </field>
            <field>
              <name>FB24</name>
              <bitOffset>24</bitOffset>
              <bitWidth>1</bitWidth>
            </field>
            <field>
              <name>FB25</name>
              <bitOffset>25</bitOffset>
              <bitWidth>1</bitWidth>
            </field>
            <field>
              <name>FB26</name>
              <bitOffset>26</bitOffset>
              <bitWidth>1</bitWidth>
            </field>
            <field>
              <name>FB27</name>
              <bitOffset>27</bitOffset>
              <bitWidth>1</bitWidth>
            </field>
            <field>
              <name>FB28</name>
              <bitOffset>28</bitOffset>
              <bitWidth>1</bitWidth>
            </field>
            <field>
              <name>FB29</name>
              <bitOffset>29</bitOffset>
              <bitWidth>1</bitWidth>
            </field>
            <field>
              <name>FB30</name>
              <bitOffset>30</bitOffset>
              <bitWidth>1</bitWidth>
            </field>
            <field>
              <name>FB31</name>
              <bitOffset>31</bitOffset>
              <bitWidth>1</bitWidth>
            </field>
          </fields>
        </register>
        <register>
          <name>sFilterRegister.8.FR1</name>
          <addressOffset>0x280</addressOffset>
          <size>0x20</size>
          <fields>
            <field>
              <name>FB0</name>
              <bitOffset>0</bitOffset>
              <bitWidth>1</bitWidth>
            </field>
            <field>
              <name>FB1</name>
              <bitOffset>1</bitOffset>
              <bitWidth>1</bitWidth>
            </field>
            <field>
              <name>FB2</name>
              <bitOffset>2</bitOffset>
              <bitWidth>1</bitWidth>
            </field>
            <field>
              <name>FB3</name>
              <bitOffset>3</bitOffset>
              <bitWidth>1</bitWidth>
            </field>
            <field>
              <name>FB4</name>
              <bitOffset>4</bitOffset>
              <bitWidth>1</bitWidth>
            </field>
            <field>
              <name>FB5</name>
              <bitOffset>5</bitOffset>
              <bitWidth>1</bitWidth>
            </field>
            <field>
              <name>FB6</name>
              <bitOffset>6</bitOffset>
              <bitWidth>1</bitWidth>
            </field>
            <field>
              <name>FB7</name>
              <bitOffset>7</bitOffset>
              <bitWidth>1</bitWidth>
            </field>
            <field>
              <name>FB8</name>
              <bitOffset>8</bitOffset>
              <bitWidth>1</bitWidth>
            </field>
            <field>
              <name>FB9</name>
              <bitOffset>9</bitOffset>
              <bitWidth>1</bitWidth>
            </field>
            <field>
              <name>FB10</name>
              <bitOffset>10</bitOffset>
              <bitWidth>1</bitWidth>
            </field>
            <field>
              <name>FB11</name>
              <bitOffset>11</bitOffset>
              <bitWidth>1</bitWidth>
            </field>
            <field>
              <name>FB12</name>
              <bitOffset>12</bitOffset>
              <bitWidth>1</bitWidth>
            </field>
            <field>
              <name>FB13</name>
              <bitOffset>13</bitOffset>
              <bitWidth>1</bitWidth>
            </field>
            <field>
              <name>FB14</name>
              <bitOffset>14</bitOffset>
              <bitWidth>1</bitWidth>
            </field>
            <field>
              <name>FB15</name>
              <bitOffset>15</bitOffset>
              <bitWidth>1</bitWidth>
            </field>
            <field>
              <name>FB16</name>
              <bitOffset>16</bitOffset>
              <bitWidth>1</bitWidth>
            </field>
            <field>
              <name>FB17</name>
              <bitOffset>17</bitOffset>
              <bitWidth>1</bitWidth>
            </field>
            <field>
              <name>FB18</name>
              <bitOffset>18</bitOffset>
              <bitWidth>1</bitWidth>
            </field>
            <field>
              <name>FB19</name>
              <bitOffset>19</bitOffset>
              <bitWidth>1</bitWidth>
            </field>
            <field>
              <name>FB20</name>
              <bitOffset>20</bitOffset>
              <bitWidth>1</bitWidth>
            </field>
            <field>
              <name>FB21</name>
              <bitOffset>21</bitOffset>
              <bitWidth>1</bitWidth>
            </field>
            <field>
              <name>FB22</name>
              <bitOffset>22</bitOffset>
              <bitWidth>1</bitWidth>
            </field>
            <field>
              <name>FB23</name>
              <bitOffset>23</bitOffset>
              <bitWidth>1</bitWidth>
            </field>
            <field>
              <name>FB24</name>
              <bitOffset>24</bitOffset>
              <bitWidth>1</bitWidth>
            </field>
            <field>
              <name>FB25</name>
              <bitOffset>25</bitOffset>
              <bitWidth>1</bitWidth>
            </field>
            <field>
              <name>FB26</name>
              <bitOffset>26</bitOffset>
              <bitWidth>1</bitWidth>
            </field>
            <field>
              <name>FB27</name>
              <bitOffset>27</bitOffset>
              <bitWidth>1</bitWidth>
            </field>
            <field>
              <name>FB28</name>
              <bitOffset>28</bitOffset>
              <bitWidth>1</bitWidth>
            </field>
            <field>
              <name>FB29</name>
              <bitOffset>29</bitOffset>
              <bitWidth>1</bitWidth>
            </field>
            <field>
              <name>FB30</name>
              <bitOffset>30</bitOffset>
              <bitWidth>1</bitWidth>
            </field>
            <field>
              <name>FB31</name>
              <bitOffset>31</bitOffset>
              <bitWidth>1</bitWidth>
            </field>
          </fields>
        </register>
        <register>
          <name>sFilterRegister.8.FR2</name>
          <addressOffset>0x284</addressOffset>
          <size>0x20</size>
          <fields>
            <field>
              <name>FB0</name>
              <bitOffset>0</bitOffset>
              <bitWidth>1</bitWidth>
            </field>
            <field>
              <name>FB1</name>
              <bitOffset>1</bitOffset>
              <bitWidth>1</bitWidth>
            </field>
            <field>
              <name>FB2</name>
              <bitOffset>2</bitOffset>
              <bitWidth>1</bitWidth>
            </field>
            <field>
              <name>FB3</name>
              <bitOffset>3</bitOffset>
              <bitWidth>1</bitWidth>
            </field>
            <field>
              <name>FB4</name>
              <bitOffset>4</bitOffset>
              <bitWidth>1</bitWidth>
            </field>
            <field>
              <name>FB5</name>
              <bitOffset>5</bitOffset>
              <bitWidth>1</bitWidth>
            </field>
            <field>
              <name>FB6</name>
              <bitOffset>6</bitOffset>
              <bitWidth>1</bitWidth>
            </field>
            <field>
              <name>FB7</name>
              <bitOffset>7</bitOffset>
              <bitWidth>1</bitWidth>
            </field>
            <field>
              <name>FB8</name>
              <bitOffset>8</bitOffset>
              <bitWidth>1</bitWidth>
            </field>
            <field>
              <name>FB9</name>
              <bitOffset>9</bitOffset>
              <bitWidth>1</bitWidth>
            </field>
            <field>
              <name>FB10</name>
              <bitOffset>10</bitOffset>
              <bitWidth>1</bitWidth>
            </field>
            <field>
              <name>FB11</name>
              <bitOffset>11</bitOffset>
              <bitWidth>1</bitWidth>
            </field>
            <field>
              <name>FB12</name>
              <bitOffset>12</bitOffset>
              <bitWidth>1</bitWidth>
            </field>
            <field>
              <name>FB13</name>
              <bitOffset>13</bitOffset>
              <bitWidth>1</bitWidth>
            </field>
            <field>
              <name>FB14</name>
              <bitOffset>14</bitOffset>
              <bitWidth>1</bitWidth>
            </field>
            <field>
              <name>FB15</name>
              <bitOffset>15</bitOffset>
              <bitWidth>1</bitWidth>
            </field>
            <field>
              <name>FB16</name>
              <bitOffset>16</bitOffset>
              <bitWidth>1</bitWidth>
            </field>
            <field>
              <name>FB17</name>
              <bitOffset>17</bitOffset>
              <bitWidth>1</bitWidth>
            </field>
            <field>
              <name>FB18</name>
              <bitOffset>18</bitOffset>
              <bitWidth>1</bitWidth>
            </field>
            <field>
              <name>FB19</name>
              <bitOffset>19</bitOffset>
              <bitWidth>1</bitWidth>
            </field>
            <field>
              <name>FB20</name>
              <bitOffset>20</bitOffset>
              <bitWidth>1</bitWidth>
            </field>
            <field>
              <name>FB21</name>
              <bitOffset>21</bitOffset>
              <bitWidth>1</bitWidth>
            </field>
            <field>
              <name>FB22</name>
              <bitOffset>22</bitOffset>
              <bitWidth>1</bitWidth>
            </field>
            <field>
              <name>FB23</name>
              <bitOffset>23</bitOffset>
              <bitWidth>1</bitWidth>
            </field>
            <field>
              <name>FB24</name>
              <bitOffset>24</bitOffset>
              <bitWidth>1</bitWidth>
            </field>
            <field>
              <name>FB25</name>
              <bitOffset>25</bitOffset>
              <bitWidth>1</bitWidth>
            </field>
            <field>
              <name>FB26</name>
              <bitOffset>26</bitOffset>
              <bitWidth>1</bitWidth>
            </field>
            <field>
              <name>FB27</name>
              <bitOffset>27</bitOffset>
              <bitWidth>1</bitWidth>
            </field>
            <field>
              <name>FB28</name>
              <bitOffset>28</bitOffset>
              <bitWidth>1</bitWidth>
            </field>
            <field>
              <name>FB29</name>
              <bitOffset>29</bitOffset>
              <bitWidth>1</bitWidth>
            </field>
            <field>
              <name>FB30</name>
              <bitOffset>30</bitOffset>
              <bitWidth>1</bitWidth>
            </field>
            <field>
              <name>FB31</name>
              <bitOffset>31</bitOffset>
              <bitWidth>1</bitWidth>
            </field>
          </fields>
        </register>
        <register>
          <name>sFilterRegister.9.FR1</name>
          <addressOffset>0x288</addressOffset>
          <size>0x20</size>
          <fields>
            <field>
              <name>FB0</name>
              <bitOffset>0</bitOffset>
              <bitWidth>1</bitWidth>
            </field>
            <field>
              <name>FB1</name>
              <bitOffset>1</bitOffset>
              <bitWidth>1</bitWidth>
            </field>
            <field>
              <name>FB2</name>
              <bitOffset>2</bitOffset>
              <bitWidth>1</bitWidth>
            </field>
            <field>
              <name>FB3</name>
              <bitOffset>3</bitOffset>
              <bitWidth>1</bitWidth>
            </field>
            <field>
              <name>FB4</name>
              <bitOffset>4</bitOffset>
              <bitWidth>1</bitWidth>
            </field>
            <field>
              <name>FB5</name>
              <bitOffset>5</bitOffset>
              <bitWidth>1</bitWidth>
            </field>
            <field>
              <name>FB6</name>
              <bitOffset>6</bitOffset>
              <bitWidth>1</bitWidth>
            </field>
            <field>
              <name>FB7</name>
              <bitOffset>7</bitOffset>
              <bitWidth>1</bitWidth>
            </field>
            <field>
              <name>FB8</name>
              <bitOffset>8</bitOffset>
              <bitWidth>1</bitWidth>
            </field>
            <field>
              <name>FB9</name>
              <bitOffset>9</bitOffset>
              <bitWidth>1</bitWidth>
            </field>
            <field>
              <name>FB10</name>
              <bitOffset>10</bitOffset>
              <bitWidth>1</bitWidth>
            </field>
            <field>
              <name>FB11</name>
              <bitOffset>11</bitOffset>
              <bitWidth>1</bitWidth>
            </field>
            <field>
              <name>FB12</name>
              <bitOffset>12</bitOffset>
              <bitWidth>1</bitWidth>
            </field>
            <field>
              <name>FB13</name>
              <bitOffset>13</bitOffset>
              <bitWidth>1</bitWidth>
            </field>
            <field>
              <name>FB14</name>
              <bitOffset>14</bitOffset>
              <bitWidth>1</bitWidth>
            </field>
            <field>
              <name>FB15</name>
              <bitOffset>15</bitOffset>
              <bitWidth>1</bitWidth>
            </field>
            <field>
              <name>FB16</name>
              <bitOffset>16</bitOffset>
              <bitWidth>1</bitWidth>
            </field>
            <field>
              <name>FB17</name>
              <bitOffset>17</bitOffset>
              <bitWidth>1</bitWidth>
            </field>
            <field>
              <name>FB18</name>
              <bitOffset>18</bitOffset>
              <bitWidth>1</bitWidth>
            </field>
            <field>
              <name>FB19</name>
              <bitOffset>19</bitOffset>
              <bitWidth>1</bitWidth>
            </field>
            <field>
              <name>FB20</name>
              <bitOffset>20</bitOffset>
              <bitWidth>1</bitWidth>
            </field>
            <field>
              <name>FB21</name>
              <bitOffset>21</bitOffset>
              <bitWidth>1</bitWidth>
            </field>
            <field>
              <name>FB22</name>
              <bitOffset>22</bitOffset>
              <bitWidth>1</bitWidth>
            </field>
            <field>
              <name>FB23</name>
              <bitOffset>23</bitOffset>
              <bitWidth>1</bitWidth>
            </field>
            <field>
              <name>FB24</name>
              <bitOffset>24</bitOffset>
              <bitWidth>1</bitWidth>
            </field>
            <field>
              <name>FB25</name>
              <bitOffset>25</bitOffset>
              <bitWidth>1</bitWidth>
            </field>
            <field>
              <name>FB26</name>
              <bitOffset>26</bitOffset>
              <bitWidth>1</bitWidth>
            </field>
            <field>
              <name>FB27</name>
              <bitOffset>27</bitOffset>
              <bitWidth>1</bitWidth>
            </field>
            <field>
              <name>FB28</name>
              <bitOffset>28</bitOffset>
              <bitWidth>1</bitWidth>
            </field>
            <field>
              <name>FB29</name>
              <bitOffset>29</bitOffset>
              <bitWidth>1</bitWidth>
            </field>
            <field>
              <name>FB30</name>
              <bitOffset>30</bitOffset>
              <bitWidth>1</bitWidth>
            </field>
            <field>
              <name>FB31</name>
              <bitOffset>31</bitOffset>
              <bitWidth>1</bitWidth>
            </field>
          </fields>
        </register>
        <register>
          <name>sFilterRegister.9.FR2</name>
          <addressOffset>0x28c</addressOffset>
          <size>0x20</size>
          <fields>
            <field>
              <name>FB0</name>
              <bitOffset>0</bitOffset>
              <bitWidth>1</bitWidth>
            </field>
            <field>
              <name>FB1</name>
              <bitOffset>1</bitOffset>
              <bitWidth>1</bitWidth>
            </field>
            <field>
              <name>FB2</name>
              <bitOffset>2</bitOffset>
              <bitWidth>1</bitWidth>
            </field>
            <field>
              <name>FB3</name>
              <bitOffset>3</bitOffset>
              <bitWidth>1</bitWidth>
            </field>
            <field>
              <name>FB4</name>
              <bitOffset>4</bitOffset>
              <bitWidth>1</bitWidth>
            </field>
            <field>
              <name>FB5</name>
              <bitOffset>5</bitOffset>
              <bitWidth>1</bitWidth>
            </field>
            <field>
              <name>FB6</name>
              <bitOffset>6</bitOffset>
              <bitWidth>1</bitWidth>
            </field>
            <field>
              <name>FB7</name>
              <bitOffset>7</bitOffset>
              <bitWidth>1</bitWidth>
            </field>
            <field>
              <name>FB8</name>
              <bitOffset>8</bitOffset>
              <bitWidth>1</bitWidth>
            </field>
            <field>
              <name>FB9</name>
              <bitOffset>9</bitOffset>
              <bitWidth>1</bitWidth>
            </field>
            <field>
              <name>FB10</name>
              <bitOffset>10</bitOffset>
              <bitWidth>1</bitWidth>
            </field>
            <field>
              <name>FB11</name>
              <bitOffset>11</bitOffset>
              <bitWidth>1</bitWidth>
            </field>
            <field>
              <name>FB12</name>
              <bitOffset>12</bitOffset>
              <bitWidth>1</bitWidth>
            </field>
            <field>
              <name>FB13</name>
              <bitOffset>13</bitOffset>
              <bitWidth>1</bitWidth>
            </field>
            <field>
              <name>FB14</name>
              <bitOffset>14</bitOffset>
              <bitWidth>1</bitWidth>
            </field>
            <field>
              <name>FB15</name>
              <bitOffset>15</bitOffset>
              <bitWidth>1</bitWidth>
            </field>
            <field>
              <name>FB16</name>
              <bitOffset>16</bitOffset>
              <bitWidth>1</bitWidth>
            </field>
            <field>
              <name>FB17</name>
              <bitOffset>17</bitOffset>
              <bitWidth>1</bitWidth>
            </field>
            <field>
              <name>FB18</name>
              <bitOffset>18</bitOffset>
              <bitWidth>1</bitWidth>
            </field>
            <field>
              <name>FB19</name>
              <bitOffset>19</bitOffset>
              <bitWidth>1</bitWidth>
            </field>
            <field>
              <name>FB20</name>
              <bitOffset>20</bitOffset>
              <bitWidth>1</bitWidth>
            </field>
            <field>
              <name>FB21</name>
              <bitOffset>21</bitOffset>
              <bitWidth>1</bitWidth>
            </field>
            <field>
              <name>FB22</name>
              <bitOffset>22</bitOffset>
              <bitWidth>1</bitWidth>
            </field>
            <field>
              <name>FB23</name>
              <bitOffset>23</bitOffset>
              <bitWidth>1</bitWidth>
            </field>
            <field>
              <name>FB24</name>
              <bitOffset>24</bitOffset>
              <bitWidth>1</bitWidth>
            </field>
            <field>
              <name>FB25</name>
              <bitOffset>25</bitOffset>
              <bitWidth>1</bitWidth>
            </field>
            <field>
              <name>FB26</name>
              <bitOffset>26</bitOffset>
              <bitWidth>1</bitWidth>
            </field>
            <field>
              <name>FB27</name>
              <bitOffset>27</bitOffset>
              <bitWidth>1</bitWidth>
            </field>
            <field>
              <name>FB28</name>
              <bitOffset>28</bitOffset>
              <bitWidth>1</bitWidth>
            </field>
            <field>
              <name>FB29</name>
              <bitOffset>29</bitOffset>
              <bitWidth>1</bitWidth>
            </field>
            <field>
              <name>FB30</name>
              <bitOffset>30</bitOffset>
              <bitWidth>1</bitWidth>
            </field>
            <field>
              <name>FB31</name>
              <bitOffset>31</bitOffset>
              <bitWidth>1</bitWidth>
            </field>
          </fields>
        </register>
        <register>
          <name>sFilterRegister.10.FR1</name>
          <addressOffset>0x290</addressOffset>
          <size>0x20</size>
          <fields>
            <field>
              <name>FB0</name>
              <bitOffset>0</bitOffset>
              <bitWidth>1</bitWidth>
            </field>
            <field>
              <name>FB1</name>
              <bitOffset>1</bitOffset>
              <bitWidth>1</bitWidth>
            </field>
            <field>
              <name>FB2</name>
              <bitOffset>2</bitOffset>
              <bitWidth>1</bitWidth>
            </field>
            <field>
              <name>FB3</name>
              <bitOffset>3</bitOffset>
              <bitWidth>1</bitWidth>
            </field>
            <field>
              <name>FB4</name>
              <bitOffset>4</bitOffset>
              <bitWidth>1</bitWidth>
            </field>
            <field>
              <name>FB5</name>
              <bitOffset>5</bitOffset>
              <bitWidth>1</bitWidth>
            </field>
            <field>
              <name>FB6</name>
              <bitOffset>6</bitOffset>
              <bitWidth>1</bitWidth>
            </field>
            <field>
              <name>FB7</name>
              <bitOffset>7</bitOffset>
              <bitWidth>1</bitWidth>
            </field>
            <field>
              <name>FB8</name>
              <bitOffset>8</bitOffset>
              <bitWidth>1</bitWidth>
            </field>
            <field>
              <name>FB9</name>
              <bitOffset>9</bitOffset>
              <bitWidth>1</bitWidth>
            </field>
            <field>
              <name>FB10</name>
              <bitOffset>10</bitOffset>
              <bitWidth>1</bitWidth>
            </field>
            <field>
              <name>FB11</name>
              <bitOffset>11</bitOffset>
              <bitWidth>1</bitWidth>
            </field>
            <field>
              <name>FB12</name>
              <bitOffset>12</bitOffset>
              <bitWidth>1</bitWidth>
            </field>
            <field>
              <name>FB13</name>
              <bitOffset>13</bitOffset>
              <bitWidth>1</bitWidth>
            </field>
            <field>
              <name>FB14</name>
              <bitOffset>14</bitOffset>
              <bitWidth>1</bitWidth>
            </field>
            <field>
              <name>FB15</name>
              <bitOffset>15</bitOffset>
              <bitWidth>1</bitWidth>
            </field>
            <field>
              <name>FB16</name>
              <bitOffset>16</bitOffset>
              <bitWidth>1</bitWidth>
            </field>
            <field>
              <name>FB17</name>
              <bitOffset>17</bitOffset>
              <bitWidth>1</bitWidth>
            </field>
            <field>
              <name>FB18</name>
              <bitOffset>18</bitOffset>
              <bitWidth>1</bitWidth>
            </field>
            <field>
              <name>FB19</name>
              <bitOffset>19</bitOffset>
              <bitWidth>1</bitWidth>
            </field>
            <field>
              <name>FB20</name>
              <bitOffset>20</bitOffset>
              <bitWidth>1</bitWidth>
            </field>
            <field>
              <name>FB21</name>
              <bitOffset>21</bitOffset>
              <bitWidth>1</bitWidth>
            </field>
            <field>
              <name>FB22</name>
              <bitOffset>22</bitOffset>
              <bitWidth>1</bitWidth>
            </field>
            <field>
              <name>FB23</name>
              <bitOffset>23</bitOffset>
              <bitWidth>1</bitWidth>
            </field>
            <field>
              <name>FB24</name>
              <bitOffset>24</bitOffset>
              <bitWidth>1</bitWidth>
            </field>
            <field>
              <name>FB25</name>
              <bitOffset>25</bitOffset>
              <bitWidth>1</bitWidth>
            </field>
            <field>
              <name>FB26</name>
              <bitOffset>26</bitOffset>
              <bitWidth>1</bitWidth>
            </field>
            <field>
              <name>FB27</name>
              <bitOffset>27</bitOffset>
              <bitWidth>1</bitWidth>
            </field>
            <field>
              <name>FB28</name>
              <bitOffset>28</bitOffset>
              <bitWidth>1</bitWidth>
            </field>
            <field>
              <name>FB29</name>
              <bitOffset>29</bitOffset>
              <bitWidth>1</bitWidth>
            </field>
            <field>
              <name>FB30</name>
              <bitOffset>30</bitOffset>
              <bitWidth>1</bitWidth>
            </field>
            <field>
              <name>FB31</name>
              <bitOffset>31</bitOffset>
              <bitWidth>1</bitWidth>
            </field>
          </fields>
        </register>
        <register>
          <name>sFilterRegister.10.FR2</name>
          <addressOffset>0x294</addressOffset>
          <size>0x20</size>
          <fields>
            <field>
              <name>FB0</name>
              <bitOffset>0</bitOffset>
              <bitWidth>1</bitWidth>
            </field>
            <field>
              <name>FB1</name>
              <bitOffset>1</bitOffset>
              <bitWidth>1</bitWidth>
            </field>
            <field>
              <name>FB2</name>
              <bitOffset>2</bitOffset>
              <bitWidth>1</bitWidth>
            </field>
            <field>
              <name>FB3</name>
              <bitOffset>3</bitOffset>
              <bitWidth>1</bitWidth>
            </field>
            <field>
              <name>FB4</name>
              <bitOffset>4</bitOffset>
              <bitWidth>1</bitWidth>
            </field>
            <field>
              <name>FB5</name>
              <bitOffset>5</bitOffset>
              <bitWidth>1</bitWidth>
            </field>
            <field>
              <name>FB6</name>
              <bitOffset>6</bitOffset>
              <bitWidth>1</bitWidth>
            </field>
            <field>
              <name>FB7</name>
              <bitOffset>7</bitOffset>
              <bitWidth>1</bitWidth>
            </field>
            <field>
              <name>FB8</name>
              <bitOffset>8</bitOffset>
              <bitWidth>1</bitWidth>
            </field>
            <field>
              <name>FB9</name>
              <bitOffset>9</bitOffset>
              <bitWidth>1</bitWidth>
            </field>
            <field>
              <name>FB10</name>
              <bitOffset>10</bitOffset>
              <bitWidth>1</bitWidth>
            </field>
            <field>
              <name>FB11</name>
              <bitOffset>11</bitOffset>
              <bitWidth>1</bitWidth>
            </field>
            <field>
              <name>FB12</name>
              <bitOffset>12</bitOffset>
              <bitWidth>1</bitWidth>
            </field>
            <field>
              <name>FB13</name>
              <bitOffset>13</bitOffset>
              <bitWidth>1</bitWidth>
            </field>
            <field>
              <name>FB14</name>
              <bitOffset>14</bitOffset>
              <bitWidth>1</bitWidth>
            </field>
            <field>
              <name>FB15</name>
              <bitOffset>15</bitOffset>
              <bitWidth>1</bitWidth>
            </field>
            <field>
              <name>FB16</name>
              <bitOffset>16</bitOffset>
              <bitWidth>1</bitWidth>
            </field>
            <field>
              <name>FB17</name>
              <bitOffset>17</bitOffset>
              <bitWidth>1</bitWidth>
            </field>
            <field>
              <name>FB18</name>
              <bitOffset>18</bitOffset>
              <bitWidth>1</bitWidth>
            </field>
            <field>
              <name>FB19</name>
              <bitOffset>19</bitOffset>
              <bitWidth>1</bitWidth>
            </field>
            <field>
              <name>FB20</name>
              <bitOffset>20</bitOffset>
              <bitWidth>1</bitWidth>
            </field>
            <field>
              <name>FB21</name>
              <bitOffset>21</bitOffset>
              <bitWidth>1</bitWidth>
            </field>
            <field>
              <name>FB22</name>
              <bitOffset>22</bitOffset>
              <bitWidth>1</bitWidth>
            </field>
            <field>
              <name>FB23</name>
              <bitOffset>23</bitOffset>
              <bitWidth>1</bitWidth>
            </field>
            <field>
              <name>FB24</name>
              <bitOffset>24</bitOffset>
              <bitWidth>1</bitWidth>
            </field>
            <field>
              <name>FB25</name>
              <bitOffset>25</bitOffset>
              <bitWidth>1</bitWidth>
            </field>
            <field>
              <name>FB26</name>
              <bitOffset>26</bitOffset>
              <bitWidth>1</bitWidth>
            </field>
            <field>
              <name>FB27</name>
              <bitOffset>27</bitOffset>
              <bitWidth>1</bitWidth>
            </field>
            <field>
              <name>FB28</name>
              <bitOffset>28</bitOffset>
              <bitWidth>1</bitWidth>
            </field>
            <field>
              <name>FB29</name>
              <bitOffset>29</bitOffset>
              <bitWidth>1</bitWidth>
            </field>
            <field>
              <name>FB30</name>
              <bitOffset>30</bitOffset>
              <bitWidth>1</bitWidth>
            </field>
            <field>
              <name>FB31</name>
              <bitOffset>31</bitOffset>
              <bitWidth>1</bitWidth>
            </field>
          </fields>
        </register>
        <register>
          <name>sFilterRegister.11.FR1</name>
          <addressOffset>0x298</addressOffset>
          <size>0x20</size>
          <fields>
            <field>
              <name>FB0</name>
              <bitOffset>0</bitOffset>
              <bitWidth>1</bitWidth>
            </field>
            <field>
              <name>FB1</name>
              <bitOffset>1</bitOffset>
              <bitWidth>1</bitWidth>
            </field>
            <field>
              <name>FB2</name>
              <bitOffset>2</bitOffset>
              <bitWidth>1</bitWidth>
            </field>
            <field>
              <name>FB3</name>
              <bitOffset>3</bitOffset>
              <bitWidth>1</bitWidth>
            </field>
            <field>
              <name>FB4</name>
              <bitOffset>4</bitOffset>
              <bitWidth>1</bitWidth>
            </field>
            <field>
              <name>FB5</name>
              <bitOffset>5</bitOffset>
              <bitWidth>1</bitWidth>
            </field>
            <field>
              <name>FB6</name>
              <bitOffset>6</bitOffset>
              <bitWidth>1</bitWidth>
            </field>
            <field>
              <name>FB7</name>
              <bitOffset>7</bitOffset>
              <bitWidth>1</bitWidth>
            </field>
            <field>
              <name>FB8</name>
              <bitOffset>8</bitOffset>
              <bitWidth>1</bitWidth>
            </field>
            <field>
              <name>FB9</name>
              <bitOffset>9</bitOffset>
              <bitWidth>1</bitWidth>
            </field>
            <field>
              <name>FB10</name>
              <bitOffset>10</bitOffset>
              <bitWidth>1</bitWidth>
            </field>
            <field>
              <name>FB11</name>
              <bitOffset>11</bitOffset>
              <bitWidth>1</bitWidth>
            </field>
            <field>
              <name>FB12</name>
              <bitOffset>12</bitOffset>
              <bitWidth>1</bitWidth>
            </field>
            <field>
              <name>FB13</name>
              <bitOffset>13</bitOffset>
              <bitWidth>1</bitWidth>
            </field>
            <field>
              <name>FB14</name>
              <bitOffset>14</bitOffset>
              <bitWidth>1</bitWidth>
            </field>
            <field>
              <name>FB15</name>
              <bitOffset>15</bitOffset>
              <bitWidth>1</bitWidth>
            </field>
            <field>
              <name>FB16</name>
              <bitOffset>16</bitOffset>
              <bitWidth>1</bitWidth>
            </field>
            <field>
              <name>FB17</name>
              <bitOffset>17</bitOffset>
              <bitWidth>1</bitWidth>
            </field>
            <field>
              <name>FB18</name>
              <bitOffset>18</bitOffset>
              <bitWidth>1</bitWidth>
            </field>
            <field>
              <name>FB19</name>
              <bitOffset>19</bitOffset>
              <bitWidth>1</bitWidth>
            </field>
            <field>
              <name>FB20</name>
              <bitOffset>20</bitOffset>
              <bitWidth>1</bitWidth>
            </field>
            <field>
              <name>FB21</name>
              <bitOffset>21</bitOffset>
              <bitWidth>1</bitWidth>
            </field>
            <field>
              <name>FB22</name>
              <bitOffset>22</bitOffset>
              <bitWidth>1</bitWidth>
            </field>
            <field>
              <name>FB23</name>
              <bitOffset>23</bitOffset>
              <bitWidth>1</bitWidth>
            </field>
            <field>
              <name>FB24</name>
              <bitOffset>24</bitOffset>
              <bitWidth>1</bitWidth>
            </field>
            <field>
              <name>FB25</name>
              <bitOffset>25</bitOffset>
              <bitWidth>1</bitWidth>
            </field>
            <field>
              <name>FB26</name>
              <bitOffset>26</bitOffset>
              <bitWidth>1</bitWidth>
            </field>
            <field>
              <name>FB27</name>
              <bitOffset>27</bitOffset>
              <bitWidth>1</bitWidth>
            </field>
            <field>
              <name>FB28</name>
              <bitOffset>28</bitOffset>
              <bitWidth>1</bitWidth>
            </field>
            <field>
              <name>FB29</name>
              <bitOffset>29</bitOffset>
              <bitWidth>1</bitWidth>
            </field>
            <field>
              <name>FB30</name>
              <bitOffset>30</bitOffset>
              <bitWidth>1</bitWidth>
            </field>
            <field>
              <name>FB31</name>
              <bitOffset>31</bitOffset>
              <bitWidth>1</bitWidth>
            </field>
          </fields>
        </register>
        <register>
          <name>sFilterRegister.11.FR2</name>
          <addressOffset>0x29c</addressOffset>
          <size>0x20</size>
          <fields>
            <field>
              <name>FB0</name>
              <bitOffset>0</bitOffset>
              <bitWidth>1</bitWidth>
            </field>
            <field>
              <name>FB1</name>
              <bitOffset>1</bitOffset>
              <bitWidth>1</bitWidth>
            </field>
            <field>
              <name>FB2</name>
              <bitOffset>2</bitOffset>
              <bitWidth>1</bitWidth>
            </field>
            <field>
              <name>FB3</name>
              <bitOffset>3</bitOffset>
              <bitWidth>1</bitWidth>
            </field>
            <field>
              <name>FB4</name>
              <bitOffset>4</bitOffset>
              <bitWidth>1</bitWidth>
            </field>
            <field>
              <name>FB5</name>
              <bitOffset>5</bitOffset>
              <bitWidth>1</bitWidth>
            </field>
            <field>
              <name>FB6</name>
              <bitOffset>6</bitOffset>
              <bitWidth>1</bitWidth>
            </field>
            <field>
              <name>FB7</name>
              <bitOffset>7</bitOffset>
              <bitWidth>1</bitWidth>
            </field>
            <field>
              <name>FB8</name>
              <bitOffset>8</bitOffset>
              <bitWidth>1</bitWidth>
            </field>
            <field>
              <name>FB9</name>
              <bitOffset>9</bitOffset>
              <bitWidth>1</bitWidth>
            </field>
            <field>
              <name>FB10</name>
              <bitOffset>10</bitOffset>
              <bitWidth>1</bitWidth>
            </field>
            <field>
              <name>FB11</name>
              <bitOffset>11</bitOffset>
              <bitWidth>1</bitWidth>
            </field>
            <field>
              <name>FB12</name>
              <bitOffset>12</bitOffset>
              <bitWidth>1</bitWidth>
            </field>
            <field>
              <name>FB13</name>
              <bitOffset>13</bitOffset>
              <bitWidth>1</bitWidth>
            </field>
            <field>
              <name>FB14</name>
              <bitOffset>14</bitOffset>
              <bitWidth>1</bitWidth>
            </field>
            <field>
              <name>FB15</name>
              <bitOffset>15</bitOffset>
              <bitWidth>1</bitWidth>
            </field>
            <field>
              <name>FB16</name>
              <bitOffset>16</bitOffset>
              <bitWidth>1</bitWidth>
            </field>
            <field>
              <name>FB17</name>
              <bitOffset>17</bitOffset>
              <bitWidth>1</bitWidth>
            </field>
            <field>
              <name>FB18</name>
              <bitOffset>18</bitOffset>
              <bitWidth>1</bitWidth>
            </field>
            <field>
              <name>FB19</name>
              <bitOffset>19</bitOffset>
              <bitWidth>1</bitWidth>
            </field>
            <field>
              <name>FB20</name>
              <bitOffset>20</bitOffset>
              <bitWidth>1</bitWidth>
            </field>
            <field>
              <name>FB21</name>
              <bitOffset>21</bitOffset>
              <bitWidth>1</bitWidth>
            </field>
            <field>
              <name>FB22</name>
              <bitOffset>22</bitOffset>
              <bitWidth>1</bitWidth>
            </field>
            <field>
              <name>FB23</name>
              <bitOffset>23</bitOffset>
              <bitWidth>1</bitWidth>
            </field>
            <field>
              <name>FB24</name>
              <bitOffset>24</bitOffset>
              <bitWidth>1</bitWidth>
            </field>
            <field>
              <name>FB25</name>
              <bitOffset>25</bitOffset>
              <bitWidth>1</bitWidth>
            </field>
            <field>
              <name>FB26</name>
              <bitOffset>26</bitOffset>
              <bitWidth>1</bitWidth>
            </field>
            <field>
              <name>FB27</name>
              <bitOffset>27</bitOffset>
              <bitWidth>1</bitWidth>
            </field>
            <field>
              <name>FB28</name>
              <bitOffset>28</bitOffset>
              <bitWidth>1</bitWidth>
            </field>
            <field>
              <name>FB29</name>
              <bitOffset>29</bitOffset>
              <bitWidth>1</bitWidth>
            </field>
            <field>
              <name>FB30</name>
              <bitOffset>30</bitOffset>
              <bitWidth>1</bitWidth>
            </field>
            <field>
              <name>FB31</name>
              <bitOffset>31</bitOffset>
              <bitWidth>1</bitWidth>
            </field>
          </fields>
        </register>
        <register>
          <name>sFilterRegister.12.FR1</name>
          <addressOffset>0x2a0</addressOffset>
          <size>0x20</size>
          <fields>
            <field>
              <name>FB0</name>
              <bitOffset>0</bitOffset>
              <bitWidth>1</bitWidth>
            </field>
            <field>
              <name>FB1</name>
              <bitOffset>1</bitOffset>
              <bitWidth>1</bitWidth>
            </field>
            <field>
              <name>FB2</name>
              <bitOffset>2</bitOffset>
              <bitWidth>1</bitWidth>
            </field>
            <field>
              <name>FB3</name>
              <bitOffset>3</bitOffset>
              <bitWidth>1</bitWidth>
            </field>
            <field>
              <name>FB4</name>
              <bitOffset>4</bitOffset>
              <bitWidth>1</bitWidth>
            </field>
            <field>
              <name>FB5</name>
              <bitOffset>5</bitOffset>
              <bitWidth>1</bitWidth>
            </field>
            <field>
              <name>FB6</name>
              <bitOffset>6</bitOffset>
              <bitWidth>1</bitWidth>
            </field>
            <field>
              <name>FB7</name>
              <bitOffset>7</bitOffset>
              <bitWidth>1</bitWidth>
            </field>
            <field>
              <name>FB8</name>
              <bitOffset>8</bitOffset>
              <bitWidth>1</bitWidth>
            </field>
            <field>
              <name>FB9</name>
              <bitOffset>9</bitOffset>
              <bitWidth>1</bitWidth>
            </field>
            <field>
              <name>FB10</name>
              <bitOffset>10</bitOffset>
              <bitWidth>1</bitWidth>
            </field>
            <field>
              <name>FB11</name>
              <bitOffset>11</bitOffset>
              <bitWidth>1</bitWidth>
            </field>
            <field>
              <name>FB12</name>
              <bitOffset>12</bitOffset>
              <bitWidth>1</bitWidth>
            </field>
            <field>
              <name>FB13</name>
              <bitOffset>13</bitOffset>
              <bitWidth>1</bitWidth>
            </field>
            <field>
              <name>FB14</name>
              <bitOffset>14</bitOffset>
              <bitWidth>1</bitWidth>
            </field>
            <field>
              <name>FB15</name>
              <bitOffset>15</bitOffset>
              <bitWidth>1</bitWidth>
            </field>
            <field>
              <name>FB16</name>
              <bitOffset>16</bitOffset>
              <bitWidth>1</bitWidth>
            </field>
            <field>
              <name>FB17</name>
              <bitOffset>17</bitOffset>
              <bitWidth>1</bitWidth>
            </field>
            <field>
              <name>FB18</name>
              <bitOffset>18</bitOffset>
              <bitWidth>1</bitWidth>
            </field>
            <field>
              <name>FB19</name>
              <bitOffset>19</bitOffset>
              <bitWidth>1</bitWidth>
            </field>
            <field>
              <name>FB20</name>
              <bitOffset>20</bitOffset>
              <bitWidth>1</bitWidth>
            </field>
            <field>
              <name>FB21</name>
              <bitOffset>21</bitOffset>
              <bitWidth>1</bitWidth>
            </field>
            <field>
              <name>FB22</name>
              <bitOffset>22</bitOffset>
              <bitWidth>1</bitWidth>
            </field>
            <field>
              <name>FB23</name>
              <bitOffset>23</bitOffset>
              <bitWidth>1</bitWidth>
            </field>
            <field>
              <name>FB24</name>
              <bitOffset>24</bitOffset>
              <bitWidth>1</bitWidth>
            </field>
            <field>
              <name>FB25</name>
              <bitOffset>25</bitOffset>
              <bitWidth>1</bitWidth>
            </field>
            <field>
              <name>FB26</name>
              <bitOffset>26</bitOffset>
              <bitWidth>1</bitWidth>
            </field>
            <field>
              <name>FB27</name>
              <bitOffset>27</bitOffset>
              <bitWidth>1</bitWidth>
            </field>
            <field>
              <name>FB28</name>
              <bitOffset>28</bitOffset>
              <bitWidth>1</bitWidth>
            </field>
            <field>
              <name>FB29</name>
              <bitOffset>29</bitOffset>
              <bitWidth>1</bitWidth>
            </field>
            <field>
              <name>FB30</name>
              <bitOffset>30</bitOffset>
              <bitWidth>1</bitWidth>
            </field>
            <field>
              <name>FB31</name>
              <bitOffset>31</bitOffset>
              <bitWidth>1</bitWidth>
            </field>
          </fields>
        </register>
        <register>
          <name>sFilterRegister.12.FR2</name>
          <addressOffset>0x2a4</addressOffset>
          <size>0x20</size>
          <fields>
            <field>
              <name>FB0</name>
              <bitOffset>0</bitOffset>
              <bitWidth>1</bitWidth>
            </field>
            <field>
              <name>FB1</name>
              <bitOffset>1</bitOffset>
              <bitWidth>1</bitWidth>
            </field>
            <field>
              <name>FB2</name>
              <bitOffset>2</bitOffset>
              <bitWidth>1</bitWidth>
            </field>
            <field>
              <name>FB3</name>
              <bitOffset>3</bitOffset>
              <bitWidth>1</bitWidth>
            </field>
            <field>
              <name>FB4</name>
              <bitOffset>4</bitOffset>
              <bitWidth>1</bitWidth>
            </field>
            <field>
              <name>FB5</name>
              <bitOffset>5</bitOffset>
              <bitWidth>1</bitWidth>
            </field>
            <field>
              <name>FB6</name>
              <bitOffset>6</bitOffset>
              <bitWidth>1</bitWidth>
            </field>
            <field>
              <name>FB7</name>
              <bitOffset>7</bitOffset>
              <bitWidth>1</bitWidth>
            </field>
            <field>
              <name>FB8</name>
              <bitOffset>8</bitOffset>
              <bitWidth>1</bitWidth>
            </field>
            <field>
              <name>FB9</name>
              <bitOffset>9</bitOffset>
              <bitWidth>1</bitWidth>
            </field>
            <field>
              <name>FB10</name>
              <bitOffset>10</bitOffset>
              <bitWidth>1</bitWidth>
            </field>
            <field>
              <name>FB11</name>
              <bitOffset>11</bitOffset>
              <bitWidth>1</bitWidth>
            </field>
            <field>
              <name>FB12</name>
              <bitOffset>12</bitOffset>
              <bitWidth>1</bitWidth>
            </field>
            <field>
              <name>FB13</name>
              <bitOffset>13</bitOffset>
              <bitWidth>1</bitWidth>
            </field>
            <field>
              <name>FB14</name>
              <bitOffset>14</bitOffset>
              <bitWidth>1</bitWidth>
            </field>
            <field>
              <name>FB15</name>
              <bitOffset>15</bitOffset>
              <bitWidth>1</bitWidth>
            </field>
            <field>
              <name>FB16</name>
              <bitOffset>16</bitOffset>
              <bitWidth>1</bitWidth>
            </field>
            <field>
              <name>FB17</name>
              <bitOffset>17</bitOffset>
              <bitWidth>1</bitWidth>
            </field>
            <field>
              <name>FB18</name>
              <bitOffset>18</bitOffset>
              <bitWidth>1</bitWidth>
            </field>
            <field>
              <name>FB19</name>
              <bitOffset>19</bitOffset>
              <bitWidth>1</bitWidth>
            </field>
            <field>
              <name>FB20</name>
              <bitOffset>20</bitOffset>
              <bitWidth>1</bitWidth>
            </field>
            <field>
              <name>FB21</name>
              <bitOffset>21</bitOffset>
              <bitWidth>1</bitWidth>
            </field>
            <field>
              <name>FB22</name>
              <bitOffset>22</bitOffset>
              <bitWidth>1</bitWidth>
            </field>
            <field>
              <name>FB23</name>
              <bitOffset>23</bitOffset>
              <bitWidth>1</bitWidth>
            </field>
            <field>
              <name>FB24</name>
              <bitOffset>24</bitOffset>
              <bitWidth>1</bitWidth>
            </field>
            <field>
              <name>FB25</name>
              <bitOffset>25</bitOffset>
              <bitWidth>1</bitWidth>
            </field>
            <field>
              <name>FB26</name>
              <bitOffset>26</bitOffset>
              <bitWidth>1</bitWidth>
            </field>
            <field>
              <name>FB27</name>
              <bitOffset>27</bitOffset>
              <bitWidth>1</bitWidth>
            </field>
            <field>
              <name>FB28</name>
              <bitOffset>28</bitOffset>
              <bitWidth>1</bitWidth>
            </field>
            <field>
              <name>FB29</name>
              <bitOffset>29</bitOffset>
              <bitWidth>1</bitWidth>
            </field>
            <field>
              <name>FB30</name>
              <bitOffset>30</bitOffset>
              <bitWidth>1</bitWidth>
            </field>
            <field>
              <name>FB31</name>
              <bitOffset>31</bitOffset>
              <bitWidth>1</bitWidth>
            </field>
          </fields>
        </register>
        <register>
          <name>sFilterRegister.13.FR1</name>
          <addressOffset>0x2a8</addressOffset>
          <size>0x20</size>
          <fields>
            <field>
              <name>FB0</name>
              <bitOffset>0</bitOffset>
              <bitWidth>1</bitWidth>
            </field>
            <field>
              <name>FB1</name>
              <bitOffset>1</bitOffset>
              <bitWidth>1</bitWidth>
            </field>
            <field>
              <name>FB2</name>
              <bitOffset>2</bitOffset>
              <bitWidth>1</bitWidth>
            </field>
            <field>
              <name>FB3</name>
              <bitOffset>3</bitOffset>
              <bitWidth>1</bitWidth>
            </field>
            <field>
              <name>FB4</name>
              <bitOffset>4</bitOffset>
              <bitWidth>1</bitWidth>
            </field>
            <field>
              <name>FB5</name>
              <bitOffset>5</bitOffset>
              <bitWidth>1</bitWidth>
            </field>
            <field>
              <name>FB6</name>
              <bitOffset>6</bitOffset>
              <bitWidth>1</bitWidth>
            </field>
            <field>
              <name>FB7</name>
              <bitOffset>7</bitOffset>
              <bitWidth>1</bitWidth>
            </field>
            <field>
              <name>FB8</name>
              <bitOffset>8</bitOffset>
              <bitWidth>1</bitWidth>
            </field>
            <field>
              <name>FB9</name>
              <bitOffset>9</bitOffset>
              <bitWidth>1</bitWidth>
            </field>
            <field>
              <name>FB10</name>
              <bitOffset>10</bitOffset>
              <bitWidth>1</bitWidth>
            </field>
            <field>
              <name>FB11</name>
              <bitOffset>11</bitOffset>
              <bitWidth>1</bitWidth>
            </field>
            <field>
              <name>FB12</name>
              <bitOffset>12</bitOffset>
              <bitWidth>1</bitWidth>
            </field>
            <field>
              <name>FB13</name>
              <bitOffset>13</bitOffset>
              <bitWidth>1</bitWidth>
            </field>
            <field>
              <name>FB14</name>
              <bitOffset>14</bitOffset>
              <bitWidth>1</bitWidth>
            </field>
            <field>
              <name>FB15</name>
              <bitOffset>15</bitOffset>
              <bitWidth>1</bitWidth>
            </field>
            <field>
              <name>FB16</name>
              <bitOffset>16</bitOffset>
              <bitWidth>1</bitWidth>
            </field>
            <field>
              <name>FB17</name>
              <bitOffset>17</bitOffset>
              <bitWidth>1</bitWidth>
            </field>
            <field>
              <name>FB18</name>
              <bitOffset>18</bitOffset>
              <bitWidth>1</bitWidth>
            </field>
            <field>
              <name>FB19</name>
              <bitOffset>19</bitOffset>
              <bitWidth>1</bitWidth>
            </field>
            <field>
              <name>FB20</name>
              <bitOffset>20</bitOffset>
              <bitWidth>1</bitWidth>
            </field>
            <field>
              <name>FB21</name>
              <bitOffset>21</bitOffset>
              <bitWidth>1</bitWidth>
            </field>
            <field>
              <name>FB22</name>
              <bitOffset>22</bitOffset>
              <bitWidth>1</bitWidth>
            </field>
            <field>
              <name>FB23</name>
              <bitOffset>23</bitOffset>
              <bitWidth>1</bitWidth>
            </field>
            <field>
              <name>FB24</name>
              <bitOffset>24</bitOffset>
              <bitWidth>1</bitWidth>
            </field>
            <field>
              <name>FB25</name>
              <bitOffset>25</bitOffset>
              <bitWidth>1</bitWidth>
            </field>
            <field>
              <name>FB26</name>
              <bitOffset>26</bitOffset>
              <bitWidth>1</bitWidth>
            </field>
            <field>
              <name>FB27</name>
              <bitOffset>27</bitOffset>
              <bitWidth>1</bitWidth>
            </field>
            <field>
              <name>FB28</name>
              <bitOffset>28</bitOffset>
              <bitWidth>1</bitWidth>
            </field>
            <field>
              <name>FB29</name>
              <bitOffset>29</bitOffset>
              <bitWidth>1</bitWidth>
            </field>
            <field>
              <name>FB30</name>
              <bitOffset>30</bitOffset>
              <bitWidth>1</bitWidth>
            </field>
            <field>
              <name>FB31</name>
              <bitOffset>31</bitOffset>
              <bitWidth>1</bitWidth>
            </field>
          </fields>
        </register>
        <register>
          <name>sFilterRegister.13.FR2</name>
          <addressOffset>0x2ac</addressOffset>
          <size>0x20</size>
          <fields>
            <field>
              <name>FB0</name>
              <bitOffset>0</bitOffset>
              <bitWidth>1</bitWidth>
            </field>
            <field>
              <name>FB1</name>
              <bitOffset>1</bitOffset>
              <bitWidth>1</bitWidth>
            </field>
            <field>
              <name>FB2</name>
              <bitOffset>2</bitOffset>
              <bitWidth>1</bitWidth>
            </field>
            <field>
              <name>FB3</name>
              <bitOffset>3</bitOffset>
              <bitWidth>1</bitWidth>
            </field>
            <field>
              <name>FB4</name>
              <bitOffset>4</bitOffset>
              <bitWidth>1</bitWidth>
            </field>
            <field>
              <name>FB5</name>
              <bitOffset>5</bitOffset>
              <bitWidth>1</bitWidth>
            </field>
            <field>
              <name>FB6</name>
              <bitOffset>6</bitOffset>
              <bitWidth>1</bitWidth>
            </field>
            <field>
              <name>FB7</name>
              <bitOffset>7</bitOffset>
              <bitWidth>1</bitWidth>
            </field>
            <field>
              <name>FB8</name>
              <bitOffset>8</bitOffset>
              <bitWidth>1</bitWidth>
            </field>
            <field>
              <name>FB9</name>
              <bitOffset>9</bitOffset>
              <bitWidth>1</bitWidth>
            </field>
            <field>
              <name>FB10</name>
              <bitOffset>10</bitOffset>
              <bitWidth>1</bitWidth>
            </field>
            <field>
              <name>FB11</name>
              <bitOffset>11</bitOffset>
              <bitWidth>1</bitWidth>
            </field>
            <field>
              <name>FB12</name>
              <bitOffset>12</bitOffset>
              <bitWidth>1</bitWidth>
            </field>
            <field>
              <name>FB13</name>
              <bitOffset>13</bitOffset>
              <bitWidth>1</bitWidth>
            </field>
            <field>
              <name>FB14</name>
              <bitOffset>14</bitOffset>
              <bitWidth>1</bitWidth>
            </field>
            <field>
              <name>FB15</name>
              <bitOffset>15</bitOffset>
              <bitWidth>1</bitWidth>
            </field>
            <field>
              <name>FB16</name>
              <bitOffset>16</bitOffset>
              <bitWidth>1</bitWidth>
            </field>
            <field>
              <name>FB17</name>
              <bitOffset>17</bitOffset>
              <bitWidth>1</bitWidth>
            </field>
            <field>
              <name>FB18</name>
              <bitOffset>18</bitOffset>
              <bitWidth>1</bitWidth>
            </field>
            <field>
              <name>FB19</name>
              <bitOffset>19</bitOffset>
              <bitWidth>1</bitWidth>
            </field>
            <field>
              <name>FB20</name>
              <bitOffset>20</bitOffset>
              <bitWidth>1</bitWidth>
            </field>
            <field>
              <name>FB21</name>
              <bitOffset>21</bitOffset>
              <bitWidth>1</bitWidth>
            </field>
            <field>
              <name>FB22</name>
              <bitOffset>22</bitOffset>
              <bitWidth>1</bitWidth>
            </field>
            <field>
              <name>FB23</name>
              <bitOffset>23</bitOffset>
              <bitWidth>1</bitWidth>
            </field>
            <field>
              <name>FB24</name>
              <bitOffset>24</bitOffset>
              <bitWidth>1</bitWidth>
            </field>
            <field>
              <name>FB25</name>
              <bitOffset>25</bitOffset>
              <bitWidth>1</bitWidth>
            </field>
            <field>
              <name>FB26</name>
              <bitOffset>26</bitOffset>
              <bitWidth>1</bitWidth>
            </field>
            <field>
              <name>FB27</name>
              <bitOffset>27</bitOffset>
              <bitWidth>1</bitWidth>
            </field>
            <field>
              <name>FB28</name>
              <bitOffset>28</bitOffset>
              <bitWidth>1</bitWidth>
            </field>
            <field>
              <name>FB29</name>
              <bitOffset>29</bitOffset>
              <bitWidth>1</bitWidth>
            </field>
            <field>
              <name>FB30</name>
              <bitOffset>30</bitOffset>
              <bitWidth>1</bitWidth>
            </field>
            <field>
              <name>FB31</name>
              <bitOffset>31</bitOffset>
              <bitWidth>1</bitWidth>
            </field>
          </fields>
        </register>
        <register>
          <name>sFilterRegister.14.FR1</name>
          <addressOffset>0x2b0</addressOffset>
          <size>0x20</size>
        </register>
        <register>
          <name>sFilterRegister.14.FR2</name>
          <addressOffset>0x2b4</addressOffset>
          <size>0x20</size>
        </register>
        <register>
          <name>sFilterRegister.15.FR1</name>
          <addressOffset>0x2b8</addressOffset>
          <size>0x20</size>
        </register>
        <register>
          <name>sFilterRegister.15.FR2</name>
          <addressOffset>0x2bc</addressOffset>
          <size>0x20</size>
        </register>
        <register>
          <name>sFilterRegister.16.FR1</name>
          <addressOffset>0x2c0</addressOffset>
          <size>0x20</size>
        </register>
        <register>
          <name>sFilterRegister.16.FR2</name>
          <addressOffset>0x2c4</addressOffset>
          <size>0x20</size>
        </register>
        <register>
          <name>sFilterRegister.17.FR1</name>
          <addressOffset>0x2c8</addressOffset>
          <size>0x20</size>
        </register>
        <register>
          <name>sFilterRegister.17.FR2</name>
          <addressOffset>0x2cc</addressOffset>
          <size>0x20</size>
        </register>
        <register>
          <name>sFilterRegister.18.FR1</name>
          <addressOffset>0x2d0</addressOffset>
          <size>0x20</size>
        </register>
        <register>
          <name>sFilterRegister.18.FR2</name>
          <addressOffset>0x2d4</addressOffset>
          <size>0x20</size>
        </register>
        <register>
          <name>sFilterRegister.19.FR1</name>
          <addressOffset>0x2d8</addressOffset>
          <size>0x20</size>
        </register>
        <register>
          <name>sFilterRegister.19.FR2</name>
          <addressOffset>0x2dc</addressOffset>
          <size>0x20</size>
        </register>
        <register>
          <name>sFilterRegister.20.FR1</name>
          <addressOffset>0x2e0</addressOffset>
          <size>0x20</size>
        </register>
        <register>
          <name>sFilterRegister.20.FR2</name>
          <addressOffset>0x2e4</addressOffset>
          <size>0x20</size>
        </register>
        <register>
          <name>sFilterRegister.21.FR1</name>
          <addressOffset>0x2e8</addressOffset>
          <size>0x20</size>
        </register>
        <register>
          <name>sFilterRegister.21.FR2</name>
          <addressOffset>0x2ec</addressOffset>
          <size>0x20</size>
        </register>
        <register>
          <name>sFilterRegister.22.FR1</name>
          <addressOffset>0x2f0</addressOffset>
          <size>0x20</size>
        </register>
        <register>
          <name>sFilterRegister.22.FR2</name>
          <addressOffset>0x2f4</addressOffset>
          <size>0x20</size>
        </register>
        <register>
          <name>sFilterRegister.23.FR1</name>
          <addressOffset>0x2f8</addressOffset>
          <size>0x20</size>
        </register>
        <register>
          <name>sFilterRegister.23.FR2</name>
          <addressOffset>0x2fc</addressOffset>
          <size>0x20</size>
        </register>
        <register>
          <name>sFilterRegister.24.FR1</name>
          <addressOffset>0x300</addressOffset>
          <size>0x20</size>
        </register>
        <register>
          <name>sFilterRegister.24.FR2</name>
          <addressOffset>0x304</addressOffset>
          <size>0x20</size>
        </register>
        <register>
          <name>sFilterRegister.25.FR1</name>
          <addressOffset>0x308</addressOffset>
          <size>0x20</size>
        </register>
        <register>
          <name>sFilterRegister.25.FR2</name>
          <addressOffset>0x30c</addressOffset>
          <size>0x20</size>
        </register>
        <register>
          <name>sFilterRegister.26.FR1</name>
          <addressOffset>0x310</addressOffset>
          <size>0x20</size>
        </register>
        <register>
          <name>sFilterRegister.26.FR2</name>
          <addressOffset>0x314</addressOffset>
          <size>0x20</size>
        </register>
        <register>
          <name>sFilterRegister.27.FR1</name>
          <addressOffset>0x318</addressOffset>
          <size>0x20</size>
        </register>
        <register>
          <name>sFilterRegister.27.FR2</name>
          <addressOffset>0x31c</addressOffset>
          <size>0x20</size>
        </register>
      </registers>
    </peripheral>
    <peripheral>
      <name>CAN2</name>
      <baseAddress>0x40006800</baseAddress>
      <registers>
        <register>
          <name>MCR</name>
          <addressOffset>0x0</addressOffset>
          <size>0x20</size>
          <fields>
            <field>
              <name>INRQ</name>
              <bitOffset>0</bitOffset>
              <bitWidth>1</bitWidth>
            </field>
            <field>
              <name>SLEEP</name>
              <bitOffset>1</bitOffset>
              <bitWidth>1</bitWidth>
            </field>
            <field>
              <name>TXFP</name>
              <bitOffset>2</bitOffset>
              <bitWidth>1</bitWidth>
            </field>
            <field>
              <name>RFLM</name>
              <bitOffset>3</bitOffset>
              <bitWidth>1</bitWidth>
            </field>
            <field>
              <name>NART</name>
              <bitOffset>4</bitOffset>
              <bitWidth>1</bitWidth>
            </field>
            <field>
              <name>AWUM</name>
              <bitOffset>5</bitOffset>
              <bitWidth>1</bitWidth>
            </field>
            <field>
              <name>ABOM</name>
              <bitOffset>6</bitOffset>
              <bitWidth>1</bitWidth>
            </field>
            <field>
              <name>TTCM</name>
              <bitOffset>7</bitOffset>
              <bitWidth>1</bitWidth>
            </field>
            <field>
              <name>RESET</name>
              <bitOffset>15</bitOffset>
              <bitWidth>1</bitWidth>
            </field>
          </fields>
        </register>
        <register>
          <name>MSR</name>
          <addressOffset>0x4</addressOffset>
          <size>0x20</size>
          <fields>
            <field>
              <name>INAK</name>
              <bitOffset>0</bitOffset>
              <bitWidth>1</bitWidth>
            </field>
            <field>
              <name>SLAK</name>
              <bitOffset>1</bitOffset>
              <bitWidth>1</bitWidth>
            </field>
            <field>
              <name>ERRI</name>
              <bitOffset>2</bitOffset>
              <bitWidth>1</bitWidth>
            </field>
            <field>
              <name>WKUI</name>
              <bitOffset>3</bitOffset>
              <bitWidth>1</bitWidth>
            </field>
            <field>
              <name>SLAKI</name>
              <bitOffset>4</bitOffset>
              <bitWidth>1</bitWidth>
            </field>
            <field>
              <name>TXM</name>
              <bitOffset>8</bitOffset>
              <bitWidth>1</bitWidth>
            </field>
            <field>
              <name>RXM</name>
              <bitOffset>9</bitOffset>
              <bitWidth>1</bitWidth>
            </field>
            <field>
              <name>SAMP</name>
              <bitOffset>10</bitOffset>
              <bitWidth>1</bitWidth>
            </field>
            <field>
              <name>RX</name>
              <bitOffset>11</bitOffset>
              <bitWidth>1</bitWidth>
            </field>
          </fields>
        </register>
        <register>
          <name>TSR</name>
          <addressOffset>0x8</addressOffset>
          <size>0x20</size>
          <fields>
            <field>
              <name>RQCP0</name>
              <bitOffset>0</bitOffset>
              <bitWidth>1</bitWidth>
            </field>
            <field>
              <name>TXOK0</name>
              <bitOffset>1</bitOffset>
              <bitWidth>1</bitWidth>
            </field>
            <field>
              <name>ALST0</name>
              <bitOffset>2</bitOffset>
              <bitWidth>1</bitWidth>
            </field>
            <field>
              <name>TERR0</name>
              <bitOffset>3</bitOffset>
              <bitWidth>1</bitWidth>
            </field>
            <field>
              <name>ABRQ0</name>
              <bitOffset>7</bitOffset>
              <bitWidth>1</bitWidth>
            </field>
            <field>
              <name>RQCP1</name>
              <bitOffset>8</bitOffset>
              <bitWidth>1</bitWidth>
            </field>
            <field>
              <name>TXOK1</name>
              <bitOffset>9</bitOffset>
              <bitWidth>1</bitWidth>
            </field>
            <field>
              <name>ALST1</name>
              <bitOffset>10</bitOffset>
              <bitWidth>1</bitWidth>
            </field>
            <field>
              <name>TERR1</name>
              <bitOffset>11</bitOffset>
              <bitWidth>1</bitWidth>
            </field>
            <field>
              <name>ABRQ1</name>
              <bitOffset>15</bitOffset>
              <bitWidth>1</bitWidth>
            </field>
            <field>
              <name>RQCP2</name>
              <bitOffset>16</bitOffset>
              <bitWidth>1</bitWidth>
            </field>
            <field>
              <name>TXOK2</name>
              <bitOffset>17</bitOffset>
              <bitWidth>1</bitWidth>
            </field>
            <field>
              <name>ALST2</name>
              <bitOffset>18</bitOffset>
              <bitWidth>1</bitWidth>
            </field>
            <field>
              <name>TERR2</name>
              <bitOffset>19</bitOffset>
              <bitWidth>1</bitWidth>
            </field>
            <field>
              <name>ABRQ2</name>
              <bitOffset>23</bitOffset>
              <bitWidth>1</bitWidth>
            </field>
            <field>
              <name>CODE</name>
              <bitOffset>24</bitOffset>
              <bitWidth>2</bitWidth>
            </field>
            <field>
              <name>TME0</name>
              <bitOffset>26</bitOffset>
              <bitWidth>1</bitWidth>
            </field>
            <field>
              <name>TME1</name>
              <bitOffset>27</bitOffset>
              <bitWidth>1</bitWidth>
            </field>
            <field>
              <name>TME2</name>
              <bitOffset>28</bitOffset>
              <bitWidth>1</bitWidth>
            </field>
            <field>
              <name>LOW0</name>
              <bitOffset>29</bitOffset>
              <bitWidth>1</bitWidth>
            </field>
            <field>
              <name>LOW1</name>
              <bitOffset>30</bitOffset>
              <bitWidth>1</bitWidth>
            </field>
            <field>
              <name>LOW2</name>
              <bitOffset>31</bitOffset>
              <bitWidth>1</bitWidth>
            </field>
          </fields>
        </register>
        <register>
          <name>RF0R</name>
          <addressOffset>0xc</addressOffset>
          <size>0x20</size>
          <fields>
            <field>
              <name>FMP0</name>
              <bitOffset>0</bitOffset>
              <bitWidth>2</bitWidth>
            </field>
            <field>
              <name>FULL0</name>
              <bitOffset>3</bitOffset>
              <bitWidth>1</bitWidth>
            </field>
            <field>
              <name>FOVR0</name>
              <bitOffset>4</bitOffset>
              <bitWidth>1</bitWidth>
            </field>
            <field>
              <name>RFOM0</name>
              <bitOffset>5</bitOffset>
              <bitWidth>1</bitWidth>
            </field>
          </fields>
        </register>
        <register>
          <name>RF1R</name>
          <addressOffset>0x10</addressOffset>
          <size>0x20</size>
          <fields>
            <field>
              <name>FMP1</name>
              <bitOffset>0</bitOffset>
              <bitWidth>2</bitWidth>
            </field>
            <field>
              <name>FULL1</name>
              <bitOffset>3</bitOffset>
              <bitWidth>1</bitWidth>
            </field>
            <field>
              <name>FOVR1</name>
              <bitOffset>4</bitOffset>
              <bitWidth>1</bitWidth>
            </field>
            <field>
              <name>RFOM1</name>
              <bitOffset>5</bitOffset>
              <bitWidth>1</bitWidth>
            </field>
          </fields>
        </register>
        <register>
          <name>IER</name>
          <addressOffset>0x14</addressOffset>
          <size>0x20</size>
          <fields>
            <field>
              <name>TMEIE</name>
              <bitOffset>0</bitOffset>
              <bitWidth>1</bitWidth>
            </field>
            <field>
              <name>FMPIE0</name>
              <bitOffset>1</bitOffset>
              <bitWidth>1</bitWidth>
            </field>
            <field>
              <name>FFIE0</name>
              <bitOffset>2</bitOffset>
              <bitWidth>1</bitWidth>
            </field>
            <field>
              <name>FOVIE0</name>
              <bitOffset>3</bitOffset>
              <bitWidth>1</bitWidth>
            </field>
            <field>
              <name>FMPIE1</name>
              <bitOffset>4</bitOffset>
              <bitWidth>1</bitWidth>
            </field>
            <field>
              <name>FFIE1</name>
              <bitOffset>5</bitOffset>
              <bitWidth>1</bitWidth>
            </field>
            <field>
              <name>FOVIE1</name>
              <bitOffset>6</bitOffset>
              <bitWidth>1</bitWidth>
            </field>
            <field>
              <name>EWGIE</name>
              <bitOffset>8</bitOffset>
              <bitWidth>1</bitWidth>
            </field>
            <field>
              <name>EPVIE</name>
              <bitOffset>9</bitOffset>
              <bitWidth>1</bitWidth>
            </field>
            <field>
              <name>BOFIE</name>
              <bitOffset>10</bitOffset>
              <bitWidth>1</bitWidth>
            </field>
            <field>
              <name>LECIE</name>
              <bitOffset>11</bitOffset>
              <bitWidth>1</bitWidth>
            </field>
            <field>
              <name>ERRIE</name>
              <bitOffset>15</bitOffset>
              <bitWidth>1</bitWidth>
            </field>
            <field>
              <name>WKUIE</name>
              <bitOffset>16</bitOffset>
              <bitWidth>1</bitWidth>
            </field>
            <field>
              <name>SLKIE</name>
              <bitOffset>17</bitOffset>
              <bitWidth>1</bitWidth>
            </field>
          </fields>
        </register>
        <register>
          <name>ESR</name>
          <addressOffset>0x18</addressOffset>
          <size>0x20</size>
          <fields>
            <field>
              <name>EWGF</name>
              <bitOffset>0</bitOffset>
              <bitWidth>1</bitWidth>
            </field>
            <field>
              <name>EPVF</name>
              <bitOffset>1</bitOffset>
              <bitWidth>1</bitWidth>
            </field>
            <field>
              <name>BOFF</name>
              <bitOffset>2</bitOffset>
              <bitWidth>1</bitWidth>
            </field>
            <field>
              <name>LEC</name>
              <bitOffset>4</bitOffset>
              <bitWidth>3</bitWidth>
            </field>
            <field>
              <name>TEC</name>
              <bitOffset>16</bitOffset>
              <bitWidth>8</bitWidth>
            </field>
            <field>
              <name>REC</name>
              <bitOffset>24</bitOffset>
              <bitWidth>8</bitWidth>
            </field>
          </fields>
        </register>
        <register>
          <name>BTR</name>
          <addressOffset>0x1c</addressOffset>
          <size>0x20</size>
          <fields>
            <field>
              <name>BRP</name>
              <bitOffset>0</bitOffset>
              <bitWidth>10</bitWidth>
            </field>
            <field>
              <name>TS1</name>
              <bitOffset>16</bitOffset>
              <bitWidth>4</bitWidth>
            </field>
            <field>
              <name>TS2</name>
              <bitOffset>20</bitOffset>
              <bitWidth>3</bitWidth>
            </field>
            <field>
              <name>SJW</name>
              <bitOffset>24</bitOffset>
              <bitWidth>2</bitWidth>
            </field>
            <field>
              <name>LBKM</name>
              <bitOffset>30</bitOffset>
              <bitWidth>1</bitWidth>
            </field>
            <field>
              <name>SILM</name>
              <bitOffset>31</bitOffset>
              <bitWidth>1</bitWidth>
            </field>
          </fields>
        </register>
        <register>
          <name>sTxMailBox.0.TIR</name>
          <addressOffset>0x180</addressOffset>
          <size>0x20</size>
          <fields>
            <field>
              <name>TXRQ</name>
              <bitOffset>0</bitOffset>
              <bitWidth>1</bitWidth>
            </field>
            <field>
              <name>RTR</name>
              <bitOffset>1</bitOffset>
              <bitWidth>1</bitWidth>
            </field>
            <field>
              <name>IDE</name>
              <bitOffset>2</bitOffset>
              <bitWidth>1</bitWidth>
            </field>
            <field>
              <name>EXID</name>
              <bitOffset>3</bitOffset>
              <bitWidth>18</bitWidth>
            </field>
            <field>
              <name>STID</name>
              <bitOffset>21</bitOffset>
              <bitWidth>11</bitWidth>
            </field>
          </fields>
        </register>
        <register>
          <name>sTxMailBox.0.TDTR</name>
          <addressOffset>0x184</addressOffset>
          <size>0x20</size>
          <fields>
            <field>
              <name>DLC</name>
              <bitOffset>0</bitOffset>
              <bitWidth>4</bitWidth>
            </field>
            <field>
              <name>TGT</name>
              <bitOffset>8</bitOffset>
              <bitWidth>1</bitWidth>
            </field>
            <field>
              <name>TIME</name>
              <bitOffset>16</bitOffset>
              <bitWidth>16</bitWidth>
            </field>
          </fields>
        </register>
        <register>
          <name>sTxMailBox.0.TDLR</name>
          <addressOffset>0x188</addressOffset>
          <size>0x20</size>
          <fields>
            <field>
              <name>DATA0</name>
              <bitOffset>0</bitOffset>
              <bitWidth>8</bitWidth>
            </field>
            <field>
              <name>DATA1</name>
              <bitOffset>8</bitOffset>
              <bitWidth>8</bitWidth>
            </field>
            <field>
              <name>DATA2</name>
              <bitOffset>16</bitOffset>
              <bitWidth>8</bitWidth>
            </field>
            <field>
              <name>DATA3</name>
              <bitOffset>24</bitOffset>
              <bitWidth>8</bitWidth>
            </field>
          </fields>
        </register>
        <register>
          <name>sTxMailBox.0.TDHR</name>
          <addressOffset>0x18c</addressOffset>
          <size>0x20</size>
          <fields>
            <field>
              <name>DATA4</name>
              <bitOffset>0</bitOffset>
              <bitWidth>8</bitWidth>
            </field>
            <field>
              <name>DATA5</name>
              <bitOffset>8</bitOffset>
              <bitWidth>8</bitWidth>
            </field>
            <field>
              <name>DATA6</name>
              <bitOffset>16</bitOffset>
              <bitWidth>8</bitWidth>
            </field>
            <field>
              <name>DATA7</name>
              <bitOffset>24</bitOffset>
              <bitWidth>8</bitWidth>
            </field>
          </fields>
        </register>
        <register>
          <name>sTxMailBox.1.TIR</name>
          <addressOffset>0x190</addressOffset>
          <size>0x20</size>
          <fields>
            <field>
              <name>TXRQ</name>
              <bitOffset>0</bitOffset>
              <bitWidth>1</bitWidth>
            </field>
            <field>
              <name>RTR</name>
              <bitOffset>1</bitOffset>
              <bitWidth>1</bitWidth>
            </field>
            <field>
              <name>IDE</name>
              <bitOffset>2</bitOffset>
              <bitWidth>1</bitWidth>
            </field>
            <field>
              <name>EXID</name>
              <bitOffset>3</bitOffset>
              <bitWidth>18</bitWidth>
            </field>
            <field>
              <name>STID</name>
              <bitOffset>21</bitOffset>
              <bitWidth>11</bitWidth>
            </field>
          </fields>
        </register>
        <register>
          <name>sTxMailBox.1.TDTR</name>
          <addressOffset>0x194</addressOffset>
          <size>0x20</size>
          <fields>
            <field>
              <name>DLC</name>
              <bitOffset>0</bitOffset>
              <bitWidth>4</bitWidth>
            </field>
            <field>
              <name>TGT</name>
              <bitOffset>8</bitOffset>
              <bitWidth>1</bitWidth>
            </field>
            <field>
              <name>TIME</name>
              <bitOffset>16</bitOffset>
              <bitWidth>16</bitWidth>
            </field>
          </fields>
        </register>
        <register>
          <name>sTxMailBox.1.TDLR</name>
          <addressOffset>0x198</addressOffset>
          <size>0x20</size>
          <fields>
            <field>
              <name>DATA0</name>
              <bitOffset>0</bitOffset>
              <bitWidth>8</bitWidth>
            </field>
            <field>
              <name>DATA1</name>
              <bitOffset>8</bitOffset>
              <bitWidth>8</bitWidth>
            </field>
            <field>
              <name>DATA2</name>
              <bitOffset>16</bitOffset>
              <bitWidth>8</bitWidth>
            </field>
            <field>
              <name>DATA3</name>
              <bitOffset>24</bitOffset>
              <bitWidth>8</bitWidth>
            </field>
          </fields>
        </register>
        <register>
          <name>sTxMailBox.1.TDHR</name>
          <addressOffset>0x19c</addressOffset>
          <size>0x20</size>
          <fields>
            <field>
              <name>DATA4</name>
              <bitOffset>0</bitOffset>
              <bitWidth>8</bitWidth>
            </field>
            <field>
              <name>DATA5</name>
              <bitOffset>8</bitOffset>
              <bitWidth>8</bitWidth>
            </field>
            <field>
              <name>DATA6</name>
              <bitOffset>16</bitOffset>
              <bitWidth>8</bitWidth>
            </field>
            <field>
              <name>DATA7</name>
              <bitOffset>24</bitOffset>
              <bitWidth>8</bitWidth>
            </field>
          </fields>
        </register>
        <register>
          <name>sTxMailBox.2.TIR</name>
          <addressOffset>0x1a0</addressOffset>
          <size>0x20</size>
          <fields>
            <field>
              <name>TXRQ</name>
              <bitOffset>0</bitOffset>
              <bitWidth>1</bitWidth>
            </field>
            <field>
              <name>RTR</name>
              <bitOffset>1</bitOffset>
              <bitWidth>1</bitWidth>
            </field>
            <field>
              <name>IDE</name>
              <bitOffset>2</bitOffset>
              <bitWidth>1</bitWidth>
            </field>
            <field>
              <name>EXID</name>
              <bitOffset>3</bitOffset>
              <bitWidth>18</bitWidth>
            </field>
            <field>
              <name>STID</name>
              <bitOffset>21</bitOffset>
              <bitWidth>11</bitWidth>
            </field>
          </fields>
        </register>
        <register>
          <name>sTxMailBox.2.TDTR</name>
          <addressOffset>0x1a4</addressOffset>
          <size>0x20</size>
          <fields>
            <field>
              <name>DLC</name>
              <bitOffset>0</bitOffset>
              <bitWidth>4</bitWidth>
            </field>
            <field>
              <name>TGT</name>
              <bitOffset>8</bitOffset>
              <bitWidth>1</bitWidth>
            </field>
            <field>
              <name>TIME</name>
              <bitOffset>16</bitOffset>
              <bitWidth>16</bitWidth>
            </field>
          </fields>
        </register>
        <register>
          <name>sTxMailBox.2.TDLR</name>
          <addressOffset>0x1a8</addressOffset>
          <size>0x20</size>
          <fields>
            <field>
              <name>DATA0</name>
              <bitOffset>0</bitOffset>
              <bitWidth>8</bitWidth>
            </field>
            <field>
              <name>DATA1</name>
              <bitOffset>8</bitOffset>
              <bitWidth>8</bitWidth>
            </field>
            <field>
              <name>DATA2</name>
              <bitOffset>16</bitOffset>
              <bitWidth>8</bitWidth>
            </field>
            <field>
              <name>DATA3</name>
              <bitOffset>24</bitOffset>
              <bitWidth>8</bitWidth>
            </field>
          </fields>
        </register>
        <register>
          <name>sTxMailBox.2.TDHR</name>
          <addressOffset>0x1ac</addressOffset>
          <size>0x20</size>
          <fields>
            <field>
              <name>DATA4</name>
              <bitOffset>0</bitOffset>
              <bitWidth>8</bitWidth>
            </field>
            <field>
              <name>DATA5</name>
              <bitOffset>8</bitOffset>
              <bitWidth>8</bitWidth>
            </field>
            <field>
              <name>DATA6</name>
              <bitOffset>16</bitOffset>
              <bitWidth>8</bitWidth>
            </field>
            <field>
              <name>DATA7</name>
              <bitOffset>24</bitOffset>
              <bitWidth>8</bitWidth>
            </field>
          </fields>
        </register>
        <register>
          <name>sFIFOMailBox.0.RIR</name>
          <addressOffset>0x1b0</addressOffset>
          <size>0x20</size>
          <fields>
            <field>
              <name>RTR</name>
              <bitOffset>1</bitOffset>
              <bitWidth>1</bitWidth>
            </field>
            <field>
              <name>IDE</name>
              <bitOffset>2</bitOffset>
              <bitWidth>1</bitWidth>
            </field>
            <field>
              <name>EXID</name>
              <bitOffset>3</bitOffset>
              <bitWidth>18</bitWidth>
            </field>
            <field>
              <name>STID</name>
              <bitOffset>21</bitOffset>
              <bitWidth>11</bitWidth>
            </field>
          </fields>
        </register>
        <register>
          <name>sFIFOMailBox.0.RDTR</name>
          <addressOffset>0x1b4</addressOffset>
          <size>0x20</size>
          <fields>
            <field>
              <name>DLC</name>
              <bitOffset>0</bitOffset>
              <bitWidth>4</bitWidth>
            </field>
            <field>
              <name>FMI</name>
              <bitOffset>8</bitOffset>
              <bitWidth>8</bitWidth>
            </field>
            <field>
              <name>TIME</name>
              <bitOffset>16</bitOffset>
              <bitWidth>16</bitWidth>
            </field>
          </fields>
        </register>
        <register>
          <name>sFIFOMailBox.0.RDLR</name>
          <addressOffset>0x1b8</addressOffset>
          <size>0x20</size>
          <fields>
            <field>
              <name>DATA0</name>
              <bitOffset>0</bitOffset>
              <bitWidth>8</bitWidth>
            </field>
            <field>
              <name>DATA1</name>
              <bitOffset>8</bitOffset>
              <bitWidth>8</bitWidth>
            </field>
            <field>
              <name>DATA2</name>
              <bitOffset>16</bitOffset>
              <bitWidth>8</bitWidth>
            </field>
            <field>
              <name>DATA3</name>
              <bitOffset>24</bitOffset>
              <bitWidth>8</bitWidth>
            </field>
          </fields>
        </register>
        <register>
          <name>sFIFOMailBox.0.RDHR</name>
          <addressOffset>0x1bc</addressOffset>
          <size>0x20</size>
          <fields>
            <field>
              <name>DATA4</name>
              <bitOffset>0</bitOffset>
              <bitWidth>8</bitWidth>
            </field>
            <field>
              <name>DATA5</name>
              <bitOffset>8</bitOffset>
              <bitWidth>8</bitWidth>
            </field>
            <field>
              <name>DATA6</name>
              <bitOffset>16</bitOffset>
              <bitWidth>8</bitWidth>
            </field>
            <field>
              <name>DATA7</name>
              <bitOffset>24</bitOffset>
              <bitWidth>8</bitWidth>
            </field>
          </fields>
        </register>
        <register>
          <name>sFIFOMailBox.1.RIR</name>
          <addressOffset>0x1c0</addressOffset>
          <size>0x20</size>
          <fields>
            <field>
              <name>RTR</name>
              <bitOffset>1</bitOffset>
              <bitWidth>1</bitWidth>
            </field>
            <field>
              <name>IDE</name>
              <bitOffset>2</bitOffset>
              <bitWidth>1</bitWidth>
            </field>
            <field>
              <name>EXID</name>
              <bitOffset>3</bitOffset>
              <bitWidth>18</bitWidth>
            </field>
            <field>
              <name>STID</name>
              <bitOffset>21</bitOffset>
              <bitWidth>11</bitWidth>
            </field>
          </fields>
        </register>
        <register>
          <name>sFIFOMailBox.1.RDTR</name>
          <addressOffset>0x1c4</addressOffset>
          <size>0x20</size>
          <fields>
            <field>
              <name>DLC</name>
              <bitOffset>0</bitOffset>
              <bitWidth>4</bitWidth>
            </field>
            <field>
              <name>FMI</name>
              <bitOffset>8</bitOffset>
              <bitWidth>8</bitWidth>
            </field>
            <field>
              <name>TIME</name>
              <bitOffset>16</bitOffset>
              <bitWidth>16</bitWidth>
            </field>
          </fields>
        </register>
        <register>
          <name>sFIFOMailBox.1.RDLR</name>
          <addressOffset>0x1c8</addressOffset>
          <size>0x20</size>
          <fields>
            <field>
              <name>DATA0</name>
              <bitOffset>0</bitOffset>
              <bitWidth>8</bitWidth>
            </field>
            <field>
              <name>DATA1</name>
              <bitOffset>8</bitOffset>
              <bitWidth>8</bitWidth>
            </field>
            <field>
              <name>DATA2</name>
              <bitOffset>16</bitOffset>
              <bitWidth>8</bitWidth>
            </field>
            <field>
              <name>DATA3</name>
              <bitOffset>24</bitOffset>
              <bitWidth>8</bitWidth>
            </field>
          </fields>
        </register>
        <register>
          <name>sFIFOMailBox.1.RDHR</name>
          <addressOffset>0x1cc</addressOffset>
          <size>0x20</size>
          <fields>
            <field>
              <name>DATA4</name>
              <bitOffset>0</bitOffset>
              <bitWidth>8</bitWidth>
            </field>
            <field>
              <name>DATA5</name>
              <bitOffset>8</bitOffset>
              <bitWidth>8</bitWidth>
            </field>
            <field>
              <name>DATA6</name>
              <bitOffset>16</bitOffset>
              <bitWidth>8</bitWidth>
            </field>
            <field>
              <name>DATA7</name>
              <bitOffset>24</bitOffset>
              <bitWidth>8</bitWidth>
            </field>
          </fields>
        </register>
        <register>
          <name>FMR</name>
          <addressOffset>0x200</addressOffset>
          <size>0x20</size>
          <fields>
            <field>
              <name>CAN2SB</name>
              <bitOffset>8</bitOffset>
              <bitWidth>6</bitWidth>
            </field>
          </fields>
        </register>
        <register>
          <name>FM1R</name>
          <addressOffset>0x204</addressOffset>
          <size>0x20</size>
          <fields>
            <field>
              <name>FBM0</name>
              <bitOffset>0</bitOffset>
              <bitWidth>1</bitWidth>
            </field>
            <field>
              <name>FBM1</name>
              <bitOffset>1</bitOffset>
              <bitWidth>1</bitWidth>
            </field>
            <field>
              <name>FBM2</name>
              <bitOffset>2</bitOffset>
              <bitWidth>1</bitWidth>
            </field>
            <field>
              <name>FBM3</name>
              <bitOffset>3</bitOffset>
              <bitWidth>1</bitWidth>
            </field>
            <field>
              <name>FBM4</name>
              <bitOffset>4</bitOffset>
              <bitWidth>1</bitWidth>
            </field>
            <field>
              <name>FBM5</name>
              <bitOffset>5</bitOffset>
              <bitWidth>1</bitWidth>
            </field>
            <field>
              <name>FBM6</name>
              <bitOffset>6</bitOffset>
              <bitWidth>1</bitWidth>
            </field>
            <field>
              <name>FBM7</name>
              <bitOffset>7</bitOffset>
              <bitWidth>1</bitWidth>
            </field>
            <field>
              <name>FBM8</name>
              <bitOffset>8</bitOffset>
              <bitWidth>1</bitWidth>
            </field>
            <field>
              <name>FBM9</name>
              <bitOffset>9</bitOffset>
              <bitWidth>1</bitWidth>
            </field>
            <field>
              <name>FBM10</name>
              <bitOffset>10</bitOffset>
              <bitWidth>1</bitWidth>
            </field>
            <field>
              <name>FBM11</name>
              <bitOffset>11</bitOffset>
              <bitWidth>1</bitWidth>
            </field>
            <field>
              <name>FBM12</name>
              <bitOffset>12</bitOffset>
              <bitWidth>1</bitWidth>
            </field>
            <field>
              <name>FBM13</name>
              <bitOffset>13</bitOffset>
              <bitWidth>1</bitWidth>
            </field>
          </fields>
        </register>
        <register>
          <name>FS1R</name>
          <addressOffset>0x20c</addressOffset>
          <size>0x20</size>
          <fields>
            <field>
              <name>FSC0</name>
              <bitOffset>0</bitOffset>
              <bitWidth>1</bitWidth>
            </field>
            <field>
              <name>FSC1</name>
              <bitOffset>1</bitOffset>
              <bitWidth>1</bitWidth>
            </field>
            <field>
              <name>FSC2</name>
              <bitOffset>2</bitOffset>
              <bitWidth>1</bitWidth>
            </field>
            <field>
              <name>FSC3</name>
              <bitOffset>3</bitOffset>
              <bitWidth>1</bitWidth>
            </field>
            <field>
              <name>FSC4</name>
              <bitOffset>4</bitOffset>
              <bitWidth>1</bitWidth>
            </field>
            <field>
              <name>FSC5</name>
              <bitOffset>5</bitOffset>
              <bitWidth>1</bitWidth>
            </field>
            <field>
              <name>FSC6</name>
              <bitOffset>6</bitOffset>
              <bitWidth>1</bitWidth>
            </field>
            <field>
              <name>FSC7</name>
              <bitOffset>7</bitOffset>
              <bitWidth>1</bitWidth>
            </field>
            <field>
              <name>FSC8</name>
              <bitOffset>8</bitOffset>
              <bitWidth>1</bitWidth>
            </field>
            <field>
              <name>FSC9</name>
              <bitOffset>9</bitOffset>
              <bitWidth>1</bitWidth>
            </field>
            <field>
              <name>FSC10</name>
              <bitOffset>10</bitOffset>
              <bitWidth>1</bitWidth>
            </field>
            <field>
              <name>FSC11</name>
              <bitOffset>11</bitOffset>
              <bitWidth>1</bitWidth>
            </field>
            <field>
              <name>FSC12</name>
              <bitOffset>12</bitOffset>
              <bitWidth>1</bitWidth>
            </field>
            <field>
              <name>FSC13</name>
              <bitOffset>13</bitOffset>
              <bitWidth>1</bitWidth>
            </field>
          </fields>
        </register>
        <register>
          <name>FFA1R</name>
          <addressOffset>0x214</addressOffset>
          <size>0x20</size>
          <fields>
            <field>
              <name>FFA0</name>
              <bitOffset>0</bitOffset>
              <bitWidth>1</bitWidth>
            </field>
            <field>
              <name>FFA1</name>
              <bitOffset>1</bitOffset>
              <bitWidth>1</bitWidth>
            </field>
            <field>
              <name>FFA2</name>
              <bitOffset>2</bitOffset>
              <bitWidth>1</bitWidth>
            </field>
            <field>
              <name>FFA3</name>
              <bitOffset>3</bitOffset>
              <bitWidth>1</bitWidth>
            </field>
            <field>
              <name>FFA4</name>
              <bitOffset>4</bitOffset>
              <bitWidth>1</bitWidth>
            </field>
            <field>
              <name>FFA5</name>
              <bitOffset>5</bitOffset>
              <bitWidth>1</bitWidth>
            </field>
            <field>
              <name>FFA6</name>
              <bitOffset>6</bitOffset>
              <bitWidth>1</bitWidth>
            </field>
            <field>
              <name>FFA7</name>
              <bitOffset>7</bitOffset>
              <bitWidth>1</bitWidth>
            </field>
            <field>
              <name>FFA8</name>
              <bitOffset>8</bitOffset>
              <bitWidth>1</bitWidth>
            </field>
            <field>
              <name>FFA9</name>
              <bitOffset>9</bitOffset>
              <bitWidth>1</bitWidth>
            </field>
            <field>
              <name>FFA10</name>
              <bitOffset>10</bitOffset>
              <bitWidth>1</bitWidth>
            </field>
            <field>
              <name>FFA11</name>
              <bitOffset>11</bitOffset>
              <bitWidth>1</bitWidth>
            </field>
            <field>
              <name>FFA12</name>
              <bitOffset>12</bitOffset>
              <bitWidth>1</bitWidth>
            </field>
            <field>
              <name>FFA13</name>
              <bitOffset>13</bitOffset>
              <bitWidth>1</bitWidth>
            </field>
          </fields>
        </register>
        <register>
          <name>FA1R</name>
          <addressOffset>0x21c</addressOffset>
          <size>0x20</size>
          <fields>
            <field>
              <name>FACT0</name>
              <bitOffset>0</bitOffset>
              <bitWidth>1</bitWidth>
            </field>
            <field>
              <name>FACT1</name>
              <bitOffset>1</bitOffset>
              <bitWidth>1</bitWidth>
            </field>
            <field>
              <name>FACT2</name>
              <bitOffset>2</bitOffset>
              <bitWidth>1</bitWidth>
            </field>
            <field>
              <name>FACT3</name>
              <bitOffset>3</bitOffset>
              <bitWidth>1</bitWidth>
            </field>
            <field>
              <name>FACT4</name>
              <bitOffset>4</bitOffset>
              <bitWidth>1</bitWidth>
            </field>
            <field>
              <name>FACT5</name>
              <bitOffset>5</bitOffset>
              <bitWidth>1</bitWidth>
            </field>
            <field>
              <name>FACT6</name>
              <bitOffset>6</bitOffset>
              <bitWidth>1</bitWidth>
            </field>
            <field>
              <name>FACT7</name>
              <bitOffset>7</bitOffset>
              <bitWidth>1</bitWidth>
            </field>
            <field>
              <name>FACT8</name>
              <bitOffset>8</bitOffset>
              <bitWidth>1</bitWidth>
            </field>
            <field>
              <name>FACT9</name>
              <bitOffset>9</bitOffset>
              <bitWidth>1</bitWidth>
            </field>
            <field>
              <name>FACT10</name>
              <bitOffset>10</bitOffset>
              <bitWidth>1</bitWidth>
            </field>
            <field>
              <name>FACT11</name>
              <bitOffset>11</bitOffset>
              <bitWidth>1</bitWidth>
            </field>
            <field>
              <name>FACT12</name>
              <bitOffset>12</bitOffset>
              <bitWidth>1</bitWidth>
            </field>
            <field>
              <name>FACT13</name>
              <bitOffset>13</bitOffset>
              <bitWidth>1</bitWidth>
            </field>
          </fields>
        </register>
        <register>
          <name>sFilterRegister.0.FR1</name>
          <addressOffset>0x240</addressOffset>
          <size>0x20</size>
          <fields>
            <field>
              <name>FB0</name>
              <bitOffset>0</bitOffset>
              <bitWidth>1</bitWidth>
            </field>
            <field>
              <name>FB1</name>
              <bitOffset>1</bitOffset>
              <bitWidth>1</bitWidth>
            </field>
            <field>
              <name>FB2</name>
              <bitOffset>2</bitOffset>
              <bitWidth>1</bitWidth>
            </field>
            <field>
              <name>FB3</name>
              <bitOffset>3</bitOffset>
              <bitWidth>1</bitWidth>
            </field>
            <field>
              <name>FB4</name>
              <bitOffset>4</bitOffset>
              <bitWidth>1</bitWidth>
            </field>
            <field>
              <name>FB5</name>
              <bitOffset>5</bitOffset>
              <bitWidth>1</bitWidth>
            </field>
            <field>
              <name>FB6</name>
              <bitOffset>6</bitOffset>
              <bitWidth>1</bitWidth>
            </field>
            <field>
              <name>FB7</name>
              <bitOffset>7</bitOffset>
              <bitWidth>1</bitWidth>
            </field>
            <field>
              <name>FB8</name>
              <bitOffset>8</bitOffset>
              <bitWidth>1</bitWidth>
            </field>
            <field>
              <name>FB9</name>
              <bitOffset>9</bitOffset>
              <bitWidth>1</bitWidth>
            </field>
            <field>
              <name>FB10</name>
              <bitOffset>10</bitOffset>
              <bitWidth>1</bitWidth>
            </field>
            <field>
              <name>FB11</name>
              <bitOffset>11</bitOffset>
              <bitWidth>1</bitWidth>
            </field>
            <field>
              <name>FB12</name>
              <bitOffset>12</bitOffset>
              <bitWidth>1</bitWidth>
            </field>
            <field>
              <name>FB13</name>
              <bitOffset>13</bitOffset>
              <bitWidth>1</bitWidth>
            </field>
            <field>
              <name>FB14</name>
              <bitOffset>14</bitOffset>
              <bitWidth>1</bitWidth>
            </field>
            <field>
              <name>FB15</name>
              <bitOffset>15</bitOffset>
              <bitWidth>1</bitWidth>
            </field>
            <field>
              <name>FB16</name>
              <bitOffset>16</bitOffset>
              <bitWidth>1</bitWidth>
            </field>
            <field>
              <name>FB17</name>
              <bitOffset>17</bitOffset>
              <bitWidth>1</bitWidth>
            </field>
            <field>
              <name>FB18</name>
              <bitOffset>18</bitOffset>
              <bitWidth>1</bitWidth>
            </field>
            <field>
              <name>FB19</name>
              <bitOffset>19</bitOffset>
              <bitWidth>1</bitWidth>
            </field>
            <field>
              <name>FB20</name>
              <bitOffset>20</bitOffset>
              <bitWidth>1</bitWidth>
            </field>
            <field>
              <name>FB21</name>
              <bitOffset>21</bitOffset>
              <bitWidth>1</bitWidth>
            </field>
            <field>
              <name>FB22</name>
              <bitOffset>22</bitOffset>
              <bitWidth>1</bitWidth>
            </field>
            <field>
              <name>FB23</name>
              <bitOffset>23</bitOffset>
              <bitWidth>1</bitWidth>
            </field>
            <field>
              <name>FB24</name>
              <bitOffset>24</bitOffset>
              <bitWidth>1</bitWidth>
            </field>
            <field>
              <name>FB25</name>
              <bitOffset>25</bitOffset>
              <bitWidth>1</bitWidth>
            </field>
            <field>
              <name>FB26</name>
              <bitOffset>26</bitOffset>
              <bitWidth>1</bitWidth>
            </field>
            <field>
              <name>FB27</name>
              <bitOffset>27</bitOffset>
              <bitWidth>1</bitWidth>
            </field>
            <field>
              <name>FB28</name>
              <bitOffset>28</bitOffset>
              <bitWidth>1</bitWidth>
            </field>
            <field>
              <name>FB29</name>
              <bitOffset>29</bitOffset>
              <bitWidth>1</bitWidth>
            </field>
            <field>
              <name>FB30</name>
              <bitOffset>30</bitOffset>
              <bitWidth>1</bitWidth>
            </field>
            <field>
              <name>FB31</name>
              <bitOffset>31</bitOffset>
              <bitWidth>1</bitWidth>
            </field>
          </fields>
        </register>
        <register>
          <name>sFilterRegister.0.FR2</name>
          <addressOffset>0x244</addressOffset>
          <size>0x20</size>
          <fields>
            <field>
              <name>FB0</name>
              <bitOffset>0</bitOffset>
              <bitWidth>1</bitWidth>
            </field>
            <field>
              <name>FB1</name>
              <bitOffset>1</bitOffset>
              <bitWidth>1</bitWidth>
            </field>
            <field>
              <name>FB2</name>
              <bitOffset>2</bitOffset>
              <bitWidth>1</bitWidth>
            </field>
            <field>
              <name>FB3</name>
              <bitOffset>3</bitOffset>
              <bitWidth>1</bitWidth>
            </field>
            <field>
              <name>FB4</name>
              <bitOffset>4</bitOffset>
              <bitWidth>1</bitWidth>
            </field>
            <field>
              <name>FB5</name>
              <bitOffset>5</bitOffset>
              <bitWidth>1</bitWidth>
            </field>
            <field>
              <name>FB6</name>
              <bitOffset>6</bitOffset>
              <bitWidth>1</bitWidth>
            </field>
            <field>
              <name>FB7</name>
              <bitOffset>7</bitOffset>
              <bitWidth>1</bitWidth>
            </field>
            <field>
              <name>FB8</name>
              <bitOffset>8</bitOffset>
              <bitWidth>1</bitWidth>
            </field>
            <field>
              <name>FB9</name>
              <bitOffset>9</bitOffset>
              <bitWidth>1</bitWidth>
            </field>
            <field>
              <name>FB10</name>
              <bitOffset>10</bitOffset>
              <bitWidth>1</bitWidth>
            </field>
            <field>
              <name>FB11</name>
              <bitOffset>11</bitOffset>
              <bitWidth>1</bitWidth>
            </field>
            <field>
              <name>FB12</name>
              <bitOffset>12</bitOffset>
              <bitWidth>1</bitWidth>
            </field>
            <field>
              <name>FB13</name>
              <bitOffset>13</bitOffset>
              <bitWidth>1</bitWidth>
            </field>
            <field>
              <name>FB14</name>
              <bitOffset>14</bitOffset>
              <bitWidth>1</bitWidth>
            </field>
            <field>
              <name>FB15</name>
              <bitOffset>15</bitOffset>
              <bitWidth>1</bitWidth>
            </field>
            <field>
              <name>FB16</name>
              <bitOffset>16</bitOffset>
              <bitWidth>1</bitWidth>
            </field>
            <field>
              <name>FB17</name>
              <bitOffset>17</bitOffset>
              <bitWidth>1</bitWidth>
            </field>
            <field>
              <name>FB18</name>
              <bitOffset>18</bitOffset>
              <bitWidth>1</bitWidth>
            </field>
            <field>
              <name>FB19</name>
              <bitOffset>19</bitOffset>
              <bitWidth>1</bitWidth>
            </field>
            <field>
              <name>FB20</name>
              <bitOffset>20</bitOffset>
              <bitWidth>1</bitWidth>
            </field>
            <field>
              <name>FB21</name>
              <bitOffset>21</bitOffset>
              <bitWidth>1</bitWidth>
            </field>
            <field>
              <name>FB22</name>
              <bitOffset>22</bitOffset>
              <bitWidth>1</bitWidth>
            </field>
            <field>
              <name>FB23</name>
              <bitOffset>23</bitOffset>
              <bitWidth>1</bitWidth>
            </field>
            <field>
              <name>FB24</name>
              <bitOffset>24</bitOffset>
              <bitWidth>1</bitWidth>
            </field>
            <field>
              <name>FB25</name>
              <bitOffset>25</bitOffset>
              <bitWidth>1</bitWidth>
            </field>
            <field>
              <name>FB26</name>
              <bitOffset>26</bitOffset>
              <bitWidth>1</bitWidth>
            </field>
            <field>
              <name>FB27</name>
              <bitOffset>27</bitOffset>
              <bitWidth>1</bitWidth>
            </field>
            <field>
              <name>FB28</name>
              <bitOffset>28</bitOffset>
              <bitWidth>1</bitWidth>
            </field>
            <field>
              <name>FB29</name>
              <bitOffset>29</bitOffset>
              <bitWidth>1</bitWidth>
            </field>
            <field>
              <name>FB30</name>
              <bitOffset>30</bitOffset>
              <bitWidth>1</bitWidth>
            </field>
            <field>
              <name>FB31</name>
              <bitOffset>31</bitOffset>
              <bitWidth>1</bitWidth>
            </field>
          </fields>
        </register>
        <register>
          <name>sFilterRegister.1.FR1</name>
          <addressOffset>0x248</addressOffset>
          <size>0x20</size>
          <fields>
            <field>
              <name>FB0</name>
              <bitOffset>0</bitOffset>
              <bitWidth>1</bitWidth>
            </field>
            <field>
              <name>FB1</name>
              <bitOffset>1</bitOffset>
              <bitWidth>1</bitWidth>
            </field>
            <field>
              <name>FB2</name>
              <bitOffset>2</bitOffset>
              <bitWidth>1</bitWidth>
            </field>
            <field>
              <name>FB3</name>
              <bitOffset>3</bitOffset>
              <bitWidth>1</bitWidth>
            </field>
            <field>
              <name>FB4</name>
              <bitOffset>4</bitOffset>
              <bitWidth>1</bitWidth>
            </field>
            <field>
              <name>FB5</name>
              <bitOffset>5</bitOffset>
              <bitWidth>1</bitWidth>
            </field>
            <field>
              <name>FB6</name>
              <bitOffset>6</bitOffset>
              <bitWidth>1</bitWidth>
            </field>
            <field>
              <name>FB7</name>
              <bitOffset>7</bitOffset>
              <bitWidth>1</bitWidth>
            </field>
            <field>
              <name>FB8</name>
              <bitOffset>8</bitOffset>
              <bitWidth>1</bitWidth>
            </field>
            <field>
              <name>FB9</name>
              <bitOffset>9</bitOffset>
              <bitWidth>1</bitWidth>
            </field>
            <field>
              <name>FB10</name>
              <bitOffset>10</bitOffset>
              <bitWidth>1</bitWidth>
            </field>
            <field>
              <name>FB11</name>
              <bitOffset>11</bitOffset>
              <bitWidth>1</bitWidth>
            </field>
            <field>
              <name>FB12</name>
              <bitOffset>12</bitOffset>
              <bitWidth>1</bitWidth>
            </field>
            <field>
              <name>FB13</name>
              <bitOffset>13</bitOffset>
              <bitWidth>1</bitWidth>
            </field>
            <field>
              <name>FB14</name>
              <bitOffset>14</bitOffset>
              <bitWidth>1</bitWidth>
            </field>
            <field>
              <name>FB15</name>
              <bitOffset>15</bitOffset>
              <bitWidth>1</bitWidth>
            </field>
            <field>
              <name>FB16</name>
              <bitOffset>16</bitOffset>
              <bitWidth>1</bitWidth>
            </field>
            <field>
              <name>FB17</name>
              <bitOffset>17</bitOffset>
              <bitWidth>1</bitWidth>
            </field>
            <field>
              <name>FB18</name>
              <bitOffset>18</bitOffset>
              <bitWidth>1</bitWidth>
            </field>
            <field>
              <name>FB19</name>
              <bitOffset>19</bitOffset>
              <bitWidth>1</bitWidth>
            </field>
            <field>
              <name>FB20</name>
              <bitOffset>20</bitOffset>
              <bitWidth>1</bitWidth>
            </field>
            <field>
              <name>FB21</name>
              <bitOffset>21</bitOffset>
              <bitWidth>1</bitWidth>
            </field>
            <field>
              <name>FB22</name>
              <bitOffset>22</bitOffset>
              <bitWidth>1</bitWidth>
            </field>
            <field>
              <name>FB23</name>
              <bitOffset>23</bitOffset>
              <bitWidth>1</bitWidth>
            </field>
            <field>
              <name>FB24</name>
              <bitOffset>24</bitOffset>
              <bitWidth>1</bitWidth>
            </field>
            <field>
              <name>FB25</name>
              <bitOffset>25</bitOffset>
              <bitWidth>1</bitWidth>
            </field>
            <field>
              <name>FB26</name>
              <bitOffset>26</bitOffset>
              <bitWidth>1</bitWidth>
            </field>
            <field>
              <name>FB27</name>
              <bitOffset>27</bitOffset>
              <bitWidth>1</bitWidth>
            </field>
            <field>
              <name>FB28</name>
              <bitOffset>28</bitOffset>
              <bitWidth>1</bitWidth>
            </field>
            <field>
              <name>FB29</name>
              <bitOffset>29</bitOffset>
              <bitWidth>1</bitWidth>
            </field>
            <field>
              <name>FB30</name>
              <bitOffset>30</bitOffset>
              <bitWidth>1</bitWidth>
            </field>
            <field>
              <name>FB31</name>
              <bitOffset>31</bitOffset>
              <bitWidth>1</bitWidth>
            </field>
          </fields>
        </register>
        <register>
          <name>sFilterRegister.1.FR2</name>
          <addressOffset>0x24c</addressOffset>
          <size>0x20</size>
          <fields>
            <field>
              <name>FB0</name>
              <bitOffset>0</bitOffset>
              <bitWidth>1</bitWidth>
            </field>
            <field>
              <name>FB1</name>
              <bitOffset>1</bitOffset>
              <bitWidth>1</bitWidth>
            </field>
            <field>
              <name>FB2</name>
              <bitOffset>2</bitOffset>
              <bitWidth>1</bitWidth>
            </field>
            <field>
              <name>FB3</name>
              <bitOffset>3</bitOffset>
              <bitWidth>1</bitWidth>
            </field>
            <field>
              <name>FB4</name>
              <bitOffset>4</bitOffset>
              <bitWidth>1</bitWidth>
            </field>
            <field>
              <name>FB5</name>
              <bitOffset>5</bitOffset>
              <bitWidth>1</bitWidth>
            </field>
            <field>
              <name>FB6</name>
              <bitOffset>6</bitOffset>
              <bitWidth>1</bitWidth>
            </field>
            <field>
              <name>FB7</name>
              <bitOffset>7</bitOffset>
              <bitWidth>1</bitWidth>
            </field>
            <field>
              <name>FB8</name>
              <bitOffset>8</bitOffset>
              <bitWidth>1</bitWidth>
            </field>
            <field>
              <name>FB9</name>
              <bitOffset>9</bitOffset>
              <bitWidth>1</bitWidth>
            </field>
            <field>
              <name>FB10</name>
              <bitOffset>10</bitOffset>
              <bitWidth>1</bitWidth>
            </field>
            <field>
              <name>FB11</name>
              <bitOffset>11</bitOffset>
              <bitWidth>1</bitWidth>
            </field>
            <field>
              <name>FB12</name>
              <bitOffset>12</bitOffset>
              <bitWidth>1</bitWidth>
            </field>
            <field>
              <name>FB13</name>
              <bitOffset>13</bitOffset>
              <bitWidth>1</bitWidth>
            </field>
            <field>
              <name>FB14</name>
              <bitOffset>14</bitOffset>
              <bitWidth>1</bitWidth>
            </field>
            <field>
              <name>FB15</name>
              <bitOffset>15</bitOffset>
              <bitWidth>1</bitWidth>
            </field>
            <field>
              <name>FB16</name>
              <bitOffset>16</bitOffset>
              <bitWidth>1</bitWidth>
            </field>
            <field>
              <name>FB17</name>
              <bitOffset>17</bitOffset>
              <bitWidth>1</bitWidth>
            </field>
            <field>
              <name>FB18</name>
              <bitOffset>18</bitOffset>
              <bitWidth>1</bitWidth>
            </field>
            <field>
              <name>FB19</name>
              <bitOffset>19</bitOffset>
              <bitWidth>1</bitWidth>
            </field>
            <field>
              <name>FB20</name>
              <bitOffset>20</bitOffset>
              <bitWidth>1</bitWidth>
            </field>
            <field>
              <name>FB21</name>
              <bitOffset>21</bitOffset>
              <bitWidth>1</bitWidth>
            </field>
            <field>
              <name>FB22</name>
              <bitOffset>22</bitOffset>
              <bitWidth>1</bitWidth>
            </field>
            <field>
              <name>FB23</name>
              <bitOffset>23</bitOffset>
              <bitWidth>1</bitWidth>
            </field>
            <field>
              <name>FB24</name>
              <bitOffset>24</bitOffset>
              <bitWidth>1</bitWidth>
            </field>
            <field>
              <name>FB25</name>
              <bitOffset>25</bitOffset>
              <bitWidth>1</bitWidth>
            </field>
            <field>
              <name>FB26</name>
              <bitOffset>26</bitOffset>
              <bitWidth>1</bitWidth>
            </field>
            <field>
              <name>FB27</name>
              <bitOffset>27</bitOffset>
              <bitWidth>1</bitWidth>
            </field>
            <field>
              <name>FB28</name>
              <bitOffset>28</bitOffset>
              <bitWidth>1</bitWidth>
            </field>
            <field>
              <name>FB29</name>
              <bitOffset>29</bitOffset>
              <bitWidth>1</bitWidth>
            </field>
            <field>
              <name>FB30</name>
              <bitOffset>30</bitOffset>
              <bitWidth>1</bitWidth>
            </field>
            <field>
              <name>FB31</name>
              <bitOffset>31</bitOffset>
              <bitWidth>1</bitWidth>
            </field>
          </fields>
        </register>
        <register>
          <name>sFilterRegister.2.FR1</name>
          <addressOffset>0x250</addressOffset>
          <size>0x20</size>
          <fields>
            <field>
              <name>FB0</name>
              <bitOffset>0</bitOffset>
              <bitWidth>1</bitWidth>
            </field>
            <field>
              <name>FB1</name>
              <bitOffset>1</bitOffset>
              <bitWidth>1</bitWidth>
            </field>
            <field>
              <name>FB2</name>
              <bitOffset>2</bitOffset>
              <bitWidth>1</bitWidth>
            </field>
            <field>
              <name>FB3</name>
              <bitOffset>3</bitOffset>
              <bitWidth>1</bitWidth>
            </field>
            <field>
              <name>FB4</name>
              <bitOffset>4</bitOffset>
              <bitWidth>1</bitWidth>
            </field>
            <field>
              <name>FB5</name>
              <bitOffset>5</bitOffset>
              <bitWidth>1</bitWidth>
            </field>
            <field>
              <name>FB6</name>
              <bitOffset>6</bitOffset>
              <bitWidth>1</bitWidth>
            </field>
            <field>
              <name>FB7</name>
              <bitOffset>7</bitOffset>
              <bitWidth>1</bitWidth>
            </field>
            <field>
              <name>FB8</name>
              <bitOffset>8</bitOffset>
              <bitWidth>1</bitWidth>
            </field>
            <field>
              <name>FB9</name>
              <bitOffset>9</bitOffset>
              <bitWidth>1</bitWidth>
            </field>
            <field>
              <name>FB10</name>
              <bitOffset>10</bitOffset>
              <bitWidth>1</bitWidth>
            </field>
            <field>
              <name>FB11</name>
              <bitOffset>11</bitOffset>
              <bitWidth>1</bitWidth>
            </field>
            <field>
              <name>FB12</name>
              <bitOffset>12</bitOffset>
              <bitWidth>1</bitWidth>
            </field>
            <field>
              <name>FB13</name>
              <bitOffset>13</bitOffset>
              <bitWidth>1</bitWidth>
            </field>
            <field>
              <name>FB14</name>
              <bitOffset>14</bitOffset>
              <bitWidth>1</bitWidth>
            </field>
            <field>
              <name>FB15</name>
              <bitOffset>15</bitOffset>
              <bitWidth>1</bitWidth>
            </field>
            <field>
              <name>FB16</name>
              <bitOffset>16</bitOffset>
              <bitWidth>1</bitWidth>
            </field>
            <field>
              <name>FB17</name>
              <bitOffset>17</bitOffset>
              <bitWidth>1</bitWidth>
            </field>
            <field>
              <name>FB18</name>
              <bitOffset>18</bitOffset>
              <bitWidth>1</bitWidth>
            </field>
            <field>
              <name>FB19</name>
              <bitOffset>19</bitOffset>
              <bitWidth>1</bitWidth>
            </field>
            <field>
              <name>FB20</name>
              <bitOffset>20</bitOffset>
              <bitWidth>1</bitWidth>
            </field>
            <field>
              <name>FB21</name>
              <bitOffset>21</bitOffset>
              <bitWidth>1</bitWidth>
            </field>
            <field>
              <name>FB22</name>
              <bitOffset>22</bitOffset>
              <bitWidth>1</bitWidth>
            </field>
            <field>
              <name>FB23</name>
              <bitOffset>23</bitOffset>
              <bitWidth>1</bitWidth>
            </field>
            <field>
              <name>FB24</name>
              <bitOffset>24</bitOffset>
              <bitWidth>1</bitWidth>
            </field>
            <field>
              <name>FB25</name>
              <bitOffset>25</bitOffset>
              <bitWidth>1</bitWidth>
            </field>
            <field>
              <name>FB26</name>
              <bitOffset>26</bitOffset>
              <bitWidth>1</bitWidth>
            </field>
            <field>
              <name>FB27</name>
              <bitOffset>27</bitOffset>
              <bitWidth>1</bitWidth>
            </field>
            <field>
              <name>FB28</name>
              <bitOffset>28</bitOffset>
              <bitWidth>1</bitWidth>
            </field>
            <field>
              <name>FB29</name>
              <bitOffset>29</bitOffset>
              <bitWidth>1</bitWidth>
            </field>
            <field>
              <name>FB30</name>
              <bitOffset>30</bitOffset>
              <bitWidth>1</bitWidth>
            </field>
            <field>
              <name>FB31</name>
              <bitOffset>31</bitOffset>
              <bitWidth>1</bitWidth>
            </field>
          </fields>
        </register>
        <register>
          <name>sFilterRegister.2.FR2</name>
          <addressOffset>0x254</addressOffset>
          <size>0x20</size>
          <fields>
            <field>
              <name>FB0</name>
              <bitOffset>0</bitOffset>
              <bitWidth>1</bitWidth>
            </field>
            <field>
              <name>FB1</name>
              <bitOffset>1</bitOffset>
              <bitWidth>1</bitWidth>
            </field>
            <field>
              <name>FB2</name>
              <bitOffset>2</bitOffset>
              <bitWidth>1</bitWidth>
            </field>
            <field>
              <name>FB3</name>
              <bitOffset>3</bitOffset>
              <bitWidth>1</bitWidth>
            </field>
            <field>
              <name>FB4</name>
              <bitOffset>4</bitOffset>
              <bitWidth>1</bitWidth>
            </field>
            <field>
              <name>FB5</name>
              <bitOffset>5</bitOffset>
              <bitWidth>1</bitWidth>
            </field>
            <field>
              <name>FB6</name>
              <bitOffset>6</bitOffset>
              <bitWidth>1</bitWidth>
            </field>
            <field>
              <name>FB7</name>
              <bitOffset>7</bitOffset>
              <bitWidth>1</bitWidth>
            </field>
            <field>
              <name>FB8</name>
              <bitOffset>8</bitOffset>
              <bitWidth>1</bitWidth>
            </field>
            <field>
              <name>FB9</name>
              <bitOffset>9</bitOffset>
              <bitWidth>1</bitWidth>
            </field>
            <field>
              <name>FB10</name>
              <bitOffset>10</bitOffset>
              <bitWidth>1</bitWidth>
            </field>
            <field>
              <name>FB11</name>
              <bitOffset>11</bitOffset>
              <bitWidth>1</bitWidth>
            </field>
            <field>
              <name>FB12</name>
              <bitOffset>12</bitOffset>
              <bitWidth>1</bitWidth>
            </field>
            <field>
              <name>FB13</name>
              <bitOffset>13</bitOffset>
              <bitWidth>1</bitWidth>
            </field>
            <field>
              <name>FB14</name>
              <bitOffset>14</bitOffset>
              <bitWidth>1</bitWidth>
            </field>
            <field>
              <name>FB15</name>
              <bitOffset>15</bitOffset>
              <bitWidth>1</bitWidth>
            </field>
            <field>
              <name>FB16</name>
              <bitOffset>16</bitOffset>
              <bitWidth>1</bitWidth>
            </field>
            <field>
              <name>FB17</name>
              <bitOffset>17</bitOffset>
              <bitWidth>1</bitWidth>
            </field>
            <field>
              <name>FB18</name>
              <bitOffset>18</bitOffset>
              <bitWidth>1</bitWidth>
            </field>
            <field>
              <name>FB19</name>
              <bitOffset>19</bitOffset>
              <bitWidth>1</bitWidth>
            </field>
            <field>
              <name>FB20</name>
              <bitOffset>20</bitOffset>
              <bitWidth>1</bitWidth>
            </field>
            <field>
              <name>FB21</name>
              <bitOffset>21</bitOffset>
              <bitWidth>1</bitWidth>
            </field>
            <field>
              <name>FB22</name>
              <bitOffset>22</bitOffset>
              <bitWidth>1</bitWidth>
            </field>
            <field>
              <name>FB23</name>
              <bitOffset>23</bitOffset>
              <bitWidth>1</bitWidth>
            </field>
            <field>
              <name>FB24</name>
              <bitOffset>24</bitOffset>
              <bitWidth>1</bitWidth>
            </field>
            <field>
              <name>FB25</name>
              <bitOffset>25</bitOffset>
              <bitWidth>1</bitWidth>
            </field>
            <field>
              <name>FB26</name>
              <bitOffset>26</bitOffset>
              <bitWidth>1</bitWidth>
            </field>
            <field>
              <name>FB27</name>
              <bitOffset>27</bitOffset>
              <bitWidth>1</bitWidth>
            </field>
            <field>
              <name>FB28</name>
              <bitOffset>28</bitOffset>
              <bitWidth>1</bitWidth>
            </field>
            <field>
              <name>FB29</name>
              <bitOffset>29</bitOffset>
              <bitWidth>1</bitWidth>
            </field>
            <field>
              <name>FB30</name>
              <bitOffset>30</bitOffset>
              <bitWidth>1</bitWidth>
            </field>
            <field>
              <name>FB31</name>
              <bitOffset>31</bitOffset>
              <bitWidth>1</bitWidth>
            </field>
          </fields>
        </register>
        <register>
          <name>sFilterRegister.3.FR1</name>
          <addressOffset>0x258</addressOffset>
          <size>0x20</size>
          <fields>
            <field>
              <name>FB0</name>
              <bitOffset>0</bitOffset>
              <bitWidth>1</bitWidth>
            </field>
            <field>
              <name>FB1</name>
              <bitOffset>1</bitOffset>
              <bitWidth>1</bitWidth>
            </field>
            <field>
              <name>FB2</name>
              <bitOffset>2</bitOffset>
              <bitWidth>1</bitWidth>
            </field>
            <field>
              <name>FB3</name>
              <bitOffset>3</bitOffset>
              <bitWidth>1</bitWidth>
            </field>
            <field>
              <name>FB4</name>
              <bitOffset>4</bitOffset>
              <bitWidth>1</bitWidth>
            </field>
            <field>
              <name>FB5</name>
              <bitOffset>5</bitOffset>
              <bitWidth>1</bitWidth>
            </field>
            <field>
              <name>FB6</name>
              <bitOffset>6</bitOffset>
              <bitWidth>1</bitWidth>
            </field>
            <field>
              <name>FB7</name>
              <bitOffset>7</bitOffset>
              <bitWidth>1</bitWidth>
            </field>
            <field>
              <name>FB8</name>
              <bitOffset>8</bitOffset>
              <bitWidth>1</bitWidth>
            </field>
            <field>
              <name>FB9</name>
              <bitOffset>9</bitOffset>
              <bitWidth>1</bitWidth>
            </field>
            <field>
              <name>FB10</name>
              <bitOffset>10</bitOffset>
              <bitWidth>1</bitWidth>
            </field>
            <field>
              <name>FB11</name>
              <bitOffset>11</bitOffset>
              <bitWidth>1</bitWidth>
            </field>
            <field>
              <name>FB12</name>
              <bitOffset>12</bitOffset>
              <bitWidth>1</bitWidth>
            </field>
            <field>
              <name>FB13</name>
              <bitOffset>13</bitOffset>
              <bitWidth>1</bitWidth>
            </field>
            <field>
              <name>FB14</name>
              <bitOffset>14</bitOffset>
              <bitWidth>1</bitWidth>
            </field>
            <field>
              <name>FB15</name>
              <bitOffset>15</bitOffset>
              <bitWidth>1</bitWidth>
            </field>
            <field>
              <name>FB16</name>
              <bitOffset>16</bitOffset>
              <bitWidth>1</bitWidth>
            </field>
            <field>
              <name>FB17</name>
              <bitOffset>17</bitOffset>
              <bitWidth>1</bitWidth>
            </field>
            <field>
              <name>FB18</name>
              <bitOffset>18</bitOffset>
              <bitWidth>1</bitWidth>
            </field>
            <field>
              <name>FB19</name>
              <bitOffset>19</bitOffset>
              <bitWidth>1</bitWidth>
            </field>
            <field>
              <name>FB20</name>
              <bitOffset>20</bitOffset>
              <bitWidth>1</bitWidth>
            </field>
            <field>
              <name>FB21</name>
              <bitOffset>21</bitOffset>
              <bitWidth>1</bitWidth>
            </field>
            <field>
              <name>FB22</name>
              <bitOffset>22</bitOffset>
              <bitWidth>1</bitWidth>
            </field>
            <field>
              <name>FB23</name>
              <bitOffset>23</bitOffset>
              <bitWidth>1</bitWidth>
            </field>
            <field>
              <name>FB24</name>
              <bitOffset>24</bitOffset>
              <bitWidth>1</bitWidth>
            </field>
            <field>
              <name>FB25</name>
              <bitOffset>25</bitOffset>
              <bitWidth>1</bitWidth>
            </field>
            <field>
              <name>FB26</name>
              <bitOffset>26</bitOffset>
              <bitWidth>1</bitWidth>
            </field>
            <field>
              <name>FB27</name>
              <bitOffset>27</bitOffset>
              <bitWidth>1</bitWidth>
            </field>
            <field>
              <name>FB28</name>
              <bitOffset>28</bitOffset>
              <bitWidth>1</bitWidth>
            </field>
            <field>
              <name>FB29</name>
              <bitOffset>29</bitOffset>
              <bitWidth>1</bitWidth>
            </field>
            <field>
              <name>FB30</name>
              <bitOffset>30</bitOffset>
              <bitWidth>1</bitWidth>
            </field>
            <field>
              <name>FB31</name>
              <bitOffset>31</bitOffset>
              <bitWidth>1</bitWidth>
            </field>
          </fields>
        </register>
        <register>
          <name>sFilterRegister.3.FR2</name>
          <addressOffset>0x25c</addressOffset>
          <size>0x20</size>
          <fields>
            <field>
              <name>FB0</name>
              <bitOffset>0</bitOffset>
              <bitWidth>1</bitWidth>
            </field>
            <field>
              <name>FB1</name>
              <bitOffset>1</bitOffset>
              <bitWidth>1</bitWidth>
            </field>
            <field>
              <name>FB2</name>
              <bitOffset>2</bitOffset>
              <bitWidth>1</bitWidth>
            </field>
            <field>
              <name>FB3</name>
              <bitOffset>3</bitOffset>
              <bitWidth>1</bitWidth>
            </field>
            <field>
              <name>FB4</name>
              <bitOffset>4</bitOffset>
              <bitWidth>1</bitWidth>
            </field>
            <field>
              <name>FB5</name>
              <bitOffset>5</bitOffset>
              <bitWidth>1</bitWidth>
            </field>
            <field>
              <name>FB6</name>
              <bitOffset>6</bitOffset>
              <bitWidth>1</bitWidth>
            </field>
            <field>
              <name>FB7</name>
              <bitOffset>7</bitOffset>
              <bitWidth>1</bitWidth>
            </field>
            <field>
              <name>FB8</name>
              <bitOffset>8</bitOffset>
              <bitWidth>1</bitWidth>
            </field>
            <field>
              <name>FB9</name>
              <bitOffset>9</bitOffset>
              <bitWidth>1</bitWidth>
            </field>
            <field>
              <name>FB10</name>
              <bitOffset>10</bitOffset>
              <bitWidth>1</bitWidth>
            </field>
            <field>
              <name>FB11</name>
              <bitOffset>11</bitOffset>
              <bitWidth>1</bitWidth>
            </field>
            <field>
              <name>FB12</name>
              <bitOffset>12</bitOffset>
              <bitWidth>1</bitWidth>
            </field>
            <field>
              <name>FB13</name>
              <bitOffset>13</bitOffset>
              <bitWidth>1</bitWidth>
            </field>
            <field>
              <name>FB14</name>
              <bitOffset>14</bitOffset>
              <bitWidth>1</bitWidth>
            </field>
            <field>
              <name>FB15</name>
              <bitOffset>15</bitOffset>
              <bitWidth>1</bitWidth>
            </field>
            <field>
              <name>FB16</name>
              <bitOffset>16</bitOffset>
              <bitWidth>1</bitWidth>
            </field>
            <field>
              <name>FB17</name>
              <bitOffset>17</bitOffset>
              <bitWidth>1</bitWidth>
            </field>
            <field>
              <name>FB18</name>
              <bitOffset>18</bitOffset>
              <bitWidth>1</bitWidth>
            </field>
            <field>
              <name>FB19</name>
              <bitOffset>19</bitOffset>
              <bitWidth>1</bitWidth>
            </field>
            <field>
              <name>FB20</name>
              <bitOffset>20</bitOffset>
              <bitWidth>1</bitWidth>
            </field>
            <field>
              <name>FB21</name>
              <bitOffset>21</bitOffset>
              <bitWidth>1</bitWidth>
            </field>
            <field>
              <name>FB22</name>
              <bitOffset>22</bitOffset>
              <bitWidth>1</bitWidth>
            </field>
            <field>
              <name>FB23</name>
              <bitOffset>23</bitOffset>
              <bitWidth>1</bitWidth>
            </field>
            <field>
              <name>FB24</name>
              <bitOffset>24</bitOffset>
              <bitWidth>1</bitWidth>
            </field>
            <field>
              <name>FB25</name>
              <bitOffset>25</bitOffset>
              <bitWidth>1</bitWidth>
            </field>
            <field>
              <name>FB26</name>
              <bitOffset>26</bitOffset>
              <bitWidth>1</bitWidth>
            </field>
            <field>
              <name>FB27</name>
              <bitOffset>27</bitOffset>
              <bitWidth>1</bitWidth>
            </field>
            <field>
              <name>FB28</name>
              <bitOffset>28</bitOffset>
              <bitWidth>1</bitWidth>
            </field>
            <field>
              <name>FB29</name>
              <bitOffset>29</bitOffset>
              <bitWidth>1</bitWidth>
            </field>
            <field>
              <name>FB30</name>
              <bitOffset>30</bitOffset>
              <bitWidth>1</bitWidth>
            </field>
            <field>
              <name>FB31</name>
              <bitOffset>31</bitOffset>
              <bitWidth>1</bitWidth>
            </field>
          </fields>
        </register>
        <register>
          <name>sFilterRegister.4.FR1</name>
          <addressOffset>0x260</addressOffset>
          <size>0x20</size>
          <fields>
            <field>
              <name>FB0</name>
              <bitOffset>0</bitOffset>
              <bitWidth>1</bitWidth>
            </field>
            <field>
              <name>FB1</name>
              <bitOffset>1</bitOffset>
              <bitWidth>1</bitWidth>
            </field>
            <field>
              <name>FB2</name>
              <bitOffset>2</bitOffset>
              <bitWidth>1</bitWidth>
            </field>
            <field>
              <name>FB3</name>
              <bitOffset>3</bitOffset>
              <bitWidth>1</bitWidth>
            </field>
            <field>
              <name>FB4</name>
              <bitOffset>4</bitOffset>
              <bitWidth>1</bitWidth>
            </field>
            <field>
              <name>FB5</name>
              <bitOffset>5</bitOffset>
              <bitWidth>1</bitWidth>
            </field>
            <field>
              <name>FB6</name>
              <bitOffset>6</bitOffset>
              <bitWidth>1</bitWidth>
            </field>
            <field>
              <name>FB7</name>
              <bitOffset>7</bitOffset>
              <bitWidth>1</bitWidth>
            </field>
            <field>
              <name>FB8</name>
              <bitOffset>8</bitOffset>
              <bitWidth>1</bitWidth>
            </field>
            <field>
              <name>FB9</name>
              <bitOffset>9</bitOffset>
              <bitWidth>1</bitWidth>
            </field>
            <field>
              <name>FB10</name>
              <bitOffset>10</bitOffset>
              <bitWidth>1</bitWidth>
            </field>
            <field>
              <name>FB11</name>
              <bitOffset>11</bitOffset>
              <bitWidth>1</bitWidth>
            </field>
            <field>
              <name>FB12</name>
              <bitOffset>12</bitOffset>
              <bitWidth>1</bitWidth>
            </field>
            <field>
              <name>FB13</name>
              <bitOffset>13</bitOffset>
              <bitWidth>1</bitWidth>
            </field>
            <field>
              <name>FB14</name>
              <bitOffset>14</bitOffset>
              <bitWidth>1</bitWidth>
            </field>
            <field>
              <name>FB15</name>
              <bitOffset>15</bitOffset>
              <bitWidth>1</bitWidth>
            </field>
            <field>
              <name>FB16</name>
              <bitOffset>16</bitOffset>
              <bitWidth>1</bitWidth>
            </field>
            <field>
              <name>FB17</name>
              <bitOffset>17</bitOffset>
              <bitWidth>1</bitWidth>
            </field>
            <field>
              <name>FB18</name>
              <bitOffset>18</bitOffset>
              <bitWidth>1</bitWidth>
            </field>
            <field>
              <name>FB19</name>
              <bitOffset>19</bitOffset>
              <bitWidth>1</bitWidth>
            </field>
            <field>
              <name>FB20</name>
              <bitOffset>20</bitOffset>
              <bitWidth>1</bitWidth>
            </field>
            <field>
              <name>FB21</name>
              <bitOffset>21</bitOffset>
              <bitWidth>1</bitWidth>
            </field>
            <field>
              <name>FB22</name>
              <bitOffset>22</bitOffset>
              <bitWidth>1</bitWidth>
            </field>
            <field>
              <name>FB23</name>
              <bitOffset>23</bitOffset>
              <bitWidth>1</bitWidth>
            </field>
            <field>
              <name>FB24</name>
              <bitOffset>24</bitOffset>
              <bitWidth>1</bitWidth>
            </field>
            <field>
              <name>FB25</name>
              <bitOffset>25</bitOffset>
              <bitWidth>1</bitWidth>
            </field>
            <field>
              <name>FB26</name>
              <bitOffset>26</bitOffset>
              <bitWidth>1</bitWidth>
            </field>
            <field>
              <name>FB27</name>
              <bitOffset>27</bitOffset>
              <bitWidth>1</bitWidth>
            </field>
            <field>
              <name>FB28</name>
              <bitOffset>28</bitOffset>
              <bitWidth>1</bitWidth>
            </field>
            <field>
              <name>FB29</name>
              <bitOffset>29</bitOffset>
              <bitWidth>1</bitWidth>
            </field>
            <field>
              <name>FB30</name>
              <bitOffset>30</bitOffset>
              <bitWidth>1</bitWidth>
            </field>
            <field>
              <name>FB31</name>
              <bitOffset>31</bitOffset>
              <bitWidth>1</bitWidth>
            </field>
          </fields>
        </register>
        <register>
          <name>sFilterRegister.4.FR2</name>
          <addressOffset>0x264</addressOffset>
          <size>0x20</size>
          <fields>
            <field>
              <name>FB0</name>
              <bitOffset>0</bitOffset>
              <bitWidth>1</bitWidth>
            </field>
            <field>
              <name>FB1</name>
              <bitOffset>1</bitOffset>
              <bitWidth>1</bitWidth>
            </field>
            <field>
              <name>FB2</name>
              <bitOffset>2</bitOffset>
              <bitWidth>1</bitWidth>
            </field>
            <field>
              <name>FB3</name>
              <bitOffset>3</bitOffset>
              <bitWidth>1</bitWidth>
            </field>
            <field>
              <name>FB4</name>
              <bitOffset>4</bitOffset>
              <bitWidth>1</bitWidth>
            </field>
            <field>
              <name>FB5</name>
              <bitOffset>5</bitOffset>
              <bitWidth>1</bitWidth>
            </field>
            <field>
              <name>FB6</name>
              <bitOffset>6</bitOffset>
              <bitWidth>1</bitWidth>
            </field>
            <field>
              <name>FB7</name>
              <bitOffset>7</bitOffset>
              <bitWidth>1</bitWidth>
            </field>
            <field>
              <name>FB8</name>
              <bitOffset>8</bitOffset>
              <bitWidth>1</bitWidth>
            </field>
            <field>
              <name>FB9</name>
              <bitOffset>9</bitOffset>
              <bitWidth>1</bitWidth>
            </field>
            <field>
              <name>FB10</name>
              <bitOffset>10</bitOffset>
              <bitWidth>1</bitWidth>
            </field>
            <field>
              <name>FB11</name>
              <bitOffset>11</bitOffset>
              <bitWidth>1</bitWidth>
            </field>
            <field>
              <name>FB12</name>
              <bitOffset>12</bitOffset>
              <bitWidth>1</bitWidth>
            </field>
            <field>
              <name>FB13</name>
              <bitOffset>13</bitOffset>
              <bitWidth>1</bitWidth>
            </field>
            <field>
              <name>FB14</name>
              <bitOffset>14</bitOffset>
              <bitWidth>1</bitWidth>
            </field>
            <field>
              <name>FB15</name>
              <bitOffset>15</bitOffset>
              <bitWidth>1</bitWidth>
            </field>
            <field>
              <name>FB16</name>
              <bitOffset>16</bitOffset>
              <bitWidth>1</bitWidth>
            </field>
            <field>
              <name>FB17</name>
              <bitOffset>17</bitOffset>
              <bitWidth>1</bitWidth>
            </field>
            <field>
              <name>FB18</name>
              <bitOffset>18</bitOffset>
              <bitWidth>1</bitWidth>
            </field>
            <field>
              <name>FB19</name>
              <bitOffset>19</bitOffset>
              <bitWidth>1</bitWidth>
            </field>
            <field>
              <name>FB20</name>
              <bitOffset>20</bitOffset>
              <bitWidth>1</bitWidth>
            </field>
            <field>
              <name>FB21</name>
              <bitOffset>21</bitOffset>
              <bitWidth>1</bitWidth>
            </field>
            <field>
              <name>FB22</name>
              <bitOffset>22</bitOffset>
              <bitWidth>1</bitWidth>
            </field>
            <field>
              <name>FB23</name>
              <bitOffset>23</bitOffset>
              <bitWidth>1</bitWidth>
            </field>
            <field>
              <name>FB24</name>
              <bitOffset>24</bitOffset>
              <bitWidth>1</bitWidth>
            </field>
            <field>
              <name>FB25</name>
              <bitOffset>25</bitOffset>
              <bitWidth>1</bitWidth>
            </field>
            <field>
              <name>FB26</name>
              <bitOffset>26</bitOffset>
              <bitWidth>1</bitWidth>
            </field>
            <field>
              <name>FB27</name>
              <bitOffset>27</bitOffset>
              <bitWidth>1</bitWidth>
            </field>
            <field>
              <name>FB28</name>
              <bitOffset>28</bitOffset>
              <bitWidth>1</bitWidth>
            </field>
            <field>
              <name>FB29</name>
              <bitOffset>29</bitOffset>
              <bitWidth>1</bitWidth>
            </field>
            <field>
              <name>FB30</name>
              <bitOffset>30</bitOffset>
              <bitWidth>1</bitWidth>
            </field>
            <field>
              <name>FB31</name>
              <bitOffset>31</bitOffset>
              <bitWidth>1</bitWidth>
            </field>
          </fields>
        </register>
        <register>
          <name>sFilterRegister.5.FR1</name>
          <addressOffset>0x268</addressOffset>
          <size>0x20</size>
          <fields>
            <field>
              <name>FB0</name>
              <bitOffset>0</bitOffset>
              <bitWidth>1</bitWidth>
            </field>
            <field>
              <name>FB1</name>
              <bitOffset>1</bitOffset>
              <bitWidth>1</bitWidth>
            </field>
            <field>
              <name>FB2</name>
              <bitOffset>2</bitOffset>
              <bitWidth>1</bitWidth>
            </field>
            <field>
              <name>FB3</name>
              <bitOffset>3</bitOffset>
              <bitWidth>1</bitWidth>
            </field>
            <field>
              <name>FB4</name>
              <bitOffset>4</bitOffset>
              <bitWidth>1</bitWidth>
            </field>
            <field>
              <name>FB5</name>
              <bitOffset>5</bitOffset>
              <bitWidth>1</bitWidth>
            </field>
            <field>
              <name>FB6</name>
              <bitOffset>6</bitOffset>
              <bitWidth>1</bitWidth>
            </field>
            <field>
              <name>FB7</name>
              <bitOffset>7</bitOffset>
              <bitWidth>1</bitWidth>
            </field>
            <field>
              <name>FB8</name>
              <bitOffset>8</bitOffset>
              <bitWidth>1</bitWidth>
            </field>
            <field>
              <name>FB9</name>
              <bitOffset>9</bitOffset>
              <bitWidth>1</bitWidth>
            </field>
            <field>
              <name>FB10</name>
              <bitOffset>10</bitOffset>
              <bitWidth>1</bitWidth>
            </field>
            <field>
              <name>FB11</name>
              <bitOffset>11</bitOffset>
              <bitWidth>1</bitWidth>
            </field>
            <field>
              <name>FB12</name>
              <bitOffset>12</bitOffset>
              <bitWidth>1</bitWidth>
            </field>
            <field>
              <name>FB13</name>
              <bitOffset>13</bitOffset>
              <bitWidth>1</bitWidth>
            </field>
            <field>
              <name>FB14</name>
              <bitOffset>14</bitOffset>
              <bitWidth>1</bitWidth>
            </field>
            <field>
              <name>FB15</name>
              <bitOffset>15</bitOffset>
              <bitWidth>1</bitWidth>
            </field>
            <field>
              <name>FB16</name>
              <bitOffset>16</bitOffset>
              <bitWidth>1</bitWidth>
            </field>
            <field>
              <name>FB17</name>
              <bitOffset>17</bitOffset>
              <bitWidth>1</bitWidth>
            </field>
            <field>
              <name>FB18</name>
              <bitOffset>18</bitOffset>
              <bitWidth>1</bitWidth>
            </field>
            <field>
              <name>FB19</name>
              <bitOffset>19</bitOffset>
              <bitWidth>1</bitWidth>
            </field>
            <field>
              <name>FB20</name>
              <bitOffset>20</bitOffset>
              <bitWidth>1</bitWidth>
            </field>
            <field>
              <name>FB21</name>
              <bitOffset>21</bitOffset>
              <bitWidth>1</bitWidth>
            </field>
            <field>
              <name>FB22</name>
              <bitOffset>22</bitOffset>
              <bitWidth>1</bitWidth>
            </field>
            <field>
              <name>FB23</name>
              <bitOffset>23</bitOffset>
              <bitWidth>1</bitWidth>
            </field>
            <field>
              <name>FB24</name>
              <bitOffset>24</bitOffset>
              <bitWidth>1</bitWidth>
            </field>
            <field>
              <name>FB25</name>
              <bitOffset>25</bitOffset>
              <bitWidth>1</bitWidth>
            </field>
            <field>
              <name>FB26</name>
              <bitOffset>26</bitOffset>
              <bitWidth>1</bitWidth>
            </field>
            <field>
              <name>FB27</name>
              <bitOffset>27</bitOffset>
              <bitWidth>1</bitWidth>
            </field>
            <field>
              <name>FB28</name>
              <bitOffset>28</bitOffset>
              <bitWidth>1</bitWidth>
            </field>
            <field>
              <name>FB29</name>
              <bitOffset>29</bitOffset>
              <bitWidth>1</bitWidth>
            </field>
            <field>
              <name>FB30</name>
              <bitOffset>30</bitOffset>
              <bitWidth>1</bitWidth>
            </field>
            <field>
              <name>FB31</name>
              <bitOffset>31</bitOffset>
              <bitWidth>1</bitWidth>
            </field>
          </fields>
        </register>
        <register>
          <name>sFilterRegister.5.FR2</name>
          <addressOffset>0x26c</addressOffset>
          <size>0x20</size>
          <fields>
            <field>
              <name>FB0</name>
              <bitOffset>0</bitOffset>
              <bitWidth>1</bitWidth>
            </field>
            <field>
              <name>FB1</name>
              <bitOffset>1</bitOffset>
              <bitWidth>1</bitWidth>
            </field>
            <field>
              <name>FB2</name>
              <bitOffset>2</bitOffset>
              <bitWidth>1</bitWidth>
            </field>
            <field>
              <name>FB3</name>
              <bitOffset>3</bitOffset>
              <bitWidth>1</bitWidth>
            </field>
            <field>
              <name>FB4</name>
              <bitOffset>4</bitOffset>
              <bitWidth>1</bitWidth>
            </field>
            <field>
              <name>FB5</name>
              <bitOffset>5</bitOffset>
              <bitWidth>1</bitWidth>
            </field>
            <field>
              <name>FB6</name>
              <bitOffset>6</bitOffset>
              <bitWidth>1</bitWidth>
            </field>
            <field>
              <name>FB7</name>
              <bitOffset>7</bitOffset>
              <bitWidth>1</bitWidth>
            </field>
            <field>
              <name>FB8</name>
              <bitOffset>8</bitOffset>
              <bitWidth>1</bitWidth>
            </field>
            <field>
              <name>FB9</name>
              <bitOffset>9</bitOffset>
              <bitWidth>1</bitWidth>
            </field>
            <field>
              <name>FB10</name>
              <bitOffset>10</bitOffset>
              <bitWidth>1</bitWidth>
            </field>
            <field>
              <name>FB11</name>
              <bitOffset>11</bitOffset>
              <bitWidth>1</bitWidth>
            </field>
            <field>
              <name>FB12</name>
              <bitOffset>12</bitOffset>
              <bitWidth>1</bitWidth>
            </field>
            <field>
              <name>FB13</name>
              <bitOffset>13</bitOffset>
              <bitWidth>1</bitWidth>
            </field>
            <field>
              <name>FB14</name>
              <bitOffset>14</bitOffset>
              <bitWidth>1</bitWidth>
            </field>
            <field>
              <name>FB15</name>
              <bitOffset>15</bitOffset>
              <bitWidth>1</bitWidth>
            </field>
            <field>
              <name>FB16</name>
              <bitOffset>16</bitOffset>
              <bitWidth>1</bitWidth>
            </field>
            <field>
              <name>FB17</name>
              <bitOffset>17</bitOffset>
              <bitWidth>1</bitWidth>
            </field>
            <field>
              <name>FB18</name>
              <bitOffset>18</bitOffset>
              <bitWidth>1</bitWidth>
            </field>
            <field>
              <name>FB19</name>
              <bitOffset>19</bitOffset>
              <bitWidth>1</bitWidth>
            </field>
            <field>
              <name>FB20</name>
              <bitOffset>20</bitOffset>
              <bitWidth>1</bitWidth>
            </field>
            <field>
              <name>FB21</name>
              <bitOffset>21</bitOffset>
              <bitWidth>1</bitWidth>
            </field>
            <field>
              <name>FB22</name>
              <bitOffset>22</bitOffset>
              <bitWidth>1</bitWidth>
            </field>
            <field>
              <name>FB23</name>
              <bitOffset>23</bitOffset>
              <bitWidth>1</bitWidth>
            </field>
            <field>
              <name>FB24</name>
              <bitOffset>24</bitOffset>
              <bitWidth>1</bitWidth>
            </field>
            <field>
              <name>FB25</name>
              <bitOffset>25</bitOffset>
              <bitWidth>1</bitWidth>
            </field>
            <field>
              <name>FB26</name>
              <bitOffset>26</bitOffset>
              <bitWidth>1</bitWidth>
            </field>
            <field>
              <name>FB27</name>
              <bitOffset>27</bitOffset>
              <bitWidth>1</bitWidth>
            </field>
            <field>
              <name>FB28</name>
              <bitOffset>28</bitOffset>
              <bitWidth>1</bitWidth>
            </field>
            <field>
              <name>FB29</name>
              <bitOffset>29</bitOffset>
              <bitWidth>1</bitWidth>
            </field>
            <field>
              <name>FB30</name>
              <bitOffset>30</bitOffset>
              <bitWidth>1</bitWidth>
            </field>
            <field>
              <name>FB31</name>
              <bitOffset>31</bitOffset>
              <bitWidth>1</bitWidth>
            </field>
          </fields>
        </register>
        <register>
          <name>sFilterRegister.6.FR1</name>
          <addressOffset>0x270</addressOffset>
          <size>0x20</size>
          <fields>
            <field>
              <name>FB0</name>
              <bitOffset>0</bitOffset>
              <bitWidth>1</bitWidth>
            </field>
            <field>
              <name>FB1</name>
              <bitOffset>1</bitOffset>
              <bitWidth>1</bitWidth>
            </field>
            <field>
              <name>FB2</name>
              <bitOffset>2</bitOffset>
              <bitWidth>1</bitWidth>
            </field>
            <field>
              <name>FB3</name>
              <bitOffset>3</bitOffset>
              <bitWidth>1</bitWidth>
            </field>
            <field>
              <name>FB4</name>
              <bitOffset>4</bitOffset>
              <bitWidth>1</bitWidth>
            </field>
            <field>
              <name>FB5</name>
              <bitOffset>5</bitOffset>
              <bitWidth>1</bitWidth>
            </field>
            <field>
              <name>FB6</name>
              <bitOffset>6</bitOffset>
              <bitWidth>1</bitWidth>
            </field>
            <field>
              <name>FB7</name>
              <bitOffset>7</bitOffset>
              <bitWidth>1</bitWidth>
            </field>
            <field>
              <name>FB8</name>
              <bitOffset>8</bitOffset>
              <bitWidth>1</bitWidth>
            </field>
            <field>
              <name>FB9</name>
              <bitOffset>9</bitOffset>
              <bitWidth>1</bitWidth>
            </field>
            <field>
              <name>FB10</name>
              <bitOffset>10</bitOffset>
              <bitWidth>1</bitWidth>
            </field>
            <field>
              <name>FB11</name>
              <bitOffset>11</bitOffset>
              <bitWidth>1</bitWidth>
            </field>
            <field>
              <name>FB12</name>
              <bitOffset>12</bitOffset>
              <bitWidth>1</bitWidth>
            </field>
            <field>
              <name>FB13</name>
              <bitOffset>13</bitOffset>
              <bitWidth>1</bitWidth>
            </field>
            <field>
              <name>FB14</name>
              <bitOffset>14</bitOffset>
              <bitWidth>1</bitWidth>
            </field>
            <field>
              <name>FB15</name>
              <bitOffset>15</bitOffset>
              <bitWidth>1</bitWidth>
            </field>
            <field>
              <name>FB16</name>
              <bitOffset>16</bitOffset>
              <bitWidth>1</bitWidth>
            </field>
            <field>
              <name>FB17</name>
              <bitOffset>17</bitOffset>
              <bitWidth>1</bitWidth>
            </field>
            <field>
              <name>FB18</name>
              <bitOffset>18</bitOffset>
              <bitWidth>1</bitWidth>
            </field>
            <field>
              <name>FB19</name>
              <bitOffset>19</bitOffset>
              <bitWidth>1</bitWidth>
            </field>
            <field>
              <name>FB20</name>
              <bitOffset>20</bitOffset>
              <bitWidth>1</bitWidth>
            </field>
            <field>
              <name>FB21</name>
              <bitOffset>21</bitOffset>
              <bitWidth>1</bitWidth>
            </field>
            <field>
              <name>FB22</name>
              <bitOffset>22</bitOffset>
              <bitWidth>1</bitWidth>
            </field>
            <field>
              <name>FB23</name>
              <bitOffset>23</bitOffset>
              <bitWidth>1</bitWidth>
            </field>
            <field>
              <name>FB24</name>
              <bitOffset>24</bitOffset>
              <bitWidth>1</bitWidth>
            </field>
            <field>
              <name>FB25</name>
              <bitOffset>25</bitOffset>
              <bitWidth>1</bitWidth>
            </field>
            <field>
              <name>FB26</name>
              <bitOffset>26</bitOffset>
              <bitWidth>1</bitWidth>
            </field>
            <field>
              <name>FB27</name>
              <bitOffset>27</bitOffset>
              <bitWidth>1</bitWidth>
            </field>
            <field>
              <name>FB28</name>
              <bitOffset>28</bitOffset>
              <bitWidth>1</bitWidth>
            </field>
            <field>
              <name>FB29</name>
              <bitOffset>29</bitOffset>
              <bitWidth>1</bitWidth>
            </field>
            <field>
              <name>FB30</name>
              <bitOffset>30</bitOffset>
              <bitWidth>1</bitWidth>
            </field>
            <field>
              <name>FB31</name>
              <bitOffset>31</bitOffset>
              <bitWidth>1</bitWidth>
            </field>
          </fields>
        </register>
        <register>
          <name>sFilterRegister.6.FR2</name>
          <addressOffset>0x274</addressOffset>
          <size>0x20</size>
          <fields>
            <field>
              <name>FB0</name>
              <bitOffset>0</bitOffset>
              <bitWidth>1</bitWidth>
            </field>
            <field>
              <name>FB1</name>
              <bitOffset>1</bitOffset>
              <bitWidth>1</bitWidth>
            </field>
            <field>
              <name>FB2</name>
              <bitOffset>2</bitOffset>
              <bitWidth>1</bitWidth>
            </field>
            <field>
              <name>FB3</name>
              <bitOffset>3</bitOffset>
              <bitWidth>1</bitWidth>
            </field>
            <field>
              <name>FB4</name>
              <bitOffset>4</bitOffset>
              <bitWidth>1</bitWidth>
            </field>
            <field>
              <name>FB5</name>
              <bitOffset>5</bitOffset>
              <bitWidth>1</bitWidth>
            </field>
            <field>
              <name>FB6</name>
              <bitOffset>6</bitOffset>
              <bitWidth>1</bitWidth>
            </field>
            <field>
              <name>FB7</name>
              <bitOffset>7</bitOffset>
              <bitWidth>1</bitWidth>
            </field>
            <field>
              <name>FB8</name>
              <bitOffset>8</bitOffset>
              <bitWidth>1</bitWidth>
            </field>
            <field>
              <name>FB9</name>
              <bitOffset>9</bitOffset>
              <bitWidth>1</bitWidth>
            </field>
            <field>
              <name>FB10</name>
              <bitOffset>10</bitOffset>
              <bitWidth>1</bitWidth>
            </field>
            <field>
              <name>FB11</name>
              <bitOffset>11</bitOffset>
              <bitWidth>1</bitWidth>
            </field>
            <field>
              <name>FB12</name>
              <bitOffset>12</bitOffset>
              <bitWidth>1</bitWidth>
            </field>
            <field>
              <name>FB13</name>
              <bitOffset>13</bitOffset>
              <bitWidth>1</bitWidth>
            </field>
            <field>
              <name>FB14</name>
              <bitOffset>14</bitOffset>
              <bitWidth>1</bitWidth>
            </field>
            <field>
              <name>FB15</name>
              <bitOffset>15</bitOffset>
              <bitWidth>1</bitWidth>
            </field>
            <field>
              <name>FB16</name>
              <bitOffset>16</bitOffset>
              <bitWidth>1</bitWidth>
            </field>
            <field>
              <name>FB17</name>
              <bitOffset>17</bitOffset>
              <bitWidth>1</bitWidth>
            </field>
            <field>
              <name>FB18</name>
              <bitOffset>18</bitOffset>
              <bitWidth>1</bitWidth>
            </field>
            <field>
              <name>FB19</name>
              <bitOffset>19</bitOffset>
              <bitWidth>1</bitWidth>
            </field>
            <field>
              <name>FB20</name>
              <bitOffset>20</bitOffset>
              <bitWidth>1</bitWidth>
            </field>
            <field>
              <name>FB21</name>
              <bitOffset>21</bitOffset>
              <bitWidth>1</bitWidth>
            </field>
            <field>
              <name>FB22</name>
              <bitOffset>22</bitOffset>
              <bitWidth>1</bitWidth>
            </field>
            <field>
              <name>FB23</name>
              <bitOffset>23</bitOffset>
              <bitWidth>1</bitWidth>
            </field>
            <field>
              <name>FB24</name>
              <bitOffset>24</bitOffset>
              <bitWidth>1</bitWidth>
            </field>
            <field>
              <name>FB25</name>
              <bitOffset>25</bitOffset>
              <bitWidth>1</bitWidth>
            </field>
            <field>
              <name>FB26</name>
              <bitOffset>26</bitOffset>
              <bitWidth>1</bitWidth>
            </field>
            <field>
              <name>FB27</name>
              <bitOffset>27</bitOffset>
              <bitWidth>1</bitWidth>
            </field>
            <field>
              <name>FB28</name>
              <bitOffset>28</bitOffset>
              <bitWidth>1</bitWidth>
            </field>
            <field>
              <name>FB29</name>
              <bitOffset>29</bitOffset>
              <bitWidth>1</bitWidth>
            </field>
            <field>
              <name>FB30</name>
              <bitOffset>30</bitOffset>
              <bitWidth>1</bitWidth>
            </field>
            <field>
              <name>FB31</name>
              <bitOffset>31</bitOffset>
              <bitWidth>1</bitWidth>
            </field>
          </fields>
        </register>
        <register>
          <name>sFilterRegister.7.FR1</name>
          <addressOffset>0x278</addressOffset>
          <size>0x20</size>
          <fields>
            <field>
              <name>FB0</name>
              <bitOffset>0</bitOffset>
              <bitWidth>1</bitWidth>
            </field>
            <field>
              <name>FB1</name>
              <bitOffset>1</bitOffset>
              <bitWidth>1</bitWidth>
            </field>
            <field>
              <name>FB2</name>
              <bitOffset>2</bitOffset>
              <bitWidth>1</bitWidth>
            </field>
            <field>
              <name>FB3</name>
              <bitOffset>3</bitOffset>
              <bitWidth>1</bitWidth>
            </field>
            <field>
              <name>FB4</name>
              <bitOffset>4</bitOffset>
              <bitWidth>1</bitWidth>
            </field>
            <field>
              <name>FB5</name>
              <bitOffset>5</bitOffset>
              <bitWidth>1</bitWidth>
            </field>
            <field>
              <name>FB6</name>
              <bitOffset>6</bitOffset>
              <bitWidth>1</bitWidth>
            </field>
            <field>
              <name>FB7</name>
              <bitOffset>7</bitOffset>
              <bitWidth>1</bitWidth>
            </field>
            <field>
              <name>FB8</name>
              <bitOffset>8</bitOffset>
              <bitWidth>1</bitWidth>
            </field>
            <field>
              <name>FB9</name>
              <bitOffset>9</bitOffset>
              <bitWidth>1</bitWidth>
            </field>
            <field>
              <name>FB10</name>
              <bitOffset>10</bitOffset>
              <bitWidth>1</bitWidth>
            </field>
            <field>
              <name>FB11</name>
              <bitOffset>11</bitOffset>
              <bitWidth>1</bitWidth>
            </field>
            <field>
              <name>FB12</name>
              <bitOffset>12</bitOffset>
              <bitWidth>1</bitWidth>
            </field>
            <field>
              <name>FB13</name>
              <bitOffset>13</bitOffset>
              <bitWidth>1</bitWidth>
            </field>
            <field>
              <name>FB14</name>
              <bitOffset>14</bitOffset>
              <bitWidth>1</bitWidth>
            </field>
            <field>
              <name>FB15</name>
              <bitOffset>15</bitOffset>
              <bitWidth>1</bitWidth>
            </field>
            <field>
              <name>FB16</name>
              <bitOffset>16</bitOffset>
              <bitWidth>1</bitWidth>
            </field>
            <field>
              <name>FB17</name>
              <bitOffset>17</bitOffset>
              <bitWidth>1</bitWidth>
            </field>
            <field>
              <name>FB18</name>
              <bitOffset>18</bitOffset>
              <bitWidth>1</bitWidth>
            </field>
            <field>
              <name>FB19</name>
              <bitOffset>19</bitOffset>
              <bitWidth>1</bitWidth>
            </field>
            <field>
              <name>FB20</name>
              <bitOffset>20</bitOffset>
              <bitWidth>1</bitWidth>
            </field>
            <field>
              <name>FB21</name>
              <bitOffset>21</bitOffset>
              <bitWidth>1</bitWidth>
            </field>
            <field>
              <name>FB22</name>
              <bitOffset>22</bitOffset>
              <bitWidth>1</bitWidth>
            </field>
            <field>
              <name>FB23</name>
              <bitOffset>23</bitOffset>
              <bitWidth>1</bitWidth>
            </field>
            <field>
              <name>FB24</name>
              <bitOffset>24</bitOffset>
              <bitWidth>1</bitWidth>
            </field>
            <field>
              <name>FB25</name>
              <bitOffset>25</bitOffset>
              <bitWidth>1</bitWidth>
            </field>
            <field>
              <name>FB26</name>
              <bitOffset>26</bitOffset>
              <bitWidth>1</bitWidth>
            </field>
            <field>
              <name>FB27</name>
              <bitOffset>27</bitOffset>
              <bitWidth>1</bitWidth>
            </field>
            <field>
              <name>FB28</name>
              <bitOffset>28</bitOffset>
              <bitWidth>1</bitWidth>
            </field>
            <field>
              <name>FB29</name>
              <bitOffset>29</bitOffset>
              <bitWidth>1</bitWidth>
            </field>
            <field>
              <name>FB30</name>
              <bitOffset>30</bitOffset>
              <bitWidth>1</bitWidth>
            </field>
            <field>
              <name>FB31</name>
              <bitOffset>31</bitOffset>
              <bitWidth>1</bitWidth>
            </field>
          </fields>
        </register>
        <register>
          <name>sFilterRegister.7.FR2</name>
          <addressOffset>0x27c</addressOffset>
          <size>0x20</size>
          <fields>
            <field>
              <name>FB0</name>
              <bitOffset>0</bitOffset>
              <bitWidth>1</bitWidth>
            </field>
            <field>
              <name>FB1</name>
              <bitOffset>1</bitOffset>
              <bitWidth>1</bitWidth>
            </field>
            <field>
              <name>FB2</name>
              <bitOffset>2</bitOffset>
              <bitWidth>1</bitWidth>
            </field>
            <field>
              <name>FB3</name>
              <bitOffset>3</bitOffset>
              <bitWidth>1</bitWidth>
            </field>
            <field>
              <name>FB4</name>
              <bitOffset>4</bitOffset>
              <bitWidth>1</bitWidth>
            </field>
            <field>
              <name>FB5</name>
              <bitOffset>5</bitOffset>
              <bitWidth>1</bitWidth>
            </field>
            <field>
              <name>FB6</name>
              <bitOffset>6</bitOffset>
              <bitWidth>1</bitWidth>
            </field>
            <field>
              <name>FB7</name>
              <bitOffset>7</bitOffset>
              <bitWidth>1</bitWidth>
            </field>
            <field>
              <name>FB8</name>
              <bitOffset>8</bitOffset>
              <bitWidth>1</bitWidth>
            </field>
            <field>
              <name>FB9</name>
              <bitOffset>9</bitOffset>
              <bitWidth>1</bitWidth>
            </field>
            <field>
              <name>FB10</name>
              <bitOffset>10</bitOffset>
              <bitWidth>1</bitWidth>
            </field>
            <field>
              <name>FB11</name>
              <bitOffset>11</bitOffset>
              <bitWidth>1</bitWidth>
            </field>
            <field>
              <name>FB12</name>
              <bitOffset>12</bitOffset>
              <bitWidth>1</bitWidth>
            </field>
            <field>
              <name>FB13</name>
              <bitOffset>13</bitOffset>
              <bitWidth>1</bitWidth>
            </field>
            <field>
              <name>FB14</name>
              <bitOffset>14</bitOffset>
              <bitWidth>1</bitWidth>
            </field>
            <field>
              <name>FB15</name>
              <bitOffset>15</bitOffset>
              <bitWidth>1</bitWidth>
            </field>
            <field>
              <name>FB16</name>
              <bitOffset>16</bitOffset>
              <bitWidth>1</bitWidth>
            </field>
            <field>
              <name>FB17</name>
              <bitOffset>17</bitOffset>
              <bitWidth>1</bitWidth>
            </field>
            <field>
              <name>FB18</name>
              <bitOffset>18</bitOffset>
              <bitWidth>1</bitWidth>
            </field>
            <field>
              <name>FB19</name>
              <bitOffset>19</bitOffset>
              <bitWidth>1</bitWidth>
            </field>
            <field>
              <name>FB20</name>
              <bitOffset>20</bitOffset>
              <bitWidth>1</bitWidth>
            </field>
            <field>
              <name>FB21</name>
              <bitOffset>21</bitOffset>
              <bitWidth>1</bitWidth>
            </field>
            <field>
              <name>FB22</name>
              <bitOffset>22</bitOffset>
              <bitWidth>1</bitWidth>
            </field>
            <field>
              <name>FB23</name>
              <bitOffset>23</bitOffset>
              <bitWidth>1</bitWidth>
            </field>
            <field>
              <name>FB24</name>
              <bitOffset>24</bitOffset>
              <bitWidth>1</bitWidth>
            </field>
            <field>
              <name>FB25</name>
              <bitOffset>25</bitOffset>
              <bitWidth>1</bitWidth>
            </field>
            <field>
              <name>FB26</name>
              <bitOffset>26</bitOffset>
              <bitWidth>1</bitWidth>
            </field>
            <field>
              <name>FB27</name>
              <bitOffset>27</bitOffset>
              <bitWidth>1</bitWidth>
            </field>
            <field>
              <name>FB28</name>
              <bitOffset>28</bitOffset>
              <bitWidth>1</bitWidth>
            </field>
            <field>
              <name>FB29</name>
              <bitOffset>29</bitOffset>
              <bitWidth>1</bitWidth>
            </field>
            <field>
              <name>FB30</name>
              <bitOffset>30</bitOffset>
              <bitWidth>1</bitWidth>
            </field>
            <field>
              <name>FB31</name>
              <bitOffset>31</bitOffset>
              <bitWidth>1</bitWidth>
            </field>
          </fields>
        </register>
        <register>
          <name>sFilterRegister.8.FR1</name>
          <addressOffset>0x280</addressOffset>
          <size>0x20</size>
          <fields>
            <field>
              <name>FB0</name>
              <bitOffset>0</bitOffset>
              <bitWidth>1</bitWidth>
            </field>
            <field>
              <name>FB1</name>
              <bitOffset>1</bitOffset>
              <bitWidth>1</bitWidth>
            </field>
            <field>
              <name>FB2</name>
              <bitOffset>2</bitOffset>
              <bitWidth>1</bitWidth>
            </field>
            <field>
              <name>FB3</name>
              <bitOffset>3</bitOffset>
              <bitWidth>1</bitWidth>
            </field>
            <field>
              <name>FB4</name>
              <bitOffset>4</bitOffset>
              <bitWidth>1</bitWidth>
            </field>
            <field>
              <name>FB5</name>
              <bitOffset>5</bitOffset>
              <bitWidth>1</bitWidth>
            </field>
            <field>
              <name>FB6</name>
              <bitOffset>6</bitOffset>
              <bitWidth>1</bitWidth>
            </field>
            <field>
              <name>FB7</name>
              <bitOffset>7</bitOffset>
              <bitWidth>1</bitWidth>
            </field>
            <field>
              <name>FB8</name>
              <bitOffset>8</bitOffset>
              <bitWidth>1</bitWidth>
            </field>
            <field>
              <name>FB9</name>
              <bitOffset>9</bitOffset>
              <bitWidth>1</bitWidth>
            </field>
            <field>
              <name>FB10</name>
              <bitOffset>10</bitOffset>
              <bitWidth>1</bitWidth>
            </field>
            <field>
              <name>FB11</name>
              <bitOffset>11</bitOffset>
              <bitWidth>1</bitWidth>
            </field>
            <field>
              <name>FB12</name>
              <bitOffset>12</bitOffset>
              <bitWidth>1</bitWidth>
            </field>
            <field>
              <name>FB13</name>
              <bitOffset>13</bitOffset>
              <bitWidth>1</bitWidth>
            </field>
            <field>
              <name>FB14</name>
              <bitOffset>14</bitOffset>
              <bitWidth>1</bitWidth>
            </field>
            <field>
              <name>FB15</name>
              <bitOffset>15</bitOffset>
              <bitWidth>1</bitWidth>
            </field>
            <field>
              <name>FB16</name>
              <bitOffset>16</bitOffset>
              <bitWidth>1</bitWidth>
            </field>
            <field>
              <name>FB17</name>
              <bitOffset>17</bitOffset>
              <bitWidth>1</bitWidth>
            </field>
            <field>
              <name>FB18</name>
              <bitOffset>18</bitOffset>
              <bitWidth>1</bitWidth>
            </field>
            <field>
              <name>FB19</name>
              <bitOffset>19</bitOffset>
              <bitWidth>1</bitWidth>
            </field>
            <field>
              <name>FB20</name>
              <bitOffset>20</bitOffset>
              <bitWidth>1</bitWidth>
            </field>
            <field>
              <name>FB21</name>
              <bitOffset>21</bitOffset>
              <bitWidth>1</bitWidth>
            </field>
            <field>
              <name>FB22</name>
              <bitOffset>22</bitOffset>
              <bitWidth>1</bitWidth>
            </field>
            <field>
              <name>FB23</name>
              <bitOffset>23</bitOffset>
              <bitWidth>1</bitWidth>
            </field>
            <field>
              <name>FB24</name>
              <bitOffset>24</bitOffset>
              <bitWidth>1</bitWidth>
            </field>
            <field>
              <name>FB25</name>
              <bitOffset>25</bitOffset>
              <bitWidth>1</bitWidth>
            </field>
            <field>
              <name>FB26</name>
              <bitOffset>26</bitOffset>
              <bitWidth>1</bitWidth>
            </field>
            <field>
              <name>FB27</name>
              <bitOffset>27</bitOffset>
              <bitWidth>1</bitWidth>
            </field>
            <field>
              <name>FB28</name>
              <bitOffset>28</bitOffset>
              <bitWidth>1</bitWidth>
            </field>
            <field>
              <name>FB29</name>
              <bitOffset>29</bitOffset>
              <bitWidth>1</bitWidth>
            </field>
            <field>
              <name>FB30</name>
              <bitOffset>30</bitOffset>
              <bitWidth>1</bitWidth>
            </field>
            <field>
              <name>FB31</name>
              <bitOffset>31</bitOffset>
              <bitWidth>1</bitWidth>
            </field>
          </fields>
        </register>
        <register>
          <name>sFilterRegister.8.FR2</name>
          <addressOffset>0x284</addressOffset>
          <size>0x20</size>
          <fields>
            <field>
              <name>FB0</name>
              <bitOffset>0</bitOffset>
              <bitWidth>1</bitWidth>
            </field>
            <field>
              <name>FB1</name>
              <bitOffset>1</bitOffset>
              <bitWidth>1</bitWidth>
            </field>
            <field>
              <name>FB2</name>
              <bitOffset>2</bitOffset>
              <bitWidth>1</bitWidth>
            </field>
            <field>
              <name>FB3</name>
              <bitOffset>3</bitOffset>
              <bitWidth>1</bitWidth>
            </field>
            <field>
              <name>FB4</name>
              <bitOffset>4</bitOffset>
              <bitWidth>1</bitWidth>
            </field>
            <field>
              <name>FB5</name>
              <bitOffset>5</bitOffset>
              <bitWidth>1</bitWidth>
            </field>
            <field>
              <name>FB6</name>
              <bitOffset>6</bitOffset>
              <bitWidth>1</bitWidth>
            </field>
            <field>
              <name>FB7</name>
              <bitOffset>7</bitOffset>
              <bitWidth>1</bitWidth>
            </field>
            <field>
              <name>FB8</name>
              <bitOffset>8</bitOffset>
              <bitWidth>1</bitWidth>
            </field>
            <field>
              <name>FB9</name>
              <bitOffset>9</bitOffset>
              <bitWidth>1</bitWidth>
            </field>
            <field>
              <name>FB10</name>
              <bitOffset>10</bitOffset>
              <bitWidth>1</bitWidth>
            </field>
            <field>
              <name>FB11</name>
              <bitOffset>11</bitOffset>
              <bitWidth>1</bitWidth>
            </field>
            <field>
              <name>FB12</name>
              <bitOffset>12</bitOffset>
              <bitWidth>1</bitWidth>
            </field>
            <field>
              <name>FB13</name>
              <bitOffset>13</bitOffset>
              <bitWidth>1</bitWidth>
            </field>
            <field>
              <name>FB14</name>
              <bitOffset>14</bitOffset>
              <bitWidth>1</bitWidth>
            </field>
            <field>
              <name>FB15</name>
              <bitOffset>15</bitOffset>
              <bitWidth>1</bitWidth>
            </field>
            <field>
              <name>FB16</name>
              <bitOffset>16</bitOffset>
              <bitWidth>1</bitWidth>
            </field>
            <field>
              <name>FB17</name>
              <bitOffset>17</bitOffset>
              <bitWidth>1</bitWidth>
            </field>
            <field>
              <name>FB18</name>
              <bitOffset>18</bitOffset>
              <bitWidth>1</bitWidth>
            </field>
            <field>
              <name>FB19</name>
              <bitOffset>19</bitOffset>
              <bitWidth>1</bitWidth>
            </field>
            <field>
              <name>FB20</name>
              <bitOffset>20</bitOffset>
              <bitWidth>1</bitWidth>
            </field>
            <field>
              <name>FB21</name>
              <bitOffset>21</bitOffset>
              <bitWidth>1</bitWidth>
            </field>
            <field>
              <name>FB22</name>
              <bitOffset>22</bitOffset>
              <bitWidth>1</bitWidth>
            </field>
            <field>
              <name>FB23</name>
              <bitOffset>23</bitOffset>
              <bitWidth>1</bitWidth>
            </field>
            <field>
              <name>FB24</name>
              <bitOffset>24</bitOffset>
              <bitWidth>1</bitWidth>
            </field>
            <field>
              <name>FB25</name>
              <bitOffset>25</bitOffset>
              <bitWidth>1</bitWidth>
            </field>
            <field>
              <name>FB26</name>
              <bitOffset>26</bitOffset>
              <bitWidth>1</bitWidth>
            </field>
            <field>
              <name>FB27</name>
              <bitOffset>27</bitOffset>
              <bitWidth>1</bitWidth>
            </field>
            <field>
              <name>FB28</name>
              <bitOffset>28</bitOffset>
              <bitWidth>1</bitWidth>
            </field>
            <field>
              <name>FB29</name>
              <bitOffset>29</bitOffset>
              <bitWidth>1</bitWidth>
            </field>
            <field>
              <name>FB30</name>
              <bitOffset>30</bitOffset>
              <bitWidth>1</bitWidth>
            </field>
            <field>
              <name>FB31</name>
              <bitOffset>31</bitOffset>
              <bitWidth>1</bitWidth>
            </field>
          </fields>
        </register>
        <register>
          <name>sFilterRegister.9.FR1</name>
          <addressOffset>0x288</addressOffset>
          <size>0x20</size>
          <fields>
            <field>
              <name>FB0</name>
              <bitOffset>0</bitOffset>
              <bitWidth>1</bitWidth>
            </field>
            <field>
              <name>FB1</name>
              <bitOffset>1</bitOffset>
              <bitWidth>1</bitWidth>
            </field>
            <field>
              <name>FB2</name>
              <bitOffset>2</bitOffset>
              <bitWidth>1</bitWidth>
            </field>
            <field>
              <name>FB3</name>
              <bitOffset>3</bitOffset>
              <bitWidth>1</bitWidth>
            </field>
            <field>
              <name>FB4</name>
              <bitOffset>4</bitOffset>
              <bitWidth>1</bitWidth>
            </field>
            <field>
              <name>FB5</name>
              <bitOffset>5</bitOffset>
              <bitWidth>1</bitWidth>
            </field>
            <field>
              <name>FB6</name>
              <bitOffset>6</bitOffset>
              <bitWidth>1</bitWidth>
            </field>
            <field>
              <name>FB7</name>
              <bitOffset>7</bitOffset>
              <bitWidth>1</bitWidth>
            </field>
            <field>
              <name>FB8</name>
              <bitOffset>8</bitOffset>
              <bitWidth>1</bitWidth>
            </field>
            <field>
              <name>FB9</name>
              <bitOffset>9</bitOffset>
              <bitWidth>1</bitWidth>
            </field>
            <field>
              <name>FB10</name>
              <bitOffset>10</bitOffset>
              <bitWidth>1</bitWidth>
            </field>
            <field>
              <name>FB11</name>
              <bitOffset>11</bitOffset>
              <bitWidth>1</bitWidth>
            </field>
            <field>
              <name>FB12</name>
              <bitOffset>12</bitOffset>
              <bitWidth>1</bitWidth>
            </field>
            <field>
              <name>FB13</name>
              <bitOffset>13</bitOffset>
              <bitWidth>1</bitWidth>
            </field>
            <field>
              <name>FB14</name>
              <bitOffset>14</bitOffset>
              <bitWidth>1</bitWidth>
            </field>
            <field>
              <name>FB15</name>
              <bitOffset>15</bitOffset>
              <bitWidth>1</bitWidth>
            </field>
            <field>
              <name>FB16</name>
              <bitOffset>16</bitOffset>
              <bitWidth>1</bitWidth>
            </field>
            <field>
              <name>FB17</name>
              <bitOffset>17</bitOffset>
              <bitWidth>1</bitWidth>
            </field>
            <field>
              <name>FB18</name>
              <bitOffset>18</bitOffset>
              <bitWidth>1</bitWidth>
            </field>
            <field>
              <name>FB19</name>
              <bitOffset>19</bitOffset>
              <bitWidth>1</bitWidth>
            </field>
            <field>
              <name>FB20</name>
              <bitOffset>20</bitOffset>
              <bitWidth>1</bitWidth>
            </field>
            <field>
              <name>FB21</name>
              <bitOffset>21</bitOffset>
              <bitWidth>1</bitWidth>
            </field>
            <field>
              <name>FB22</name>
              <bitOffset>22</bitOffset>
              <bitWidth>1</bitWidth>
            </field>
            <field>
              <name>FB23</name>
              <bitOffset>23</bitOffset>
              <bitWidth>1</bitWidth>
            </field>
            <field>
              <name>FB24</name>
              <bitOffset>24</bitOffset>
              <bitWidth>1</bitWidth>
            </field>
            <field>
              <name>FB25</name>
              <bitOffset>25</bitOffset>
              <bitWidth>1</bitWidth>
            </field>
            <field>
              <name>FB26</name>
              <bitOffset>26</bitOffset>
              <bitWidth>1</bitWidth>
            </field>
            <field>
              <name>FB27</name>
              <bitOffset>27</bitOffset>
              <bitWidth>1</bitWidth>
            </field>
            <field>
              <name>FB28</name>
              <bitOffset>28</bitOffset>
              <bitWidth>1</bitWidth>
            </field>
            <field>
              <name>FB29</name>
              <bitOffset>29</bitOffset>
              <bitWidth>1</bitWidth>
            </field>
            <field>
              <name>FB30</name>
              <bitOffset>30</bitOffset>
              <bitWidth>1</bitWidth>
            </field>
            <field>
              <name>FB31</name>
              <bitOffset>31</bitOffset>
              <bitWidth>1</bitWidth>
            </field>
          </fields>
        </register>
        <register>
          <name>sFilterRegister.9.FR2</name>
          <addressOffset>0x28c</addressOffset>
          <size>0x20</size>
          <fields>
            <field>
              <name>FB0</name>
              <bitOffset>0</bitOffset>
              <bitWidth>1</bitWidth>
            </field>
            <field>
              <name>FB1</name>
              <bitOffset>1</bitOffset>
              <bitWidth>1</bitWidth>
            </field>
            <field>
              <name>FB2</name>
              <bitOffset>2</bitOffset>
              <bitWidth>1</bitWidth>
            </field>
            <field>
              <name>FB3</name>
              <bitOffset>3</bitOffset>
              <bitWidth>1</bitWidth>
            </field>
            <field>
              <name>FB4</name>
              <bitOffset>4</bitOffset>
              <bitWidth>1</bitWidth>
            </field>
            <field>
              <name>FB5</name>
              <bitOffset>5</bitOffset>
              <bitWidth>1</bitWidth>
            </field>
            <field>
              <name>FB6</name>
              <bitOffset>6</bitOffset>
              <bitWidth>1</bitWidth>
            </field>
            <field>
              <name>FB7</name>
              <bitOffset>7</bitOffset>
              <bitWidth>1</bitWidth>
            </field>
            <field>
              <name>FB8</name>
              <bitOffset>8</bitOffset>
              <bitWidth>1</bitWidth>
            </field>
            <field>
              <name>FB9</name>
              <bitOffset>9</bitOffset>
              <bitWidth>1</bitWidth>
            </field>
            <field>
              <name>FB10</name>
              <bitOffset>10</bitOffset>
              <bitWidth>1</bitWidth>
            </field>
            <field>
              <name>FB11</name>
              <bitOffset>11</bitOffset>
              <bitWidth>1</bitWidth>
            </field>
            <field>
              <name>FB12</name>
              <bitOffset>12</bitOffset>
              <bitWidth>1</bitWidth>
            </field>
            <field>
              <name>FB13</name>
              <bitOffset>13</bitOffset>
              <bitWidth>1</bitWidth>
            </field>
            <field>
              <name>FB14</name>
              <bitOffset>14</bitOffset>
              <bitWidth>1</bitWidth>
            </field>
            <field>
              <name>FB15</name>
              <bitOffset>15</bitOffset>
              <bitWidth>1</bitWidth>
            </field>
            <field>
              <name>FB16</name>
              <bitOffset>16</bitOffset>
              <bitWidth>1</bitWidth>
            </field>
            <field>
              <name>FB17</name>
              <bitOffset>17</bitOffset>
              <bitWidth>1</bitWidth>
            </field>
            <field>
              <name>FB18</name>
              <bitOffset>18</bitOffset>
              <bitWidth>1</bitWidth>
            </field>
            <field>
              <name>FB19</name>
              <bitOffset>19</bitOffset>
              <bitWidth>1</bitWidth>
            </field>
            <field>
              <name>FB20</name>
              <bitOffset>20</bitOffset>
              <bitWidth>1</bitWidth>
            </field>
            <field>
              <name>FB21</name>
              <bitOffset>21</bitOffset>
              <bitWidth>1</bitWidth>
            </field>
            <field>
              <name>FB22</name>
              <bitOffset>22</bitOffset>
              <bitWidth>1</bitWidth>
            </field>
            <field>
              <name>FB23</name>
              <bitOffset>23</bitOffset>
              <bitWidth>1</bitWidth>
            </field>
            <field>
              <name>FB24</name>
              <bitOffset>24</bitOffset>
              <bitWidth>1</bitWidth>
            </field>
            <field>
              <name>FB25</name>
              <bitOffset>25</bitOffset>
              <bitWidth>1</bitWidth>
            </field>
            <field>
              <name>FB26</name>
              <bitOffset>26</bitOffset>
              <bitWidth>1</bitWidth>
            </field>
            <field>
              <name>FB27</name>
              <bitOffset>27</bitOffset>
              <bitWidth>1</bitWidth>
            </field>
            <field>
              <name>FB28</name>
              <bitOffset>28</bitOffset>
              <bitWidth>1</bitWidth>
            </field>
            <field>
              <name>FB29</name>
              <bitOffset>29</bitOffset>
              <bitWidth>1</bitWidth>
            </field>
            <field>
              <name>FB30</name>
              <bitOffset>30</bitOffset>
              <bitWidth>1</bitWidth>
            </field>
            <field>
              <name>FB31</name>
              <bitOffset>31</bitOffset>
              <bitWidth>1</bitWidth>
            </field>
          </fields>
        </register>
        <register>
          <name>sFilterRegister.10.FR1</name>
          <addressOffset>0x290</addressOffset>
          <size>0x20</size>
          <fields>
            <field>
              <name>FB0</name>
              <bitOffset>0</bitOffset>
              <bitWidth>1</bitWidth>
            </field>
            <field>
              <name>FB1</name>
              <bitOffset>1</bitOffset>
              <bitWidth>1</bitWidth>
            </field>
            <field>
              <name>FB2</name>
              <bitOffset>2</bitOffset>
              <bitWidth>1</bitWidth>
            </field>
            <field>
              <name>FB3</name>
              <bitOffset>3</bitOffset>
              <bitWidth>1</bitWidth>
            </field>
            <field>
              <name>FB4</name>
              <bitOffset>4</bitOffset>
              <bitWidth>1</bitWidth>
            </field>
            <field>
              <name>FB5</name>
              <bitOffset>5</bitOffset>
              <bitWidth>1</bitWidth>
            </field>
            <field>
              <name>FB6</name>
              <bitOffset>6</bitOffset>
              <bitWidth>1</bitWidth>
            </field>
            <field>
              <name>FB7</name>
              <bitOffset>7</bitOffset>
              <bitWidth>1</bitWidth>
            </field>
            <field>
              <name>FB8</name>
              <bitOffset>8</bitOffset>
              <bitWidth>1</bitWidth>
            </field>
            <field>
              <name>FB9</name>
              <bitOffset>9</bitOffset>
              <bitWidth>1</bitWidth>
            </field>
            <field>
              <name>FB10</name>
              <bitOffset>10</bitOffset>
              <bitWidth>1</bitWidth>
            </field>
            <field>
              <name>FB11</name>
              <bitOffset>11</bitOffset>
              <bitWidth>1</bitWidth>
            </field>
            <field>
              <name>FB12</name>
              <bitOffset>12</bitOffset>
              <bitWidth>1</bitWidth>
            </field>
            <field>
              <name>FB13</name>
              <bitOffset>13</bitOffset>
              <bitWidth>1</bitWidth>
            </field>
            <field>
              <name>FB14</name>
              <bitOffset>14</bitOffset>
              <bitWidth>1</bitWidth>
            </field>
            <field>
              <name>FB15</name>
              <bitOffset>15</bitOffset>
              <bitWidth>1</bitWidth>
            </field>
            <field>
              <name>FB16</name>
              <bitOffset>16</bitOffset>
              <bitWidth>1</bitWidth>
            </field>
            <field>
              <name>FB17</name>
              <bitOffset>17</bitOffset>
              <bitWidth>1</bitWidth>
            </field>
            <field>
              <name>FB18</name>
              <bitOffset>18</bitOffset>
              <bitWidth>1</bitWidth>
            </field>
            <field>
              <name>FB19</name>
              <bitOffset>19</bitOffset>
              <bitWidth>1</bitWidth>
            </field>
            <field>
              <name>FB20</name>
              <bitOffset>20</bitOffset>
              <bitWidth>1</bitWidth>
            </field>
            <field>
              <name>FB21</name>
              <bitOffset>21</bitOffset>
              <bitWidth>1</bitWidth>
            </field>
            <field>
              <name>FB22</name>
              <bitOffset>22</bitOffset>
              <bitWidth>1</bitWidth>
            </field>
            <field>
              <name>FB23</name>
              <bitOffset>23</bitOffset>
              <bitWidth>1</bitWidth>
            </field>
            <field>
              <name>FB24</name>
              <bitOffset>24</bitOffset>
              <bitWidth>1</bitWidth>
            </field>
            <field>
              <name>FB25</name>
              <bitOffset>25</bitOffset>
              <bitWidth>1</bitWidth>
            </field>
            <field>
              <name>FB26</name>
              <bitOffset>26</bitOffset>
              <bitWidth>1</bitWidth>
            </field>
            <field>
              <name>FB27</name>
              <bitOffset>27</bitOffset>
              <bitWidth>1</bitWidth>
            </field>
            <field>
              <name>FB28</name>
              <bitOffset>28</bitOffset>
              <bitWidth>1</bitWidth>
            </field>
            <field>
              <name>FB29</name>
              <bitOffset>29</bitOffset>
              <bitWidth>1</bitWidth>
            </field>
            <field>
              <name>FB30</name>
              <bitOffset>30</bitOffset>
              <bitWidth>1</bitWidth>
            </field>
            <field>
              <name>FB31</name>
              <bitOffset>31</bitOffset>
              <bitWidth>1</bitWidth>
            </field>
          </fields>
        </register>
        <register>
          <name>sFilterRegister.10.FR2</name>
          <addressOffset>0x294</addressOffset>
          <size>0x20</size>
          <fields>
            <field>
              <name>FB0</name>
              <bitOffset>0</bitOffset>
              <bitWidth>1</bitWidth>
            </field>
            <field>
              <name>FB1</name>
              <bitOffset>1</bitOffset>
              <bitWidth>1</bitWidth>
            </field>
            <field>
              <name>FB2</name>
              <bitOffset>2</bitOffset>
              <bitWidth>1</bitWidth>
            </field>
            <field>
              <name>FB3</name>
              <bitOffset>3</bitOffset>
              <bitWidth>1</bitWidth>
            </field>
            <field>
              <name>FB4</name>
              <bitOffset>4</bitOffset>
              <bitWidth>1</bitWidth>
            </field>
            <field>
              <name>FB5</name>
              <bitOffset>5</bitOffset>
              <bitWidth>1</bitWidth>
            </field>
            <field>
              <name>FB6</name>
              <bitOffset>6</bitOffset>
              <bitWidth>1</bitWidth>
            </field>
            <field>
              <name>FB7</name>
              <bitOffset>7</bitOffset>
              <bitWidth>1</bitWidth>
            </field>
            <field>
              <name>FB8</name>
              <bitOffset>8</bitOffset>
              <bitWidth>1</bitWidth>
            </field>
            <field>
              <name>FB9</name>
              <bitOffset>9</bitOffset>
              <bitWidth>1</bitWidth>
            </field>
            <field>
              <name>FB10</name>
              <bitOffset>10</bitOffset>
              <bitWidth>1</bitWidth>
            </field>
            <field>
              <name>FB11</name>
              <bitOffset>11</bitOffset>
              <bitWidth>1</bitWidth>
            </field>
            <field>
              <name>FB12</name>
              <bitOffset>12</bitOffset>
              <bitWidth>1</bitWidth>
            </field>
            <field>
              <name>FB13</name>
              <bitOffset>13</bitOffset>
              <bitWidth>1</bitWidth>
            </field>
            <field>
              <name>FB14</name>
              <bitOffset>14</bitOffset>
              <bitWidth>1</bitWidth>
            </field>
            <field>
              <name>FB15</name>
              <bitOffset>15</bitOffset>
              <bitWidth>1</bitWidth>
            </field>
            <field>
              <name>FB16</name>
              <bitOffset>16</bitOffset>
              <bitWidth>1</bitWidth>
            </field>
            <field>
              <name>FB17</name>
              <bitOffset>17</bitOffset>
              <bitWidth>1</bitWidth>
            </field>
            <field>
              <name>FB18</name>
              <bitOffset>18</bitOffset>
              <bitWidth>1</bitWidth>
            </field>
            <field>
              <name>FB19</name>
              <bitOffset>19</bitOffset>
              <bitWidth>1</bitWidth>
            </field>
            <field>
              <name>FB20</name>
              <bitOffset>20</bitOffset>
              <bitWidth>1</bitWidth>
            </field>
            <field>
              <name>FB21</name>
              <bitOffset>21</bitOffset>
              <bitWidth>1</bitWidth>
            </field>
            <field>
              <name>FB22</name>
              <bitOffset>22</bitOffset>
              <bitWidth>1</bitWidth>
            </field>
            <field>
              <name>FB23</name>
              <bitOffset>23</bitOffset>
              <bitWidth>1</bitWidth>
            </field>
            <field>
              <name>FB24</name>
              <bitOffset>24</bitOffset>
              <bitWidth>1</bitWidth>
            </field>
            <field>
              <name>FB25</name>
              <bitOffset>25</bitOffset>
              <bitWidth>1</bitWidth>
            </field>
            <field>
              <name>FB26</name>
              <bitOffset>26</bitOffset>
              <bitWidth>1</bitWidth>
            </field>
            <field>
              <name>FB27</name>
              <bitOffset>27</bitOffset>
              <bitWidth>1</bitWidth>
            </field>
            <field>
              <name>FB28</name>
              <bitOffset>28</bitOffset>
              <bitWidth>1</bitWidth>
            </field>
            <field>
              <name>FB29</name>
              <bitOffset>29</bitOffset>
              <bitWidth>1</bitWidth>
            </field>
            <field>
              <name>FB30</name>
              <bitOffset>30</bitOffset>
              <bitWidth>1</bitWidth>
            </field>
            <field>
              <name>FB31</name>
              <bitOffset>31</bitOffset>
              <bitWidth>1</bitWidth>
            </field>
          </fields>
        </register>
        <register>
          <name>sFilterRegister.11.FR1</name>
          <addressOffset>0x298</addressOffset>
          <size>0x20</size>
          <fields>
            <field>
              <name>FB0</name>
              <bitOffset>0</bitOffset>
              <bitWidth>1</bitWidth>
            </field>
            <field>
              <name>FB1</name>
              <bitOffset>1</bitOffset>
              <bitWidth>1</bitWidth>
            </field>
            <field>
              <name>FB2</name>
              <bitOffset>2</bitOffset>
              <bitWidth>1</bitWidth>
            </field>
            <field>
              <name>FB3</name>
              <bitOffset>3</bitOffset>
              <bitWidth>1</bitWidth>
            </field>
            <field>
              <name>FB4</name>
              <bitOffset>4</bitOffset>
              <bitWidth>1</bitWidth>
            </field>
            <field>
              <name>FB5</name>
              <bitOffset>5</bitOffset>
              <bitWidth>1</bitWidth>
            </field>
            <field>
              <name>FB6</name>
              <bitOffset>6</bitOffset>
              <bitWidth>1</bitWidth>
            </field>
            <field>
              <name>FB7</name>
              <bitOffset>7</bitOffset>
              <bitWidth>1</bitWidth>
            </field>
            <field>
              <name>FB8</name>
              <bitOffset>8</bitOffset>
              <bitWidth>1</bitWidth>
            </field>
            <field>
              <name>FB9</name>
              <bitOffset>9</bitOffset>
              <bitWidth>1</bitWidth>
            </field>
            <field>
              <name>FB10</name>
              <bitOffset>10</bitOffset>
              <bitWidth>1</bitWidth>
            </field>
            <field>
              <name>FB11</name>
              <bitOffset>11</bitOffset>
              <bitWidth>1</bitWidth>
            </field>
            <field>
              <name>FB12</name>
              <bitOffset>12</bitOffset>
              <bitWidth>1</bitWidth>
            </field>
            <field>
              <name>FB13</name>
              <bitOffset>13</bitOffset>
              <bitWidth>1</bitWidth>
            </field>
            <field>
              <name>FB14</name>
              <bitOffset>14</bitOffset>
              <bitWidth>1</bitWidth>
            </field>
            <field>
              <name>FB15</name>
              <bitOffset>15</bitOffset>
              <bitWidth>1</bitWidth>
            </field>
            <field>
              <name>FB16</name>
              <bitOffset>16</bitOffset>
              <bitWidth>1</bitWidth>
            </field>
            <field>
              <name>FB17</name>
              <bitOffset>17</bitOffset>
              <bitWidth>1</bitWidth>
            </field>
            <field>
              <name>FB18</name>
              <bitOffset>18</bitOffset>
              <bitWidth>1</bitWidth>
            </field>
            <field>
              <name>FB19</name>
              <bitOffset>19</bitOffset>
              <bitWidth>1</bitWidth>
            </field>
            <field>
              <name>FB20</name>
              <bitOffset>20</bitOffset>
              <bitWidth>1</bitWidth>
            </field>
            <field>
              <name>FB21</name>
              <bitOffset>21</bitOffset>
              <bitWidth>1</bitWidth>
            </field>
            <field>
              <name>FB22</name>
              <bitOffset>22</bitOffset>
              <bitWidth>1</bitWidth>
            </field>
            <field>
              <name>FB23</name>
              <bitOffset>23</bitOffset>
              <bitWidth>1</bitWidth>
            </field>
            <field>
              <name>FB24</name>
              <bitOffset>24</bitOffset>
              <bitWidth>1</bitWidth>
            </field>
            <field>
              <name>FB25</name>
              <bitOffset>25</bitOffset>
              <bitWidth>1</bitWidth>
            </field>
            <field>
              <name>FB26</name>
              <bitOffset>26</bitOffset>
              <bitWidth>1</bitWidth>
            </field>
            <field>
              <name>FB27</name>
              <bitOffset>27</bitOffset>
              <bitWidth>1</bitWidth>
            </field>
            <field>
              <name>FB28</name>
              <bitOffset>28</bitOffset>
              <bitWidth>1</bitWidth>
            </field>
            <field>
              <name>FB29</name>
              <bitOffset>29</bitOffset>
              <bitWidth>1</bitWidth>
            </field>
            <field>
              <name>FB30</name>
              <bitOffset>30</bitOffset>
              <bitWidth>1</bitWidth>
            </field>
            <field>
              <name>FB31</name>
              <bitOffset>31</bitOffset>
              <bitWidth>1</bitWidth>
            </field>
          </fields>
        </register>
        <register>
          <name>sFilterRegister.11.FR2</name>
          <addressOffset>0x29c</addressOffset>
          <size>0x20</size>
          <fields>
            <field>
              <name>FB0</name>
              <bitOffset>0</bitOffset>
              <bitWidth>1</bitWidth>
            </field>
            <field>
              <name>FB1</name>
              <bitOffset>1</bitOffset>
              <bitWidth>1</bitWidth>
            </field>
            <field>
              <name>FB2</name>
              <bitOffset>2</bitOffset>
              <bitWidth>1</bitWidth>
            </field>
            <field>
              <name>FB3</name>
              <bitOffset>3</bitOffset>
              <bitWidth>1</bitWidth>
            </field>
            <field>
              <name>FB4</name>
              <bitOffset>4</bitOffset>
              <bitWidth>1</bitWidth>
            </field>
            <field>
              <name>FB5</name>
              <bitOffset>5</bitOffset>
              <bitWidth>1</bitWidth>
            </field>
            <field>
              <name>FB6</name>
              <bitOffset>6</bitOffset>
              <bitWidth>1</bitWidth>
            </field>
            <field>
              <name>FB7</name>
              <bitOffset>7</bitOffset>
              <bitWidth>1</bitWidth>
            </field>
            <field>
              <name>FB8</name>
              <bitOffset>8</bitOffset>
              <bitWidth>1</bitWidth>
            </field>
            <field>
              <name>FB9</name>
              <bitOffset>9</bitOffset>
              <bitWidth>1</bitWidth>
            </field>
            <field>
              <name>FB10</name>
              <bitOffset>10</bitOffset>
              <bitWidth>1</bitWidth>
            </field>
            <field>
              <name>FB11</name>
              <bitOffset>11</bitOffset>
              <bitWidth>1</bitWidth>
            </field>
            <field>
              <name>FB12</name>
              <bitOffset>12</bitOffset>
              <bitWidth>1</bitWidth>
            </field>
            <field>
              <name>FB13</name>
              <bitOffset>13</bitOffset>
              <bitWidth>1</bitWidth>
            </field>
            <field>
              <name>FB14</name>
              <bitOffset>14</bitOffset>
              <bitWidth>1</bitWidth>
            </field>
            <field>
              <name>FB15</name>
              <bitOffset>15</bitOffset>
              <bitWidth>1</bitWidth>
            </field>
            <field>
              <name>FB16</name>
              <bitOffset>16</bitOffset>
              <bitWidth>1</bitWidth>
            </field>
            <field>
              <name>FB17</name>
              <bitOffset>17</bitOffset>
              <bitWidth>1</bitWidth>
            </field>
            <field>
              <name>FB18</name>
              <bitOffset>18</bitOffset>
              <bitWidth>1</bitWidth>
            </field>
            <field>
              <name>FB19</name>
              <bitOffset>19</bitOffset>
              <bitWidth>1</bitWidth>
            </field>
            <field>
              <name>FB20</name>
              <bitOffset>20</bitOffset>
              <bitWidth>1</bitWidth>
            </field>
            <field>
              <name>FB21</name>
              <bitOffset>21</bitOffset>
              <bitWidth>1</bitWidth>
            </field>
            <field>
              <name>FB22</name>
              <bitOffset>22</bitOffset>
              <bitWidth>1</bitWidth>
            </field>
            <field>
              <name>FB23</name>
              <bitOffset>23</bitOffset>
              <bitWidth>1</bitWidth>
            </field>
            <field>
              <name>FB24</name>
              <bitOffset>24</bitOffset>
              <bitWidth>1</bitWidth>
            </field>
            <field>
              <name>FB25</name>
              <bitOffset>25</bitOffset>
              <bitWidth>1</bitWidth>
            </field>
            <field>
              <name>FB26</name>
              <bitOffset>26</bitOffset>
              <bitWidth>1</bitWidth>
            </field>
            <field>
              <name>FB27</name>
              <bitOffset>27</bitOffset>
              <bitWidth>1</bitWidth>
            </field>
            <field>
              <name>FB28</name>
              <bitOffset>28</bitOffset>
              <bitWidth>1</bitWidth>
            </field>
            <field>
              <name>FB29</name>
              <bitOffset>29</bitOffset>
              <bitWidth>1</bitWidth>
            </field>
            <field>
              <name>FB30</name>
              <bitOffset>30</bitOffset>
              <bitWidth>1</bitWidth>
            </field>
            <field>
              <name>FB31</name>
              <bitOffset>31</bitOffset>
              <bitWidth>1</bitWidth>
            </field>
          </fields>
        </register>
        <register>
          <name>sFilterRegister.12.FR1</name>
          <addressOffset>0x2a0</addressOffset>
          <size>0x20</size>
          <fields>
            <field>
              <name>FB0</name>
              <bitOffset>0</bitOffset>
              <bitWidth>1</bitWidth>
            </field>
            <field>
              <name>FB1</name>
              <bitOffset>1</bitOffset>
              <bitWidth>1</bitWidth>
            </field>
            <field>
              <name>FB2</name>
              <bitOffset>2</bitOffset>
              <bitWidth>1</bitWidth>
            </field>
            <field>
              <name>FB3</name>
              <bitOffset>3</bitOffset>
              <bitWidth>1</bitWidth>
            </field>
            <field>
              <name>FB4</name>
              <bitOffset>4</bitOffset>
              <bitWidth>1</bitWidth>
            </field>
            <field>
              <name>FB5</name>
              <bitOffset>5</bitOffset>
              <bitWidth>1</bitWidth>
            </field>
            <field>
              <name>FB6</name>
              <bitOffset>6</bitOffset>
              <bitWidth>1</bitWidth>
            </field>
            <field>
              <name>FB7</name>
              <bitOffset>7</bitOffset>
              <bitWidth>1</bitWidth>
            </field>
            <field>
              <name>FB8</name>
              <bitOffset>8</bitOffset>
              <bitWidth>1</bitWidth>
            </field>
            <field>
              <name>FB9</name>
              <bitOffset>9</bitOffset>
              <bitWidth>1</bitWidth>
            </field>
            <field>
              <name>FB10</name>
              <bitOffset>10</bitOffset>
              <bitWidth>1</bitWidth>
            </field>
            <field>
              <name>FB11</name>
              <bitOffset>11</bitOffset>
              <bitWidth>1</bitWidth>
            </field>
            <field>
              <name>FB12</name>
              <bitOffset>12</bitOffset>
              <bitWidth>1</bitWidth>
            </field>
            <field>
              <name>FB13</name>
              <bitOffset>13</bitOffset>
              <bitWidth>1</bitWidth>
            </field>
            <field>
              <name>FB14</name>
              <bitOffset>14</bitOffset>
              <bitWidth>1</bitWidth>
            </field>
            <field>
              <name>FB15</name>
              <bitOffset>15</bitOffset>
              <bitWidth>1</bitWidth>
            </field>
            <field>
              <name>FB16</name>
              <bitOffset>16</bitOffset>
              <bitWidth>1</bitWidth>
            </field>
            <field>
              <name>FB17</name>
              <bitOffset>17</bitOffset>
              <bitWidth>1</bitWidth>
            </field>
            <field>
              <name>FB18</name>
              <bitOffset>18</bitOffset>
              <bitWidth>1</bitWidth>
            </field>
            <field>
              <name>FB19</name>
              <bitOffset>19</bitOffset>
              <bitWidth>1</bitWidth>
            </field>
            <field>
              <name>FB20</name>
              <bitOffset>20</bitOffset>
              <bitWidth>1</bitWidth>
            </field>
            <field>
              <name>FB21</name>
              <bitOffset>21</bitOffset>
              <bitWidth>1</bitWidth>
            </field>
            <field>
              <name>FB22</name>
              <bitOffset>22</bitOffset>
              <bitWidth>1</bitWidth>
            </field>
            <field>
              <name>FB23</name>
              <bitOffset>23</bitOffset>
              <bitWidth>1</bitWidth>
            </field>
            <field>
              <name>FB24</name>
              <bitOffset>24</bitOffset>
              <bitWidth>1</bitWidth>
            </field>
            <field>
              <name>FB25</name>
              <bitOffset>25</bitOffset>
              <bitWidth>1</bitWidth>
            </field>
            <field>
              <name>FB26</name>
              <bitOffset>26</bitOffset>
              <bitWidth>1</bitWidth>
            </field>
            <field>
              <name>FB27</name>
              <bitOffset>27</bitOffset>
              <bitWidth>1</bitWidth>
            </field>
            <field>
              <name>FB28</name>
              <bitOffset>28</bitOffset>
              <bitWidth>1</bitWidth>
            </field>
            <field>
              <name>FB29</name>
              <bitOffset>29</bitOffset>
              <bitWidth>1</bitWidth>
            </field>
            <field>
              <name>FB30</name>
              <bitOffset>30</bitOffset>
              <bitWidth>1</bitWidth>
            </field>
            <field>
              <name>FB31</name>
              <bitOffset>31</bitOffset>
              <bitWidth>1</bitWidth>
            </field>
          </fields>
        </register>
        <register>
          <name>sFilterRegister.12.FR2</name>
          <addressOffset>0x2a4</addressOffset>
          <size>0x20</size>
          <fields>
            <field>
              <name>FB0</name>
              <bitOffset>0</bitOffset>
              <bitWidth>1</bitWidth>
            </field>
            <field>
              <name>FB1</name>
              <bitOffset>1</bitOffset>
              <bitWidth>1</bitWidth>
            </field>
            <field>
              <name>FB2</name>
              <bitOffset>2</bitOffset>
              <bitWidth>1</bitWidth>
            </field>
            <field>
              <name>FB3</name>
              <bitOffset>3</bitOffset>
              <bitWidth>1</bitWidth>
            </field>
            <field>
              <name>FB4</name>
              <bitOffset>4</bitOffset>
              <bitWidth>1</bitWidth>
            </field>
            <field>
              <name>FB5</name>
              <bitOffset>5</bitOffset>
              <bitWidth>1</bitWidth>
            </field>
            <field>
              <name>FB6</name>
              <bitOffset>6</bitOffset>
              <bitWidth>1</bitWidth>
            </field>
            <field>
              <name>FB7</name>
              <bitOffset>7</bitOffset>
              <bitWidth>1</bitWidth>
            </field>
            <field>
              <name>FB8</name>
              <bitOffset>8</bitOffset>
              <bitWidth>1</bitWidth>
            </field>
            <field>
              <name>FB9</name>
              <bitOffset>9</bitOffset>
              <bitWidth>1</bitWidth>
            </field>
            <field>
              <name>FB10</name>
              <bitOffset>10</bitOffset>
              <bitWidth>1</bitWidth>
            </field>
            <field>
              <name>FB11</name>
              <bitOffset>11</bitOffset>
              <bitWidth>1</bitWidth>
            </field>
            <field>
              <name>FB12</name>
              <bitOffset>12</bitOffset>
              <bitWidth>1</bitWidth>
            </field>
            <field>
              <name>FB13</name>
              <bitOffset>13</bitOffset>
              <bitWidth>1</bitWidth>
            </field>
            <field>
              <name>FB14</name>
              <bitOffset>14</bitOffset>
              <bitWidth>1</bitWidth>
            </field>
            <field>
              <name>FB15</name>
              <bitOffset>15</bitOffset>
              <bitWidth>1</bitWidth>
            </field>
            <field>
              <name>FB16</name>
              <bitOffset>16</bitOffset>
              <bitWidth>1</bitWidth>
            </field>
            <field>
              <name>FB17</name>
              <bitOffset>17</bitOffset>
              <bitWidth>1</bitWidth>
            </field>
            <field>
              <name>FB18</name>
              <bitOffset>18</bitOffset>
              <bitWidth>1</bitWidth>
            </field>
            <field>
              <name>FB19</name>
              <bitOffset>19</bitOffset>
              <bitWidth>1</bitWidth>
            </field>
            <field>
              <name>FB20</name>
              <bitOffset>20</bitOffset>
              <bitWidth>1</bitWidth>
            </field>
            <field>
              <name>FB21</name>
              <bitOffset>21</bitOffset>
              <bitWidth>1</bitWidth>
            </field>
            <field>
              <name>FB22</name>
              <bitOffset>22</bitOffset>
              <bitWidth>1</bitWidth>
            </field>
            <field>
              <name>FB23</name>
              <bitOffset>23</bitOffset>
              <bitWidth>1</bitWidth>
            </field>
            <field>
              <name>FB24</name>
              <bitOffset>24</bitOffset>
              <bitWidth>1</bitWidth>
            </field>
            <field>
              <name>FB25</name>
              <bitOffset>25</bitOffset>
              <bitWidth>1</bitWidth>
            </field>
            <field>
              <name>FB26</name>
              <bitOffset>26</bitOffset>
              <bitWidth>1</bitWidth>
            </field>
            <field>
              <name>FB27</name>
              <bitOffset>27</bitOffset>
              <bitWidth>1</bitWidth>
            </field>
            <field>
              <name>FB28</name>
              <bitOffset>28</bitOffset>
              <bitWidth>1</bitWidth>
            </field>
            <field>
              <name>FB29</name>
              <bitOffset>29</bitOffset>
              <bitWidth>1</bitWidth>
            </field>
            <field>
              <name>FB30</name>
              <bitOffset>30</bitOffset>
              <bitWidth>1</bitWidth>
            </field>
            <field>
              <name>FB31</name>
              <bitOffset>31</bitOffset>
              <bitWidth>1</bitWidth>
            </field>
          </fields>
        </register>
        <register>
          <name>sFilterRegister.13.FR1</name>
          <addressOffset>0x2a8</addressOffset>
          <size>0x20</size>
          <fields>
            <field>
              <name>FB0</name>
              <bitOffset>0</bitOffset>
              <bitWidth>1</bitWidth>
            </field>
            <field>
              <name>FB1</name>
              <bitOffset>1</bitOffset>
              <bitWidth>1</bitWidth>
            </field>
            <field>
              <name>FB2</name>
              <bitOffset>2</bitOffset>
              <bitWidth>1</bitWidth>
            </field>
            <field>
              <name>FB3</name>
              <bitOffset>3</bitOffset>
              <bitWidth>1</bitWidth>
            </field>
            <field>
              <name>FB4</name>
              <bitOffset>4</bitOffset>
              <bitWidth>1</bitWidth>
            </field>
            <field>
              <name>FB5</name>
              <bitOffset>5</bitOffset>
              <bitWidth>1</bitWidth>
            </field>
            <field>
              <name>FB6</name>
              <bitOffset>6</bitOffset>
              <bitWidth>1</bitWidth>
            </field>
            <field>
              <name>FB7</name>
              <bitOffset>7</bitOffset>
              <bitWidth>1</bitWidth>
            </field>
            <field>
              <name>FB8</name>
              <bitOffset>8</bitOffset>
              <bitWidth>1</bitWidth>
            </field>
            <field>
              <name>FB9</name>
              <bitOffset>9</bitOffset>
              <bitWidth>1</bitWidth>
            </field>
            <field>
              <name>FB10</name>
              <bitOffset>10</bitOffset>
              <bitWidth>1</bitWidth>
            </field>
            <field>
              <name>FB11</name>
              <bitOffset>11</bitOffset>
              <bitWidth>1</bitWidth>
            </field>
            <field>
              <name>FB12</name>
              <bitOffset>12</bitOffset>
              <bitWidth>1</bitWidth>
            </field>
            <field>
              <name>FB13</name>
              <bitOffset>13</bitOffset>
              <bitWidth>1</bitWidth>
            </field>
            <field>
              <name>FB14</name>
              <bitOffset>14</bitOffset>
              <bitWidth>1</bitWidth>
            </field>
            <field>
              <name>FB15</name>
              <bitOffset>15</bitOffset>
              <bitWidth>1</bitWidth>
            </field>
            <field>
              <name>FB16</name>
              <bitOffset>16</bitOffset>
              <bitWidth>1</bitWidth>
            </field>
            <field>
              <name>FB17</name>
              <bitOffset>17</bitOffset>
              <bitWidth>1</bitWidth>
            </field>
            <field>
              <name>FB18</name>
              <bitOffset>18</bitOffset>
              <bitWidth>1</bitWidth>
            </field>
            <field>
              <name>FB19</name>
              <bitOffset>19</bitOffset>
              <bitWidth>1</bitWidth>
            </field>
            <field>
              <name>FB20</name>
              <bitOffset>20</bitOffset>
              <bitWidth>1</bitWidth>
            </field>
            <field>
              <name>FB21</name>
              <bitOffset>21</bitOffset>
              <bitWidth>1</bitWidth>
            </field>
            <field>
              <name>FB22</name>
              <bitOffset>22</bitOffset>
              <bitWidth>1</bitWidth>
            </field>
            <field>
              <name>FB23</name>
              <bitOffset>23</bitOffset>
              <bitWidth>1</bitWidth>
            </field>
            <field>
              <name>FB24</name>
              <bitOffset>24</bitOffset>
              <bitWidth>1</bitWidth>
            </field>
            <field>
              <name>FB25</name>
              <bitOffset>25</bitOffset>
              <bitWidth>1</bitWidth>
            </field>
            <field>
              <name>FB26</name>
              <bitOffset>26</bitOffset>
              <bitWidth>1</bitWidth>
            </field>
            <field>
              <name>FB27</name>
              <bitOffset>27</bitOffset>
              <bitWidth>1</bitWidth>
            </field>
            <field>
              <name>FB28</name>
              <bitOffset>28</bitOffset>
              <bitWidth>1</bitWidth>
            </field>
            <field>
              <name>FB29</name>
              <bitOffset>29</bitOffset>
              <bitWidth>1</bitWidth>
            </field>
            <field>
              <name>FB30</name>
              <bitOffset>30</bitOffset>
              <bitWidth>1</bitWidth>
            </field>
            <field>
              <name>FB31</name>
              <bitOffset>31</bitOffset>
              <bitWidth>1</bitWidth>
            </field>
          </fields>
        </register>
        <register>
          <name>sFilterRegister.13.FR2</name>
          <addressOffset>0x2ac</addressOffset>
          <size>0x20</size>
          <fields>
            <field>
              <name>FB0</name>
              <bitOffset>0</bitOffset>
              <bitWidth>1</bitWidth>
            </field>
            <field>
              <name>FB1</name>
              <bitOffset>1</bitOffset>
              <bitWidth>1</bitWidth>
            </field>
            <field>
              <name>FB2</name>
              <bitOffset>2</bitOffset>
              <bitWidth>1</bitWidth>
            </field>
            <field>
              <name>FB3</name>
              <bitOffset>3</bitOffset>
              <bitWidth>1</bitWidth>
            </field>
            <field>
              <name>FB4</name>
              <bitOffset>4</bitOffset>
              <bitWidth>1</bitWidth>
            </field>
            <field>
              <name>FB5</name>
              <bitOffset>5</bitOffset>
              <bitWidth>1</bitWidth>
            </field>
            <field>
              <name>FB6</name>
              <bitOffset>6</bitOffset>
              <bitWidth>1</bitWidth>
            </field>
            <field>
              <name>FB7</name>
              <bitOffset>7</bitOffset>
              <bitWidth>1</bitWidth>
            </field>
            <field>
              <name>FB8</name>
              <bitOffset>8</bitOffset>
              <bitWidth>1</bitWidth>
            </field>
            <field>
              <name>FB9</name>
              <bitOffset>9</bitOffset>
              <bitWidth>1</bitWidth>
            </field>
            <field>
              <name>FB10</name>
              <bitOffset>10</bitOffset>
              <bitWidth>1</bitWidth>
            </field>
            <field>
              <name>FB11</name>
              <bitOffset>11</bitOffset>
              <bitWidth>1</bitWidth>
            </field>
            <field>
              <name>FB12</name>
              <bitOffset>12</bitOffset>
              <bitWidth>1</bitWidth>
            </field>
            <field>
              <name>FB13</name>
              <bitOffset>13</bitOffset>
              <bitWidth>1</bitWidth>
            </field>
            <field>
              <name>FB14</name>
              <bitOffset>14</bitOffset>
              <bitWidth>1</bitWidth>
            </field>
            <field>
              <name>FB15</name>
              <bitOffset>15</bitOffset>
              <bitWidth>1</bitWidth>
            </field>
            <field>
              <name>FB16</name>
              <bitOffset>16</bitOffset>
              <bitWidth>1</bitWidth>
            </field>
            <field>
              <name>FB17</name>
              <bitOffset>17</bitOffset>
              <bitWidth>1</bitWidth>
            </field>
            <field>
              <name>FB18</name>
              <bitOffset>18</bitOffset>
              <bitWidth>1</bitWidth>
            </field>
            <field>
              <name>FB19</name>
              <bitOffset>19</bitOffset>
              <bitWidth>1</bitWidth>
            </field>
            <field>
              <name>FB20</name>
              <bitOffset>20</bitOffset>
              <bitWidth>1</bitWidth>
            </field>
            <field>
              <name>FB21</name>
              <bitOffset>21</bitOffset>
              <bitWidth>1</bitWidth>
            </field>
            <field>
              <name>FB22</name>
              <bitOffset>22</bitOffset>
              <bitWidth>1</bitWidth>
            </field>
            <field>
              <name>FB23</name>
              <bitOffset>23</bitOffset>
              <bitWidth>1</bitWidth>
            </field>
            <field>
              <name>FB24</name>
              <bitOffset>24</bitOffset>
              <bitWidth>1</bitWidth>
            </field>
            <field>
              <name>FB25</name>
              <bitOffset>25</bitOffset>
              <bitWidth>1</bitWidth>
            </field>
            <field>
              <name>FB26</name>
              <bitOffset>26</bitOffset>
              <bitWidth>1</bitWidth>
            </field>
            <field>
              <name>FB27</name>
              <bitOffset>27</bitOffset>
              <bitWidth>1</bitWidth>
            </field>
            <field>
              <name>FB28</name>
              <bitOffset>28</bitOffset>
              <bitWidth>1</bitWidth>
            </field>
            <field>
              <name>FB29</name>
              <bitOffset>29</bitOffset>
              <bitWidth>1</bitWidth>
            </field>
            <field>
              <name>FB30</name>
              <bitOffset>30</bitOffset>
              <bitWidth>1</bitWidth>
            </field>
            <field>
              <name>FB31</name>
              <bitOffset>31</bitOffset>
              <bitWidth>1</bitWidth>
            </field>
          </fields>
        </register>
        <register>
          <name>sFilterRegister.14.FR1</name>
          <addressOffset>0x2b0</addressOffset>
          <size>0x20</size>
        </register>
        <register>
          <name>sFilterRegister.14.FR2</name>
          <addressOffset>0x2b4</addressOffset>
          <size>0x20</size>
        </register>
        <register>
          <name>sFilterRegister.15.FR1</name>
          <addressOffset>0x2b8</addressOffset>
          <size>0x20</size>
        </register>
        <register>
          <name>sFilterRegister.15.FR2</name>
          <addressOffset>0x2bc</addressOffset>
          <size>0x20</size>
        </register>
        <register>
          <name>sFilterRegister.16.FR1</name>
          <addressOffset>0x2c0</addressOffset>
          <size>0x20</size>
        </register>
        <register>
          <name>sFilterRegister.16.FR2</name>
          <addressOffset>0x2c4</addressOffset>
          <size>0x20</size>
        </register>
        <register>
          <name>sFilterRegister.17.FR1</name>
          <addressOffset>0x2c8</addressOffset>
          <size>0x20</size>
        </register>
        <register>
          <name>sFilterRegister.17.FR2</name>
          <addressOffset>0x2cc</addressOffset>
          <size>0x20</size>
        </register>
        <register>
          <name>sFilterRegister.18.FR1</name>
          <addressOffset>0x2d0</addressOffset>
          <size>0x20</size>
        </register>
        <register>
          <name>sFilterRegister.18.FR2</name>
          <addressOffset>0x2d4</addressOffset>
          <size>0x20</size>
        </register>
        <register>
          <name>sFilterRegister.19.FR1</name>
          <addressOffset>0x2d8</addressOffset>
          <size>0x20</size>
        </register>
        <register>
          <name>sFilterRegister.19.FR2</name>
          <addressOffset>0x2dc</addressOffset>
          <size>0x20</size>
        </register>
        <register>
          <name>sFilterRegister.20.FR1</name>
          <addressOffset>0x2e0</addressOffset>
          <size>0x20</size>
        </register>
        <register>
          <name>sFilterRegister.20.FR2</name>
          <addressOffset>0x2e4</addressOffset>
          <size>0x20</size>
        </register>
        <register>
          <name>sFilterRegister.21.FR1</name>
          <addressOffset>0x2e8</addressOffset>
          <size>0x20</size>
        </register>
        <register>
          <name>sFilterRegister.21.FR2</name>
          <addressOffset>0x2ec</addressOffset>
          <size>0x20</size>
        </register>
        <register>
          <name>sFilterRegister.22.FR1</name>
          <addressOffset>0x2f0</addressOffset>
          <size>0x20</size>
        </register>
        <register>
          <name>sFilterRegister.22.FR2</name>
          <addressOffset>0x2f4</addressOffset>
          <size>0x20</size>
        </register>
        <register>
          <name>sFilterRegister.23.FR1</name>
          <addressOffset>0x2f8</addressOffset>
          <size>0x20</size>
        </register>
        <register>
          <name>sFilterRegister.23.FR2</name>
          <addressOffset>0x2fc</addressOffset>
          <size>0x20</size>
        </register>
        <register>
          <name>sFilterRegister.24.FR1</name>
          <addressOffset>0x300</addressOffset>
          <size>0x20</size>
        </register>
        <register>
          <name>sFilterRegister.24.FR2</name>
          <addressOffset>0x304</addressOffset>
          <size>0x20</size>
        </register>
        <register>
          <name>sFilterRegister.25.FR1</name>
          <addressOffset>0x308</addressOffset>
          <size>0x20</size>
        </register>
        <register>
          <name>sFilterRegister.25.FR2</name>
          <addressOffset>0x30c</addressOffset>
          <size>0x20</size>
        </register>
        <register>
          <name>sFilterRegister.26.FR1</name>
          <addressOffset>0x310</addressOffset>
          <size>0x20</size>
        </register>
        <register>
          <name>sFilterRegister.26.FR2</name>
          <addressOffset>0x314</addressOffset>
          <size>0x20</size>
        </register>
        <register>
          <name>sFilterRegister.27.FR1</name>
          <addressOffset>0x318</addressOffset>
          <size>0x20</size>
        </register>
        <register>
          <name>sFilterRegister.27.FR2</name>
          <addressOffset>0x31c</addressOffset>
          <size>0x20</size>
        </register>
      </registers>
    </peripheral>
    <peripheral>
      <name>CEC</name>
      <baseAddress>0x40006c00</baseAddress>
      <registers>
        <register>
          <name>CR</name>
          <addressOffset>0x0</addressOffset>
          <size>0x20</size>
          <fields>
            <field>
              <name>CECEN</name>
              <bitOffset>0</bitOffset>
              <bitWidth>1</bitWidth>
            </field>
            <field>
              <name>TXSOM</name>
              <bitOffset>1</bitOffset>
              <bitWidth>1</bitWidth>
            </field>
            <field>
              <name>TXEOM</name>
              <bitOffset>2</bitOffset>
              <bitWidth>1</bitWidth>
            </field>
          </fields>
        </register>
        <register>
          <name>CFGR</name>
          <addressOffset>0x4</addressOffset>
          <size>0x20</size>
          <fields>
            <field>
              <name>SFT</name>
              <bitOffset>0</bitOffset>
              <bitWidth>3</bitWidth>
            </field>
            <field>
              <name>RXTOL</name>
              <bitOffset>3</bitOffset>
              <bitWidth>1</bitWidth>
            </field>
            <field>
              <name>BRESTP</name>
              <bitOffset>4</bitOffset>
              <bitWidth>1</bitWidth>
            </field>
            <field>
              <name>BREGEN</name>
              <bitOffset>5</bitOffset>
              <bitWidth>1</bitWidth>
            </field>
            <field>
              <name>LBPEGEN</name>
              <bitOffset>6</bitOffset>
              <bitWidth>1</bitWidth>
            </field>
            <field>
              <name>BRDNOGEN</name>
              <bitOffset>7</bitOffset>
              <bitWidth>1</bitWidth>
            </field>
            <field>
              <name>SFTOPT</name>
              <bitOffset>8</bitOffset>
              <bitWidth>1</bitWidth>
            </field>
            <field>
              <name>OAR</name>
              <bitOffset>16</bitOffset>
              <bitWidth>15</bitWidth>
            </field>
            <field>
              <name>LSTN</name>
              <bitOffset>31</bitOffset>
              <bitWidth>1</bitWidth>
            </field>
          </fields>
        </register>
        <register>
          <name>TXDR</name>
          <addressOffset>0x8</addressOffset>
          <size>0x20</size>
          <fields>
            <field>
              <name>TXD</name>
              <bitOffset>0</bitOffset>
              <bitWidth>8</bitWidth>
            </field>
          </fields>
        </register>
        <register>
          <name>RXDR</name>
          <addressOffset>0xc</addressOffset>
          <size>0x20</size>
          <fields>
            <field>
              <name>RXD</name>
              <bitOffset>0</bitOffset>
              <bitWidth>8</bitWidth>
            </field>
          </fields>
        </register>
        <register>
          <name>ISR</name>
          <addressOffset>0x10</addressOffset>
          <size>0x20</size>
          <fields>
            <field>
              <name>RXBR</name>
              <bitOffset>0</bitOffset>
              <bitWidth>1</bitWidth>
            </field>
            <field>
              <name>RXEND</name>
              <bitOffset>1</bitOffset>
              <bitWidth>1</bitWidth>
            </field>
            <field>
              <name>RXOVR</name>
              <bitOffset>2</bitOffset>
              <bitWidth>1</bitWidth>
            </field>
            <field>
              <name>BRE</name>
              <bitOffset>3</bitOffset>
              <bitWidth>1</bitWidth>
            </field>
            <field>
              <name>SBPE</name>
              <bitOffset>4</bitOffset>
              <bitWidth>1</bitWidth>
            </field>
            <field>
              <name>LBPE</name>
              <bitOffset>5</bitOffset>
              <bitWidth>1</bitWidth>
            </field>
            <field>
              <name>RXACKE</name>
              <bitOffset>6</bitOffset>
              <bitWidth>1</bitWidth>
            </field>
            <field>
              <name>ARBLST</name>
              <bitOffset>7</bitOffset>
              <bitWidth>1</bitWidth>
            </field>
            <field>
              <name>TXBR</name>
              <bitOffset>8</bitOffset>
              <bitWidth>1</bitWidth>
            </field>
            <field>
              <name>TXEND</name>
              <bitOffset>9</bitOffset>
              <bitWidth>1</bitWidth>
            </field>
            <field>
              <name>TXUDR</name>
              <bitOffset>10</bitOffset>
              <bitWidth>1</bitWidth>
            </field>
            <field>
              <name>TXERR</name>
              <bitOffset>11</bitOffset>
              <bitWidth>1</bitWidth>
            </field>
            <field>
              <name>TXACKE</name>
              <bitOffset>12</bitOffset>
              <bitWidth>1</bitWidth>
            </field>
          </fields>
        </register>
        <register>
          <name>IER</name>
          <addressOffset>0x14</addressOffset>
          <size>0x20</size>
          <fields>
            <field>
              <name>RXBRIE</name>
              <bitOffset>0</bitOffset>
              <bitWidth>1</bitWidth>
            </field>
            <field>
              <name>RXENDIE</name>
              <bitOffset>1</bitOffset>
              <bitWidth>1</bitWidth>
            </field>
            <field>
              <name>RXOVRIE</name>
              <bitOffset>2</bitOffset>
              <bitWidth>1</bitWidth>
            </field>
            <field>
              <name>BREIE</name>
              <bitOffset>3</bitOffset>
              <bitWidth>1</bitWidth>
            </field>
            <field>
              <name>SBPEIE</name>
              <bitOffset>4</bitOffset>
              <bitWidth>1</bitWidth>
            </field>
            <field>
              <name>LBPEIE</name>
              <bitOffset>5</bitOffset>
              <bitWidth>1</bitWidth>
            </field>
            <field>
              <name>RXACKEIE</name>
              <bitOffset>6</bitOffset>
              <bitWidth>1</bitWidth>
            </field>
            <field>
              <name>ARBLSTIE</name>
              <bitOffset>7</bitOffset>
              <bitWidth>1</bitWidth>
            </field>
            <field>
              <name>TXBRIE</name>
              <bitOffset>8</bitOffset>
              <bitWidth>1</bitWidth>
            </field>
            <field>
              <name>TXENDIE</name>
              <bitOffset>9</bitOffset>
              <bitWidth>1</bitWidth>
            </field>
            <field>
              <name>TXUDRIE</name>
              <bitOffset>10</bitOffset>
              <bitWidth>1</bitWidth>
            </field>
            <field>
              <name>TXERRIE</name>
              <bitOffset>11</bitOffset>
              <bitWidth>1</bitWidth>
            </field>
            <field>
              <name>TXACKEIE</name>
              <bitOffset>12</bitOffset>
              <bitWidth>1</bitWidth>
            </field>
          </fields>
        </register>
      </registers>
    </peripheral>
    <peripheral>
      <name>PWR</name>
      <baseAddress>0x40007000</baseAddress>
      <registers>
        <register>
          <name>CR1</name>
          <addressOffset>0x0</addressOffset>
          <size>0x20</size>
          <fields>
            <field>
              <name>LPDS</name>
              <bitOffset>0</bitOffset>
              <bitWidth>1</bitWidth>
            </field>
            <field>
              <name>PDDS</name>
              <bitOffset>1</bitOffset>
              <bitWidth>1</bitWidth>
            </field>
            <field>
              <name>CSBF</name>
              <bitOffset>3</bitOffset>
              <bitWidth>1</bitWidth>
            </field>
            <field>
              <name>PVDE</name>
              <bitOffset>4</bitOffset>
              <bitWidth>1</bitWidth>
            </field>
            <field>
              <name>PLS_LEV7</name>
              <bitOffset>5</bitOffset>
              <bitWidth>3</bitWidth>
            </field>
            <field>
              <name>PLS_LEV6</name>
              <bitOffset>6</bitOffset>
              <bitWidth>2</bitWidth>
            </field>
            <field>
              <name>PLS_LEV4</name>
              <bitOffset>7</bitOffset>
              <bitWidth>1</bitWidth>
            </field>
            <field>
              <name>DBP</name>
              <bitOffset>8</bitOffset>
              <bitWidth>1</bitWidth>
            </field>
            <field>
              <name>FPDS</name>
              <bitOffset>9</bitOffset>
              <bitWidth>1</bitWidth>
            </field>
            <field>
              <name>LPUDS</name>
              <bitOffset>10</bitOffset>
              <bitWidth>1</bitWidth>
            </field>
            <field>
              <name>MRUDS</name>
              <bitOffset>11</bitOffset>
              <bitWidth>1</bitWidth>
            </field>
            <field>
              <name>ADCDC1</name>
              <bitOffset>13</bitOffset>
              <bitWidth>1</bitWidth>
            </field>
            <field>
              <name>VOS</name>
              <bitOffset>14</bitOffset>
              <bitWidth>2</bitWidth>
            </field>
            <field>
              <name>ODEN</name>
              <bitOffset>16</bitOffset>
              <bitWidth>1</bitWidth>
            </field>
            <field>
              <name>ODSWEN</name>
              <bitOffset>17</bitOffset>
              <bitWidth>1</bitWidth>
            </field>
            <field>
              <name>UDEN</name>
              <bitOffset>18</bitOffset>
              <bitWidth>2</bitWidth>
            </field>
          </fields>
        </register>
        <register>
          <name>CSR1</name>
          <addressOffset>0x4</addressOffset>
          <size>0x20</size>
          <fields>
            <field>
              <name>WUIF</name>
              <bitOffset>0</bitOffset>
              <bitWidth>1</bitWidth>
            </field>
            <field>
              <name>SBF</name>
              <bitOffset>1</bitOffset>
              <bitWidth>1</bitWidth>
            </field>
            <field>
              <name>PVDO</name>
              <bitOffset>2</bitOffset>
              <bitWidth>1</bitWidth>
            </field>
            <field>
              <name>BRR</name>
              <bitOffset>3</bitOffset>
              <bitWidth>1</bitWidth>
            </field>
            <field>
              <name>EIWUP</name>
              <bitOffset>8</bitOffset>
              <bitWidth>1</bitWidth>
            </field>
            <field>
              <name>BRE</name>
              <bitOffset>9</bitOffset>
              <bitWidth>1</bitWidth>
            </field>
            <field>
              <name>VOSRDY</name>
              <bitOffset>14</bitOffset>
              <bitWidth>1</bitWidth>
            </field>
            <field>
              <name>ODRDY</name>
              <bitOffset>16</bitOffset>
              <bitWidth>1</bitWidth>
            </field>
            <field>
              <name>ODSWRDY</name>
              <bitOffset>17</bitOffset>
              <bitWidth>1</bitWidth>
            </field>
            <field>
              <name>UDRDY</name>
              <bitOffset>18</bitOffset>
              <bitWidth>2</bitWidth>
            </field>
          </fields>
        </register>
        <register>
          <name>CR2</name>
          <addressOffset>0x8</addressOffset>
          <size>0x20</size>
          <fields>
            <field>
              <name>CWUPF1</name>
              <bitOffset>0</bitOffset>
              <bitWidth>1</bitWidth>
            </field>
            <field>
              <name>CWUPF2</name>
              <bitOffset>1</bitOffset>
              <bitWidth>1</bitWidth>
            </field>
            <field>
              <name>CWUPF3</name>
              <bitOffset>2</bitOffset>
              <bitWidth>1</bitWidth>
            </field>
            <field>
              <name>CWUPF4</name>
              <bitOffset>3</bitOffset>
              <bitWidth>1</bitWidth>
            </field>
            <field>
              <name>CWUPF5</name>
              <bitOffset>4</bitOffset>
              <bitWidth>1</bitWidth>
            </field>
            <field>
              <name>CWUPF6</name>
              <bitOffset>5</bitOffset>
              <bitWidth>1</bitWidth>
            </field>
            <field>
              <name>WUPP1</name>
              <bitOffset>8</bitOffset>
              <bitWidth>1</bitWidth>
            </field>
            <field>
              <name>WUPP2</name>
              <bitOffset>9</bitOffset>
              <bitWidth>1</bitWidth>
            </field>
            <field>
              <name>WUPP3</name>
              <bitOffset>10</bitOffset>
              <bitWidth>1</bitWidth>
            </field>
            <field>
              <name>WUPP4</name>
              <bitOffset>11</bitOffset>
              <bitWidth>1</bitWidth>
            </field>
            <field>
              <name>WUPP5</name>
              <bitOffset>12</bitOffset>
              <bitWidth>1</bitWidth>
            </field>
            <field>
              <name>WUPP6</name>
              <bitOffset>13</bitOffset>
              <bitWidth>1</bitWidth>
            </field>
          </fields>
        </register>
        <register>
          <name>CSR2</name>
          <addressOffset>0xc</addressOffset>
          <size>0x20</size>
          <fields>
            <field>
              <name>WUPF1</name>
              <bitOffset>0</bitOffset>
              <bitWidth>1</bitWidth>
            </field>
            <field>
              <name>WUPF2</name>
              <bitOffset>1</bitOffset>
              <bitWidth>1</bitWidth>
            </field>
            <field>
              <name>WUPF3</name>
              <bitOffset>2</bitOffset>
              <bitWidth>1</bitWidth>
            </field>
            <field>
              <name>WUPF4</name>
              <bitOffset>3</bitOffset>
              <bitWidth>1</bitWidth>
            </field>
            <field>
              <name>WUPF5</name>
              <bitOffset>4</bitOffset>
              <bitWidth>1</bitWidth>
            </field>
            <field>
              <name>WUPF6</name>
              <bitOffset>5</bitOffset>
              <bitWidth>1</bitWidth>
            </field>
            <field>
              <name>EWUP1</name>
              <bitOffset>8</bitOffset>
              <bitWidth>1</bitWidth>
            </field>
            <field>
              <name>EWUP2</name>
              <bitOffset>9</bitOffset>
              <bitWidth>1</bitWidth>
            </field>
            <field>
              <name>EWUP3</name>
              <bitOffset>10</bitOffset>
              <bitWidth>1</bitWidth>
            </field>
            <field>
              <name>EWUP4</name>
              <bitOffset>11</bitOffset>
              <bitWidth>1</bitWidth>
            </field>
            <field>
              <name>EWUP5</name>
              <bitOffset>12</bitOffset>
              <bitWidth>1</bitWidth>
            </field>
            <field>
              <name>EWUP6</name>
              <bitOffset>13</bitOffset>
              <bitWidth>1</bitWidth>
            </field>
          </fields>
        </register>
      </registers>
    </peripheral>
    <peripheral>
      <name>DAC1</name>
      <baseAddress>0x40007400</baseAddress>
      <registers>
        <register>
          <name>CR</name>
          <addressOffset>0x0</addressOffset>
          <size>0x20</size>
          <fields>
            <field>
              <name>EN1</name>
              <bitOffset>0</bitOffset>
              <bitWidth>1</bitWidth>
            </field>
            <field>
              <name>BOFF1</name>
              <bitOffset>1</bitOffset>
              <bitWidth>1</bitWidth>
            </field>
            <field>
              <name>TEN1</name>
              <bitOffset>2</bitOffset>
              <bitWidth>1</bitWidth>
            </field>
            <field>
              <name>TSEL1</name>
              <bitOffset>3</bitOffset>
              <bitWidth>3</bitWidth>
            </field>
            <field>
              <name>WAVE1</name>
              <bitOffset>6</bitOffset>
              <bitWidth>2</bitWidth>
            </field>
            <field>
              <name>MAMP1</name>
              <bitOffset>8</bitOffset>
              <bitWidth>4</bitWidth>
            </field>
            <field>
              <name>DMAEN1</name>
              <bitOffset>12</bitOffset>
              <bitWidth>1</bitWidth>
            </field>
            <field>
              <name>DMAUDRIE1</name>
              <bitOffset>13</bitOffset>
              <bitWidth>1</bitWidth>
            </field>
            <field>
              <name>EN2</name>
              <bitOffset>16</bitOffset>
              <bitWidth>1</bitWidth>
            </field>
            <field>
              <name>BOFF2</name>
              <bitOffset>17</bitOffset>
              <bitWidth>1</bitWidth>
            </field>
            <field>
              <name>TEN2</name>
              <bitOffset>18</bitOffset>
              <bitWidth>1</bitWidth>
            </field>
            <field>
              <name>TSEL2</name>
              <bitOffset>19</bitOffset>
              <bitWidth>3</bitWidth>
            </field>
            <field>
              <name>WAVE2</name>
              <bitOffset>22</bitOffset>
              <bitWidth>2</bitWidth>
            </field>
            <field>
              <name>MAMP2</name>
              <bitOffset>24</bitOffset>
              <bitWidth>4</bitWidth>
            </field>
            <field>
              <name>DMAEN2</name>
              <bitOffset>28</bitOffset>
              <bitWidth>1</bitWidth>
            </field>
            <field>
              <name>DMAUDRIE2</name>
              <bitOffset>29</bitOffset>
              <bitWidth>1</bitWidth>
            </field>
          </fields>
        </register>
        <register>
          <name>SWTRIGR</name>
          <addressOffset>0x4</addressOffset>
          <size>0x20</size>
          <fields>
            <field>
              <name>SWTRIG1</name>
              <bitOffset>0</bitOffset>
              <bitWidth>1</bitWidth>
            </field>
            <field>
              <name>SWTRIG2</name>
              <bitOffset>1</bitOffset>
              <bitWidth>1</bitWidth>
            </field>
          </fields>
        </register>
        <register>
          <name>DHR12R1</name>
          <addressOffset>0x8</addressOffset>
          <size>0x20</size>
          <fields>
            <field>
              <name>DACC1DHR</name>
              <bitOffset>0</bitOffset>
              <bitWidth>12</bitWidth>
            </field>
          </fields>
        </register>
        <register>
          <name>DHR12L1</name>
          <addressOffset>0xc</addressOffset>
          <size>0x20</size>
          <fields>
            <field>
              <name>DACC1DHR</name>
              <bitOffset>4</bitOffset>
              <bitWidth>12</bitWidth>
            </field>
          </fields>
        </register>
        <register>
          <name>DHR8R1</name>
          <addressOffset>0x10</addressOffset>
          <size>0x20</size>
          <fields>
            <field>
              <name>DACC1DHR</name>
              <bitOffset>0</bitOffset>
              <bitWidth>8</bitWidth>
            </field>
          </fields>
        </register>
        <register>
          <name>DHR12R2</name>
          <addressOffset>0x14</addressOffset>
          <size>0x20</size>
          <fields>
            <field>
              <name>DACC2DHR</name>
              <bitOffset>0</bitOffset>
              <bitWidth>12</bitWidth>
            </field>
          </fields>
        </register>
        <register>
          <name>DHR12L2</name>
          <addressOffset>0x18</addressOffset>
          <size>0x20</size>
          <fields>
            <field>
              <name>DACC2DHR</name>
              <bitOffset>4</bitOffset>
              <bitWidth>12</bitWidth>
            </field>
          </fields>
        </register>
        <register>
          <name>DHR8R2</name>
          <addressOffset>0x1c</addressOffset>
          <size>0x20</size>
          <fields>
            <field>
              <name>DACC2DHR</name>
              <bitOffset>0</bitOffset>
              <bitWidth>8</bitWidth>
            </field>
          </fields>
        </register>
        <register>
          <name>DHR12RD</name>
          <addressOffset>0x20</addressOffset>
          <size>0x20</size>
          <fields>
            <field>
              <name>DACC1DHR</name>
        </register>
        <register>
          <name>FGCLUT.230</name>
          <addressOffset>0x798</addressOffset>
          <size>0x20</size>
        </register>
        <register>
          <name>FGCLUT.231</name>
          <addressOffset>0x79c</addressOffset>
          <size>0x20</size>
        </register>
        <register>
          <name>FGCLUT.232</name>
          <addressOffset>0x7a0</addressOffset>
          <size>0x20</size>
        </register>
        <register>
          <name>FGCLUT.233</name>
          <addressOffset>0x7a4</addressOffset>
          <size>0x20</size>
        </register>
        <register>
          <name>FGCLUT.234</name>
          <addressOffset>0x7a8</addressOffset>
          <size>0x20</size>
        </register>
        <register>
          <name>FGCLUT.235</name>
          <addressOffset>0x7ac</addressOffset>
          <size>0x20</size>
        </register>
        <register>
          <name>FGCLUT.236</name>
          <addressOffset>0x7b0</addressOffset>
          <size>0x20</size>
        </register>
        <register>
          <name>FGCLUT.237</name>
          <addressOffset>0x7b4</addressOffset>
          <size>0x20</size>
        </register>
        <register>
          <name>FGCLUT.238</name>
          <addressOffset>0x7b8</addressOffset>
          <size>0x20</size>
        </register>
        <register>
          <name>FGCLUT.239</name>
          <addressOffset>0x7bc</addressOffset>
          <size>0x20</size>
        </register>
        <register>
          <name>FGCLUT.240</name>
          <addressOffset>0x7c0</addressOffset>
          <size>0x20</size>
        </register>
        <register>
          <name>FGCLUT.241</name>
          <addressOffset>0x7c4</addressOffset>
          <size>0x20</size>
        </register>
        <register>
          <name>FGCLUT.242</name>
          <addressOffset>0x7c8</addressOffset>
          <size>0x20</size>
        </register>
        <register>
          <name>FGCLUT.243</name>
          <addressOffset>0x7cc</addressOffset>
          <size>0x20</size>
        </register>
        <register>
          <name>FGCLUT.244</name>
          <addressOffset>0x7d0</addressOffset>
          <size>0x20</size>
        </register>
        <register>
          <name>FGCLUT.245</name>
          <addressOffset>0x7d4</addressOffset>
          <size>0x20</size>
        </register>
        <register>
          <name>FGCLUT.246</name>
          <addressOffset>0x7d8</addressOffset>
          <size>0x20</size>
        </register>
        <register>
          <name>FGCLUT.247</name>
          <addressOffset>0x7dc</addressOffset>
          <size>0x20</size>
        </register>
        <register>
          <name>FGCLUT.248</name>
          <addressOffset>0x7e0</addressOffset>
          <size>0x20</size>
        </register>
        <register>
          <name>FGCLUT.249</name>
          <addressOffset>0x7e4</addressOffset>
          <size>0x20</size>
        </register>
        <register>
          <name>FGCLUT.250</name>
          <addressOffset>0x7e8</addressOffset>
          <size>0x20</size>
        </register>
        <register>
          <name>FGCLUT.251</name>
          <addressOffset>0x7ec</addressOffset>
          <size>0x20</size>
        </register>
        <register>
          <name>FGCLUT.252</name>
          <addressOffset>0x7f0</addressOffset>
          <size>0x20</size>
        </register>
        <register>
          <name>FGCLUT.253</name>
          <addressOffset>0x7f4</addressOffset>
          <size>0x20</size>
        </register>
        <register>
          <name>FGCLUT.254</name>
          <addressOffset>0x7f8</addressOffset>
          <size>0x20</size>
        </register>
        <register>
          <name>FGCLUT.255</name>
          <addressOffset>0x7fc</addressOffset>
          <size>0x20</size>
        </register>
        <register>
          <name>BGCLUT.0</name>
          <addressOffset>0x800</addressOffset>
          <size>0x20</size>
        </register>
        <register>
          <name>BGCLUT.1</name>
          <addressOffset>0x804</addressOffset>
          <size>0x20</size>
        </register>
        <register>
          <name>BGCLUT.2</name>
          <addressOffset>0x808</addressOffset>
          <size>0x20</size>
        </register>
        <register>
          <name>BGCLUT.3</name>
          <addressOffset>0x80c</addressOffset>
          <size>0x20</size>
        </register>
        <register>
          <name>BGCLUT.4</name>
          <addressOffset>0x810</addressOffset>
          <size>0x20</size>
        </register>
        <register>
          <name>BGCLUT.5</name>
          <addressOffset>0x814</addressOffset>
          <size>0x20</size>
        </register>
        <register>
          <name>BGCLUT.6</name>
          <addressOffset>0x818</addressOffset>
          <size>0x20</size>
        </register>
        <register>
          <name>BGCLUT.7</name>
          <addressOffset>0x81c</addressOffset>
          <size>0x20</size>
        </register>
        <register>
          <name>BGCLUT.8</name>
          <addressOffset>0x820</addressOffset>
          <size>0x20</size>
        </register>
        <register>
          <name>BGCLUT.9</name>
          <addressOffset>0x824</addressOffset>
          <size>0x20</size>
        </register>
        <register>
          <name>BGCLUT.10</name>
          <addressOffset>0x828</addressOffset>
          <size>0x20</size>
        </register>
        <register>
          <name>BGCLUT.11</name>
          <addressOffset>0x82c</addressOffset>
          <size>0x20</size>
        </register>
        <register>
          <name>BGCLUT.12</name>
          <addressOffset>0x830</addressOffset>
          <size>0x20</size>
        </register>
        <register>
          <name>BGCLUT.13</name>
          <addressOffset>0x834</addressOffset>
          <size>0x20</size>
        </register>
        <register>
          <name>BGCLUT.14</name>
          <addressOffset>0x838</addressOffset>
          <size>0x20</size>
        </register>
        <register>
          <name>BGCLUT.15</name>
          <addressOffset>0x83c</addressOffset>
          <size>0x20</size>
        </register>
        <register>
          <name>BGCLUT.16</name>
          <addressOffset>0x840</addressOffset>
          <size>0x20</size>
        </register>
        <register>
          <name>BGCLUT.17</name>
          <addressOffset>0x844</addressOffset>
          <size>0x20</size>
        </register>
        <register>
          <name>BGCLUT.18</name>
          <addressOffset>0x848</addressOffset>
          <size>0x20</size>
        </register>
        <register>
          <name>BGCLUT.19</name>
          <addressOffset>0x84c</addressOffset>
          <size>0x20</size>
        </register>
        <register>
          <name>BGCLUT.20</name>
          <addressOffset>0x850</addressOffset>
          <size>0x20</size>
        </register>
        <register>
          <name>BGCLUT.21</name>
          <addressOffset>0x854</addressOffset>
          <size>0x20</size>
        </register>
        <register>
          <name>BGCLUT.22</name>
          <addressOffset>0x858</addressOffset>
          <size>0x20</size>
        </register>
        <register>
          <name>BGCLUT.23</name>
          <addressOffset>0x85c</addressOffset>
          <size>0x20</size>
        </register>
        <register>
          <name>BGCLUT.24</name>
          <addressOffset>0x860</addressOffset>
          <size>0x20</size>
        </register>
        <register>
          <name>BGCLUT.25</name>
          <addressOffset>0x864</addressOffset>
          <size>0x20</size>
        </register>
        <register>
          <name>BGCLUT.26</name>
          <addressOffset>0x868</addressOffset>
          <size>0x20</size>
        </register>
        <register>
          <name>BGCLUT.27</name>
          <addressOffset>0x86c</addressOffset>
          <size>0x20</size>
        </register>
        <register>
          <name>BGCLUT.28</name>
          <addressOffset>0x870</addressOffset>
          <size>0x20</size>
        </register>
        <register>
          <name>BGCLUT.29</name>
          <addressOffset>0x874</addressOffset>
          <size>0x20</size>
        </register>
        <register>
          <name>BGCLUT.30</name>
          <addressOffset>0x878</addressOffset>
          <size>0x20</size>
        </register>
        <register>
          <name>BGCLUT.31</name>
          <addressOffset>0x87c</addressOffset>
          <size>0x20</size>
        </register>
        <register>
          <name>BGCLUT.32</name>
          <addressOffset>0x880</addressOffset>
          <size>0x20</size>
        </register>
        <register>
          <name>BGCLUT.33</name>
          <addressOffset>0x884</addressOffset>
          <size>0x20</size>
        </register>
        <register>
          <name>BGCLUT.34</name>
          <addressOffset>0x888</addressOffset>
          <size>0x20</size>
        </register>
        <register>
          <name>BGCLUT.35</name>
          <addressOffset>0x88c</addressOffset>
          <size>0x20</size>
        </register>
        <register>
          <name>BGCLUT.36</name>
          <addressOffset>0x890</addressOffset>
          <size>0x20</size>
        </register>
        <register>
          <name>BGCLUT.37</name>
          <addressOffset>0x894</addressOffset>
          <size>0x20</size>
        </register>
        <register>
          <name>BGCLUT.38</name>
          <addressOffset>0x898</addressOffset>
          <size>0x20</size>
        </register>
        <register>
          <name>BGCLUT.39</name>
          <addressOffset>0x89c</addressOffset>
          <size>0x20</size>
        </register>
        <register>
          <name>BGCLUT.40</name>
          <addressOffset>0x8a0</addressOffset>
          <size>0x20</size>
        </register>
        <register>
          <name>BGCLUT.41</name>
          <addressOffset>0x8a4</addressOffset>
          <size>0x20</size>
        </register>
        <register>
          <name>BGCLUT.42</name>
          <addressOffset>0x8a8</addressOffset>
          <size>0x20</size>
        </register>
        <register>
          <name>BGCLUT.43</name>
          <addressOffset>0x8ac</addressOffset>
          <size>0x20</size>
        </register>
        <register>
          <name>BGCLUT.44</name>
          <addressOffset>0x8b0</addressOffset>
          <size>0x20</size>
        </register>
        <register>
          <name>BGCLUT.45</name>
          <addressOffset>0x8b4</addressOffset>
          <size>0x20</size>
        </register>
        <register>
          <name>BGCLUT.46</name>
          <addressOffset>0x8b8</addressOffset>
          <size>0x20</size>
        </register>
        <register>
          <name>BGCLUT.47</name>
          <addressOffset>0x8bc</addressOffset>
          <size>0x20</size>
        </register>
        <register>
          <name>BGCLUT.48</name>
          <addressOffset>0x8c0</addressOffset>
          <size>0x20</size>
        </register>
        <register>
          <name>BGCLUT.49</name>
          <addressOffset>0x8c4</addressOffset>
          <size>0x20</size>
        </register>
        <register>
          <name>BGCLUT.50</name>
          <addressOffset>0x8c8</addressOffset>
          <size>0x20</size>
        </register>
        <register>
          <name>BGCLUT.51</name>
          <addressOffset>0x8cc</addressOffset>
          <size>0x20</size>
        </register>
        <register>
          <name>BGCLUT.52</name>
          <addressOffset>0x8d0</addressOffset>
          <size>0x20</size>
        </register>
        <register>
          <name>BGCLUT.53</name>
          <addressOffset>0x8d4</addressOffset>
          <size>0x20</size>
        </register>
        <register>
          <name>BGCLUT.54</name>
          <addressOffset>0x8d8</addressOffset>
          <size>0x20</size>
        </register>
        <register>
          <name>BGCLUT.55</name>
          <addressOffset>0x8dc</addressOffset>
          <size>0x20</size>
        </register>
        <register>
          <name>BGCLUT.56</name>
          <addressOffset>0x8e0</addressOffset>
          <size>0x20</size>
        </register>
        <register>
          <name>BGCLUT.57</name>
          <addressOffset>0x8e4</addressOffset>
          <size>0x20</size>
        </register>
        <register>
          <name>BGCLUT.58</name>
          <addressOffset>0x8e8</addressOffset>
          <size>0x20</size>
        </register>
        <register>
          <name>BGCLUT.59</name>
          <addressOffset>0x8ec</addressOffset>
          <size>0x20</size>
        </register>
        <register>
          <name>BGCLUT.60</name>
          <addressOffset>0x8f0</addressOffset>
          <size>0x20</size>
        </register>
        <register>
          <name>BGCLUT.61</name>
          <addressOffset>0x8f4</addressOffset>
          <size>0x20</size>
        </register>
        <register>
          <name>BGCLUT.62</name>
          <addressOffset>0x8f8</addressOffset>
          <size>0x20</size>
        </register>
        <register>
          <name>BGCLUT.63</name>
          <addressOffset>0x8fc</addressOffset>
          <size>0x20</size>
        </register>
        <register>
          <name>BGCLUT.64</name>
          <addressOffset>0x900</addressOffset>
          <size>0x20</size>
        </register>
        <register>
          <name>BGCLUT.65</name>
          <addressOffset>0x904</addressOffset>
          <size>0x20</size>
        </register>
        <register>
          <name>BGCLUT.66</name>
          <addressOffset>0x908</addressOffset>
          <size>0x20</size>
        </register>
        <register>
          <name>BGCLUT.67</name>
          <addressOffset>0x90c</addressOffset>
          <size>0x20</size>
        </register>
        <register>
          <name>BGCLUT.68</name>
          <addressOffset>0x910</addressOffset>
          <size>0x20</size>
        </register>
        <register>
          <name>BGCLUT.69</name>
          <addressOffset>0x914</addressOffset>
          <size>0x20</size>
        </register>
        <register>
          <name>BGCLUT.70</name>
          <addressOffset>0x918</addressOffset>
          <size>0x20</size>
        </register>
        <register>
          <name>BGCLUT.71</name>
          <addressOffset>0x91c</addressOffset>
          <size>0x20</size>
        </register>
        <register>
          <name>BGCLUT.72</name>
          <addressOffset>0x920</addressOffset>
          <size>0x20</size>
        </register>
        <register>
          <name>BGCLUT.73</name>
          <addressOffset>0x924</addressOffset>
          <size>0x20</size>
        </register>
        <register>
          <name>BGCLUT.74</name>
          <addressOffset>0x928</addressOffset>
          <size>0x20</size>
        </register>
        <register>
          <name>BGCLUT.75</name>
          <addressOffset>0x92c</addressOffset>
          <size>0x20</size>
        </register>
        <register>
          <name>BGCLUT.76</name>
          <addressOffset>0x930</addressOffset>
          <size>0x20</size>
        </register>
        <register>
          <name>BGCLUT.77</name>
          <addressOffset>0x934</addressOffset>
          <size>0x20</size>
        </register>
        <register>
          <name>BGCLUT.78</name>
          <addressOffset>0x938</addressOffset>
          <size>0x20</size>
        </register>
        <register>
          <name>BGCLUT.79</name>
          <addressOffset>0x93c</addressOffset>
          <size>0x20</size>
        </register>
        <register>
          <name>BGCLUT.80</name>
          <addressOffset>0x940</addressOffset>
          <size>0x20</size>
        </register>
        <register>
          <name>BGCLUT.81</name>
          <addressOffset>0x944</addressOffset>
          <size>0x20</size>
        </register>
        <register>
          <name>BGCLUT.82</name>
          <addressOffset>0x948</addressOffset>
          <size>0x20</size>
        </register>
        <register>
          <name>BGCLUT.83</name>
          <addressOffset>0x94c</addressOffset>
          <size>0x20</size>
        </register>
        <register>
          <name>BGCLUT.84</name>
          <addressOffset>0x950</addressOffset>
          <size>0x20</size>
        </register>
        <register>
          <name>BGCLUT.85</name>
          <addressOffset>0x954</addressOffset>
          <size>0x20</size>
        </register>
        <register>
          <name>BGCLUT.86</name>
          <addressOffset>0x958</addressOffset>
          <size>0x20</size>
        </register>
        <register>
          <name>BGCLUT.87</name>
          <addressOffset>0x95c</addressOffset>
          <size>0x20</size>
        </register>
        <register>
          <name>BGCLUT.88</name>
          <addressOffset>0x960</addressOffset>
          <size>0x20</size>
        </register>
        <register>
          <name>BGCLUT.89</name>
          <addressOffset>0x964</addressOffset>
          <size>0x20</size>
        </register>
        <register>
          <name>BGCLUT.90</name>
          <addressOffset>0x968</addressOffset>
          <size>0x20</size>
        </register>
        <register>
          <name>BGCLUT.91</name>
          <addressOffset>0x96c</addressOffset>
          <size>0x20</size>
        </register>
        <register>
          <name>BGCLUT.92</name>
          <addressOffset>0x970</addressOffset>
          <size>0x20</size>
        </register>
        <register>
          <name>BGCLUT.93</name>
          <addressOffset>0x974</addressOffset>
          <size>0x20</size>
        </register>
        <register>
          <name>BGCLUT.94</name>
          <addressOffset>0x978</addressOffset>
          <size>0x20</size>
        </register>
        <register>
          <name>BGCLUT.95</name>
          <addressOffset>0x97c</addressOffset>
          <size>0x20</size>
        </register>
        <register>
          <name>BGCLUT.96</name>
          <addressOffset>0x980</addressOffset>
          <size>0x20</size>
        </register>
        <register>
          <name>BGCLUT.97</name>
          <addressOffset>0x984</addressOffset>
          <size>0x20</size>
        </register>
        <register>
          <name>BGCLUT.98</name>
          <addressOffset>0x988</addressOffset>
          <size>0x20</size>
        </register>
        <register>
          <name>BGCLUT.99</name>
          <addressOffset>0x98c</addressOffset>
          <size>0x20</size>
        </register>
        <register>
          <name>BGCLUT.100</name>
          <addressOffset>0x990</addressOffset>
          <size>0x20</size>
        </register>
        <register>
          <name>BGCLUT.101</name>
          <addressOffset>0x994</addressOffset>
          <size>0x20</size>
        </register>
        <register>
          <name>BGCLUT.102</name>
          <addressOffset>0x998</addressOffset>
          <size>0x20</size>
        </register>
        <register>
          <name>BGCLUT.103</name>
          <addressOffset>0x99c</addressOffset>
          <size>0x20</size>
        </register>
        <register>
          <name>BGCLUT.104</name>
          <addressOffset>0x9a0</addressOffset>
          <size>0x20</size>
        </register>
        <register>
          <name>BGCLUT.105</name>
          <addressOffset>0x9a4</addressOffset>
          <size>0x20</size>
        </register>
        <register>
          <name>BGCLUT.106</name>
          <addressOffset>0x9a8</addressOffset>
          <size>0x20</size>
        </register>
        <register>
          <name>BGCLUT.107</name>
          <addressOffset>0x9ac</addressOffset>
          <size>0x20</size>
        </register>
        <register>
          <name>BGCLUT.108</name>
          <addressOffset>0x9b0</addressOffset>
          <size>0x20</size>
        </register>
        <register>
          <name>BGCLUT.109</name>
          <addressOffset>0x9b4</addressOffset>
          <size>0x20</size>
        </register>
        <register>
          <name>BGCLUT.110</name>
          <addressOffset>0x9b8</addressOffset>
          <size>0x20</size>
        </register>
        <register>
          <name>BGCLUT.111</name>
          <addressOffset>0x9bc</addressOffset>
          <size>0x20</size>
        </register>
        <register>
          <name>BGCLUT.112</name>
          <addressOffset>0x9c0</addressOffset>
          <size>0x20</size>
        </register>
        <register>
          <name>BGCLUT.113</name>
          <addressOffset>0x9c4</addressOffset>
          <size>0x20</size>
        </register>
        <register>
          <name>BGCLUT.114</name>
          <addressOffset>0x9c8</addressOffset>
          <size>0x20</size>
        </register>
        <register>
          <name>BGCLUT.115</name>
          <addressOffset>0x9cc</addressOffset>
          <size>0x20</size>
        </register>
        <register>
          <name>BGCLUT.116</name>
          <addressOffset>0x9d0</addressOffset>
          <size>0x20</size>
        </register>
        <register>
          <name>BGCLUT.117</name>
          <addressOffset>0x9d4</addressOffset>
          <size>0x20</size>
        </register>
        <register>
          <name>BGCLUT.118</name>
          <addressOffset>0x9d8</addressOffset>
          <size>0x20</size>
        </register>
        <register>
          <name>BGCLUT.119</name>
          <addressOffset>0x9dc</addressOffset>
          <size>0x20</size>
        </register>
        <register>
          <name>BGCLUT.120</name>
          <addressOffset>0x9e0</addressOffset>
          <size>0x20</size>
        </register>
        <register>
          <name>BGCLUT.121</name>
          <addressOffset>0x9e4</addressOffset>
          <size>0x20</size>
        </register>
        <register>
          <name>BGCLUT.122</name>
          <addressOffset>0x9e8</addressOffset>
          <size>0x20</size>
        </register>
        <register>
          <name>BGCLUT.123</name>
          <addressOffset>0x9ec</addressOffset>
          <size>0x20</size>
        </register>
        <register>
          <name>BGCLUT.124</name>
          <addressOffset>0x9f0</addressOffset>
          <size>0x20</size>
        </register>
        <register>
          <name>BGCLUT.125</name>
          <addressOffset>0x9f4</addressOffset>
          <size>0x20</size>
        </register>
        <register>
          <name>BGCLUT.126</name>
          <addressOffset>0x9f8</addressOffset>
          <size>0x20</size>
        </register>
        <register>
          <name>BGCLUT.127</name>
          <addressOffset>0x9fc</addressOffset>
          <size>0x20</size>
        </register>
        <register>
          <name>BGCLUT.128</name>
          <addressOffset>0xa00</addressOffset>
          <size>0x20</size>
        </register>
        <register>
          <name>BGCLUT.129</name>
          <addressOffset>0xa04</addressOffset>
          <size>0x20</size>
        </register>
        <register>
          <name>BGCLUT.130</name>
          <addressOffset>0xa08</addressOffset>
          <size>0x20</size>
        </register>
        <register>
          <name>BGCLUT.131</name>
          <addressOffset>0xa0c</addressOffset>
          <size>0x20</size>
        </register>
        <register>
          <name>BGCLUT.132</name>
          <addressOffset>0xa10</addressOffset>
          <size>0x20</size>
        </register>
        <register>
          <name>BGCLUT.133</name>
          <addressOffset>0xa14</addressOffset>
          <size>0x20</size>
        </register>
        <register>
          <name>BGCLUT.134</name>
          <addressOffset>0xa18</addressOffset>
          <size>0x20</size>
        </register>
        <register>
          <name>BGCLUT.135</name>
          <addressOffset>0xa1c</addressOffset>
          <size>0x20</size>
        </register>
        <register>
          <name>BGCLUT.136</name>
          <addressOffset>0xa20</addressOffset>
          <size>0x20</size>
        </register>
        <register>
          <name>BGCLUT.137</name>
          <addressOffset>0xa24</addressOffset>
          <size>0x20</size>
        </register>
        <register>
          <name>BGCLUT.138</name>
          <addressOffset>0xa28</addressOffset>
          <size>0x20</size>
        </register>
        <register>
          <name>BGCLUT.139</name>
          <addressOffset>0xa2c</addressOffset>
          <size>0x20</size>
        </register>
        <register>
          <name>BGCLUT.140</name>
          <addressOffset>0xa30</addressOffset>
          <size>0x20</size>
        </register>
        <register>
          <name>BGCLUT.141</name>
          <addressOffset>0xa34</addressOffset>
          <size>0x20</size>
        </register>
        <register>
          <name>BGCLUT.142</name>
          <addressOffset>0xa38</addressOffset>
          <size>0x20</size>
        </register>
        <register>
          <name>BGCLUT.143</name>
          <addressOffset>0xa3c</addressOffset>
          <size>0x20</size>
        </register>
        <register>
          <name>BGCLUT.144</name>
          <addressOffset>0xa40</addressOffset>
          <size>0x20</size>
        </register>
        <register>
          <name>BGCLUT.145</name>
          <addressOffset>0xa44</addressOffset>
          <size>0x20</size>
        </register>
        <register>
          <name>BGCLUT.146</name>
          <addressOffset>0xa48</addressOffset>
          <size>0x20</size>
        </register>
        <register>
          <name>BGCLUT.147</name>
          <addressOffset>0xa4c</addressOffset>
          <size>0x20</size>
        </register>
        <register>
          <name>BGCLUT.148</name>
          <addressOffset>0xa50</addressOffset>
          <size>0x20</size>
        </register>
        <register>
          <name>BGCLUT.149</name>
          <addressOffset>0xa54</addressOffset>
          <size>0x20</size>
        </register>
        <register>
          <name>BGCLUT.150</name>
          <addressOffset>0xa58</addressOffset>
          <size>0x20</size>
        </register>
        <register>
          <name>BGCLUT.151</name>
          <addressOffset>0xa5c</addressOffset>
          <size>0x20</size>
        </register>
        <register>
          <name>BGCLUT.152</name>
          <addressOffset>0xa60</addressOffset>
          <size>0x20</size>
        </register>
        <register>
          <name>BGCLUT.153</name>
          <addressOffset>0xa64</addressOffset>
          <size>0x20</size>
        </register>
        <register>
          <name>BGCLUT.154</name>
          <addressOffset>0xa68</addressOffset>
          <size>0x20</size>
        </register>
        <register>
          <name>BGCLUT.155</name>
          <addressOffset>0xa6c</addressOffset>
          <size>0x20</size>
        </register>
        <register>
          <name>BGCLUT.156</name>
          <addressOffset>0xa70</addressOffset>
          <size>0x20</size>
        </register>
        <register>
          <name>BGCLUT.157</name>
          <addressOffset>0xa74</addressOffset>
          <size>0x20</size>
        </register>
        <register>
          <name>BGCLUT.158</name>
          <addressOffset>0xa78</addressOffset>
          <size>0x20</size>
        </register>
        <register>
          <name>BGCLUT.159</name>
          <addressOffset>0xa7c</addressOffset>
          <size>0x20</size>
        </register>
        <register>
          <name>BGCLUT.160</name>
          <addressOffset>0xa80</addressOffset>
          <size>0x20</size>
        </register>
        <register>
          <name>BGCLUT.161</name>
          <addressOffset>0xa84</addressOffset>
          <size>0x20</size>
        </register>
        <register>
          <name>BGCLUT.162</name>
          <addressOffset>0xa88</addressOffset>
          <size>0x20</size>
        </register>
        <register>
          <name>BGCLUT.163</name>
          <addressOffset>0xa8c</addressOffset>
          <size>0x20</size>
        </register>
        <register>
          <name>BGCLUT.164</name>
          <addressOffset>0xa90</addressOffset>
          <size>0x20</size>
        </register>
        <register>
          <name>BGCLUT.165</name>
          <addressOffset>0xa94</addressOffset>
          <size>0x20</size>
        </register>
        <register>
          <name>BGCLUT.166</name>
          <addressOffset>0xa98</addressOffset>
          <size>0x20</size>
        </register>
        <register>
          <name>BGCLUT.167</name>
          <addressOffset>0xa9c</addressOffset>
          <size>0x20</size>
        </register>
        <register>
          <name>BGCLUT.168</name>
          <addressOffset>0xaa0</addressOffset>
          <size>0x20</size>
        </register>
        <register>
          <name>BGCLUT.169</name>
          <addressOffset>0xaa4</addressOffset>
          <size>0x20</size>
        </register>
        <register>
          <name>BGCLUT.170</name>
          <addressOffset>0xaa8</addressOffset>
          <size>0x20</size>
        </register>
        <register>
          <name>BGCLUT.171</name>
          <addressOffset>0xaac</addressOffset>
          <size>0x20</size>
        </register>
        <register>
          <name>BGCLUT.172</name>
          <addressOffset>0xab0</addressOffset>
          <size>0x20</size>
        </register>
        <register>
          <name>BGCLUT.173</name>
          <addressOffset>0xab4</addressOffset>
          <size>0x20</size>
        </register>
        <register>
          <name>BGCLUT.174</name>
          <addressOffset>0xab8</addressOffset>
          <size>0x20</size>
        </register>
        <register>
          <name>BGCLUT.175</name>
          <addressOffset>0xabc</addressOffset>
          <size>0x20</size>
        </register>
        <register>
          <name>BGCLUT.176</name>
          <addressOffset>0xac0</addressOffset>
          <size>0x20</size>
        </register>
        <register>
          <name>BGCLUT.177</name>
          <addressOffset>0xac4</addressOffset>
          <size>0x20</size>
        </register>
        <register>
          <name>BGCLUT.178</name>
          <addressOffset>0xac8</addressOffset>
          <size>0x20</size>
        </register>
        <register>
          <name>BGCLUT.179</name>
          <addressOffset>0xacc</addressOffset>
          <size>0x20</size>
        </register>
        <register>
          <name>BGCLUT.180</name>
          <addressOffset>0xad0</addressOffset>
          <size>0x20</size>
        </register>
        <register>
          <name>BGCLUT.181</name>
          <addressOffset>0xad4</addressOffset>
          <size>0x20</size>
        </register>
        <register>
          <name>BGCLUT.182</name>
          <addressOffset>0xad8</addressOffset>
          <size>0x20</size>
        </register>
        <register>
          <name>BGCLUT.183</name>
          <addressOffset>0xadc</addressOffset>
          <size>0x20</size>
        </register>
        <register>
          <name>BGCLUT.184</name>
          <addressOffset>0xae0</addressOffset>
          <size>0x20</size>
        </register>
        <register>
          <name>BGCLUT.185</name>
          <addressOffset>0xae4</addressOffset>
          <size>0x20</size>
        </register>
        <register>
          <name>BGCLUT.186</name>
          <addressOffset>0xae8</addressOffset>
          <size>0x20</size>
        </register>
        <register>
          <name>BGCLUT.187</name>
          <addressOffset>0xaec</addressOffset>
          <size>0x20</size>
        </register>
        <register>
          <name>BGCLUT.188</name>
          <addressOffset>0xaf0</addressOffset>
          <size>0x20</size>
        </register>
        <register>
          <name>BGCLUT.189</name>
          <addressOffset>0xaf4</addressOffset>
          <size>0x20</size>
        </register>
        <register>
          <name>BGCLUT.190</name>
          <addressOffset>0xaf8</addressOffset>
          <size>0x20</size>
        </register>
        <register>
          <name>BGCLUT.191</name>
          <addressOffset>0xafc</addressOffset>
          <size>0x20</size>
        </register>
        <register>
          <name>BGCLUT.192</name>
          <addressOffset>0xb00</addressOffset>
          <size>0x20</size>
        </register>
        <register>
          <name>BGCLUT.193</name>
          <addressOffset>0xb04</addressOffset>
          <size>0x20</size>
        </register>
        <register>
          <name>BGCLUT.194</name>
          <addressOffset>0xb08</addressOffset>
          <size>0x20</size>
        </register>
        <register>
          <name>BGCLUT.195</name>
          <addressOffset>0xb0c</addressOffset>
          <size>0x20</size>
        </register>
        <register>
          <name>BGCLUT.196</name>
          <addressOffset>0xb10</addressOffset>
          <size>0x20</size>
        </register>
        <register>
          <name>BGCLUT.197</name>
          <addressOffset>0xb14</addressOffset>
          <size>0x20</size>
        </register>
        <register>
          <name>BGCLUT.198</name>
          <addressOffset>0xb18</addressOffset>
          <size>0x20</size>
        </register>
        <register>
          <name>BGCLUT.199</name>
          <addressOffset>0xb1c</addressOffset>
          <size>0x20</size>
        </register>
        <register>
          <name>BGCLUT.200</name>
          <addressOffset>0xb20</addressOffset>
          <size>0x20</size>
        </register>
        <register>
          <name>BGCLUT.201</name>
          <addressOffset>0xb24</addressOffset>
          <size>0x20</size>
        </register>
        <register>
          <name>BGCLUT.202</name>
          <addressOffset>0xb28</addressOffset>
          <size>0x20</size>
        </register>
        <register>
          <name>BGCLUT.203</name>
          <addressOffset>0xb2c</addressOffset>
          <size>0x20</size>
        </register>
        <register>
          <name>BGCLUT.204</name>
          <addressOffset>0xb30</addressOffset>
          <size>0x20</size>
        </register>
        <register>
          <name>BGCLUT.205</name>
          <addressOffset>0xb34</addressOffset>
          <size>0x20</size>
        </register>
        <register>
          <name>BGCLUT.206</name>
          <addressOffset>0xb38</addressOffset>
          <size>0x20</size>
        </register>
        <register>
          <name>BGCLUT.207</name>
          <addressOffset>0xb3c</addressOffset>
          <size>0x20</size>
        </register>
        <register>
          <name>BGCLUT.208</name>
          <addressOffset>0xb40</addressOffset>
          <size>0x20</size>
        </register>
        <register>
          <name>BGCLUT.209</name>
          <addressOffset>0xb44</addressOffset>
          <size>0x20</size>
        </register>
        <register>
          <name>BGCLUT.210</name>
          <addressOffset>0xb48</addressOffset>
          <size>0x20</size>
        </register>
        <register>
          <name>BGCLUT.211</name>
          <addressOffset>0xb4c</addressOffset>
          <size>0x20</size>
        </register>
        <register>
          <name>BGCLUT.212</name>
          <addressOffset>0xb50</addressOffset>
          <size>0x20</size>
        </register>
        <register>
          <name>BGCLUT.213</name>
          <addressOffset>0xb54</addressOffset>
          <size>0x20</size>
        </register>
        <register>
          <name>BGCLUT.214</name>
          <addressOffset>0xb58</addressOffset>
          <size>0x20</size>
        </register>
        <register>
          <name>BGCLUT.215</name>
          <addressOffset>0xb5c</addressOffset>
          <size>0x20</size>
        </register>
        <register>
          <name>BGCLUT.216</name>
          <addressOffset>0xb60</addressOffset>
          <size>0x20</size>
        </register>
        <register>
          <name>BGCLUT.217</name>
          <addressOffset>0xb64</addressOffset>
          <size>0x20</size>
        </register>
        <register>
          <name>BGCLUT.218</name>
          <addressOffset>0xb68</addressOffset>
          <size>0x20</size>
        </register>
        <register>
          <name>BGCLUT.219</name>
          <addressOffset>0xb6c</addressOffset>
          <size>0x20</size>
        </register>
        <register>
          <name>BGCLUT.220</name>
          <addressOffset>0xb70</addressOffset>
          <size>0x20</size>
        </register>
        <register>
          <name>BGCLUT.221</name>
          <addressOffset>0xb74</addressOffset>
          <size>0x20</size>
        </register>
        <register>
          <name>BGCLUT.222</name>
          <addressOffset>0xb78</addressOffset>
          <size>0x20</size>
        </register>
        <register>
          <name>BGCLUT.223</name>
          <addressOffset>0xb7c</addressOffset>
          <size>0x20</size>
        </register>
        <register>
          <name>BGCLUT.224</name>
          <addressOffset>0xb80</addressOffset>
          <size>0x20</size>
        </register>
        <register>
          <name>BGCLUT.225</name>
          <addressOffset>0xb84</addressOffset>
          <size>0x20</size>
        </register>
        <register>
          <name>BGCLUT.226</name>
          <addressOffset>0xb88</addressOffset>
          <size>0x20</size>
        </register>
        <register>
          <name>BGCLUT.227</name>
          <addressOffset>0xb8c</addressOffset>
          <size>0x20</size>
        </register>
        <register>
          <name>BGCLUT.228</name>
          <addressOffset>0xb90</addressOffset>
          <size>0x20</size>
        </register>
        <register>
          <name>BGCLUT.229</name>
          <addressOffset>0xb94</addressOffset>
          <size>0x20</size>
        </register>
        <register>
          <name>BGCLUT.230</name>
          <addressOffset>0xb98</addressOffset>
          <size>0x20</size>
        </register>
        <register>
          <name>BGCLUT.231</name>
          <addressOffset>0xb9c</addressOffset>
          <size>0x20</size>
        </register>
        <register>
          <name>BGCLUT.232</name>
          <addressOffset>0xba0</addressOffset>
          <size>0x20</size>
        </register>
        <register>
          <name>BGCLUT.233</name>
          <addressOffset>0xba4</addressOffset>
          <size>0x20</size>
        </register>
        <register>
          <name>BGCLUT.234</name>
          <addressOffset>0xba8</addressOffset>
          <size>0x20</size>
        </register>
        <register>
          <name>BGCLUT.235</name>
          <addressOffset>0xbac</addressOffset>
          <size>0x20</size>
        </register>
        <register>
          <name>BGCLUT.236</name>
          <addressOffset>0xbb0</addressOffset>
          <size>0x20</size>
        </register>
        <register>
          <name>BGCLUT.237</name>
          <addressOffset>0xbb4</addressOffset>
          <size>0x20</size>
        </register>
        <register>
          <name>BGCLUT.238</name>
          <addressOffset>0xbb8</addressOffset>
          <size>0x20</size>
        </register>
        <register>
          <name>BGCLUT.239</name>
          <addressOffset>0xbbc</addressOffset>
          <size>0x20</size>
        </register>
        <register>
          <name>BGCLUT.240</name>
          <addressOffset>0xbc0</addressOffset>
          <size>0x20</size>
        </register>
        <register>
          <name>BGCLUT.241</name>
          <addressOffset>0xbc4</addressOffset>
          <size>0x20</size>
        </register>
        <register>
          <name>BGCLUT.242</name>
          <addressOffset>0xbc8</addressOffset>
          <size>0x20</size>
        </register>
        <register>
          <name>BGCLUT.243</name>
          <addressOffset>0xbcc</addressOffset>
          <size>0x20</size>
        </register>
        <register>
          <name>BGCLUT.244</name>
          <addressOffset>0xbd0</addressOffset>
          <size>0x20</size>
        </register>
        <register>
          <name>BGCLUT.245</name>
          <addressOffset>0xbd4</addressOffset>
          <size>0x20</size>
        </register>
        <register>
          <name>BGCLUT.246</name>
          <addressOffset>0xbd8</addressOffset>
          <size>0x20</size>
        </register>
        <register>
          <name>BGCLUT.247</name>
          <addressOffset>0xbdc</addressOffset>
          <size>0x20</size>
        </register>
        <register>
          <name>BGCLUT.248</name>
          <addressOffset>0xbe0</addressOffset>
          <size>0x20</size>
        </register>
        <register>
          <name>BGCLUT.249</name>
          <addressOffset>0xbe4</addressOffset>
          <size>0x20</size>
        </register>
        <register>
          <name>BGCLUT.250</name>
          <addressOffset>0xbe8</addressOffset>
          <size>0x20</size>
        </register>
        <register>
          <name>BGCLUT.251</name>
          <addressOffset>0xbec</addressOffset>
          <size>0x20</size>
        </register>
        <register>
          <name>BGCLUT.252</name>
          <addressOffset>0xbf0</addressOffset>
          <size>0x20</size>
        </register>
        <register>
          <name>BGCLUT.253</name>
          <addressOffset>0xbf4</addressOffset>
          <size>0x20</size>
        </register>
        <register>
          <name>BGCLUT.254</name>
          <addressOffset>0xbf8</addressOffset>
          <size>0x20</size>
        </register>
        <register>
          <name>BGCLUT.255</name>
          <addressOffset>0xbfc</addressOffset>
          <size>0x20</size>
        </register>
      </registers>
    </peripheral>
    <peripheral>
      <name>USB_OTG_HS</name>
      <baseAddress>0x40040000</baseAddress>
      <registers>
        <register>
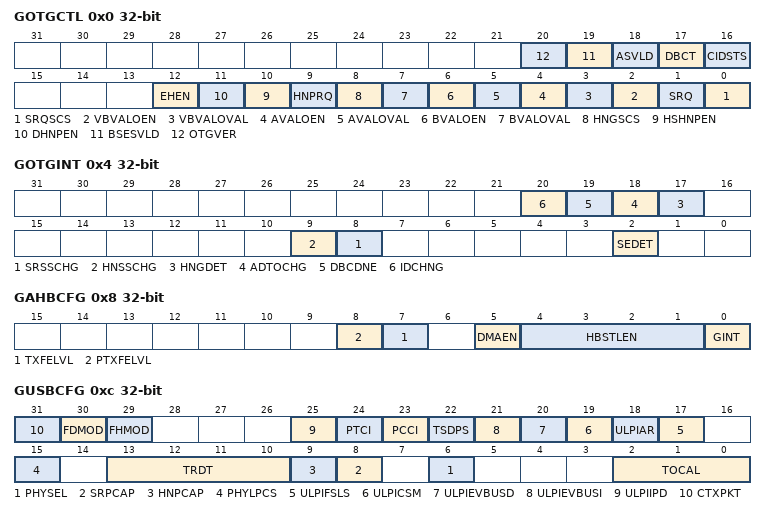
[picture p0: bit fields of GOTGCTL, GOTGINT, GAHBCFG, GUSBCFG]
          <name>GOTGCTL</name>
          <addressOffset>0x0</addressOffset>
          <size>0x20</size>
          <fields>
            <field>
              <name>SRQSCS</name>
              <bitOffset>0</bitOffset>
              <bitWidth>1</bitWidth>
            </field>
            <field>
              <name>SRQ</name>
              <bitOffset>1</bitOffset>
              <bitWidth>1</bitWidth>
            </field>
            <field>
              <name>VBVALOEN</name>
              <bitOffset>2</bitOffset>
              <bitWidth>1</bitWidth>
            </field>
            <field>
              <name>VBVALOVAL</name>
              <bitOffset>3</bitOffset>
              <bitWidth>1</bitWidth>
            </field>
            <field>
              <name>AVALOEN</name>
              <bitOffset>4</bitOffset>
              <bitWidth>1</bitWidth>
            </field>
            <field>
              <name>AVALOVAL</name>
              <bitOffset>5</bitOffset>
              <bitWidth>1</bitWidth>
            </field>
            <field>
              <name>BVALOEN</name>
              <bitOffset>6</bitOffset>
              <bitWidth>1</bitWidth>
            </field>
            <field>
              <name>BVALOVAL</name>
              <bitOffset>7</bitOffset>
              <bitWidth>1</bitWidth>
            </field>
            <field>
              <name>HNGSCS</name>
              <bitOffset>8</bitOffset>
              <bitWidth>1</bitWidth>
            </field>
            <field>
              <name>HNPRQ</name>
              <bitOffset>9</bitOffset>
              <bitWidth>1</bitWidth>
            </field>
            <field>
              <name>HSHNPEN</name>
              <bitOffset>10</bitOffset>
              <bitWidth>1</bitWidth>
            </field>
            <field>
              <name>DHNPEN</name>
              <bitOffset>11</bitOffset>
              <bitWidth>1</bitWidth>
            </field>
            <field>
              <name>EHEN</name>
              <bitOffset>12</bitOffset>
              <bitWidth>1</bitWidth>
            </field>
            <field>
              <name>CIDSTS</name>
              <bitOffset>16</bitOffset>
              <bitWidth>1</bitWidth>
            </field>
            <field>
              <name>DBCT</name>
              <bitOffset>17</bitOffset>
              <bitWidth>1</bitWidth>
            </field>
            <field>
              <name>ASVLD</name>
              <bitOffset>18</bitOffset>
              <bitWidth>1</bitWidth>
            </field>
            <field>
              <name>BSESVLD</name>
              <bitOffset>19</bitOffset>
              <bitWidth>1</bitWidth>
            </field>
            <field>
              <name>OTGVER</name>
              <bitOffset>20</bitOffset>
              <bitWidth>1</bitWidth>
            </field>
          </fields>
        </register>
        <register>
          <name>GOTGINT</name>
          <addressOffset>0x4</addressOffset>
          <size>0x20</size>
          <fields>
            <field>
              <name>SEDET</name>
              <bitOffset>2</bitOffset>
              <bitWidth>1</bitWidth>
            </field>
            <field>
              <name>SRSSCHG</name>
              <bitOffset>8</bitOffset>
              <bitWidth>1</bitWidth>
            </field>
            <field>
              <name>HNSSCHG</name>
              <bitOffset>9</bitOffset>
              <bitWidth>1</bitWidth>
            </field>
            <field>
              <name>HNGDET</name>
              <bitOffset>17</bitOffset>
              <bitWidth>1</bitWidth>
            </field>
            <field>
              <name>ADTOCHG</name>
              <bitOffset>18</bitOffset>
              <bitWidth>1</bitWidth>
            </field>
            <field>
              <name>DBCDNE</name>
              <bitOffset>19</bitOffset>
              <bitWidth>1</bitWidth>
            </field>
            <field>
              <name>IDCHNG</name>
              <bitOffset>20</bitOffset>
              <bitWidth>1</bitWidth>
            </field>
          </fields>
        </register>
        <register>
          <name>GAHBCFG</name>
          <addressOffset>0x8</addressOffset>
          <size>0x20</size>
          <fields>
            <field>
              <name>GINT</name>
              <bitOffset>0</bitOffset>
              <bitWidth>1</bitWidth>
            </field>
            <field>
              <name>HBSTLEN</name>
              <bitOffset>1</bitOffset>
              <bitWidth>4</bitWidth>
            </field>
            <field>
              <name>DMAEN</name>
              <bitOffset>5</bitOffset>
              <bitWidth>1</bitWidth>
            </field>
            <field>
              <name>TXFELVL</name>
              <bitOffset>7</bitOffset>
              <bitWidth>1</bitWidth>
            </field>
            <field>
              <name>PTXFELVL</name>
              <bitOffset>8</bitOffset>
              <bitWidth>1</bitWidth>
            </field>
          </fields>
        </register>
        <register>
          <name>GUSBCFG</name>
          <addressOffset>0xc</addressOffset>
          <size>0x20</size>
          <fields>
            <field>
              <name>TOCAL</name>
              <bitOffset>0</bitOffset>
              <bitWidth>3</bitWidth>
            </field>
            <field>
              <name>PHYSEL</name>
              <bitOffset>6</bitOffset>
              <bitWidth>1</bitWidth>
            </field>
            <field>
              <name>SRPCAP</name>
              <bitOffset>8</bitOffset>
              <bitWidth>1</bitWidth>
            </field>
            <field>
              <name>HNPCAP</name>
              <bitOffset>9</bitOffset>
              <bitWidth>1</bitWidth>
            </field>
            <field>
              <name>TRDT</name>
              <bitOffset>10</bitOffset>
              <bitWidth>4</bitWidth>
            </field>
            <field>
              <name>PHYLPCS</name>
              <bitOffset>15</bitOffset>
              <bitWidth>1</bitWidth>
            </field>
            <field>
              <name>ULPIFSLS</name>
              <bitOffset>17</bitOffset>
              <bitWidth>1</bitWidth>
            </field>
            <field>
              <name>ULPIAR</name>
              <bitOffset>18</bitOffset>
              <bitWidth>1</bitWidth>
            </field>
            <field>
              <name>ULPICSM</name>
              <bitOffset>19</bitOffset>
              <bitWidth>1</bitWidth>
            </field>
            <field>
              <name>ULPIEVBUSD</name>
              <bitOffset>20</bitOffset>
              <bitWidth>1</bitWidth>
            </field>
            <field>
              <name>ULPIEVBUSI</name>
              <bitOffset>21</bitOffset>
              <bitWidth>1</bitWidth>
            </field>
            <field>
              <name>TSDPS</name>
              <bitOffset>22</bitOffset>
              <bitWidth>1</bitWidth>
            </field>
            <field>
              <name>PCCI</name>
              <bitOffset>23</bitOffset>
              <bitWidth>1</bitWidth>
            </field>
            <field>
              <name>PTCI</name>
              <bitOffset>24</bitOffset>
              <bitWidth>1</bitWidth>
            </field>
            <field>
              <name>ULPIIPD</name>
              <bitOffset>25</bitOffset>
              <bitWidth>1</bitWidth>
            </field>
            <field>
              <name>FHMOD</name>
              <bitOffset>29</bitOffset>
              <bitWidth>1</bitWidth>
            </field>
            <field>
              <name>FDMOD</name>
              <bitOffset>30</bitOffset>
              <bitWidth>1</bitWidth>
            </field>
            <field>
              <name>CTXPKT</name>
              <bitOffset>31</bitOffset>
              <bitWidth>1</bitWidth>
            </field>
          </fields>
        </register>
        <register>
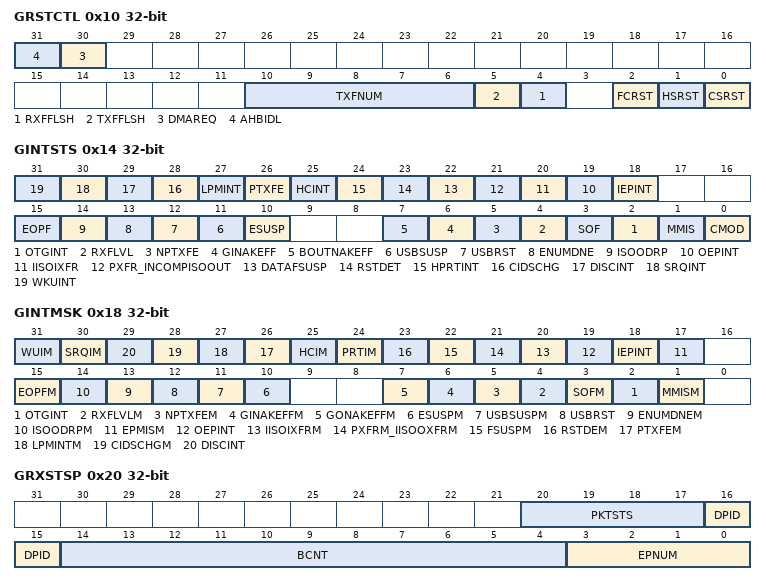
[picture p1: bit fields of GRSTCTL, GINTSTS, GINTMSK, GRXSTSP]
          <name>GRSTCTL</name>
          <addressOffset>0x10</addressOffset>
          <size>0x20</size>
          <fields>
            <field>
              <name>CSRST</name>
              <bitOffset>0</bitOffset>
              <bitWidth>1</bitWidth>
            </field>
            <field>
              <name>HSRST</name>
              <bitOffset>1</bitOffset>
              <bitWidth>1</bitWidth>
            </field>
            <field>
              <name>FCRST</name>
              <bitOffset>2</bitOffset>
              <bitWidth>1</bitWidth>
            </field>
            <field>
              <name>RXFFLSH</name>
              <bitOffset>4</bitOffset>
              <bitWidth>1</bitWidth>
            </field>
            <field>
              <name>TXFFLSH</name>
              <bitOffset>5</bitOffset>
              <bitWidth>1</bitWidth>
            </field>
            <field>
              <name>TXFNUM</name>
              <bitOffset>6</bitOffset>
              <bitWidth>5</bitWidth>
            </field>
            <field>
              <name>DMAREQ</name>
              <bitOffset>30</bitOffset>
              <bitWidth>1</bitWidth>
            </field>
            <field>
              <name>AHBIDL</name>
              <bitOffset>31</bitOffset>
              <bitWidth>1</bitWidth>
            </field>
          </fields>
        </register>
        <register>
          <name>GINTSTS</name>
          <addressOffset>0x14</addressOffset>
          <size>0x20</size>
          <fields>
            <field>
              <name>CMOD</name>
              <bitOffset>0</bitOffset>
              <bitWidth>1</bitWidth>
            </field>
            <field>
              <name>MMIS</name>
              <bitOffset>1</bitOffset>
              <bitWidth>1</bitWidth>
            </field>
            <field>
              <name>OTGINT</name>
              <bitOffset>2</bitOffset>
              <bitWidth>1</bitWidth>
            </field>
            <field>
              <name>SOF</name>
              <bitOffset>3</bitOffset>
              <bitWidth>1</bitWidth>
            </field>
            <field>
              <name>RXFLVL</name>
              <bitOffset>4</bitOffset>
              <bitWidth>1</bitWidth>
            </field>
            <field>
              <name>NPTXFE</name>
              <bitOffset>5</bitOffset>
              <bitWidth>1</bitWidth>
            </field>
            <field>
              <name>GINAKEFF</name>
              <bitOffset>6</bitOffset>
              <bitWidth>1</bitWidth>
            </field>
            <field>
              <name>BOUTNAKEFF</name>
              <bitOffset>7</bitOffset>
              <bitWidth>1</bitWidth>
            </field>
            <field>
              <name>ESUSP</name>
              <bitOffset>10</bitOffset>
              <bitWidth>1</bitWidth>
            </field>
            <field>
              <name>USBSUSP</name>
              <bitOffset>11</bitOffset>
              <bitWidth>1</bitWidth>
            </field>
            <field>
              <name>USBRST</name>
              <bitOffset>12</bitOffset>
              <bitWidth>1</bitWidth>
            </field>
            <field>
              <name>ENUMDNE</name>
              <bitOffset>13</bitOffset>
              <bitWidth>1</bitWidth>
            </field>
            <field>
              <name>ISOODRP</name>
              <bitOffset>14</bitOffset>
              <bitWidth>1</bitWidth>
            </field>
            <field>
              <name>EOPF</name>
              <bitOffset>15</bitOffset>
              <bitWidth>1</bitWidth>
            </field>
            <field>
              <name>IEPINT</name>
              <bitOffset>18</bitOffset>
              <bitWidth>1</bitWidth>
            </field>
            <field>
              <name>OEPINT</name>
              <bitOffset>19</bitOffset>
              <bitWidth>1</bitWidth>
            </field>
            <field>
              <name>IISOIXFR</name>
              <bitOffset>20</bitOffset>
              <bitWidth>1</bitWidth>
            </field>
            <field>
              <name>PXFR_INCOMPISOOUT</name>
              <bitOffset>21</bitOffset>
              <bitWidth>1</bitWidth>
            </field>
            <field>
              <name>DATAFSUSP</name>
              <bitOffset>22</bitOffset>
              <bitWidth>1</bitWidth>
            </field>
            <field>
              <name>RSTDET</name>
              <bitOffset>23</bitOffset>
              <bitWidth>1</bitWidth>
            </field>
            <field>
              <name>HPRTINT</name>
              <bitOffset>24</bitOffset>
              <bitWidth>1</bitWidth>
            </field>
            <field>
              <name>HCINT</name>
              <bitOffset>25</bitOffset>
              <bitWidth>1</bitWidth>
            </field>
            <field>
              <name>PTXFE</name>
              <bitOffset>26</bitOffset>
              <bitWidth>1</bitWidth>
            </field>
            <field>
              <name>LPMINT</name>
              <bitOffset>27</bitOffset>
              <bitWidth>1</bitWidth>
            </field>
            <field>
              <name>CIDSCHG</name>
              <bitOffset>28</bitOffset>
              <bitWidth>1</bitWidth>
            </field>
            <field>
              <name>DISCINT</name>
              <bitOffset>29</bitOffset>
              <bitWidth>1</bitWidth>
            </field>
            <field>
              <name>SRQINT</name>
              <bitOffset>30</bitOffset>
              <bitWidth>1</bitWidth>
            </field>
            <field>
              <name>WKUINT</name>
              <bitOffset>31</bitOffset>
              <bitWidth>1</bitWidth>
            </field>
          </fields>
        </register>
        <register>
          <name>GINTMSK</name>
          <addressOffset>0x18</addressOffset>
          <size>0x20</size>
          <fields>
            <field>
              <name>MMISM</name>
              <bitOffset>1</bitOffset>
              <bitWidth>1</bitWidth>
            </field>
            <field>
              <name>OTGINT</name>
              <bitOffset>2</bitOffset>
              <bitWidth>1</bitWidth>
            </field>
            <field>
              <name>SOFM</name>
              <bitOffset>3</bitOffset>
              <bitWidth>1</bitWidth>
            </field>
            <field>
              <name>RXFLVLM</name>
              <bitOffset>4</bitOffset>
              <bitWidth>1</bitWidth>
            </field>
            <field>
              <name>NPTXFEM</name>
              <bitOffset>5</bitOffset>
              <bitWidth>1</bitWidth>
            </field>
            <field>
              <name>GINAKEFFM</name>
              <bitOffset>6</bitOffset>
              <bitWidth>1</bitWidth>
            </field>
            <field>
              <name>GONAKEFFM</name>
              <bitOffset>7</bitOffset>
              <bitWidth>1</bitWidth>
            </field>
            <field>
              <name>ESUSPM</name>
              <bitOffset>10</bitOffset>
              <bitWidth>1</bitWidth>
            </field>
            <field>
              <name>USBSUSPM</name>
              <bitOffset>11</bitOffset>
              <bitWidth>1</bitWidth>
            </field>
            <field>
              <name>USBRST</name>
              <bitOffset>12</bitOffset>
              <bitWidth>1</bitWidth>
            </field>
            <field>
              <name>ENUMDNEM</name>
              <bitOffset>13</bitOffset>
              <bitWidth>1</bitWidth>
            </field>
            <field>
              <name>ISOODRPM</name>
              <bitOffset>14</bitOffset>
              <bitWidth>1</bitWidth>
            </field>
            <field>
              <name>EOPFM</name>
              <bitOffset>15</bitOffset>
              <bitWidth>1</bitWidth>
            </field>
            <field>
              <name>EPMISM</name>
              <bitOffset>17</bitOffset>
              <bitWidth>1</bitWidth>
            </field>
            <field>
              <name>IEPINT</name>
              <bitOffset>18</bitOffset>
              <bitWidth>1</bitWidth>
            </field>
            <field>
              <name>OEPINT</name>
              <bitOffset>19</bitOffset>
              <bitWidth>1</bitWidth>
            </field>
            <field>
              <name>IISOIXFRM</name>
              <bitOffset>20</bitOffset>
              <bitWidth>1</bitWidth>
            </field>
            <field>
              <name>PXFRM_IISOOXFRM</name>
              <bitOffset>21</bitOffset>
              <bitWidth>1</bitWidth>
            </field>
            <field>
              <name>FSUSPM</name>
              <bitOffset>22</bitOffset>
              <bitWidth>1</bitWidth>
            </field>
            <field>
              <name>RSTDEM</name>
              <bitOffset>23</bitOffset>
              <bitWidth>1</bitWidth>
            </field>
            <field>
              <name>PRTIM</name>
              <bitOffset>24</bitOffset>
              <bitWidth>1</bitWidth>
            </field>
            <field>
              <name>HCIM</name>
              <bitOffset>25</bitOffset>
              <bitWidth>1</bitWidth>
            </field>
            <field>
              <name>PTXFEM</name>
              <bitOffset>26</bitOffset>
              <bitWidth>1</bitWidth>
            </field>
            <field>
              <name>LPMINTM</name>
              <bitOffset>27</bitOffset>
              <bitWidth>1</bitWidth>
            </field>
            <field>
              <name>CIDSCHGM</name>
              <bitOffset>28</bitOffset>
              <bitWidth>1</bitWidth>
            </field>
            <field>
              <name>DISCINT</name>
              <bitOffset>29</bitOffset>
              <bitWidth>1</bitWidth>
            </field>
            <field>
              <name>SRQIM</name>
              <bitOffset>30</bitOffset>
              <bitWidth>1</bitWidth>
            </field>
            <field>
              <name>WUIM</name>
              <bitOffset>31</bitOffset>
              <bitWidth>1</bitWidth>
            </field>
          </fields>
        </register>
        <register>
          <name>GRXSTSR</name>
          <addressOffset>0x1c</addressOffset>
          <size>0x20</size>
        </register>
        <register>
          <name>GRXSTSP</name>
          <addressOffset>0x20</addressOffset>
          <size>0x20</size>
          <fields>
            <field>
              <name>EPNUM</name>
              <bitOffset>0</bitOffset>
              <bitWidth>4</bitWidth>
            </field>
            <field>
              <name>BCNT</name>
              <bitOffset>4</bitOffset>
              <bitWidth>11</bitWidth>
            </field>
            <field>
              <name>DPID</name>
              <bitOffset>15</bitOffset>
              <bitWidth>2</bitWidth>
            </field>
            <field>
              <name>PKTSTS</name>
              <bitOffset>17</bitOffset>
              <bitWidth>4</bitWidth>
            </field>
          </fields>
        </register>
        <register>
          <name>GRXFSIZ</name>
          <addressOffset>0x24</addressOffset>
          <size>0x20</size>
          <fields>
            <field>
              <name>RXFD</name>
              <bitOffset>0</bitOffset>
              <bitWidth>16</bitWidth>
            </field>
          </fields>
        </register>
        <register>
          <name>DIEPTXF0_HNPTXFSIZ</name>
          <addressOffset>0x28</addressOffset>
          <size>0x20</size>
        </register>
        <register>
          <name>HNPTXSTS</name>
          <addressOffset>0x2c</addressOffset>
          <size>0x20</size>
        </register>
        <register>
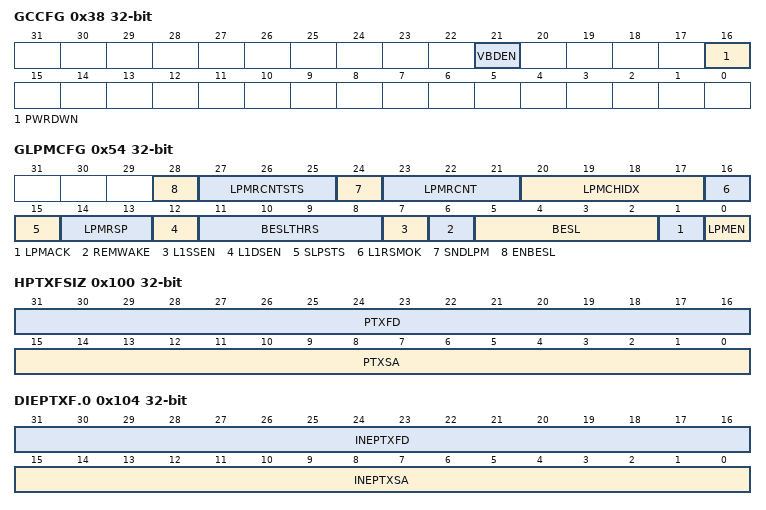
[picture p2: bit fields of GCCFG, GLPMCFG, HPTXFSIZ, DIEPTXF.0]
          <name>GCCFG</name>
          <addressOffset>0x38</addressOffset>
          <size>0x20</size>
          <fields>
            <field>
              <name>PWRDWN</name>
              <bitOffset>16</bitOffset>
              <bitWidth>1</bitWidth>
            </field>
            <field>
              <name>VBDEN</name>
              <bitOffset>21</bitOffset>
              <bitWidth>1</bitWidth>
            </field>
          </fields>
        </register>
        <register>
          <name>CID</name>
          <addressOffset>0x3c</addressOffset>
          <size>0x20</size>
          <fields>
            <field>
              <name>PRODUCT_ID</name>
              <bitOffset>0</bitOffset>
              <bitWidth>32</bitWidth>
            </field>
          </fields>
        </register>
        <register>
          <name>GHWCFG3</name>
          <addressOffset>0x4c</addressOffset>
          <size>0x20</size>
        </register>
        <register>
          <name>GLPMCFG</name>
          <addressOffset>0x54</addressOffset>
          <size>0x20</size>
          <fields>
            <field>
              <name>LPMEN</name>
              <bitOffset>0</bitOffset>
              <bitWidth>1</bitWidth>
            </field>
            <field>
              <name>LPMACK</name>
              <bitOffset>1</bitOffset>
              <bitWidth>1</bitWidth>
            </field>
            <field>
              <name>BESL</name>
              <bitOffset>2</bitOffset>
              <bitWidth>4</bitWidth>
            </field>
            <field>
              <name>REMWAKE</name>
              <bitOffset>6</bitOffset>
              <bitWidth>1</bitWidth>
            </field>
            <field>
              <name>L1SSEN</name>
              <bitOffset>7</bitOffset>
              <bitWidth>1</bitWidth>
            </field>
            <field>
              <name>BESLTHRS</name>
              <bitOffset>8</bitOffset>
              <bitWidth>4</bitWidth>
            </field>
            <field>
              <name>L1DSEN</name>
              <bitOffset>12</bitOffset>
              <bitWidth>1</bitWidth>
            </field>
            <field>
              <name>LPMRSP</name>
              <bitOffset>13</bitOffset>
              <bitWidth>2</bitWidth>
            </field>
            <field>
              <name>SLPSTS</name>
              <bitOffset>15</bitOffset>
              <bitWidth>1</bitWidth>
            </field>
            <field>
              <name>L1RSMOK</name>
              <bitOffset>16</bitOffset>
              <bitWidth>1</bitWidth>
            </field>
            <field>
              <name>LPMCHIDX</name>
              <bitOffset>17</bitOffset>
              <bitWidth>4</bitWidth>
            </field>
            <field>
              <name>LPMRCNT</name>
              <bitOffset>21</bitOffset>
              <bitWidth>3</bitWidth>
            </field>
            <field>
              <name>SNDLPM</name>
              <bitOffset>24</bitOffset>
              <bitWidth>1</bitWidth>
            </field>
            <field>
              <name>LPMRCNTSTS</name>
              <bitOffset>25</bitOffset>
              <bitWidth>3</bitWidth>
            </field>
            <field>
              <name>ENBESL</name>
              <bitOffset>28</bitOffset>
              <bitWidth>1</bitWidth>
            </field>
          </fields>
        </register>
        <register>
          <name>GDFIFOCFG</name>
          <addressOffset>0x5c</addressOffset>
          <size>0x20</size>
        </register>
        <register>
          <name>HPTXFSIZ</name>
          <addressOffset>0x100</addressOffset>
          <size>0x20</size>
          <fields>
            <field>
              <name>PTXSA</name>
              <bitOffset>0</bitOffset>
              <bitWidth>16</bitWidth>
            </field>
            <field>
              <name>PTXFD</name>
              <bitOffset>16</bitOffset>
              <bitWidth>16</bitWidth>
            </field>
          </fields>
        </register>
        <register>
          <name>DIEPTXF.0</name>
          <addressOffset>0x104</addressOffset>
          <size>0x20</size>
          <fields>
            <field>
              <name>INEPTXSA</name>
              <bitOffset>0</bitOffset>
              <bitWidth>16</bitWidth>
            </field>
            <field>
              <name>INEPTXFD</name>
              <bitOffset>16</bitOffset>
              <bitWidth>16</bitWidth>
            </field>
          </fields>
        </register>
        <register>
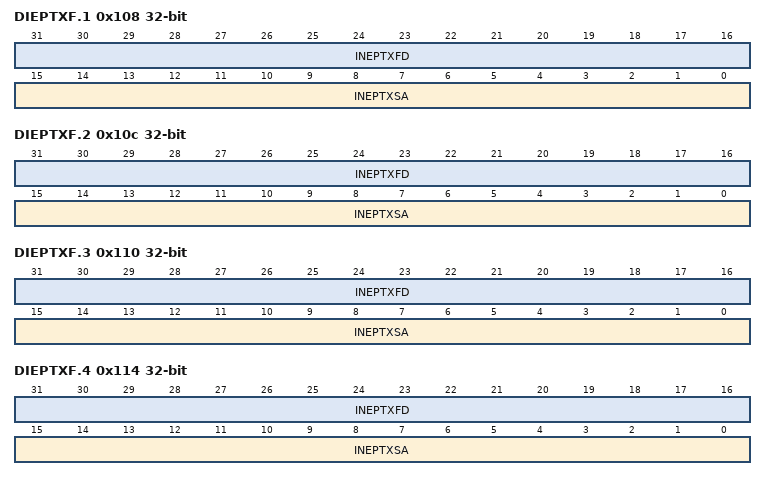
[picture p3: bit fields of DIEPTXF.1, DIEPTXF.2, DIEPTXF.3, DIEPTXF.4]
          <name>DIEPTXF.1</name>
          <addressOffset>0x108</addressOffset>
          <size>0x20</size>
          <fields>
            <field>
              <name>INEPTXSA</name>
              <bitOffset>0</bitOffset>
              <bitWidth>16</bitWidth>
            </field>
            <field>
              <name>INEPTXFD</name>
              <bitOffset>16</bitOffset>
              <bitWidth>16</bitWidth>
            </field>
          </fields>
        </register>
        <register>
          <name>DIEPTXF.2</name>
          <addressOffset>0x10c</addressOffset>
          <size>0x20</size>
          <fields>
            <field>
              <name>INEPTXSA</name>
              <bitOffset>0</bitOffset>
              <bitWidth>16</bitWidth>
            </field>
            <field>
              <name>INEPTXFD</name>
              <bitOffset>16</bitOffset>
              <bitWidth>16</bitWidth>
            </field>
          </fields>
        </register>
        <register>
          <name>DIEPTXF.3</name>
          <addressOffset>0x110</addressOffset>
          <size>0x20</size>
          <fields>
            <field>
              <name>INEPTXSA</name>
              <bitOffset>0</bitOffset>
              <bitWidth>16</bitWidth>
            </field>
            <field>
              <name>INEPTXFD</name>
              <bitOffset>16</bitOffset>
              <bitWidth>16</bitWidth>
            </field>
          </fields>
        </register>
        <register>
          <name>DIEPTXF.4</name>
          <addressOffset>0x114</addressOffset>
          <size>0x20</size>
          <fields>
            <field>
              <name>INEPTXSA</name>
              <bitOffset>0</bitOffset>
              <bitWidth>16</bitWidth>
            </field>
            <field>
              <name>INEPTXFD</name>
              <bitOffset>16</bitOffset>
              <bitWidth>16</bitWidth>
            </field>
          </fields>
        </register>
        <register>
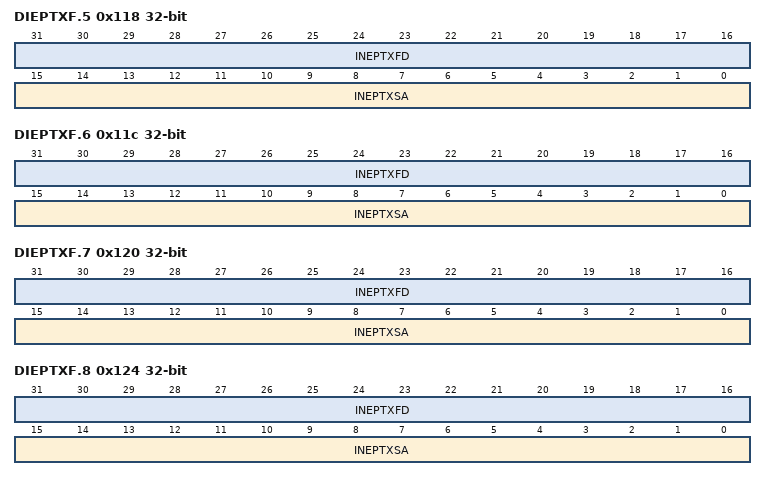
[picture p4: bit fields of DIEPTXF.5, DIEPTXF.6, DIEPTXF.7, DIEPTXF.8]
          <name>DIEPTXF.5</name>
          <addressOffset>0x118</addressOffset>
          <size>0x20</size>
          <fields>
            <field>
              <name>INEPTXSA</name>
              <bitOffset>0</bitOffset>
              <bitWidth>16</bitWidth>
            </field>
            <field>
              <name>INEPTXFD</name>
              <bitOffset>16</bitOffset>
              <bitWidth>16</bitWidth>
            </field>
          </fields>
        </register>
        <register>
          <name>DIEPTXF.6</name>
          <addressOffset>0x11c</addressOffset>
          <size>0x20</size>
          <fields>
            <field>
              <name>INEPTXSA</name>
              <bitOffset>0</bitOffset>
              <bitWidth>16</bitWidth>
            </field>
            <field>
              <name>INEPTXFD</name>
              <bitOffset>16</bitOffset>
              <bitWidth>16</bitWidth>
            </field>
          </fields>
        </register>
        <register>
          <name>DIEPTXF.7</name>
          <addressOffset>0x120</addressOffset>
          <size>0x20</size>
          <fields>
            <field>
              <name>INEPTXSA</name>
              <bitOffset>0</bitOffset>
              <bitWidth>16</bitWidth>
            </field>
            <field>
              <name>INEPTXFD</name>
              <bitOffset>16</bitOffset>
              <bitWidth>16</bitWidth>
            </field>
          </fields>
        </register>
        <register>
          <name>DIEPTXF.8</name>
          <addressOffset>0x124</addressOffset>
          <size>0x20</size>
          <fields>
            <field>
              <name>INEPTXSA</name>
              <bitOffset>0</bitOffset>
              <bitWidth>16</bitWidth>
            </field>
            <field>
              <name>INEPTXFD</name>
              <bitOffset>16</bitOffset>
              <bitWidth>16</bitWidth>
            </field>
          </fields>
        </register>
        <register>
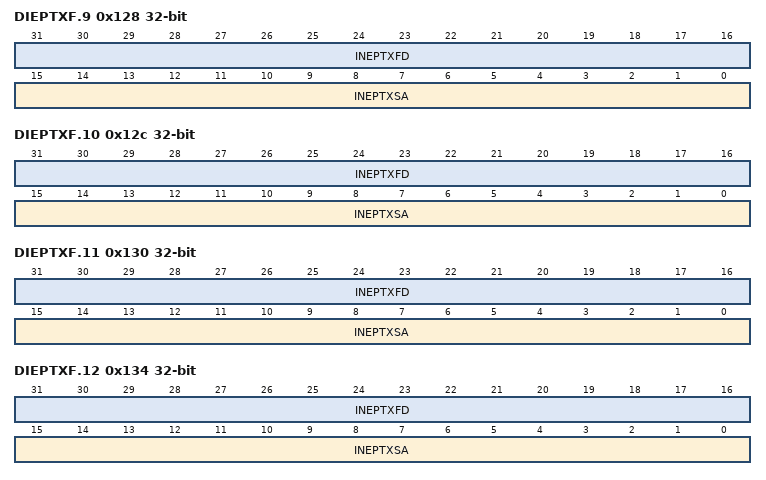
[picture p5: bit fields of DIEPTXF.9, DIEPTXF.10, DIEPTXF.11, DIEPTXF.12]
          <name>DIEPTXF.9</name>
          <addressOffset>0x128</addressOffset>
          <size>0x20</size>
          <fields>
            <field>
              <name>INEPTXSA</name>
              <bitOffset>0</bitOffset>
              <bitWidth>16</bitWidth>
            </field>
            <field>
              <name>INEPTXFD</name>
              <bitOffset>16</bitOffset>
              <bitWidth>16</bitWidth>
            </field>
          </fields>
        </register>
        <register>
          <name>DIEPTXF.10</name>
          <addressOffset>0x12c</addressOffset>
          <size>0x20</size>
          <fields>
            <field>
              <name>INEPTXSA</name>
              <bitOffset>0</bitOffset>
              <bitWidth>16</bitWidth>
            </field>
            <field>
              <name>INEPTXFD</name>
              <bitOffset>16</bitOffset>
              <bitWidth>16</bitWidth>
            </field>
          </fields>
        </register>
        <register>
          <name>DIEPTXF.11</name>
          <addressOffset>0x130</addressOffset>
          <size>0x20</size>
          <fields>
            <field>
              <name>INEPTXSA</name>
              <bitOffset>0</bitOffset>
              <bitWidth>16</bitWidth>
            </field>
            <field>
              <name>INEPTXFD</name>
              <bitOffset>16</bitOffset>
              <bitWidth>16</bitWidth>
            </field>
          </fields>
        </register>
        <register>
          <name>DIEPTXF.12</name>
          <addressOffset>0x134</addressOffset>
          <size>0x20</size>
          <fields>
            <field>
              <name>INEPTXSA</name>
              <bitOffset>0</bitOffset>
              <bitWidth>16</bitWidth>
            </field>
            <field>
              <name>INEPTXFD</name>
              <bitOffset>16</bitOffset>
              <bitWidth>16</bitWidth>
            </field>
          </fields>
        </register>
        <register>
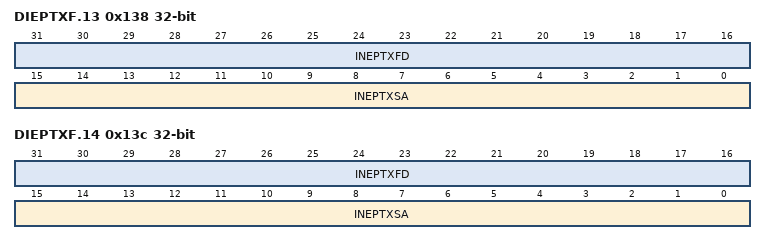
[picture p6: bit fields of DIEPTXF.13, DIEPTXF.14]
          <name>DIEPTXF.13</name>
          <addressOffset>0x138</addressOffset>
          <size>0x20</size>
          <fields>
            <field>
              <name>INEPTXSA</name>
              <bitOffset>0</bitOffset>
              <bitWidth>16</bitWidth>
            </field>
            <field>
              <name>INEPTXFD</name>
              <bitOffset>16</bitOffset>
              <bitWidth>16</bitWidth>
            </field>
          </fields>
        </register>
        <register>
          <name>DIEPTXF.14</name>
          <addressOffset>0x13c</addressOffset>
          <size>0x20</size>
          <fields>
            <field>
              <name>INEPTXSA</name>
              <bitOffset>0</bitOffset>
              <bitWidth>16</bitWidth>
            </field>
            <field>
              <name>INEPTXFD</name>
              <bitOffset>16</bitOffset>
              <bitWidth>16</bitWidth>
            </field>
          </fields>
        </register>
      </registers>
    </peripheral>
    <peripheral>
      <name>USB_OTG_FS</name>
      <baseAddress>0x50000000</baseAddress>
      <registers>
        <register>
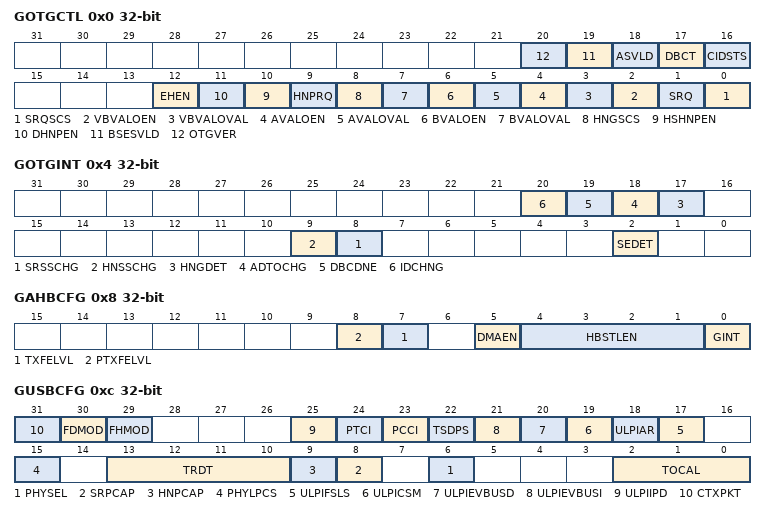
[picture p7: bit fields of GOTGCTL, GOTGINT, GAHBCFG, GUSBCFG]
          <name>GOTGCTL</name>
          <addressOffset>0x0</addressOffset>
          <size>0x20</size>
          <fields>
            <field>
              <name>SRQSCS</name>
              <bitOffset>0</bitOffset>
              <bitWidth>1</bitWidth>
            </field>
            <field>
              <name>SRQ</name>
              <bitOffset>1</bitOffset>
              <bitWidth>1</bitWidth>
            </field>
            <field>
              <name>VBVALOEN</name>
              <bitOffset>2</bitOffset>
              <bitWidth>1</bitWidth>
            </field>
            <field>
              <name>VBVALOVAL</name>
              <bitOffset>3</bitOffset>
              <bitWidth>1</bitWidth>
            </field>
            <field>
              <name>AVALOEN</name>
              <bitOffset>4</bitOffset>
              <bitWidth>1</bitWidth>
            </field>
            <field>
              <name>AVALOVAL</name>
              <bitOffset>5</bitOffset>
              <bitWidth>1</bitWidth>
            </field>
            <field>
              <name>BVALOEN</name>
              <bitOffset>6</bitOffset>
              <bitWidth>1</bitWidth>
            </field>
            <field>
              <name>BVALOVAL</name>
              <bitOffset>7</bitOffset>
              <bitWidth>1</bitWidth>
            </field>
            <field>
              <name>HNGSCS</name>
              <bitOffset>8</bitOffset>
              <bitWidth>1</bitWidth>
            </field>
            <field>
              <name>HNPRQ</name>
              <bitOffset>9</bitOffset>
              <bitWidth>1</bitWidth>
            </field>
            <field>
              <name>HSHNPEN</name>
              <bitOffset>10</bitOffset>
              <bitWidth>1</bitWidth>
            </field>
            <field>
              <name>DHNPEN</name>
              <bitOffset>11</bitOffset>
              <bitWidth>1</bitWidth>
            </field>
            <field>
              <name>EHEN</name>
              <bitOffset>12</bitOffset>
              <bitWidth>1</bitWidth>
            </field>
            <field>
              <name>CIDSTS</name>
              <bitOffset>16</bitOffset>
              <bitWidth>1</bitWidth>
            </field>
            <field>
              <name>DBCT</name>
              <bitOffset>17</bitOffset>
              <bitWidth>1</bitWidth>
            </field>
            <field>
              <name>ASVLD</name>
              <bitOffset>18</bitOffset>
              <bitWidth>1</bitWidth>
            </field>
            <field>
              <name>BSESVLD</name>
              <bitOffset>19</bitOffset>
              <bitWidth>1</bitWidth>
            </field>
            <field>
              <name>OTGVER</name>
              <bitOffset>20</bitOffset>
              <bitWidth>1</bitWidth>
            </field>
          </fields>
        </register>
        <register>
          <name>GOTGINT</name>
          <addressOffset>0x4</addressOffset>
          <size>0x20</size>
          <fields>
            <field>
              <name>SEDET</name>
              <bitOffset>2</bitOffset>
              <bitWidth>1</bitWidth>
            </field>
            <field>
              <name>SRSSCHG</name>
              <bitOffset>8</bitOffset>
              <bitWidth>1</bitWidth>
            </field>
            <field>
              <name>HNSSCHG</name>
              <bitOffset>9</bitOffset>
              <bitWidth>1</bitWidth>
            </field>
            <field>
              <name>HNGDET</name>
              <bitOffset>17</bitOffset>
              <bitWidth>1</bitWidth>
            </field>
            <field>
              <name>ADTOCHG</name>
              <bitOffset>18</bitOffset>
              <bitWidth>1</bitWidth>
            </field>
            <field>
              <name>DBCDNE</name>
              <bitOffset>19</bitOffset>
              <bitWidth>1</bitWidth>
            </field>
            <field>
              <name>IDCHNG</name>
              <bitOffset>20</bitOffset>
              <bitWidth>1</bitWidth>
            </field>
          </fields>
        </register>
        <register>
          <name>GAHBCFG</name>
          <addressOffset>0x8</addressOffset>
          <size>0x20</size>
          <fields>
            <field>
              <name>GINT</name>
              <bitOffset>0</bitOffset>
              <bitWidth>1</bitWidth>
            </field>
            <field>
              <name>HBSTLEN</name>
              <bitOffset>1</bitOffset>
              <bitWidth>4</bitWidth>
            </field>
            <field>
              <name>DMAEN</name>
              <bitOffset>5</bitOffset>
              <bitWidth>1</bitWidth>
            </field>
            <field>
              <name>TXFELVL</name>
              <bitOffset>7</bitOffset>
              <bitWidth>1</bitWidth>
            </field>
            <field>
              <name>PTXFELVL</name>
              <bitOffset>8</bitOffset>
              <bitWidth>1</bitWidth>
            </field>
          </fields>
        </register>
        <register>
          <name>GUSBCFG</name>
          <addressOffset>0xc</addressOffset>
          <size>0x20</size>
          <fields>
            <field>
              <name>TOCAL</name>
              <bitOffset>0</bitOffset>
              <bitWidth>3</bitWidth>
            </field>
            <field>
              <name>PHYSEL</name>
              <bitOffset>6</bitOffset>
              <bitWidth>1</bitWidth>
            </field>
            <field>
              <name>SRPCAP</name>
              <bitOffset>8</bitOffset>
              <bitWidth>1</bitWidth>
            </field>
            <field>
              <name>HNPCAP</name>
              <bitOffset>9</bitOffset>
              <bitWidth>1</bitWidth>
            </field>
            <field>
              <name>TRDT</name>
              <bitOffset>10</bitOffset>
              <bitWidth>4</bitWidth>
            </field>
            <field>
              <name>PHYLPCS</name>
              <bitOffset>15</bitOffset>
              <bitWidth>1</bitWidth>
            </field>
            <field>
              <name>ULPIFSLS</name>
              <bitOffset>17</bitOffset>
              <bitWidth>1</bitWidth>
            </field>
            <field>
              <name>ULPIAR</name>
              <bitOffset>18</bitOffset>
              <bitWidth>1</bitWidth>
            </field>
            <field>
              <name>ULPICSM</name>
              <bitOffset>19</bitOffset>
              <bitWidth>1</bitWidth>
            </field>
            <field>
              <name>ULPIEVBUSD</name>
              <bitOffset>20</bitOffset>
              <bitWidth>1</bitWidth>
            </field>
            <field>
              <name>ULPIEVBUSI</name>
              <bitOffset>21</bitOffset>
              <bitWidth>1</bitWidth>
            </field>
            <field>
              <name>TSDPS</name>
              <bitOffset>22</bitOffset>
              <bitWidth>1</bitWidth>
            </field>
            <field>
              <name>PCCI</name>
              <bitOffset>23</bitOffset>
              <bitWidth>1</bitWidth>
            </field>
            <field>
              <name>PTCI</name>
              <bitOffset>24</bitOffset>
              <bitWidth>1</bitWidth>
            </field>
            <field>
              <name>ULPIIPD</name>
              <bitOffset>25</bitOffset>
              <bitWidth>1</bitWidth>
            </field>
            <field>
              <name>FHMOD</name>
              <bitOffset>29</bitOffset>
              <bitWidth>1</bitWidth>
            </field>
            <field>
              <name>FDMOD</name>
              <bitOffset>30</bitOffset>
              <bitWidth>1</bitWidth>
            </field>
            <field>
              <name>CTXPKT</name>
              <bitOffset>31</bitOffset>
              <bitWidth>1</bitWidth>
            </field>
          </fields>
        </register>
        <register>
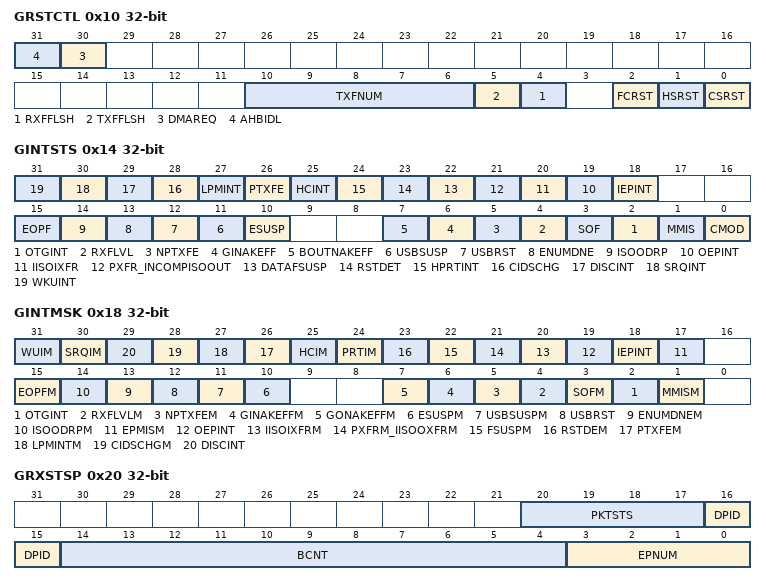
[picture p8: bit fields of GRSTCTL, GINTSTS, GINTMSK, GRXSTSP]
          <name>GRSTCTL</name>
          <addressOffset>0x10</addressOffset>
          <size>0x20</size>
          <fields>
            <field>
              <name>CSRST</name>
              <bitOffset>0</bitOffset>
              <bitWidth>1</bitWidth>
            </field>
            <field>
              <name>HSRST</name>
              <bitOffset>1</bitOffset>
              <bitWidth>1</bitWidth>
            </field>
            <field>
              <name>FCRST</name>
              <bitOffset>2</bitOffset>
              <bitWidth>1</bitWidth>
            </field>
            <field>
              <name>RXFFLSH</name>
              <bitOffset>4</bitOffset>
              <bitWidth>1</bitWidth>
            </field>
            <field>
              <name>TXFFLSH</name>
              <bitOffset>5</bitOffset>
              <bitWidth>1</bitWidth>
            </field>
            <field>
              <name>TXFNUM</name>
              <bitOffset>6</bitOffset>
              <bitWidth>5</bitWidth>
            </field>
            <field>
              <name>DMAREQ</name>
              <bitOffset>30</bitOffset>
              <bitWidth>1</bitWidth>
            </field>
            <field>
              <name>AHBIDL</name>
              <bitOffset>31</bitOffset>
              <bitWidth>1</bitWidth>
            </field>
          </fields>
        </register>
        <register>
          <name>GINTSTS</name>
          <addressOffset>0x14</addressOffset>
          <size>0x20</size>
          <fields>
            <field>
              <name>CMOD</name>
              <bitOffset>0</bitOffset>
              <bitWidth>1</bitWidth>
            </field>
            <field>
              <name>MMIS</name>
              <bitOffset>1</bitOffset>
              <bitWidth>1</bitWidth>
            </field>
            <field>
              <name>OTGINT</name>
              <bitOffset>2</bitOffset>
              <bitWidth>1</bitWidth>
            </field>
            <field>
              <name>SOF</name>
              <bitOffset>3</bitOffset>
              <bitWidth>1</bitWidth>
            </field>
            <field>
              <name>RXFLVL</name>
              <bitOffset>4</bitOffset>
              <bitWidth>1</bitWidth>
            </field>
            <field>
              <name>NPTXFE</name>
              <bitOffset>5</bitOffset>
              <bitWidth>1</bitWidth>
            </field>
            <field>
              <name>GINAKEFF</name>
              <bitOffset>6</bitOffset>
              <bitWidth>1</bitWidth>
            </field>
            <field>
              <name>BOUTNAKEFF</name>
              <bitOffset>7</bitOffset>
              <bitWidth>1</bitWidth>
            </field>
            <field>
              <name>ESUSP</name>
              <bitOffset>10</bitOffset>
              <bitWidth>1</bitWidth>
            </field>
            <field>
              <name>USBSUSP</name>
              <bitOffset>11</bitOffset>
              <bitWidth>1</bitWidth>
            </field>
            <field>
              <name>USBRST</name>
              <bitOffset>12</bitOffset>
              <bitWidth>1</bitWidth>
            </field>
            <field>
              <name>ENUMDNE</name>
              <bitOffset>13</bitOffset>
              <bitWidth>1</bitWidth>
            </field>
            <field>
              <name>ISOODRP</name>
              <bitOffset>14</bitOffset>
              <bitWidth>1</bitWidth>
            </field>
            <field>
              <name>EOPF</name>
              <bitOffset>15</bitOffset>
              <bitWidth>1</bitWidth>
            </field>
            <field>
              <name>IEPINT</name>
              <bitOffset>18</bitOffset>
              <bitWidth>1</bitWidth>
            </field>
            <field>
              <name>OEPINT</name>
              <bitOffset>19</bitOffset>
              <bitWidth>1</bitWidth>
            </field>
            <field>
              <name>IISOIXFR</name>
              <bitOffset>20</bitOffset>
              <bitWidth>1</bitWidth>
            </field>
            <field>
              <name>PXFR_INCOMPISOOUT</name>
              <bitOffset>21</bitOffset>
              <bitWidth>1</bitWidth>
            </field>
            <field>
              <name>DATAFSUSP</name>
              <bitOffset>22</bitOffset>
              <bitWidth>1</bitWidth>
            </field>
            <field>
              <name>RSTDET</name>
              <bitOffset>23</bitOffset>
              <bitWidth>1</bitWidth>
            </field>
            <field>
              <name>HPRTINT</name>
              <bitOffset>24</bitOffset>
              <bitWidth>1</bitWidth>
            </field>
            <field>
              <name>HCINT</name>
              <bitOffset>25</bitOffset>
              <bitWidth>1</bitWidth>
            </field>
            <field>
              <name>PTXFE</name>
              <bitOffset>26</bitOffset>
              <bitWidth>1</bitWidth>
            </field>
            <field>
              <name>LPMINT</name>
              <bitOffset>27</bitOffset>
              <bitWidth>1</bitWidth>
            </field>
            <field>
              <name>CIDSCHG</name>
              <bitOffset>28</bitOffset>
              <bitWidth>1</bitWidth>
            </field>
            <field>
              <name>DISCINT</name>
              <bitOffset>29</bitOffset>
              <bitWidth>1</bitWidth>
            </field>
            <field>
              <name>SRQINT</name>
              <bitOffset>30</bitOffset>
              <bitWidth>1</bitWidth>
            </field>
            <field>
              <name>WKUINT</name>
              <bitOffset>31</bitOffset>
              <bitWidth>1</bitWidth>
            </field>
          </fields>
        </register>
        <register>
          <name>GINTMSK</name>
          <addressOffset>0x18</addressOffset>
          <size>0x20</size>
          <fields>
            <field>
              <name>MMISM</name>
              <bitOffset>1</bitOffset>
              <bitWidth>1</bitWidth>
            </field>
            <field>
              <name>OTGINT</name>
              <bitOffset>2</bitOffset>
              <bitWidth>1</bitWidth>
            </field>
            <field>
              <name>SOFM</name>
              <bitOffset>3</bitOffset>
              <bitWidth>1</bitWidth>
            </field>
            <field>
              <name>RXFLVLM</name>
              <bitOffset>4</bitOffset>
              <bitWidth>1</bitWidth>
            </field>
            <field>
              <name>NPTXFEM</name>
              <bitOffset>5</bitOffset>
              <bitWidth>1</bitWidth>
            </field>
            <field>
              <name>GINAKEFFM</name>
              <bitOffset>6</bitOffset>
              <bitWidth>1</bitWidth>
            </field>
            <field>
              <name>GONAKEFFM</name>
              <bitOffset>7</bitOffset>
              <bitWidth>1</bitWidth>
            </field>
            <field>
              <name>ESUSPM</name>
              <bitOffset>10</bitOffset>
              <bitWidth>1</bitWidth>
            </field>
            <field>
              <name>USBSUSPM</name>
              <bitOffset>11</bitOffset>
              <bitWidth>1</bitWidth>
            </field>
            <field>
              <name>USBRST</name>
              <bitOffset>12</bitOffset>
              <bitWidth>1</bitWidth>
            </field>
            <field>
              <name>ENUMDNEM</name>
              <bitOffset>13</bitOffset>
              <bitWidth>1</bitWidth>
            </field>
            <field>
              <name>ISOODRPM</name>
              <bitOffset>14</bitOffset>
              <bitWidth>1</bitWidth>
            </field>
            <field>
              <name>EOPFM</name>
              <bitOffset>15</bitOffset>
              <bitWidth>1</bitWidth>
            </field>
            <field>
              <name>EPMISM</name>
              <bitOffset>17</bitOffset>
              <bitWidth>1</bitWidth>
            </field>
            <field>
              <name>IEPINT</name>
              <bitOffset>18</bitOffset>
              <bitWidth>1</bitWidth>
            </field>
            <field>
              <name>OEPINT</name>
              <bitOffset>19</bitOffset>
              <bitWidth>1</bitWidth>
            </field>
            <field>
              <name>IISOIXFRM</name>
              <bitOffset>20</bitOffset>
              <bitWidth>1</bitWidth>
            </field>
            <field>
              <name>PXFRM_IISOOXFRM</name>
              <bitOffset>21</bitOffset>
              <bitWidth>1</bitWidth>
            </field>
            <field>
              <name>FSUSPM</name>
              <bitOffset>22</bitOffset>
              <bitWidth>1</bitWidth>
            </field>
            <field>
              <name>RSTDEM</name>
              <bitOffset>23</bitOffset>
              <bitWidth>1</bitWidth>
            </field>
            <field>
              <name>PRTIM</name>
              <bitOffset>24</bitOffset>
              <bitWidth>1</bitWidth>
            </field>
            <field>
              <name>HCIM</name>
              <bitOffset>25</bitOffset>
              <bitWidth>1</bitWidth>
            </field>
            <field>
              <name>PTXFEM</name>
              <bitOffset>26</bitOffset>
              <bitWidth>1</bitWidth>
            </field>
            <field>
              <name>LPMINTM</name>
              <bitOffset>27</bitOffset>
              <bitWidth>1</bitWidth>
            </field>
            <field>
              <name>CIDSCHGM</name>
              <bitOffset>28</bitOffset>
              <bitWidth>1</bitWidth>
            </field>
            <field>
              <name>DISCINT</name>
              <bitOffset>29</bitOffset>
              <bitWidth>1</bitWidth>
            </field>
            <field>
              <name>SRQIM</name>
              <bitOffset>30</bitOffset>
              <bitWidth>1</bitWidth>
            </field>
            <field>
              <name>WUIM</name>
              <bitOffset>31</bitOffset>
              <bitWidth>1</bitWidth>
            </field>
          </fields>
        </register>
        <register>
          <name>GRXSTSR</name>
          <addressOffset>0x1c</addressOffset>
          <size>0x20</size>
        </register>
        <register>
          <name>GRXSTSP</name>
          <addressOffset>0x20</addressOffset>
          <size>0x20</size>
          <fields>
            <field>
              <name>EPNUM</name>
              <bitOffset>0</bitOffset>
              <bitWidth>4</bitWidth>
            </field>
            <field>
              <name>BCNT</name>
              <bitOffset>4</bitOffset>
              <bitWidth>11</bitWidth>
            </field>
            <field>
              <name>DPID</name>
              <bitOffset>15</bitOffset>
              <bitWidth>2</bitWidth>
            </field>
            <field>
              <name>PKTSTS</name>
              <bitOffset>17</bitOffset>
              <bitWidth>4</bitWidth>
            </field>
          </fields>
        </register>
        <register>
          <name>GRXFSIZ</name>
          <addressOffset>0x24</addressOffset>
          <size>0x20</size>
          <fields>
            <field>
              <name>RXFD</name>
              <bitOffset>0</bitOffset>
              <bitWidth>16</bitWidth>
            </field>
          </fields>
        </register>
        <register>
          <name>DIEPTXF0_HNPTXFSIZ</name>
          <addressOffset>0x28</addressOffset>
          <size>0x20</size>
        </register>
        <register>
          <name>HNPTXSTS</name>
          <addressOffset>0x2c</addressOffset>
          <size>0x20</size>
        </register>
        <register>
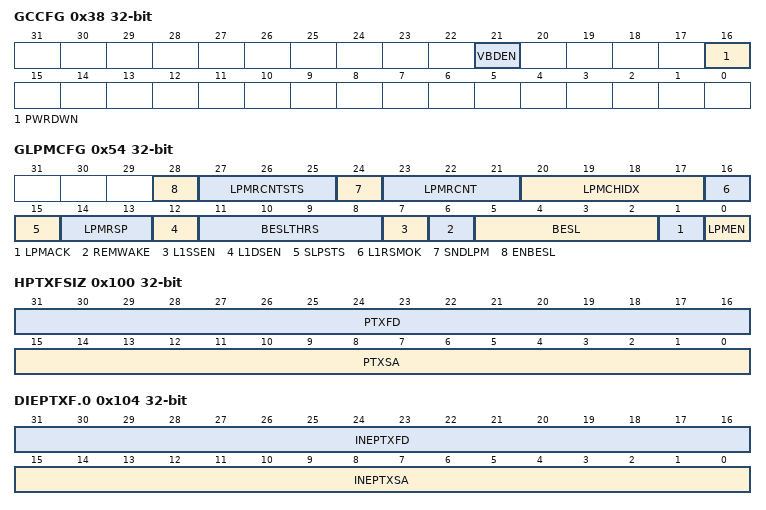
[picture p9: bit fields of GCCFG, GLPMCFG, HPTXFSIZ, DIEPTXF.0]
          <name>GCCFG</name>
          <addressOffset>0x38</addressOffset>
          <size>0x20</size>
          <fields>
            <field>
              <name>PWRDWN</name>
              <bitOffset>16</bitOffset>
              <bitWidth>1</bitWidth>
            </field>
            <field>
              <name>VBDEN</name>
              <bitOffset>21</bitOffset>
              <bitWidth>1</bitWidth>
            </field>
          </fields>
        </register>
        <register>
          <name>CID</name>
          <addressOffset>0x3c</addressOffset>
          <size>0x20</size>
          <fields>
            <field>
              <name>PRODUCT_ID</name>
              <bitOffset>0</bitOffset>
              <bitWidth>32</bitWidth>
            </field>
          </fields>
        </register>
        <register>
          <name>GHWCFG3</name>
          <addressOffset>0x4c</addressOffset>
          <size>0x20</size>
        </register>
        <register>
          <name>GLPMCFG</name>
          <addressOffset>0x54</addressOffset>
          <size>0x20</size>
          <fields>
            <field>
              <name>LPMEN</name>
              <bitOffset>0</bitOffset>
              <bitWidth>1</bitWidth>
            </field>
            <field>
              <name>LPMACK</name>
              <bitOffset>1</bitOffset>
              <bitWidth>1</bitWidth>
            </field>
            <field>
              <name>BESL</name>
              <bitOffset>2</bitOffset>
              <bitWidth>4</bitWidth>
            </field>
            <field>
              <name>REMWAKE</name>
              <bitOffset>6</bitOffset>
              <bitWidth>1</bitWidth>
            </field>
            <field>
              <name>L1SSEN</name>
              <bitOffset>7</bitOffset>
              <bitWidth>1</bitWidth>
            </field>
            <field>
              <name>BESLTHRS</name>
              <bitOffset>8</bitOffset>
              <bitWidth>4</bitWidth>
            </field>
            <field>
              <name>L1DSEN</name>
              <bitOffset>12</bitOffset>
              <bitWidth>1</bitWidth>
            </field>
            <field>
              <name>LPMRSP</name>
              <bitOffset>13</bitOffset>
              <bitWidth>2</bitWidth>
            </field>
            <field>
              <name>SLPSTS</name>
              <bitOffset>15</bitOffset>
              <bitWidth>1</bitWidth>
            </field>
            <field>
              <name>L1RSMOK</name>
              <bitOffset>16</bitOffset>
              <bitWidth>1</bitWidth>
            </field>
            <field>
              <name>LPMCHIDX</name>
              <bitOffset>17</bitOffset>
              <bitWidth>4</bitWidth>
            </field>
            <field>
              <name>LPMRCNT</name>
              <bitOffset>21</bitOffset>
              <bitWidth>3</bitWidth>
            </field>
            <field>
              <name>SNDLPM</name>
              <bitOffset>24</bitOffset>
              <bitWidth>1</bitWidth>
            </field>
            <field>
              <name>LPMRCNTSTS</name>
              <bitOffset>25</bitOffset>
              <bitWidth>3</bitWidth>
            </field>
            <field>
              <name>ENBESL</name>
              <bitOffset>28</bitOffset>
              <bitWidth>1</bitWidth>
            </field>
          </fields>
        </register>
        <register>
          <name>GDFIFOCFG</name>
          <addressOffset>0x5c</addressOffset>
          <size>0x20</size>
        </register>
        <register>
          <name>HPTXFSIZ</name>
          <addressOffset>0x100</addressOffset>
          <size>0x20</size>
          <fields>
            <field>
              <name>PTXSA</name>
              <bitOffset>0</bitOffset>
              <bitWidth>16</bitWidth>
            </field>
            <field>
              <name>PTXFD</name>
              <bitOffset>16</bitOffset>
              <bitWidth>16</bitWidth>
            </field>
          </fields>
        </register>
        <register>
          <name>DIEPTXF.0</name>
          <addressOffset>0x104</addressOffset>
          <size>0x20</size>
          <fields>
            <field>
              <name>INEPTXSA</name>
              <bitOffset>0</bitOffset>
              <bitWidth>16</bitWidth>
            </field>
            <field>
              <name>INEPTXFD</name>
              <bitOffset>16</bitOffset>
              <bitWidth>16</bitWidth>
            </field>
          </fields>
        </register>
        <register>
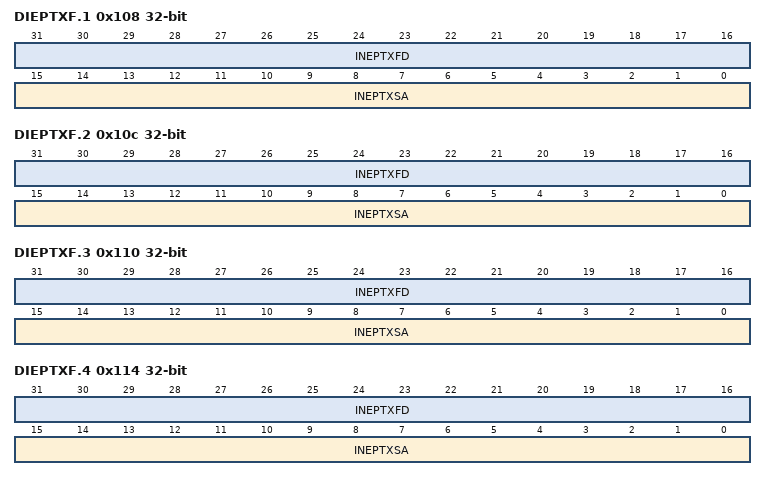
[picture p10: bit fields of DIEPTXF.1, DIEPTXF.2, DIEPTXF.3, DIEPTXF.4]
          <name>DIEPTXF.1</name>
          <addressOffset>0x108</addressOffset>
          <size>0x20</size>
          <fields>
            <field>
              <name>INEPTXSA</name>
              <bitOffset>0</bitOffset>
              <bitWidth>16</bitWidth>
            </field>
            <field>
              <name>INEPTXFD</name>
              <bitOffset>16</bitOffset>
              <bitWidth>16</bitWidth>
            </field>
          </fields>
        </register>
        <register>
          <name>DIEPTXF.2</name>
          <addressOffset>0x10c</addressOffset>
          <size>0x20</size>
          <fields>
            <field>
              <name>INEPTXSA</name>
              <bitOffset>0</bitOffset>
              <bitWidth>16</bitWidth>
            </field>
            <field>
              <name>INEPTXFD</name>
              <bitOffset>16</bitOffset>
              <bitWidth>16</bitWidth>
            </field>
          </fields>
        </register>
        <register>
          <name>DIEPTXF.3</name>
          <addressOffset>0x110</addressOffset>
          <size>0x20</size>
          <fields>
            <field>
              <name>INEPTXSA</name>
              <bitOffset>0</bitOffset>
              <bitWidth>16</bitWidth>
            </field>
            <field>
              <name>INEPTXFD</name>
              <bitOffset>16</bitOffset>
              <bitWidth>16</bitWidth>
            </field>
          </fields>
        </register>
        <register>
          <name>DIEPTXF.4</name>
          <addressOffset>0x114</addressOffset>
          <size>0x20</size>
          <fields>
            <field>
              <name>INEPTXSA</name>
              <bitOffset>0</bitOffset>
              <bitWidth>16</bitWidth>
            </field>
            <field>
              <name>INEPTXFD</name>
              <bitOffset>16</bitOffset>
              <bitWidth>16</bitWidth>
            </field>
          </fields>
        </register>
        <register>
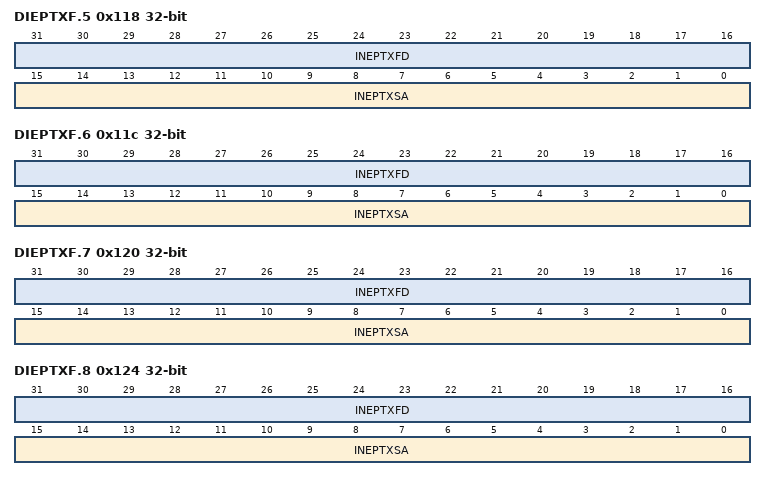
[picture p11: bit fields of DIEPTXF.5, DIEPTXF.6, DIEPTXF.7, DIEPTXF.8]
          <name>DIEPTXF.5</name>
          <addressOffset>0x118</addressOffset>
          <size>0x20</size>
          <fields>
            <field>
              <name>INEPTXSA</name>
              <bitOffset>0</bitOffset>
              <bitWidth>16</bitWidth>
            </field>
            <field>
              <name>INEPTXFD</name>
              <bitOffset>16</bitOffset>
              <bitWidth>16</bitWidth>
            </field>
          </fields>
        </register>
        <register>
          <name>DIEPTXF.6</name>
          <addressOffset>0x11c</addressOffset>
          <size>0x20</size>
          <fields>
            <field>
              <name>INEPTXSA</name>
              <bitOffset>0</bitOffset>
              <bitWidth>16</bitWidth>
            </field>
            <field>
              <name>INEPTXFD</name>
              <bitOffset>16</bitOffset>
              <bitWidth>16</bitWidth>
            </field>
          </fields>
        </register>
        <register>
          <name>DIEPTXF.7</name>
          <addressOffset>0x120</addressOffset>
          <size>0x20</size>
          <fields>
            <field>
              <name>INEPTXSA</name>
              <bitOffset>0</bitOffset>
              <bitWidth>16</bitWidth>
            </field>
            <field>
              <name>INEPTXFD</name>
              <bitOffset>16</bitOffset>
              <bitWidth>16</bitWidth>
            </field>
          </fields>
        </register>
        <register>
          <name>DIEPTXF.8</name>
          <addressOffset>0x124</addressOffset>
          <size>0x20</size>
          <fields>
            <field>
              <name>INEPTXSA</name>
              <bitOffset>0</bitOffset>
              <bitWidth>16</bitWidth>
            </field>
            <field>
              <name>INEPTXFD</name>
              <bitOffset>16</bitOffset>
              <bitWidth>16</bitWidth>
            </field>
          </fields>
        </register>
        <register>
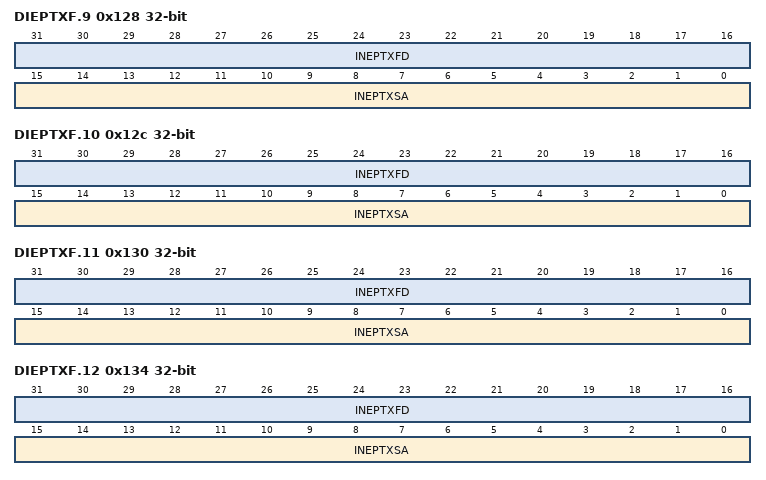
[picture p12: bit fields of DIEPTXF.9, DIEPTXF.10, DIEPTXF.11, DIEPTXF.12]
          <name>DIEPTXF.9</name>
          <addressOffset>0x128</addressOffset>
          <size>0x20</size>
          <fields>
            <field>
              <name>INEPTXSA</name>
              <bitOffset>0</bitOffset>
              <bitWidth>16</bitWidth>
            </field>
            <field>
              <name>INEPTXFD</name>
              <bitOffset>16</bitOffset>
              <bitWidth>16</bitWidth>
            </field>
          </fields>
        </register>
        <register>
          <name>DIEPTXF.10</name>
          <addressOffset>0x12c</addressOffset>
          <size>0x20</size>
          <fields>
            <field>
              <name>INEPTXSA</name>
              <bitOffset>0</bitOffset>
              <bitWidth>16</bitWidth>
            </field>
            <field>
              <name>INEPTXFD</name>
              <bitOffset>16</bitOffset>
              <bitWidth>16</bitWidth>
            </field>
          </fields>
        </register>
        <register>
          <name>DIEPTXF.11</name>
          <addressOffset>0x130</addressOffset>
          <size>0x20</size>
          <fields>
            <field>
              <name>INEPTXSA</name>
              <bitOffset>0</bitOffset>
              <bitWidth>16</bitWidth>
            </field>
            <field>
              <name>INEPTXFD</name>
              <bitOffset>16</bitOffset>
              <bitWidth>16</bitWidth>
            </field>
          </fields>
        </register>
        <register>
          <name>DIEPTXF.12</name>
          <addressOffset>0x134</addressOffset>
          <size>0x20</size>
          <fields>
            <field>
              <name>INEPTXSA</name>
              <bitOffset>0</bitOffset>
              <bitWidth>16</bitWidth>
            </field>
            <field>
              <name>INEPTXFD</name>
              <bitOffset>16</bitOffset>
              <bitWidth>16</bitWidth>
            </field>
          </fields>
        </register>
        <register>
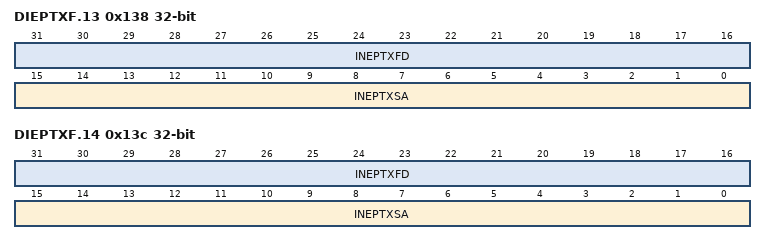
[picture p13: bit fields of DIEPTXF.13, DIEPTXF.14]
          <name>DIEPTXF.13</name>
          <addressOffset>0x138</addressOffset>
          <size>0x20</size>
          <fields>
            <field>
              <name>INEPTXSA</name>
              <bitOffset>0</bitOffset>
              <bitWidth>16</bitWidth>
            </field>
            <field>
              <name>INEPTXFD</name>
              <bitOffset>16</bitOffset>
              <bitWidth>16</bitWidth>
            </field>
          </fields>
        </register>
        <register>
          <name>DIEPTXF.14</name>
          <addressOffset>0x13c</addressOffset>
          <size>0x20</size>
          <fields>
            <field>
              <name>INEPTXSA</name>
              <bitOffset>0</bitOffset>
              <bitWidth>16</bitWidth>
            </field>
            <field>
              <name>INEPTXFD</name>
              <bitOffset>16</bitOffset>
              <bitWidth>16</bitWidth>
            </field>
          </fields>
        </register>
      </registers>
    </peripheral>
    <peripheral>
      <name>DCMI</name>
      <baseAddress>0x50050000</baseAddress>
      <registers>
        <register>
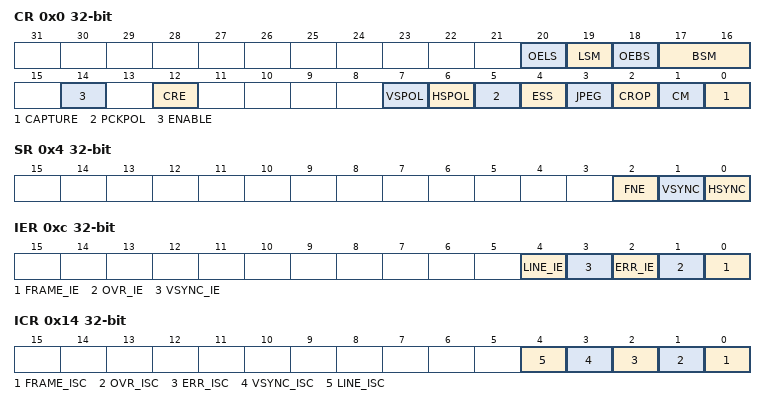
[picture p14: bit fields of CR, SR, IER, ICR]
          <name>CR</name>
          <addressOffset>0x0</addressOffset>
          <size>0x20</size>
          <fields>
            <field>
              <name>CAPTURE</name>
              <bitOffset>0</bitOffset>
              <bitWidth>1</bitWidth>
            </field>
            <field>
              <name>CM</name>
              <bitOffset>1</bitOffset>
              <bitWidth>1</bitWidth>
            </field>
            <field>
              <name>CROP</name>
              <bitOffset>2</bitOffset>
              <bitWidth>1</bitWidth>
            </field>
            <field>
              <name>JPEG</name>
              <bitOffset>3</bitOffset>
              <bitWidth>1</bitWidth>
            </field>
            <field>
              <name>ESS</name>
              <bitOffset>4</bitOffset>
              <bitWidth>1</bitWidth>
            </field>
            <field>
              <name>PCKPOL</name>
              <bitOffset>5</bitOffset>
              <bitWidth>1</bitWidth>
            </field>
            <field>
              <name>HSPOL</name>
              <bitOffset>6</bitOffset>
              <bitWidth>1</bitWidth>
            </field>
            <field>
              <name>VSPOL</name>
              <bitOffset>7</bitOffset>
              <bitWidth>1</bitWidth>
            </field>
            <field>
              <name>CRE</name>
              <bitOffset>12</bitOffset>
              <bitWidth>1</bitWidth>
            </field>
            <field>
              <name>ENABLE</name>
              <bitOffset>14</bitOffset>
              <bitWidth>1</bitWidth>
            </field>
            <field>
              <name>BSM</name>
              <bitOffset>16</bitOffset>
              <bitWidth>2</bitWidth>
            </field>
            <field>
              <name>OEBS</name>
              <bitOffset>18</bitOffset>
              <bitWidth>1</bitWidth>
            </field>
            <field>
              <name>LSM</name>
              <bitOffset>19</bitOffset>
              <bitWidth>1</bitWidth>
            </field>
            <field>
              <name>OELS</name>
              <bitOffset>20</bitOffset>
              <bitWidth>1</bitWidth>
            </field>
          </fields>
        </register>
        <register>
          <name>SR</name>
          <addressOffset>0x4</addressOffset>
          <size>0x20</size>
          <fields>
            <field>
              <name>HSYNC</name>
              <bitOffset>0</bitOffset>
              <bitWidth>1</bitWidth>
            </field>
            <field>
              <name>VSYNC</name>
              <bitOffset>1</bitOffset>
              <bitWidth>1</bitWidth>
            </field>
            <field>
              <name>FNE</name>
              <bitOffset>2</bitOffset>
              <bitWidth>1</bitWidth>
            </field>
          </fields>
        </register>
        <register>
          <name>RISR</name>
          <addressOffset>0x8</addressOffset>
          <size>0x20</size>
        </register>
        <register>
          <name>IER</name>
          <addressOffset>0xc</addressOffset>
          <size>0x20</size>
          <fields>
            <field>
              <name>FRAME_IE</name>
              <bitOffset>0</bitOffset>
              <bitWidth>1</bitWidth>
            </field>
            <field>
              <name>OVR_IE</name>
              <bitOffset>1</bitOffset>
              <bitWidth>1</bitWidth>
            </field>
            <field>
              <name>ERR_IE</name>
              <bitOffset>2</bitOffset>
              <bitWidth>1</bitWidth>
            </field>
            <field>
              <name>VSYNC_IE</name>
              <bitOffset>3</bitOffset>
              <bitWidth>1</bitWidth>
            </field>
            <field>
              <name>LINE_IE</name>
              <bitOffset>4</bitOffset>
              <bitWidth>1</bitWidth>
            </field>
          </fields>
        </register>
        <register>
          <name>MISR</name>
          <addressOffset>0x10</addressOffset>
          <size>0x20</size>
        </register>
        <register>
          <name>ICR</name>
          <addressOffset>0x14</addressOffset>
          <size>0x20</size>
          <fields>
            <field>
              <name>FRAME_ISC</name>
              <bitOffset>0</bitOffset>
              <bitWidth>1</bitWidth>
            </field>
            <field>
              <name>OVR_ISC</name>
              <bitOffset>1</bitOffset>
              <bitWidth>1</bitWidth>
            </field>
            <field>
              <name>ERR_ISC</name>
              <bitOffset>2</bitOffset>
              <bitWidth>1</bitWidth>
            </field>
            <field>
              <name>VSYNC_ISC</name>
              <bitOffset>3</bitOffset>
              <bitWidth>1</bitWidth>
            </field>
            <field>
              <name>LINE_ISC</name>
              <bitOffset>4</bitOffset>
              <bitWidth>1</bitWidth>
            </field>
          </fields>
        </register>
        <register>
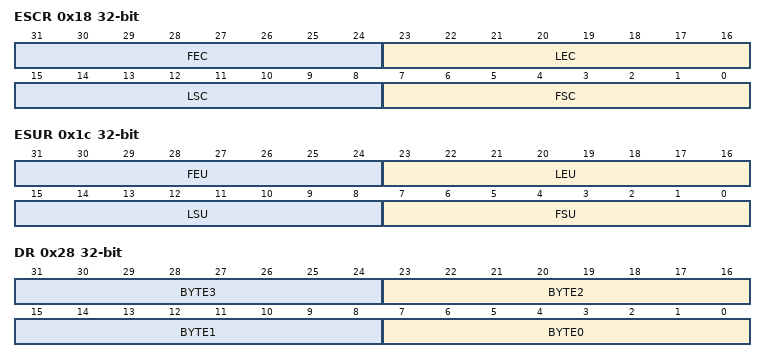
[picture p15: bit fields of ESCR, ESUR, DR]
          <name>ESCR</name>
          <addressOffset>0x18</addressOffset>
          <size>0x20</size>
          <fields>
            <field>
              <name>FSC</name>
              <bitOffset>0</bitOffset>
              <bitWidth>8</bitWidth>
            </field>
            <field>
              <name>LSC</name>
              <bitOffset>8</bitOffset>
              <bitWidth>8</bitWidth>
            </field>
            <field>
              <name>LEC</name>
              <bitOffset>16</bitOffset>
              <bitWidth>8</bitWidth>
            </field>
            <field>
              <name>FEC</name>
              <bitOffset>24</bitOffset>
              <bitWidth>8</bitWidth>
            </field>
          </fields>
        </register>
        <register>
          <name>ESUR</name>
          <addressOffset>0x1c</addressOffset>
          <size>0x20</size>
          <fields>
            <field>
              <name>FSU</name>
              <bitOffset>0</bitOffset>
              <bitWidth>8</bitWidth>
            </field>
            <field>
              <name>LSU</name>
              <bitOffset>8</bitOffset>
              <bitWidth>8</bitWidth>
            </field>
            <field>
              <name>LEU</name>
              <bitOffset>16</bitOffset>
              <bitWidth>8</bitWidth>
            </field>
            <field>
              <name>FEU</name>
              <bitOffset>24</bitOffset>
              <bitWidth>8</bitWidth>
            </field>
          </fields>
        </register>
        <register>
          <name>CWSTRTR</name>
          <addressOffset>0x20</addressOffset>
          <size>0x20</size>
        </register>
        <register>
          <name>CWSIZER</name>
          <addressOffset>0x24</addressOffset>
          <size>0x20</size>
        </register>
        <register>
          <name>DR</name>
          <addressOffset>0x28</addressOffset>
          <size>0x20</size>
          <fields>
            <field>
              <name>BYTE0</name>
              <bitOffset>0</bitOffset>
              <bitWidth>8</bitWidth>
            </field>
            <field>
              <name>BYTE1</name>
              <bitOffset>8</bitOffset>
              <bitWidth>8</bitWidth>
            </field>
            <field>
              <name>BYTE2</name>
              <bitOffset>16</bitOffset>
              <bitWidth>8</bitWidth>
            </field>
            <field>
              <name>BYTE3</name>
              <bitOffset>24</bitOffset>
              <bitWidth>8</bitWidth>
            </field>
          </fields>
        </register>
      </registers>
    </peripheral>
    <peripheral>
      <name>RNG</name>
      <baseAddress>0x50060800</baseAddress>
      <registers>
        <register>
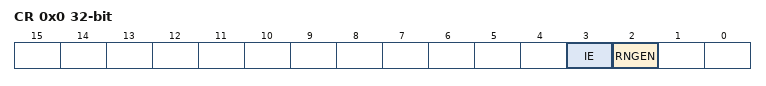
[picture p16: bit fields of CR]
          <name>CR</name>
          <addressOffset>0x0</addressOffset>
          <size>0x20</size>
          <fields>
            <field>
              <name>RNGEN</name>
              <bitOffset>2</bitOffset>
              <bitWidth>1</bitWidth>
            </field>
            <field>
              <name>IE</name>
              <bitOffset>3</bitOffset>
              <bitWidth>1</bitWidth>
            </field>
          </fields>
        </register>
        <register>
          <name>SR</name>
          <addressOffset>0x4</addressOffset>
          <size>0x20</size>
          <fields>
            <field>
              <name>DRDY</name>
              <bitOffset>0</bitOffset>
              <bitWidth>1</bitWidth>
            </field>
            <field>
              <name>CECS</name>
              <bitOffset>1</bitOffset>
              <bitWidth>1</bitWidth>
            </field>
            <field>
              <name>SECS</name>
              <bitOffset>2</bitOffset>
              <bitWidth>1</bitWidth>
            </field>
            <field>
              <name>CEIS</name>
              <bitOffset>5</bitOffset>
              <bitWidth>1</bitWidth>
            </field>
            <field>
              <name>SEIS</name>
              <bitOffset>6</bitOffset>
              <bitWidth>1</bitWidth>
            </field>
          </fields>
        </register>
        <register>
          <name>DR</name>
          <addressOffset>0x8</addressOffset>
          <size>0x20</size>
        </register>
      </registers>
    </peripheral>
    <peripheral>
      <name>FMC_Bank1</name>
      <baseAddress>0xa0000000</baseAddress>
      <registers>
        <register>
          <name>BTCR.0</name>
          <addressOffset>0x0</addressOffset>
          <size>0x20</size>
        </register>
        <register>
          <name>BTCR.1</name>
          <addressOffset>0x4</addressOffset>
          <size>0x20</size>
        </register>
        <register>
          <name>BTCR.2</name>
          <addressOffset>0x8</addressOffset>
          <size>0x20</size>
        </register>
        <register>
          <name>BTCR.3</name>
          <addressOffset>0xc</addressOffset>
          <size>0x20</size>
        </register>
        <register>
          <name>BTCR.4</name>
          <addressOffset>0x10</addressOffset>
          <size>0x20</size>
        </register>
        <register>
          <name>BTCR.5</name>
          <addressOffset>0x14</addressOffset>
          <size>0x20</size>
        </register>
        <register>
          <name>BTCR.6</name>
          <addressOffset>0x18</addressOffset>
          <size>0x20</size>
        </register>
        <register>
          <name>BTCR.7</name>
          <addressOffset>0x1c</addressOffset>
          <size>0x20</size>
        </register>
      </registers>
    </peripheral>
    <peripheral>
      <name>FMC_Bank3</name>
      <baseAddress>0xa0000080</baseAddress>
      <registers>
        <register>
          <name>PCR</name>
          <addressOffset>0x0</addressOffset>
          <size>0x20</size>
          <fields>
            <field>
              <name>PWAITEN</name>
              <bitOffset>1</bitOffset>
              <bitWidth>1</bitWidth>
            </field>
            <field>
              <name>PBKEN</name>
              <bitOffset>2</bitOffset>
              <bitWidth>1</bitWidth>
            </field>
            <field>
              <name>PTYP</name>
              <bitOffset>3</bitOffset>
              <bitWidth>1</bitWidth>
            </field>
            <field>
              <name>PWID</name>
              <bitOffset>4</bitOffset>
              <bitWidth>2</bitWidth>
            </field>
            <field>
              <name>ECCEN</name>
              <bitOffset>6</bitOffset>
              <bitWidth>1</bitWidth>
            </field>
            <field>
              <name>TCLR</name>
              <bitOffset>9</bitOffset>
              <bitWidth>4</bitWidth>
            </field>
            <field>
              <name>TAR</name>
              <bitOffset>13</bitOffset>
              <bitWidth>4</bitWidth>
            </field>
            <field>
              <name>ECCPS</name>
              <bitOffset>17</bitOffset>
              <bitWidth>3</bitWidth>
            </field>
          </fields>
        </register>
        <register>
          <name>SR</name>
          <addressOffset>0x4</addressOffset>
          <size>0x20</size>
          <fields>
            <field>
              <name>IRS</name>
              <bitOffset>0</bitOffset>
              <bitWidth>1</bitWidth>
            </field>
            <field>
              <name>ILS</name>
              <bitOffset>1</bitOffset>
              <bitWidth>1</bitWidth>
            </field>
            <field>
              <name>IFS</name>
              <bitOffset>2</bitOffset>
              <bitWidth>1</bitWidth>
            </field>
            <field>
              <name>IREN</name>
              <bitOffset>3</bitOffset>
              <bitWidth>1</bitWidth>
            </field>
            <field>
              <name>ILEN</name>
              <bitOffset>4</bitOffset>
              <bitWidth>1</bitWidth>
            </field>
            <field>
              <name>IFEN</name>
              <bitOffset>5</bitOffset>
              <bitWidth>1</bitWidth>
            </field>
            <field>
              <name>FEMPT</name>
              <bitOffset>6</bitOffset>
              <bitWidth>1</bitWidth>
            </field>
          </fields>
        </register>
        <register>
          <name>PMEM</name>
          <addressOffset>0x8</addressOffset>
          <size>0x20</size>
          <fields>
            <field>
              <name>MEMSET3</name>
              <bitOffset>0</bitOffset>
              <bitWidth>8</bitWidth>
            </field>
            <field>
              <name>MEMWAIT3</name>
              <bitOffset>8</bitOffset>
              <bitWidth>8</bitWidth>
            </field>
            <field>
              <name>MEMHOLD3</name>
              <bitOffset>16</bitOffset>
              <bitWidth>8</bitWidth>
            </field>
            <field>
              <name>MEMHIZ3</name>
              <bitOffset>24</bitOffset>
              <bitWidth>8</bitWidth>
            </field>
          </fields>
        </register>
        <register>
          <name>PATT</name>
          <addressOffset>0xc</addressOffset>
          <size>0x20</size>
          <fields>
            <field>
              <name>ATTSET3</name>
              <bitOffset>0</bitOffset>
              <bitWidth>8</bitWidth>
            </field>
            <field>
              <name>ATTWAIT3</name>
              <bitOffset>8</bitOffset>
              <bitWidth>8</bitWidth>
            </field>
            <field>
              <name>ATTHOLD3</name>
              <bitOffset>16</bitOffset>
              <bitWidth>8</bitWidth>
            </field>
            <field>
              <name>ATTHIZ3</name>
              <bitOffset>24</bitOffset>
              <bitWidth>8</bitWidth>
            </field>
          </fields>
        </register>
        <register>
          <name>ECCR</name>
          <addressOffset>0x14</addressOffset>
          <size>0x20</size>
          <fields>
            <field>
              <name>ECC3</name>
              <bitOffset>0</bitOffset>
              <bitWidth>32</bitWidth>
            </field>
          </fields>
        </register>
      </registers>
    </peripheral>
    <peripheral>
      <name>FMC_Bank1E</name>
      <baseAddress>0xa0000104</baseAddress>
      <registers>
        <register>
          <name>BWTR.0</name>
          <addressOffset>0x0</addressOffset>
          <size>0x20</size>
          <fields>
            <field>
              <name>ADDSET</name>
              <bitOffset>0</bitOffset>
              <bitWidth>4</bitWidth>
            </field>
            <field>
              <name>ADDHLD</name>
              <bitOffset>4</bitOffset>
              <bitWidth>4</bitWidth>
            </field>
            <field>
              <name>DATAST</name>
              <bitOffset>8</bitOffset>
              <bitWidth>8</bitWidth>
            </field>
            <field>
              <name>BUSTURN</name>
              <bitOffset>16</bitOffset>
              <bitWidth>4</bitWidth>
            </field>
            <field>
              <name>ACCMOD</name>
              <bitOffset>28</bitOffset>
              <bitWidth>2</bitWidth>
            </field>
          </fields>
        </register>
        <register>
          <name>BWTR.1</name>
          <addressOffset>0x4</addressOffset>
          <size>0x20</size>
          <fields>
            <field>
              <name>ADDSET</name>
              <bitOffset>0</bitOffset>
              <bitWidth>4</bitWidth>
            </field>
            <field>
              <name>ADDHLD</name>
              <bitOffset>4</bitOffset>
              <bitWidth>4</bitWidth>
            </field>
            <field>
              <name>DATAST</name>
              <bitOffset>8</bitOffset>
              <bitWidth>8</bitWidth>
            </field>
            <field>
              <name>BUSTURN</name>
              <bitOffset>16</bitOffset>
              <bitWidth>4</bitWidth>
            </field>
            <field>
              <name>ACCMOD</name>
              <bitOffset>28</bitOffset>
              <bitWidth>2</bitWidth>
            </field>
          </fields>
        </register>
        <register>
          <name>BWTR.2</name>
          <addressOffset>0x8</addressOffset>
          <size>0x20</size>
          <fields>
            <field>
              <name>ADDSET</name>
              <bitOffset>0</bitOffset>
              <bitWidth>4</bitWidth>
            </field>
            <field>
              <name>ADDHLD</name>
              <bitOffset>4</bitOffset>
              <bitWidth>4</bitWidth>
            </field>
            <field>
              <name>DATAST</name>
              <bitOffset>8</bitOffset>
              <bitWidth>8</bitWidth>
            </field>
            <field>
              <name>BUSTURN</name>
              <bitOffset>16</bitOffset>
              <bitWidth>4</bitWidth>
            </field>
            <field>
              <name>ACCMOD</name>
              <bitOffset>28</bitOffset>
              <bitWidth>2</bitWidth>
            </field>
          </fields>
        </register>
        <register>
          <name>BWTR.3</name>
          <addressOffset>0xc</addressOffset>
          <size>0x20</size>
          <fields>
            <field>
              <name>ADDSET</name>
              <bitOffset>0</bitOffset>
              <bitWidth>4</bitWidth>
            </field>
            <field>
              <name>ADDHLD</name>
              <bitOffset>4</bitOffset>
              <bitWidth>4</bitWidth>
            </field>
            <field>
              <name>DATAST</name>
              <bitOffset>8</bitOffset>
              <bitWidth>8</bitWidth>
            </field>
            <field>
              <name>BUSTURN</name>
              <bitOffset>16</bitOffset>
              <bitWidth>4</bitWidth>
            </field>
            <field>
              <name>ACCMOD</name>
              <bitOffset>28</bitOffset>
              <bitWidth>2</bitWidth>
            </field>
          </fields>
        </register>
        <register>
          <name>BWTR.4</name>
          <addressOffset>0x10</addressOffset>
          <size>0x20</size>
        </register>
        <register>
          <name>BWTR.5</name>
          <addressOffset>0x14</addressOffset>
          <size>0x20</size>
        </register>
        <register>
          <name>BWTR.6</name>
          <addressOffset>0x18</addressOffset>
          <size>0x20</size>
        </register>
      </registers>
    </peripheral>
    <peripheral>
      <name>FMC_Bank5_6</name>
      <baseAddress>0xa0000140</baseAddress>
      <registers>
        <register>
          <name>SDCR.0</name>
          <addressOffset>0x0</addressOffset>
          <size>0x20</size>
          <fields>
            <field>
              <name>NC</name>
              <bitOffset>0</bitOffset>
              <bitWidth>2</bitWidth>
            </field>
            <field>
              <name>NR</name>
              <bitOffset>2</bitOffset>
              <bitWidth>2</bitWidth>
            </field>
            <field>
              <name>MWID</name>
              <bitOffset>4</bitOffset>
              <bitWidth>2</bitWidth>
            </field>
            <field>
              <name>NB</name>
              <bitOffset>6</bitOffset>
              <bitWidth>1</bitWidth>
            </field>
            <field>
              <name>CAS</name>
              <bitOffset>7</bitOffset>
              <bitWidth>2</bitWidth>
            </field>
            <field>
              <name>WP</name>
              <bitOffset>9</bitOffset>
              <bitWidth>1</bitWidth>
            </field>
            <field>
              <name>SDCLK</name>
              <bitOffset>10</bitOffset>
              <bitWidth>2</bitWidth>
            </field>
            <field>
              <name>RBURST</name>
              <bitOffset>12</bitOffset>
              <bitWidth>1</bitWidth>
            </field>
            <field>
              <name>RPIPE</name>
              <bitOffset>13</bitOffset>
              <bitWidth>2</bitWidth>
            </field>
          </fields>
        </register>
        <register>
          <name>SDCR.1</name>
          <addressOffset>0x4</addressOffset>
          <size>0x20</size>
          <fields>
            <field>
              <name>NC</name>
              <bitOffset>0</bitOffset>
              <bitWidth>2</bitWidth>
            </field>
            <field>
              <name>NR</name>
              <bitOffset>2</bitOffset>
              <bitWidth>2</bitWidth>
            </field>
            <field>
              <name>MWID</name>
              <bitOffset>4</bitOffset>
              <bitWidth>2</bitWidth>
            </field>
            <field>
              <name>NB</name>
              <bitOffset>6</bitOffset>
              <bitWidth>1</bitWidth>
            </field>
            <field>
              <name>CAS</name>
              <bitOffset>7</bitOffset>
              <bitWidth>2</bitWidth>
            </field>
            <field>
              <name>WP</name>
              <bitOffset>9</bitOffset>
              <bitWidth>1</bitWidth>
            </field>
            <field>
              <name>SDCLK</name>
              <bitOffset>10</bitOffset>
              <bitWidth>2</bitWidth>
            </field>
            <field>
              <name>RBURST</name>
              <bitOffset>12</bitOffset>
              <bitWidth>1</bitWidth>
            </field>
            <field>
              <name>RPIPE</name>
              <bitOffset>13</bitOffset>
              <bitWidth>2</bitWidth>
            </field>
          </fields>
        </register>
        <register>
          <name>SDTR.0</name>
          <addressOffset>0x8</addressOffset>
          <size>0x20</size>
          <fields>
            <field>
              <name>TMRD</name>
              <bitOffset>0</bitOffset>
              <bitWidth>4</bitWidth>
            </field>
            <field>
              <name>TXSR</name>
              <bitOffset>4</bitOffset>
              <bitWidth>4</bitWidth>
            </field>
            <field>
              <name>TRAS</name>
              <bitOffset>8</bitOffset>
              <bitWidth>4</bitWidth>
            </field>
            <field>
              <name>TRC</name>
              <bitOffset>12</bitOffset>
              <bitWidth>4</bitWidth>
            </field>
            <field>
              <name>TWR</name>
              <bitOffset>16</bitOffset>
              <bitWidth>4</bitWidth>
            </field>
            <field>
              <name>TRP</name>
              <bitOffset>20</bitOffset>
              <bitWidth>4</bitWidth>
            </field>
            <field>
              <name>TRCD</name>
              <bitOffset>24</bitOffset>
              <bitWidth>4</bitWidth>
            </field>
          </fields>
        </register>
        <register>
          <name>SDTR.1</name>
          <addressOffset>0xc</addressOffset>
          <size>0x20</size>
          <fields>
            <field>
              <name>TMRD</name>
              <bitOffset>0</bitOffset>
              <bitWidth>4</bitWidth>
            </field>
            <field>
              <name>TXSR</name>
              <bitOffset>4</bitOffset>
              <bitWidth>4</bitWidth>
            </field>
            <field>
              <name>TRAS</name>
              <bitOffset>8</bitOffset>
              <bitWidth>4</bitWidth>
            </field>
            <field>
              <name>TRC</name>
              <bitOffset>12</bitOffset>
              <bitWidth>4</bitWidth>
            </field>
            <field>
              <name>TWR</name>
              <bitOffset>16</bitOffset>
              <bitWidth>4</bitWidth>
            </field>
            <field>
              <name>TRP</name>
              <bitOffset>20</bitOffset>
              <bitWidth>4</bitWidth>
            </field>
            <field>
              <name>TRCD</name>
              <bitOffset>24</bitOffset>
              <bitWidth>4</bitWidth>
            </field>
          </fields>
        </register>
        <register>
          <name>SDCMR</name>
          <addressOffset>0x10</addressOffset>
          <size>0x20</size>
          <fields>
            <field>
              <name>MODE</name>
              <bitOffset>0</bitOffset>
              <bitWidth>3</bitWidth>
            </field>
            <field>
              <name>CTB2</name>
              <bitOffset>3</bitOffset>
              <bitWidth>1</bitWidth>
            </field>
            <field>
              <name>CTB1</name>
              <bitOffset>4</bitOffset>
              <bitWidth>1</bitWidth>
            </field>
            <field>
              <name>NRFS</name>
              <bitOffset>5</bitOffset>
              <bitWidth>4</bitWidth>
            </field>
            <field>
              <name>MRD</name>
              <bitOffset>9</bitOffset>
              <bitWidth>13</bitWidth>
            </field>
          </fields>
        </register>
        <register>
          <name>SDRTR</name>
          <addressOffset>0x14</addressOffset>
          <size>0x20</size>
          <fields>
            <field>
              <name>CRE</name>
              <bitOffset>0</bitOffset>
              <bitWidth>1</bitWidth>
            </field>
            <field>
              <name>COUNT</name>
              <bitOffset>1</bitOffset>
              <bitWidth>13</bitWidth>
            </field>
            <field>
              <name>REIE</name>
              <bitOffset>14</bitOffset>
              <bitWidth>1</bitWidth>
            </field>
          </fields>
        </register>
        <register>
          <name>SDSR</name>
          <addressOffset>0x18</addressOffset>
          <size>0x20</size>
          <fields>
            <field>
              <name>RE</name>
              <bitOffset>0</bitOffset>
              <bitWidth>1</bitWidth>
            </field>
            <field>
              <name>MODES1</name>
              <bitOffset>1</bitOffset>
              <bitWidth>2</bitWidth>
            </field>
            <field>
              <name>MODES2</name>
              <bitOffset>3</bitOffset>
              <bitWidth>2</bitWidth>
            </field>
            <field>
              <name>BUSY</name>
              <bitOffset>5</bitOffset>
              <bitWidth>1</bitWidth>
            </field>
          </fields>
        </register>
      </registers>
    </peripheral>
    <peripheral>
      <name>QUADSPI</name>
      <baseAddress>0xa0001000</baseAddress>
      <registers>
        <register>
          <name>CR</name>
          <addressOffset>0x0</addressOffset>
          <size>0x20</size>
          <fields>
            <field>
              <name>EN</name>
              <bitOffset>0</bitOffset>
              <bitWidth>1</bitWidth>
            </field>
            <field>
              <name>ABORT</name>
              <bitOffset>1</bitOffset>
              <bitWidth>1</bitWidth>
            </field>
            <field>
              <name>DMAEN</name>
              <bitOffset>2</bitOffset>
              <bitWidth>1</bitWidth>
            </field>
            <field>
              <name>TCEN</name>
              <bitOffset>3</bitOffset>
              <bitWidth>1</bitWidth>
            </field>
            <field>
              <name>SSHIFT</name>
              <bitOffset>4</bitOffset>
              <bitWidth>1</bitWidth>
            </field>
            <field>
              <name>DFM</name>
              <bitOffset>6</bitOffset>
              <bitWidth>1</bitWidth>
            </field>
            <field>
              <name>FSEL</name>
              <bitOffset>7</bitOffset>
              <bitWidth>1</bitWidth>
            </field>
            <field>
              <name>FTHRES</name>
              <bitOffset>8</bitOffset>
              <bitWidth>5</bitWidth>
            </field>
            <field>
              <name>TEIE</name>
              <bitOffset>16</bitOffset>
              <bitWidth>1</bitWidth>
            </field>
            <field>
              <name>TCIE</name>
              <bitOffset>17</bitOffset>
              <bitWidth>1</bitWidth>
            </field>
            <field>
              <name>FTIE</name>
              <bitOffset>18</bitOffset>
              <bitWidth>1</bitWidth>
            </field>
            <field>
              <name>SMIE</name>
              <bitOffset>19</bitOffset>
              <bitWidth>1</bitWidth>
            </field>
            <field>
              <name>TOIE</name>
              <bitOffset>20</bitOffset>
              <bitWidth>1</bitWidth>
            </field>
            <field>
              <name>APMS</name>
              <bitOffset>22</bitOffset>
              <bitWidth>1</bitWidth>
            </field>
            <field>
              <name>PMM</name>
              <bitOffset>23</bitOffset>
              <bitWidth>1</bitWidth>
            </field>
            <field>
              <name>PRESCALER</name>
              <bitOffset>24</bitOffset>
              <bitWidth>8</bitWidth>
            </field>
          </fields>
        </register>
        <register>
          <name>DCR</name>
          <addressOffset>0x4</addressOffset>
          <size>0x20</size>
          <fields>
            <field>
              <name>CKMODE</name>
              <bitOffset>0</bitOffset>
              <bitWidth>1</bitWidth>
            </field>
            <field>
              <name>CSHT</name>
              <bitOffset>8</bitOffset>
              <bitWidth>3</bitWidth>
            </field>
            <field>
              <name>FSIZE</name>
              <bitOffset>16</bitOffset>
              <bitWidth>5</bitWidth>
            </field>
          </fields>
        </register>
        <register>
          <name>SR</name>
          <addressOffset>0x8</addressOffset>
          <size>0x20</size>
          <fields>
            <field>
              <name>TEF</name>
              <bitOffset>0</bitOffset>
              <bitWidth>1</bitWidth>
            </field>
            <field>
              <name>TCF</name>
              <bitOffset>1</bitOffset>
              <bitWidth>1</bitWidth>
            </field>
            <field>
              <name>FTF</name>
              <bitOffset>2</bitOffset>
              <bitWidth>1</bitWidth>
            </field>
            <field>
              <name>SMF</name>
              <bitOffset>3</bitOffset>
              <bitWidth>1</bitWidth>
            </field>
            <field>
              <name>TOF</name>
              <bitOffset>4</bitOffset>
              <bitWidth>1</bitWidth>
            </field>
            <field>
              <name>BUSY</name>
              <bitOffset>5</bitOffset>
              <bitWidth>1</bitWidth>
            </field>
            <field>
              <name>FLEVEL</name>
              <bitOffset>8</bitOffset>
              <bitWidth>6</bitWidth>
            </field>
          </fields>
        </register>
        <register>
          <name>FCR</name>
          <addressOffset>0xc</addressOffset>
          <size>0x20</size>
          <fields>
            <field>
              <name>CTEF</name>
              <bitOffset>0</bitOffset>
              <bitWidth>1</bitWidth>
            </field>
            <field>
              <name>CTCF</name>
              <bitOffset>1</bitOffset>
              <bitWidth>1</bitWidth>
            </field>
            <field>
              <name>CSMF</name>
              <bitOffset>3</bitOffset>
              <bitWidth>1</bitWidth>
            </field>
            <field>
              <name>CTOF</name>
              <bitOffset>4</bitOffset>
              <bitWidth>1</bitWidth>
            </field>
          </fields>
        </register>
        <register>
          <name>DLR</name>
          <addressOffset>0x10</addressOffset>
          <size>0x20</size>
          <fields>
            <field>
              <name>DL</name>
              <bitOffset>0</bitOffset>
              <bitWidth>32</bitWidth>
            </field>
          </fields>
        </register>
        <register>
          <name>CCR</name>
          <addressOffset>0x14</addressOffset>
          <size>0x20</size>
          <fields>
            <field>
              <name>INSTRUCTION</name>
              <bitOffset>0</bitOffset>
              <bitWidth>8</bitWidth>
            </field>
            <field>
              <name>IMODE</name>
              <bitOffset>8</bitOffset>
              <bitWidth>2</bitWidth>
            </field>
            <field>
              <name>ADMODE</name>
              <bitOffset>10</bitOffset>
              <bitWidth>2</bitWidth>
            </field>
            <field>
              <name>ADSIZE</name>
              <bitOffset>12</bitOffset>
              <bitWidth>2</bitWidth>
            </field>
            <field>
              <name>ABMODE</name>
              <bitOffset>14</bitOffset>
              <bitWidth>2</bitWidth>
            </field>
            <field>
              <name>ABSIZE</name>
              <bitOffset>16</bitOffset>
              <bitWidth>2</bitWidth>
            </field>
            <field>
              <name>DCYC</name>
              <bitOffset>18</bitOffset>
              <bitWidth>5</bitWidth>
            </field>
            <field>
              <name>DMODE</name>
              <bitOffset>24</bitOffset>
              <bitWidth>2</bitWidth>
            </field>
            <field>
              <name>FMODE</name>
              <bitOffset>26</bitOffset>
              <bitWidth>2</bitWidth>
            </field>
            <field>
              <name>SIOO</name>
              <bitOffset>28</bitOffset>
              <bitWidth>1</bitWidth>
            </field>
            <field>
              <name>DHHC</name>
              <bitOffset>30</bitOffset>
              <bitWidth>1</bitWidth>
            </field>
            <field>
              <name>DDRM</name>
              <bitOffset>31</bitOffset>
              <bitWidth>1</bitWidth>
            </field>
          </fields>
        </register>
        <register>
          <name>AR</name>
          <addressOffset>0x18</addressOffset>
          <size>0x20</size>
          <fields>
            <field>
              <name>ADDRESS</name>
              <bitOffset>0</bitOffset>
              <bitWidth>32</bitWidth>
            </field>
          </fields>
        </register>
        <register>
          <name>ABR</name>
          <addressOffset>0x1c</addressOffset>
          <size>0x20</size>
          <fields>
            <field>
              <name>ALTERNATE</name>
              <bitOffset>0</bitOffset>
              <bitWidth>32</bitWidth>
            </field>
          </fields>
        </register>
        <register>
          <name>DR</name>
          <addressOffset>0x20</addressOffset>
          <size>0x20</size>
          <fields>
            <field>
              <name>DATA</name>
              <bitOffset>0</bitOffset>
              <bitWidth>32</bitWidth>
            </field>
          </fields>
        </register>
        <register>
          <name>PSMKR</name>
          <addressOffset>0x24</addressOffset>
          <size>0x20</size>
          <fields>
            <field>
              <name>MASK</name>
              <bitOffset>0</bitOffset>
              <bitWidth>32</bitWidth>
            </field>
          </fields>
        </register>
        <register>
          <name>PSMAR</name>
          <addressOffset>0x28</addressOffset>
          <size>0x20</size>
          <fields>
            <field>
              <name>MATCH</name>
              <bitOffset>0</bitOffset>
              <bitWidth>32</bitWidth>
            </field>
          </fields>
        </register>
        <register>
          <name>PIR</name>
          <addressOffset>0x2c</addressOffset>
          <size>0x20</size>
          <fields>
            <field>
              <name>INTERVAL</name>
              <bitOffset>0</bitOffset>
              <bitWidth>16</bitWidth>
            </field>
          </fields>
        </register>
        <register>
          <name>LPTR</name>
          <addressOffset>0x30</addressOffset>
          <size>0x20</size>
          <fields>
            <field>
              <name>TIMEOUT</name>
              <bitOffset>0</bitOffset>
              <bitWidth>16</bitWidth>
            </field>
          </fields>
        </register>
      </registers>
    </peripheral>
    <peripheral>
      <name>DBGMCU</name>
      <baseAddress>0xe0042000</baseAddress>
      <registers>
        <register>
          <name>IDCODE</name>
          <addressOffset>0x0</addressOffset>
          <size>0x20</size>
          <fields>
            <field>
              <name>DEV_ID</name>
              <bitOffset>0</bitOffset>
              <bitWidth>12</bitWidth>
            </field>
            <field>
              <name>REV_ID</name>
              <bitOffset>16</bitOffset>
              <bitWidth>16</bitWidth>
            </field>
          </fields>
        </register>
        <register>
          <name>CR</name>
          <addressOffset>0x4</addressOffset>
          <size>0x20</size>
          <fields>
            <field>
              <name>DBG_SLEEP</name>
              <bitOffset>0</bitOffset>
              <bitWidth>1</bitWidth>
            </field>
            <field>
              <name>DBG_STOP</name>
              <bitOffset>1</bitOffset>
              <bitWidth>1</bitWidth>
            </field>
            <field>
              <name>DBG_STANDBY</name>
              <bitOffset>2</bitOffset>
              <bitWidth>1</bitWidth>
            </field>
            <field>
              <name>TRACE_IOEN</name>
              <bitOffset>5</bitOffset>
              <bitWidth>1</bitWidth>
            </field>
            <field>
              <name>TRACE_MODE</name>
              <bitOffset>6</bitOffset>
              <bitWidth>2</bitWidth>
            </field>
          </fields>
        </register>
        <register>
          <name>APB1FZ</name>
          <addressOffset>0x8</addressOffset>
          <size>0x20</size>
          <fields>
            <field>
              <name>DBG_TIM2_STOP</name>
              <bitOffset>0</bitOffset>
              <bitWidth>1</bitWidth>
            </field>
            <field>
              <name>DBG_TIM3_STOP</name>
              <bitOffset>1</bitOffset>
              <bitWidth>1</bitWidth>
            </field>
            <field>
              <name>DBG_TIM4_STOP</name>
              <bitOffset>2</bitOffset>
              <bitWidth>1</bitWidth>
            </field>
            <field>
              <name>DBG_TIM5_STOP</name>
              <bitOffset>3</bitOffset>
              <bitWidth>1</bitWidth>
            </field>
            <field>
              <name>DBG_TIM6_STOP</name>
              <bitOffset>4</bitOffset>
              <bitWidth>1</bitWidth>
            </field>
            <field>
              <name>DBG_TIM7_STOP</name>
              <bitOffset>5</bitOffset>
              <bitWidth>1</bitWidth>
            </field>
            <field>
              <name>DBG_TIM12_STOP</name>
              <bitOffset>6</bitOffset>
              <bitWidth>1</bitWidth>
            </field>
            <field>
              <name>DBG_TIM13_STOP</name>
              <bitOffset>7</bitOffset>
              <bitWidth>1</bitWidth>
            </field>
            <field>
              <name>DBG_TIM14_STOP</name>
              <bitOffset>8</bitOffset>
              <bitWidth>1</bitWidth>
            </field>
            <field>
              <name>DBG_LPTIM1_STOP</name>
              <bitOffset>9</bitOffset>
              <bitWidth>1</bitWidth>
            </field>
            <field>
              <name>DBG_RTC_STOP</name>
              <bitOffset>10</bitOffset>
              <bitWidth>1</bitWidth>
            </field>
            <field>
              <name>DBG_WWDG_STOP</name>
              <bitOffset>11</bitOffset>
              <bitWidth>1</bitWidth>
            </field>
            <field>
              <name>DBG_IWDG_STOP</name>
              <bitOffset>12</bitOffset>
              <bitWidth>1</bitWidth>
            </field>
            <field>
              <name>DBG_CAN3_STOP</name>
              <bitOffset>13</bitOffset>
              <bitWidth>1</bitWidth>
            </field>
            <field>
              <name>DBG_I2C1_SMBUS_TIMEOUT</name>
              <bitOffset>21</bitOffset>
              <bitWidth>1</bitWidth>
            </field>
            <field>
              <name>DBG_I2C2_SMBUS_TIMEOUT</name>
              <bitOffset>22</bitOffset>
              <bitWidth>1</bitWidth>
            </field>
            <field>
              <name>DBG_I2C3_SMBUS_TIMEOUT</name>
              <bitOffset>23</bitOffset>
              <bitWidth>1</bitWidth>
            </field>
            <field>
              <name>DBG_I2C4_SMBUS_TIMEOUT</name>
              <bitOffset>24</bitOffset>
              <bitWidth>1</bitWidth>
            </field>
            <field>
              <name>DBG_CAN1_STOP</name>
              <bitOffset>25</bitOffset>
              <bitWidth>1</bitWidth>
            </field>
            <field>
              <name>DBG_CAN2_STOP</name>
              <bitOffset>26</bitOffset>
              <bitWidth>1</bitWidth>
            </field>
          </fields>
        </register>
        <register>
          <name>APB2FZ</name>
          <addressOffset>0xc</addressOffset>
          <size>0x20</size>
          <fields>
            <field>
              <name>DBG_TIM1_STOP</name>
              <bitOffset>0</bitOffset>
              <bitWidth>1</bitWidth>
            </field>
            <field>
              <name>DBG_TIM8_STOP</name>
              <bitOffset>1</bitOffset>
              <bitWidth>1</bitWidth>
            </field>
            <field>
              <name>DBG_TIM9_STOP</name>
              <bitOffset>16</bitOffset>
              <bitWidth>1</bitWidth>
            </field>
            <field>
              <name>DBG_TIM10_STOP</name>
              <bitOffset>17</bitOffset>
              <bitWidth>1</bitWidth>
            </field>
            <field>
              <name>DBG_TIM11_STOP</name>
              <bitOffset>18</bitOffset>
              <bitWidth>1</bitWidth>
            </field>
          </fields>
        </register>
      </registers>
    </peripheral>
  </peripherals>
</device>
